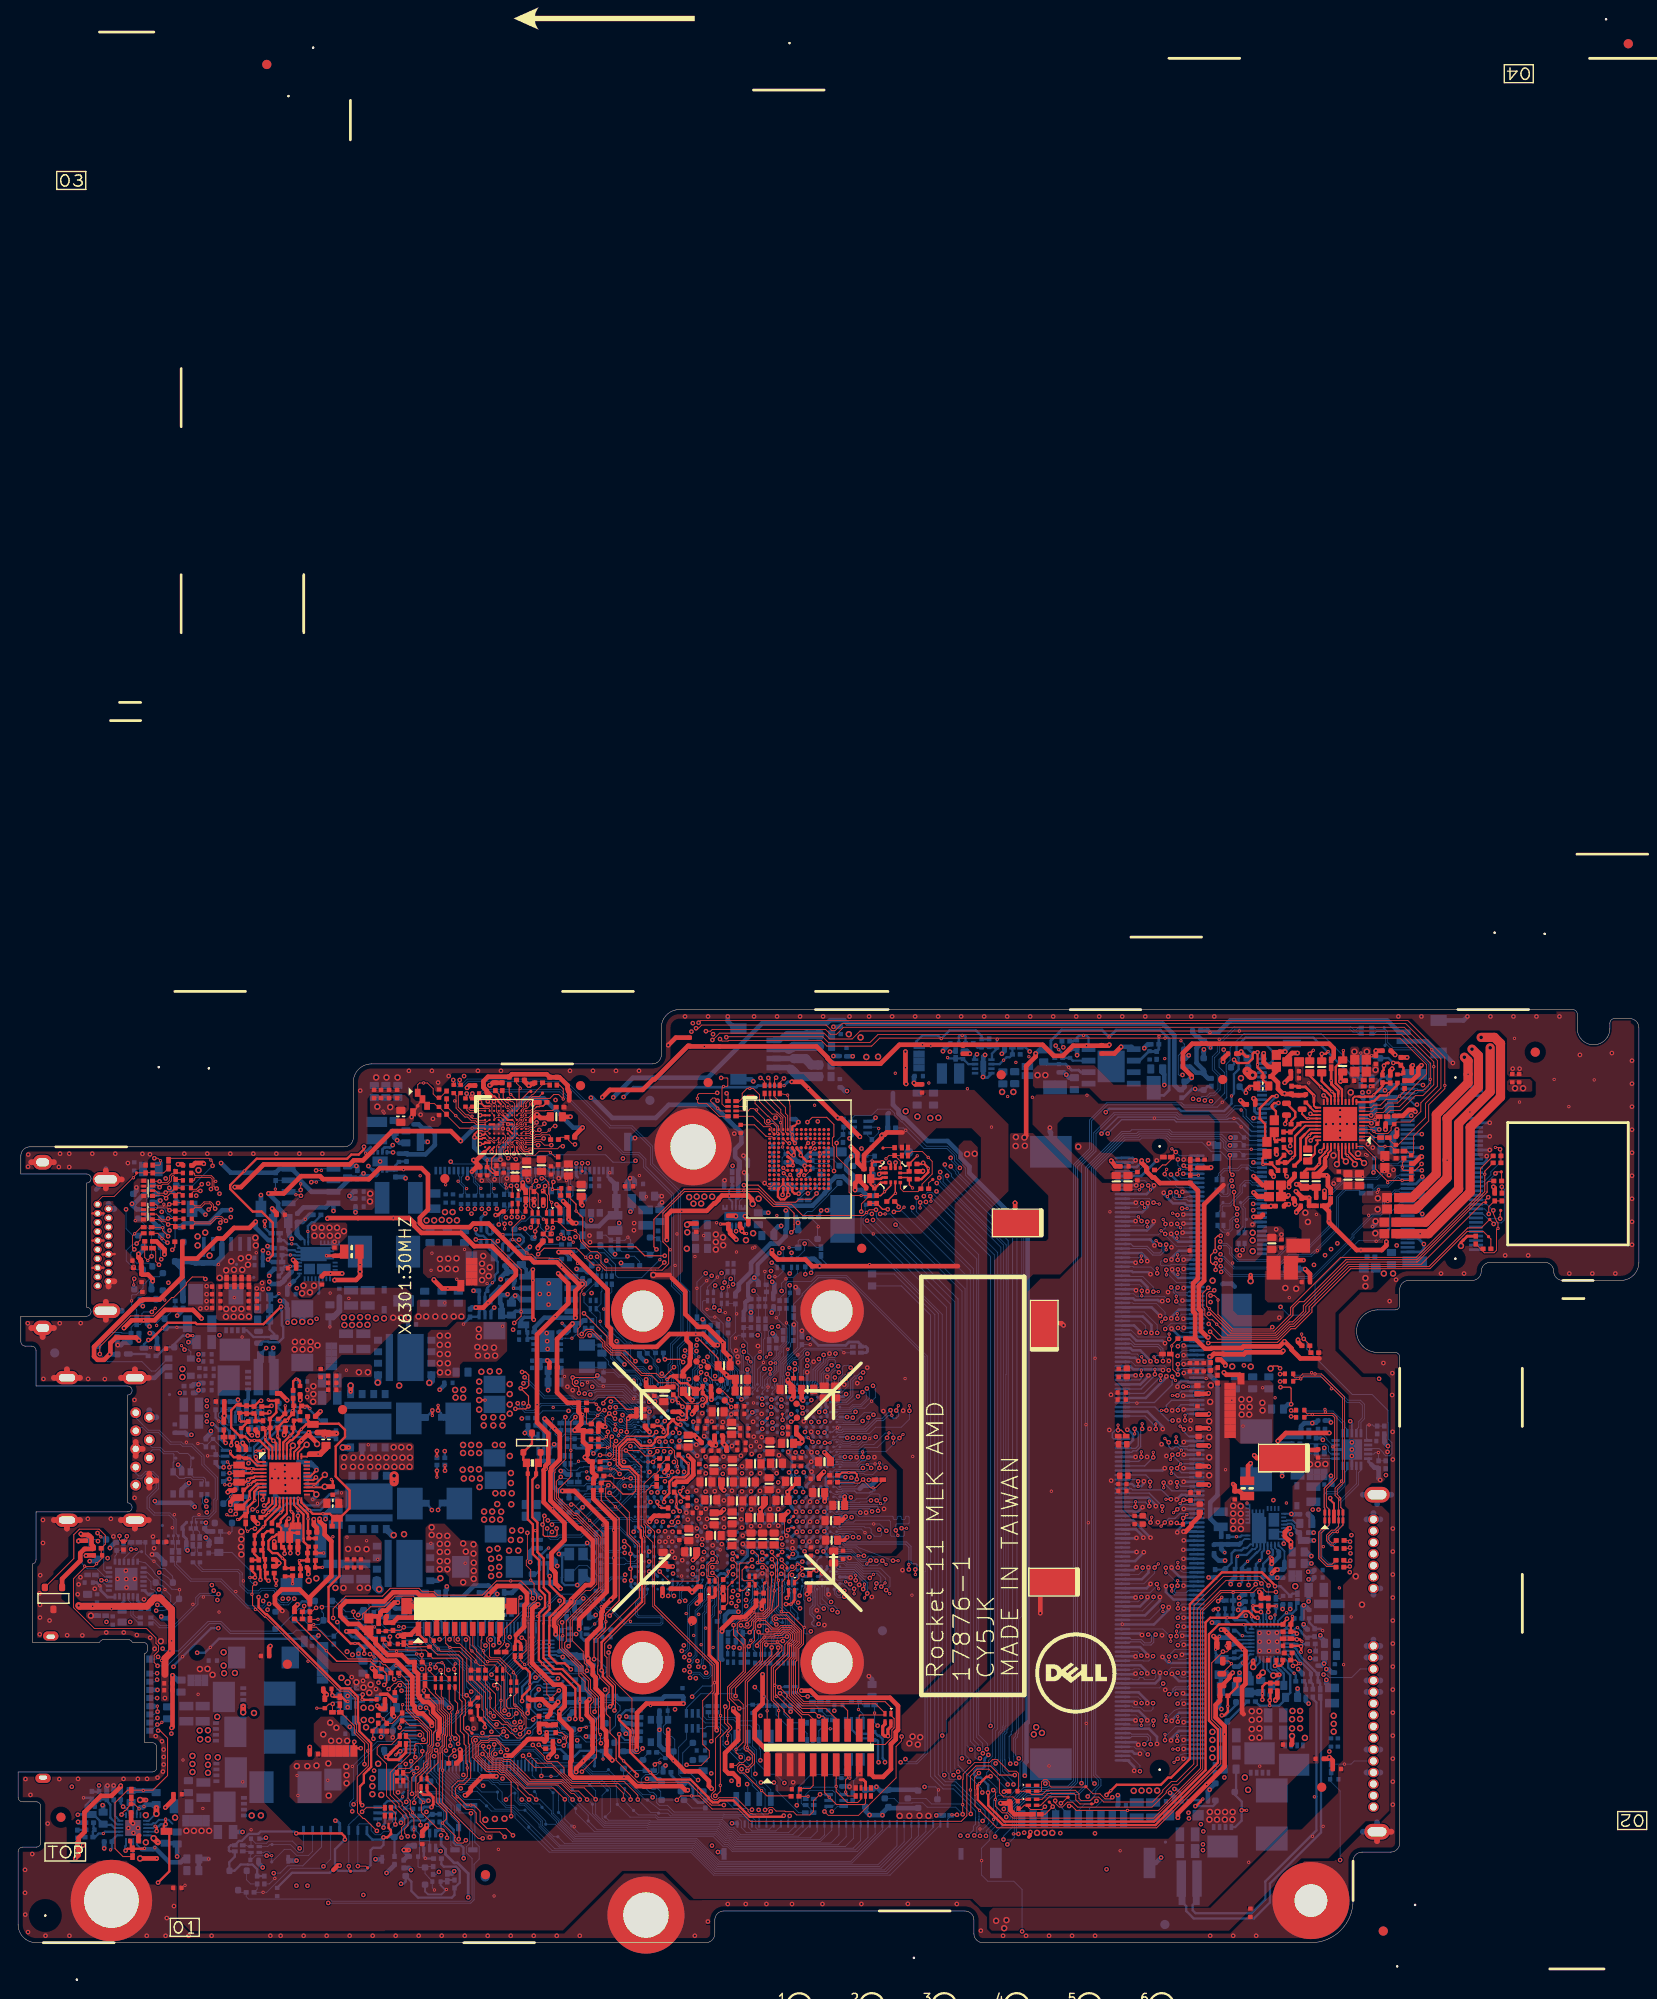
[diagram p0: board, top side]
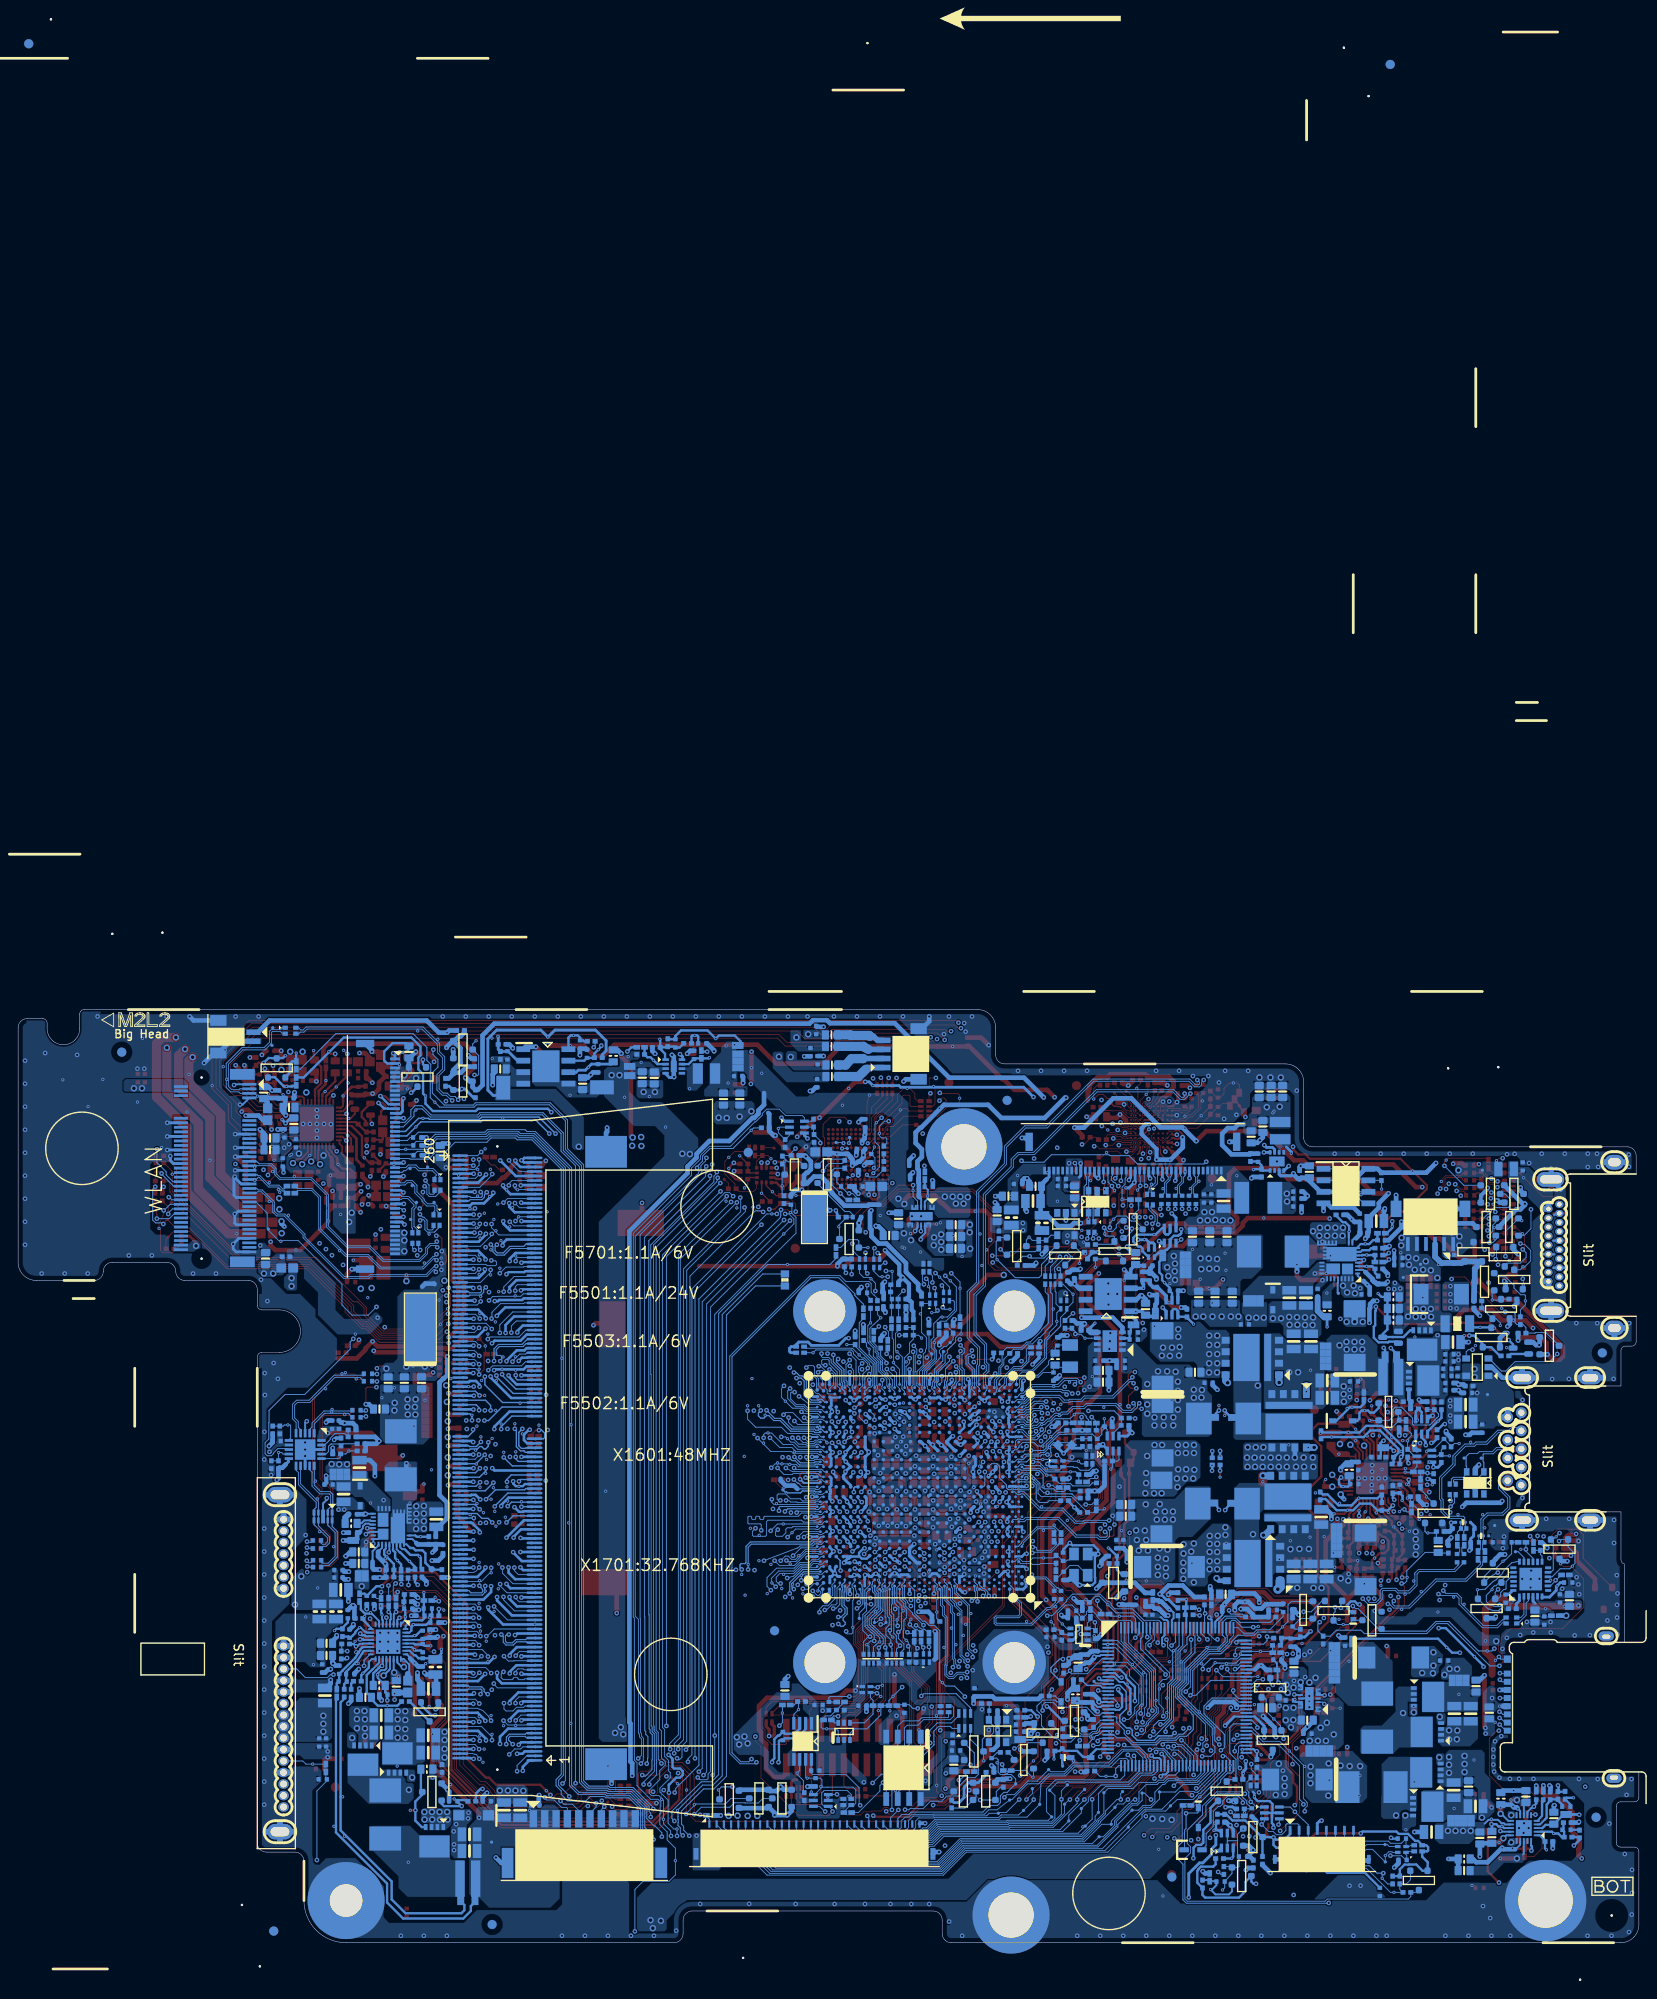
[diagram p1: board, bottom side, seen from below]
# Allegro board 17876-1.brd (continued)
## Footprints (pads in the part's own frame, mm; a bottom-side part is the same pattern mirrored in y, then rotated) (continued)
C402-TO0D2H28
  custom 0.152x0.152 smd: 1(0,0.457) 2(0,-0.457)
C402H22
  custom 0.114x0.114 smd: 1(0,0.457) 2(0,-0.457)
C603H35
  custom 0.197x0.197 smd: 1(0,0.66) 2(0,-0.66)
C603H36
  custom 0.197x0.197 smd: 1(0,0.66) 2(0,-0.66)
C603H38
  custom 0.197x0.197 smd: 1(0,0.66) 2(0,-0.66)
C603H40
  custom 0.197x0.197 smd: 1(0,0.66) 2(0,-0.66)
C805H50
  rect 1.549x0.94 smd: 1(0,0.838) 2(0,-0.838)
C805H54
  rect 1.549x0.94 smd: 1(0,0.838) 2(0,-0.838)
C805H56
  rect 1.549x0.94 smd: 1(0,0.838) 2(0,-0.838)
C805H58
  rect 1.549x0.94 smd: 1(0,0.838) 2(0,-0.838)
CON2O-U
  custom 0.159x0.159 smd: 1(0,0.254) 2(0,-0.254)
CSP97G60-1H41
  round 0.241 smd: A1(-2.25,2.25) A2(-1.75,2.25) A3(-1.25,2.25) A4(-0.75,2.25) A5(-0.25,2.25) A6(0.25,2.25) A7(0.75,2.25) A8(1.25,2.25) A9(1.75,2.25) A10(2.25,2.25) B1(-2.25,1.75) B2(-1.75,1.75) B3(-1.25,1.75) B4(-0.75,1.75) B5(-0.25,1.75) B6(0.25,1.75) B7(0.75,1.75) B8(1.25,1.75) B9(1.75,1.75) B10(2.25,1.75) C1(-2.25,1.25) C2(-1.75,1.25) C3(-1.25,1.25) C4(-0.75,1.25) C5(-0.25,1.25) C6(0.25,1.25) C7(0.75,1.25) C8(1.25,1.25) C9(1.75,1.25) C10(2.25,1.25) D1(-2.25,0.75) D2(-1.75,0.75) D3(-1.25,0.75) D4(-0.75,0.75) D5(-0.25,0.75) D6(0.25,0.75) D7(0.75,0.75) D8(1.25,0.75) D9(1.75,0.75) D10(2.25,0.75) E1(-2.25,0.25) E2(-1.75,0.25) E3(-1.25,0.25) E4(-0.75,0.25) E5(-0.25,0.25) E7(0.75,0.25) E8(1.25,0.25) E9(1.75,0.25) E10(2.25,0.25) F1(-2.25,-0.25) F2(-1.75,-0.25) F3(-1.25,-0.25) F4(-0.75,-0.25) F7(0.75,-0.25) F8(1.25,-0.25) F9(1.75,-0.25) F10(2.25,-0.25) G1(-2.25,-0.75) G2(-1.75,-0.75) G3(-1.25,-0.75) G4(-0.75,-0.75) G5(-0.25,-0.75) G6(0.25,-0.75) G7(0.75,-0.75) G8(1.25,-0.75) G9(1.75,-0.75) G10(2.25,-0.75) H1(-2.25,-1.25) H2(-1.75,-1.25) H3(-1.25,-1.25) H4(-0.75,-1.25) H5(-0.25,-1.25) H6(0.25,-1.25) H7(0.75,-1.25) H8(1.25,-1.25) H9(1.75,-1.25) H10(2.25,-1.25) J1(-2.25,-1.75) J2(-1.75,-1.75) J3(-1.25,-1.75) J4(-0.75,-1.75) J5(-0.25,-1.75) J6(0.25,-1.75) J7(0.75,-1.75) J8(1.25,-1.75) J9(1.75,-1.75) J10(2.25,-1.75) K1(-2.25,-2.25) K2(-1.75,-2.25) K3(-1.25,-2.25) K4(-0.75,-2.25) K5(-0.25,-2.25) K6(0.25,-2.25) K7(0.75,-2.25) K8(1.25,-2.25) K9(1.75,-2.25) K10(2.25,-2.25)
CT7343H83
  rect 2.413x1.905 smd: 1(0,2.959) 2(0,-2.959)
D0201H13
  custom 0.076x0.076 smd: 1(0,0.279) 2(0,-0.279)
DFN8-G125065H32
  rect 0.305x0.711 smd: 1(0.75,0.965) 2(0.25,0.965) 3(-0.25,0.965) 4(-0.75,0.965) 5(-0.75,-0.965) 6(-0.25,-0.965) 7(0.25,-0.965) 8(0.75,-0.965)
  rect 1.245x0.66 smd: 9(0,0)
DFN8F3-G2416-1H32
  rect 0.406x0.737 smd: 1(0.975,1.386) 2(0.325,1.386) 3(-0.325,1.386) 4(-0.975,1.386) 5(-0.975,-1.386) 6(-0.325,-1.386) 7(0.325,-1.386) 8(0.975,-1.386)
  rect 2.388x1.6 smd: 9(0,0)
DFN8G2-G1711H26
  rect 0.305x0.508 smd: 1(0.75,1) 2(0.25,1) 3(-0.25,1) 4(-0.75,1) 5(-0.75,-1) 6(-0.25,-1) 7(0.25,-1) 8(0.75,-1)
  rect 1.702x1.092 smd: 9(0,0)
DFN10G2510H22
  rect 0.305x0.66 smd: 1(1,0.43) 5(-1,0.43) 6(-1,-0.43) 10(1,-0.43)
  rect 0.254x0.66 smd: 2(0.521,0.43) 4(-0.521,0.43) 7(-0.521,-0.43) 9(0.521,-0.43)
  rect 0.025x0.025 smd: 3(0,0.43)
  rect 0.406x1.499 smd: 8(0,-0.43)
DFN14J32-G255D95H32
  custom 0.14x0.14 smd: 1(1.2,0.975) 6(-0.8,0.975) 8(-1.2,-0.975) 13(0.8,-0.975)
  rect 0.025x0.025 smd: 2(0.8,0.975) 7(-1.2,0.975) 9(-0.8,-0.975) 14(1.2,-0.975)
  rect 0.203x0.559 smd: 3(0.4,0.975) 4(0,0.975) 5(-0.4,0.975) 10(-0.4,-0.975) 11(0,-0.975) 12(0.4,-0.975)
  rect 2.54x0.94 smd: 15(0,0)
DM-ASP-137098-05-01
  rect 0.737x2.54 smd: 1(-5.715,-1.908) 2(-5.715,1.908) 3(-4.445,-1.908) 4(-4.445,1.908) 5(-3.175,-1.908) 6(-3.175,1.908) 7(-1.905,-1.908) 8(-1.905,1.908) 9(-0.635,-1.908) 10(-0.635,1.908) 11(0.635,-1.908) 12(0.635,1.908) 13(1.905,-1.908) 14(1.905,1.908) 15(3.175,-1.908) 16(3.175,1.908) 17(4.445,-1.908) 18(4.445,1.908) 19(5.715,-1.908) 20(5.715,1.908)
DO214AAAKH97
  rect 2.261x1.651 smd: A(0,2.223) K(0,-2.223)
GAP-CLOSE-PWR
  rect 0.66x0.762 smd: 1(-0.305,0) 2(0.305,0)
GAP-CLOSE-PWR-3
  rect 0.66x0.762 smd: 1(-0.305,0) 2(0.305,0)
HOLE276R178
  round 7.01 hole 4.521: 1(0,0)
HOLE335R142
  round 8.509 hole 3.607: 1(0,0)
HOLE335R197
  round 8.509 hole 5.004: 1(0,0)
HOLE354R237
  round 8.992 hole 6.02: 1(0,0)
L1608-UH38
  custom 0.197x0.197 smd: 1(0,0.66) 2(0,-0.66)
L2520-D620H48
  rect 2.261x1.118 smd: 1(0,0.955) 2(0,-0.955)
L7066-1830-UH119
  rect 3.505x2.667 smd: 1(0,2.653) 2(0,-2.653)
L7366-1930H119
  rect 3.505x2.819 smd: 1(0,2.729) 2(0,-2.729)
L125100-4PH24
  rect 0.457x0.584 smd: 1(-0.328,-0.587) 2(0.328,-0.587) 3(0.328,0.587) 4(-0.328,0.587)
LGA12G2H40
  rect 0.381x0.381 smd: 1(0.809,0.809) 4(-0.809,0.809) 7(-0.809,-0.809) 10(0.809,-0.809)
  rect 0.305x0.432 smd: 2(0.25,0.784) 3(-0.25,0.784) 8(-0.25,-0.784) 9(0.25,-0.784)
  rect 0.432x0.305 smd: 5(-0.784,0.25) 6(-0.784,-0.25) 11(0.784,-0.25) 12(0.784,0.25)
LQFP128H63
  rect 0.203x1.27 smd: 1(6.2,7.62) 2(5.8,7.62) 3(5.4,7.62) 4(5,7.62) 5(4.6,7.62) 6(4.2,7.62) 7(3.8,7.62) 8(3.4,7.62) 9(3,7.62) 10(2.6,7.62) 11(2.2,7.62) 12(1.8,7.62) 13(1.4,7.62) 14(1,7.62) 15(0.6,7.62) 16(0.2,7.62) 17(-0.2,7.62) 18(-0.6,7.62) 19(-1,7.62) 20(-1.4,7.62) 21(-1.8,7.62) 22(-2.2,7.62) 23(-2.6,7.62) 24(-3,7.62) 25(-3.4,7.62) 26(-3.8,7.62) 27(-4.2,7.62) 28(-4.6,7.62) 29(-5,7.62) 30(-5.4,7.62) 31(-5.8,7.62) 32(-6.2,7.62) 65(-6.2,-7.62) 66(-5.8,-7.62) 67(-5.4,-7.62) 68(-5,-7.62) 69(-4.6,-7.62) 70(-4.2,-7.62) 71(-3.8,-7.62) 72(-3.4,-7.62) 73(-3,-7.62) 74(-2.6,-7.62) 75(-2.2,-7.62) 76(-1.8,-7.62) 77(-1.4,-7.62) 78(-1,-7.62) 79(-0.6,-7.62) 80(-0.2,-7.62) 81(0.2,-7.62) 82(0.6,-7.62) 83(1,-7.62) 84(1.4,-7.62) 85(1.8,-7.62) 86(2.2,-7.62) 87(2.6,-7.62) 88(3,-7.62) 89(3.4,-7.62) 90(3.8,-7.62) 91(4.2,-7.62) 92(4.6,-7.62) 93(5,-7.62) 94(5.4,-7.62) 95(5.8,-7.62) 96(6.2,-7.62)
  rect 1.27x0.203 smd: 33(-7.62,6.2) 34(-7.62,5.8) 35(-7.62,5.4) 36(-7.62,5) 37(-7.62,4.6) 38(-7.62,4.2) 39(-7.62,3.8) 40(-7.62,3.4) 41(-7.62,3) 42(-7.62,2.6) 43(-7.62,2.2) 44(-7.62,1.8) 45(-7.62,1.4) 46(-7.62,1) 47(-7.62,0.6) 48(-7.62,0.2) 49(-7.62,-0.2) 50(-7.62,-0.6) 51(-7.62,-1) 52(-7.62,-1.4) 53(-7.62,-1.8) 54(-7.62,-2.2) 55(-7.62,-2.6) 56(-7.62,-3) 57(-7.62,-3.4) 58(-7.62,-3.8) 59(-7.62,-4.2) 60(-7.62,-4.6) 61(-7.62,-5) 62(-7.62,-5.4) 63(-7.62,-5.8) 64(-7.62,-6.2) 97(7.62,-6.2) 98(7.62,-5.8) 99(7.62,-5.4) 100(7.62,-5) 101(7.62,-4.6) 102(7.62,-4.2) 103(7.62,-3.8) 104(7.62,-3.4) 105(7.62,-3) 106(7.62,-2.6) 107(7.62,-2.2) 108(7.62,-1.8) 109(7.62,-1.4) 110(7.62,-1) 111(7.62,-0.6) 112(7.62,-0.2) 113(7.62,0.2) 114(7.62,0.6) 115(7.62,1) 116(7.62,1.4) 117(7.62,1.8) 118(7.62,2.2) 119(7.62,2.6) 120(7.62,3) 121(7.62,3.4) 122(7.62,3.8) 123(7.62,4.2) 124(7.62,4.6) 125(7.62,5) 126(7.62,5.4) 127(7.62,5.8) 128(7.62,6.2)
MSOP8-1H44
  rect 0.356x1.397 smd: 1(-0.975,-1.991) 2(-0.325,-1.991) 3(0.325,-1.991) 4(0.975,-1.991) 5(0.975,1.991) 6(0.325,1.991) 7(-0.325,1.991) 8(-0.975,1.991)
NFSA0-S6705-TPH4
  round 0.254 hole 1.651 unplated: (-10,0)
  round 0.254 hole 1.168 unplated: (10,0)
  rect 0.305x1.549 smd: 1(9.25,-5.275) 2(9,2.275) 3(8.75,-5.275) 4(8.5,2.275) 5(8.25,-5.275) 6(8,2.275) 7(7.75,-5.275) 16(5.5,2.275) 17(5.25,-5.275) 18(5,2.275) 19(4.75,-5.275) 20(4.5,2.275) 21(4.25,-5.275) 22(4,2.275) 23(3.75,-5.275) 24(3.5,2.275) 25(3.25,-5.275) 26(3,2.275) 27(2.75,-5.275) 28(2.5,2.275) 29(2.25,-5.275) 30(2,2.275) 31(1.75,-5.275) 32(1.5,2.275) 33(1.25,-5.275) 34(1,2.275) 35(0.75,-5.275) 36(0.5,2.275) 37(0.25,-5.275) 38(0,2.275) 39(-0.25,-5.275) 40(-0.5,2.275) 41(-0.75,-5.275) 42(-1,2.275) 43(-1.25,-5.275) 44(-1.5,2.275) 45(-1.75,-5.275) 46(-2,2.275) 47(-2.25,-5.275) 48(-2.5,2.275) 49(-2.75,-5.275) 50(-3,2.275) 51(-3.25,-5.275) 52(-3.5,2.275) 53(-3.75,-5.275) 54(-4,2.275) 55(-4.25,-5.275) 56(-4.5,2.275) 57(-4.75,-5.275) 58(-5,2.275) 59(-5.25,-5.275) 60(-5.5,2.275) 61(-5.75,-5.275) 62(-6,2.275) 63(-6.25,-5.275) 64(-6.5,2.275) 65(-6.75,-5.275) 66(-7,2.275) 67(-7.25,-5.275) 68(-7.5,2.275) 69(-7.75,-5.275) 70(-8,2.275) 71(-8.25,-5.275) 72(-8.5,2.275) 73(-8.75,-5.275) 74(-9,2.275) 75(-9.25,-5.275)
  rect 1.194x2.743 smd: 76(10.35,-4.5) 77(-10.35,-4.5)
NTC-402H22-U
  custom 0.127x0.127 smd: 1(0,0.432) 2(0,-0.432)
NTC-402H24-U
  custom 0.127x0.127 smd: 1(0,0.432) 2(0,-0.432)
NTC-603H38
  rect 0.914x0.787 smd: 1(0,0.66) 2(0,-0.66)
OSC-3225-4P-4H36
  rect 1.397x1.067 smd: 1(-1.171,-0.756) 2(1.171,-0.756) 3(1.171,0.756) 4(-1.171,0.756)
PAD-87212-1002N
  rect 0.61x1.549 smd: 1(-4.5,-2.525) 2(-3.5,-2.525) 3(-2.5,-2.525) 4(-1.5,-2.525) 5(-0.5,-2.525) 6(0.5,-2.525) 7(1.5,-2.525) 8(2.5,-2.525) 9(3.5,-2.525) 10(4.5,-2.525)
  rect 1.194x1.803 smd: 11(-5.797,0) 12(5.797,0)
POLYSW-2114H30
  rect 1.6x0.889 smd: 1(0,0.865) 2(0,-0.865)
POLYSW-4633-UH43
  rect 3.505x1.626 smd: 1(0,1.834) 2(0,-1.834)
PPAK-8P-3232H36
  rect 0.406x0.66 smd: 1(-0.975,-2.142) 2(-0.325,-2.142) 3(0.325,-2.142) 4(0.975,-2.142)
  rect 3.353x2.438 smd: 5(0,0)
  rect 0.025x0.025 smd: 6(0.65,0.838) 7(0,0.838) 8(-0.65,0.838)
PPAK-8P-G5324H44-COLAY
  rect 0.762x0.889 smd: 1(-1.905,-2.946) 2(-0.635,-2.946) 3(0.635,-2.946) 4(1.905,-2.946) 5(1.905,2.946) 6(0.635,2.946) 7(-0.635,2.946) 8(-1.905,2.946)
  rect 5.207x2.896 smd: 9(0,0.65)
  rect 5.207x0.787 smd: 10(0,-1.7)
PTFBT4-09GLBS1NN4H2
  rect 0.813x0.762 smd: 1(5.3,11.775)
  rect 0.66x0.762 smd: 2(3.7,11.775) 3(2.8,11.775) 4(1.9,11.775) 5(1,11.775) 6(0.1,11.775) 7(-0.8,11.775) 8(-1.7,11.775) 9(-2.6,11.775)
  oval 1.016x1.702 hole 0.457x0.914: 10(-7.775,0) 11(7.775,0.85)
QFN20-G1D75H32
  rect 0.203x0.66 smd: 1(0.8,1.487) 2(0.4,1.487) 3(0,1.487) 4(-0.4,1.487) 5(-0.8,1.487) 11(-0.8,-1.487) 12(-0.4,-1.487) 13(0,-1.487) 14(0.4,-1.487) 15(0.8,-1.487)
  rect 0.66x0.203 smd: 6(-1.487,0.8) 7(-1.487,0.4) 8(-1.487,0) 9(-1.487,-0.4) 10(-1.487,-0.8) 16(1.487,-0.8) 17(1.487,-0.4) 18(1.487,0) 19(1.487,0.4) 20(1.487,0.8)
  rect 1.753x1.753 smd: 21(0,0)
QFN20-G2D25H32
  rect 0.305x0.914 smd: 1(1,1.86) 2(0.5,1.86) 3(0,1.86) 4(-0.5,1.86) 5(-1,1.86) 11(-1,-1.86) 12(-0.5,-1.86) 13(0,-1.86) 14(0.5,-1.86) 15(1,-1.86)
  rect 0.914x0.305 smd: 6(-1.86,1) 7(-1.86,0.5) 8(-1.86,0) 9(-1.86,-0.5) 10(-1.86,-1) 16(1.86,-1) 17(1.86,-0.5) 18(1.86,0) 19(1.86,0.5) 20(1.86,1)
  rect 2.261x2.261 smd: 21(0,0)
QFN24-G2D5H40-U
  rect 0.305x0.66 smd: 1(1.25,1.987) 6(-1.25,1.987) 13(-1.25,-1.987) 18(1.25,-1.987)
  rect 0.305x0.711 smd: 2(0.75,1.962) 3(0.25,1.962) 4(-0.25,1.962) 5(-0.75,1.962) 14(-0.75,-1.962) 15(-0.25,-1.962) 16(0.25,-1.962) 17(0.75,-1.962)
  rect 0.66x0.305 smd: 7(-1.987,1.25) 12(-1.987,-1.25) 19(1.987,-1.25) 24(1.987,1.25)
  rect 0.711x0.305 smd: 8(-1.962,0.75) 9(-1.962,0.25) 10(-1.962,-0.25) 11(-1.962,-0.75) 20(1.962,-0.75) 21(1.962,-0.25) 22(1.962,0.25) 23(1.962,0.75)
  rect 2.489x2.489 smd: 25(0,0)
QFN32J4-G2D7H42
  custom 0.051x0.051 smd: 1(1.4,1.911) 8(-1.4,1.911) 9(-1.911,1.4) 16(-1.911,-1.4) 17(-1.4,-1.911) 24(1.4,-1.911) 25(1.911,-1.4) 32(1.911,1.4)
  rect 0.203x0.686 smd: 2(1,1.911) 3(0.6,1.911) 4(0.2,1.911) 5(-0.2,1.911) 6(-0.6,1.911) 7(-1,1.911) 18(-1,-1.911) 19(-0.6,-1.911) 20(-0.2,-1.911) 21(0.2,-1.911) 22(0.6,-1.911) 23(1,-1.911)
  rect 0.686x0.203 smd: 10(-1.911,1) 11(-1.911,0.6) 12(-1.911,0.2) 13(-1.911,-0.2) 14(-1.911,-0.6) 15(-1.911,-1) 26(1.911,-1) 27(1.911,-0.6) 28(1.911,-0.2) 29(1.911,0.2) 30(1.911,0.6) 31(1.911,1)
  rect 2.692x2.692 smd: 33(0,0)
QFN32J4-G3PH32
  rect 0.203x0.559 smd: 1(1.4,1.975) 2(1,1.975) 3(0.6,1.975) 4(0.2,1.975) 5(-0.2,1.975) 6(-0.6,1.975) 7(-1,1.975) 8(-1.4,1.975) 21(0.2,-1.975) 22(0.6,-1.975) 23(1,-1.975) 24(1.4,-1.975)
  rect 0.559x0.203 smd: 9(-1.975,1.4) 10(-1.975,1) 25(1.975,-1.4) 26(1.975,-1) 27(1.975,-0.6) 28(1.975,-0.2) 29(1.975,0.2) 30(1.975,0.6) 31(1.975,1) 32(1.975,1.4)
  rect 0.025x0.025 smd: 11(-1.975,0.6) 12(-1.975,0.2) 13(-1.975,-0.2) 14(-1.975,-0.6) 15(-1.975,-1) 17(-1.4,-1.975) 18(-1,-1.975) 19(-0.6,-1.975) 20(-0.2,-1.975)
  custom 0.14x0.14 smd: 16(-1.975,-1.4)
  rect 1.168x1.219 smd: 33(0.895,0.86)
  rect 1.168x1.524 smd: 34(0.895,-0.72)
  custom 0.401x0.401 smd: 35(-0.762,0)
QFN40-G3D5H32
  rect 0.203x0.66 smd: 1(1.8,2.4) 10(-1.8,2.4) 21(-1.8,-2.4) 30(1.8,-2.4)
  rect 0.203x0.711 smd: 2(1.4,2.4) 3(1,2.4) 4(0.6,2.4) 5(0.2,2.4) 6(-0.2,2.4) 7(-0.6,2.4) 8(-1,2.4) 9(-1.4,2.4) 22(-1.4,-2.4) 23(-1,-2.4) 24(-0.6,-2.4) 25(-0.2,-2.4) 26(0.2,-2.4) 27(0.6,-2.4) 28(1,-2.4) 29(1.4,-2.4)
  rect 0.66x0.203 smd: 11(-2.4,1.8) 20(-2.4,-1.8) 31(2.4,-1.8) 40(2.4,1.8)
  rect 0.711x0.203 smd: 12(-2.4,1.4) 13(-2.4,1) 14(-2.4,0.6) 15(-2.4,0.2) 16(-2.4,-0.2) 17(-2.4,-0.6) 18(-2.4,-1) 19(-2.4,-1.4) 32(2.4,-1.4) 33(2.4,-1) 34(2.4,-0.6) 35(2.4,-0.2) 36(2.4,0.2) 37(2.4,0.6) 38(2.4,1) 39(2.4,1.4)
  rect 3.505x3.505 smd: 41(0,0)
QFN40J5-G3D75H36
  rect 0.203x0.66 smd: 1(1.8,2.489) 2(1.4,2.489) 3(1,2.489) 4(0.6,2.489) 5(0.2,2.489) 6(-0.2,2.489) 7(-0.6,2.489) 8(-1,2.489) 9(-1.4,2.489) 10(-1.8,2.489) 21(-1.8,-2.489) 22(-1.4,-2.489) 23(-1,-2.489) 24(-0.6,-2.489) 25(-0.2,-2.489) 26(0.2,-2.489) 27(0.6,-2.489) 28(1,-2.489) 29(1.4,-2.489) 30(1.8,-2.489)
  rect 0.66x0.203 smd: 11(-2.489,1.8) 12(-2.489,1.4) 13(-2.489,1) 14(-2.489,0.6) 15(-2.489,0.2) 16(-2.489,-0.2) 17(-2.489,-0.6) 18(-2.489,-1) 19(-2.489,-1.4) 20(-2.489,-1.8) 31(2.489,-1.8) 32(2.489,-1.4) 33(2.489,-1) 34(2.489,-0.6) 35(2.489,-0.2) 36(2.489,0.2) 37(2.489,0.6) 38(2.489,1) 39(2.489,1.4) 40(2.489,1.8)
  rect 3.759x3.759 smd: 41(0,0)
R402H14
  custom 0.127x0.127 smd: 1(0,0.432) 2(0,-0.432)
R402H16
  custom 0.127x0.127 smd: 1(0,0.432) 2(0,-0.432)
R603H22
  custom 0.197x0.197 smd: 1(0,0.66) 2(0,-0.66)
R805H24
  rect 1.549x0.94 smd: 1(0,0.838) 2(0,-0.838)
R1206H28
  rect 1.854x1.016 smd: 1(0,1.346) 2(0,-1.346)
R3720H40
  rect 4.013x1.041 smd: 1(0,0.867) 2(0,-0.867)
S-OSC3-2016H28
  rect 0.889x0.635 smd: 1(-0.718,-0.517) 3(0.718,0.517)
  custom 0.417x0.417 smd: 2(0.718,-0.517)
SC70-2D2-312H44
  custom 0.152x0.152 smd: 1(-0.65,-0.864) 2(0.65,-0.864) 3(0,0.864)
SC70-6H44
  rect 0.406x0.66 smd: 1(-0.65,-0.95) 2(0,-0.95) 3(0.65,-0.95) 4(0.65,0.95) 5(0,0.95) 6(-0.65,0.95)
SKT-HDMI23-188125-5
  oval 0.762x0.914 hole 0.508: 1(-4.5,6.08) 2(-4,7.28) 3(-3.5,6.08) 4(-3,7.28) 5(-2.5,6.08) 6(-2,7.28) 7(-1.5,6.08) 8(-1,7.28) 9(-0.5,6.08) 10(0,7.28) 11(0.5,6.08) 12(1,7.28) 13(1.5,6.08) 14(2,7.28) 15(2.5,6.08) 16(3,7.28) 17(3.5,6.08) 18(4,7.28) 19(4.5,6.08)
  oval 1.626x3.023 hole 0.914x2.464: 20(7.25,6.98) 22(-7.25,6.98)
  oval 1.626x2.134 hole 0.914x1.422: 21(9.15,0) 23(-9.15,0)
SKT-USB13-160161
  round 1.194 hole 0.711: 1(3.5,9.09) 2(1,9.09) 3(-1,9.09) 4(-3.5,9.09) 5(-4,7.59) 6(-2,7.59) 7(0,7.59) 8(2,7.59) 9(4,7.59)
  oval 1.473x2.515 hole 0.813x1.803: 10(-7.85,0) 11(7.85,0)
  oval 1.473x2.718 hole 0.813x2.007: 12(-7.85,7.5) 13(7.85,7.5)
SMD49-12H34
  rect 1.753x1.27 smd: 1(0,1.231) 2(0,-1.231)
SMD-ARES4
  rect 0.356x0.61 smd: 1(-0.325,-0.457) 2(0.325,-0.457) 3(0.325,0.457) 4(-0.325,0.457)
SMD-ARES4H18
  rect 0.356x0.61 smd: 1(-0.325,-0.457) 2(0.325,-0.457) 3(0.325,0.457) 4(-0.325,0.457)
SMD-ARES4H20
  rect 0.356x0.61 smd: 1(-0.325,-0.457) 2(0.325,-0.457) 3(0.325,0.457) 4(-0.325,0.457)
SOD123AK-2H43
  rect 1.143x1.245 smd: A(0,1.631) K(0,-1.631)
SOD323-2513AKH36
  rect 0.559x1.041 smd: A(0,0.987) K(0,-0.987)
SOD323AKH38
  rect 0.559x0.813 smd: A(0,1.1) K(0,-1.1)
SOD323AKH40
  rect 0.559x0.813 smd: A(0,1.1) K(0,-1.1)
SOD323AKH44
  rect 0.559x0.813 smd: A(0,1.1) K(0,-1.1)
SOD882-10D6-1H20
  rect 0.61x0.457 smd: 1(0,0.457) 2(0,-0.457)
SOD-523-4H28
  rect 0.559x0.711 smd: 1(0,0.702) 2(0,-0.702)
SOIC8-1H86
  rect 0.635x1.524 smd: 1(-1.905,-3.442) 2(-0.635,-3.442) 3(0.635,-3.442) 4(1.905,-3.442) 5(1.905,3.442) 6(0.635,3.442) 7(-0.635,3.442) 8(-1.905,3.442)
SOIC8-G3530H63
  rect 0.635x1.524 smd: 1(-1.905,-2.492) 2(-0.635,-2.492) 3(0.635,-2.492) 4(1.905,-2.492) 5(1.905,2.492) 6(0.635,2.492) 7(-0.635,2.492) 8(-1.905,2.492)
  rect 3.505x2.997 smd: 9(0,0)
SOIC8H69
  rect 0.635x1.524 smd: 1(-1.905,-2.477) 2(-0.635,-2.477) 3(0.635,-2.477) 4(1.905,-2.477) 5(1.905,2.477) 6(0.635,2.477) 7(-0.635,2.477) 8(-1.905,2.477)
SOT23-2D4-312H44
  custom 0.171x0.171 smd: 1(-0.95,-1.069) 2(0.95,-1.069) 3(0,1.069)
SOT23-2D4-312H46
  custom 0.171x0.171 smd: 1(-0.95,-1.069) 2(0.95,-1.069) 3(0,1.069)
SOT23-2D4-312H48
  custom 0.171x0.171 smd: 1(-0.95,-1.069) 2(0.95,-1.069) 3(0,1.069)
SOT23-2D8-123H52
  custom 0.171x0.171 smd: 1(0,1.21) 2(-0.95,-1.21) 3(0.95,-1.21)
SOT23-2D8-312H58
  custom 0.171x0.171 smd: 1(-0.95,-1.21) 2(0.95,-1.21) 3(0,1.21)
SOT23CBE2D4H44
  custom 0.165x0.165 smd: B(-0.95,-1.073) C(0,1.073) E(0.95,-1.073)
SOT23DGS2D4H44
  custom 0.171x0.171 smd: D(0,1.069) G(-0.95,-1.069) S(0.95,-1.069)
SOT23DGS2D4H48
  custom 0.171x0.171 smd: D(0,1.069) G(-0.95,-1.069) S(0.95,-1.069)
SOT-6H58
  rect 0.61x0.813 smd: 1(-0.95,-1.219) 2(0,-1.219) 3(0.95,-1.219) 4(0.95,1.219) 5(0,1.219) 6(-0.95,1.219)
SOT-23-5H40
  rect 0.686x0.864 smd: 1(-0.953,-1.232) 2(0,-1.232) 3(0.953,-1.232) 4(0.953,1.232) 5(-0.953,1.232)
SOT-23-5H58
  rect 0.686x0.864 smd: 1(-0.953,-1.232) 2(0,-1.232) 3(0.953,-1.232) 4(0.953,1.232) 5(-0.953,1.232)
SOT-23-9H44
  custom 0.165x0.165 smd: 1(-0.953,-1.056) 2(0.953,-1.056) 3(0,1.056)
SOT-363H44
  rect 0.356x0.965 smd: 1(-0.65,-0.826) 2(0,-0.826) 3(0.65,-0.826) 4(0.65,0.826) 5(0,0.826) 6(-0.65,0.826)
SPR5432H83
  rect 5.105x2.896 smd: 1(-1.499,0)
SPR5630H142
  rect 5.283x2.692 smd: 1(-2.413,0)
SPR7837H229
  rect 7.493x3.353 smd: 1(-2.095,0)
TPAD14-OP
  round 0.356 smd: 1(0,0)
TPAD28
  round 0.711 smd: 1(0,0)
unnamed
  round 1.016 smd: (0,0)

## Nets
1V_CPU_CORE: C1001.1 C1002.1 C1003.1 C1004.1 C1005.1 C1006.1 C1007.1 C1008.1 C1009.1 C1067.1 C1068.1 C1069.1 C1070.1 C1075.1 CPU1.AA25 CPU1.AA27 CPU1.AA29 CPU1.AA31 CPU1.K21 CPU1.K23 CPU1.K25 CPU1.K27 CPU1.K29 CPU1.K31 CPU1.N21 CPU1.N23 CPU1.N25 CPU1.N27 CPU1.N29 CPU1.N31 CPU1.U23 CPU1.U25 CPU1.U27 CPU1.U29 CPU1.U31 PC4709.1 PC4710.1 PG4707.2 PL4701.2 PR4634.1 PT4701.1 PT4702.1
1V_S0: C6306.1 C6307.1 C6311.1 C6312.1 C6313.1 C6337.1 C6340.1 PC6301.1 PC6303.1 PC6304.1 PL6301.2 PR6302.1 PR6303.2 U6304.C3 U6304.D3 U6304.D5 U6304.D8 U6304.G1 U6304.G7 U6304.H2 U6304.H4 U6304.J4
3V5V_CT1: C4002.1 U4001.12
3V5V_CT2: C4001.1 U4001.10
3V_5V_EN: D4001.1 PR4502.2 PR4514.2 R4002.1 R4003.1
3V_5V_PWRGD: PG4903.1 PR4513.2 PR5409.1 PU4501.7 Q1702.2 RN1706.2
3V_5V_PWRGD_R: Q1702.5 Q1702.6 RN1706.1
3V_S0_EN: C4028.1 R4001.2 U4001.3
5V_AUX_S5: PG4525.2 PR5410.1
5V_DDC_HDMI1: D5701.1 RN5701.3(B)
5V_DDC_HDMI2: D5701.2 RN5701.4
5V_HDMI: EC5701.1 F5701.1 HDMI1.18
5V_S0: C4003.1 C6005.1 C6006.2 D5701.3 EC6001.1 F5503.1 FC8921.1 FC8922.1 FC8923.1 FC8924.1 FC8925.1 HDD1.P7 HDD1.P8 HDD1.P9 Q6501.E R2427.1 R2701.1 R2703.2 R2707.1 R5534.1 U4001.13 U4001.14
5V_S0_EN: C4029.1 R4012.2 U4001.5
5V_S5: AFTP5402.1 C3606.1 C4017.1 C4018.1 EC8901.1 F5701.2 IOBD1.39 IOBD1.40 IOBD1.41 IOBD1.42 IOBD1.43 IOBD1.44 PC4610.1 PC4901.1 PC4902.1 PC5201.1 PC5301.1 PG4502.2 PG4504.2 PG4509.2 PG4511.2 PG4516.2 PG4518.2 PG4519.2 PG4521.2 PR4303.1 PR4616.1 PR5201.2 PR5301.2 PR5310.1 PU4601.12 PU4601.26 PU4901.6 U3601.5 U4001.1 U4001.2 U4001.4 U4002.4 U4003.4
5V_USB30: AFTP3401.1 C3601.1 C3602.1 C3608.1 C3609.1 ED3505.5 R3605.1 U3601.1 USB1.1
12V_BT+: AFTP4304.1 BATT1.1 BATT1.2 BATT1.3 EC4303.1 PC4401.1 PC4410.1 PC4411.1 PC4452.1 PC4453.1 PC4464.1 PD4302.K PG4426.2 PQ4416.2 PR4443.2 PR4454.2 PR4481.1
19V_DCBATOUT_LCD: C5502.1 C5503.1 C5504.1 F5501.2 LCD1.1 LCD1.2 LCD1.3 LCD1.4
+3V_1D8V_AVDD: C2710.1 HDA27.33 R2752.2
+3V_1D8V_DVDD: C2720.1 C2721.1 C2740.1 C2741.1 HDA27.1 R2710.1 R2715.2 R2717.1
+5V_AVDD: C2706.1 C2707.1 HDA27.20 R2703.1
+5V_PVDD: C2701.1 C2712.1 R2701.2 R2707.2 R2751.1
+5V_PVDD1: C2713.1 C2714.1 C2717.1 C2718.1 HDA27.34 HDA27.39 R2751.2
DVSS: HDA27.10 R2716.2
GND: AFTP3404.1 AFTP4305.1 AFTP6526.1 BATT1.8 BATT1.9 BATT1.10 BATT1.11 BATT1.12 C801.2 C802.2 C803.1 C804.2 C1001.2 C1002.2 C1003.2 C1004.2 C1005.2 C1006.2 C1007.2 C1008.2 C1009.2 C1010.2 C1011.2 C1012.2 C1013.2 C1014.2 C1015.2 C1016.2 C1017.2 C1018.2 C1019.2 C1020.2 C1021.2 C1022.2 C1023.2 C1024.2 C1025.2 C1026.2 C1027.2 C1028.2 C1029.2 C1030.2 C1031.2 C1032.2 C1033.2 C1034.2 C1035.2 C1036.2 C1037.2 C1038.2 C1039.2 C1040.2 C1041.2 C1042.2 C1043.2 C1044.2 C1045.2 C1046.2 C1047.2 C1048.2 C1049.2 C1050.2 C1051.2 C1052.2 C1053.2 C1054.2 C1055.2 C1056.2 C1057.2 C1058.2 C1059.2 C1060.2 C1061.2 C1062.2 C1063.2 C1064.2 C1065.2 C1066.2 C1067.2 C1068.2 C1069.2 C1070.2 C1071.2 C1072.2 C1073.2 C1074.2 C1075.2 C1076.2 C1077.2 C1078.2 C1079.2 C1080.2 C1081.2 C1201.2 C1202.2 C1203.2 C1204.2 C1205.2 C1206.2 C1207.2 C1208.2 C1209.2 C1210.2 C1211.2 C1212.2 C1213.2 C1214.2 C1215.2 C1216.2 C1217.2 C1218.2 C1219.2 C1220.2 C1221.2 C1222.2 C1223.2 C1224.2 C1225.2 C1226.2 C1227.2 C1228.2 C1601.1 C1602.1 C1603.2 C1701.2 C1702.1 C1703.2 C1704.2 C2401.2 C2402.2 C2403.2 C2414.2 C2428.1 C2429.2 C2430.2 C2431.2 C2432.2 C2433.2 C2439.2 C2440.2 C2441.2 C2443.2 C2444.1 C2445.2 C2446.2 C2447.1 C2448.2 C2501.2 C2502.2 C2507.2 C2508.2 C2601.2 C2602.2 C2606.2 C2701.2 C2704.2 C2705.2 C2709.2 C2712.2 C2713.2 C2714.2 C2717.2 C2718.2 C2720.2 C2721.2 C2722.2 C2723.2 C2724.2 C2725.2 C2739.2 C2740.2 C2741.2 C2742.2 C2743.2 C3301.2 C3302.2 C3303.2 C3304.2 C3305.2 C3306.2 C3307.2 C3308.1 C3309.1 C3508.2 C3509.2 C3510.2 C3511.2 C3601.2 C3602.2 C3606.2 C3608.2 C3609.2 C4001.2 C4002.2 C4003.2 C4004.2 C4005.2 C4006.2 C4007.1 C4008.2 C4009.2 C4010.1 C4011.2 C4012.2 C4013.2 C4014.2 C4015.2 C4016.2 C4017.2 C4018.2 C4027.2 C4028.2 C4029.2 C4030.2 C5502.2 C5503.2 C5504.2 C5508.2 C5509.1 C5511.2 C5512.2 C5514.2 C5518.2 C5519.2 C5520.2 C5521.2 C6005.2 C6006.1 C6011.2 C6012.2 C6013.2 C6014.2 C6015.2 C6016.2 C6017.2 C6018.2 C6102.2 C6103.2 C6104.2 C6301.2 C6302.2 C6303.2 C6304.2 C6305.2 C6306.2 C6307.2 C6308.2 C6309.2 C6310.2 C6311.2 C6312.2 C6313.2 C6314.2 C6315.2 C6318.2 C6320.2 C6327.2 C6330.2 C6335.2 C6337.2 C6340.2 C6341.2 C6343.2 C6344.2 C6349.2 C6701.2 C6702.2 C6801.2 C6901.2 C6902.2 CPU1.A2 CPU1.A8 CPU1.A13 CPU1.A18 CPU1.A23 CPU1.A32 CPU1.A35 CPU1.A39 CPU1.AA1 CPU1.AA2 CPU1.AA3 CPU1.AA5 CPU1.AA10 CPU1.AA39 CPU1.AC3 CPU1.AC7 CPU1.AC10 CPU1.AC11 CPU1.AC13 CPU1.AC15 CPU1.AC17 CPU1.AC19 CPU1.AC21 CPU1.AC23 CPU1.AC25 CPU1.AC27 CPU1.AC29 CPU1.AC31 CPU1.AC38 CPU1.AC39 CPU1.AC41 CPU1.AE3 CPU1.AE5 CPU1.AE10 CPU1.AE39 CPU1.AG3 CPU1.AG7 CPU1.AG10 CPU1.AG11 CPU1.AG13 CPU1.AG15 CPU1.AG17 CPU1.AG19 CPU1.AG21 CPU1.AG23 CPU1.AG25 CPU1.AG27 CPU1.AG29 CPU1.AG31 CPU1.AG39 CPU1.AG41 CPU1.AJ3 CPU1.AJ5 CPU1.AJ10 CPU1.AJ29 CPU1.AJ31 CPU1.AJ39 CPU1.AL1 CPU1.AL2 CPU1.AL3 CPU1.AL7 CPU1.AL10 CPU1.AL31 CPU1.AL39 CPU1.AL41 CPU1.AM25 CPU1.AM27 CPU1.AM29 CPU1.AM31 CPU1.AN3 CPU1.AN5 CPU1.AN39 CPU1.AR3 CPU1.AR11 CPU1.AR19 CPU1.AR23 CPU1.AR27 CPU1.AR31 CPU1.AR39 CPU1.AR41 CPU1.AU3 CPU1.AU9 CPU1.AU21 CPU1.AU25 CPU1.AU29 CPU1.AU39 CPU1.AW3 CPU1.AW5 CPU1.AW7 CPU1.AW9 CPU1.AW11 CPU1.AW13 CPU1.AW15 CPU1.AW17 CPU1.AW19 CPU1.AW21 CPU1.AW23 CPU1.AW25 CPU1.AW27 CPU1.AW29 CPU1.AW31 CPU1.AW33 CPU1.AW35 CPU1.AW37 CPU1.AW39 CPU1.AW41 CPU1.AY1 CPU1.AY11 CPU1.B8 CPU1.B13 CPU1.B32 CPU1.B39 CPU1.BA7 CPU1.BA11 CPU1.BA15 CPU1.BA19 CPU1.BA23 CPU1.BA31 CPU1.BA35 CPU1.BA39 CPU1.C3 CPU1.C5 CPU1.C7 CPU1.C9 CPU1.C11 CPU1.C13 CPU1.C15 CPU1.C17 CPU1.C19 CPU1.C21 CPU1.C23 CPU1.C25 CPU1.C27 CPU1.C29 CPU1.C31 CPU1.C33 CPU1.C35 CPU1.C37 CPU1.C39 CPU1.C41 CPU1.E1 CPU1.E2 CPU1.E3 CPU1.E21 CPU1.E25 CPU1.E29 CPU1.E35 CPU1.E38 CPU1.E39 CPU1.G1 CPU1.G2 CPU1.G3 CPU1.G11 CPU1.G13 CPU1.G23 CPU1.G27 CPU1.G31 CPU1.G35 CPU1.G37 CPU1.G39 CPU1.G41 CPU1.H23 CPU1.J3 CPU1.J8 CPU1.J39 CPU1.L3 CPU1.L8 CPU1.L13 CPU1.L19 CPU1.L21 CPU1.L23 CPU1.L25 CPU1.L27 CPU1.L29 CPU1.L31 CPU1.L39 CPU1.L41 CPU1.N1 CPU1.N2 CPU1.N3 CPU1.N39 CPU1.R3 CPU1.R11 CPU1.R13 CPU1.R15 CPU1.R17 CPU1.R19 CPU1.R21 CPU1.R23 CPU1.R25 CPU1.R27 CPU1.R29 CPU1.R31 CPU1.R39 CPU1.R41 CPU1.U1 CPU1.U2 CPU1.U3 CPU1.U10 CPU1.U39 CPU1.W3 CPU1.W10 CPU1.W11 CPU1.W13 CPU1.W15 CPU1.W17 CPU1.W19 CPU1.W21 CPU1.W23 CPU1.W25 CPU1.W27 CPU1.W29 CPU1.W31 CPU1.W39 CPU1.W41 D4301.1 D4302.1 D4303.1 DB1.1 DB1.3 DB1.11 DB1.12 DCIN1.1 DCIN1.2 DCIN1.7 DCIN1.8 DIMM1.1 DIMM1.2 DIMM1.5 DIMM1.6 DIMM1.9 DIMM1.10 DIMM1.14 DIMM1.15 DIMM1.18 DIMM1.19 DIMM1.22 DIMM1.23 DIMM1.26 DIMM1.27 DIMM1.30 DIMM1.31 DIMM1.35 DIMM1.36 DIMM1.39 DIMM1.40 DIMM1.43 DIMM1.44 DIMM1.47 DIMM1.48 DIMM1.51 DIMM1.52 DIMM1.56 DIMM1.57 DIMM1.60 DIMM1.61 DIMM1.64 DIMM1.65 DIMM1.68 DIMM1.69 DIMM1.72 DIMM1.73 DIMM1.77 DIMM1.78 DIMM1.81 DIMM1.82 DIMM1.85 DIMM1.86 DIMM1.89 DIMM1.90 DIMM1.93 DIMM1.94 DIMM1.98 DIMM1.99 DIMM1.102 DIMM1.103 DIMM1.106 DIMM1.107 DIMM1.167 DIMM1.168 DIMM1.171 DIMM1.172 DIMM1.175 DIMM1.176 DIMM1.180 DIMM1.181 DIMM1.184 DIMM1.185 DIMM1.188 DIMM1.189 DIMM1.192 DIMM1.193 DIMM1.196 DIMM1.197 DIMM1.201 DIMM1.202 DIMM1.205 DIMM1.206 DIMM1.209 DIMM1.210 DIMM1.213 DIMM1.214 DIMM1.217 DIMM1.218 DIMM1.222 DIMM1.223 DIMM1.226 DIMM1.227 DIMM1.230 DIMM1.231 DIMM1.234 DIMM1.235 DIMM1.238 DIMM1.239 DIMM1.243 DIMM1.244 DIMM1.247 DIMM1.248 DIMM1.251 DIMM1.252 DIMM1.261 DIMM1.262 EC1601.2 EC1701.1 EC2401.2 EC2403.2 EC2601.2 EC2602.2 EC2701.2 EC2702.2 EC2703.2 EC2704.2 EC2705.2 EC2709.2 EC2710.2 EC2711.2 EC2901.2 EC2902.2 EC2903.2 EC2904.2 EC3301.2 EC3307.2 EC4301.2 EC4302.2 EC4303.2 EC4304.2 EC4305.1 EC4306.2 EC4307.2 EC4308.2 EC4309.2 EC4310.2 EC4311.2 EC4312.2 EC4313.2 EC4314.2 EC4315.2 EC4401.1 EC5501.2 EC5502.2 EC5503.2 EC5505.2 EC5506.2 EC5507.2 EC5510.2 EC5701.2 EC6001.2 EC6002.2 EC6501.2 EC6502.2 EC6503.2 EC6506.2 EC6601.2 EC6602.2 EC6603.2 EC8901.2 EC8902.2 EC8903.2 EC8904.2 EC8905.2 ED501.2 ED3301.3 ED3302.3 ED3303.3 ED3501.2 ED3502.2 ED3503.2 ED3504.2 ED3505.2 ED5501.2 ED6001.3 ED6001.8 ED6002.3 ED6002.8 FC1001.2 FC1002.2 FC1003.2 FC1201.2 FC1202.2 FC1601.2 FC2401.2 FC6002.2 FC8901.2 FC8902.2 FC8903.2 FC8904.2 FC8905.2 FC8906.2 FC8907.2 FC8908.2 FC8909.2 FC8910.2 FC8911.2 FC8912.2 FC8913.2 FC8914.2 FC8915.2 FC8916.2 FC8917.2 FC8918.2 FC8919.2 FC8920.2 FC8921.2 FC8922.2 FC8923.2 FC8924.2 FC8925.2 FC8926.2 FC8927.2 G1701.1 G1702.1 H1.1 H4.1 H9.1 H10.1 H11.1 H12.1 H13.1 H14.1 HDA27.41 HDD1.23 HDD1.24 HDD1.P4 HDD1.P5 HDD1.P6 HDD1.P10 HDD1.P12 HDD1.S1 HDD1.S4 HDD1.S7 HDMI1.2 HDMI1.5 HDMI1.8 HDMI1.11 HDMI1.17 HDMI1.20 HDMI1.21 HDMI1.22 HDMI1.23 HDT1.3 HDT1.5 HDT1.7 HDT1.17 IOBD1.14 IOBD1.24 IOBD1.27 IOBD1.30 IOBD1.33 IOBD1.45 IOBD1.46 KB1.30 KB1.31 KB1.32 LCD1.8 LCD1.11 LCD1.14 LCD1.17 LCD1.21 LCD1.28 LCD1.29 LCD1.32 LCD1.34 LCD1.35 LCD1.41 LCD1.42 LIDSW1.1 PC4302.2 PC4303.2 PC4304.2 PC4305.2 PC4306.2 PC4401.2 PC4402.2 PC4403.2 PC4405.2 PC4406.2 PC4410.2 PC4411.2 PC4418.2 PC4419.2 PC4427.2 PC4435.2 PC4436.2 PC4438.2 PC4445.2 PC4446.2 PC4452.2 PC4453.2 PC4456.2 PC4459.2 PC4461.1 PC4462.1 PC4464.2 PC4467.1 PC4468.1 PC4471.2 PC4501.2 PC4502.2 PC4503.2 PC4504.2 PC4505.2 PC4506.2 PC4507.2 PC4508.2 PC4509.2 PC4510.2 PC4513.2 PC4514.2 PC4517.2 PC4518.2 PC4601.1 PC4605.2 PC4608.2 PC4609.2 PC4610.2 PC4611.2 PC4612.1 PC4613.2 PC4617.2 PC4620.1 PC4621.1 PC4622.2 PC4623.2 PC4701.2 PC4702.2 PC4703.2 PC4704.2 PC4705.2 PC4706.2 PC4707.2 PC4709.2 PC4710.2 PC4711.2 PC4712.2 PC4713.2 PC4714.2 PC4715.2 PC4716.2 PC4718.2 PC4719.2 PC4720.2 PC4901.2 PC4902.2 PC4903.2 PC4904.2 PC4905.2 PC4906.2 PC4907.2 PC5201.2 PC5202.2 PC5203.2 PC5204.2 PC5205.2 PC5207.2 PC5208.2 PC5209.2 PC5210.2 PC5211.2 PC5212.2 PC5213.2 PC5214.2 PC5301.2 PC5302.2 PC5303.2 PC5304.2 PC5305.2 PC5307.2 PC5308.2 PC5309.2 PC5310.2 PC5311.2 PC5312.2 PC5313.2 PC5314.2 PC5315.2 PC5316.2 PC5317.2 PC5318.2 PC5320.2 PC5321.2 PC5405.2 PC5406.2 PC5407.2 PC5408.2 PC5410.2 PC5411.2 PC5412.2 PC5418.2 PC5419.2 PC5420.2 PC6301.2 PC6302.2 PC6304.2 PC6305.2 PD4301.A PD4302.A PD4303.1 PD4304.3 PD5201.A PD5301.A PQ4302.E PQ4304.2 PQ4309.S PQ4402.S PQ4405.1 PQ4405.4 PQ4412.S PQ4414.1 PQ4414.4 PQ4415.2 PQ4901.1 PQ4901.4 PR4302.2 PR4310.2 PR4403.2 PR4404.2 PR4405.2 PR4406.1 PR4412.2 PR4413.1 PR4416.2 PR4418.2 PR4433.2 PR4434.1 PR4436.2 PR4445.2 PR4478.2 PR4506.2 PR4507.2 PR4508.2 PR4512.2 PR4608.2 PR4612.1 PR4615.2 PR4618.2 PR4622.1 PR4629.2 PR4630.1 PR4631.2 PR4903.2 PR5208.2 PR5309.2 PR5316.2 PR5405.2 PR6301.2 PT4501.2 PT4502.2 PT4701.2 PT4702.2 PT4705.2 PT4706.2 PT4707.2 PT4708.2 PU4401.33 PU4412.1 PU4412.2 PU4412.3 PU4501.21 PU4504.1 PU4504.2 PU4504.3 PU4505.1 PU4505.2 PU4505.3 PU4601.41 PU4701.5 PU4701.6 PU4701.7 PU4702.5 PU4702.6 PU4702.7 PU4705.5 PU4705.6 PU4705.7 PU4706.5 PU4706.6 PU4706.7 PU4901.2 PU4901.9 PU5201.4 PU5201.5 PU5201.11 PU5201.12 PU5201.13 PU5201.14 PU5201.15 PU5201.16 PU5201.29 PU5201.30 PU5201.31 PU5201.32 PU5201.33 PU5301.4 PU5301.11 PU5301.12 PU5301.13 PU5301.14 PU5301.15 PU5301.16 PU5301.30 PU5301.32 PU5301.33 PU5302.1 PU5401.4 PU5401.8 PU5401.9 PU5402.2 PU6301.4 PU6301.8 PU6301.9 Q1701.1 Q1701.4 Q1702.1 Q1702.4 Q2401.C Q2402.S Q2403.S Q2405.S Q2502.S Q2505.S Q2507.S Q4001.S Q5401.S Q5701.S Q5707.S Q6507.1 Q6507.4 Q7001.1 Q7001.4 R302.2 R802.2 R803.2 R809.2 R811.2 R1201.1 R1202.1 R1204.2 R1208.1 R1210.1 R1601.1 R1603.2 R1609.2 R1613.1 R1614.1 R1620.1 R1621.1 R1636.1 R1717.1 R1718.1 R1719.1 R1721.1 R1723.1 R1724.1 R1756.1 R1757.1 R1761.1 R2007.2 R2008.2 R2009.2 R2010.2 R2011.2 R2012.2 R2415.2 R2419.2 R2428.1 R2442.2 R2443.2 R2468.2 R2497.1 R2505.2 R2507.2 R2516.2 R2613.2 R2704.2 R2705.2 R2706.2 R2735.2 R3304.1 R3311.1 R3605.2 R4002.2 R4014.2 R4301.1 R5502.2 R5505.1 R5506.1 R5507.1 R5508.1 R5709.1 R5711.2 R5719.2 R6005.2 R6007.2 R6008.2 R6009.2 R6010.2 R6012.2 R6346.2 R6355.2 R6357.2 R6359.2 R6360.2 R6504.2 R6515.1 R6903.1 RN808.3(B) RN808.4 RN809.3(B) RN809.4 RN1708.1 RN1708.2 RN1709.1 RN1709.2 RN1710.1 RN1710.2 RN6802.6 RN6802.7 RN6802.8 RTC1.2 RTC1.3 RTC1.4 SD1.4 SD1.10 SD1.11 SPK1.5 SPK1.6 SPR1.1 SPR2.1 SPR3.1 SPR4.1 SPR5.1 SPR6.1 TPAD1.4 TPAD1.9 TPAD1.10 U801.2 U2401.5 U2401.12 U2401.18 U2401.45 U2401.78 U2401.89 U2401.116 U2404.2 U2501.4 U2502.1 U2601.5 U3301.25 U3601.2 U4001.11 U4001.15 U4002.11 U4002.15 U4003.9 U5501.2 U6001.3 U6001.13 U6001.18 U6001.21 U6301.A6 U6301.C4 U6301.E7 U6301.G5 U6301.H10 U6301.J5 U6301.K8 U6301.N2 U6301.N5 U6301.P4 U6301.P6 U6304.A1 U6304.A2 U6304.B10 U6304.C1 U6304.C2 U6304.C5 U6304.D6 U6304.D7 U6304.E2 U6304.E3 U6304.E4 U6304.E5 U6304.F3 U6304.F4 U6304.F7 U6304.G3 U6304.G4 U6304.G5 U6304.J1 U6304.J2 U6304.J5 U6304.J7 U6304.K3 U6304.K9 U6305.4 U6901.5 U6901.6 U6901.7 U6901.8 USB1.4 USB1.7 USB1.10 USB1.11 USB1.12 USB1.13 WLAN1.1 WLAN1.7 WLAN1.18 WLAN1.23 WLAN1.24 WLAN1.29 WLAN1.30 WLAN1.33 WLAN1.36 WLAN1.39 WLAN1.45 WLAN1.51 WLAN1.57 WLAN1.63 WLAN1.69 WLAN1.75 X1601.2 X1601.4 X6301.2
V3D3_STB: HDA27.16 R2708.2
VCCCORE_SENSE: CPU1.D31 PG4610.2 PR4634.2
VDD: PC4446.1 PR4401.1 PR4402.1 PR4438.1 PR4451.1 PU4401.19
VDDCR_FCH: C1043.1 C1044.1 C1045.1 C1078.1 C1079.1 C1080.1 C4015.1 C4016.1 CPU1.AR4 CPU1.AR5 CPU1.AR7 CPU1.AU7 U4003.7 U4003.8
VDDCR_FCH_EN: R4010.1 U4003.5
VDDIO_AUDIO: C1064.1 C1065.1 C1081.1 CPU1.AM13 R704.2
VDDNB_SENSE: CPU1.E33 PG4601.2
VDDQ_PWRGD: PR5303.2 PU5301.8 TP5301.1
VSSCORE_SENSE: PG4609.2 PR4631.1 RN810.4
VSSNB_SENSE: PG4611.2 RN810.3(B)
0D6V_VREF_S0: C1222.1 C1223.1 C1228.1 DIMM1.258 PG5314.1 PG5315.1
0D95V_S0: C1034.1 C1035.1 C1036.1 C1037.1 C1038.1 C1039.1 C1040.1 C1041.1 C1042.1 C1046.1 C1047.1 C1051.1 C4007.2 CPU1.AJ21 CPU1.AJ23 CPU1.AJ25 CPU1.AJ27 CPU1.AL23 CPU1.AL25 CPU1.AL27 CPU1.AL29 FC8926.1 FC8927.1 PR6303.1 R301.1 R1602.1 U4002.13 U4002.14
0D95V_S0_EN: C4011.1 R4007.2 U4002.3
0D95V_S5: C1048.1 C1049.1 C1050.1 CPU1.AJ11 CPU1.AL11 CPU1.AL13 PG5204.2 PG5205.2 PG5206.2 PG5207.2 PG5208.2 PG5209.2 PG5210.2 PG5211.2 R1610.2 U4002.1 U4002.2
0D95V_S5_EN: PR5206.1 RN2407.1 U2401.9
0D95V_S5_PWRGD: PR5204.1 U2401.20
0D775V_S5: C4013.1 C4014.1 PG4901.2 U4003.3
1D2V_CPU_VDDNB: C1010.1 C1011.1 C1012.1 C1013.1 C1014.1 C1015.1 C1016.1 C1017.1 C1018.1 C1019.1 C1020.1 C1021.1 C1071.1 C1072.1 C1073.1 C1074.1 C1076.1 C4008.1 C4009.1 CPU1.AA11 CPU1.AA13 CPU1.AA15 CPU1.AA17 CPU1.AA19 CPU1.AA21 CPU1.AA23 CPU1.AE11 CPU1.AE13 CPU1.AE15 CPU1.AE17 CPU1.AE19 CPU1.AE21 CPU1.AE23 CPU1.AE25 CPU1.AE27 CPU1.AE29 CPU1.AE31 CPU1.E9 CPU1.E11 CPU1.E13 CPU1.E15 CPU1.E17 CPU1.E19 CPU1.G7 CPU1.J7 CPU1.K11 CPU1.K13 CPU1.K15 CPU1.K17 CPU1.K19 CPU1.L7 CPU1.L10 CPU1.L15 CPU1.L17 CPU1.N7 CPU1.N11 CPU1.N13 CPU1.N15 CPU1.N17 CPU1.N19 CPU1.R7 CPU1.U7 CPU1.U11 CPU1.U13 CPU1.U15 CPU1.U17 CPU1.U19 CPU1.U21 CPU1.W7 PC4718.1 PC4719.1 PG4713.2 PL4702.2 PR4601.1 PT4705.1 PT4706.1 U4003.1 U4003.2
1D2V_S3: C1022.1 C1023.1 C1024.1 C1025.1 C1026.1 C1027.1 C1028.1 C1029.1 C1030.1 C1031.1 C1032.1 C1033.1 C1077.1 C1203.1 C1204.1 C1205.1 C1206.1 C1207.1 C1208.1 C1209.1 C1210.1 C1212.1 C1213.1 C1214.1 C1215.1 C1216.1 C1217.1 C1218.1 C1219.1 CPU1.AA35 CPU1.AC32 CPU1.AC37 CPU1.AE32 CPU1.AE35 CPU1.AG32 CPU1.AG37 CPU1.AJ32 CPU1.AJ35 CPU1.AL32 CPU1.AL37 CPU1.AR35 CPU1.J35 CPU1.L32 CPU1.L37 CPU1.N35 CPU1.R37 CPU1.U32 CPU1.U35 CPU1.W32 CPU1.W37 DIMM1.111 DIMM1.112 DIMM1.117 DIMM1.118 DIMM1.123 DIMM1.124 DIMM1.129 DIMM1.130 DIMM1.135 DIMM1.136 DIMM1.141 DIMM1.142 DIMM1.147 DIMM1.148 DIMM1.153 DIMM1.154 DIMM1.159 DIMM1.160 DIMM1.163 FC1201.1 FC1202.1 PG5302.2 PG5304.2 PG5306.2 PG5307.2 PG5308.2 PG5309.2 PG5310.2 PG5311.2 R503.1 R504.1 R1203.2 R1206.1
1D8V_AUX_EN: PC5418.1 PR5414.1 PU5402.3 Q5401.D
1D8V_AUX_PWR: PC5419.1 PG5411.1 PU5402.5
1D8V_AUX_S5: C2439.1 FC2401.1 PG5411.2 R2465.1 R2486.1
1D8V_DVDD-IO: C2723.1 C2724.1 C2742.1 C2743.1 HDA27.8 R2742.2
1D8V_PWR: PC5407.1 PC5408.1 PC5410.1 PG5401.1 PG5404.2 PG5405.2 PG5406.2 PL5401.2
1D8V_PWR_VIN: PC5420.1 PR5410.2 PR5413.2 PU5402.1
1D8V_S0: C803.2 C1055.1 C1056.1 C1057.1 C4010.2 CPU1.AJ15 CPU1.AL17 HDT1.1 HDT1.19 PG4606.1 PR4619.1 Q801.2 Q801.5 Q6301.G R704.1 R801.1 R808.1 R812.1 R822.1 R1615.2 R2515.2 R2709.1 R2742.1 R2752.1 R5521.1 R5526.1 R6309.1 R6313.2 R6325.2 R6514.1 RN803.5(B) RN803.6 RN803.7 RN803.8 RN804.1 RN804.2 RN804.3 RN804.4 RN806.1 RN806.2 RN807.1 RN807.2 RN1705.1 RN1705.2 U801.5 U4002.8 U4002.9
1D8V_S0_EN: C4027.1 D4004.3 Q2507.G R2516.1 R4016.1
1D8V_S0_EN_D: Q2506.G Q2507.D R2518.1
1D8V_S0_EN_R: R4015.2 R4016.2 U4002.5
1D8V_S5: C1052.1 C1053.1 C1054.1 C2446.1 CPU1.AJ13 CPU1.AL15 PG4902.2 PG5404.1 PG5405.1 PG5406.1 PR4902.1 R1616.2 R1746.2 R2421.1 R2436.1 R2517.2 R5522.1 U2404.1 U4002.6 U4002.7
1D8V_S5_PWRGD: PR5209.1 PR5412.1
1D8V_SPI_EN#: R4008.1 R4014.1 U2401.100
1D8V_SPI_S5: C2501.1 C2502.1 Q2506.D R2515.1 R2540.1 RN1601.3(B) RN1601.4 U2501.8
3D3V_AUX_KBC: D4301.2 D4302.2 D4303.2 PR5414.2 Q2404.D R2407.1 R2408.2 R2409.2 R2410.1 R2463.1 R2490.1 R2608.1 R2615.1 RN2404.1 RN2404.2 RN2407.3(B) RN2407.4
3D3V_AUX_S5: C2403.1 C2442.2 PG4524.1 PR4409.1 PR4435.1 PR4449.1 PR4450.1 PR5413.1 Q2404.S Q2501.2 R2472.1 R2473.1 R2489.2 R2491.2 R2513.2 R2514.1 R2614.1 R4013.1 RN1706.3(B) RN1706.4 U2401.75
3D3V_CAMERA_S0: C5514.1 EC5510.1 F5502.2 LCD1.40 R5533.2
3D3V_CARD: C3301.1 C3302.1 C3303.1 C3304.1 C3305.1 SD1.6 U3301.5
3D3V_CARD_S0: C3306.1 C3307.1 R3302.2 U3301.4
3D3V_GSEN2: C6901.1 C6902.1 R6901.2 R6902.1 R6905.1 U6901.9 U6901.10
3D3V_LCDVDD_S0: C5508.1 C5509.2 C5511.1 C5521.1 LCD1.37 LCD1.38 U5501.1
3D3V_MSATA_S0: C6014.1 C6015.1 C6018.1 HDD1.P1 HDD1.P2 R6014.2 R6015.2
3D3V_S0: AFTP6601.1 C1061.1 C1062.1 C1063.1 C1201.1 C2432.1 C2433.1 C2601.1 C2602.1 C4004.1 C5512.1 C6011.1 C6012.1 C6013.1 C6016.1 C6017.1 C6308.1 C6309.1 C6310.1 C6318.1 C6320.1 C6330.1 C6335.1 C6341.1 CPU1.AJ19 CPU1.AL21 DB1.10 DIMM1.255 EC8902.1 EC8903.1 EC8904.1 EC8905.1 F5502.1 FC1003.1 FC6002.1 FC8916.1 FC8917.1 FC8918.1 FC8919.1 FC8920.1 IOBD1.36 PC6302.1 PC6305.1 PR4611.1 PR4620.1 PU6301.3 PU6301.7 Q2604.2 Q2604.5 Q5701.G Q5703.G Q5705.G Q5708.C R1205.1 R1207.1 R1209.1 R1708.1 R1713.1 R1715.1 R1758.1 R2004.1 R2005.1 R2006.1 R2400.1 R2420.1 R2422.1 R2423.1 R2475.1 R2478.1 R2499.1 R2605.1 R2606.1 R2607.2 R2715.1 R2716.1 R3302.1 R3307.1 R4006.1 R5516.1 R5527.1 R5533.1 R5719.1 R6002.1 R6003.1 R6004.1 R6006.1 R6011.1 R6013.1 R6014.1 R6015.1 R6105.1 R6324.2 R6345.1 R6347.1 R6348.1 R6354.1 R6356.1 R6361.1 R6364.1 R6513.2 R6901.1 R7002.1 R7005.1 RN811.1 RN811.2 RN1703.1 RN1703.2 RN2403.1 RN2403.2 RN2601.1 RN2601.2 RN6901.1 RN6901.2 U2401.4 U2601.1 U4001.8 U4001.9 U5501.5 U6001.7 U6001.10 U6001.20 U6304.C6 U6304.D4 U6304.E7 U6304.F2 U6304.G2 U6304.H1 U6304.J3 U6304.K5 U6304.K8 U6305.3 U6305.8
3D3V_S5: C1058.1 C1059.1 C1060.1 C2445.1 C6702.1 CPU1.AJ17 CPU1.AL19 FC1001.1 FC1002.1 IOBD1.37 LIDSW1.2 PD4303.2 PG4501.1 PG4507.1 PG4512.1 PG4515.1 PG4517.1 PG4520.1 PG5402.1 PG5403.1 PR4306.1 PR4448.2 PR4472.1 PR4513.1 PR4901.1 PR5203.1 PR5303.1 PR5311.2 PR5407.1 R1702.1 R1703.1 R1707.1 R1709.1 R1710.1 R1711.1 R1733.1 R1735.1 R1738.1 R1747.1 R1759.1 R1760.1 R2001.1 R2002.1 R2003.1 R2434.1 R2444.1 R2471.1 R2474.1 R4010.2 R4011.2 R5701.1 R6106.1 R6501.1 R6701.2 RN1701.1 RN1701.2 RN2401.1 RN2401.2 U2404.6 U4001.6 U4001.7
3D3V_WLAN_S0: AFTP6101.1 C6102.1 C6103.1 C6104.1 R6105.2 R6106.2 R6111.1 R6112.1 WLAN1.2 WLAN1.4 WLAN1.72 WLAN1.74
25M_48M_OSC: CPU1.AL8 TP1608.1
48M_X1: C1601.2 CPU1.F2 R1624.1 X1601.3
48M_X2: CPU1.F1 R1624.2 R1625.2
+DC_IN: EC4308.1 EC4309.1 EC4310.1 EC4311.1 EC4312.1 EC4313.1 EL4301.2 EL4302.2 EL4303.2 EL4304.2 PC4301.1 PC4302.1 PD4301.K PQ4305.2 PR4309.1 PR4316.1 PU4301.1 PU4301.2 PU4301.3
+DC_IN_C: AFTP4307.1 AFTP4309.1 DCIN1.5 DCIN1.6 EC4304.1 EC4306.1 EL4301.1 EL4302.1 EL4303.1 EL4304.1
+RTC_PWR: R2501.2 RTC1.1
+SDC_IN: PG4429.2 PQ4408.1 PQ4408.2 PQ4408.3 PR4426.1 PR4441.1
+VCHGR: PG4428.2 PL4401.2 PQ4401.5 PQ4401.6 PQ4401.7 PQ4401.8 PR4443.1
AC_DIS_R: PC4471.1 PQ4412.G PR4444.2
AC_PRES_KBC: R1734.1 U2401.113
AC_PRES_R: CPU1.AH2 R1717.2 R1734.2
ACLIM: PR4401.2 PR4403.1 PU4401.16
ACOK_IN: PQ4405.2 PR4417.2 PR4418.1 PR4474.1 Q2405.G
AD+: EC4314.1 EC4315.1 EC4401.2 PC4303.1 PC4304.1 PC4305.1 PC4306.1 PD4410.1 PQ4408.5 PQ4408.6 PQ4408.7 PQ4408.8 PR4420.1 PR4431.1 PR4440.1 PR4445.1 PR4452.1 PU4301.5 PU4301.6 PU4301.7 PU4301.8
AD+_G_1: PQ4405.5 PQ4405.6 PR4422.1
AD+_G_2: PQ4408.4 PR4422.2 PR4441.2
AD+_R: PQ4401.4 PQ4412.D PR4440.2
AD_IA: C2428.2 C2438.2 PC4402.1 PR4475.1 U2401.97
AD_OFF_L: PQ4304.3 PQ4305.1
AD_OFF_R: PC4301.2 PQ4305.3 PR4309.2 PR4310.1 PU4301.4
AGPIO3: CPU1.AJ7 R2003.2 R2009.1
AGPIO11: CPU1.AJ8 R1710.2
AGPIO92: CPU1.AY32 R1761.2
AGPIO130: CPU1.AY30 R1636.2
ALERT#: R2605.2 U2601.6
APU_ALERT#: CPU1.A30 RN804.6
APU_DBRDY: CPU1.A26 HDT1.14
APU_DBREQ#: CPU1.A25 HDT1.16 R812.2
APU_DEVSLP1: CPU1.AU31 R1613.2 TP1605.1
APU_FANIN: CPU1.AV33 TP1706.1
APU_FANOUT: CPU1.AU33 TP1707.1
APU_KBRST#: CPU1.BA30 R1633.1
APU_LDRQ0#: CPU1.AY18 TP1602.1
APU_LPC_AD0: CPU1.BA26 RN1605.4
APU_LPC_AD1: CPU1.AY28 RN1605.3(B)
APU_LPC_AD2: CPU1.AY25 RN1606.3(B)
APU_LPC_AD3: CPU1.AY23 RN1606.4
APU_LPC_CLKRUN#: CPU1.AY26 R1630.2
APU_LPC_FRAME#: CPU1.AY24 R1618.2
APU_LPC_PD#: CPU1.AC1 R1614.2 R1632.2
APU_LPC_PME#: CPU1.AA8 R1634.2
APU_LPC_RST#: CPU1.AY27 R1629.2
APU_LPC_SERIRQ: CPU1.AV27 R1631.2
APU_LPC_SMI#: CPU1.BA27 R1635.2
APU_LPCCLK0: CPU1.BA25 R1611.2
APU_LPCCLK1: CPU1.BA24 R1612.2 R2005.2 R2011.1
APU_PWRBTN#_R: CPU1.AD2 R1702.2 R1730.2
APU_PWROK: PR4621.2 PU4601.9
APU_PWROK_HDT: HDT1.10 R823.2 RN806.3(B) U801.4
APU_RSMRST#: Q1701.5 Q1702.3 R1719.2 R1748.1
APU_RSMRST#_R: C1702.2 CPU1.AG1 Q1701.6 R1746.1
APU_RST#: R808.2 R816.1 R821.1 U801.1
APU_RST#_R: C801.1 CPU1.D29 R816.2
APU_RST_L_BUF: HDT1.12 R821.2 RN806.4 U801.6
APU_S0A3_IND: CPU1.AB1 R1757.2
APU_SIC: CPU1.B30 Q801.4 RN804.7
APU_SID: CPU1.B29 Q801.1 RN804.5(B)
APU_SLP_S3#: CPU1.AC2 D4002.K D4003.K D4004.1 PR5307.1 R1733.2 R4001.1 R4007.1 R4009.2 R4012.1 R4015.1 U2401.64
APU_SLP_S5#: CPU1.AG4 PQ4415.1 PR5314.1 PR5319.1 R1738.2 U2401.21
APU_SPI_CLK: CPU1.AY17 RN1603.1
APU_SPI_CS1#: CPU1.AY21 R1616.1 RN1604.1
APU_SPI_CS2#: CPU1.AY19 R1615.1 R1621.2 TP1609.1
APU_SPI_HOLD#: CPU1.BA18 R1617.1
APU_SPI_SI_R: CPU1.AY20 RN1603.2
APU_SPI_SO_R: CPU1.BA17 RN1604.2
APU_SPI_TPM_CS#: CPU1.BA21 R1620.2 TP1601.1
APU_SPI_WP#: CPU1.BA20 R1619.1
APU_SVC: CPU1.E27 R813.2
APU_SVD: CPU1.D27 R820.2
APU_SVT: CPU1.H27 R810.2
APU_TCK: CPU1.B27 HDT1.2 RN803.3
APU_TDI: CPU1.B25 HDT1.6 RN803.1
APU_TDO: CPU1.A27 HDT1.8
APU_TEST0: CPU1.AF2 RN1701.3(B) RN1708.4
APU_TEST1: CPU1.AE1 R1711.2 R1721.2
APU_TEST2: CPU1.AC8 RN1701.4 RN1708.3(B)
APU_TEST6: CPU1.H25 TP803.1
APU_TEST9: CPU1.R32 TP804.1
APU_TEST10: CPU1.N32 TP805.1
APU_TEST14_BP1: CPU1.G21 R811.1 TP806.1
APU_TEST15_BP3: CPU1.H21 TP807.1
APU_TEST16_BP5: CPU1.D23 RN808.2 TP808.1
APU_TEST17_BP7: CPU1.E23 RN808.1 TP809.1
APU_TEST18_HDT20: CPU1.A28 HDT1.20 RN809.1 TP810.1
APU_TEST19_HDT18: CPU1.B28 HDT1.18 RN809.2 TP811.1
APU_TEST28_H: CPU1.N8 TP812.1
APU_TEST28_L: CPU1.N10 TP813.1
APU_TEST31: CPU1.H31 TP814.1
APU_TEST36: CPU1.D25 R809.1 R822.2 TP815.1
APU_TEST41: CPU1.B31 TP816.1
APU_THERMDA: CPU1.H29 TP801.1
APU_THERMDC: CPU1.G29 TP802.1
APU_TMS: CPU1.B26 HDT1.4 RN803.2
APU_TRST#: CPU1.A29 R6804.1 RN803.4
APU_TRST#_R: C6801.1 HDT1.9 R6804.2
APU_VSS_SENSE_A: CPU1.D33 RN810.1 RN810.2
AUD_AGND: AFTP2908.1 C2702.1 C2703.2 C2706.2 C2707.2 C2710.2 C2711.2 C2715.2 C2902.1 EC2701.1 EC2702.1 EC2703.1 EC2704.1 EC2705.1 EC2905.2 EC2906.2 EC2907.2 EC2908.2 HDA27.19 HDA27.31 IOBD1.1 IOBD1.13 Q2901.S R2702.2 R2704.1 R2705.1 R2706.1 R2905.2
AUD_HP1_JACK_L: HDA27.25 R2908.1 R2922.2 R2928.2
AUD_HP1_JACK_L1: EC2907.1 R2907.1 R2908.2
AUD_HP1_JACK_R: HDA27.26 R2910.1 R2912.2 R2921.2
AUD_HP1_JACK_R1: EC2908.1 R2909.1 R2910.2
AUD_PC_BEEP: C2735.2 HDA27.11
AUD_PC_BEEP_C: C2735.1 C2739.1 D2703.3 R2735.1
AUD_PORTA_L_R_B: AFTP2906.1 IOBD1.12 R2907.2
AUD_PORTA_R_R_B: AFTP2907.1 IOBD1.11 R2909.2
AUD_SENSE: AFTP2909.1 Q2901.D R2711.1 R2914.2
AUD_SENSE_A: HDA27.12 R2710.2 R2711.2
AUD_SPK_11_L+: EC2902.1 R2743.1 R2902.1
AUD_SPK_11_L-: EC2901.1 R2745.1 R2901.1
AUD_SPK_11_R+: EC2904.1 R2749.1 R2904.1
AUD_SPK_11_R-: EC2903.1 R2747.1 R2903.1
AUD_SPK_L+_C11: AFTP2902.1 R2902.2 SPK1.3
AUD_SPK_L+_R: HDA27.35 R2743.2
AUD_SPK_L-_C11: AFTP2901.1 R2901.2 SPK1.4
AUD_SPK_L-_R: HDA27.36 R2745.2
AUD_SPK_R+_C11: AFTP2904.1 R2904.2 SPK1.1
AUD_SPK_R+_R: HDA27.38 R2749.2
AUD_SPK_R-_C11: AFTP2903.1 R2903.2 SPK1.2
AUD_SPK_R-_R: HDA27.37 R2747.2
AUD_VREF: C2702.2 HDA27.22
BAT_IN#: D4302.3 EC4305.2 PC4433.1 PR4409.2 PR4439.2 PR4472.2 R2463.2 RN4301.2 U2401.80
BAT_SCL: D4301.3 EC4301.1 PR4471.1 RN2404.3(B) RN4302.2 U2401.70
BAT_SDA: D4303.3 EC4302.1 PR4470.1 RN2404.4 RN4301.1 U2401.69
BKLT_CTRL: D5502.3 R5505.2 R5524.1 RN5503.3(B)
BLON_OUT: RN5504.4 U2401.27
BLON_OUT_C: LCD1.25 R5506.2 RN5504.1
BLUETOOTH_EN: AFTP6110.1 R2478.2 R6110.1 U2401.83
BLUETOOTH_EN_R: R6110.2 R6111.2 WLAN1.54
BP_D: PQ4402.D PR4415.2
BP_G: PC4433.2 PQ4402.G PR4478.1
BT_USB20_CON_N5: AFTP6111.1 EL6101.1 WLAN1.5
BT_USB20_CON_P5: AFTP6113.1 EL6101.2 WLAN1.3
BT_USB20_N5: CPU1.AP2 EL6101.4
BT_USB20_P5: CPU1.AP1 EL6101.3
CAP_LED: AFTP6533.1 EC6506.1 KB1.27 R6503.2
CAP_LED#: R6502.1 U2401.109
CAP_LED_Q: Q6501.C R6503.1
CAP_LED_R#: Q6501.B R6502.2
CARD1_USB20_CON_N2: EL3301.2 U3301.2
CARD1_USB20_CON_P2: EL3301.1 U3301.3
CARD1_USB20_N2: CPU1.AU2 EL3301.3
CARD1_USB20_P2: CPU1.AU1 EL3301.4
CARD_AV18: C3308.2 U3301.24
CARD_RREF: R3304.2 U3301.1
CBN: C2708.1 HDA27.28
CBP: C2708.2 HDA27.30
CCD_USB20_CON_N0: EL5501.2 LCD1.16
CCD_USB20_CON_P0: EL5501.1 LCD1.15
CCD_USB20_N0: CPU1.AW2 EL5501.3
CCD_USB20_P0: CPU1.AW1 EL5501.4
CCLIM: PR4402.2 PR4404.1 PU4401.11
CLK_REQG: CPU1.AV35 R7005.2
CPVDD: C2704.1 C2705.1 HDA27.29 R2709.2
CPVEE: C2709.1 HDA27.27
CR_GPIO0: TP3301.1 U3301.17
DBC_EN: CPU1.AY14 R5501.2
DBC_EN_R: LCD1.22 R5501.1
DBRDY1: HDT1.15 RN6802.1
DBRDY2: HDT1.13 RN6802.2
DBRDY3: HDT1.11 RN6802.3
DC_IN_D: PQ4405.3 PR4420.2
DCBATOUT: EC5501.1 EC5502.1 EC5503.1 F5501.1 FC8901.1 FC8902.1 FC8903.1 FC8904.1 FC8905.1 FC8906.1 FC8907.1 FC8908.1 FC8909.1 FC8910.1 FC8911.1 FC8912.1 FC8913.1 FC8914.1 FC8915.1 PC4418.1 PC4427.1 PC4438.1 PC4456.1 PC4459.1 PC4506.1 PC4507.1 PG4407.2 PG4503.1 PG4505.1 PG4506.1 PG4508.1 PG4510.1 PG4513.1 PG4514.1 PG4701.1 PG4702.1 PG4703.1 PG4704.1 PG4705.1 PG4708.1 PG4709.1 PG4710.1 PG4711.1 PG5201.1 PG5202.1 PG5203.1 PG5301.1 PG5303.1 PG5305.1 PQ4401.1 PQ4401.2 PQ4401.3 PR4426.2 PR4432.1 PR4477.1 PT4707.1 PT4708.1 PU4411.5 PU4411.6 PU4411.7 PU4411.8 PU4501.12
DDR4_A_DRAMRST#: C1211.1 CPU1.G38 DIMM1.108 ED501.1
DDR_VREF_S3: CPU1.AA40 TP502.1
DM1_SA0: DIMM1.256 R1209.2 R1210.2
DM1_SA1: DIMM1.260 R1207.2 R1208.2
DM1_SA2: DIMM1.166 R1201.2 R1205.2
DMIC_CLK: C2725.1 EC5506.1 R2720.1 RN5502.3(B)
DMIC_CLK_C: LCD1.18 RN5502.2
DMIC_CLK_R: HDA27.3 R2720.2
DMIC_DATA: EC2711.1 EC5505.1 R2718.1 RN5502.4
DMIC_DATA_C: LCD1.19 RN5502.1
DMIC_DATA_R: HDA27.2 R2718.2
DP_2K_ZVSS: CPU1.B18 R803.1
DP_150_ZVSS: CPU1.D21 R802.1
DP_HPD0_C: LCD1.24 RN5503.1
E51_RX1: R6109.2 TP6102.1 WLAN1.46
E51_RX2: TP6101.1 WLAN1.58
E51_TX1: R6107.2 R6108.2 WLAN1.44
E51_TXD: R6107.1 U2401.111
EC_AGND: C2416.2 C2417.2 C2436.2 C2438.1 R2415.1 R2438.2 U2401.103
EC_AVCC: C2416.1 C2436.1 R2409.1 R2437.1 U2401.102
EC_BRIGHTNESS: D5502.2 U2401.106
EC_MUTE#: R2497.2 R2712.1 R2717.2 U2401.30
EC_VCC1V8: R2486.2 U2401.88
ECRST#: C2444.2 Q2401.E R2465.2 U2401.85
ECSCI#_KBC: R1634.1 R2423.2 U2401.29
ECSMI#_KBC: R1632.1 R1635.1 R2422.2 U2401.6
EDP_AUX_CON_N: C5505.1 LCD1.13
EDP_AUX_CON_P: C5501.1 LCD1.12
EDP_AUX_CPU_N: C5505.2 CPU1.H15
EDP_AUX_CPU_P: C5501.2 CPU1.G15
EDP_BLON: CPU1.B23 U2401.91
EDP_HPD_CPU: CPU1.D15 R5507.2 RN5503.4
EDP_TX_CON_N0: C5507.1 LCD1.9
EDP_TX_CON_N1: C5513.1 LCD1.6
EDP_TX_CON_P0: C5506.1 LCD1.10
EDP_TX_CON_P1: C5510.1 LCD1.7
EDP_TX_CPU_N0: C5507.2 CPU1.B9
EDP_TX_CPU_N1: C5513.2 CPU1.B10
EDP_TX_CPU_P0: C5506.2 CPU1.A9
EDP_TX_CPU_P1: C5510.2 CPU1.A10
EGPIO95: CPU1.BA14 TP1708.1
EGPIO96: CPU1.AY15 TP1709.1
EGPIO99: CPU1.BA16 TP1710.1
EGPIO100: CPU1.AY16 TP1711.1
EMMC_CLK: R6312.1 R6343.1
EMMC_CLK_R: R6343.2 U6304.G10
EMMC_CMD: R6313.1 R6344.1 U6301.M5
EMMC_CMD_R: R6344.2 U6304.H10
EMMC_D0: RN6302.3 U6301.A3
EMMC_D0_R: RN6302.6 U6304.F10
EMMC_D1: RN6301.1 U6301.A4
EMMC_D1_R: RN6301.8 U6304.F9
EMMC_D2: RN6301.3 U6301.A5
EMMC_D2_R: RN6301.6 U6304.G9
EMMC_D3: RN6302.1 U6301.B2
EMMC_D3_R: RN6302.8 U6304.H9
EMMC_D4: RN6302.2 U6301.B3
EMMC_D4_R: RN6302.7 U6304.J10
EMMC_D5: RN6302.4 U6301.B4
EMMC_D5_R: RN6302.5(B) U6304.J9
EMMC_D6: RN6301.2 U6301.B5
EMMC_D6_R: RN6301.7 U6304.G8
EMMC_D7: RN6301.4 U6301.B6
EMMC_D7_R: RN6301.5(B) U6304.H8
EMMC_E9: TP6301.1 U6301.E9
EMMC_E10: TP6302.1 U6301.E10
EMMC_F10: TP6303.1 U6301.F10
EMMC_K10: TP6304.1 U6301.K10
EMMC_R_CLK: R6312.2 U6301.M6
EMMC_RESET#: C6349.1 Q6301.S R6309.2 R6327.1 U6301.K5
EMMC_SATA_RX_N1: C6348.1 CPU1.BA8
EMMC_SATA_RX_N1_C: C6348.2 U6304.B2
EMMC_SATA_RX_P1: C6347.1 CPU1.AY8
EMMC_SATA_RX_P1_C: C6347.2 U6304.B1
EMMC_SATA_TX_N1: C6346.1 CPU1.BA9
EMMC_SATA_TX_N1_C: C6346.2 U6304.D2
EMMC_SATA_TX_P1: C6345.1 CPU1.AY9
EMMC_SATA_TX_P1_C: C6345.2 U6304.D1
EMMC_VCC: C6302.1 C6305.1 R6324.1 U6301.E6 U6301.F5 U6301.J10 U6301.K9
EMMC_VCC1N: R6347.2 U6304.H7
EMMC_VCC2N: R6348.2 U6304.J8
EMMC_VCCQ: C6303.1 C6304.1 R6325.1 U6301.C6 U6301.M4 U6301.N4 U6301.P3 U6301.P5
EMMC_VDDI: C6301.1 U6301.C2
FALL_INT2: Q7001.2 Q7001.3 R7002.2
FAN_PWM1_C: TP2408.1 U2401.22
FAN_TACH1: D2403.A R2498.1 R2499.2 U2401.31
FAN_TACH1_C: D2403.K R2498.2 TP2409.1
FFS_INT2: CPU1.AV29 Q7001.5 R1758.2 R6937.1 R7001.1
FFS_INT2_Q: EC6002.1 Q7001.6 R6001.1 R7001.2
FFS_INT2_Q_R: HDD1.P11 R6001.2
GPIO0: R6359.1 R6364.2 U6304.B9
GPIO1: R6356.2 U6304.C8
GPIO2: R6360.1 U6304.B8
GPIO3: R6361.2 U6304.A8
GPIO4: R6355.1 U6304.C7
GPIO5: R6357.1 U6304.B7
GPIO67: RN2407.2 U2401.123
GROUPB_PWRGD: PR4617.1 R4005.2
GROUPB_PWRGD_R: C4012.1 D4003.A R4005.1 R4006.2
GSEN2_INT1: IOBD1.18 R6933.2
GSEN2_INT1_R: R6933.1 U6901.12
GSEN2_INT2: IOBD1.17 R6934.2 R6937.2
GSEN2_INT2_R: R6934.1 U6901.11
GSENSOR_CS: R6905.2 U6901.2
GSENSOR_SDO: R6902.2 R6903.2 U6901.3
H_A20GATE: CPU1.AU35 R1713.2 U2401.121
H_PROCHOT#: CPU1.A31 PG4604.1 PR4415.1 PR4447.2 PR4450.2 PU4401.5 Q2402.D RN804.8
HALL_KB_DIS#: IOBD1.21 R2434.2 U2401.105
HDA_BITCLK_CODEC: R2753.1 RN1707.3
HDA_BITCLK_CODEC_R: EC2710.1 HDA27.5 R2753.2
HDA_CODEC_BITCLK_R: CPU1.AY6 R1723.2 RN1707.6
HDA_CODEC_SDIN0_R: CPU1.BA6 R1724.2 RN1707.5(B)
HDA_CODEC_SDIN1_R: CPU1.AY5 RN1710.4
HDA_CODEC_SDIN2_R: CPU1.BA5 RN1710.3(B)
HDA_CODEC_SDOUT_R: CPU1.BA4 RN1707.7 RN1709.3(B)
HDA_CODEC_SYNC_R: CPU1.BA3 RN1707.8 RN1709.4
HDA_SDIN0_CPU: HDA27.7 RN1707.4
HDA_SDOUT_CODEC: EC2709.1 HDA27.4 RN1707.2
HDA_SPKR_R: D2703.1 R2741.2
HDA_SYNC_CODEC: HDA27.9 RN1707.1
HDD_DEVSLP: CPU1.AV31 HDD1.P3
HDD_DEW1: R6010.1 R6011.2 U6001.16
HDD_DEW2: R6012.1 R6013.2 U6001.6
HDD_SATA_RX_CON_N0: C6003.2 HDD1.S5 R6018.1
HDD_SATA_RX_CON_P0: C6004.2 HDD1.S6 R6019.1
HDD_SATA_RX_N0: C6008.2 C6022.1 CPU1.AY12
HDD_SATA_RX_P0: C6007.2 C6021.1 CPU1.BA12
HDD_SATA_RX_RE_N0: C6003.1 ED6001.4 ED6001.7 U6001.12
HDD_SATA_RX_RE_N1: C6022.2 ED6002.4 ED6002.7 R6018.2
HDD_SATA_RX_RE_P0: C6004.1 ED6001.5 ED6001.6 U6001.11
HDD_SATA_RX_RE_P1: C6021.2 ED6002.5 ED6002.6 R6019.2
HDD_SATA_TX_CON_N0: C6002.2 HDD1.S3 R6017.1
HDD_SATA_TX_CON_P0: C6001.2 HDD1.S2 R6016.1
HDD_SATA_TX_N0: C6010.1 C6019.1 CPU1.AY10
HDD_SATA_TX_P0: C6009.1 C6020.1 CPU1.BA10
HDD_SATA_TX_RE_N0: C6002.1 ED6001.2 ED6001.9 U6001.14
HDD_SATA_TX_RE_N1: C6019.2 ED6002.2 ED6002.9 R6017.2
HDD_SATA_TX_RE_P0: C6001.1 ED6001.1 ED6001.10 U6001.15
HDD_SATA_TX_RE_P1: C6020.2 ED6002.1 ED6002.10 R6016.2
HDMI_CLK_CON: HDMI1.15 Q5703.D RN5701.2
HDMI_DATA_CON: HDMI1.16 Q5705.D RN5701.1
HDMI_DDI_TX_CON_N0: C5703.2 ER5714.1 HDMI1.9 RN5703.2
HDMI_DDI_TX_CON_N1: C5705.2 ER5715.1 HDMI1.6 RN5702.4
HDMI_DDI_TX_CON_N2: C5707.2 ER5716.1 HDMI1.3 RN5702.2
HDMI_DDI_TX_CON_N3: C5701.2 ER5717.1 HDMI1.12 RN5703.4
HDMI_DDI_TX_CON_P0: C5704.2 ER5714.2 HDMI1.7 RN5703.1
HDMI_DDI_TX_CON_P1: C5706.2 ER5715.2 HDMI1.4 RN5702.3
HDMI_DDI_TX_CON_P2: C5708.2 ER5716.2 HDMI1.1 RN5702.1
HDMI_DDI_TX_CON_P3: C5702.2 ER5717.2 HDMI1.10 RN5703.3
HDMI_DDI_TX_N0: C5703.1 CPU1.B16
HDMI_DDI_TX_N1: C5705.1 CPU1.B15
HDMI_DDI_TX_N2: C5707.1 CPU1.B14
HDMI_DDI_TX_N3: C5701.1 CPU1.B17
HDMI_DDI_TX_P0: C5704.1 CPU1.A16
HDMI_DDI_TX_P1: C5706.1 CPU1.A15
HDMI_DDI_TX_P2: C5708.1 CPU1.A14
HDMI_DDI_TX_P3: C5702.1 CPU1.A17
HDMI_DET_CPU: CPU1.D17 R5712.1
HDMI_HPD_B: Q5708.B R5710.2
HDMI_HPD_E: Q5708.E R5709.2 R5712.2
HDMI_HPD_G: Q5707.G R5702.2
HDMI_IN#: Q5707.D R5701.2 U2401.17
HDMI_PLL_GND: Q5701.D RN5702.5(B) RN5702.6 RN5702.7 RN5702.8 RN5703.5(B) RN5703.6 RN5703.7 RN5703.8
HDMI_SCL_CPU: CPU1.G17 Q5703.S RN811.4
HDMI_SDA_CPU: CPU1.H17 Q5705.S RN811.3(B)
HPD_HDMI_CON: HDMI1.19 R5702.1 R5710.1 R5711.1 TP5701.1
HUB_USB20_CON_N7: AFTP6606.1 EL6602.1 IOBD1.31
HUB_USB20_CON_P7: AFTP6607.1 EL6602.2 IOBD1.32
HUB_USB20_N7: CPU1.AM2 EL6602.4
HUB_USB20_P7: CPU1.AM1 EL6602.3
HVBEN_L: CPU1.AP27 R1756.2
I2C1_1V8_CLK: CPU1.AU19 RN1705.3(B) TP1703.1
I2C1_1V8_DATA: CPU1.AV19 RN1705.4 TP1704.1
I_BATT: C2447.2 PC4403.1 PR4476.1 U2401.96
INT_SERIRQ: C2401.1 R2420.2 R2435.1 U2401.125 U2404.4
INT_SERIRQ_OE: R2419.1 R2421.2 U2404.5
INT_TP#: Q6502.D R1709.2 R1737.2 R6510.2
INT_TP#_CONN: Q6502.S R6510.1 R6512.2 TPAD1.5 U2401.63
INT_TP#_R: CPU1.AJ2 R1737.1
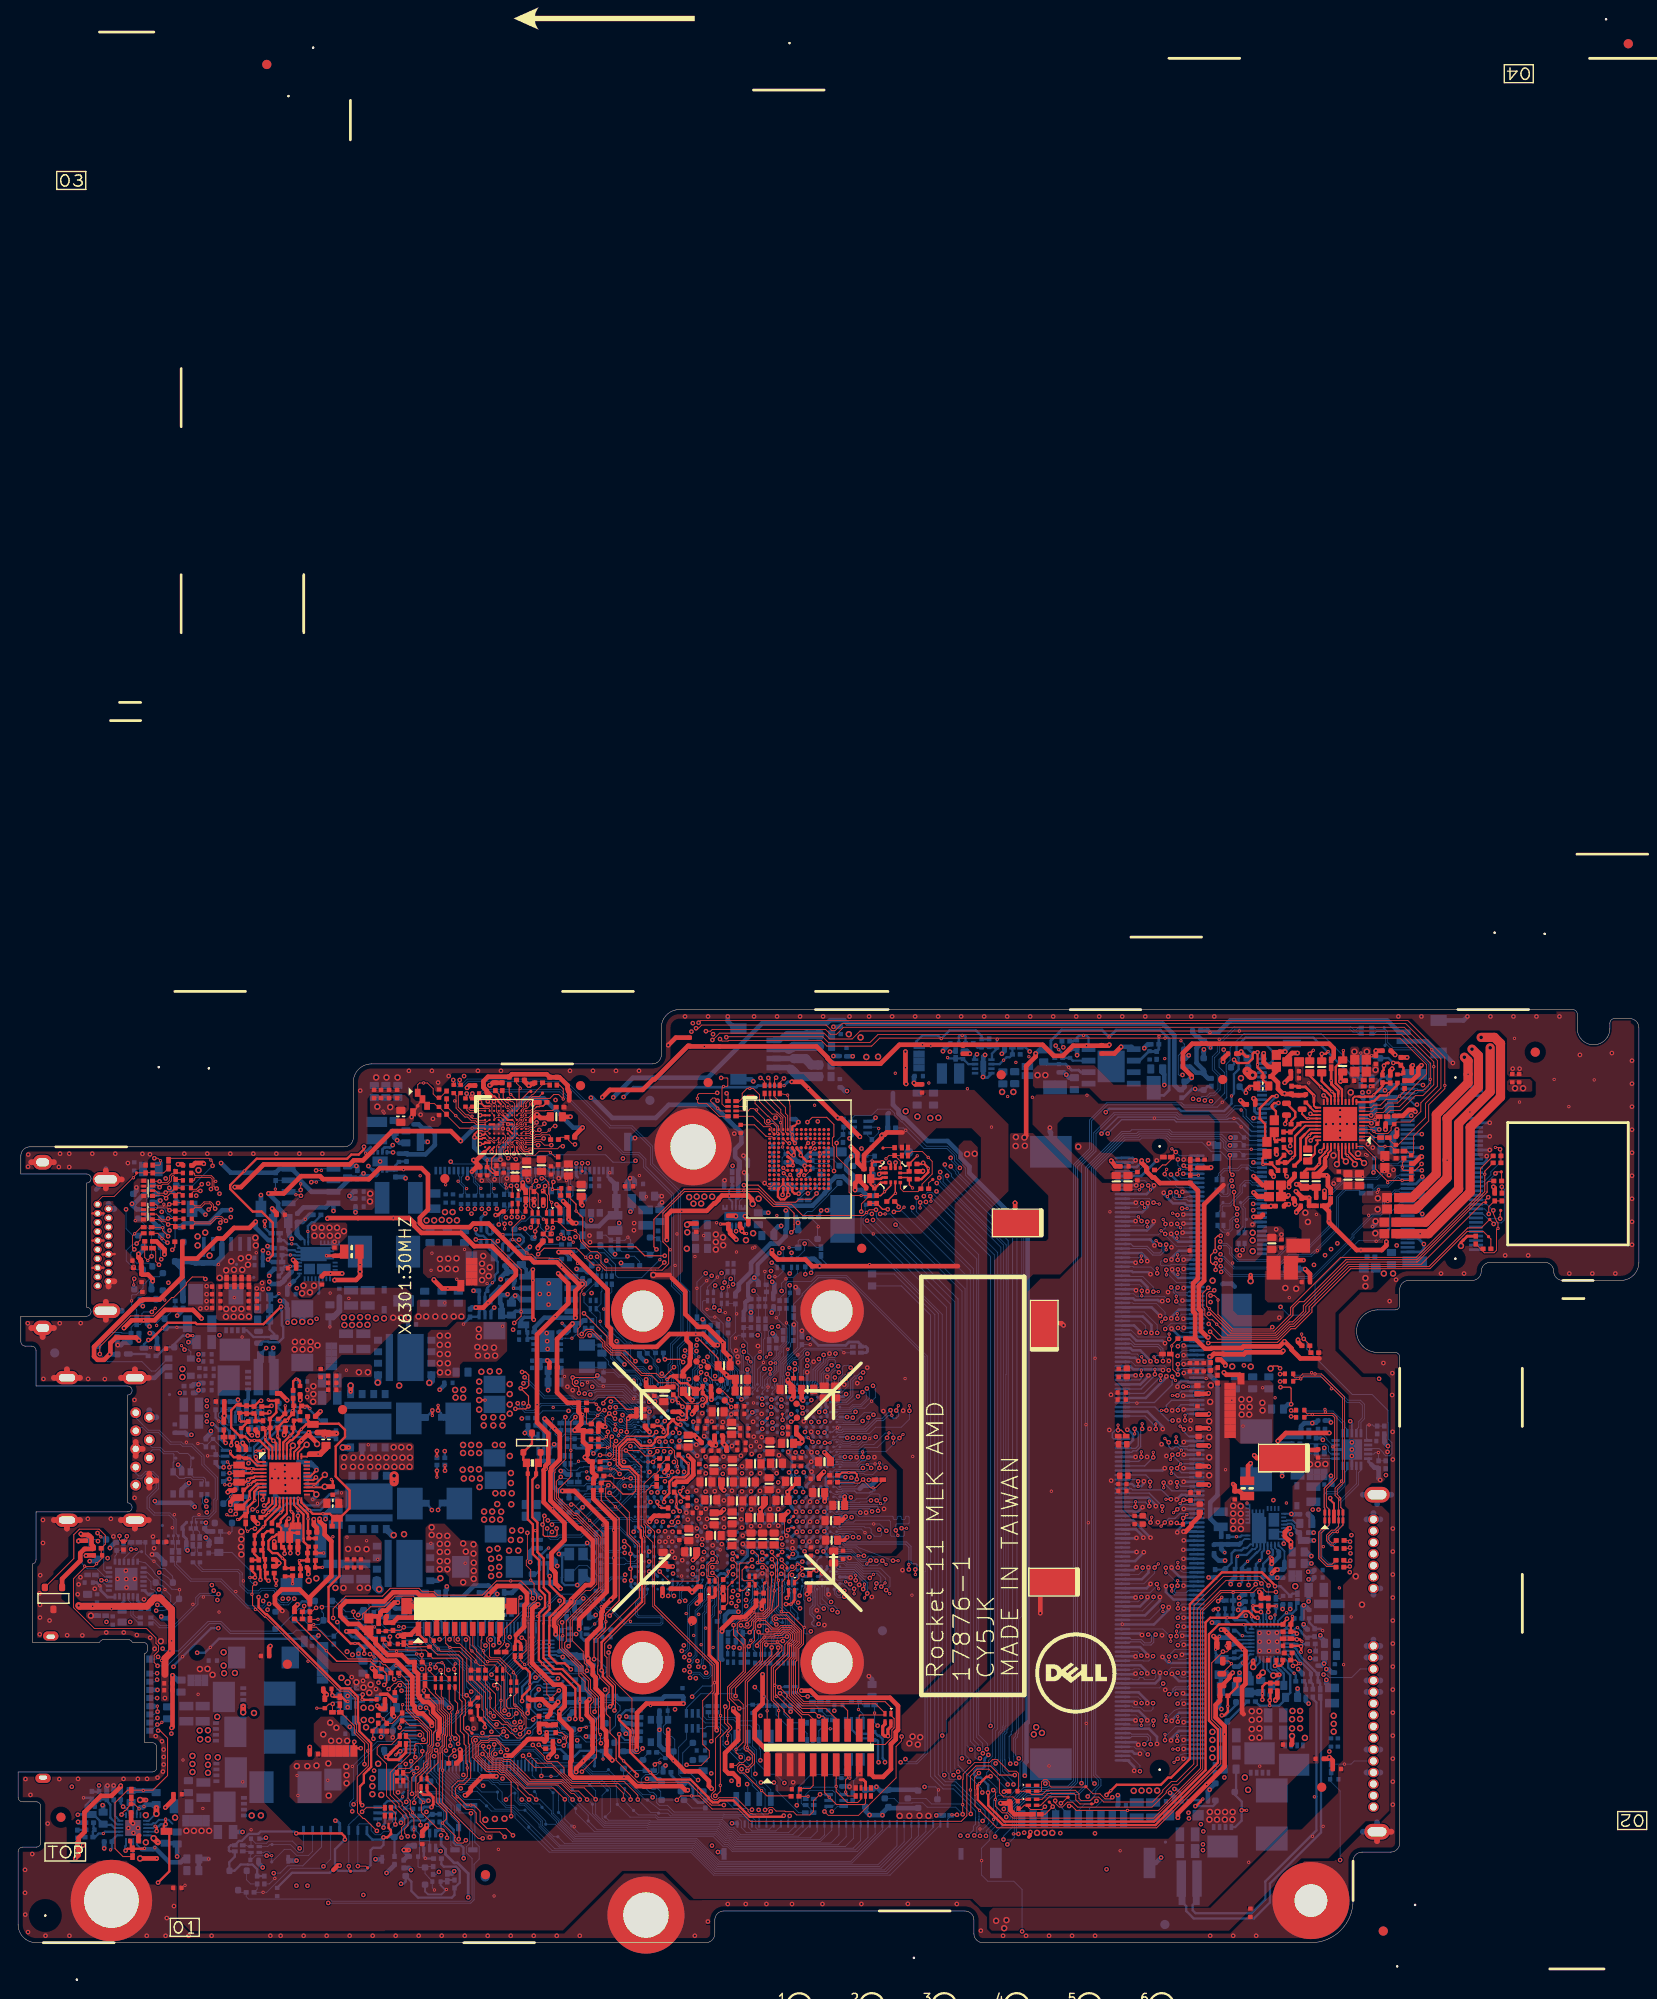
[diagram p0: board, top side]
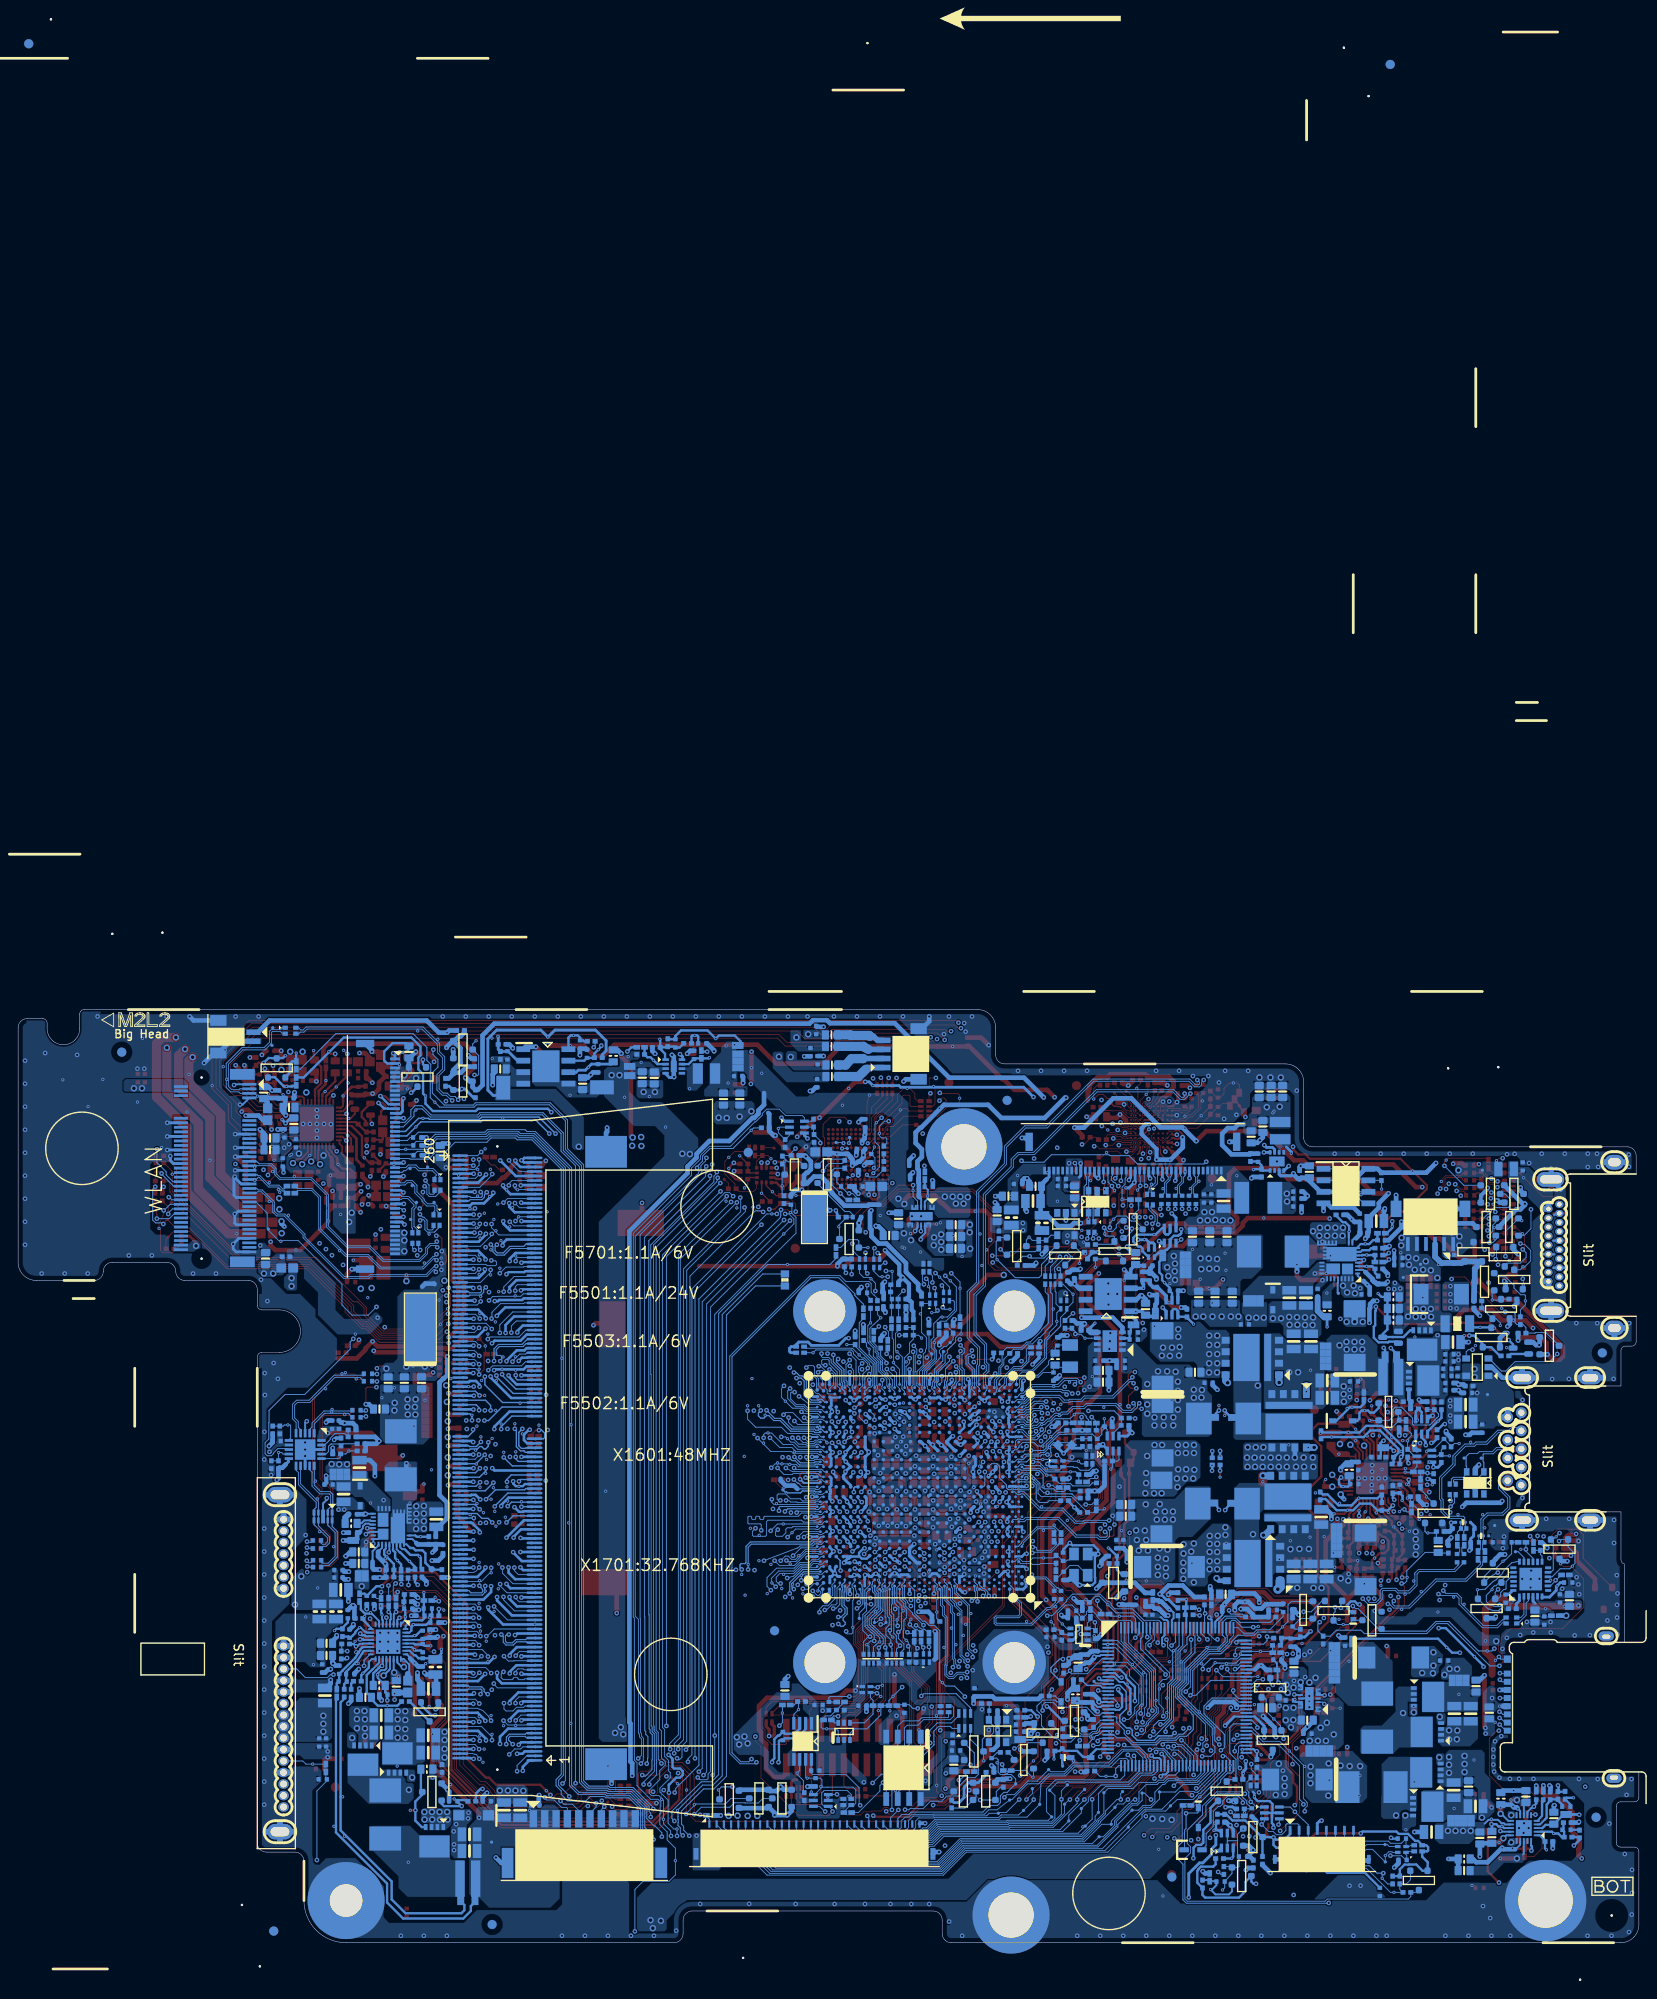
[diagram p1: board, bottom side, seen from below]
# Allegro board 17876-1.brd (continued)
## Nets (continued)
JACK_PLUG: C2902.2 IOBD1.2 Q2901.G R2905.1 R2914.1
KB_LOOP: KB1.1 R6515.2
KBC_BEEP: R2734.1 U2401.32
KBC_BEEP_R: D2703.2 R2734.2
KBC_ON#_GATE: C2442.1 Q2403.G Q2404.G R2492.2
KBC_ON#_GATE_L: R2491.1 R2492.1 R2493.2
KBC_PECI: TP2407.1 U2401.13
KBC_PWRBTN#: EC6601.1 IOBD1.22 R2488.1
KBC_VCC: C2414.1 C2429.1 C2430.1 C2431.1 C2440.1 C2441.1 R2408.1 U2401.19 U2401.46 U2401.76 U2401.115
KBC_VCORF: C2443.1 U2401.44
KBRST#: R1633.2 R2400.2 U2401.122
KCOL0: AFTP6517.1 KB1.18 U2401.53
KCOL1: AFTP6515.1 KB1.16 U2401.52
KCOL2: AFTP6516.1 KB1.17 U2401.51
KCOL3: AFTP6514.1 KB1.15 U2401.50
KCOL4: AFTP6510.1 KB1.11 U2401.49
KCOL5: AFTP6509.1 KB1.10 U2401.48
KCOL6: AFTP6512.1 KB1.13 U2401.47
KCOL7: AFTP6511.1 KB1.12 U2401.43
KCOL8: AFTP6513.1 KB1.14 U2401.42
KCOL9: AFTP6523.1 KB1.24 U2401.41
KCOL10: AFTP6525.1 KB1.26 U2401.40
KCOL11: AFTP6524.1 KB1.25 U2401.39
KCOL12: AFTP6518.1 KB1.19 U2401.38
KCOL13: AFTP6521.1 KB1.22 U2401.37
KCOL14: AFTP6522.1 KB1.23 U2401.36
KCOL15: AFTP6520.1 KB1.21 U2401.35
KCOL16: AFTP6527.1 KB1.20 U2401.34
KROW0: AFTP6508.1 KB1.9 U2401.54
KROW1: AFTP6506.1 KB1.7 U2401.55
KROW2: AFTP6504.1 KB1.5 U2401.56
KROW3: AFTP6507.1 KB1.8 U2401.57
KROW4: AFTP6503.1 KB1.4 U2401.58
KROW5: AFTP6505.1 KB1.6 U2401.59
KROW6: AFTP6502.1 KB1.3 U2401.60
KROW7: AFTP6501.1 KB1.2 U2401.61
L_BKLT_CTRL: D5502.1 Q5503.C R5524.2 R5527.2
L_BKLT_CTRL_B: Q5503.B R5526.2
L_BKLT_CTRL_CPU: CPU1.A24 Q5503.E
LCD_BRIGHTNESS: EC5507.1 LCD1.26 RN5503.2
LCD_TST: R2413.1 RN5504.3(B)
LCD_TST_C: LCD1.23 RN5504.2
LCD_TST_EN: D5501.2 R5503.1 U2401.28
LCD_TST_KBC: R2413.2 U2401.124
LDO1_CAP: C2703.1 HDA27.21 R2702.1
LDO2_CAP: C2711.1 HDA27.32
LDO3_CAP: C2722.1 HDA27.6
LID_CLOSE#: C6701.1 LIDSW1.3 R2474.2 R6701.1 U2401.107
LINE1-L_C: C2907.2 R2922.1
LINE1-L_R: C2908.2 R2921.1
LINE1_L: C2907.1 HDA27.18
LINE1_R: C2908.1 HDA27.17
LINE1_VREFO: D2901.3 HDA27.24
LINE1_VREFO_D1: D2901.2 R2912.1
LINE1_VREFO_D2: D2901.1 R2928.1
LPC_AD_CPU_P0: RN1605.1 RN6801.2 U2401.126
LPC_AD_CPU_P1: RN1605.2 RN6801.1 U2401.127
LPC_AD_CPU_P2: RN1606.2 RN6803.2 U2401.128
LPC_AD_CPU_P3: RN1606.1 RN6803.1 U2401.1
LPC_CLK_CPU_P0: C1603.1 EC1601.1 R1611.1 R2004.2 R2010.1 U2401.2
LPC_CLK_CPU_P1: DB1.2 FC1601.1 R1612.1
LPC_CLKRUN#_CPU: R1630.1 R2475.2 U2401.8
LPC_FRAME#_CPU: R1618.1 R2006.2 R2012.1 R6801.1 U2401.3
LPC_FRAME#_DEBUG: DB1.5 R6801.2
LPC_LAD0_R: DB1.9 RN6801.3(B)
LPC_LAD1_R: DB1.8 RN6801.4
LPC_LAD2_R: DB1.7 RN6803.3(B)
LPC_LAD3_R: DB1.6 RN6803.4
LPC_RST#: C804.1 R1629.1 R6802.1 U2401.7
LPC_SERIRQ_CPU: R1631.1 R2435.2 R2436.2 U2404.3
LVDS_VDD_EN: D5501.1 Q5501.C R5516.2
LVDS_VDD_EN_B: Q5501.B R5521.2
LVDS_VDD_EN_CPU: CPU1.B24 Q5501.E R2440.2 R5522.2
LVDS_VDD_EN_KBC: R2440.1 U2401.26
LVDS_VDD_EN_R: D5501.3 R5503.2 R5508.2 U5501.4
M_A_A0: CPU1.AG38 DIMM1.144
M_A_A1: CPU1.W35 DIMM1.133
M_A_A2: CPU1.W38 DIMM1.132
M_A_A3: CPU1.W34 DIMM1.131
M_A_A4: CPU1.U38 DIMM1.128
M_A_A5: CPU1.U37 DIMM1.126
M_A_A6: CPU1.U34 DIMM1.127
M_A_A7: CPU1.R35 DIMM1.122
M_A_A8: CPU1.R38 DIMM1.125
M_A_A9: CPU1.N38 DIMM1.121
M_A_A10: CPU1.AG34 DIMM1.146
M_A_A11: CPU1.R34 DIMM1.120
M_A_A12: CPU1.N37 DIMM1.119
M_A_A13: CPU1.AN35 DIMM1.158
M_A_ACT#: CPU1.L35 DIMM1.114
M_A_ALERT_N: DIMM1.116 R1206.2
M_A_BA0: CPU1.AJ38 DIMM1.150
M_A_BA1: CPU1.AG35 DIMM1.145
M_A_BG0: CPU1.N34 DIMM1.115
M_A_BG1: CPU1.L38 DIMM1.113
M_A_CAS#: CPU1.AN38 DIMM1.156
M_A_CKE0: CPU1.J38 DIMM1.109
M_A_CKE1: CPU1.J34 DIMM1.110
M_A_CLK0: CPU1.AC35 DIMM1.137
M_A_CLK1: CPU1.AA34 DIMM1.138
M_A_CLK#0: CPU1.AC34 DIMM1.139
M_A_CLK#1: CPU1.AA32 DIMM1.140
M_A_CS#0: CPU1.AL35 DIMM1.149
M_A_CS#1: CPU1.AR37 DIMM1.157
M_A_DM0: CPU1.B35 DIMM1.12
M_A_DM1: CPU1.D40 DIMM1.33
M_A_DM2: CPU1.K40 DIMM1.54
M_A_DM3: CPU1.T41 DIMM1.75
M_A_DM4: CPU1.AE41 DIMM1.178
M_A_DM5: CPU1.AL40 DIMM1.199
M_A_DM6: CPU1.AU40 DIMM1.220
M_A_DM7: CPU1.BA37 DIMM1.241
M_A_DQ0: CPU1.A34 DIMM1.8
M_A_DQ1: CPU1.B34 DIMM1.7
M_A_DQ2: CPU1.A38 DIMM1.20
M_A_DQ3: CPU1.B38 DIMM1.21
M_A_DQ4: CPU1.A33 DIMM1.4
M_A_DQ5: CPU1.B33 DIMM1.3
M_A_DQ6: CPU1.A37 DIMM1.16
M_A_DQ7: CPU1.B37 DIMM1.17
M_A_DQ8: CPU1.B41 DIMM1.28
M_A_DQ9: CPU1.C40 DIMM1.29
M_A_DQ10: CPU1.F41 DIMM1.41
M_A_DQ11: CPU1.G40 DIMM1.42
M_A_DQ12: CPU1.A40 DIMM1.24
M_A_DQ13: CPU1.B40 DIMM1.25
M_A_DQ14: CPU1.E41 DIMM1.38
M_A_DQ15: CPU1.F40 DIMM1.37
M_A_DQ16: CPU1.J40 DIMM1.50
M_A_DQ17: CPU1.J41 DIMM1.49
M_A_DQ18: CPU1.N40 DIMM1.62
M_A_DQ19: CPU1.N41 DIMM1.63
M_A_DQ20: CPU1.H40 DIMM1.46
M_A_DQ21: CPU1.H41 DIMM1.45
M_A_DQ22: CPU1.M40 DIMM1.58
M_A_DQ23: CPU1.M41 DIMM1.59
M_A_DQ24: CPU1.R40 DIMM1.70
M_A_DQ25: CPU1.T40 DIMM1.71
M_A_DQ26: CPU1.W40 DIMM1.83
M_A_DQ27: CPU1.Y40 DIMM1.84
M_A_DQ28: CPU1.P40 DIMM1.66
M_A_DQ29: CPU1.P41 DIMM1.67
M_A_DQ30: CPU1.V40 DIMM1.79
M_A_DQ31: CPU1.V41 DIMM1.80
M_A_DQ32: CPU1.AD41 DIMM1.174
M_A_DQ33: CPU1.AD40 DIMM1.173
M_A_DQ34: CPU1.AH41 DIMM1.187
M_A_DQ35: CPU1.AH40 DIMM1.186
M_A_DQ36: CPU1.AB40 DIMM1.170
M_A_DQ37: CPU1.AC40 DIMM1.169
M_A_DQ38: CPU1.AF40 DIMM1.183
M_A_DQ39: CPU1.AG40 DIMM1.182
M_A_DQ40: CPU1.AK41 DIMM1.195
M_A_DQ41: CPU1.AK40 DIMM1.194
M_A_DQ42: CPU1.AP41 DIMM1.207
M_A_DQ43: CPU1.AP40 DIMM1.208
M_A_DQ44: CPU1.AJ41 DIMM1.191
M_A_DQ45: CPU1.AJ40 DIMM1.190
M_A_DQ46: CPU1.AN41 DIMM1.203
M_A_DQ47: CPU1.AN40 DIMM1.204
M_A_DQ48: CPU1.AT40 DIMM1.216
M_A_DQ49: CPU1.AU41 DIMM1.215
M_A_DQ50: CPU1.AY40 DIMM1.228
M_A_DQ51: CPU1.BA40 DIMM1.229
M_A_DQ52: CPU1.AR40 DIMM1.211
M_A_DQ53: CPU1.AT41 DIMM1.212
M_A_DQ54: CPU1.AW40 DIMM1.224
M_A_DQ55: CPU1.AY41 DIMM1.225
M_A_DQ56: CPU1.BA38 DIMM1.237
M_A_DQ57: CPU1.AY37 DIMM1.236
M_A_DQ58: CPU1.BA34 DIMM1.249
M_A_DQ59: CPU1.BA33 DIMM1.250
M_A_DQ60: CPU1.AY39 DIMM1.232
M_A_DQ61: CPU1.AY38 DIMM1.233
M_A_DQ62: CPU1.AY35 DIMM1.245
M_A_DQ63: CPU1.AY34 DIMM1.246
M_A_DQS_DN0: CPU1.A36 DIMM1.11
M_A_DQS_DN1: CPU1.D41 DIMM1.32
M_A_DQS_DN2: CPU1.K41 DIMM1.53
M_A_DQS_DN3: CPU1.U40 DIMM1.74
M_A_DQS_DN4: CPU1.AE40 DIMM1.177
M_A_DQS_DN5: CPU1.AM41 DIMM1.198
M_A_DQS_DN6: CPU1.AV41 DIMM1.219
M_A_DQS_DN7: CPU1.AY36 DIMM1.240
M_A_DQS_DP0: CPU1.B36 DIMM1.13
M_A_DQS_DP1: CPU1.E40 DIMM1.34
M_A_DQS_DP2: CPU1.L40 DIMM1.55
M_A_DQS_DP3: CPU1.U41 DIMM1.76
M_A_DQS_DP4: CPU1.AF41 DIMM1.179
M_A_DQS_DP5: CPU1.AM40 DIMM1.200
M_A_DQS_DP6: CPU1.AV40 DIMM1.221
M_A_DQS_DP7: CPU1.BA36 DIMM1.242
M_A_EVENT#: DIMM1.134 R501.1
M_A_EVENT#_APU: CPU1.AA41 R501.2 R504.2
M_A_ODT0: CPU1.AN37 DIMM1.155
M_A_ODT1: CPU1.AU38 DIMM1.161
M_A_PARITY: DIMM1.143 R1202.2
M_A_RAS#: CPU1.AJ37 DIMM1.152
M_A_WE#: CPU1.AL38 DIMM1.151
M_VREF_CA_DIMMA: C1202.1 C1220.1 C1224.1 DIMM1.164 R1203.1 R1204.1 R1211.1
M_VREFDQ: CPU1.Y41 TP501.1
M_ZVDDIO: CPU1.AB41 R503.2
MIC2_VREFO: HDA27.23 RN2901.1 RN2901.2
MIC_CAP: C2715.1 HDA27.15
MIC_GND: LCD1.20 R5502.1
MODEL_ID: IOBD1.15 R2414.1
MODEL_ID_AD: R2410.2 R2414.2 U2401.94
NC#7: R6354.2 U6305.7
NCT_CLK: EC2601.1 Q2604.1 R2476.1 RN2601.4 U2601.8
NCT_CLK_R: R2476.2 U2401.119
NCT_DATA: EC2602.1 Q2604.4 R2477.1 RN2601.3(B) U2601.7
NCT_DATA_R: R2477.2 U2401.120
P2800_DXN: C2604.2 C2605.2 Q2601.E R2604.2 U2601.3
P2800_DXP: C2604.1 C2605.1 Q2601.B Q2601.C R2604.1 U2601.2
P_ZVDDP: CPU1.U8 R301.2
P_ZVSS: CPU1.W8 R302.1
PBAT_PRES1#: AFTP4301.1 BATT1.6 RN4301.3(B)
PBAT_SMBCLK1: AFTP4303.1 BATT1.4 RN4302.3(B)
PBAT_SMBDAT1: AFTP4302.1 BATT1.5 RN4301.4
PCB_VER_AD: C2417.1 R2437.2 R2438.1 U2401.98
PCIE_RST#_C: CPU1.AE4 R1729.2
PD4403_A: PD4404.A PQ4413.B
PD4403_K: PD4404.K PR4432.2
PD4410_2: PD4410.2 PQ4416.3 PR4481.2
PDB_R: HDA27.40 R2712.2
PG_1: PG4429.1 PR4467.1
PG_2: PG4407.1 PR4468.1
PLT_RST#: AFTP6105.1 C1701.1 EC1701.2 R1729.1 R6328.2 R6803.1 WLAN1.52
PLT_RST#_DEBUG: DB1.4 R6802.2 R6803.2
PLTRST#_CPU_D: Q6301.D R6327.2 R6328.1
PM_PWRBTN#: R1730.1 U2401.117
PQ3802_1: PQ4302.B PR4302.1 PR4311.2
PQ4209_D: PQ4309.D PR4316.2
PQ4405_2: PQ4414.2 PR4442.1 PR4446.2
PQ4405_3: PQ4414.3 PR4447.1
PQ4405_5: PC4404.1 PQ4414.5 PR4413.2
PQ4405_6: PC4404.2 PQ4414.6 PR4448.1
PQ4408_C: PQ4413.C PR4433.1 PR4442.2
PQ4408_E: PQ4413.E PR4431.2 PR4436.1
PQ4415_C: PQ4415.3 PQ4416.1
PR_2: PC4405.1 PR4407.2
PROCHOT#_EC: Q2402.G R2442.1 U2401.24
PROJECT_ID1: LCD1.33 TP5501.1
PS_ID: PQ4301.S PR4307.1
PS_ID_R: AFTP4308.1 DCIN1.3 EC4307.1 PD4304.1 PD4304.2 PQ4301.D PR4311.1
PSID_DISABLE#_R_C: PQ4301.G PQ4302.C PR4303.2
PSID_EC: PD4303.3 PR4306.2 PR4307.2 U2401.99
PSL_IN1#: Q2405.D R2473.2 U2401.73
PSL_IN2#: R2488.2 R2489.1 U2401.93
PSL_OUT#: PR5411.1 R2493.1 U2401.74
PURE_HW_SHUTDOWN#: C2606.1 D4001.3 EC2403.1 Q2401.B Q2603.D R2472.2 R2603.1
PWR_0D95V: PC5207.1 PC5208.1 PC5209.1 PC5210.1 PC5211.1 PC5212.1 PG5204.1 PG5205.1 PG5206.1 PG5207.1 PG5208.1 PG5209.1 PG5210.1 PG5211.1 PG5212.2 PL5201.2
PWR_0D95V_BOOT: PR5210.1 PU5201.27
PWR_0D95V_BOOT_A: PC5206.1 PR5210.2
PWR_0D95V_CS: PR5202.2 PU5201.10
PWR_0D95V_EN: PR5206.2 PR5209.2 PU5201.6
PWR_0D95V_FB: PR5207.2 PR5208.1 PU5201.3
PWR_0D95V_PG: PR5203.2 PR5204.2 PU5201.8
PWR_0D95V_PH: PC5206.2 PL5201.1 PR5211.1 PU5201.17 PU5201.18 PU5201.19 PU5201.20 PU5201.25 PU5201.35
PWR_0D95V_SNUB: PC5214.1 PR5211.2
PWR_0D95V_TON: PR5205.2 PU5201.7
PWR_0D95V_VCC: PC5202.1 PR5201.1 PR5202.1 PU5201.9
PWR_0D95V_VDDQ: PG5212.1 PR5207.1 PU5201.2
PWR_0D95V_VLDOIN: PU5201.28 TP5201.1
PWR_0D95V_VTTREF: PC5213.1 PU5201.1
PWR_0D775V: PC4903.1 PC4904.1 PG4901.1 PU4901.4
PWR_0D775V_EN: PC4907.1 PG4903.2 PQ4901.5
PWR_0D775V_EN_R: PQ4901.2 PQ4901.3 PR4901.2
PWR_0D775V_VIN: PC4905.1 PG4902.1 PU4901.1
PWR_0D775V_VREF: PC4906.1 PQ4901.6 PR4902.2 PR4903.1 PU4901.3
PWR_1D0V_FB: PC6303.2 PR6301.1 PR6302.2 PU6301.1
PWR_1D0V_LX: PL6301.1 PU6301.6
PWR_1D8V_EN: PC5411.1 PR5409.2 PU5401.7
PWR_1D8V_FB: PC5401.2 PR5403.2 PR5405.1 PR5406.1 PU5401.1
PWR_1D8V_FB_R1: PC5401.1 PG5401.2 PR5403.1
PWR_1D8V_FB_R2: PC5412.1 PR5406.2
PWR_1D8V_PG: PR5407.2 PR5412.2 PU5401.2
PWR_1D8V_PH: PL5401.1 PU5401.6
PWR_1D8V_PVIN: PC5405.1 PC5406.1 PG5402.2 PG5403.2 PU5401.3
PWR_2D5V_PWRGD: PC5317.1 PR5306.1 PR5312.2 PU5302.7
PWR_3D3V: PC4514.1 PG4501.2 PG4507.2 PG4512.2 PG4515.2 PG4517.2 PG4520.2 PG4522.1 PL4501.1 PT4501.1
PWR_3D3V_BOOT: PR4503.2 PU4501.9
PWR_3D3V_BOOT_A: PC4511.2 PR4503.1
PWR_3D3V_CS: PR4506.1 PU4501.5
PWR_3D3V_EN: PC4502.1 PR4502.1 PU4501.6
PWR_3D3V_FB: PC4515.2 PR4505.2 PR4508.1 PU4501.4
PWR_3D3V_FB_A: PC4515.1 PR4509.2
PWR_3D3V_FB_B: PG4522.2 PR4505.1 PR4509.1
PWR_3D3V_HG: PU4501.10 PU4502.4
PWR_3D3V_LG: PU4501.11 PU4504.4
PWR_3D3V_PH: PC4511.1 PL4501.2 PU4501.8 PU4502.1 PU4502.2 PU4502.3 PU4504.5 PU4504.6 PU4504.7 PU4504.8
PWR_3D3V_VREG: PC4517.1 PG4524.2 PU4501.3
PWR_5V: PC4513.1 PG4502.1 PG4504.1 PG4509.1 PG4511.1 PG4516.1 PG4518.1 PG4519.1 PG4521.1 PG4523.1 PL4502.2 PT4502.1
PWR_5V_BOOT: PR4504.1 PU4501.17
PWR_5V_BOOT_A: PC4512.1 PR4504.2
PWR_5V_CS: PR4507.1 PU4501.1
PWR_5V_EN: PC4501.1 PR4514.1 PU4501.20
PWR_5V_FB: PC4516.2 PR4511.2 PR4512.1 PU4501.2
PWR_5V_FB_A: PC4516.1 PR4510.2
PWR_5V_HG: PU4501.16 PU4503.4
PWR_5V_LG: PU4501.15 PU4505.4
PWR_5V_PH: PC4512.2 PL4502.1 PU4501.18 PU4503.1 PU4503.2 PU4503.3 PU4505.5 PU4505.6 PU4505.7 PU4505.8
PWR_5V_VO: PG4523.2 PR4510.1 PR4511.1 PU4501.14
PWR_5V_VREG: PC4518.1 PG4525.1 PU4501.13
PWR_CHG_ACDET: PC4419.1 PR4416.1 PR4452.2 PU4401.1
PWR_CHG_ACN: PC4466.2 PC4468.2 PR4468.2 PU4401.31
PWR_CHG_ACOK: PR4434.2 PR4446.1 PR4451.2 PR4474.2 PU4401.2
PWR_CHG_ACP: PC4466.1 PC4467.2 PR4467.2 PU4401.32
PWR_CHG_AD_OFF: PQ4309.G PR4312.1 PR4444.1 R2443.1 U2401.11
PWR_CHG_AD_OFF_R: PQ4304.1 PR4312.2
PWR_CHG_AMON: PR4475.2 PU4401.6
PWR_CHG_ASGATE: PC4409.2 PU4401.30
PWR_CHG_BATDRV: PC4408.2 PU4401.25
PWR_CHG_BATGONE: PC4436.1 PR4439.1 PU4401.13
PWR_CHG_BMON: PR4476.2 PU4401.7
PWR_CHG_BTST: PR4428.1 PU4401.24
PWR_CHG_BTST1: PC4431.1 PR4428.2
PWR_CHG_CMSRC: PC4409.1 PR4477.2 PU4401.29
PWR_CHG_COMP: PC4406.1 PR4407.1 PU4401.10
PWR_CHG_DCIN: PC4435.1 PR4437.1 PU4401.18
PWR_CHG_DCIN_R: PD4410.3 PR4437.2
PWR_CHG_FSET: PR4406.2 PU4401.12
PWR_CHG_HIDRV: PU4401.23 PU4411.4
PWR_CHG_LODRV: PU4401.21 PU4412.4
PWR_CHG_NTC: PR4410.1 PU4401.17
PWR_CHG_NTC_1: PR4410.2 PR4412.1
PWR_CHG_PHASE: PC4431.2 PL4401.1 PU4401.22 PU4411.1 PU4411.2 PU4411.3 PU4412.5 PU4412.6 PU4412.7 PU4412.8
PWR_CHG_PROG: PR4405.1 PU4401.9
PWR_CHG_REGN: PC4445.1 PR4417.1 PR4438.2 PU4401.20
PWR_CHG_SCL: PR4449.2 PR4471.2 PU4401.4
PWR_CHG_SDA: PR4435.2 PR4470.2 PU4401.3
PWR_CHG_SRN: PC4462.2 PC4463.2 PR4457.2 PU4401.14
PWR_CHG_SRN_R: PG4426.1 PR4457.1
PWR_CHG_SRP: PC4461.2 PC4463.1 PR4456.2 PU4401.15
PWR_CHG_SRP_R: PG4428.1 PR4456.1
PWR_CORE_BOOT1: PR4701.1 PU4601.21
PWR_CORE_BOOT_1: PC4708.1 PR4701.2
PWR_CORE_COMP: PC4615.1 PC4616.1 PR4629.1 PU4601.19
PWR_CORE_COMP_A: PC4616.2 PR4627.1
PWR_CORE_COMP_B: PC4617.1 PR4628.2
PWR_CORE_EN: PR4617.2 PU4601.8
PWR_CORE_FB_A: PC4614.1 PR4624.2
PWR_CORE_FB_R: PC4615.2 PR4624.1 PR4625.1 PR4627.2 PR4628.1 PU4601.18
PWR_CORE_HG1: PU4601.22 PU4701.1 PU4702.1
PWR_CORE_IMON: PC4613.1 PR4618.1 PU4601.10
PWR_CORE_ISEN1_N: PG4707.1 PR4703.2
PWR_CORE_ISEN1_P: PG4706.1 PR4702.2
PWR_CORE_ISEN_N: PC4618.2 PC4619.2 PC4622.1 PC4623.1 PR4633.2 PR4635.2 PR4636.2 PR4703.1
PWR_CORE_ISEN_P: PC4618.1 PC4619.1 PR4632.1 PR4633.1 PR4702.1 PU4601.14
PWR_CORE_ISUMN: PR4636.1 PU4601.15
PWR_CORE_ISUMP: PR4632.2 PR4635.1
PWR_CORE_LG1: PU4601.24 PU4701.8 PU4702.8
PWR_CORE_NTC: PR4623.2 PR4626.2 PU4601.11
PWR_CORE_NTC_A_R: PR4622.2 PR4623.1 PR4626.1
PWR_CORE_PGOOD: PG4608.1 PR4620.2 PU4601.20
PWR_CORE_PH1: PC4708.2 PG4706.2 PL4701.1 PU4601.23 PU4701.9 PU4702.9
PWR_CORE_SVC: PG4603.2 PU4601.3
PWR_CORE_SVD: PG4605.2 PU4601.5
PWR_CORE_SVT: PG4607.2 PU4601.7
PWR_CORE_VDD: PC4611.1 PR4616.2 PU4601.25
PWR_CORE_VDDIO: PC4612.2 PG4606.2 PU4601.6
PWR_CORE_VR_HOT#: PG4604.2 PU4601.4
PWR_CORE_VSEN1_N: PC4620.2 PG4609.1 PG4611.1 PU4601.17
PWR_CORE_VSEN1_P: PC4614.2 PC4621.2 PG4610.1 PR4625.2 PU4601.16
PWR_CPU_ISEN1: PR4630.2 PU4601.13
PWR_DCBATOUT_0D95V: PC5203.1 PC5204.1 PC5205.1 PD5201.K PG5201.2 PG5202.2 PG5203.2 PR5205.1 PU5201.21 PU5201.22 PU5201.23 PU5201.24 PU5201.34
PWR_DCBATOUT_3D3V: PC4503.1 PC4504.1 PC4505.1 PG4505.2 PG4508.2 PG4513.2 PU4502.5 PU4502.6 PU4502.7 PU4502.8
PWR_DCBATOUT_5V: PC4508.1 PC4509.1 PC4510.1 PG4503.2 PG4506.2 PG4510.2 PG4514.2 PU4503.5 PU4503.6 PU4503.7 PU4503.8
PWR_DCBATOUT_VCCCORE: PC4701.1 PC4702.1 PC4703.1 PC4704.1 PC4705.1 PC4706.1 PC4707.1 PG4701.2 PG4702.2 PG4703.2 PG4704.2 PG4705.2 PU4701.2 PU4701.3 PU4701.4 PU4701.10 PU4702.2 PU4702.3 PU4702.4 PU4702.10
PWR_DCBATOUT_VDDNB: PC4711.1 PC4712.1 PC4713.1 PC4714.1 PC4715.1 PC4716.1 PC4720.1 PG4708.2 PG4709.2 PG4710.2 PG4711.2 PU4705.2 PU4705.3 PU4705.4 PU4705.10 PU4706.2 PU4706.3 PU4706.4 PU4706.10
PWR_DCBATOUT_VDDQ: PC5303.1 PC5304.1 PC5305.1 PD5301.K PG5301.2 PG5303.2 PG5305.2 PR5304.1 PU5301.21 PU5301.22 PU5301.23 PU5301.24 PU5301.34
PWR_OPCN: PC4407.2 PU4401.28
PWR_OPCP: PC4407.1 PU4401.27
PWR_VBAT: PC4408.1 PR4454.1 PU4401.26
PWR_VDDNB_BOOT: PR4704.1 PU4601.31
PWR_VDDNB_BOOT_A: PC4717.1 PR4704.2
PWR_VDDNB_COMP: PC4603.1 PC4604.1 PR4608.1 PU4601.36
PWR_VDDNB_FB: PC4603.2 PR4602.1 PR4604.2 PR4605.1 PR4607.2 PU4601.37
PWR_VDDNB_FB_A: PC4604.2 PR4604.1
PWR_VDDNB_FB_B: PC4608.1 PR4607.1
PWR_VDDNB_FB_C: PC4602.1 PR4602.2
PWR_VDDNB_HG: PU4601.32 PU4705.1 PU4706.1
PWR_VDDNB_ISEN1_N: PG4713.1 PR4706.2
PWR_VDDNB_ISEN1_N_A: PC4605.1 PC4606.1 PC4607.1 PR4603.1 PR4606.1 PR4609.1 PR4706.1
PWR_VDDNB_ISEN1_P: PG4712.1 PR4705.2
PWR_VDDNB_ISEN1_P_A: PC4606.2 PC4607.2 PR4609.2 PR4610.2 PR4705.1 PU4601.40
PWR_VDDNB_ISUMN: PR4603.2 PU4601.39
PWR_VDDNB_ISUMN_A: PR4606.2 PR4610.1
PWR_VDDNB_LG: PU4601.34 PU4705.8 PU4706.8
PWR_VDDNB_NTC: PR4613.2 PR4614.2 PU4601.1
PWR_VDDNB_NTC_A: PR4612.2 PR4613.1 PR4614.1
PWR_VDDNB_PG: PG4602.1 PR4611.2 PU4601.35
PWR_VDDNB_PH: PC4717.2 PG4712.2 PL4702.1 PU4601.33 PU4705.9 PU4706.9
PWR_VDDNB_VSEN: PC4601.2 PC4602.2 PG4601.1 PR4601.2 PR4605.2 PU4601.38
PWR_VDDNBE_IMON: PC4609.1 PR4615.1 PU4601.2
PWR_VDDQ: PC5308.1 PC5309.1 PC5310.1 PC5311.1 PG5302.1 PG5304.1 PG5306.1 PG5307.1 PG5308.1 PG5309.1 PG5310.1 PG5311.1 PG5312.1 PG5313.2 PL5301.2
PWR_VDDQ_BOOT: PR5317.1 PU5301.27
PWR_VDDQ_BOOT_A: PC5306.1 PR5317.2
PWR_VDDQ_CS: PR5302.2 PU5301.10
PWR_VDDQ_EN: PR5306.2 PR5319.2 PU5301.6
PWR_VDDQ_FB: PR5308.2 PR5309.1 PU5301.3
PWR_VDDQ_LVOIN: PC5307.1 PG5312.2 PU5301.28
PWR_VDDQ_PH: PC5306.2 PL5301.1 PR5318.1 PU5301.17 PU5301.18 PU5301.19 PU5301.20 PU5301.25 PU5301.35
PWR_VDDQ_SNUB: PC5321.1 PR5318.2
PWR_VDDQ_TON: PR5304.2 PU5301.7
PWR_VDDQ_VCC: PC5302.1 PR5301.1 PR5302.1 PU5301.9
PWR_VDDQ_VDDQ: PG5313.1 PR5308.1 PU5301.2
PWR_VDDQ_VTT: PC5312.1 PC5313.1 PG5314.2 PG5315.2 PU5301.29 PU5301.31
PWR_VDDQ_VTTREF: PC5314.1 PU5301.1 R1211.2
PWR_VPP_EN1: PC5320.1 PR5314.2 PU5302.8
PWR_VPP_FB: PC5319.2 PR5315.2 PR5316.1 PU5302.2
PWR_VPP_VCNTL: PC5316.1 PR5310.2 PU5302.6
PWR_VTT_EN: PR5307.2 PU5301.5
Q1702_2: Q1701.2 Q1701.3 R1747.2
Q2406_D: C4030.1 D4004.2 Q4001.D R4013.2
Q2406_G: Q4001.G R4008.2
Q2506_S: Q2506.S R2517.1 R2518.2
Q5102_G: PR5411.2 Q5401.G
Q6203_S: C6504.2 Q6503.S R6501.2
Q6204_S: C6505.2 Q6504.S R6514.2 R6518.2
Q6205_D: Q6507.6 R6505.2
Q6206_D: Q6507.3 R6506.2
R1930.R: C1602.2 R1625.1 X1601.1
RING2: EC2905.1 HDA27.13 R2906.1 RN2901.3(B)
RING2_R: IOBD1.3 IOBD1.4 IOBD1.5 IOBD1.6 R2906.2
RSMRST#_KBC: EC2401.1 R1748.2 U2401.15
RSTN: C6327.1 R6345.2 U6304.H5
RTC_1D5V_PWR: C2508.1 R2506.1 U2502.2
RTC_1D5V_S5: C1066.1 CPU1.AM11 Q2505.D R2506.2
RTC_AUX_S5: C2507.1 Q2501.3 R2425.2 R2513.1 R2708.1 U2502.3
RTC_CLK: CPU1.AN4 R2001.2 R2007.1
RTC_DET#: CPU1.AE8 Q2502.D R1703.2
RTC_DET#_G: Q2501.1 Q2502.G R2501.1 R2505.1 R2514.2
RTCRST_ON: Q2505.G R2507.1 U2401.23
RUNPWROK_D: D4002.A R4004.1
S5_ENABLE: C2448.1 Q2403.D R2490.2 R4003.2 U2401.14
S5_MUX_APU: CPU1.AA7 R4009.1 R4011.1 U4003.6
SATA3_DE1_HDD: R6002.2 R6005.1 U6001.9
SATA3_DE2_HDD: R6006.2 R6009.1 U6001.8
SATA3_EQ1_HDD: R6003.2 R6007.1 U6001.17
SATA3_EQ2_HDD: R6004.2 R6008.1 U6001.19
SATA3_PRX_DTX_N0_L: C6008.1 U6001.4
SATA3_PRX_DTX_P0_L: C6007.1 U6001.5
SATA3_PTX_DRX_N0_R: C6010.2 U6001.2
SATA3_PTX_DRX_P0_R: C6009.2 U6001.1
SATA_ZVDD_095: CPU1.AP11 R1602.2
SATA_ZVSS: CPU1.AU11 R1601.2
SD1_POWER: C6314.1 C6315.1 U6304.F8 U6304.K2
SD1_REXT: R6346.1 U6304.E8
SD_CD#: EC3301.1 R3309.2 SD1.1
SD_CD#_CARD: R3307.2 R3309.1 U3301.13
SD_MMC_CLK/MS_DATA2: EC3307.1 ED3302.1 R3303.2 SD1.5
SD_MMC_CMM/MS_DATA3: ED3301.2 SD1.7 U3301.18
SD_MMC_DAT1: ED3303.1 SD1.2 U3301.10
SD_MMC_DATA0/MS_DATA5: ED3303.2 SD1.3 U3301.11
SD_MMC_DATA2/MS_BS: ED3301.1 SD1.9 U3301.21
SD_MMC_DATA3/MS_CLK: ED3302.2 SD1.8 U3301.20
SD_WP#/MS_DATA1_C: R3311.2 U3301.8
SDREG: C3309.2 U3301.6
SENSOR_I2C_SCL: R6935.1 TP6901.1
SENSOR_I2C_SCL_R: R6935.2 RN6901.4 U6901.1
SENSOR_I2C_SDA: R6936.1 TP6902.1
SENSOR_I2C_SDA_R: R6936.2 RN6901.3(B) U6901.4
SENSOR_KB_DIS: IOBD1.16 R2428.2 U2401.101
SER_RXD: CPU1.AG5 R6109.1
SER_TXD: CPU1.AJ4 R6108.1
SLEEVE: EC2906.1 HDA27.14 R2911.1 RN2901.4
SLEEVE_R: IOBD1.7 IOBD1.8 IOBD1.9 IOBD1.10 R2911.2
SMB0_CLK: CPU1.AY33 DIMM1.253 RN1703.3(B)
SMB0_DATA: CPU1.BA32 DIMM1.254 RN1703.4
SML1_CLK: Q801.3 Q2604.6 RN2401.3(B) U2401.67
SML1_DATA: Q801.6 Q2604.3 RN2401.4 U2401.68
SP5: R3303.1 U3301.15
SPI_CLK_KBC: RN2405.1 U2401.92
SPI_CLK_ROM: RN1603.4 RN2405.4 U2501.6
SPI_CS_KBC_N0: RN2405.2 U2401.90
SPI_CS_ROM_N0: R2540.2 RN1604.4 RN2405.3(B) U2501.1
SPI_CSN: U6304.J6 U6305.1
SPI_HOLD_CPU: R1617.2 RN1601.2 U2501.7
SPI_MISO: U6304.G6 U6305.2
SPI_MOSI: U6304.H6 U6305.5
SPI_SCK: U6304.K6 U6305.6
SPI_SI_KBC: RN2406.2 U2401.87
SPI_SI_ROM: RN1603.3(B) RN2406.3(B) U2501.5
SPI_SO_CPU: RN1604.3(B) RN2406.4 U2501.2
SPI_SO_KBC: RN2406.1 U2401.86
SPI_WP_CPU: R1619.2 RN1601.1 U2501.3
SPKR: CPU1.AP29 R2741.1
SVID_ALERT#_CPU: PG4607.1 R801.2 R810.1
SVID_CLK_CPU: PG4603.1 R813.1 RN807.3(B)
SVID_DATA_CPU: PG4605.1 R820.1 RN807.4
SVID_PWRGD: PR4619.2 PR4621.1 R818.1 R823.1 U801.3
SVID_PWRGD_R: C802.1 CPU1.G25 R818.2
SYS_PRES1#: AFTP4306.1 BATT1.7 R4301.2
SYS_PWRGD: R1731.1 R2609.2 R4004.2 U2401.84
SYS_PWRGD_G: Q2603.G R2607.1 R2609.1
SYS_PWRGD_R: CPU1.AE2 R1718.2 R1731.2
SYS_RESET#: CPU1.AF1 G1701.2 G1702.2 R2002.2 R2008.1
T_CRIT#: R2601.1 R2606.2 U2601.4
THERM_SYS_SHDN#: Q2603.S R2601.2 R2602.1
TOUCH_PANEL_EN: D2402.K R2427.2 U2401.25
TOUCH_PANEL_INTR#: CPU1.AL4 D2402.A R1708.2 R1735.2 R5504.2
TP_CLK: AFTP6532.1 Q6508.6 RN6504.4 TPAD1.3
TP_CLK_C: AFTP6529.1 RN6502.3(B) TPAD1.8
TP_DAT: AFTP6531.1 Q6508.3 RN6504.3(B) TPAD1.2
TP_DATA_C: AFTP6530.1 RN6502.4 TPAD1.7
TP_DISABLE#: R2494.1 R6520.2 TPAD1.6
TP_DISABLE#_R: R2494.2 U2401.62
TP_I2C_CLK: CPU1.AY22 Q6508.1 RN1704.4
TP_I2C_DATA: CPU1.BA22 Q6508.4 RN1704.3(B)
TP_ON#: R2407.2 R6516.1 U2401.33
TP_ON#_GATE: C6504.1 C6505.1 Q6503.G Q6504.G Q6507.2 Q6507.5 R6516.2
TP_VDD: AFTP6528.1 EC6502.1 Q6502.G Q6503.D R6504.1 R6505.1 R6512.1 R6513.1 R6520.1 RN6503.1 RN6503.2 RN6504.1 RN6504.2 TPAD1.1
TP_VDD_1D8V: Q6504.D Q6508.2 Q6508.5 R6506.1 R6518.1 RN1704.1 RN1704.2
TPAN_VDD: C5519.1 C5520.1 ED5501.5 F5503.2 LCD1.39 R5534.2
TPCLK: EC6501.1 RN6502.2 RN6503.3(B) U2401.72
TPDATA: EC6503.1 RN6502.1 RN6503.4 U2401.71
TPNL_INT: C5518.1 LCD1.27 R5504.1
TS_USB20_CON_N1: ED5501.6 EL5502.1 LCD1.30
TS_USB20_CON_P1: ED5501.1 EL5502.2 LCD1.31
TS_USB20_N1: CPU1.AV2 EL5502.4
TS_USB20_P1: CPU1.AV1 EL5502.3
UART_RX: TP6306.1 U6304.A9
UART_TX: TP6305.1 U6304.A10
USB1_USB20_CON_N6: AFTP3402.1 ED3505.3 EL3503.4 USB1.2
USB1_USB20_CON_P6: AFTP3403.1 ED3505.1 EL3503.3 USB1.3
USB1_USB20_N6: CPU1.AN2 EL3503.1
USB1_USB20_P6: CPU1.AN1 EL3503.2
USB1_USB30_RX_CON_N2: C3511.1 ED3504.1 R3506.2 USB1.5
USB1_USB30_RX_CON_P2: C3510.1 ED3503.1 R3505.2 USB1.6
USB1_USB30_RX_N2: CPU1.Y1 R3506.1
USB1_USB30_RX_P2: CPU1.Y2 R3505.1
USB1_USB30_TX_CMC_N2: C3505.2 R3504.1
USB1_USB30_TX_CMC_P2: C3506.2 R3503.1
USB1_USB30_TX_CON_N2: C3509.1 ED3502.1 R3504.2 USB1.8
USB1_USB30_TX_CON_P2: C3508.1 ED3501.1 R3503.2 USB1.9
USB1_USB30_TX_N2: C3505.1 CPU1.P2
USB1_USB30_TX_P2: C3506.1 CPU1.P1
USB2_PWR_EN#: IOBD1.23 R2444.2 U2401.112
USB2_USB20_CON_N3: AFTP6602.1 EL6603.1 IOBD1.28
USB2_USB20_CON_P3: AFTP6603.1 EL6603.2 IOBD1.29
USB2_USB20_N3: CPU1.AT2 EL6603.4
USB2_USB20_P3: CPU1.AT1 EL6603.3
USB3_PWR_EN#: R2471.2 U2401.108 U3601.4
USB3_USB20_CON_N4: AFTP6605.1 EL6604.1 IOBD1.25
USB3_USB20_CON_P4: AFTP6604.1 EL6604.2 IOBD1.26
USB3_USB20_N4: CPU1.AR2 EL6604.4
USB3_USB20_P4: CPU1.AR1 EL6604.3
USB_OC#0: CPU1.AB2 IOBD1.34 R1760.2
USB_OC#1: CPU1.AH1 R1707.2 U3601.3
USB_SS_ZVDD_095: CPU1.W5 R1610.1
USB_SS_ZVSS: CPU1.W4 R1609.1
USB_ZVSS: CPU1.AN7 R1603.1
VBKUP: C2402.1 R2425.1 U2401.114
VCORE_PWRGD: PG4602.2 PG4608.2 U2401.10
VD1_EN#: R2468.1 U2401.66
VD_IN1: C2612.1 C2613.1 R2608.2 R2612.1 R2614.2 U2401.95 U2401.104
VD_IN1_C: C2612.2 C2613.2 R2612.2 R2613.1
VD_OUT1#: R2602.2 R2603.2 R2615.2 U2401.110
VOL_DOWN#: EC6603.1 IOBD1.19 RN2403.3(B) U2401.79
VOL_UP#: EC6602.1 IOBD1.20 RN2403.4 U2401.77
VPP_2D5V: C1221.1 C1225.1 C1226.1 C1227.1 DIMM1.257 DIMM1.259 PR5312.1 PR5313.2
VPP_IN: PC5315.1 PR5311.1 PU5302.5 PU5302.9
VPP_PWR: PC5318.1 PC5319.1 PR5313.1 PR5315.1 PU5302.3 PU5302.4
VTT_CT_0.95V: C4006.1 U4002.12
VTT_CT_1.8V: C4005.1 U4002.10
WAKE_L: CPU1.AE7 R1759.2
WIFI_RF_EN: AFTP6104.1 R6113.1 U2401.82
WIFI_RF_EN_R: R6112.2 R6113.2 WLAN1.56
WLAN_CLK_CPU_N3: R1608.1 WLAN1.49
WLAN_CLK_CPU_N3_R: CPU1.J1 R1608.2
WLAN_CLK_CPU_P3: R1607.1 WLAN1.47
WLAN_CLK_CPU_P3_R: CPU1.J2 R1607.2
WLAN_CLKREQ_CPU_N3: AFTP6102.1 CPU1.AP31 R1715.2 WLAN1.53
WLAN_PCIE_RX_N3: CPU1.N5 R6104.2
WLAN_PCIE_RX_P3: CPU1.N4 R6101.2
WLAN_PCIE_TX_CON_N3: C304.2 WLAN1.37
WLAN_PCIE_TX_CON_P3: C303.2 WLAN1.35
WLAN_PCIE_TX_N3: C304.1 CPU1.B3
WLAN_PCIE_TX_P3: C303.1 CPU1.A3
WLANTX_N3: R6104.1 WLAN1.43
WLANTX_P3: R6101.1 WLAN1.41
X25M_48M_OSC: CPU1.AU27 TP1604.1
XI: C6344.1 R6353.1 U6304.F1 X6301.3
XO: R6353.2 R6365.1 U6304.E1
XO_R: C6343.1 R6365.2 X6301.1
XTL_32K_X1_CPU: C1703.1 CPU1.BA2 R1745.1 X1701.2
XTL_32K_X2_CPU: C1704.1 CPU1.AY2 R1745.2 X1701.1

Pads without a net: CPU1 A4 A5 A6 A7 A11 A12 A19 A20 A21 A22 AA4 AA37 AA38 AC4 AC5 AD1 AE34 AE37 AE38 AG2 AG8 AJ1 AJ34 AK1 AK2 AL5 AL34 AM15 AM17 AM19 AM21 AM23 AN8 AN34 AP13 AP15 AP17 AP19 AP21 AP23 AP25 AR13 AR15 AR17 AR21 AR25 AR29 AR38 AU4 AU13 AU15 AU17 AU23 AV7 AV9 AV11 AV13 AV15 AV17 AV21 AV23 AV25 AY3 AY4 AY7 AY13 AY29 AY31 B1 B2 B4 B5 B6 B7 B11 B12 B19 B20 B21 B22 BA13 BA28 BA29 C1 C2 D1 D2 D7 D9 D11 D13 D19 D35 E4 E7 E31 G4 G5 G19 H1 H2 H11 H13 H19 J4 J5 J37 K1 K2 L1 L2 L4 L5 L11 L34 M1 M2 R1 R2 R4 R5 R8 R10 T1 T2 U4 U5 V1 V2 W1 W2; D4001 2; DCIN1 4; DIMM1 87 88 91 92 95 96 97 100 101 104 105 162 165; ED3505 4 6; ED5501 3 4; HDD1 P13 P14 P15; HDMI1 13 14; IOBD1 35 38; KB1 28 29; LCD1 5 36; PU4401 8; PU4501 19; PU4601 27 28 29 30; PU4901 5 7 8; PU5201 26; PU5301 26; PU5401 5; PU5402 4; PU6301 2 5; RN4302 1 4; RN6802 4 5; U2401 16 65 81 118; U3301 7 9 12 14 16 19 22 23; U5501 3; U6301 A1 A2 A7 A8 A9 A10 A11 A12 A13 A14 B1 B7 B8 B9 B10 B11 B12 B13 B14 C1 C3 C5 C7 C8 C9 C10 C11 C12 C13 C14 D1 D2 D3 D4 D12 D13 D14 E1 E2 E3 E5 E8 E12 E13 E14 F1 F2 F3 F12 F13 F14 G1 G2 G3 G10 G12 G13 G14 H1 H2 H3 H5 H12 H13 H14 J1 J2 J3 J12 J13 J14 K1 K2 K3 K6 K7 K12 K13 K14 L1 L2 L3 L12 L13 L14 M1 M2 M3 M7 M8 M9 M10 M11 M12 M13 M14 N1 N3 N6 N7 N8 N9 N10 N11 N12 N13 N14 P1 P2 P7 P8 P9 P10 P11 P12 P13 P14; U6304 A3 A4 A5 A6 A7 B3 B4 B5 B6 C4 C9 C10 D9 D10 E9 E10 H3 K1 K4 K7 K10; WLAN1 6 16 17 19 20 21 22 25 26 27 28 31 32 34 38 40 42 48 50 55 59 60 61 62 64 65 66 67 68 70 71 73 76 77

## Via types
v1: diameter 0.508, hole 0.254, TOP to BOTTOM, 2382 vias
v2: diameter 0.356, hole 0.178, TOP to BOTTOM, 862 vias
v3: diameter 0.711, hole 0.406, TOP to BOTTOM, 480 vias
v4: diameter 0.457, hole 0.203, TOP to BOTTOM, 14 vias
v5: diameter 0.559, hole 0.305, TOP to BOTTOM, 2 vias

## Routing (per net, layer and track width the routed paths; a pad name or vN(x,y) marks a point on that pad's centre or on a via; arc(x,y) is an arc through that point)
1V_CPU_CORE: length 32.1
  TOP w0.508: PR4634.1 28.27,43.69 v1(28.27,44.27) ; v1(74.93,37.44) 75.34,37.85 C1009.1 ; v1(71.12,38.28) 71.13,38.29 C1075.1
  L3 w0.508: v1(28.27,44.27) 28.27,42.52 28.17,42.42 28.17,41.63 28.55,41.25 29.67,41.25 32.88,38.04 37.45,38.04 37.8,37.7 40.56,37.7 41.07,38.2 49.95,38.2 v3(52.21,40.46)
  vias: v1(78.74,37.49) v1(78.79,38.13) v1(78.92,38.81) v1(79.27,37.14) v1(79.45,38.36) v1(79.53,37.72) v1(79.98,44.93) v1(79.95,43.12) v1(80.35,37.83) v1(80.91,47.83) v1(80.91,45.98) v1(81.89,49.87) v1(81.89,46) v1(82.91,46.03) v1(82.98,47.86) v1(83.9,49.87) v1(83.9,47.86) v1(83.9,46.03) v1(84.25,44.65) v1(84.35,43.94) v2(57.1,45.49) v3(51.44,47.59) v3(51.44,46.7) v3(52.03,43.38) v3(52.21,42.37) v3(52.21,41.35) v3(52.32,47.59) v3(52.32,46.7) v3(52.88,48.41) v3(52.92,43.51) v3(53.1,42.5) v3(53.1,41.48) v3(53.1,40.59) v3(53.21,46.7) v3(53.31,47.58) v3(54.19,43.28) v3(54.43,48.39) v3(54.39,44.45) v3(54.53,45.49) v3(55.21,43.28) v3(55.41,44.45) v3(55.5,45.52)
1V_S0: length 18.5
  TOP w0.076: U6304.D8 54.8,91.07 54.8,92.63 54.56,92.86 54.38,92.86 v1(54.13,93.12) ; U6304.D3 52.8,91.07 53.3,91.07 U6304.D5 ; U6304.H4 52.8,88.57 52.44,88.57 52.19,88.82 U6304.H2 ; U6304.C3 52.3,91.57 52.3,92.51 52.22,92.58 52.12,92.58 v1(51.84,92.86)
  TOP w0.089: U6304.D3 U6304.C3 ; U6304.H2 U6304.G1 ; U6304.J4 U6304.H4
  TOP w0.203: v4(54.08,89.79) U6304.G7 ; U6304.G1 51.41,89.18 v1(51,89.18)
  BOTTOM w0.508: PC6303.1 PR6302.1 42.96,87.02 44.96,87.02 46,88.05 46,89.31 45.39,89.92 44.63,89.92 44.22,90.32 43.64,90.32
  vias: v2(40.27,91.79) v2(40.4,91.59) v3(39.65,92.28) v3(41.07,92.23)
3V5V_CT1: length 0.8
  BOTTOM w0.203: U4001.12 37.88,26.55 C4002.1
3V5V_CT2: length 2.9
  TOP w0.254: v1(38.04,27.4) 37.97,27.33 v2(37.97,26.82) 37.98,26.81 39.52,26.81 C4001.1
  BOTTOM w0.203: U4001.10 37.99,27.35 v1(38.04,27.4)
3V_5V_EN: length 49.9
  TOP w0.102: R4003.1 R4002.1 31.57,36.73 v1(31.57,37.16) ; v1(15.45,23.41) 15.46,23.4 15.68,23.4 16.5,22.57 16.5,18.46 14.88,16.84 PR4502.2 12.09,16.84 10.69,15.44 10.69,10.39 11.58,9.5 PR4514.2
  L3 w0.102: v1(15.95,32.46) 15.95,29.28 16.64,28.59 16.64,26.11 15.86,25.34 15.86,23.82 v1(15.45,23.41)
  BOTTOM w0.102: v1(31.57,37.16) 31.29,36.88 31,36.88 28.75,34.64 28.41,34.64 D4001.1 28.16,34.39 23.47,34.39 22.41,35.45 20.94,35.45 17.7,32.2 v2(16.75,32.2) 16.21,32.2 v1(15.95,32.46)
3V_5V_PWRGD: length 178.7
  L3 w0.254: v1(17.14,30.46) 17.91,29.69 17.91,29.06 17.86,29.01 17.86,25.96 17.48,25.58 17.48,22.91 17.08,22.52 17.08,18.48 15.58,16.98 13.2,16.98 12.26,16.03 12.07,16.03 11.67,15.63 11.67,15.1 v1(11.59,15.02) ; v1(102.84,98.35) 102.16,97.66 96.77,97.66 94.15,95.05 88.33,95.05 82.09,88.8 78.2,88.8 76.65,89.9 76,90.55 74.59,90.88 73.21,90.88 71.67,90.05 70.47,89.43 67.94,88.14 67.84,88.04 67.84,86.72 67.64,86.52 67.64,86.22 66.71,85.28 60.26,85.28 59.92,84.94 53.82,84.94 53.39,84.52 53.39,80.52 53.21,80.34 53.21,80.11 52.86,79.76 51.54,79.76 v1(50.52,78.74) 45.2,78.74 43.83,80.11 38.35,80.11 37.74,80.72 37.74,80.95 37.47,81.23 37.24,81.23 37.19,81.28 32.49,81.28 32.23,81.03 29.11,81.03 28.32,80.24 26.01,80.24 21.84,76.08 21.84,75.59 21.49,75.24 21.01,75.24 19,73.23 19,68.23 20.93,66.3 20.93,60.66 20.32,60.05 20.32,59.34 19.66,58.68 19.66,55.53 19.15,55.02 19.15,51.92 18.69,51.46 18.69,51.44 17.96,50.7 17.96,45.26 19.2,44.01 19.2,42.12 18.36,41.28 18.36,38.46 v1(22.1,34.72)
  BOTTOM w0.203: 11.83,14.86 11.87,14.86 12.3,14.43 PU4501.7
  BOTTOM w0.254: v1(50.52,78.74) 50.52,78.28 50.67,78.13 50.75,78.13 50.85,78.03 51.33,78.03 51.74,77.62 Q1702.2 51.74,76.84 52.1,76.48 52.22,76.48 PG4903.1 52.99,76.15 53.01,76.13 53.06,76.13 53.47,75.71 RN1706.2 ; v1(102.84,98.35) 103.35,98.35 PR5409.1 ; 11.67,15.02 11.33,15.36 PR4513.2 ; 11.67,15.02 v1(11.59,15.02) ; 11.67,15.02 11.83,14.86 ; v1(22.1,34.72) 21.31,34.72 v2(18.15,31.57) 17.14,30.56 v1(17.14,30.46)
3V_5V_PWRGD_R: length 8.7
  BOTTOM w0.254: Q1702.5 51.74,78.39 51.95,78.17 52.21,78.17 52.39,78.35 Q1702.6 52.62,78.88 53.33,78.17 v2(53.51,78.17) 53.53,78.16 55.46,78.16 55.8,77.81 55.8,77.39 55.25,76.84 55.01,76.84 54.79,76.62 54.79,76.33 RN1706.1
3V_S0_EN: length 3.6
  TOP w0.102: v1(34.72,26.36) 34.7,26.33 ; 34.7,26.33 R4001.2 ; 34.7,26.33 34.3,26.33 C4028.1 v2(32.97,25.88)
  BOTTOM w0.102: U4001.3 34.92,26.55 v1(34.72,26.36)
5V_AUX_S5: length 109
  TOP w0.254: PG4525.2 16.69,7.88 v1(15.44,6.63) ; v1(66.38,24.95) 66.37,24.94 66.37,24.56 67.23,23.69 67.3,23.69 67.55,23.44 67.55,23.31 67.59,23.28 67.59,22.85 67.55,22.82 67.55,21.01 v2(69.76,18.8) 70.55,18.01 74.21,18.01 76.22,16 76.22,15.9 76.48,15.64 76.51,15.64 76.66,15.49 77.26,15.49 77.47,15.7 78.96,15.7 80.75,13.91 84.39,13.91 v1(84.51,14.02)
  L4 w0.254: v1(15.44,6.63) 15.85,6.22 22.33,6.22 24.92,8.82 27.91,8.82 28.65,8.08 31.29,8.08 34.6,4.76 48.49,4.76 49.58,5.85 59.95,5.85 63.42,9.32 74.3,9.32 74.69,8.93 79.82,8.93 84.45,13.57 84.45,13.9 84.51,13.95 v1(84.51,14.02)
  BOTTOM w0.254: v1(66.38,24.95) 67.08,25.66 PR5410.1
5V_DDC_HDMI1: length 3.5
  TOP w0.102: RN5701.3 15.42,78.31 15.88,77.85 v2(15.88,77.71) 16.04,77.71 v1(16.48,77.27)
  BOTTOM w0.102: v1(16.48,77.27) 16.13,77.27 15.8,77.6 D5701.1
5V_DDC_HDMI2: length 4.7
  TOP w0.102: RN5701.4 15.11,78.98 15.16,78.93 v2(15.96,78.93) 15.95,78.93 15.95,78.59 v1(16.56,77.98)
  BOTTOM w0.102: D5701.2 15.8,79.53 16.13,79.19 16.13,78.56 16.56,78.13 v1(16.56,77.98)
5V_HDMI: length 1.2
  BOTTOM w0.635: 9.98,81.56 HDMI1.18 10.62,81
  vias: v2(12.72,84.43)
5V_S0: length 264.1
  TOP w0.508: v1(68.28,21.31) 68.28,22.52 68.31,22.55 68.31,25.36 69.35,26.39 v1(73.43,26.39) ; v1(120.45,99.11) 120.35,99.01 119.66,99.01 FC8925.1 119.56,99.01 v2(117.93,99.01) 116.44,99.01 115.33,97.89 114.3,97.89 113.08,99.11 104.37,99.11 FC8924.1 104.22,99.11 v2(99.83,99.11) 97.28,99.11 95.2,97.03 89.93,97.03 89.36,97.6 89.36,97.69 88.13,98.92 77.43,98.92 77.43,98.93 v2(75.74,98.93) 74.17,98.93 FC8923.1 73.94,98.99 70.26,95.3 70.1,95.3 68.94,94.13 65.3,94.13 v1(64.49,93.32) ; R2703.2 140.08,97.67 140.61,98.2 v1(141.22,98.2)
  L3 w0.508: v1(66.76,86.56) 65.57,87.75 v1(64.2,87.75) 64.16,87.79 63.18,87.79 62.27,86.88 61.53,86.88 60.86,86.21 60.29,86.21 59.65,85.57 53.55,85.57 53.18,85.21 50.13,85.21 48.49,86.84 46.63,86.84 45.39,85.6 39.83,85.6 37.54,83.31 32.05,83.31 31.63,83.73 30.52,83.73 28.7,81.92 27.66,81.92 26.89,81.14 23.74,81.14 v1(23.5,80.9) ; v1(141.22,98.2) 140.44,98.99 134.72,98.99 134.37,98.63 134.37,98.53 133.81,97.97 133.43,97.97 133.4,97.94 132.79,97.94 132.44,98.3 132.44,98.76 131.93,99.26 125.84,99.26 125.72,99.24 124.57,98.1 121.46,98.1 v1(120.45,99.11)
  L4 w0.508: v3(141.07,72.19) 141.07,78.54 140.28,79.33 140.02,79.33 139.27,80.08 139.27,86.46 139.55,86.74 139.55,87.3 138.81,88.04 138.81,91.19 140.49,92.86 140.49,95.76 141.22,96.5 v1(141.22,98.2) ; v1(120.14,8.1) 120.14,13.13 117.31,15.96 117.31,16.76 116.74,17.34 116.74,17.58 113.4,20.92 111.89,20.92 111.52,21.29 107.83,21.29 107.56,21.55 107.56,21.63 107.19,22 107.1,22 106.69,22.4 102.7,22.4 102.51,22.22 100.71,22.22 99.62,21.13 98.98,21.13 98.86,21.26 98.04,21.26 97.13,22.18 95.26,22.18 93.56,23.88 88.27,23.88 85.42,26.72 83.67,26.72 81.57,28.82 77,28.82 74.5,26.32 73.51,26.32 v1(73.43,26.39) ; v1(64.49,93.32) 64.49,90.2 64.14,89.84 64.14,87.82 v1(64.2,87.75) ; v1(66.76,86.56) 66.76,82.31 66.1,81.65 66.1,79.69 v1(66.34,79.44)
  BOTTOM w0.508: v1(23.5,80.9) 23.44,80.85 22.52,80.85 21.07,79.4 18.34,79.4 D5701.3 ; R2427.1 66.28,26.9 71.07,26.9 71.35,27.18 FC8922.1 73.43,27.08 v1(73.43,26.39) ; v1(68.28,21.31) 68.08,21.12 Q6501.E ; F5503.1 66.34,79.04 v1(66.34,79.44)
  vias: v2(140.31,71.2) v3(38.13,25.94) v3(38.15,24.59) v3(38.4,23.78) v3(38.96,25.91) v3(38.99,24.56) v3(139.88,72.26) v3(145.21,25.05) v3(145.21,24.16) v3(145.21,23.29)
5V_S0_EN: length 3.5
  TOP w0.254: C4029.1 34.62,27.99 34.62,27.38 v1(34.7,27.31) 34.87,27.13 R4012.2 35.72,27.13 36.21,26.64 v2(36.4,26.64)
  BOTTOM w0.203: v1(34.7,27.31) 34.74,27.35 U4001.5
5V_S5: length 249.8
  TOP w0.203: PU4601.12 28.06,48.48 27.31,47.73 27.2,47.73 27.08,47.6 v1(27.05,47.6) ; PU4601.26 32.24,51.46 32.69,51.9 32.69,51.92
  TOP w0.254: 32.69,51.92 v1(32.93,52.16)
  TOP w0.508: v1(131.52,64.7) 131.67,64.7 131.98,65 133.02,65 133.07,64.95 135.31,64.95 135.53,65.18 139.5,65.18 v1(139.65,65.33) ; v1(112.32,98.15) 112.32,97.82 111.27,96.77 111.27,89.07 v3(111.07,88.88) ; v1(61.52,68.99) 61.51,69 61.51,71.94 v1(62.28,72.71) 61.86,72.71 59.46,75.11 56.96,75.11 56.5,75.57 55.73,75.57 51.93,79.38 50.24,79.38 49.85,78.98 44.78,78.98 44.35,79.41 44.35,80.02 45.24,80.91 45.24,84.79 44.53,85.5 39.93,85.5 38.71,84.28 33.66,84.28 33.33,84.61 31.23,84.61 29.32,82.7 v1(27.64,82.7)
  L3 w0.508: v3(136.27,76.33) 137.36,75.24 137.36,67.79 139.55,65.61 139.55,65.43 v1(139.65,65.33) ; v1(27.05,47.6) 27.08,47.6 27.1,47.63 30.05,47.63 31.65,49.23 31.65,51.04 32.6,52 32.63,52 32.79,52.16 v1(32.93,52.16) 32.58,52.51 31.19,52.51 29.42,54.27 29.42,55.19 30,55.77 30,56.74 28.73,58.02 28.73,64.3 29.74,65.31 v1(29.74,68.43)
  L3 w0.762: v1(27.64,82.7) 27.58,82.75 27.58,82.83 27.13,83.29 25.43,83.29 23.72,84.99 20.19,84.99 v3(19.91,85.27) 18.31,83.67 18.31,76.7 17.22,75.61 17.22,75.03 15.7,73.51 15.7,72.79 15.17,72.26 15.01,72.26 13.77,71.02 v1(13.77,70.26) 13.92,70.41 15.29,70.41 17.6,68.09 17.6,65.14 18.14,64.61 v3(18.14,63.32)
  L4 w0.508: v1(62.28,72.71) 62.28,74.24 62.42,74.37 62.42,80.01 63.12,80.72 63.12,82.4 64.16,83.44 64.16,86.62 63.41,87.37 63.41,89.91 63.22,90.1 v1(63.22,93.27) ; v1(30.2,77.7) 30.2,77.67 29.72,77.19 29.72,75.1 29.87,74.95 29.87,71.73 28.98,70.84 v1(28.91,70.84)
  BOTTOM w0.203: U4002.4 79.22,82.09 79.4,82.27
  BOTTOM w0.508: PR5310.1 112.75,98.55 112.34,98.15 v1(112.32,98.15) ; v1(32.93,52.16) 32.93,52.35 32.42,52.86 PR4616.1 31.78,53.06 PC4610.1 ; v1(62.28,72.71) 62.73,72.71 PC4902.1 ; v1(62.28,72.71) 61.81,72.24 PU4901.6 ; v1(62.28,72.71) 62.28,73.31 PC4901.1 ; v1(61.52,68.99) 58.09,68.99 57.01,67.91 U4003.4 ; v1(28.91,70.84) 29.31,70.84 29.67,70.49 29.67,70.05 29.74,69.98 v1(29.74,68.43) ; v1(13.77,70.26) 13.44,70.59 PR4303.1 ; v1(30.2,77.7) 30.2,77.75 29.92,78.03 PR5201.2 29.82,78.49 PC5201.1 29.82,80.13 29.71,80.13 28.7,81.13 28.7,81.64 v1(27.64,82.7) ; PR5301.2 132.8,45.84 PC5301.1 132.51,45.9 131.58,46.82 131.58,48.6 132.38,49.4 132.38,61.85 131.98,62.26 131.93,62.26 131.52,62.66 v1(131.52,64.7) ; 79.4,82.27 79.48,82.35 79.48,83.88 79.53,83.93 C4018.1 79.49,84.32 79.49,85.28 79.63,85.42 C4017.1 79.63,86.25 79.15,86.73 79.15,87.58 79.83,88.27 79.83,89.44 79.32,89.94 79.25,89.94 76.71,92.49 71.82,92.49 70.37,91.04 65.58,91.04 63.35,93.27 v1(63.22,93.27)
  vias: v3(18.14,62.43) v3(33.68,22.99) v3(34.44,24.28) v3(34.54,22.28) v3(35.13,23.73) v3(35.43,22.28) v3(36.32,22.28) v3(97.31,14) v3(98.37,14) v3(99.49,14.02) v3(100.48,14) v3(110.13,88.93) v3(110.11,87.94) v3(111.12,87.96) v3(136.27,78.36) v3(136.27,77.52)
5V_USB30: length 13.6
  L4 w0.305: v1(17.86,60.68) 18.59,59.95 18.59,54.96 18.95,54.6 18.95,50.83 v1(18.86,50.74)
  BOTTOM w0.508: ED3505.5 18.06,50.04 18.57,50.55 18.67,50.55 v1(18.86,50.74)
  BOTTOM w0.635: 14.48,58.78 USB1.1 15.25,58
12V_BT+: length 22.2
  TOP w0.457: v1(134.06,29.8) 133.72,29.45 133.72,29.23 PQ4416.2
  TOP w0.508: v1(128.02,13.79) 128.02,14.29 v2(131.19,17.46) 133.17,19.44 v2(133.17,23.02) 133.17,23.87 132.18,24.86 132.18,26.24 132.66,26.72 PR4481.1 132.66,28.18 PQ4416.2
  BOTTOM w0.508: v1(134.06,29.8) 133.86,29.59 PR4454.2 132.77,29.52 PC4453.1
19V_DCBATOUT_LCD:
  vias: v2(44.38,84.66) v2(47.19,83.66)
+3V_1D8V_AVDD: length 7
  TOP w0.203: HDA27.33 144.92,87.46 144.6,87.14 144.6,86.94 144.41,86.75
  TOP w0.381: 144.26,86.31 144.26,86.6 144.41,86.75
  TOP w0.508: R2752.2 144.88,83.23 144.58,83.53 144.58,84.56 v2(144.42,84.71) C2710.1 144.26,85.69 144.26,86.31
+3V_1D8V_DVDD: length 12.3
  TOP w0.508: v1(151.66,96.47) 151.66,96.45 151.46,96.24 R2710.1
  L3 w0.508: v1(149.53,87.76) 151.09,87.76 152.83,89.5 152.83,95.3 v1(151.66,96.47)
  vias: v1(149,88.14) v2(150.65,86.36)
+5V_AVDD:
  vias: v2(142.46,94.91)
+5V_PVDD: length 1.4
  TOP w0.508: R2701.2 v2(141.9,75.34)
+5V_PVDD1:
  vias: v2(143.31,80.39) v2(143.42,76.39) v2(148.74,87) v2(148.9,86.91) v3(142.09,80.57) v3(142.37,79.55) v3(145.19,86.9) v3(147.9,87.1)
DVSS: length 5.7
  TOP w0.102: 152.49,93.47 153.03,94.02 R2716.2 ; 152.49,93.47 152.1,93.09 151,93.09 150.37,92.46 149.63,92.46 149.35,92.18 HDA27.10 ; 152.49,93.47 v2(152.49,93.44)
GND: length 1234.5
  TOP w0.076: U6304.D7 54.8,90.57 54.8,90.22 54.55,89.97 U6304.F7 ; v1(82.4,83.85) 82.75,83.49 83.19,83.49 83.44,83.75 U6301.N2 ; U6304.G5 53.79,89.07 53.79,88.7 53.55,88.45 U6304.J5 ; U6304.J7 54.79,88.57 55.15,88.57 55.3,88.42 55.3,88.18 55.55,87.93 U6304.K9 ; U6304.C5 53.4,91.32 53.15,91.57 52.95,91.57 52.8,91.72 52.8,92.44 52.53,92.71 v1(52.53,92.84)
  TOP w0.089: U6304.B10 56.53,91.82 56.82,92.11 v1(56.82,92.53)
  TOP w0.102: v1(84.83,44.92) 84.58,45.17 84.58,46.65 C1067.2 ; 84.13,43.54 84.52,43.53
  TOP w0.127: v1(67.18,56.36) 67.18,57.71 v1(67.34,57.86) ; v1(67.67,39.98) 67.67,41.18 v1(67.58,41.27) 67.59,41.27 v1(67.59,42.93) 67.59,43.64 v1(66.9,44.32) ; v1(133.76,86.92) 133.76,85.04 v1(134.04,84.76) ; v1(54.89,58.93) 56.06,58.93 v1(56.34,59.21) 56.34,60.33 v1(55.47,61.19) 56.05,61.19 56.36,61.5 56.36,62.65 56.02,62.99 v1(55.63,62.99) ; v1(64.59,59.54) 64.59,59.68 65.12,60.21 65.79,60.21 67.12,58.88 C1080.2 ; v1(134.57,81.03) 134.21,81.38 v1(134.21,82.86) ; U6301.N5 U6301.P6 ; v1(64.8,56.95) 64.8,57.96 v1(65.25,58.42) 65.84,57.84 v1(65.89,57.84) ; v3(138.25,63.37) 138.53,63.65 139.04,63.65 v1(139.29,63.4) ; v1(132.18,74.27) v1(132.18,74.98) 132.09,74.89 131.85,74.89 131.63,75.12 131.63,75.87 132.09,76.33 v1(132.13,76.33) 132.13,77.74 132.42,78.03 v1(132.74,78.03) ; v1(59.44,45.72) 59.49,45.67 59.49,45.01 59.33,44.85 58.11,44.85 57.95,45.01 57.95,46.09 v1(57.89,46.15) 58,46.27 58,47.03 v1(58.09,47.12) ; U6301.C4 84.96,88.24 v4(85.12,88.24) ; v1(73.41,64.09) 73.1,64.39 v1(71.4,64.39) ; v1(61.9,60.66) 61.9,61.28 61.77,61.41 61.47,61.41 61.45,61.43 61.44,61.43 61.18,61.69 61.18,62.35 v1(61.21,62.38) 63.7,62.38 v1(63.93,62.61) ; v1(140.51,59.44) 140.51,61.19 140.39,61.32 v1(139.34,61.32) ; C1058.2 77.27,64.51 75.2,66.58 v1(74.96,66.58)
  TOP w0.152: U6304.K9 55.55,87.66 55.89,87.32 v1(56.57,87.32)
  TOP w0.203: v1(50.98,92.79) 51.45,92.32 U6304.A1 U6304.A2 ; v1(144.83,49.07) 144.83,48.9 145.24,48.49 ED6002.8 ; U6301.A6 85.45,90.05 85.57,90.17 85.72,90.17 v1(86.13,90.58) ; U6304.K3 52.3,87.58 52.3,87.41 v1(52.27,87.33) ; v1(51,91.34) 51.02,91.32 U6304.C1 U6304.C2 ; U6304.C5 U6304.D6 U6304.D7 ; U6304.J1 51.39,88.17 v1(50.98,88.17)
  TOP w0.241: U6304.J1 51.56,88.31 52.04,88.31 U6304.J2 ; U6304.E2 U6304.E3
  TOP w0.254: v1(84.38,82.55) 84.45,82.62 U6301.P4 ; v1(86.16,82.68) 85.7,82.68 85.45,82.93 U6301.P6 ; 8.19,80.5 HDMI1.17 9.44,80.51 ; DB1.1 44.19,34.1 FC1601.2 ; C2444.1 50.75,24.97 FC2401.2 51.51,24.21 v1(51.51,23.78) ; v4(86.17,84.71) 86.17,84.78 86.3,84.91 86.3,84.91 86.45,85.06 U6301.K8 ; U6301.G5 85.01,86.75 85.09,86.67 85.12,86.67 85.52,86.26 v4(85.52,85.8) 85.47,85.75 U6301.J5 ; 9.41,77.5 HDMI1.11 8.19,77.5 ; U6301.E7 85.95,87.66 86.04,87.57 86.04,87.55 86.39,87.2 v1(86.39,86.92) 86.78,86.53 86.78,86.5 87.03,86.25 U6301.H10 ; 9.4,74.5 HDMI1.5 8.19,74.48 ; 10.66,76.01 HDMI1.8 9.32,75.96
  TOP w0.305: R5506.1 56.92,81.69 56.95,81.66 v1(56.95,81.38) ; U6901.8 95.17,84.96 v1(95.05,84.84) ; v1(52.7,80.32) 52.98,80.32 53.39,80.72 EC5506.2 ; PC4621.1 29.62,46.55 v1(29.87,46.81) ; U6901.5 96.82,86.08 v1(96.85,86.11) ; RN6802.6 93.54,17.73 93.29,17.98 92.94,17.98 ; U6901.6 96.32,85.95 v1(96.16,86.11) ; R5502.2 v1(56.03,81.36) 56.01,81.33 EC5505.2 ; U6901.7 95.23,85.52 95.22,85.52 v1(95.17,85.52)
  TOP w0.356: AFTP4305.1 111.71,11.81 111.71,12.19 v1(111.73,12.22) ; RN809.3 95.69,24.12 95.43,23.86 95.43,23 95.63,22.81 v1(96.01,22.81) 96.01,23.54 96.34,23.87 RN809.4
  TOP w0.381: EC4301.2 108.86,16.71 v1(108.81,16.66) ; v1(50.98,92.79) 50.88,92.89 C6320.2 ; C1006.2 85.44,50.32 85.44,50.27 v1(84.92,49.75)
  TOP w0.406: v1(91.52,44.76) 91.19,44.43 C1023.2
  TOP w0.457: DB1.3 46.19,35.58 46.58,35.97 46.58,36.2 v1(46.61,36.22) ; PR4615.2 24.37,54.65 24.18,54.84 24.18,55.07 24.16,55.1 v1(24.16,55.15) ; v1(24.79,55.16) 24.82,55.13 24.82,55.06 25.14,54.74 PC4609.2
  TOP w0.508: v1(152.2,89.77) 152.2,89.1 C2725.2 ; v1(142.06,74.35) 142.6,73.82 FC8921.2 ; v1(141.27,66.55) 141.27,66.32 R6009.2 ; R1603.2 69.22,56.87 v1(69.7,56.39) ; v1(16.15,75.97) 16.15,76.53 15.26,77.42 R5709.1 ; v1(56.82,92.53) 57.05,92.76 R6346.2 ; R2443.2 56.54,26.8 57.22,26.8 57.29,26.87 57.82,26.87 58.19,26.5 58.19,26.5 58.46,26.23 EC2401.2 ; C4006.2 79.17,80.24 v1(79.22,80.19) ; v1(59.44,81.48) 59.82,81.1 R5507.1 ; C1030.2 v1(91.24,49.22) ; SPR6.1 115.16,68.38 v1(115.39,68.15) ; FC8913.2 30.68,75.03 v1(30.35,75.36) ; v1(88.94,51.97) 88.39,51.42 C1031.2 ; v1(99.87,85.17) 99.85,85.17 99.82,85.14 R6903.1 ; v1(82.09,36.83) 82.09,37.53 R809.2 ; v1(77.9,47.82) 77.53,47.45 C1012.2 ; C4001.2 40.49,25.88 C2440.2 40,25.81 v1(39.66,26.15) ; FC8904.2 143.41,54.38 140.32,54.38 SPR3.1 136.73,53.5 v1(136.44,53.79) ; v1(134.92,92.97) 135.36,92.53 EC2702.2 ; EC2703.2 v1(138.28,81.31) 138.23,81.26 C1201.2 ; v1(120.65,86.31) 120.67,86.28 120.71,86.27 121.11,85.7 C1227.2 ; C1066.2 73.04,58.6 v1(73.31,58.33) ; v1(16.25,14.92) 17.14,15.82 FC8908.2 ; C1210.2 130.43,47.12 C1211.2 129.49,46 128.87,45.38 v1(128.64,45.38) ; v1(29.36,56.03) 29.36,56.24 29.49,56.36 PR4608.2 ; v1(64.8,56.95) 64.62,56.95 64.47,57.1 64.29,57.1 R2007.2 64.03,57.15 R2009.2 ; R4301.1 109.98,14.17 109.52,14.63 EC4305.1 109.52,15.52 EC4302.2 109.19,15.39 109.05,15.39 109.04,15.39 108.46,15.39 v1(108.45,15.41) ; PC4612.1 23.9,49.99 23.83,49.91 23.32,49.91 v1(23.14,49.73) ; C2704.2 140.89,81.99 140.89,81.59 140.94,81.54 v1(140.94,81.48) ; v1(12.67,13.18) 12.47,13.39 PC4502.2 ; 92.84,84.28 92.84,84.15 93.6,83.39 C6902.2 ; 92.84,84.28 92.38,83.82 v1(92.38,83.09) ; 92.84,84.28 C6901.2 ; R4002.2 30.51,37 v1(30.84,37.33) ; EC8905.2 58.7,25.21 58.72,25.23 EC2401.2 ; v1(26.44,55.98) 26.44,56.29 26.21,56.52 PC4605.2 ; FC8927.2 73.96,79.38 v3(73.84,79.25) ; v1(98.88,94.9) 99.03,94.74 FC8917.2 ; C1024.2 v1(89.03,48.72) ; v1(58.42,64.26) 58.64,64.05 FC1001.2 ; R2704.2 137.36,83.62 v1(136.37,84.61) ; DB1.12 53.11,37.16 52.07,36.12 v1(51.97,36.12) ; C1037.2 79.17,60.91 C1034.2 78.94,62.41 78.46,62.41 78.21,62.66 v1(78.18,62.66) 77.27,63.58 C1058.2 ; FC8909.2 27.71,32.62 v1(27.84,32.74) ; C1081.2 C1065.2 76.53,60.61 v1(76.53,59.94) ; v1(121.74,98.88) 121.01,98.15 FC8925.2 ; v1(131.44,58.37) 131.37,58.29 C1214.2 ; v1(59.59,26.57) 59.59,26.52 59.09,26 EC2401.2 ; v1(84.92,49.75) 84.98,49.69 C1068.2 ; PR4418.2 138.99,27 138.79,26.8 v1(138.79,26.75) ; R1609.2 70.74,47.12 70.74,47.12 70.21,47.12 69.85,46.76 69.85,46.71 69.71,46.57 v1(69.71,46.47) ; R2735.2 v1(153.31,97.72) ; C2448.2 40.02,29.41 EC8904.2 39.45,29.92 v1(39.07,30.3) ; R802.2 77.8,39.19 v1(77.8,38.53) 77.8,38.47 77.85,38.42 R811.2 ; EC2701.2 132.99,97.56 v1(132.99,97.23) ; 57.02,94.92 56.9,94.79 56.64,94.79 56.46,94.62 v1(56.36,94.62) 55.88,95.1 R6360.2 ; C1048.2 74.63,56.03 v1(74.94,55.71) 75.05,55.6 75.08,55.6 75.44,55.25 C1057.2 ; EC2711.2 154.06,86.01 154.81,86.75 v1(154.94,86.75) ; EC2705.2 151.54,98.45 v1(151.99,97.99) ; PC4620.1 PR4631.2 v1(30.89,43) ; FC8915.2 28.52,80.55 v1(28.04,81.03) ; PC4608.2 31.14,60.5 v1(31.14,59.89) ; R2706.2 137.29,82.35 137.28,82.36 136.82,82.36 v1(136.37,82.81) ; C1038.2 C1046.2 86.02,56.14 86.54,55.62 v1(86.54,55.3) 86.36,55.12 C1035.2 ; R5505.1 57.94,77.34 57.38,76.79 v1(57.38,76.66) ; v1(131.44,52.53) 131.37,52.61 C1205.2 ; C1022.2 89.66,53.46 v1(89,54.12) ; C1025.2 86.49,60 v1(86.64,59.85) ; v1(74.49,42.24) 74.89,42.64 C1016.2 ; C6330.2 49.81,94.62 v1(49.56,94.36) ; v1(16.94,23.71) 17.04,23.81 C3303.2 C3302.2 v1(17.04,29.52) ; C2443.2 59.03,21.47 R2497.1 59.11,21.39 59.11,21.08 58.55,20.52 v1(58.55,20.45) ; v1(84.96,62.13) 84.96,61.94 85.42,61.48 C1051.2 85.6,60.89 85.6,60.23 v1(85.37,60) ; C6701.2 7.54,42.75 7.52,42.72 v1(7.49,42.72) ; C4029.2 33.68,27.76 v1(34.06,27.38) 33.86,27.18 C4028.2 ; EC2710.2 150.95,89.94 150.93,89.92 v1(150.93,89.77) ; PC4456.2 140.61,21.95 v3(140.61,22.81) ; R6357.2 R6355.2 52.41,94.92 52.13,94.64 v1(52.04,94.64) ; v1(43.94,36.83) 43.61,37.16 DB1.11 ; C1028.2 90.9,46.59 v1(91.34,47.02) ; v1(112.83,36.37) 112.83,38.57 SPR4.1 ; SPR5.1 110.05,81.64 v1(110.03,81.66) ; EC5507.2 v1(57.96,81.36) ; C1064.2 73.43,60.76 74.3,59.89 v1(74.42,59.89) ; v1(140.28,83.42) 140.28,83.92 140.89,84.53 C2709.2 ; v1(131.44,56.72) 131.37,56.8 C1206.2 ; v1(85,47.57) 84.34,46.91 C1067.2 ; C1004.2 82.38,48.3 v1(81.9,47.82) 81.96,47.76 C1070.2 ; C2739.2 153.82,96.75 v1(153.92,96.85) ; FC8906.2 44.6,12.27 45.1,12.77 v1(45.1,12.96) ; C6314.2 v1(60.96,91.16) ; C1216.2 131.37,54.89 v1(131.44,54.81) ; AFTP6526.1 35.28,8.51 v1(35.48,8.51) ; C1080.2 C1045.2 67.59,58.12 v1(67.34,57.86) ; C6702.2 6.71,44.38 v1(6.65,44.32) ; v1(131.95,33.83) 132.32,33.47 PQ4415.2 ; 13.36,11.84 13.28,11.76 PC4501.2 ; v1(131.44,50.5) 131.37,50.57 C1219.2 ; C1207.2 131.33,60.58 v1(131.41,60.66) ; C1017.2 77.64,50.17 77.88,49.94 v1(77.93,49.94) ; v1(69.32,62.18) 69.32,61.39 C1079.2 C1044.2 70.46,61.04 C1043.2 71.58,61.34 R1601.1 ; v1(144.2,82.98) EC2704.2 ; PC4513.2 v1(32.2,21.59) ; ED501.2 87.38,38.78 v1(87.08,38.49) ; v1(41.91,33.83) 41.96,33.89 42.21,33.89 R2613.2 42.7,34.01 C2447.1 43.96,34.64 DB1.1 ; EC1701.1 71.7,52.35 71.58,52.22 71.58,52.19 v1(71.33,51.94) ; EC2709.2 152.85,91.26 153.51,91.92 154.03,91.92 v1(154.22,91.74) ; PC4622.2 28.47,41.56 v1(28.8,41.89) 28.38,42.32 PC4623.2 ; FC8911.2 v1(22.76,58.17) 22.71,58.12 PR4434.1 ; PR4630.1 25.96,46.92 25.96,46.74 26.39,46.31 26.42,46.31 v1(26.47,46.26) ; C1075.2 74.02,39.07 v1(74.4,38.69) 75,39.29 C1009.2 ; 31.88,41.43 32.03,41.28 v1(32.03,40.69) ; C4005.2 80.59,79.83 v1(80.24,80.19) ; C2705.2 141.58,81.17 141.1,80.69 v1(141.1,80.62) ; FC8924.2 v1(105.05,98.12) ; EC8903.2 18.08,85.93 v1(17.65,85.93) ; v1(32.64,46.74) 32.64,46.11 32.97,45.78 PR4629.2 ; FC8919.2 145.11,20.09 v1(144.73,20.47) 144.55,20.3 FC8905.2 ; v1(72.25,41.52) 71.65,41.52 71.41,41.76 C1020.2 ; FC8923.2 72.59,99.9 v1(71.76,99.07) ; v1(139.85,98.35) 139.24,98.35 138.89,97.99
  TOP w0.635: HDMI1.20 9.68,85.24 ; HDMI1.20 9.68,83.26 ; HDMI1.20 11.45,84.25 ; USB1.10 6.83,46.65 ; USB1.10 3.95,46.65 ; USB1.10 5.39,45.71 ; USB1.4 14.48,51.78 ; USB1.4 15.25,51 ; USB1.4 14.48,50.22 ; 2.7,66.86 HDMI1.23 ; HDMI1.23 3.95,67.85 ; HDMI1.23 1.45,67.85 ; 1.45,86.15 HDMI1.21 3.95,86.15 ; USB1.7 12.98,55.28 ; USB1.7 12.98,53.72 ; USB1.7 13.76,54.5 ; 9.68,70.74 HDMI1.22 9.68,68.76 ; 9.98,72.44 HDMI1.2 10.62,73 ; USB1.11 6.83,62.35 ; USB1.11 3.95,62.35 ; USB1.11 5.39,63.29 ; 11.35,46.65 USB1.12 ; USB1.12 12.89,45.71 ; USB1.12 14.43,46.65 ; USB1.13 14.43,62.35 ; USB1.13 12.89,63.29 ; USB1.13 11.35,62.35 ; 151.58,12.25 HDD1.24 150,11.21
  L3 w0.127: v1(21.39,39.47) 21.93,39.47 22.67,38.73 22.67,38.33 22.17,37.82 v1(22,37.82) ; v1(134.57,79.1) 134.31,79.1 134.05,79.37 134.05,80.57 134.5,81.03 v1(134.57,81.03)
  L3 w0.508: HDD1.P5 150.58,27.68 ; HDD1.P6 150.58,26.41 ; HDD1.P10 150.58,21.33 ; HDD1.P12 150.58,18.79 ; HDD1.P4 150.58,28.95
  L3 w0.635: 5.39,45.71 USB1.10 ; USB1.10 3.95,46.65 ; USB1.10 6.83,46.65 ; 150,11.21 HDD1.24 ; HDD1.24 151.58,12.25 ; HDD1.24 148.42,12.25 ; HDD1.24 150,13.29 ; USB1.11 6.83,62.35 ; USB1.11 3.95,62.35 ; USB1.11 5.39,63.29 ; 2.7,66.86 HDMI1.23 ; HDMI1.23 3.95,67.85 ; HDMI1.23 1.45,67.85 ; 12.98,53.79 USB1.7 ; USB1.7 12.98,55.21 ; USB1.7 13.69,54.5 ; HDD1.23 151.58,49.45 ; HDD1.23 148.42,49.45 ; HDD1.23 150,48.41 ; 11.35,62.35 USB1.13 12.89,63.29 ; 3.95,86.15 HDMI1.21 1.45,86.15 ; 14.48,51.71 USB1.4 14.48,50.29 ; 12.89,45.71 USB1.12 11.35,46.65 ; HDD1.S1 150.36,46.73 ; HDD1.S1 148.84,46.73 ; HDD1.S1 149.6,47.42 ; HDMI1.22 9.68,70.74 ; HDMI1.22 9.68,68.76 ; HDMI1.22 11.45,69.75 ; HDMI1.20 11.45,84.25 ; HDMI1.20 9.68,85.24 ; HDMI1.20 9.68,83.26
  L4 w0.127: v1(61.52,77.9) 61.65,77.78 v1(61.65,74.37) ; v1(63.37,61.37) 63.93,61.93 v1(63.93,62.61)
  L4 w0.635: 148.84,28.95 HDD1.P4 150.36,28.95 ; HDD1.S1 149.6,47.42 ; HDD1.S1 150.36,46.73 ; HDD1.S1 148.84,46.73 ; USB1.10 6.83,46.65 ; USB1.10 5.39,45.71 ; USB1.10 3.95,46.65 ; 148.42,49.45 HDD1.23 ; HDD1.23 150,48.41 ; HDD1.23 151.58,49.45 ; HDMI1.23 3.95,67.85 ; HDMI1.23 1.45,67.85 ; HDMI1.23 2.7,66.86 ; 150,11.21 HDD1.24 ; HDD1.24 148.42,12.25 ; HDD1.24 150,13.29 ; HDD1.24 151.58,12.25 ; 14.48,50.29 USB1.4 14.48,51.71 ; HDMI1.20 9.68,85.24 ; HDMI1.20 9.68,83.26 ; HDMI1.20 11.45,84.25 ; 150.36,21.33 HDD1.P10 148.84,21.33 ; 12.89,63.29 USB1.13 11.35,62.35 ; 148.84,27.68 HDD1.P5 150.36,27.68 ; HDMI1.22 9.68,70.74 ; HDMI1.22 11.45,69.75 ; HDMI1.22 9.68,68.76 ; USB1.7 13.69,54.5 ; USB1.7 12.98,55.21 ; USB1.7 12.98,53.79 ; 148.84,18.79 HDD1.P12 150.36,18.79 ; 148.84,26.41 HDD1.P6 150.36,26.41 ; USB1.11 5.39,63.29 ; USB1.11 3.95,62.35 ; USB1.11 6.83,62.35 ; 1.45,86.15 HDMI1.21 3.95,86.15
  BOTTOM w0.102: v1(77.8,38.53) 77.8,39.32 CPU1.A18
  BOTTOM w0.152: U2401.89 43.97,30.55 44.32,30.2 v1(44.58,30.2)
  BOTTOM w0.203: U6001.3 147.22,57.38 v1(147.04,57.56) ; U4001.11 36.97,26.95 36.41,27.15 v1(36.37,27.23) ; WLAN1.7 154.12,92.51 v1(154.41,92.51) ; v1(140.51,45.09) 140.51,45.11 140.36,45.26 140.16,45.26 140.07,45.35 PU5301.30 138.87,45.35 PU5301.33 139.15,44.55 PU5301.32 139.69,44.05 v1(139.7,44.05) ; v1(60.11,31.55) 60.05,31.61 59.96,31.61 59.92,31.65 59.51,31.65 59.41,31.75 U2401.5 ; U2401.78 44.15,26.15 44.37,25.94 v1(44.4,25.94) ; v1(59.59,29.16) 59.38,28.95 U2401.12 ; IOBD1.30 136.68,83.05 136.66,83.03 136.6,83.03 v1(136.37,82.81) ; WLAN1.1 154.98,94.75 v1(155.07,94.67) ; v1(59.59,26.57) 59.58,26.56 58.58,26.56 U2401.18 ; v1(91.52,55.73) 91.43,55.82 CPU1.AL41 ; U4002.11 79.22,78.67 79.25,78.64 v1(79.25,78.54) ; CPU1.U1 CPU1.U2 ; PU5301.4 137.92,43.16 v1(137.99,43.09) ; v1(52.47,32.84) 52.63,33 52.63,33.65 52.35,33.92 U2401.116 ; CPU1.AW37 88.25,60.17 89.25,60.17 ; v1(52.68,20.83) 52.35,20.5 U2401.45 ; PU5201.5 30.45,75.46 v1(30.35,75.36) 30.65,75.06 PU5201.4 ; ED6002.8 145.24,48.49 144.83,48.9 v1(144.83,49.07)
  BOTTOM w0.216: v1(88.94,51.97) 88.94,51.83 88.6,51.49 CPU1.AC38
  BOTTOM w0.25: CPU1.E38 88.73,41.38 88.73,40.86 88.76,40.84 v1(88.76,40.77)
  BOTTOM w0.254: 9.42,74.49 HDMI1.5 8.19,74.5 ; v1(67.94,45.36) 68.1,45.52 CPU1.N1 CPU1.N2 ; DIMM1.209 121.91,74.12 122.94,74.12 123.04,74.02 124.76,74.02 v1(124.99,73.79) ; v1(30.84,37.33) 31.03,37.33 31.06,37.37 31.06,37.39 31.34,37.67 31.8,37.67 32.16,37.31 32.16,36.86 31.85,36.55 EC2403.2 ; HDMI1.17 9.36,80.35 ; v1(128.64,41.41) 128.68,41.38 DIMM1.86 ; v1(128.65,24.33) 128.66,24.35 128.66,24.38 DIMM1.18 ; CPU1.A32 CPU1.B32 ; v1(62.31,48.06) 62.97,48.72 R1757.1 ; CPU1.A8 CPU1.B8 ; CPU1.AW11 CPU1.AY11 73.92,60.94 73.92,61.6 CPU1.BA11 ; CPU1.AL1 68.11,55.83 68.2,55.83 68.22,55.86 68.68,55.86 68.7,55.83 68.79,55.83 CPU1.AL2 CPU1.AL3 69.72,56.04 69.72,56.37 v1(69.7,56.39) ; CPU1.G3 69.5,43.01 v1(69.66,43.17) 69.5,43.33 CPU1.J3 ; v1(67.58,41.27) 67.84,41.52 CPU1.E1 CPU1.E2 ; CPU1.G2 68.78,42.64 68.12,42.64 CPU1.G1 67.79,42.93 v1(67.59,42.93) ; 10.65,76.02 HDMI1.8 9.38,75.99 ; C1601.1 63.55,43.38 v1(62.81,44.12) 62.64,43.95 62.61,43.95 62.53,43.87 60.2,43.87 59.69,43.36 v1(59.69,42.91) 60.05,42.55 60.05,40.34 60.02,40.31 60.02,39.79 60.34,39.47 v1(61.72,39.47) ; DIMM1.201 123.15,72.13 123.27,72.01 v1(123.39,72.01) ; 86.08,42.7 86.16,42.62 CPU1.G35 ; 86.08,42.7 86.08,43.03 85.57,43.54 v1(85.47,43.54) ; 86.08,42.7 85.78,42.39 85.23,42.39 CPU1.G31 ; DIMM1.78 128.67,39.38 v1(128.64,39.4) ; CPU1.AC3 69.5,51.76 v1(69.69,51.95) ; DIMM1.213 123.25,75.13 123.32,75.06 v1(123.34,75.06) ; v1(27.36,11.58) 27.25,11.48 EC6501.2 ; CPU1.AW3 69.5,59.86 v1(69.65,59.7) ; DIMM1.26 v1(128.66,26.38) ; CPU1.L41 91.45,44.82 v1(91.52,44.76) ; CPU1.AA2 68.77,50.35 68.13,50.35 CPU1.AA1 ; HDMI1.11 9.45,77.49
  BOTTOM w0.279: v1(128.54,78.38) 128.54,78.38 DIMM1.226 ; v1(124.66,38.15) 124.66,37.95 123.84,37.12 DIMM1.69 ; v1(124.05,33.96) 123.98,33.96 123.81,34.12 DIMM1.57 ; DIMM1.184 128.7,67.87 128.69,67.87 v1(128.66,67.87) ; v1(124.64,31.68) 124.64,31.84 123.85,32.63 DIMM1.51 ; v1(126.7,39.35) 126.7,38.71 127.53,37.87 DIMM1.72 ; DIMM1.239 123.3,81.62 v1(123.37,81.69) ; DIMM1.196 v1(128.52,70.88) ; DIMM1.217 124,76.13 124.64,75.49 v1(124.64,75.24) ; v1(127.94,45.29) 127.94,45.48 128.79,46.33 128.9,46.33 128.95,46.38 DIMM1.106 ; v1(128.65,72.26) 128.76,72.38 DIMM1.202 ; DIMM1.30 128.74,27.38 v1(128.59,27.52) ; DIMM1.244 v1(128.51,82.88) ; v1(125.68,86.34) 123.97,84.62 DIMM1.251 ; DIMM1.193 125.13,70.13 v1(126.06,69.19) ; v1(126.29,70.82) 125.93,70.82 125.81,70.94 123.27,70.94 123.09,71.13 DIMM1.197 ; DIMM1.103 123.39,45.63 124.21,44.81 v1(124.21,44.71) ; v1(128.5,33.87) DIMM1.56 ; DIMM1.44 126.98,30.87 126.31,31.54 v1(126.31,31.54) ; DIMM1.90 v1(128.64,42.38) ; v1(124.64,26.44) 124.64,26.67 123.68,27.63 DIMM1.31 ; DIMM1.14 128.12,23.38 127.25,22.51 v1(127.25,22.33) ; v1(127.32,41.41) 127.32,41.26 128.21,40.38 DIMM1.82 ; v1(126.03,38.15) 126.03,37.77 124.39,36.12 DIMM1.65 ; v1(124.76,41.43) 124.76,40.84 124.04,40.13 DIMM1.81 ; v1(125.09,67.31) 125.09,68.18 124.15,69.13 DIMM1.189 ; DIMM1.248 128.13,83.88 127.25,84.76 v1(127.25,84.79) ; v1(128.66,44.41) 128.7,44.38 DIMM1.98 ; DIMM1.205 123.9,73.13 124.66,72.37 v1(124.66,71.91) ; v1(127.38,74.32) 127.38,74.07 128.07,73.38 DIMM1.206 ; v1(128.65,74.37) 128.7,74.37 128.7,74.38 DIMM1.210 ; v1(123.34,31.6) 123.27,31.6 123.24,31.63 DIMM1.47 ; DIMM1.238 128.99,81.37 128.75,81.61 127.48,81.61 126.45,82.63 v1(126.45,82.78) ; v1(124.99,44.71) 123.07,46.63 DIMM1.107 ; v1(128.65,35.87) 128.69,35.87 128.7,35.87 DIMM1.64 ; v1(124.64,24.54) 124.64,24.65 123.71,25.58 122.94,25.58 122.89,25.63 DIMM1.23 ; v1(128.65,22.38) 130.1,22.38 DIMM1.10 ; DIMM1.234 v1(128.61,80.37) ; DIMM1.93 v1(123.46,43.13) ; v1(127.28,68.91) 127.28,69.04 128.12,69.88 DIMM1.192 ; v1(128.65,75.39) 128.8,75.39 128.82,75.38 DIMM1.214 ; v1(123.65,64.21) 123.29,64.57 122.71,64.57 122.65,64.62 DIMM1.171 ; v1(127.33,24.49) 127.33,24.54 128.17,25.38 DIMM1.22 ; v1(124.99,64.19) 124.99,64.25 123.86,65.38 123.01,65.38 122.77,65.62 DIMM1.175 ; v1(125.35,79.63) 125.35,79.38 124.6,78.62 DIMM1.227 ; DIMM1.222 128.06,77.38 127.27,78.17 v1(127.27,78.25) ; v1(127.3,75.41) 127.3,75.57 128.11,76.38 DIMM1.218 ; v1(123.42,83.59) 123.39,83.62 DIMM1.247 ; v1(128.65,21.39) 128.68,21.39 128.69,21.38 DIMM1.6 ; v1(124.69,81.64) 124.69,81.23 124.09,80.62 DIMM1.235 ; v1(124.64,29.72) 124.64,29.88 123.9,30.63 DIMM1.43 ; DIMM1.230 v1(128.63,79.38) ; DIMM1.48 128.55,31.87 v1(128.46,31.79) ; DIMM1.52 v1(128.66,32.87) ; DIMM1.243 124.56,82.62 125.37,83.44 v1(125.37,83.59) ; DIMM1.5 122.97,21.12 123.24,20.86 v1(123.83,20.86) ; DIMM1.176 128.77,65.87 128.73,65.91 v1(128.65,65.91) ; DIMM1.68 v1(128.66,36.87) ; v1(128.63,20.3) 128.98,20.38 DIMM1.2 ; DIMM1.172 129.07,64.87 129.05,64.85 v1(128.65,64.85) ; DIMM1.27 123.19,26.63 v1(123.37,26.44) ; DIMM1.167 122.76,63.62 123.1,63.29 126.28,63.29 v1(126.36,63.2) ; v1(125.71,21.94) 125.71,22.73 124.81,23.63 DIMM1.15 ; DIMM1.73 123.32,38.13 v1(123.34,38.1) ; v1(124.99,39.6) 124.99,39.55 124.57,39.13 DIMM1.77 ; DIMM1.85 123.16,41.13 v1(123.46,41.43) ; DIMM1.61 125.37,35.12 127.01,36.77 v1(127.01,37.02) ; v1(123.34,79.66) 123.31,79.62 DIMM1.231 ; v1(73.51,51.97) 73.48,51.99 73.48,52.44 ; v1(126.59,66.17) 126.31,66.45 123.44,66.45 122.77,67.13 DIMM1.181 ; v1(123.44,44.68) 123.37,44.68 123.31,44.63 DIMM1.99 ; DIMM1.89 123.3,42.13 124.26,43.08 v1(124.26,43.11) ; DIMM1.19 123.26,24.63 v1(123.34,24.54) ; v1(126.03,29.8) 126.03,29.15 125.51,28.63 DIMM1.35 ; v1(123.19,18.98) 123.19,19.41 122.47,20.12 DIMM1.1 ; DIMM1.185 123.19,68.13 123.8,67.52 v1(123.8,67.36) ; DIMM1.252 v1(128.61,84.88) ; v1(123.65,21.85) 123.65,21.86 123.38,22.12 DIMM1.9 ; v1(128.65,29.75) 128.78,29.87 DIMM1.40 ; v1(127.31,67.78) 128.22,66.87 DIMM1.180 ; DIMM1.39 123.22,29.63 123.29,29.69 v1(123.34,29.69) ; DIMM1.60 v1(128.66,34.87) ; v1(125.43,76.96) 125.43,77.17 124.97,77.62 DIMM1.223 ; v1(127.36,29.67) 127.36,29.66 128.14,28.87 DIMM1.36 ; DIMM1.168 128.8,63.87 128.79,63.86 v1(128.65,63.86) ; DIMM1.94 v1(128.62,43.38) ; DIMM1.102 v1(128.64,45.38) ; v1(128.63,68.87) DIMM1.188
  BOTTOM w0.3: CPU1.G41 91.62,42.62 v1(91.77,42.47) ; CPU1.A39 89.35,38.56 v1(89.46,38.45) ; v1(91.26,53.62) CPU1.AG41 ; CPU1.C41 91.32,40.37 91.36,40.33 91.9,40.33 v1(91.9,40.31) ; CPU1.AC41 91.25,51.42 91.31,51.36 v1(91.31,51.39) ; v1(91.39,60.56) 91.1,60.27 CPU1.AW41 ; v1(87.08,38.49) 87.1,38.51 CPU1.A35 ; v1(89.31,62.46) 89.28,62.46 89.35,62.39 CPU1.BA39 ; CPU1.R41 v1(91.34,47.02) ; CPU1.BA31 84.9,62.07 v1(84.96,62.13) ; v1(91.24,49.22) CPU1.W41 ; v1(87.1,62.97) 87.1,62.97 CPU1.BA35 ; CPU1.AR41 v1(91.5,58.02)
  BOTTOM w0.305: v1(71.4,64.39) 71.22,64.57 R1724.1 ; CPU1.AA1 67.69,50.32 v1(67.59,50.42) ; CPU1.C19 77.98,40.74 77.52,40.74 CPU1.C17 ; CPU1.G27 82.29,42.31 v1(82.14,42.31) ; CPU1.C27 82.38,40.74 82.18,40.74 v1(82.15,40.77) 81.95,40.77 CPU1.C25 81.4,40.62 80.7,40.62 CPU1.C23 ; C3508.2 20.73,45.9 v1(20.73,46.36) ED3501.2 ; CPU1.E39 89.3,41.28 88.79,40.77 v1(88.76,40.77) ; CPU1.BA11 73.9,62.07 v1(74.04,62.21) ; CPU1.E35 87.71,41.92 v1(87.73,41.94) 87.6,42.06 87.6,42.11 87.3,42.42 87.2,42.42 CPU1.G35 CPU1.G37 ; CPU1.C35 86.81,40.42 86.66,40.58 v1(86.6,40.58) 86.16,40.58 CPU1.C33 ; CPU1.AW13 74.75,60.22 v1(74.42,59.89) ; WLAN1.36 161.75,86 162.1,86.36 v1(162.1,86.82) ; v1(88.76,40.77) 89.11,40.42 CPU1.C39 CPU1.B39 ; v1(88.76,40.77) 88.76,40.75 88.43,40.42 CPU1.C37 ; 73.48,52.44 CPU1.AE10 73.23,52.69 73.23,53.45 CPU1.AG10 ; CPU1.AW33 86.14,60.22 86.51,59.85 v1(86.64,59.85) 86.64,59.86 87,60.22 CPU1.AW35 ; v1(89.03,48.72) 89.3,48.99 CPU1.W39 89.3,49.54 89.23,49.61 89.23,49.94 89.24,49.95 89.24,49.95 89.3,50.01 CPU1.AA39 89.15,50.47 89.15,51.27 CPU1.AC39 ; 61.77,84.49 61.6,84.66 LCD1.32 61.6,86 v1(61.62,86.02) ; CPU1.BA7 71.7,61.63 71.68,61.65 71.68,62.18 v1(71.04,62.82) ; LCD1.14 52.6,84.26 v1(52.59,84.25) ; WLAN1.45 154.28,83.75 154.99,84.46 v1(154.99,84.56) 155.08,84.46 155.08,82.52 154.82,82.25 WLAN1.51 ; v1(136.36,91.02) 136.39,91.05 IOBD1.14 ; CPU1.R3 69.71,46.81 v1(69.71,46.47) ; WLAN1.63 154.81,79.25 154.99,79.43 v1(154.99,80.44) 154.92,80.44 154.61,80.75 WLAN1.57 ; v1(74.47,40.67) 74.72,40.42 CPU1.C13 CPU1.B13 ; IOBD1.33 v1(136.32,81.55) ; PR4413.1 21.81,52.84 22.17,52.48 v1(22.68,52.48) 22.68,52.88 PQ4414.4 ; v1(78.18,62.66) 78.21,62.64 78.21,62.18 78.3,62.09 CPU1.BA19 ; RN1708.2 64.98,52.53 v1(65.29,52.85) 64.95,53.18 RN1708.1 ; v1(53.95,84.35) 54.02,84.42 54.02,84.43 54.05,84.46 54.05,84.61 54.1,84.66 LCD1.17 ; CPU1.AW15 76.25,60.22 v1(76.53,59.94) 76.59,60 76.98,60 CPU1.AW17 77.4,60.22 77.5,60.12 78.2,60.12 CPU1.AW19 ; CPU1.AJ3 69.5,54.39 v1(69.76,54.13) 69.73,54.13 69.5,53.9 CPU1.AG3 69.5,53.31 69.57,53.24 69.57,52.91 69.5,52.84 CPU1.AE3 69.5,52.17 69.54,52.13 69.54,52.1 v1(69.69,51.95) ; v1(83.11,59.13) 83.39,59.13 CPU1.AU29 ; CPU1.A13 74.67,38.69 v1(74.4,38.69) ; CPU1.C3 69.66,40.58 v1(69.66,40.97) 70.05,40.97 CPU1.C5 ; IOBD1.24 136.43,86.05 v1(136.35,86.13) ; v1(79.84,59.97) 79.85,59.98 80.05,59.98 80.29,60.22 CPU1.AW23 ; v1(80.49,63.27) 80.5,63.27 CPU1.BA23 ; v1(71.38,57.58) 71,57.2 CPU1.AN5 ; CPU1.AG7 71.8,53.74 72.01,53.95 v1(72.01,54.15) ; v1(69.66,42.07) 69.66,41.68 CPU1.E3 ; CPU1.AC10 73.4,51.72 73.43,51.75 73.43,51.89 v1(73.51,51.97) ; CPU1.AR23 80.5,57.97 81.02,58.48 81.02,58.51 v1(81.04,58.54) ; 89.01,47.57 89.3,47.86 CPU1.U39 ; 89.01,47.57 v1(88.98,47.57) ; 89.01,47.57 89.3,47.28 CPU1.R39 ; PU6301.8 v1(41.39,87.23) ; CPU1.AA3 69.44,50.38 68.86,50.38 CPU1.AA2 ; v1(67.67,39.98) 67.64,39.96 67.64,39.32 67.94,39.02 CPU1.A2 ; v1(56.29,84.18) 56.29,84.28 56.1,84.47 LCD1.21 ; CPU1.L39 89.3,45.09 v1(88.98,45.41) 89.3,45.73 CPU1.N39 ; v1(106.5,95.56) 106.57,95.49 107,95.49 PU5401.4 ; Q7001.4 92.11,89.12 v1(91.77,88.77) ; CPU1.C29 84.12,40.74 84.2,40.74 v1(84.23,40.72) 84.4,40.72 84.7,40.42 CPU1.C31 85.07,40.59 v1(85.42,40.59) 85.45,40.56 CPU1.B32 ; WLAN1.18 v1(162.44,90.5) ; Q1701.4 56.48,55.92 56.13,56.26 v1(55.93,56.26) ; CPU1.AW39 89.14,60.06 89.14,59.28 CPU1.AU39 89.3,59.05 89.08,58.83 v1(89.08,58.62) 89.08,58.5 89.3,58.28 CPU1.AR39 ; TPAD1.4 35.5,13.16 35.2,13.47 v1(35.02,13.47) ; LCD1.29 60.1,84.69 59.8,84.38 v1(59.66,84.38) 59.6,84.45 LCD1.28 ; LCD1.11 51.1,84.19 v1(51.18,84.11) ; Q7001.1 94.28,90.67 94.64,91.03 v1(94.64,91.06) ; v1(38.66,85.73) 39.15,85.23 PU6301.4 ; CPU1.A23 80.5,38.52 v1(80.49,38.51) ; PQ4901.1 52.19,69.71 52.53,70.05 52.53,70.08 v1(52.55,70.11) ; PU5401.8 105.56,97.79 v1(105.84,98.07) ; v1(45.1,12.96) 45.1,12.85 44.78,12.53 Q6507.4 ; CPU1.BA15 75.84,61.88 v1(75.84,62.13) ; WLAN1.69 154.53,77.75 v1(155.17,77.12) 155.17,76.58 154.84,76.25 WLAN1.75 ; U6001.13 v1(147.22,53.72) ; CPU1.AJ39 89.3,54.43 89,54.14 v1(89,54.12) 89.3,53.82 CPU1.AG39 89.15,53.47 89.15,52.67 CPU1.AE39 ; CPU1.J39 89.3,43.61 v1(88.89,43.2) 89.3,42.78 CPU1.G39 ; CPU1.AL10 73,55.42 v1(73,55.41) 73,55.12 CPU1.AJ10 ; CPU1.AM25 81.75,56.32 v1(82.14,56.71) ; CPU1.AW27 82.51,60.22 82.32,60.03 v1(82.12,60.03) 81.99,60.03 81.8,60.22 CPU1.AW25 ; ED3502.2 18.14,45.95 C3509.2 18.24,45.62 ED3503.2 18.57,44.58 C3510.2 ; WLAN1.39 v1(154.94,85.25) ; WLAN1.33 v1(154.94,86.75) ; CPU1.AW29 83.58,60 83.21,60 v1(83.16,59.95) ; CPU1.AW5 70.23,59.85 70.23,59.82 v1(70.31,59.74) ; CPU1.W3 69.5,48.98 69.8,48.67 v1(69.8,48.63) 69.5,48.33 CPU1.U3 CPU1.U2 ; CPU1.AN39 89.3,56.63 89,56.34 v1(89,56.31) 89,56.31 89.3,56.01 CPU1.AL39 ; WLAN1.30 v1(162.44,87.5) ; CPU1.AJ5 71,55.09 v1(70.78,55.31) ; CPU1.AU3 69.67,58.95 69.67,58.65 v1(69.7,58.62) 69.67,58.6 69.67,58.39 69.5,58.22 CPU1.AR3 69.5,57.96 69.57,57.89 69.57,57.3 69.5,57.23 CPU1.AN3 ; LCD1.8 v1(49.6,84.39) ; WLAN1.24 v1(162.44,89) ; v1(67.92,62.03) 68.05,61.9 68.05,61.24 68.08,61.21 68.08,61.04 CPU1.AY1 ; CPU1.AW7 71.84,60.22 72.21,59.84 v1(72.21,59.79) 72.24,59.79 72.43,59.98 72.56,59.98 CPU1.AW9 ; G1702.1 64.14,54.64 v1(63.5,54) 62.81,54.69 G1701.1 62.51,54.59 61.59,54.59 R2008.2 ; v1(24.79,55.16) 24.79,55.3 24.63,55.46 PQ4405.1 ; v1(51.56,80.49) 51.09,80.02 Q1702.4 ; v1(59.16,55.02) 59.11,54.97 59.11,54.89 58.69,54.47 Q1701.1 ; U6001.18 v1(147.22,54.43) ; ED5501.2 59.79,80.9 59.44,81.26 v1(59.44,81.48) ; WLAN1.29 v1(154.94,87.75) ; CPU1.N3 69.69,45.73 v1(69.69,45.37) 69.69,45.01 CPU1.L3 ; WLAN1.23 v1(154.94,89.25) ; IOBD1.27 136.56,84.55 136.5,84.61 v1(136.37,84.61) ; v1(83.2,41.52) 83.4,41.52 CPU1.E29
  BOTTOM w0.356: v1(46.64,10.11) 46.63,10.12 46.41,10.12 Q6507.1 ; CPU1.AR31 85.25,58.27 85.27,58.27 v1(85.34,58.35) ; CPU1.AW21 79.58,60.22 79.83,59.97 v1(79.84,59.97) ; RN1710.1 66.21,64.55 v1(66.93,63.83) ; CPU1.AA5 71,50.23 70.57,49.8 v1(70.57,49.71) ; CPU1.W19 78.2,49.45 ; CPU1.AR19 78.32,57.92 v1(78.72,58.32) 78.92,58.52 78.92,58.52 79.02,58.62 79.3,58.62 CPU1.AU21 ; v1(22.76,58.17) 22.96,58.17 PQ4405.4 ; CPU1.AR11 73.49,58.33 v1(73.31,58.33) 73.19,58.33 CPU1.AU9 ; PQ4901.4 50.89,71.95 PC4907.2 ; v1(85.37,60) 85.35,60 85.13,60.22 CPU1.AW31 ; v1(80,44.01) CPU1.H23 CPU1.G23 79.7,41.92 CPU1.E21 ; Q1702.1 52.72,77.23 52.93,77.45 v1(52.96,77.45) ; CPU1.AU25 81.43,58.72 81.24,58.54 v1(81.04,58.54) ; v1(71.33,51.94) 71.8,51.47 CPU1.AC7 ; v1(72.27,56.29) 72.18,56.29 71.8,55.91 CPU1.AL7 ; v1(82.14,57.38) 82.25,57.38 82.7,57.83 CPU1.AR27 ; RN1710.2 66.21,66.25 v1(66.07,66.4)
  BOTTOM w0.381: v1(144.02,55.5) 143.81,55.7 R6007.2 ; v1(62.31,48.06) 62.28,48.06 R1614.1 ; v1(73.76,47.47) 73.74,47.49 73.74,47.78 CPU1.U10 ; v1(149.61,85.02) 149.61,85.6 C2741.2 ; CPU1.L13 75.4,45.36 75.09,45.68 74.98,45.68 v1(74.93,45.73) ; CPU1.AE5 71,52.27 v1(71.33,51.94) ; v1(61.59,34.06) 61.57,34.04 U2404.2 ; v1(63.75,36.17) 63.75,36.12 63.61,35.97 63.17,35.97 63.17,35.84 C2445.2
  BOTTOM w0.406: v1(27.03,76.4) 27,76.38 EC4304.2 27,74.8 EC4306.2 ; v1(16.69,83.31) 16.76,83.24 16.76,83.15 17.45,82.47 Q5707.S ; KB1.30 79.32,13.18 v1(78.79,13.18) ; CPU1.E25 v1(82.14,42.31)
  BOTTOM w0.457: PC5303.2 144.88,50.78 144.88,51.51 v1(144.91,51.54)
  BOTTOM w0.508: C4016.2 C1078.2 v1(58.5,60.99) ; C6012.2 144.7,57.63 v1(144.91,57.43) ; EC1601.2 83.39,69.88 83.19,69.67 v1(83.19,69.55) ; v1(102.08,98.4) 102.08,98.49 102.86,99.26 PC5412.2 ; PC4304.2 v1(19.91,60.99) 19.61,60.68 C3609.2 ; v1(80.14,85.02) 80.44,84.71 C4018.2 ; v1(14.78,42.85) 15.32,42.85 15.82,42.34 15.82,42.32 16.13,42.02 ED3302.3 ; v1(93.9,29.41) 94.26,29.06 C2602.2 ; SD1.4 v1(15.38,27.9) ; DCIN1.7 20.04,81 v1(20.68,80.37) ; v1(142.39,40.95) 142.9,40.95 C6016.2 ; v1(64.8,56.95) 64.54,56.95 R1717.1 ; C1008.2 57.67,43.55 PC4709.2 56.52,43.16 v1(56.52,42.01) ; v1(121.74,98.88) 122.89,98.88 PU5302.1 ; ED3505.2 18.06,52.35 v1(17.65,52.76) ; C2403.2 37.95,32.67 37.57,32.29 v1(37.57,31.9) 37.57,31.57 C4004.2 ; PR4512.2 6.7,13.25 v1(6.62,13.34) ; v1(17.55,9.51) PC4507.2 17.48,10.97 PC4518.2 ; EC6601.2 v1(133.76,86.92) ; PQ4304.2 11.67,66.29 11.35,65.97 v1(11,65.97) 10.95,66.01 PD4303.1 ; PR5405.2 108.89,98.43 v1(108.58,98.12) ; 8.62,83.13 HDMI1.20 9.68,85.45 ; v1(27,8.31) 26.54,8.77 EC6503.2 ; PC4468.1 v1(131.78,35.33) ; v1(89.99,101.09) 90.7,101.09 EC2901.2 ; v1(152.2,89.77) 151.75,89.32 C2720.2 151.71,88.77 151.71,87.56 C2740.2 ; R1756.1 83.69,66.75 83.49,66.96 83.49,67.06 v1(83.29,67.26) ; v1(126.16,9.4) 125.56,8.8 BATT1.11 ; 134.29,72.42 133.96,72.75 132.99,72.75 132.94,72.7 ; v1(85.27,25.5) 85.27,26.14 C803.1 ; PC5304.2 140.07,53.27 139.52,52.72 v1(139.52,51.51) ; v1(127.15,16.54) 127.61,16.08 PC4464.2 ; C5519.2 67.72,80.9 67.59,80.77 v1(67.59,80.7) ; v1(113.89,89.96) 113.89,89.52 114,89.4 DIMM1.261 ; R6504.2 45.55,13.3 45.21,12.96 v1(45.1,12.96) ; PQ4309.S 15.33,66.76 14.81,67.29 v1(14.53,67.29) ; v1(91.77,17.22) 91.72,17.22 91.69,17.25 EC2602.2 ; PC4419.2 135.25,36.73 v1(134.67,36.73) ; C6018.2 145.01,29.82 144.65,30.18 144.42,30.18 v1(144.4,30.2) ; SPK1.5 80.92,95.3 v1(81.15,95.07) ; v1(62.68,22.78) 62.72,22.74 R2442.2 ; PR5208.2 27.71,73.81 v1(27.71,73.61) ; v1(63.09,67.03) 63.78,67.03 63.99,66.83 C1703.2 ; R5508.1 65.43,76.43 65.86,76 v1(65.89,76) ; v1(78.33,102.24) 78.33,101.7 79.14,100.9 SPK1.6 ; v1(59.89,52.07) 59.92,52.05 60.17,52.05 60.55,51.67 R1718.1 ; v1(9.86,17.35) 9.74,17.2 PR4508.2 ; v1(142.44,37.67) C6017.2 ; C2401.2 C2445.2 ; DIMM1.262 113.39,19.09 v1(113.39,17.57) ; PC5318.2 126.34,96.01 126.52,95.84 v1(126.52,94.67) ; PC4904.2 55.85,76.18 v1(56.49,76.81) ; C6014.2 144.2,30.91 144.15,30.86 v1(144.15,30.81) 144.09,30.81 143.87,30.58 PC4462.1 ; PC4306.2 v1(18.8,66.3) ; C1701.2 93.6,82.58 93.09,83.09 v1(92.38,83.09) ; C2742.2 151.28,94.49 v1(150.88,94.08) C2743.2 ; v1(57.65,38.05) 57.45,38.25 57.45,38.28 57.08,38.65 56.91,38.65 U2502.1 ; 42.72,13.92 42.26,13.46 v1(42.26,13.25) ; EC8901.2 37.03,23.4 v1(36.6,23.83) 36.53,23.9 36.49,23.9 35.94,24.45 C4003.2 ; PC6301.2 41.5,88.9 v1(41.83,88.57) 42.11,88.29 PC6304.2 ; v1(133.22,42.18) 132.51,42.18 132.01,42.69 PC5302.2 ; PR5309.2 138.36,40.29 v1(138.99,40.29) 139.01,40.29 PC5314.2 ; PC5418.2 PU5402.2 v1(70.79,23.5) 70.76,23.47 70.76,21.79 71.27,21.29 EC6506.2 ; C6005.2 144.91,28.12 144.4,28.63 v1(144.4,29.01) ; ED3303.3 8.51,42.11 v1(7.9,42.11) ; C4011.2 77.93,84.1 v1(77.98,84.15) ; PC4445.2 139.04,27.05 138.79,26.8 v1(138.79,26.75) ; DCIN1.8 v1(26.8,82.52) ; PU4901.2 55.47,70.97 55.02,71.43 v1(54.86,71.43) 54.46,71.02 PC4905.2 ; PQ4414.1 24.79,54.64 v1(24.79,55.16) ; v1(106.73,97.99) 106.53,97.79 PU5401.9 106.53,95.58 v1(106.5,95.56) ; PC4706.2 34.47,47.83 33.94,47.29 v1(33.94,46.76) ; C2606.2 38.23,36.63 Q2401.C 38.1,36.73 v1(37.54,36.17) ; v1(131.42,88.22) 132.08,88.22 C1222.2 ; v1(85.62,68.23) 85.57,68.18 R1636.1 ; v1(33.15,33.91) 32.92,33.68 PC4514.2 ; PC5315.2 116.03,95.48 v1(115.7,95.81) 115.44,96.06 PC5316.2 ; EC2903.2 v1(89.99,97.87) ; EC4303.2 121.42,15.24 121.42,16.25 v1(121.39,16.28) ; C2439.2 39.45,31.07 39.07,30.68 v1(39.07,30.3) ; v1(143.74,33.94) 143.74,33.76 144.2,33.3 C6015.2 ; EC5503.2 37.05,82.91 v1(36.58,82.43) 36.86,82.15 EC5502.2 ; PC4403.2 v1(140.41,36.83) ; v1(141.3,30.2) 141.78,29.72 PC4461.1 ; v1(50.27,71.96) PC4907.2 ; v1(105.05,98.12) 104.72,98.45 PC5411.2 ; C4030.2 86.11,79.48 v1(86.08,79.45) 86.08,79.38 86.1,79.35 Q4001.S ; v1(148.39,93.85) 148.41,93.83 148.41,93.3 C2724.2 ; EC5510.2 68.07,83.92 68.05,83.94 68.05,84.15 67.82,84.38 v1(67.54,84.38) 67.54,84.3 67.26,84.02 C5520.2 ; C3510.2 18.57,43.44 v1(18.69,43.31) ; PC5420.2 67.71,24.21 Q2402.S 66.76,23.51 67.08,23.19 v1(67.08,23.06) 67.36,23.06 67.59,23.29 PC5419.2 ; Q2507.S 70.81,18.03 R2516.2 69.83,18.1 v1(69.41,18.1) ; EC2902.2 v1(92.13,97.84) ; R2505.2 128.83,97.56 v1(129.21,97.94) ; C4010.1 v1(82.8,80.57) ; PR4416.2 135.25,37.64 135.05,37.44 135.03,37.44 134.95,37.37 v1(134.8,37.37) ; PC4506.2 v1(24.78,12.22) ; C4009.2 C4008.2 58.39,64.24 v1(58.42,64.26) 58.45,64.24 C4015.2 ; v1(89.27,80.84) 89.41,80.84 89.44,80.87 90.16,80.87 91,80.03 SPR2.1 ; PQ4412.S 131.52,16.96 v1(131.52,16.89) 131.32,16.69 PC4471.2 ; v1(159.97,102.24) 159.53,101.8 RTC1.3 ; C4027.2 C6303.2 86.59,83.11 v1(86.16,82.68) ; C1055.2 83.41,78.56 83.92,79.07 84.18,79.07 v1(84.23,79.12) ; PR4903.2 54,74.24 53.92,74.32 53.92,74.45 53.7,74.68 PC4903.2 ; PR4903.2 54.13,74.04 PC4906.2 ; PR4903.2 53.77,73.91 53.26,73.4 v1(53.26,73.23) ; IOBD1.45 139.85,98.5 v1(139.85,98.35) ; v1(17.56,69.22) 18.19,69.85 PR4302.2 ; FC6002.2 142.88,40.11 v1(142.44,40.11) ; v1(45.29,15.67) 45.23,15.67 45.21,15.65 Q2405.S ; v1(71.07,81.71) 71.07,81.69 70.84,81.46 C5512.2 ; v1(158.37,97.11) 157.27,98.2 RTC1.4 155.5,99.5 RTC1.2 ; TPAD1.10 29.95,9.07 v1(30.73,9.07) ; v1(85.83,72.37) 85.83,72.32 86.11,72.04 C804.2 ; PR4506.2 v1(10.54,17.35) ; C2508.2 58.78,42.67 59.33,42.11 59.33,41.76 v1(59.51,41.58) ; PC4405.2 142.2,37.03 142.18,37.03 141.98,37.24 v1(141.91,37.24) 141.78,37.11 141.78,35.86 PR4405.2 ; Q2502.S 130.86,98.3 130.89,98.33 v1(130.89,98.6) ; ED3301.3 15.93,35.81 15.8,35.94 v1(15.8,36.01) ; PC5410.2 98.88,95.58 v1(98.88,94.9) ; v1(62.87,51.31) 62.99,51.18 R1721.1 ; v1(61.65,74.37) 61.75,74.27 PC4901.2 62.59,74.27 62.84,74.02 63.07,74.02 PC4902.2 ; LCD1.42 67.73,88.83 v1(68.1,88.83) ; R3605.2 19.35,61.62 v1(19.91,61.62) 20.07,61.77 PC4305.2 ; v1(24.27,59.93) 24.05,59.72 PR4436.2 ; v1(60.11,31.55) 60.14,31.51 60.14,31.42 60.68,30.89 C2432.2 61.14,30.89 61.24,30.79 61.49,30.79 61.9,30.38 C2433.2 ; C2507.2 54.43,37.14 C2441.2 C2429.2 53.47,36.88 53.04,36.88 C2402.2 52.55,36.4 52.53,36.4 52.25,36.12 v1(51.97,36.12) ; C4017.2 80.54,86.39 v1(80.06,86.87) ; PC5317.2 116.15,98.58 116.26,98.68 PC5320.2 116.89,98.66 v1(116.89,97.97) ; v1(39.45,9.22) 39.47,9.2 TPAD1.9 ; R2415.2 47.19,38.86 47.32,38.99 v1(47.32,39.32) ; C1602.1 62.97,40.03 62.44,40.56 X1601.4 62.35,39.98 61.84,39.47 v1(61.72,39.47) ; C2721.2 150.22,89.79 v1(150.24,89.77) ; v1(140.51,59.44) 140.18,59.44 139.67,58.93 PC5308.2 ; PC4435.2 v1(141.22,28.04) ; IOBD1.46 v1(142.06,74.35) ; v1(141.9,35.15) 141.9,34.99 PC4406.2 ; v1(34.81,80.77) U6305.4 34.41,81.61 33.95,81.15 31.5,81.15 PC5202.2 ; v1(42.77,84.38) 42.63,84.52 PR6301.2 ; v1(14.5,68.02) 14.24,68.29 PQ4302.E ; v1(134.82,29.8) 134.82,29.48 134.81,29.47 134.81,29.06 134.44,28.69 PC4453.2 ; R6008.2 141.6,57 141.96,57.35 v1(142.85,57.35) 143,57.35 143.05,57.41 143.26,57.41 C6013.2 ; EC5501.2 v1(37.24,80.62) ; C2428.1 40.87,36.02 R4014.2 42.52,35.94 R2428.1 42.65,36.07 42.65,36.25 43.23,36.83 43.94,36.83 v1(43.94,36.83) ; v1(28.04,81.03) 28.07,81 28.07,80.85 28.14,80.77 PC5201.2 ; C6305.2 86.36,87.33 v1(86.39,86.92) ; C3608.2 18.44,56.29 18.67,56.06 v1(19.13,56.06) ; USB1.13 15.05,62.35 16.21,63.5 16.57,63.5 U3601.2 ; PC4402.2 139.57,37.31 v1(139.57,36.83) ; R2011.2 v1(80.89,69.57) 80.9,69.57 R2012.2 ; v1(47.57,25.94) 46.94,26.57 44.77,26.57 44.4,26.2 v1(44.4,25.94) ; C6304.2 85.81,90.9 v1(86.13,90.58) ; v1(101.35,14.05) R6515.1 ; v1(46.53,61.04) 47.04,61.55 PC4718.2 ; v1(45.21,88.39) 45.11,88.39 45.11,88.4 LCD1.41 ; PR4507.2 v1(9.5,10.41) ; PR4412.2 142.14,26.7 v1(142.44,26.39) ; PC6305.2 37.44,85.63 v1(37.34,85.73) 37.31,85.75 PC6302.2 ; KB1.32 77.91,9.8 77.7,10.01 v1(77.24,10.01) ; v1(86.51,67.54) R1761.1 ; C1704.2 64.36,62.28 64.21,62.28 64.01,62.49 64.01,62.54 v1(63.93,62.61) ; EC6603.2 v1(133.83,88.88) ; C1702.1 59.56,54.92 59.26,54.92 v1(59.16,55.02) ; v1(83.24,72.95) 83.46,72.72 R2010.2 83.36,71.73 C1603.2 ; R1719.1 56.29,56.62 v1(55.93,56.26) ; PC4517.2 9.39,15.11 9.33,15.17 v1(9.33,15.18) ; v1(75.56,68.81) 75.56,68.76 75.69,68.63 R1621.1 ; PC5313.2 142.24,43.13 142.7,42.67 v1(142.75,42.67) ; v4(85.52,85.8) 85.22,86.11 84.76,86.11 C6349.2 ; C2430.2 C2431.2 60.2,27.43 59.61,26.85 59.61,26.6 v1(59.59,26.57) ; U5501.2 v1(63.25,79.73) ; v1(26.44,55.98) 26.44,56.11 26.47,56.14 PR4433.2 ; C5514.2 v1(71.04,82.4) ; PC4505.2 17.58,28.98 v1(17.04,29.52) ; D4302.1 99.31,14.85 96.19,14.85 D4303.1 95.4,14.32 v1(95.4,14.07) 94.01,14.07 v1(93.98,14.1) 93.52,14.56 D4301.1 ; v1(142.75,41.86) PC5312.2 ; EC2904.2 90.86,94.41 91.26,94.01 v1(91.49,94.01) ; v1(78.41,68.84) 78.36,68.78 R1620.1 ; PC4467.1 v1(135.51,36.1) ; X1601.2 v1(59.69,42.91) ; PR4478.2 20.88,45.39 C3508.2 ; v1(69.34,64.19) 69.16,64.19 68.58,64.77 R1723.1 ; C6302.2 86.16,84.72 v4(86.17,84.71) ; PU4705.7 v3(37.97,53.54) ; v1(79.5,36.53) 78.44,36.53 78.03,36.12 R803.2 ; Q5701.S 15.36,81.7 15.57,81.92 v1(15.7,81.92) ; R2507.2 60.78,24.64 v1(60.86,24.72) 60.86,25.06 Q2505.S ; R6012.2 150.8,55.4 C6011.2 150.83,55.2 v1(151.21,54.81) ; PR5316.2 124.69,99.16 124.31,98.78 v1(124.31,98.73) ; v1(144.17,54.61) R6010.2 ; PC5307.2 v1(143,45.26) ; EC6602.2 v1(133.76,88.01)
  BOTTOM w0.635: HDD1.23 151.58,49.45 ; HDD1.23 150,48.41 ; HDD1.23 148.42,49.45 ; USB1.11 5.39,63.29 ; USB1.11 6.83,62.35 ; USB1.11 3.95,62.35 ; HDMI1.22 9.68,70.74 ; HDMI1.22 11.45,69.75 ; HDMI1.22 9.68,68.76 ; 150,11.21 HDD1.24 ; HDD1.24 151.58,12.25 ; HDD1.24 148.42,12.25 ; HDD1.24 150,13.29 ; 148.84,27.68 HDD1.P5 150.36,27.68 ; 150.36,21.33 HDD1.P10 148.84,21.33 ; 150.36,18.79 HDD1.P12 148.84,18.79 ; 150.36,39.11 HDD1.S7 149.6,38.41 ; 150.36,28.95 HDD1.P4 148.84,28.95 ; HDMI1.23 3.95,67.85 ; HDMI1.23 2.7,66.86 ; HDMI1.23 1.45,67.85 ; 5.39,45.71 USB1.10 ; USB1.10 3.95,46.65 ; USB1.10 6.83,46.65 ; 3.95,86.15 HDMI1.21 1.45,86.15 ; 12.89,63.29 USB1.13 11.35,62.35 ; HDD1.S1 149.6,47.42 ; HDD1.S1 148.84,46.73 ; HDD1.S1 150.36,46.73 ; 12.89,45.71 USB1.12 11.35,46.65 ; 10.62,73 HDMI1.2 9.98,72.44
  BOTTOM w0.711: PT4707.2 v3(31.37,68.53)
  vias: v1(0.81,18.06) v1(0.76,8.04) v1(0.76,5.5) v1(0.79,3.1) v1(1.12,87) v1(1.09,85.65) v1(1.07,68.38) v1(1.09,1.17) v1(1.36,16.31) v1(1.56,9.79) v1(2.44,40.57) v1(2.36,38.56) v1(2.41,37.29) v1(2.41,35.89) v1(2.39,34.04) v1(2.74,46.66) v1(2.74,44.12) v1(2.79,62.23) v1(3.02,0.76) v1(3.26,13.15) v1(3.47,35.56) v1(4.5,85.63) v1(4.55,18.06) v1(4.63,87.09) v1(4.6,68.38) v1(5.41,33.94) v1(5.64,87.09) v1(5.64,85.61) v1(5.66,0.76) v1(6.58,38.46) v1(6.61,18.08) v1(6.68,39.55) v1(6.91,68.39) v1(6.88,40.34) v1(7.09,33.92) v1(7.72,62.23) v1(7.7,46.79) v1(8.18,87.09) v1(8.46,39.07) v1(9.57,62.21) v1(9.73,34.24) v1(9.75,35.41) v1(9.88,42.45) v1(10.24,46.79) v1(10.51,44.84) v1(10.72,87.09) v1(10.97,40.16) v1(11.64,18.08) v1(11.66,34.24) v1(11.89,41.07) v1(11.94,40.13) v1(11.96,39.19) v1(12.12,86.06) v1(12.17,12.65) v1(12.37,35.41) v1(12.73,12.12) v1(12.84,59.91) v1(12.85,49.1) v1(12.88,40.16) v1(13.11,33.96) v1(13.22,18.08) v1(13.23,12.65) v1(13.72,87.07) v1(13.89,37.9) v1(14.23,18.08) v1(14.2,0.76) v1(14.55,87.02) v1(14.58,33.66) v1(14.88,44.83) v1(15.01,43.54) v1(15.06,32.44) v1(15.19,22.8) v1(15.39,18.22) v1(15.85,80.67) v1(15.88,22.23) v1(15.98,18.89) v1(16.06,21.32) v1(16.07,20.5) v1(16.07,19.67) v1(16.28,84.36) v1(16.28,0.76) v1(16.41,2.72) v1(16.71,78.61) v1(16.91,23.08) v1(17.2,4.04) v1(18.34,87.09) v1(18.82,0.76) v1(19.66,82.45) v1(19.91,64.95) v1(19.91,64.31) v1(20.12,70) v1(20.8,72.47) v1(20.8,71.58) v1(20.8,70.82) v1(20.8,70.05) v1(20.83,59.84) v1(20.83,59.21) v1(20.83,58.19) v1(20.83,57.53) v1(20.83,47.5) v1(20.88,87.09) v1(20.98,83.77) v1(21.36,0.76) v1(22.07,81.64) v1(22.23,82.68) v1(22.2,78.84) v1(23.42,87.09) v1(23.47,80.09) v1(25.96,87.09) v1(26.34,72.21) v1(26.92,72.82) v1(27,72.14) v1(27.41,38.28) v1(27.53,36.76) v1(27.84,0.76) v1(28.02,51.26) v1(28.5,87.09) v1(28.73,51.26) v1(28.98,0.76) v1(29.21,37.97) v1(29.44,52.71) v1(29.44,52) v1(29.46,51.26) v1(29.49,50.52) v1(29.51,49.84) v1(30.25,51.26) v1(30.72,6.29) v1(30.76,72.24) v1(30.94,51.26) v1(31.04,87.09) v1(31.52,0.76) v1(31.93,61.01) v1(31.9,60.23) v1(31.94,6.29) v1(33.58,87.09) v1(34.06,0.76) v1(34.92,77.37) v1(36.37,25.99) v1(36.6,0.76) v1(37.76,94.05) v1(39.14,0.76) v1(39.29,18.99) v1(39.95,86.23) v1(41.68,0.76) v1(43.13,96.24) v1(44.22,0.76) v1(44.42,91.39) v1(45.67,96.24) v1(45.79,90.93) v1(46.35,94.95) v1(46.76,0.76) v1(47.52,95.66) v1(49.23,95.66) v1(49.3,0.76) v1(50.04,80.47) v1(50.75,96.24) v1(51.84,0.76) v1(53.29,96.24) v1(53.85,80.06) v1(54.33,79.4) v1(54.38,0.76) v1(54.64,67.67) v1(56.92,0.76) v1(57.33,50.34) v1(57.58,71.6) v1(58.34,67.29) v1(58.39,66.4) v1(58.45,65.53) v1(58.55,70.44) v1(58.57,72.77) v1(58.57,71.6) v1(59.32,93.02) v1(59.46,0.76) v1(59.61,77.73) v1(60.91,96.24) v1(62,0.76) v1(62.89,86.04) v1(63.3,71.71) v1(63.45,96.24) v1(65.28,32.67) v1(65.99,96.24) v1(68.53,96.24) v1(72.29,40.74) v1(73.48,32.82) v1(73.53,30.08) v1(73.61,102.24) v1(73.89,49.76) v1(73.92,46.71) v1(74.14,31.8) v1(74.32,100.56) v1(74.47,101.5) v1(74.47,41.4) v1(74.7,0.76) v1(74.8,29.19) v1(74.85,49.91) v1(74.98,31.09) v1(75.51,58.45) v1(75.56,40.7) v1(75.88,53.63) v1(75.91,51.8) v1(75.95,29.8) v1(76.14,2.34) v1(76.15,102.24) v1(76.5,18.69) v1(76.71,100.28) v1(77.79,57.47) v1(77.79,51.75) v1(77.87,53.65) v1(78.33,4.27) v1(78.92,40.67) v1(79.04,89.31) v1(79.79,53.75) v1(79.83,46.74) v1(79.9,51.82) v1(79.9,49.82) v1(79.9,47.82) v1(79.9,45.82) v1(80.31,4.27) v1(80.9,49.82) v1(81.23,102.24) v1(81.85,53.72) v1(81.9,51.82) v1(81.94,25.05) v1(82.6,4.27) v1(83.77,102.24) v1(83.9,50.82) v1(83.98,53.81) v1(84.35,56.2) v1(85.42,4.27) v1(85.47,44.25) v1(85.55,17.71) v1(86.31,102.24) v1(87.81,64.14) v1(88.16,36.68) v1(88.78,4.27) v1(88.85,102.24) v1(89,35.05) v1(89.56,65.03) v1(90.09,25.6) v1(91.19,61.6) v1(91.77,102.24) v1(92.63,61.76) v1(92.85,39.5) v1(93.08,4.27) v1(93.73,63.48) v1(93.93,102.24) v1(94.23,38.16) v1(95.5,58.68) v1(96.47,102.24) v1(97.61,41.12) v1(97.69,58.73) v1(98.21,4.29) v1(99.01,102.24) v1(99.67,41.16) v1(101.55,102.24) v1(103.61,4.27) v1(104.01,11.81) v1(104.09,102.24) v1(106.26,1.32) v1(106.63,102.24) v1(108.72,0.76) v1(109.17,102.24) v1(111.05,12.14) v1(111.26,0.76) v1(111.71,102.24) v1(113.8,0.76) v1(114.25,102.24) v1(116.34,0.76) v1(116.79,102.24) v1(118.88,0.76) v1(119.33,102.24) v1(120.45,56.59) v1(120.62,60.48) v1(120.65,51) v1(121.87,102.24) v1(124.41,102.24) v1(126.26,33.94) v1(126.62,27.92) v1(126.92,71.81) v1(126.95,102.24) v1(127.03,64.21) v1(127.28,79.33) v1(127.3,76.76) v1(128.65,86.44) v1(129.18,14.35) v1(129.24,13.72) v1(129.49,102.24) v1(129.69,93.14) v1(130.56,13.08) v1(130.82,12.29) v1(130.78,10.85) v1(130.78,10.21) v1(131.58,0.76) v1(131.67,92.89) v1(132.03,102.24) v1(134.12,0.76) v1(134.85,75.87) v1(135.31,63.73) v1(136.66,0.76) v1(137.03,34.19) v1(137.03,33.22) v1(137.03,32.21) v1(138.02,34.22) v1(138.05,33.22) v1(138.07,32.21) v1(138.86,78.74) v1(138.94,34.22) v1(138.96,33.22) v1(139.01,32.21) v1(139.45,78.16) v1(142.9,47.8) v1(143.03,74.82) v1(143.54,47.8) v1(144.26,75.89) v1(144.37,90.35) v1(144.73,21.11) v1(144.92,76.55) v1(145.14,90.37) v1(145.21,83.8) v1(145.62,77.2) v1(145.92,91.9) v1(145.92,91.16) v1(145.92,90.37) v1(145.92,89.64) v1(145.92,88.85) v1(146.69,90.37) v1(146.99,40.9) v1(147.07,42.98) v1(147.22,55.22) v1(147.17,44.99) v1(147.45,90.37) v1(150.23,62.25) v1(150.7,63.98) v1(150.98,51.61) v1(151.38,70.82) v1(151.69,62.87) v1(151.66,60.45) v1(151.71,56.39) v1(151.74,53.34) v1(151.74,45.72) v1(151.74,43.18) v1(151.74,40.64) v1(151.74,38.1) v1(151.74,35.56) v1(151.74,33.02) v1(151.74,30.48) v1(151.74,27.94) v1(151.74,25.4) v1(151.74,22.86) v1(151.74,20.32) v1(151.74,17.78) v1(151.74,15.24) v1(152.1,73.18) v1(152.17,76.96) v1(152.35,102.24) v1(154.89,102.24) v1(157.06,73.86) v1(159.6,73.86) v1(162.51,102.24) v1(164.14,75.86) v1(164.97,96.47) v1(165.05,102.24) v1(165.74,96.47) v1(166.68,75.86) v1(167.59,102.24) v1(170.13,102.24) v1(171.22,73.86) v1(172.39,97.99) v1(173.76,73.86) v1(175.92,98.2) v1(176.3,73.86) v1(178.14,97.36) v1(178.14,94.82) v1(178.14,92.28) v1(178.14,89.74) v1(178.14,87.2) v1(178.14,84.66) v1(178.14,82.12) v1(178.14,79.58) v1(178.14,77.04) v2(14.61,65.68) v2(18.2,20.16) v2(18.42,6.33) v2(28.35,52.26) v2(38.65,54.96) v2(45.56,44.08) v2(47.1,70.62) v2(49.34,41.89) v2(52.54,5.16) v2(53.47,68.05) v2(69.36,82.33) v2(97.9,62.27) v2(98.75,53.68) v2(98.66,38.36) v2(109.22,93.41) v2(113.79,19.51) v2(114.05,49.84) v2(117.87,57.17) v2(117.9,24.21) v2(118.13,46.35) v2(118.87,64.51) v2(120.51,80.68) v2(121.87,35.16) v2(125.41,91.02) v2(165.17,99.82) v2(165.72,92.79) v2(169.55,95.29) v2(171.17,92.29) v2(173.97,95.24) v3(17.33,13.81) v3(19.25,20.62) v3(19.25,19.73) v3(19.25,18.84) v3(19.81,77.95) v3(19.81,76.96) v3(20.04,23.42) v3(20.09,22.46) v3(20.65,78.39) v3(20.95,23.45) v3(20.95,22.43) v3(20.95,20.5) v3(20.95,19.64) v3(20.95,18.75) v3(21.13,75.85) v3(22.68,32.06) v3(22.68,30.58) v3(22.73,29.75) v3(23.93,29.77) v3(30.48,68.53) v3(31.34,71.68) v3(31.5,72.52) v3(32.08,39.96) v3(32.21,71.78) v3(32.26,68.53) v3(32.59,61.42) v3(32.59,60.56) v3(32.56,59.72) v3(32.66,78.92) v3(32.72,78.03) v3(32.66,72.52) v3(32.92,40.21) v3(33.5,78.92) v3(33.55,78.03) v3(34.37,78.92) v3(34.42,78.03) v3(35.03,39.16) v3(35.2,78.92) v3(35.28,78.03) v3(35.94,52.53) v3(35.92,39.16) v3(35.97,78.54) v3(35.97,69.01) v3(36.02,68.18) v3(35.99,53.54) v3(36.86,69.01) v3(36.86,68.18) v3(37.01,53.54) v3(36.96,52.53) v3(37.74,69.04) v3(37.69,68.2) v3(37.72,39.17) v3(37.85,52.53) v3(38.61,69.06) v3(38.56,68.2) v3(38.61,39.17) v3(38.86,53.54) v3(38.86,52.53) v3(39.1,18.14) v3(39.1,17.28) v3(39.1,16.39) v3(39.52,95.51) v3(39.5,68.91) v3(39.74,19.75) v3(39.75,53.54) v3(39.75,52.53) v3(40.08,16.31) v3(40.39,68.91) v3(40.64,53.54) v3(40.64,52.53) v3(40.67,95.51) v3(41.45,54.69) v3(41.53,53.54) v3(41.53,52.53) v3(41.88,95.51) v3(42.29,54.69) v3(42.42,53.54) v3(42.37,52.53) v3(43.18,54.69) v3(43.21,52.53) v3(43.26,53.54) v3(44.2,69.12) v3(45.03,69.12) v3(45.09,79.72) v3(45.64,45.85) v3(45.64,45.01) v3(45.92,79.73) v3(46.05,69.12) v3(46.55,67.01) v3(46.55,65.99) v3(46.55,64.97) v3(46.55,63.96) v3(46.48,44.91) v3(46.55,44.02) v3(46.55,43.13) v3(46.55,42.11) v3(46.55,41.23) v3(46.56,62.94) v3(46.76,79.78) v3(47.12,80.65) v3(47.07,69.12) v3(47.43,67.01) v3(47.43,65.99) v3(47.43,64.97) v3(47.43,63.96) v3(47.45,62.94) v3(47.37,44.91) v3(47.38,44.02) v3(47.38,43.13) v3(47.38,42.11) v3(47.38,41.23) v3(47.6,79.73) v3(47.96,80.65) v3(48.08,69.12) v3(48.44,79.73) v3(48.92,69.12) v3(49.11,54.94) v3(49.11,54.05) v3(49.07,52.2) v3(49.12,44.07) v3(49.12,39.78) v3(49.2,51.23) v3(49.42,43.17) v3(50,54.94) v3(50,54.05) v3(49.97,52.25) v3(50.09,51.23) v3(50.27,43.97) v3(50.27,42.95) v3(50.29,41.94) v3(50.29,41.05) v3(50.29,40.16) v3(50.69,65.75) v3(50.76,64.81) v3(50.85,67.72) v3(50.85,66.88) v3(50.89,54.94) v3(50.89,54.05) v3(50.86,52.25) v3(50.93,50.29) v3(50.99,51.23) v3(51.54,65.69) v3(51.77,64.77) v3(52.53,65.69) v3(52.63,54.94) v3(52.65,64.8) v3(52.68,49.61) v3(53.47,54.94) v3(53.52,49.61) v3(54.28,53.72) v3(54.39,51.84) v3(54.39,50.74) v3(54.48,49.61) v3(73.81,76.61) v3(73.86,78.41) v3(97.97,91.77) v3(99.26,91.19) v3(100.69,91.04) v3(101.57,91.06) v3(108.61,93.91) v3(109.86,93.91) v3(112.47,12.12) v3(113.31,12.12) v3(114.15,12.12) v3(123.14,16.77) v3(124,16.79) v3(124.84,16.79) v3(125.73,16.79) v3(131.83,23.27) v3(131.83,22.38) v3(131.83,21.39) v3(131.83,20.45) v3(134.01,63.6) v3(134.11,48.21) v3(134.11,47.37) v3(134.11,46.53) v3(134.11,45.7) v3(134.95,48.19) v3(134.95,47.35) v3(134.98,46.51) v3(134.98,45.67) v3(136.06,63.59) v3(140.62,24.67) v3(140.62,23.65) v3(140.67,25.58) v3(141.5,25.58) v3(141.5,24.69) v3(141.5,23.67) v4(53.52,89.87)
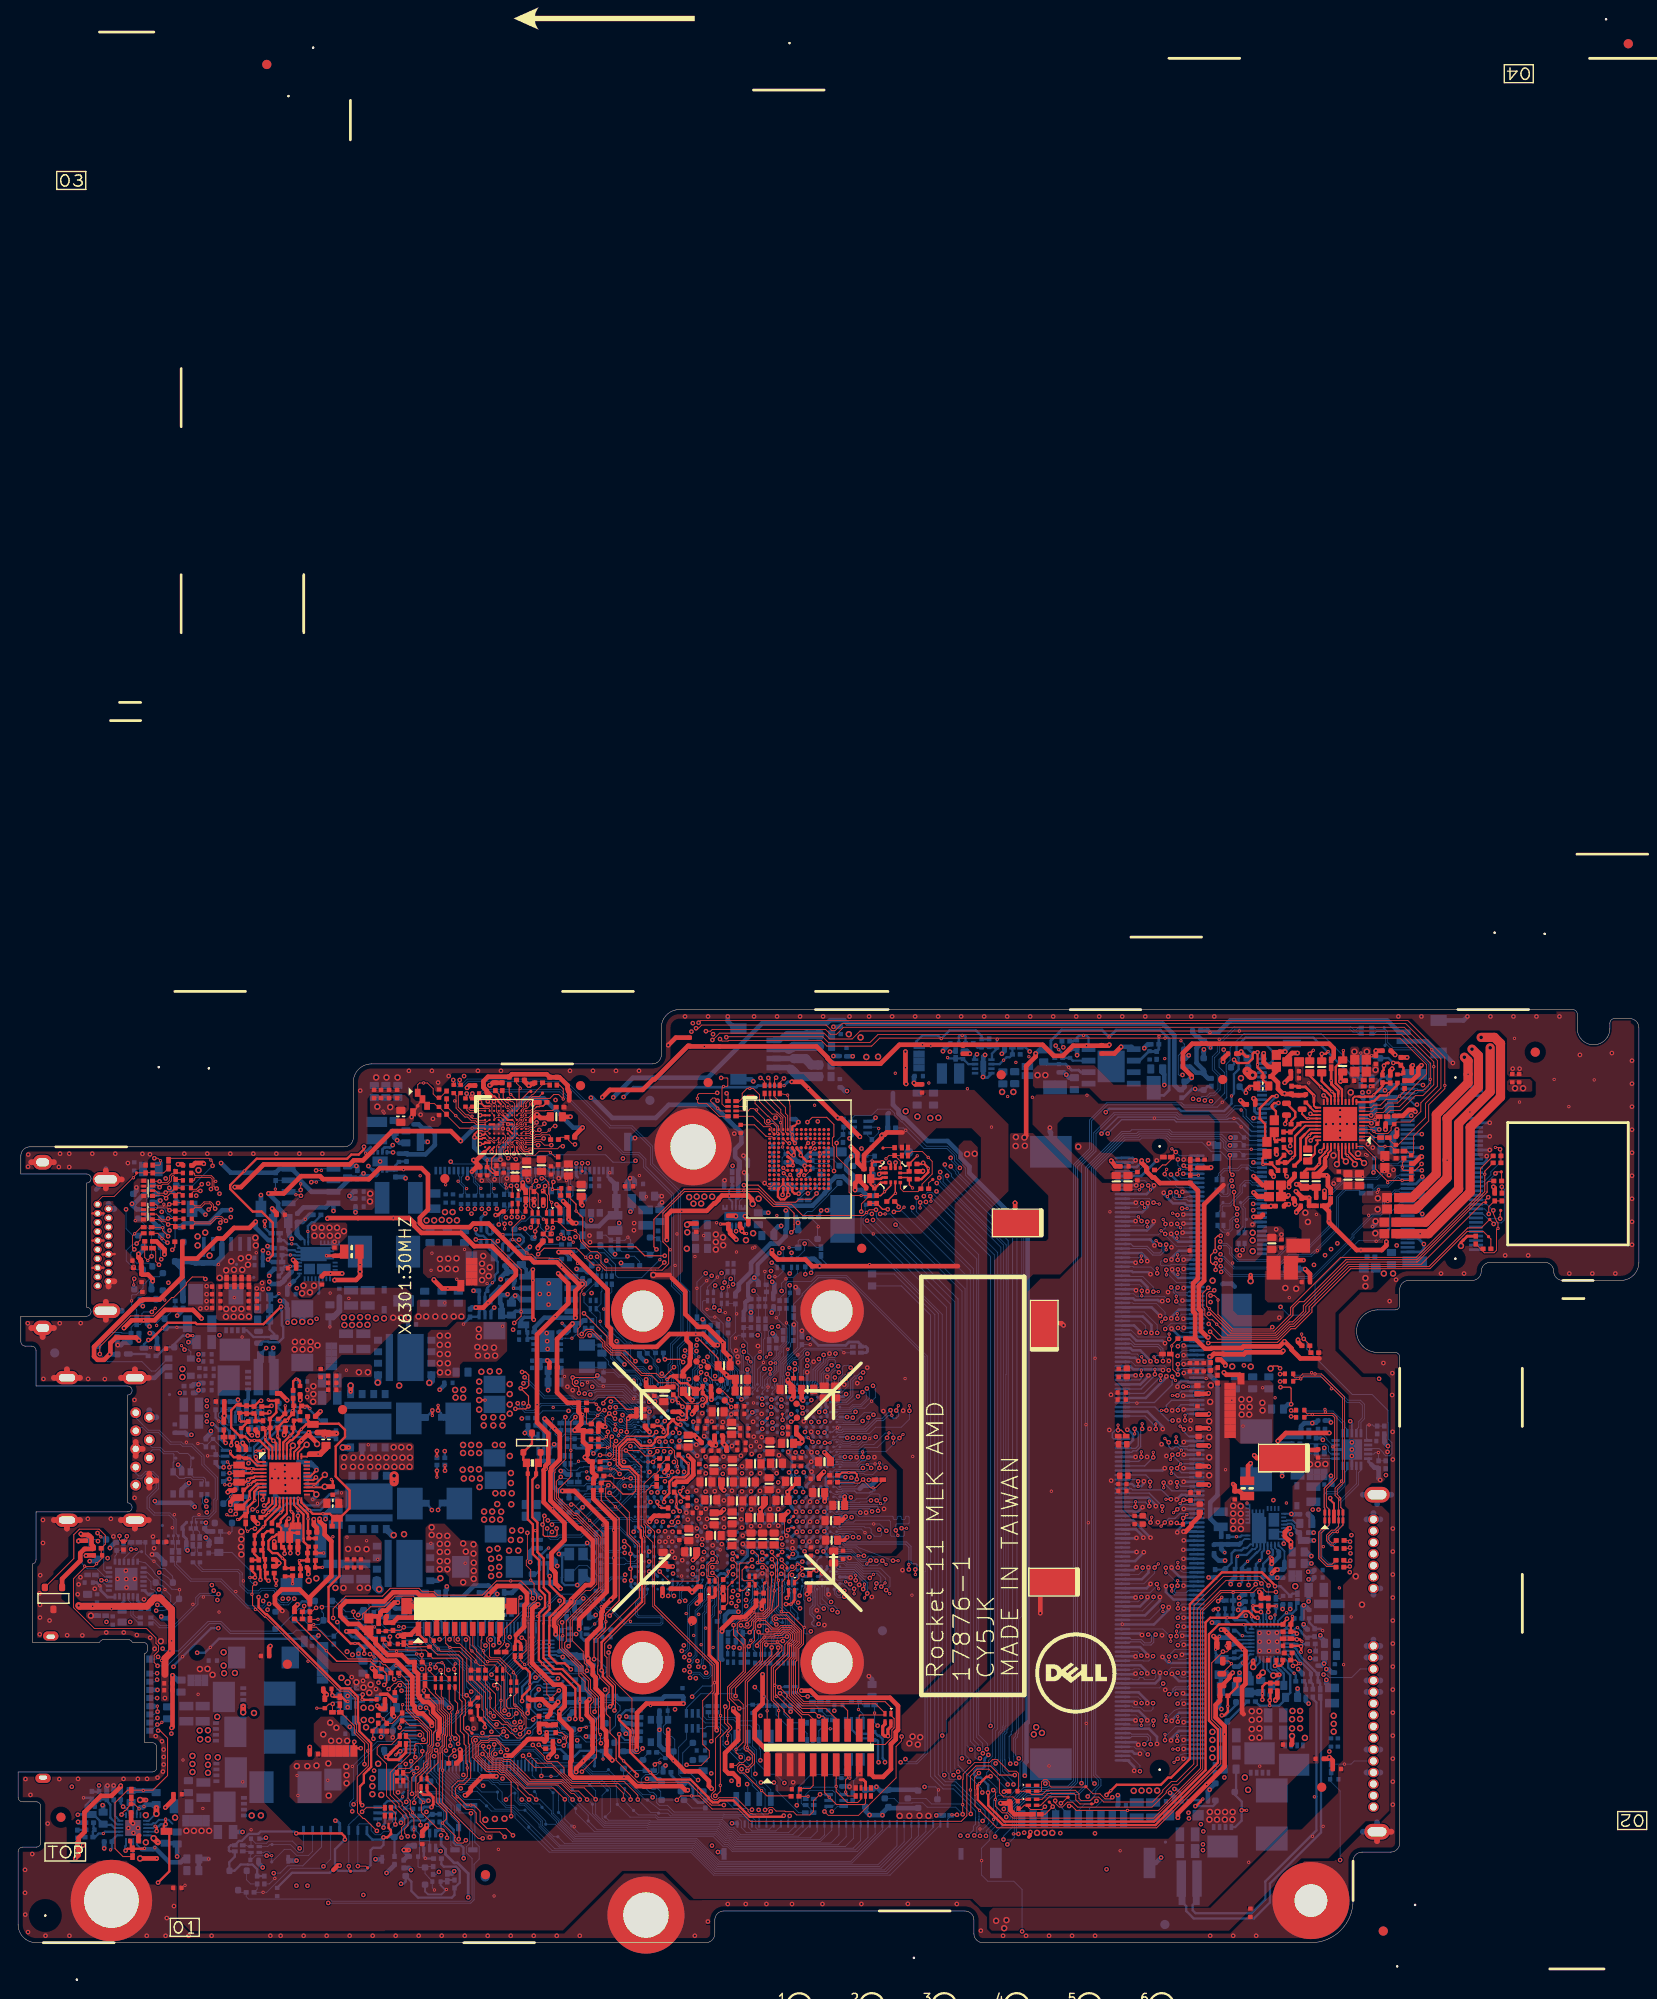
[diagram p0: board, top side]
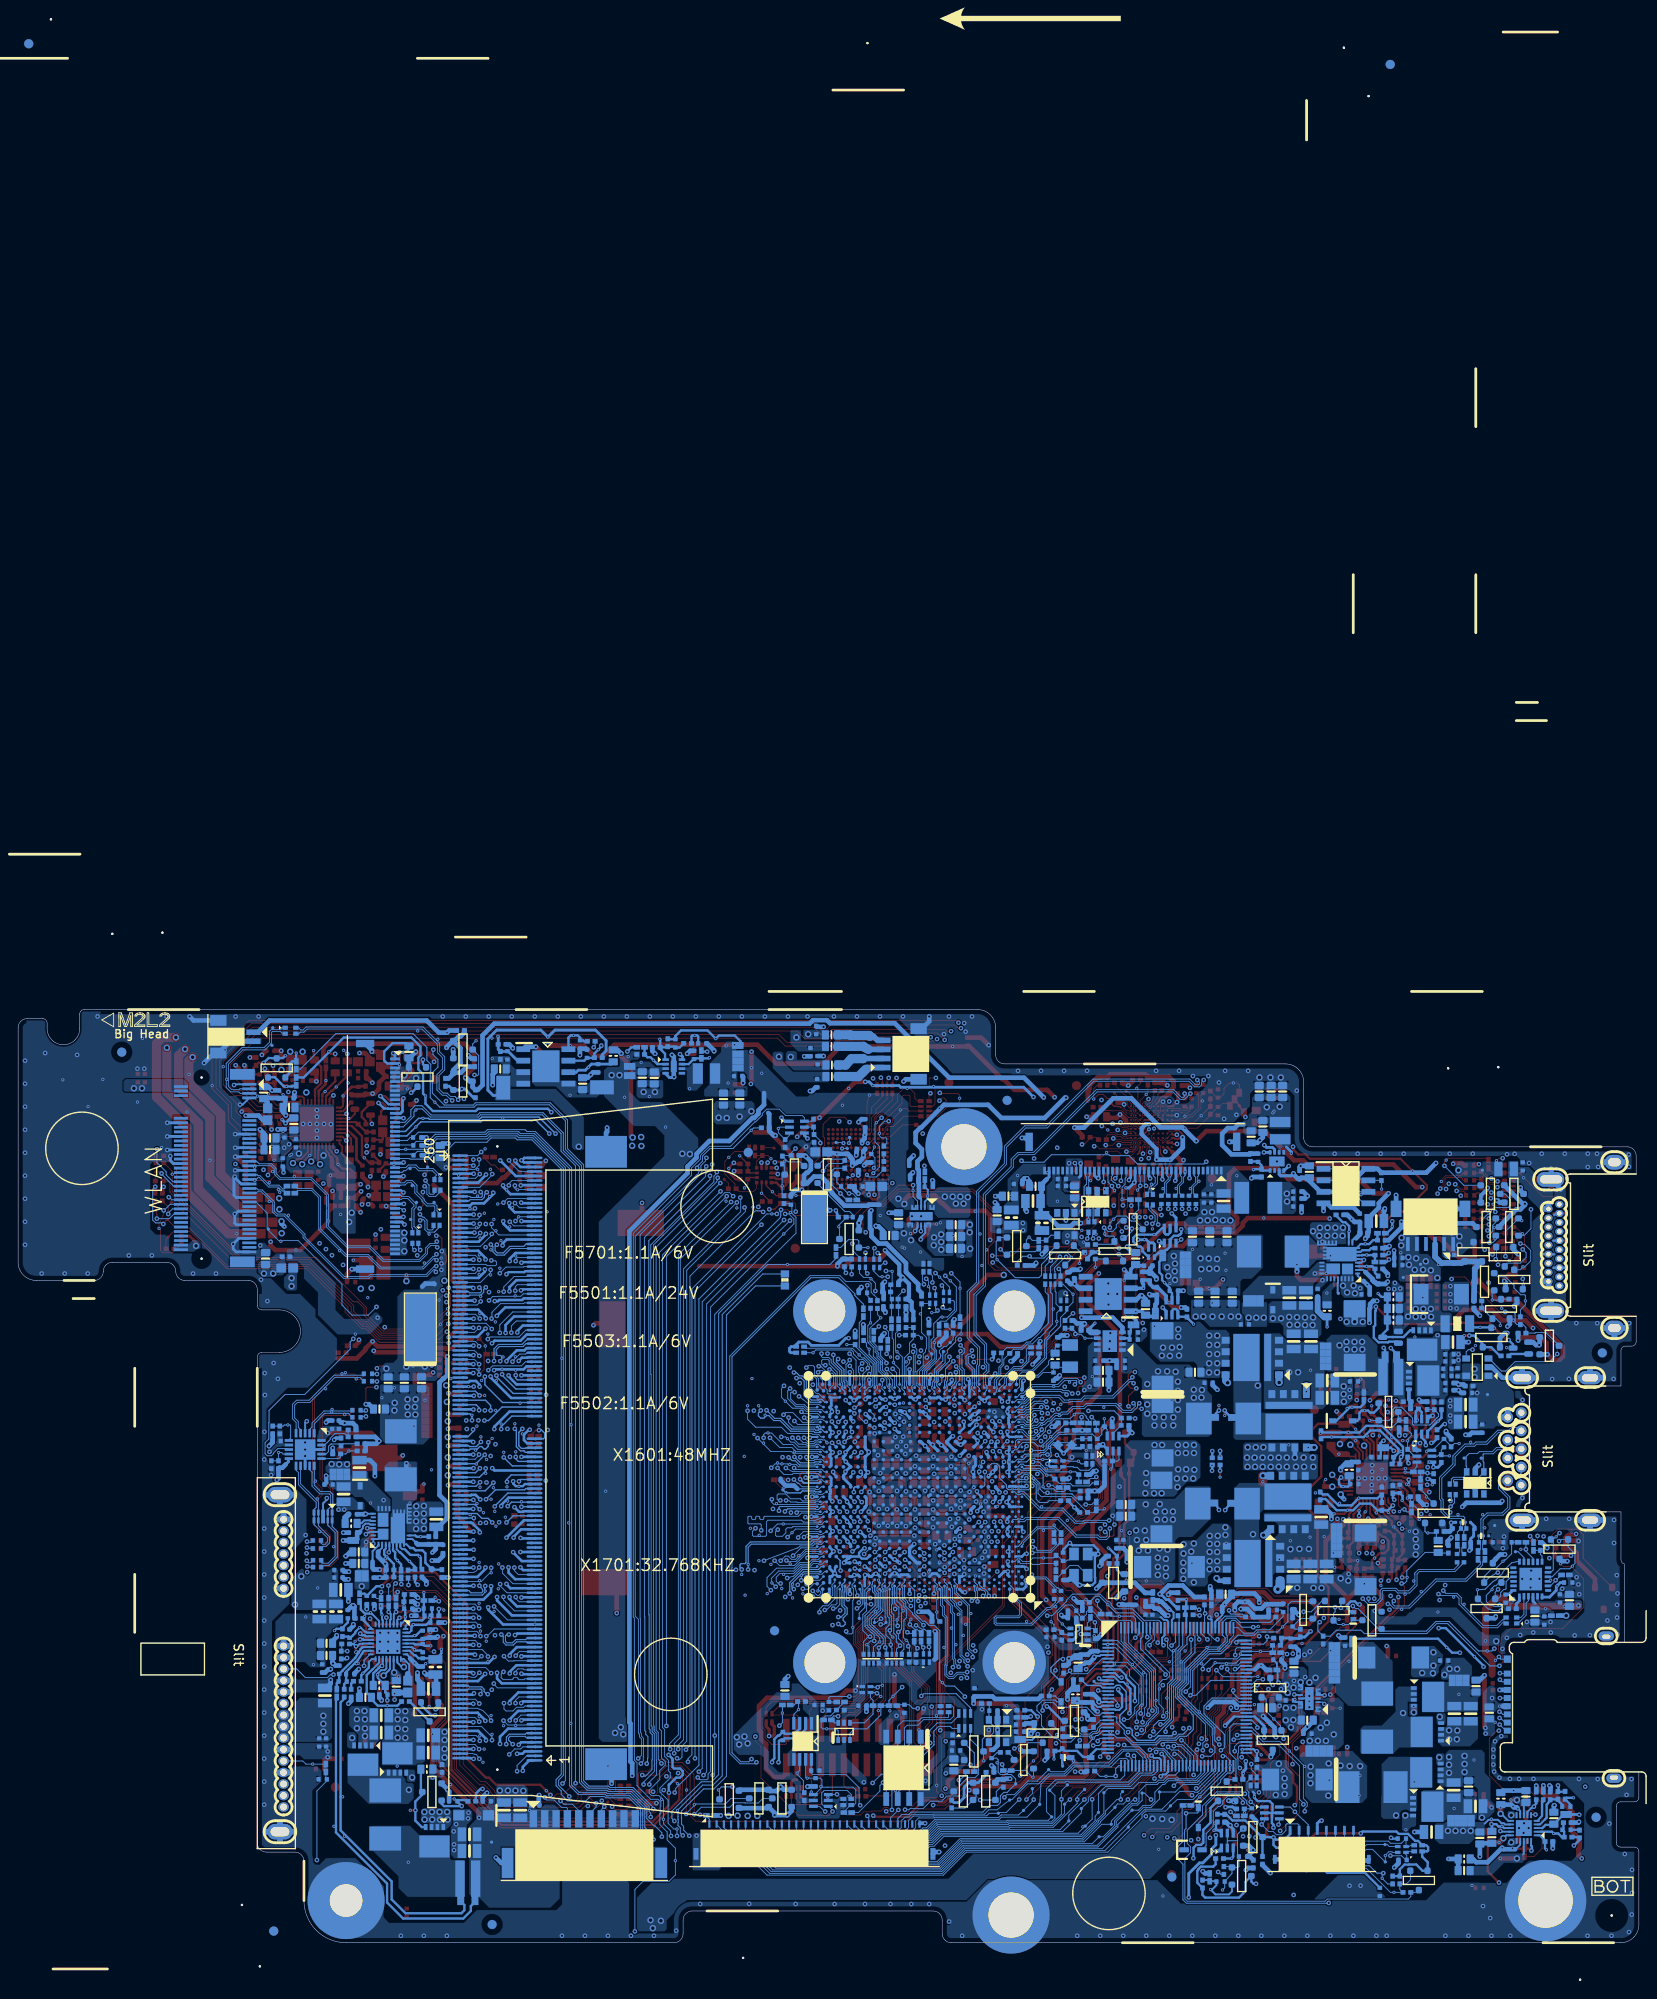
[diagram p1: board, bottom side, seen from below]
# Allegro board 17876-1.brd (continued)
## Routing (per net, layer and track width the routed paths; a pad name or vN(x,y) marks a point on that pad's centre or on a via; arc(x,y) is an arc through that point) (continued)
V3D3_STB: length 4
  TOP w0.203: HDA27.16 145.72,93.45 145.72,93.45 145.72,93.68
  TOP w0.305: 145.72,93.68 145.72,94.01 144.97,94.76 144.97,95.05 144.93,95.09 144.93,95.16 v2(144.93,95.16) 144.93,95.17 R2708.2
VCCCORE_SENSE: length 78.9
  TOP w0.254: v1(29.41,42.95) 29.41,43.41 PR4634.2 29.03,43.79 PG4610.2
  L4 w0.254: v1(85.45,41.51) 85.62,41.34 85.62,41.28 85.9,41 85.9,40.25 84.92,39.27 84.92,38.84 84.91,38.81 84.33,38.23 84.33,37.72 82.63,36.02 79.27,36.02 78.99,36.3 78.99,36.32 72.16,36.32 71.81,36.68 66.27,36.68 65.72,37.24 58.25,37.24 57.61,36.61 57.61,36.61 57.48,36.48 54.61,36.48 53.39,35.26 51.52,35.26 49.94,33.67 49.94,33.24 49.33,32.64 43.8,32.64 43.45,33 40.72,33 39.91,33.81 36.07,33.81 34.28,35.6 30.66,35.6 30.3,35.97 27.59,35.97 26.34,37.22 26.34,37.62 25.6,38.36 25.6,40.5 25.93,40.82 25.94,40.82 28.33,43.21 29.16,43.21 v1(29.41,42.95)
  BOTTOM w0.254: CPU1.D31 84.93,41.12 85.29,41.48 85.42,41.48 v1(85.45,41.51)
VDD: length 188.5
  TOP w0.254: v1(140.06,35.76) 140.06,35.69 139.62,35.26 PR4402.1 132.53,35.13 131.44,34.05 131.44,24.51 132.44,23.52 132.44,19.88 125.54,12.98 108.7,12.98 105.93,15.76 105.93,16.36 105.92,16.37 105.92,16.99 105.89,17.02 105.89,17.32 v2(106.11,17.55) 106.88,18.32 107.29,18.32 v1(107.34,18.37) ; PR4401.1 139.6,30.81 139.34,30.56 v1(138.73,30.56) 138.73,30.58 138.89,30.74 PC4446.1
  L3 w0.254: v1(107.34,18.37) 106.5,18.37 106.35,18.21 105.16,18.21 103.99,19.38 100.03,19.38 99.36,18.72 93.85,18.72 91.87,20.7 85.07,20.7 81.69,24.08 81.54,24.08 80.98,24.65 80.98,24.79 80.42,25.35 75.55,25.35 74.94,24.74 70.59,24.74 69.95,24.11 64.49,24.11 63.92,24.68 62.9,24.68 62.35,25.22 60.65,25.22 60.22,24.79 58.22,24.79 56.13,26.87 56.13,26.89 55.11,27.92 52.08,27.92 50.76,29.24 45.62,29.24 45.5,29.36 44.37,29.36 43.13,30.61 40.23,30.61 39.52,31.32 38.61,31.32 38.53,31.24 35.84,31.24 34.92,32.16 32.08,32.16 30.78,33.46 26.26,33.46 24.39,35.33 23.05,35.33 20.37,38.01 20.37,44.28 18.98,45.67 18.98,49.36 20.07,50.45 20.07,51.11 20.18,51.22 20.18,54.57 20.68,55.07 20.68,56.59 21.34,57.25 v1(21.42,57.25)
  L4 w0.254: v1(138.73,30.56) 140.06,31.88 v1(140.06,35.76)
  BOTTOM w0.203: PU4401.19 138.65,30.64
  BOTTOM w0.254: PR4438.1 139.7,29.72 139.37,30.05 139.37,30.05 139.12,30.3 138.86,30.56 v1(138.73,30.56) 138.65,30.64 ; v1(21.42,57.25) 21.57,57.25 22.2,56.62 PR4451.1
VDDCR_FCH:
  vias: v1(60.63,61.37) v1(61.21,60.99) v1(71.15,58.6) v2(60.31,62.5) v2(64.58,61.42) v2(67.95,60.05)
VDDCR_FCH_EN: length 2.1
  BOTTOM w0.305: R4010.1 60.71,67.72 v2(60.05,68.38)
  BOTTOM w0.635: R4010.1 60.49,67.37 U4003.5
VDDIO_AUDIO: length 11.3
  TOP w0.254: v2(71.63,62.16) 72,62.53 R704.2 72.53,62.34 73.11,61.76 73.85,61.76 C1064.1 75.01,60.86 C1081.1 C1065.1 76.03,60.19 76.03,59.78 v1(75.54,59.29)
  L4 w0.254: v1(74.52,57.51) 74.52,57.58 74.88,57.94 74.88,58.62 v1(75.54,59.29)
  BOTTOM w0.254: CPU1.AM13 74.47,56.85 74.47,57.46 v1(74.52,57.51)
VDDNB_SENSE: length 97.1
  TOP w0.254: v2(26.24,54.22) 26.32,54.29 v1(27.05,54.29)
  L4 w0.254: v1(86.56,42.06) 87.08,41.55 87.08,40.29 85.62,38.83 85.62,37.3 85.65,37.27 85.65,35.69 83.34,33.38 77.32,33.38 75.51,35.18 71.67,35.18 71.32,35.54 66.25,35.54 65.87,35.16 63.5,35.16 62.56,36.1 58.72,36.1 58.09,35.46 58.09,35.46 57.93,35.31 55.07,35.31 53.88,34.11 52,34.11 51.08,33.19 51.08,32.77 49.63,31.32 45.75,31.32 45.27,30.84 43.99,30.84 42.97,31.85 40.23,31.85 39.42,32.67 35.56,32.67 33.77,34.46 30.19,34.46 29.82,34.83 27.12,34.83 25.2,36.75 25.2,37.14 24.33,38 24.33,41.1 26.59,43.36 26.59,44.28 27.28,44.97 27.28,46.61 26.47,47.42 26.47,53.13 27.05,53.72 v1(27.05,54.29)
  BOTTOM w0.254: PG4601.2 27.38,54.64 27.05,54.3 v1(27.05,54.29) ; v1(86.56,42.06) 86.42,41.92 CPU1.E33
VDDQ_PWRGD: length 6
  BOTTOM w0.203: PU5301.8 136.02,43.98 135.66,43.61
  BOTTOM w0.254: 135.66,43.61 135.61,43.56 135.29,43.56 135.04,43.31 134.27,43.31 133.95,42.98 133.95,41.93 TP5301.1 133.19,41.18 PR5303.2
VSSCORE_SENSE: length 78
  TOP w0.254: RN810.4 85.69,37.82 85.62,37.74 85.62,37.66 85.32,37.37 v2(85.31,37.37) v1(84.76,37.37) ; v1(30.05,43) 30.05,43.61 PR4631.1 29.97,43.69 PG4609.2
  L4 w0.254: v1(30.05,43) 30.05,43.04 29.5,43.59 28.17,43.59 25.78,41.2 25.77,41.2 25.22,40.65 25.22,38.2 25.96,37.47 25.96,37.06 27.44,35.59 30.14,35.59 30.51,35.22 34.12,35.22 35.92,33.43 39.75,33.43 40.56,32.62 43.29,32.62 43.64,32.26 49.49,32.26 50.32,33.09 50.32,33.51 51.68,34.88 53.55,34.88 54.77,36.1 57.64,36.1 57.77,36.22 57.77,36.22 58.4,36.86 65.56,36.86 66.12,36.3 71.65,36.3 72,35.94 78.81,35.94 79.12,35.64 82.78,35.64 84.51,37.37 84.75,37.37 v1(84.76,37.37)
VSSNB_SENSE: length 86.2
  TOP w0.254: v1(84.84,38.05) 85.04,38.26 RN810.3 ; v1(30.89,47.12) 30.89,47.09 30.91,47.07 PG4611.2
  L4 w0.254: v1(84.84,38.05) 85.24,37.65 85.24,37.14 85.27,37.11 85.27,35.85 83.18,33.76 77.48,33.76 75.67,35.56 71.83,35.56 71.48,35.92 66.09,35.92 65.71,35.54 63.66,35.54 62.72,36.48 58.56,36.48 57.93,35.84 57.93,35.84 57.77,35.69 54.92,35.69 53.72,34.49 51.84,34.49 50.7,33.35 50.7,32.93 49.47,31.7 45.59,31.7 45.11,31.22 44.15,31.22 43.13,32.23 40.39,32.23 39.57,33.05 35.72,33.05 33.93,34.84 30.35,34.84 29.98,35.21 27.28,35.21 25.58,36.91 25.58,37.29 24.71,38.16 24.71,40.94 26.97,43.2 26.97,44.12 27.66,44.81 27.66,46 27.91,46.26 30.15,46.26 30.86,46.97 30.86,47.09 v1(30.89,47.12)
  BOTTOM w0.254: v1(30.89,47.12) v2(30.89,47.68)
0D6V_VREF_S0: length 57.6
  TOP w0.508: C1223.1 C1228.1 131.62,85.52 v1(131.67,85.57) ; v3(136.04,73.03) v2(136.04,73.69)
  L3 w0.762: v3(136.04,73.03) 136.04,71.81 135.1,70.87 135.1,68.48 138.56,65.02 138.56,64.97 139.22,64.31 139.26,64.31 139.39,64.19 139.58,64.19 140.31,63.46 140.31,62.03 141.91,60.43 141.91,53.37 141.73,53.19 141.73,52.43 141.99,52.17 141.99,46.76 141.78,46.56 141.78,43.54 140.97,42.72 v3(140.97,39.35) ; v3(131.85,73.08) 131.67,73.08 131.65,73.1 131.62,73.1 131.09,73.64 131.09,76.68 131.14,76.74 131.14,76.79 131.52,77.17 131.52,85.42 v1(131.67,85.57)
  L4 w0.762: v3(136.04,73.03) 135.89,73.18 133.93,73.18 133.38,72.62 132.51,72.62 132.05,73.08 v3(131.85,73.08)
0D95V_S0: length 16.3
  TOP w0.508: R1602.1 74.85,58.93 74.52,58.6 74.52,58.47 v1(74.4,58.35) ; R301.1 72.69,50.88 73.78,50.88 73.8,50.9 73.81,50.9 74.53,51.62 74.53,53.19 v1(73.96,53.75)
  L3 w0.508: 78.82,54.21 78.21,54.21 78.13,54.28 75.29,54.28 75.21,54.36 74.7,54.36 74.09,53.75 v1(73.96,53.75) 73.91,53.8 73.91,57.76 74.4,58.24 v1(74.4,58.35)
  BOTTOM w0.102: 81.76,57.59 81.97,57.77
  BOTTOM w0.127: 81.32,58.18 81.54,58.31
  vias: v1(43.43,91.14) v1(79.25,65.36) v1(79.4,64.7) v1(79.48,64.06) v1(80.89,54.81) v1(80.98,53.95) v1(81.13,57.51) v1(81.2,55.86) v1(81.66,65.86) v1(81.89,54.76) v1(82.07,58.37) v1(82.07,55.81) v2(74.71,75.74) v2(75.68,78.05) v2(77.1,79.47) v2(81.06,76.67) v2(81.17,59.58) v2(81.5,55.29) v2(82.77,61.32) v3(77.01,78.18) v3(77.01,77.34) v3(77.01,76.51) v3(77.8,77.85) v3(77.83,76.99)
0D95V_S0_EN: length 3.4
  BOTTOM w0.203: U4002.3 78.82,81.79 78.49,82.12 78.49,82.41 v2(78.51,82.42) 78.49,82.45 78.49,83.09 C4011.1
  BOTTOM w0.254: C4011.1 78.82,83.47 R4007.2
0D95V_S5: length 2.1
  BOTTOM w0.356: CPU1.AL11 74.73,54.99 74.8,54.99 74.83,54.97 v1(74.85,54.97) 74.88,54.99 75.06,54.99 75.39,55.32 CPU1.AL13 ; v1(74.96,53.75) 74.4,54.3 CPU1.AJ11
  vias: v2(51.77,72.75) v3(51.21,74.96) v3(51.23,74.12) v3(51.21,73.15) v3(51.33,75.8) v3(51.94,73.59) v3(52.07,74.55) v3(74.07,82.3) v3(74.54,81.58) v3(74.9,82.35) v3(75.39,81.58) v3(75.74,82.35) v3(76.61,82.35)
0D95V_S5_EN: length 97.4
  TOP w0.254: v1(55.63,26.68) 55.63,27.18 56.49,28.05 v2(56.49,28.53) 56.49,29.84 56.04,30.28 55.72,30.28 54.82,31.18 RN2407.1
  L3 w0.254: v1(27.61,76.13) 27.58,76.13 24.54,73.08 24.54,70.92 26.09,69.37 26.09,68.86 21.44,64.21 21.44,59.1 21.04,58.7 20.62,58.7 20.17,58.25 20.17,55.3 19.66,54.79 19.66,51.44 19.56,51.34 19.56,50.67 18.47,49.59 18.47,45.46 19.71,44.22 19.71,41.91 19.53,41.73 19.53,38.06 22.77,34.82 24.18,34.82 26.95,32.06 31.45,32.06 31.85,31.65 34.7,31.65 35.61,30.74 38.76,30.74 38.84,30.81 39.29,30.81 40.01,30.1 42.9,30.1 44.15,28.86 45.29,28.86 45.54,28.6 49.15,28.6 49.28,28.73 50.55,28.73 51.24,28.04 51.24,28.04 51.87,27.41 54.89,27.41 v1(55.63,26.68)
  BOTTOM w0.203: 56.4,29.01 56.63,29.23 56.63,29.51 57.27,30.15 U2401.9
  BOTTOM w0.254: PR5206.1 27.94,75.9 27.86,75.97 27.81,75.97 27.66,76.13 v1(27.61,76.13) ; v1(55.63,26.68) 55.63,28.23 56.4,29.01
0D95V_S5_PWRGD: length 96.1
  TOP w0.254: v1(27.23,79.63) v2(27.23,79.07)
  L3 w0.254: v1(27.23,79.63) 28.88,77.98 28.88,74.91 28.09,74.12 27.5,74.12 25.83,72.45 25.83,71.42 27.36,69.89 27.36,68.2 25.02,65.86 25.02,65.81 23.27,64.05 23.27,56.88 22.05,55.66 22.05,54.79 21.36,54.1 21.36,50.75 21.21,50.6 21.21,49.94 20.22,48.95 20.22,46.13 21.31,45.04 21.31,41.28 20.88,40.84 20.88,38.22 23.26,35.84 24.6,35.84 26.47,33.97 31.01,33.97 32.31,32.67 37.69,32.67 37.9,32.87 40.08,32.87 40.46,32.49 44.57,32.49 45.36,31.7 46.23,31.7 46.71,31.22 49.89,31.22 50.3,30.8 51.29,30.8 51.48,30.61 56.49,30.61 57.62,29.48 57.62,28.1 v1(57.47,27.95)
  BOTTOM w0.203: 57.05,26.03 57.07,26 57.07,25.97 57.36,25.69 57.76,25.69 57.82,25.75 U2401.20
  BOTTOM w0.254: 57.05,26.03 57.05,26.03 57.05,26.45 57.05,26.45 57.05,27.36 57.43,27.74 57.43,27.92 v1(57.47,27.95) ; PR5204.1 27.82,78.31 27.23,78.9 v1(27.23,79.63)
0D775V_S5: length 2.5
  BOTTOM w0.254: U4003.3 56.36,66.72 C4014.1 C4013.1 56.08,67.49 PG4901.2
1D2V_CPU_VDDNB: length 33.3
  TOP w0.254: v3(50.89,59.89) v2(51.55,59.89)
  TOP w0.508: PR4601.1 28.93,60.63 v1(29.69,59.87)
  L3 w0.508: v3(49.12,61.04) 49.1,61.06 49.1,67.24 48.18,68.15 39.75,68.15 36.25,64.64 31.72,64.64 29.52,62.44 29.52,61.23 29.49,61.21 29.49,60.07 v1(29.69,59.87)
  vias: v1(69.9,49.71) v1(70.69,45.42) v1(70.79,44.27) v1(71.4,50.93) v1(71.42,45.42) v1(71.45,44.25) v1(72.11,48.72) v1(72.23,45.37) v1(72.2,44.27) v1(72.2,43.17) v1(72.33,47.56) v1(72.49,42.49) v1(73.15,48.69) v1(73.3,42.22) v1(74.88,48.8) v1(74.9,48.01) v1(74.96,44.88) v1(75.13,46.81) v1(75.51,44.55) v1(75.55,42.32) v1(75.84,45.9) v1(75.91,52.59) v1(75.88,49.8) v1(75.9,47.88) v1(76.04,46.77) v1(76.63,41.45) v1(76.67,43.86) v1(76.89,49.83) v1(77.67,43.99) v1(77.91,52.59) v1(77.9,48.82) v1(77.9,46.82) v1(77.91,45.84) v1(78.79,49.89) v1(79.91,52.59) v1(80.93,51.8) v1(83.73,51.82) v2(71.77,44.75) v2(73.24,40.47) v2(77.5,43.36) v3(48.23,61.01) v3(48.29,60.17) v3(49.12,60.15) v3(50.89,61.93) v3(50.89,60.91) v3(50.89,58.84) v3(51.13,63.02) v3(51.4,57.99) v3(51.4,57.1) v3(52.07,63.07) v3(52.45,57.99) v3(52.45,57.1) v3(53.09,63.07) v3(53.47,57.99) v3(53.47,57.1) v3(54.27,61.66) v3(54.27,60.56) v3(54.27,59.41) v3(54.27,58.4)
1D2V_S3: length 68.8
  BOTTOM w0.254: v1(124.26,50.93) 124.26,50.67 123.98,50.4 123.19,50.4 122.96,50.62 DIMM1.123
  BOTTOM w0.279: DIMM1.147 124.66,58.62 126.34,56.95 v1(126.34,56.69) ; DIMM1.112 v1(128.66,47.87) ; DIMM1.124 v1(128.65,50.87) ; v1(126.57,52.38) 126.32,52.13 DIMM1.129 ; v1(122.43,56.62) 122.53,56.62 123.06,56.08 123.06,55.48 122.71,55.13 DIMM1.141 ; v1(127.89,48.92) 128.37,49.4 128.4,49.4 128.42,49.43 128.88,49.43 128.93,49.38 DIMM1.118 ; v1(128.65,58.85) 128.7,58.85 128.7,58.87 DIMM1.148 ; DIMM1.111 123.09,47.62 123.15,47.56 123.61,47.56 v1(124.12,48.07) ; v1(123.34,62.62) DIMM1.163 ; DIMM1.154 v1(128.6,60.38) ; v1(124.76,62.61) 124.76,62.51 123.88,61.62 121.9,61.62 DIMM1.159 ; DIMM1.160 129.16,61.87 129.03,62 128.37,62 127.97,61.6 v1(127.97,61.37) ; v1(128.64,52.38) 128.64,52.38 DIMM1.130 ; v1(128.66,55.26) 128.78,55.38 DIMM1.142 ; DIMM1.135 122.72,53.62 122.72,53.62 123.32,53.62 v1(123.34,53.62) ; v1(125.58,48.19) 125.58,48.31 124.77,49.13 DIMM1.117 ; v1(126.75,62.51) 126.75,62.39 124.48,60.13 DIMM1.153 ; DIMM1.136 v1(128.66,53.87)
  BOTTOM w0.305: CPU1.W32 85.27,49.09 85.27,48.25 CPU1.U32 85.4,48.02 v1(85.86,47.56) ; v1(87.54,56.4) 87.54,56.39 CPU1.AL37 ; CPU1.L32 85.92,45.34 v1(85.95,45.34) ; CPU1.R37 87.4,46.62 v1(87.4,46.47) 87.37,46.47 87,46.1 CPU1.N35 ; CPU1.L37 87.4,44.42 87.4,44.32 v1(87.35,44.27) 87,43.92 CPU1.J35 ; CPU1.AC32 85.4,51.61 v1(85.09,51.92) 85.4,52.23 CPU1.AE32 CPU1.AG32 85,54.02 v1(85,54.17) 85.4,54.57 CPU1.AJ32 CPU1.AL32 ; CPU1.AJ35 87,54.71 v1(87.57,54.14) 87.59,54.11 87.59,53.83 CPU1.AG37 87.8,53.42 87.54,53.16 v1(87.54,53.09) 87,52.54 CPU1.AE35 87.05,52.52 v1(87.58,52) 87.58,51.79 87.8,51.57 CPU1.AC37 87.8,51.27 87,50.47 CPU1.AA35 ; CPU1.W37 87.4,48.82 v1(87.4,48.67) 87.4,48.64 87,48.24 CPU1.U35
  BOTTOM w0.356: v1(86.72,57.54) 87,57.81 CPU1.AR35
  vias: v1(92.57,53.59) v1(93.6,47.47) v1(94.52,53.59) v1(95.58,47.88) v1(124.61,53.62) v1(124.89,56.72) v1(125.81,46.41) v1(126.21,55.02) v1(126.75,53.72) v1(127.2,50.8) v1(127.25,46.36) v1(127.38,58.75) v1(128.09,57.66) v1(129.44,57.65) v1(129.38,56.7) v2(90.43,56.84) v2(123.49,59.56) v2(133.27,52.2) v3(131.47,57.56) v3(131.47,55.81) v3(131.47,53.57) v3(131.47,51.59) v3(131.65,61.52) v3(131.57,59.69)
1D8V_AUX_EN: length 7.4
  BOTTOM w0.102: v2(72.31,20.07) 72.34,20.09 Q5401.D 72.47,21.24 72.47,22.44 72.15,22.76 71.65,22.76 71.22,23.19 71.22,23.9 71.74,24.42 PU5402.3 71.74,25.57 PC5418.1 PR5414.1
1D8V_AUX_S5: length 46.8
  TOP w0.203: v1(66.34,23.01) 66.34,20.55 v2(66.83,20.06) 68.07,18.83 68.09,18.83 68.29,18.63 v1(68.29,18.46)
  L3 w0.203: v1(68.29,18.46) 68.29,18.58 68.09,18.78 67.27,18.78 66.12,17.63 52.86,17.63 52.6,17.88 52.58,17.88 51.64,18.82 51.64,18.84 50.19,20.3 50.17,20.3 49.7,20.76 49.7,22.91 50.28,23.49 v1(50.28,23.65) 50.28,23.91 49.11,25.08 42.99,25.08 40.21,27.86 40.21,27.97 39.78,28.4 v1(39.78,28.7)
  BOTTOM w0.203: v1(39.78,28.7) 39.88,28.81 39.88,30.02 R2486.1 39.95,30.84 C2439.1 ; v1(66.34,23.01) 66.98,22.38 67.94,22.38 PG5411.2
1D8V_DVDD-IO: length 6.8
  TOP w0.203: HDA27.8 149.28,91.37 149.34,91.31 v1(149.35,91.31)
  BOTTOM w0.508: v1(149.35,91.31) 149.35,91.38 149.66,91.69 C2723.1 149.4,92.46 C2724.1 150.06,93.22 C2743.1 150.18,93.23 151.73,93.23 151.79,93.17 151.35,92.73 R2742.2
1D8V_PWR:
  vias: v2(100.52,94.89) v2(100.74,98.99)
1D8V_PWR_VIN:
  vias: v2(69.81,26.17)
1D8V_S0: length 487.7
  TOP w0.508: v1(151.03,77.37) 151.03,76.96 150.52,76.46 v2(148.23,76.46) 147.75,76.46 144.69,79.52 v2(144.69,79.67) 144.69,80.71 R2709.1 144.53,81.33 144.88,81.68 R2752.1 ; PG4606.1 23.93,49.13 23.42,48.62 v1(23.42,48.34) ; C1056.1 76.88,55.61 76.89,55.6 76.89,55.17 77,55.05 v1(77,54.92) 76.6,54.92 C1057.1 ; v1(59.66,76.23) 60.92,76.23 v2(61.1,76.04) 65.06,72.08 65.06,68.11 65.43,67.74 65.43,66.13 65.8,65.76 70.49,65.76 71.91,67.18 73.79,67.18 ; v1(77.22,65.97) 76.81,65.97 75.59,67.18 73.79,67.18 ; 73.79,67.18 73.79,66.5 74.23,66.05 74.23,64.56 74.14,64.47 74.14,63.8 73.39,63.05 R704.1 ; HDT1.19 94.11,18.66 94.47,18.3 95.47,18.3 96.34,19.17 96.34,21.92 96.88,22.45 96.88,23.25 97.12,23.5 97.12,26.14 96.23,27.03 88.24,27.03 87.46,27.81 v1(86.46,27.81) ; v1(98.02,94.79) 97.94,94.87 v2(97.94,96.58) v1(97.94,98.35) ; v1(23.91,83.4) 24.6,83.4 27.1,85.9 36.6,85.9 37.06,86.36 38.07,86.36 41.3,89.59 47.75,89.59 v1(48.84,88.5) ; R822.1 81.45,37.18 80.21,35.94 79.78,35.94 79.76,35.92 78.97,35.92 77.7,34.65 v1(77.7,34.37) ; v1(62.31,89.97) 61.44,89.1 R6313.2 ; HDT1.1 82.68,21.2 81.31,22.57 81.31,25.52 82.17,26.39 v1(82.17,29.61)
  L3 w0.508: v1(153.77,91.29) 153.77,88.77 150.34,85.35 150.34,84.02 151.48,82.89 151.48,77.82 v1(151.03,77.37) ; v1(91.95,86.79) 91.95,86.94 91.67,87.23 91.66,87.23 91.14,87.75 91.14,89.04 94.15,92.05 95.28,92.05 v1(98.02,94.79) ; v1(16.59,72.85) 17.98,74.25 17.98,75.29 19.08,76.38 19.08,78.26 19.94,79.12 20.75,79.12 23.91,82.29 v1(23.91,83.4) ; v1(48.13,7.89) 46.11,5.87 39.86,5.87 38.76,6.96 19.68,6.96 19.38,7.27 14.35,7.27 12.57,9.04 9.59,9.04 8.72,9.92 8.72,14.42 v1(5.93,17.22) ; v1(27.64,72.18) 27.64,72.16 28.08,71.71 28.08,69.11 28.07,69.09 28.07,68 25.65,65.58 25.65,65.54 25.17,65.06 25.17,55.75 25.65,55.26 25.65,54.3 24.44,53.08 24.44,51.54 24.41,51.51 24.41,49.33 v1(23.42,48.34)
  L4 w0.508: v1(62.31,89.97) 62.77,89.5 62.77,87.11 63.53,86.35 63.53,84.07 61.44,81.99 61.44,80.43 59.29,78.28 59.27,78.28 58.98,77.99 58.98,76.91 v1(59.66,76.23) ; v1(5.93,17.22) 6.5,16.64 11.73,16.64 12.47,17.38 15.44,17.38 16.7,18.64 16.7,22.31 16.28,22.74 16.28,23.95 20.05,27.73 20.05,29.17 19.33,29.9 19.33,30.51 20.4,31.57 20.4,32.39 19.76,33.02 19.76,34.65 18.01,36.4 18.01,37.1 16.29,38.82 16.29,39.02 16.28,39.03 16.28,41.4 15.75,41.94 15.75,51.56 15.47,51.84 15.47,58.68 14.68,59.46 14.68,63.04 12.7,65.03 12.7,70.09 14.19,71.58 15.32,71.58 v1(16.59,72.85) ; v1(27.64,72.18) 27.65,72.16 28.19,72.16 28.55,72.52 28.55,74.12 28.02,74.65 27.18,74.65 26.19,75.64 26.19,75.97 25.93,76.23 25.93,76.23 25.2,76.96 25.2,82.12 v1(23.91,83.4) ; v1(153.77,91.29) 153.59,91.48 153.59,94.08 155.52,96.02 155.52,97.12 153.37,99.26 126.47,99.26 125.3,98.1 120.27,98.1 119.61,98.76 116.77,98.76 116.2,98.2 113.81,98.2 112.97,99.04 98.63,99.04 v1(97.94,98.35) ; v1(48.13,7.89) 48.93,8.69 58.92,8.69 63.35,13.11 74.75,13.11 78.74,17.1 v1(78.74,17.87)
  BOTTOM w0.305: v1(59.66,76.23) R5521.1 60.35,76.13 60.86,75.62 R5526.1
  BOTTOM w0.356: v1(77,54.92) 77,54.92 ; 77,54.92 76.92,54.92 76.4,54.4 CPU1.AJ15 ; 77,54.92 CPU1.AL17
  BOTTOM w0.508: R6309.1 92.06,86.9 v1(91.95,86.79) 91.4,86.23 91.4,85.36 91.76,84.99 91.87,84.99 92.15,84.71 Q6301.G 91.79,83.84 91.06,84.57 90.26,84.57 89.55,83.86 89.55,83.29 89.04,82.79 89.04,82.72 87.67,81.35 85.11,81.35 85,81.46 83.81,81.46 ; v1(23.42,48.34) 23.77,48.34 24.33,48.9 24.33,49.2 PR4619.1 ; R2742.1 151.85,90.79 152.35,91.29 v1(153.77,91.29) ; v1(77.7,34.37) 77.6,34.27 77.6,31.4 77.75,31.24 ; v1(48.13,7.89) 47.9,7.65 R6514.1 ; v1(77.22,65.97) 77.22,66.17 76.45,66.93 R1615.2 ; v1(48.84,88.5) 48.9,88.5 50.39,89.99 52.81,89.99 56.03,93.21 58.02,93.21 61.26,89.97 v1(62.31,89.97)
  vias: v2(79.29,76.24) v2(81.32,76.77) v2(83.75,80.27) v3(80.34,77.55) v3(81.13,78.31)
1D8V_S0_EN: length 141.6
  TOP w0.102: v1(110.01,18.5) 108.34,18.5 107.33,19.51 105.72,19.51 104.72,18.51 104.72,14.02 104.1,13.4 80.83,13.4 79.47,14.76 76.6,14.76 75.16,16.2 v2(74.33,16.2) 73.16,16.2 v1(72.71,15.75)
  L4 w0.102: v1(102.54,84.65) 102.54,84.91 102.36,85.09 102.36,85.11 101.97,85.5 101.55,85.5 100.76,84.7 98.56,84.7 98.33,84.93 98.33,85.85 97.17,87.01 97.15,87.01 96.87,87.29 94.39,87.29 93.35,86.26 93.33,86.26 91.14,84.08 91.14,83.9 90.94,83.69 88.19,83.69 87.2,82.7 v1(87.17,82.7)
  BOTTOM w0.102: v1(72.71,15.75) Q2507.G 70.93,15.92 70.93,16.69 70.43,17.17 R2516.1 ; v1(110.01,18.5) 109.9,18.39 109.64,18.39 108.94,19.1 108.94,20.16 108.9,20.2 108.9,22.96 109.14,23.2 109.14,23.5 109.25,23.61 109.25,36.17 109.29,36.21 109.29,77.49 102.54,84.24 v1(102.54,84.65) ; R4016.1 86.33,82.24 86.79,82.7 v1(87.17,82.7) 87.3,82.7 C4027.1 88.53,83.93 D4004.3
1D8V_S0_EN_D: length 3.8
  BOTTOM w0.102: Q2507.D 73.16,16.09 Q2506.G 74.39,14.86 75.86,14.86 R2518.1
1D8V_S0_EN_R: length 17.6
  TOP w0.102: v1(80.11,83.62) 81.69,83.62 83.57,81.74 85.84,81.74 86.16,82.06 87.58,82.06 88.1,82.58 88.1,82.63 88.13,82.66 v1(88.13,82.7)
  BOTTOM w0.102: U4002.5 79.62,81.85 80.11,82.34 v2(80.11,83.01) v1(80.11,83.62) ; R4015.2 88.78,85.49 89.07,85.2 89.07,83.64 v1(88.13,82.7) 87.41,81.98 R4016.2
1D8V_S5: length 248.4
  TOP w0.508: v3(81.08,81.54) 81.08,81.71 81,81.79 81,82.04 80.57,82.48 77.7,82.48 77.34,82.12 77.34,82.02 76.94,81.61 76.83,81.61 76,80.78 72.11,80.78 71.6,80.27 v1(71.6,77.57) ; v1(59.33,34.04) 59.33,34.8 59.16,34.97 59.16,35.69 59.81,36.34 59.81,36.35 61.04,37.58 v2(61.04,37.86) 62.65,39.47 63.17,39.47 63.45,39.75 63.45,44.38 62.09,45.75 61.82,45.75 58.76,48.81 58.76,52.01 58.84,52.08 58.84,52.38 59.79,53.33 59.79,56.16 v2(59.23,56.72) v1(58.12,57.84)
  L3 w0.508: v1(118.86,12.07) 118.07,12.85 110.37,12.85 110.06,12.55 108.53,12.55 107.44,13.64 107.44,13.93 107.25,14.12 107.25,14.16 106.71,14.7 105.62,14.7 105.28,15.04 102.5,15.04 102.38,14.92 91.11,14.92 90.29,15.74 88.25,15.74 87.7,16.29 79.29,16.29 78.29,17.3 78.14,17.44 78.14,17.66 77.14,18.66 77.14,18.95 76.77,19.33 76.24,19.33 75.98,19.07 75.8,19.07 75.78,19.05 74.6,19.05 74.6,19.04 74.11,19.04 74.07,19 72.02,19 v1(71.46,19.56) ; v1(54.03,71.58) 54.03,71.37 55.9,69.5 59.96,69.5 64.11,73.64 65.15,73.64 v1(66.55,75.03) 66.55,75.96 68.16,77.57 v1(71.6,77.57)
  L4 w0.305: v1(54.03,71.58) 54.03,70.69 54.76,69.95 54.76,69.16 55.58,68.35 55.58,65.13 57.33,63.37 57.33,61.82 57.2,61.69 57.2,60.45 58.29,59.36 58.29,58.02 v1(58.12,57.84)
  L4 w0.508: v1(118.86,12.07) 118.86,13.51 113.94,18.43 v1(111.12,18.43)
  BOTTOM w0.356: v1(75.72,55.91) 75.81,55.91 CPU1.AL15 76.4,55.22 75.5,54.32 CPU1.AJ13
  BOTTOM w0.508: R2517.2 71.19,19.29 v1(71.46,19.56) ; PG4902.2 53.37,70.44 53.21,70.59 PR4902.1 53.92,71.48 v1(54.03,71.58) ; R5522.1 66.75,74.75 66.55,74.96 v1(66.55,75.03) ; v1(58.12,57.84) 58.14,57.81 R1746.2 ; R1616.2 79.17,71.71 79.55,72.09 79.55,72.7 80.9,74.04 80.9,75.02 83.05,77.17 83.91,77.17 84.71,77.97 84.71,78.69 84.86,78.84 84.86,80.7 v1(84.73,80.82) ; v1(111.12,18.43) 111.12,19.8 111.31,19.99 111.31,24.18 111.43,24.3 111.43,78.53 105.01,84.95 105.01,85.67 104.01,86.67 104.01,87.08 102.6,88.49 100.39,88.49 97.85,91.04 97.66,91.04 97.18,91.52 97.18,91.87 96.57,92.48 96.57,93.78 ; R2436.1 59.74,33.58 59.33,33.99 v1(59.33,34.04)
  vias: v1(76.56,57.53) v2(81.52,91.93) v2(87.91,92.44) v2(96.82,95.98) v3(81.74,82.12)
1D8V_S5_PWRGD: length 110.4
  TOP w0.254: v1(38.18,87.86) 38.18,87.58 37.59,87 36.78,87 36.32,86.54 26.33,86.54 v2(24.97,85.18) 23.41,83.61 23.41,83.19 25.9,80.7 26.88,80.7 28.12,79.46 28.12,75.92 27.62,75.41 v1(27.58,75.41)
  L3 w0.254: v1(38.18,87.86) 38.18,91.67 41.1,94.59 42.01,94.59 42.88,95.45 46.69,95.45 47.42,94.72 49.12,94.72 49.47,95.07 51.39,95.07 51.95,95.63 66.93,95.63 70.37,95.68 75.99,96.83 95.21,96.83 97.29,98.91 111.12,98.91 v1(111.66,98.38)
  BOTTOM w0.254: v1(111.66,98.38) 111.2,98.83 PR5412.1 ; PR5209.1 27.86,75.13 v1(27.58,75.41)
1D8V_SPI_EN#: length 165.6
  L3 w0.102: v1(106.47,13.43) 106.35,13.55 104.81,13.55 104.79,13.57 102.62,13.57 102.29,13.24 91.86,13.24 90.01,15.08 87.98,15.08 87.44,15.62 79.03,15.62 77.48,17.17 77.48,17.39 76.93,17.94 75.68,17.94 75.23,18.39 74.87,18.39 74.83,18.34 69.78,18.34 69.59,18.53 69.24,18.53 68.98,18.28 68.98,18.22 68.44,17.67 67.03,17.67 66.48,17.12 52.6,17.12 51.94,17.78 49.27,17.78 48.21,18.85 v1(48.21,20.58)
  BOTTOM w0.102: R4014.1 40.67,35.36 44.02,35.36 44.48,35.82 45.5,35.82 45.95,35.36 U2401.100 45.95,33.94 45.92,33.91 45.67,33.66 45.67,33.3 46.33,32.64 47.61,32.64 49.96,30.28 49.96,28.7 50.67,27.99 50.67,27.28 47.04,23.65 47.04,21.87 46.8,21.63 46.8,21.02 47.24,20.58 v1(48.21,20.58) ; R4008.1 88.62,75.52 89.29,74.86 v2(93.98,74.86) 96.18,74.86 101.57,69.46 101.57,18.54 102.35,17.76 103.49,17.76 106.73,14.52 106.73,13.7 v1(106.47,13.43)
1D8V_SPI_S5: length 10.2
  TOP w0.508: v1(78.94,25.86) 78.94,25.6 79.48,25.07 v2(79.48,23.5) 79.48,22.38 78.04,20.94 78.04,19.04 78.4,18.68 R2540.1 78.91,18.68 79.53,18.06 v1(79.53,17.43)
3D3V_AUX_KBC: length 170.2
  TOP w0.305: 54.94,33.93 54.94,33.28 ; 54.94,33.28 54.88,33.22 RN2407.4 ; 54.94,33.28 55.21,33.28 55.49,33 RN2407.3 ; v1(40.61,20.5) 40.92,20.19 41.99,20.19 42.36,20.57 42.38,20.57 42.8,21 RN2404.2
  TOP w0.356: v1(40.61,20.5) 40.69,20.5 41.12,20.93 41.12,20.96 41.78,21.62 41.81,21.62 RN2404.1
  TOP w0.508: v1(76.54,17) 76.25,17.29 76.25,17.84 75.17,18.92 73.6,18.92 71.75,20.77 v1(71.75,23.5) ; 54.94,33.93 55.86,34.85 55.86,36.1 55.9,36.14 55.9,37.21 56.16,37.48 56.16,38.55 55.34,39.37 52.88,39.37 51.94,38.43 v1(51.94,38.41) 51.41,37.87 46.16,37.87 45.73,38.3 44.37,38.3 43.99,38.69 41.4,38.69 40.39,37.67 36.2,37.67 35.56,37.03 35.56,36.07 36.45,35.18 37.54,35.18 38.25,34.47 R2409.2 38.71,33.99 39.22,33.48 R2608.1 39.45,33.07 40.77,31.75 42.32,31.75 43.11,30.96 R2410.1 43.74,30.08 44.15,29.67 44.15,27.36 R2463.1 44.3,27.03 44.75,26.57 45.3,26.57 45.82,26.05 45.82,25.44 46.53,24.72 46.53,23.27 46.45,23.18 46.45,23.16 46.38,23.09 v1(46.38,22.51) ; v1(63.07,26.85) 62.77,26.55 62.77,25.12 63.42,24.47 63.42,22.49 63.41,22.48 63.41,21.77 63.42,21.76 63.42,21.08 v2(62.4,20.06) 61.59,19.25 v1(61.59,18.85)
  L3 w0.508: v1(40.61,20.5) 40.91,20.2 40.91,19.8 42.72,18 45.59,18 48.12,15.47 50.23,15.47 50.56,15.14 71.6,15.14 71.66,15.09 74.63,15.09 v1(76.54,17) ; v1(71.75,23.5) 71.86,23.6 75.42,23.6 75.89,24.08 79.93,24.08 81.07,22.94 81.22,22.94 84.59,19.56 91.39,19.56 93.75,17.2 v1(94.74,17.2) ; v1(72.51,25.76) 71.91,26.36 66.81,26.36 66.02,27.15 63.8,27.15 63.5,26.85 v1(63.07,26.85)
  L4 w0.508: v1(40.61,20.5) 41.89,21.77 44.99,21.77 45.72,22.51 v1(46.38,22.51)
  BOTTOM w0.508: R2407.1 61.04,18.85 v1(61.59,18.85) ; R2615.1 51.72,38.64 v1(51.94,38.41) ; D4302.2 99.24,16.88 D4303.2 95.92,16.74 95.2,16.74 v1(94.74,17.2) 94.69,17.2 94.37,16.88 D4301.2 ; v1(63.07,26.85) 63.07,27.56 62.56,28.07 R2408.2 62.41,28.3 R2490.1 ; Q2404.D 40.41,20.9 40.61,20.7 v1(40.61,20.5)
3D3V_AUX_S5: length 473.3
  TOP w0.508: v1(137.01,38.71) 137.19,38.53 PR4435.1 137.25,38.05 137.27,38.03 PR4449.1 ; v1(36.25,34.37) 37.24,34.37 40.49,31.12 41.71,31.12 43.51,29.31 43.51,26.35 43.76,26.09 43.76,25.67 44.14,25.3 44.66,25.3 45.57,24.39 45.57,24.35 45.67,24.25 v1(45.67,23.95) ; v1(85.39,95.02) 86.49,95.02 v2(87.21,94.3) v1(90.45,91.06) 90.5,91.01 90.86,91.01 v1(92.91,88.95)
  L3 w0.508: v1(88.64,80.83) 88.64,81.1 89.01,81.48 89.24,81.48 91.7,83.94 91.7,84.84 93.61,86.76 93.61,86.97 93.81,87.16 93.81,87.88 92.91,88.77 v1(92.91,88.95) ; v1(90.45,91.06) 93.57,94.18 94.89,94.18 96.82,96.12 99.26,96.12 100.91,94.46 104.8,94.46 105.87,95.53 105.87,95.82 106.77,96.72 116.71,96.72 117.07,96.37 125.29,96.37 125.34,96.42 129.5,96.42 130.18,95.74 130.18,95.22 129.92,94.96 v1(129.92,94.24) 129.89,94.24 129.06,93.41 129.06,92.43 133.12,88.37 133.12,78.55 133.6,78.07 133.6,77.19 133.38,76.96 133.38,74.75 133.58,74.55 133.58,70.61 133.48,70.51 133.48,68.06 136.86,64.68 136.86,63.27 136.32,62.74 135.43,62.74 133.17,60.48 133.17,59.03 133.15,59 133.15,45.01 132.59,44.45 132.59,39.87 133.75,38.71 v1(137.01,38.71) ; v1(36.25,34.37) 35.85,33.97 34.4,33.97 33.55,34.83 32.05,34.83 31.56,35.32 27.92,35.32 22.61,40.63 22.61,47.04 22.4,47.25 22.4,48.9 22.5,49 22.5,50.01 22.66,50.17 22.66,50.73 23.1,51.18 v1(23.32,51.18) ; v1(43.39,20.03) 42.82,20.6 42.82,21.4 41.56,22.66 v1(41.35,22.66) ; v1(142.6,31.42) 142.6,30.19 143.48,29.3 143.48,13.69 135.05,5.26 125.73,5.26 122.63,8.36 122.51,8.36 121.91,8.95 117.72,8.95 117,8.23 109.32,8.23 109.3,8.26 74.6,8.26 73.41,9.45 58.94,9.45 54.5,5.01 v1(49.68,5.01) 39.27,5.01 38.37,5.9 32.46,5.9 32.2,5.65 15.07,5.65 12.31,8.41 8.48,8.41 7.97,8.92 7.97,13.61 7.46,14.12 v1(6.59,14.12)
  L4 w0.457: v1(43.39,20.03) 43.4,20.02 43.4,19.06 46.89,15.57 46.89,12.05 v1(46.69,11.85)
  L4 w0.508: v1(67.13,24.97) 67.13,24.81 66.64,24.32 66.04,24.32 64.14,26.21 60.92,26.21 59.93,27.21 57.32,27.21 57.21,27.31 55.16,27.31 54.1,26.25 52.85,26.25 50.93,24.33 49.36,24.33 48.79,23.76 46.69,23.76 ; v1(55.3,77.6) 55.3,79.06 55.69,79.45 56.03,79.45 57.25,80.67 58.18,80.67 58.8,81.3 58.8,82.62 60.3,84.12 60.3,87.15 60.78,87.64 60.78,87.65 60.8,87.67 60.8,88.39 60.4,88.79 60.4,90.63 60.28,90.75 60.28,91.47 61.04,92.23 61.04,93.04 62.59,94.59 66.02,94.59 66.83,93.79 v1(66.83,93.35) ; v1(142.6,31.42) 142.9,31.42 143.41,31.93 143.41,33.37 143.1,33.67 143.1,35.13 140.16,38.08 137.64,38.08 v1(137.01,38.71)
  BOTTOM w0.203: 44.67,24.95 U2401.75 42.4,24.95 ; 45.45,24.17 45.45,24.17
  BOTTOM w0.305: v1(46.69,11.85) 46.69,10.81 47.17,10.33 47.17,9.76 48.13,8.81 48.51,8.81 49.68,7.63 v1(49.68,5.01) ; R2473.1 43.73,18.84 43.51,19.06 43.51,19.07 43.39,19.19 v1(43.39,20.03) ; R2514.1 131.31,94.54 130.89,94.12 Q2501.2 130.04,94.12 v1(129.92,94.24) 129.6,94.24 128.63,93.27 R2513.2 ; RN1706.3 53.47,77.1 53.62,77.24 54.03,77.24 54.12,77.15 ; v1(41.35,22.66) 41.35,23.41 Q2404.S 41.36,23.91 42.4,24.95 ; 54.12,77.15 54.12,77.34 54.38,77.6 v2(54.59,77.6) v1(55.3,77.6) ; 54.12,77.15 RN1706.4 ; v1(67.13,24.97) 67.26,24.97 67.36,24.87 PR5413.1 ; v1(6.59,14.12) 6.62,14.15 PG4524.1 ; v1(36.25,34.37) 36.87,33.74 R2472.1 37.53,33.58 C2403.1 38.48,33.58 38.53,33.63 R2614.1 39.45,32.95 R2489.2 ; R4013.1 88.62,80.8 88.64,80.82 v1(88.64,80.83) ; 44.67,24.95 45.45,24.17 ; PR4409.1 142.72,31.32 142.62,31.42 v1(142.6,31.42) ; v1(23.32,51.18) 23.08,51.18 22.8,50.9 PR4450.1 ; v1(66.83,93.35) 67.91,94.43 81.49,94.43 81.67,94.61 v2(84.55,94.61) 84.96,95.02 v1(85.39,95.02) ; 45.45,24.17 v1(45.67,23.95)
3D3V_CAMERA_S0:
  vias: v2(68.58,84.68)
3D3V_CARD: length 19.1
  TOP w0.762: v1(6.68,37.21) 6.76,37.14 v2(8.23,37.14) 14.21,37.14 14.66,37.58 14.66,37.66 15.05,38.05 15.68,38.05 16.94,36.79 v2(16.94,33.32) 16.94,32.11 16.21,31.38 16.21,29.62
  BOTTOM w0.66: SD1.6 14.92,26.1
  vias: v1(16.21,27)
3D3V_CARD_S0: length 0.8
  BOTTOM w0.305: 11.46,37.47 11.69,37.7 U3301.4
  vias: v2(10.31,36.86)
3D3V_GSEN2: length 16.3
  TOP w0.254: C6901.1 94.13,84.31 94.77,84.31 94.78,84.3 95.2,84.3 95.23,84.33 95.26,84.33 95.39,84.46 U6901.9 ; C6901.1 94.11,85.27 R6901.2 94.23,85.99 94.26,86.02 v2(94.26,86.29) 94.35,86.19 95.32,86.19 v1(95.38,86.14) ; C6901.1 94.11,83.69 C6902.1 94.59,83.29 95.2,83.9 U6901.10 ; R6902.1 99.75,85.96 99.87,86.08 v1(99.9,86.08) 100.46,85.52 v2(100.46,85.46) 100.46,85.03 99.7,84.28 R6905.1
  L3 w0.254: v1(95.38,86.14) 95.43,86.19 95.53,86.19 95.95,86.62 95.96,86.62 96.09,86.74 99.24,86.74 v1(99.9,86.08)
3D3V_LCDVDD_S0: length 1
  TOP w0.508: v1(62.27,81.39) 62.15,81.52 C5521.1
  vias: v2(64.19,81.84)
3D3V_MSATA_S0: length 3.7
  BOTTOM w0.635: HDD1.P1 150.36,32.76 ; HDD1.P1 149.6,33.45 ; HDD1.P1 148.84,32.76 ; 148.84,31.49 HDD1.P2 150.36,31.49
  vias: v2(146.3,30.69) v2(147.15,35.95)
3D3V_S0: length 448.7
  TOP w0.076: 51.8,89.57 51.8,89.57 U6304.G2 ; 51.8,89.57 51.65,89.57 51.65,89.57 51.26,89.57 51.19,89.64 ; 51.8,89.57 U6304.F2 ; 53.3,92.55 53.3,91.72 53.45,91.57 53.8,91.57 U6304.C6 ; U6304.J3 52.44,88.32 52.19,88.57 51.94,88.57 51.94,88.58 51.79,88.58 U6304.H1 ; U6304.D4 53.3,90.57 53.86,90.57 v4(54.08,90.35)
  TOP w0.152: U6304.K8 55.05,87.48 55.07,87.46 55.07,87.4 55.17,87.3 55.17,87.18 55.34,87.01 ; 50.61,89.47 50.78,89.64 51.19,89.64
  TOP w0.203: v4(54.08,90.35) 54.11,90.32 U6304.E7 ; U6304.H1 51.29,88.82 51.19,88.72 50.81,88.72 50.72,88.82 50.52,88.82 50.48,88.79 v1(50.37,88.9) 50.37,89.23 50.61,89.47 ; 53.3,92.55 52.98,92.86 52.98,93.03 52.59,93.42 52.24,93.42
  TOP w0.305: DB1.10 53.19,33.84 53.02,33.67 53.02,33.24 53.11,33.15 v1(53.11,33.12) ; 45.49,16.38 45.13,16.75 RN2403.2 ; 45.49,16.38 45.44,16.33 44.73,16.33 44.48,16.58 RN2403.1 ; 45.49,16.38 45.82,16.05 45.82,15.26 45.72,15.16 45.72,15.05 v1(45.62,14.95)
  TOP w0.356: 76.28,38.13 76.76,38.13 76.93,38.3 RN811.2 ; 76.28,38.13 76.28,31.75 77.19,30.84 77.19,27.54 77.05,27.39 77.05,23.67 77.11,23.61 v1(77.11,23.44) ; 76.28,38.13 RN811.1
  TOP w0.381: R2478.1 41.46,26.74 40.77,27.43 39.97,27.43
  TOP w0.508: 32.21,37.85 32.21,38.13 34.49,40.41 34.52,40.41 34.57,40.46 34.57,44.31 33.84,45.05 33.84,45.96 PR4620.1 33.81,45.98 33.27,46.51 v1(33.27,46.78) ; 32.21,37.85 R2607.2 ; 32.21,37.85 31.07,38.98 29.08,38.98 28.35,38.25 28.35,37.44 v1(29.16,36.63) ; R2423.1 58.96,24.06 58.92,24.01 EC8905.1 58.29,24.13 R2475.1 57.51,23.29 57.56,23.24 v1(57.56,23.22) ; R2716.1 153.87,95.15 154.56,95.83 154.56,96.52 v1(154.89,96.85) ; v1(144.73,56.26) 139.94,56.26 v1(139.05,55.38) ; 129.92,66.68 129.92,69.45 129.69,69.67 129.69,72.77 130.23,73.31 FC8918.1 130.23,83.01 R1209.1 126.03,83.85 125.41,84.46 125.22,84.46 124.57,85.12 R1207.1 124.57,85.53 124.02,86.09 v1(124.02,86.32) ; 129.92,66.68 131.04,65.56 131.62,65.56 131.7,65.64 135.09,65.64 135.27,65.81 139.22,65.81 v1(139.78,66.37) 140.56,65.58 140.56,65.46 141.53,64.49 143.64,64.49 ; 129.92,66.68 R1205.1 ; EC8903.1 19.3,85.8 19.56,86.06 20.42,86.06 v1(20.49,85.98) ; 52.24,93.42 51.93,93.73 C6320.1 51.74,93.78 51.74,94.03 51.36,94.41 C6330.1 51.36,95.07 51.87,95.58 54.18,95.58 R6361.1 54.51,95.86 58.34,95.86 R6364.1 R6356.1 59.74,95.53 60.66,94.62 60.66,94.24 60.71,94.18 60.71,94.03 60.81,93.93 60.81,93.85 60.83,93.83 60.83,92.97 ; v1(91.92,87.86) 92.63,87.15 92.63,86.13 R6901.1 93.37,86.92 95.31,88.86 v1(95.31,89.1) 95.39,89.18 95.63,89.18 95.89,89.44 97.61,89.44 ; v1(65.57,20.14) 65.57,20.15 64.9,20.83 64.9,21.67 64.97,21.75 64.97,22.27 64.9,22.35 64.9,23.34 64.5,23.74 64.5,25.06 64.49,25.07 64.49,25.85 64.48,25.85 64.48,27.31 64.42,27.37 64.42,27.4 63.75,28.07 63.75,29.27 63.42,29.6 63.42,30.54 62.92,31.05 v1(62.92,31.37) 62.92,31.42 62.8,31.53 62.8,33.36 64.31,34.87 64.31,35.71 64.39,35.79 64.39,36.45 64.52,36.58 64.52,36.93 v1(65.43,37.85) 65.88,38.3 65.88,46.64 63.5,49.01 R1708.1 ; 103.73,74.68 v1(88.47,74.68) 87.63,74.68 86.89,75.41 83.84,75.41 83.21,76.04 v1(83.21,76.43) ; v1(13.28,76.02) 13.28,75.63 13.52,75.4 FC1003.1 13.59,75.21 R5719.1 13.62,74.47 EC8902.1 13.71,73.74 14.34,73.74 14.86,73.22 v1(14.86,73.03) ; C1201.1 137.16,80.11 v1(136.37,80.11) ; PR4611.1 32.82,58.1 v1(33.36,58.65)
  L3 w0.508: v1(87.22,66.73) 87.22,67.74 86.54,68.43 86.54,70.82 88.89,73.17 88.89,74.26 v1(88.47,74.68) ; v1(151.81,85.31) 151.81,85.45 153.7,87.33 153.7,87.4 154.74,88.44 155.03,88.44 155.57,88.99 155.57,92.79 154.43,93.93 154.43,96.39 v1(154.89,96.85) ; v1(81.25,73.41) 81.81,72.85 81.81,69.59 81,68.78 81,65.33 81.1,65.23 81.1,60.86 81.17,60.79 81.17,59.53 80.39,58.75 80.39,56.43 v1(78.79,54.83) ; v3(8.03,36.1) 7.82,36.3 7.82,39.35 8.53,40.06 8.53,42.6 9.5,43.57 v1(10.14,43.57) ; v1(50.37,88.9) 49.2,87.73 42.29,87.73 42.09,87.94 41.45,87.94 v1(41.35,88.04) 40.07,88.04 38.02,85.99 38.02,85.02 v1(38.13,84.91) ; v3(51.57,13.56) 51.56,13.56 51.39,13.4 51.13,13.4 51.05,13.48 48.84,13.48 48.31,14.01 46.8,14.01 45.86,14.95 v1(45.62,14.95) ; v1(22.4,86.06) 22.02,86.44 20.95,86.44 v1(20.49,85.98) 20.42,86.06 19.05,86.06 18.16,85.17 15.42,85.17 14.73,84.48 14.73,83.72 v1(12.57,81.56) 14.22,79.91 14.22,76.96 v1(13.28,76.02)
  L4 w0.381: v1(40.67,7.7) 41.66,8.69 41.66,11.83 44.84,15.01 45.57,15.01 v1(45.62,14.95)
  L4 w0.508: v1(65.57,20.14) 64.92,20.14 64.77,20.3 60.8,20.3 59.11,21.99 59.11,22.03 59.06,22.08 59.06,22.19 58.05,23.2 57.89,23.2 57.88,23.22 v1(57.56,23.22) ; v1(33.36,58.65) 31.08,58.65 28.73,56.29 28.73,55.75 28.82,55.67 28.82,53.99 26.97,52.15 26.97,49.81 27.25,49.53 27.26,49.53 27.64,49.16 27.64,49.15 28.07,48.72 31.56,48.72 33.27,47 v1(33.27,46.78) ; v1(136.37,80.11) 136.88,79.61 136.88,78.79 138.38,77.29 138.38,71.82 139.39,70.82 139.61,70.82 139.98,70.45 139.98,66.63 139.78,66.42 v1(139.78,66.37) 139.78,66.12 141.73,64.16 141.73,60.76 143.71,58.78 143.71,57.28 v1(144.73,56.26) ; v1(65.43,37.85) 65.28,38 v1(62.38,38)
  BOTTOM w0.203: 59.71,32.15 U2401.4
  BOTTOM w0.279: DIMM1.255 123.47,85.62 124.02,86.17 v1(124.02,86.32)
  BOTTOM w0.305: v1(78.79,54.83) 78.4,54.44 CPU1.AJ19 ; 149.36,52.8 149.08,53.08 U6001.10 ; v1(41.35,88.04) 41.1,87.78 40.44,87.78 40.2,87.55 PU6301.7 ; v1(45.62,14.95) 45.59,14.99 44.84,14.99 44.64,14.78 R4006.1 ; RN1703.2 93.61,65.12 93.75,65.27 93.75,65.61 93.57,65.79 RN1703.1 93.02,66 92.72,66.3 91.71,66.3 91.34,65.94 88.32,65.94 87.53,66.73 v1(87.22,66.73) ; v1(136.37,80.11) 136.44,80.05 IOBD1.36 ; PU6301.3 39.7,84.83
  BOTTOM w0.356: v1(38.13,84.91) 38.38,84.66 39.53,84.66 39.7,84.83 ; v1(78.79,54.83) 79.28,55.32 CPU1.AL21
  BOTTOM w0.457: v1(83.21,76.43) 81.64,74.86 81.64,73.79 v1(81.25,73.41) 80.57,72.72 80.57,71.35 80.87,71.05 80.69,71.05 80.52,70.87 80.44,70.87 80.26,70.69 80.26,69.85 80.08,69.67 R2005.1 ; v4(54.08,90.35) 54.43,90.35 54.89,89.89 54.89,89.25 53.24,87.6 v1(53.24,86.44)
  BOTTOM w0.508: R6004.1 139.5,55.83 v1(139.05,55.38) 139.36,55.07 R6003.1 140.54,54.99 140.54,54.36 R6011.1 ; R1715.1 R1713.1 87.91,75.47 88.47,74.91 v1(88.47,74.68) ; Q5703.G 14.72,72.88 v1(14.86,73.03) ; R2422.1 63.12,30.61 62.92,30.81 v1(62.92,31.37) 62.59,31.37 62.38,31.57 C2433.1 61.67,31.8 C2432.1 60.48,32.15 60.33,32.15 60.3,32.18 59.74,32.18 59.71,32.15 ; v1(22.4,86.06) 23.47,84.99 R6354.1 28.85,85.42 U6305.8 30.21,85.42 31,84.63 31,84.28 32.4,82.88 U6305.3 35.16,82.88 36.37,84.1 PC6302.1 37.29,84.43 PC6305.1 37.52,84.36 37.67,84.36 38.13,84.81 v1(38.13,84.91) ; v1(40.67,7.7) 41.55,8.58 R6513.2 ; v1(10.14,43.57) 10.14,43.62 10.69,44.17 R3307.1 ; v1(53.24,86.44) 51.69,86.44 50.34,87.78 50.34,88.88 v1(50.37,88.9) ; R2420.1 61.44,37.49 R2400.1 61.95,37.57 v1(62.38,38) ; v1(150.34,51.08) 150.16,51.26 R6002.1 150.06,52.43 149.73,52.43 149.36,52.8 ; R2004.1 81.71,72.95 v1(81.25,73.41) ; 80.87,71.05 R2006.1 ; v1(13.28,76.02) 13.36,76.02 13.86,76.52 Q5705.G ; Q5708.C 15.42,79.05 13.53,80.94 13.08,80.94 12.57,81.45 v1(12.57,81.56) 12.82,81.56 Q5701.G ; v1(95.31,89.1) 95.49,89.1 95.99,89.61 R7005.1 95.99,91.48 AFTP6601.1 ; v3(8.03,36.1) R3302.1 ; v1(65.57,20.14) 65.57,20.15 65.33,20.4 R2499.1
  vias: v1(36.83,29.31) v1(38.07,28.91) v1(39.5,27.99) v1(63.07,78.06) v1(63.12,77.32) v1(68,79.43) v1(67.97,78.64) v1(151.16,54.18) v1(151.32,84.74) v2(22.18,36.5) v2(53.01,10.31) v2(65.31,84.98) v2(107.44,90.03) v2(142.87,11.75) v2(145.84,39.16) v3(15.75,33.28) v3(37.34,28.75) v3(38.13,28.17) v3(38.76,27.59) v3(38.91,28.48) v3(52.62,13.66) v3(53.69,13.69) v3(98.37,22) v3(98.73,22.76) v3(99.31,21.87) v3(99.57,22.68) v3(107.95,2.41) v3(108.84,1.6) v3(109.09,2.49) v3(147.65,40.44) v3(148.34,37.31) v3(148.72,73.36) v3(148.72,72.47)
3D3V_S5: length 422
  TOP w0.508: v1(50.52,70.11) 51.34,70.11 v2(51.87,70.63) 54.94,73.7 54.94,74.23 52.29,76.88 50.35,76.88 48.88,78.35 44.51,78.35 43.71,79.15 43.71,79.44 43.16,79.99 v2(41.41,79.99) 37.52,79.99 37.52,79.99 34.19,79.99 v1(34.14,79.94) ; C1058.1 v1(78.59,64.59) 77.88,65.31 77.88,66.17 76.07,67.97 75.06,67.97 73.63,69.4 73.63,71.88 72.17,73.35 ; v1(61.93,34.62) 61.93,35.69 64.97,38.74 64.97,46.29 61.4,49.86 v1(60.07,49.86) ; v1(61.19,68.33) 59.49,66.63 59.49,63.56 FC1001.1 59.49,63.43 59.49,60.73 60.63,59.59 R1707.1 R2001.1 61.87,58.56 62.15,58.28 62.15,57.28 v1(61.44,56.57) 61.47,56.54 62.48,56.54 ; v1(11.33,17.32) 11.33,17.24 10.3,16.21 9.14,16.21 7.33,14.4 7.33,12.22 6.68,11.57 6.68,11.14 6.53,10.99 6.53,10.47 6.68,10.32 6.68,9.67 v1(6.31,9.3) ; R1735.1 63.5,51.23 R1760.1 63.37,51.93 R1759.1 R1703.1 63.07,53.09 v1(62.57,53.58) 62.87,53.88 62.87,54.43 R1710.1 62.89,54.76 62.36,55.3 62.36,56.42 62.48,56.54 ; v1(48.77,21.31) 48.84,21.24 48.84,20.24 R2471.1 ; 133.05,83.62 130.91,81.48 130.91,73.08 130.33,72.49 130.33,69.95 130.56,69.72 130.56,67.56 131.28,66.83 v1(131.37,66.83) ; LIDSW1.2 4.85,40.16 6.86,42.17 6.86,43 7.32,43.46 C6702.1 8.23,43.46 R6701.2 8.31,43.74 8.1,43.95 8.1,44.69 7.88,44.91 7.83,44.91 7.73,45.01 7.04,45.01 v1(6.92,45.12) ; 62.48,56.54 62.59,56.44 R2003.1 ; C1060.1 78.18,54.35 78.18,54.74 v1(77.95,54.97) 77.8,55.12 77.8,55.9 C1059.1 ; 18.12,75.52 18.12,77.33 R5701.1 ; 18.12,75.52 19.76,75.52 21.97,77.73 22.66,77.73 23.83,78.89 25.53,78.89 v1(26.21,79.58) ; 18.12,75.52 18.12,73.49 15.63,71 13.8,71 FC1002.1 13.52,70.91 8.38,65.77 8.38,64.71 8.75,64.34 9.49,64.34 v1(10.09,64.94) 10.19,65.03 10.19,66.19 10.79,66.8 13,66.8 v1(13.34,66.47) ; v3(70.11,73.7) 71.91,73.7
  L3 w0.508: v1(48.77,21.31) 48.83,21.31 49.2,21.68 49.2,22.51 47.12,24.59 42.8,24.59 40.44,26.95 39.37,26.95 39.18,26.76 37.77,26.76 36.37,28.16 v3(36.37,28.73) ; v1(78.59,64.59) 78.79,64.39 78.79,63.88 80.07,62.6 80.07,61.02 80.56,60.53 80.56,59.81 79.78,59.03 79.78,56.8 v1(77.95,54.97) ; v3(70.11,73.7) 66.62,73.7 63.1,70.18 61.72,70.18 60.88,69.34 60.88,68.63 v1(61.19,68.33) 60.99,68.12 56.37,68.12 55.13,69.37 51.26,69.37 v1(50.52,70.11) ; v1(6.31,9.3) 6.31,3.56 8.81,1.06 11.79,1.06 15.41,4.68 33.62,4.68 33.97,5.02 37.86,5.02 v1(38.11,5.27) ; v1(26.21,79.58) 26.21,79.11 28.24,77.07 28.24,75.18 27.82,74.75 27.16,74.75 25.17,72.76 25.17,71.18 26.72,69.63 26.72,68.48 24.38,66.14 24.38,66.09 22.61,64.31 22.61,64.29 22.1,63.78 22.1,57.09 22.06,57.06 22.06,56.99 21.69,56.62 21.62,56.62 21.48,56.48 v1(21.29,56.48) 21.41,56.35 21.41,55.07 20.73,54.38 20.73,51.03 20.57,50.88 20.57,50.22 19.56,49.2 19.56,49.17 19.49,49.1 v1(19.49,48.11) 19.49,47.09 19.58,46.99 19.58,45.85 v1(20.71,44.72)
  L4 w0.254: v1(52.06,11.63) 52.06,11.58 51.28,10.8 47.03,10.8 46.18,11.64 46.18,12.07 46.22,12.11 46.22,15.46 44.74,16.94 42.29,16.94 v1(41.94,16.59)
  L4 w0.406: 40.94,9.81 40.94,13.98 41.94,14.98 v1(41.94,16.59)
  L4 w0.508: v1(6.92,45.12) 7.88,46.08 11.23,46.08 11.8,45.51 13.98,45.51 15.09,46.62 v1(15.09,48.74) ; v1(26.21,79.58) 26.37,79.58 26.95,79 27.51,79 28.09,79.58 29.22,79.58 30.44,80.8 33.63,80.8 34.14,80.29 v1(34.14,79.94) ; v1(38.11,5.27) 42.54,5.27 43.05,5.78 43.05,7.7 v1(43.37,8.02) 42.64,8.02 41.53,6.91 40.36,6.91 39.7,7.57 39.7,8.56 40.94,9.81 ; v1(131.37,66.83) 131.11,66.83 130.73,66.46 130.73,42.62 131.41,41.95 v1(131.41,40.31)
  BOTTOM w0.305: IOBD1.37 136.52,79.55 v1(136.25,79.28) ; R2444.1 51.01,36.96 51.93,37.87 52.17,37.87 52.78,38.48 52.86,38.48 ; v1(61.93,34.62) 61.93,34.51 62.14,34.29 62.14,33.72 62.47,33.39 U2404.6
  BOTTOM w0.356: CPU1.AL19 78.07,54.99 77.98,54.99 v1(77.95,54.97) 77.95,54.87 CPU1.AJ17
  BOTTOM w0.508: R6501.1 43.13,8.25 v1(43.37,8.02) ; PR4901.1 50.06,70.11 v1(50.52,70.11) ; R2434.1 49.07,38.15 50.34,39.42 51.92,39.42 52.86,38.48 v1(52.89,38.48) ; PR4448.2 20.73,55.73 21.29,56.29 v1(21.29,56.48) ; R4010.2 61.57,67.95 v1(61.19,68.33) 61.21,68.35 62.04,68.35 62.37,68.68 R4011.2 ; R1738.1 v1(61.44,56.57) R1709.1 ; PR4513.1 v1(11.33,17.32) ; v1(15.09,48.74) 15.28,48.56 19.04,48.56 v1(19.49,48.11) ; v1(61.93,34.62) 61.93,35.05 62.1,35.23 C2445.1 ; PR5303.1 v1(131.41,40.31) ; v1(26.21,79.58) 26.21,78.94 27.61,77.55 PR5203.1 ; PR4472.1 21.11,43.94 21.11,44.32 v1(20.71,44.72) ; 58.98,52.69 58.98,50.78 R1711.1 59,50.42 59.56,49.86 v1(60.07,49.86) R1702.1 R1733.1 ; PR4306.1 v1(13.34,66.47) ; PD4303.2 v1(10.09,64.94)
  vias: v1(139.22,68.99) v2(111.57,97.79) v2(111.96,93.32) v3(35.69,29.24) v3(104.75,87.05) v3(105.59,87.09) v3(112.11,22.99) v3(112.37,23.79) v3(112.52,95.76) v3(113.01,23.15) v3(113.39,95.76) v5(36.31,32.13) v5(36.91,31.78)
3D3V_WLAN_S0: length 3.1
  TOP w0.305: R6111.1 159.95,77.99 AFTP6101.1 159.26,77.29 v3(159.26,76.91)
  TOP w0.508: R6112.1 162.99,83.29 v1(162.84,83.43)
  vias: v3(150.75,73.86) v3(151.76,73.86) v3(165.23,94.31) v3(166.12,94.31)
25M_48M_OSC: length 1.3
  TOP w0.089: TP1608.1 72.64,56.6 v1(72.99,56.26)
  BOTTOM w0.089: CPU1.AL8 72.6,55.87 v1(72.99,56.26)
48M_X1: length 8
  BOTTOM w0.089: CPU1.F2 68.88,42.07 68.58,42.37 68.32,42.37 68.03,42.07 67.3,42.07 66.89,42.47 v2(65.73,42.47) 64.62,42.47 R1624.1 64.21,42.75 63.6,42.14 C1601.2 63.17,42.14 63.07,42.24 62.89,42.24 62.35,42.78 X1601.3
48M_X2: length 5.1
  BOTTOM w0.089: CPU1.F1 68.22,41.84 67.04,41.84 66.95,41.76 66.14,41.76 66.06,41.84 64.38,41.84 R1624.2 64.34,41.08 R1625.2
+DC_IN:
  vias: v2(23.85,71.21) v3(22.94,69.09) v3(22.96,69.95) v3(23.8,69.95) v3(23.8,69.09) v3(24.64,69.95) v3(24.64,69.09) v3(25.48,69.12)
+DC_IN_C:
  vias: v2(22.12,74.86) v2(26.28,76.15) v3(22.25,73.38) v3(22.96,74.22) v3(23.52,75.21) v3(23.83,74.27) v3(24.59,75.54) v3(24.74,74.27) v3(25.37,74.83) v3(25.45,75.67) v3(26.19,77.8) v3(26.24,76.96)
+RTC_PWR: length 23.6
  BOTTOM w0.508: R2501.2 131.32,100.69 v2(131.56,100.45) 132.45,100.45 133.79,101.79 151.14,101.79 152.43,100.5 RTC1.1
+VCHGR:
  vias: v2(135.83,8.88)
AC_DIS_R: length 5.9
  TOP w0.254: v1(129.94,15.08) 130.04,15.08 130.51,15.55 130.51,15.6 130.76,15.84 130.76,15.85 v2(130.77,15.87)
  BOTTOM w0.254: PR4444.2 129.38,15.74 130.35,15.74 PC4471.1 130.42,15.58 129.94,15.1 v1(129.94,15.08) 131.9,15.08 132.15,15.33 PQ4412.G
AC_PRES_KBC: length 41.9
  TOP w0.102: v1(60.76,32.73) 60.76,32.73 60.94,32.9 60.94,35.62 64.33,39.01 64.33,44.75 61.68,47.4 61.41,47.4 59.64,49.17 59.64,50.07 61.01,51.44 v2(61.01,54.35) 61.01,57.51 v1(61.52,58.02)
  L3 w0.102: v1(51.59,32.8) 51.75,32.8 52.15,32.4 54.76,32.4 55.08,32.73 v1(60.76,32.73)
  BOTTOM w0.102: R1734.1 61.57,57.89 61.52,57.94 v1(61.52,58.02) ; U2401.113 51.15,33.2 51.52,32.83 51.56,32.83 v1(51.59,32.8)
AC_PRES_R: length 8.5
  BOTTOM w0.102: CPU1.AH2 68.91,54.41 68.68,54.41 68.43,54.66 68.43,54.82 68.03,55.22 66.77,55.22 66.36,54.82 65.79,54.82 v2(65.79,54.82) 65.79,54.95 64.2,56.54 64.08,56.54 R1717.2 R1734.2
ACLIM: length 4.3
  TOP w0.127: v1(140.72,30.56) 140.8,30.64 141.17,30.64 v2(141.37,30.83) 141.01,31.19 PR4401.2 140.61,31.35 PR4403.1
  BOTTOM w0.127: v1(140.72,30.56) 140.72,31.17 140.06,31.82 PU4401.16
ACOK_IN: length 178
  TOP w0.254: v1(23.52,54.92) 23.55,54.94 23.55,55.25 23.6,55.3 PR4474.1 ; PR4418.1 PR4417.2 137.72,28.65 137.35,28.28 137.35,27.5 v2(137.34,27.5) 137.35,27.49 v1(137.35,26.82) ; v1(37.98,15.18) 37.77,15.39 37.77,15.57 37.73,15.61 37.73,17.25 38.16,17.68 38.16,18.59 38.7,19.13 38.7,19.13 38.97,19.4 38.97,22.04 38.71,22.3 38.71,22.3 37.67,23.34 37.67,24.21 37.52,24.36 37.52,27.13 36.58,28.07 35.64,28.07 27.46,36.25 27.32,36.25 26.54,37.03 v1(26.54,38.15)
  L3 w0.254: v1(26.54,38.15) 26.52,38.18 25.78,38.18 24.33,39.63 24.33,39.7 23.14,40.9 23.14,43.66 23.11,43.69 23.11,44.81 23.14,44.83 23.14,47.25 22.91,47.47 22.91,48.67 23.88,49.63 23.88,54.66 23.62,54.92 v1(23.52,54.92) ; v1(137.35,26.82) 133.13,26.82 132.31,25.99 132.31,24.67 132.44,24.54 132.44,18.86 127.9,14.33 127.46,14.33 123.22,10.09 117.24,10.09 116.65,9.5 75.11,9.5 74.02,10.59 58.36,10.59 57.3,9.53 49.39,9.53 v1(49.18,9.32) 48.97,9.53 45.47,9.53 44.21,10.79 39.79,10.79 38.63,11.95 38.63,13.96 38.73,14.06 38.73,14.42 v1(37.98,15.18)
  BOTTOM w0.254: PQ4405.2 23.98,55.75 23.6,55.37 23.6,55.3 23.55,55.25 23.55,54.94 v1(23.52,54.92) ; v1(49.18,9.32) 49.16,9.34 49.16,10.48 48.85,10.79 48.33,10.79 48.07,11.04 48.07,12.46 47.29,13.25 47.29,14.87 46.51,15.65 Q2405.G
AD+: length 215
  TOP w0.508: v1(11.68,67.85) 12.55,68.71 v2(13.85,68.71) 15.06,68.71 16.21,69.85 19.3,69.85 v1(20.24,68.91)
  L3 w0.508: v1(11.68,67.85) 11.93,67.6 11.93,65.75 15.39,62.28 15.39,50.02 14.45,49.07 14.45,47.53 14.92,47.06 14.92,45.88 15.61,45.19 15.61,44.27 16.26,43.62 16.26,42.61 14.86,41.21 14.86,38.65 15.59,37.92 15.63,37.92 16,37.55 16,37.36 22.05,31.32 24.18,31.32 25.83,29.67 30.23,29.67 30.66,29.24 32.56,29.24 32.94,28.86 32.94,22.13 33.78,21.29 35.7,21.29 37.17,19.82 37.17,17.67 37.14,17.65 37.14,16.38 36.2,15.44 36.2,13.58 36.71,13.08 36.79,13.08 39.69,10.17 41.7,10.17 42.78,9.09 45.19,9.09 45.72,8.56 57.04,8.56 57.57,9.09 57.58,9.09 58.57,10.09 73.69,10.09 74.88,8.89 109.58,8.89 109.59,8.87 116.74,8.87 117.45,9.59 123.8,9.59 127.3,13.08 129.5,13.08 129.87,13.45 129.87,13.79 133.15,17.07 v1(133.15,18.24)
  L4 w0.508: v1(20.24,68.91) 21.65,67.51 21.78,67.51 v1(22.23,67.06) ; v1(134.77,38.08) 134.82,38.03 135.04,38.03 136.14,36.92 136.14,33.53 132.82,30.2 v1(132.82,25.78) 132.66,25.78 132.23,25.36 132.23,23.9 132.59,23.55 132.59,18.8 v1(133.15,18.24)
  BOTTOM w0.508: v1(134.77,38.08) 134.98,38.28 135.03,38.28 135.18,38.43 PR4452.1 ; v1(132.82,25.78) 132.52,26.08 PD4410.1
AD+_G_1: length 2.5
  BOTTOM w0.254: PQ4405.5 23.98,58.57 PR4422.1 24.63,58.64 PQ4405.6
AD+_G_2: length 2.3
  BOTTOM w0.406: PQ4408.4 25.38,59.95 PR4441.2
  BOTTOM w0.508: PR4441.2 25.2,59.67 PR4422.2
AD+_R: length 8.1
  TOP w0.254: v1(135.05,14.62) v2(135.61,14.62)
  BOTTOM w0.254: PR4440.2 134.44,16.79 PQ4412.D 134.29,16.34 135.06,15.57 135.06,14.63 v1(135.05,14.62) 135.05,13.47 134.34,12.76 PQ4401.4
AD_IA: length 137.1
  TOP w0.089: v1(138.84,38.71) 137.77,38.71 137.34,39.14 136.8,39.14 136.3,38.64 132.8,38.64 130.75,36.59 130.75,19.16 125.34,13.75 109.8,13.75 109.22,14.33 108.63,14.33 107.87,15.08 v2(107.87,15.82) 107.87,16.63 107.66,16.84 v1(107.63,16.84)
  L3 w0.14: v1(50.01,27.71) 50.2,27.71 51.47,26.44 53.71,26.44 54.39,25.76 55.18,25.76 55.45,25.5 55.45,25.38 57.16,23.67 60.87,23.67 61.46,23.09 62.34,23.09 62.49,23.23 63.93,23.23 64.6,22.56 67.72,22.56 68.31,23.15 70.5,23.15 70.6,23.05 70.98,23.05 71.19,23.26 71.35,23.26 71.57,23.05 71.94,23.05 72.05,23.15 75.6,23.15 75.72,23.26 76.51,23.26 77.1,22.67 80.7,22.67 80.88,22.49 81.03,22.49 84.41,19.11 84.44,19.11 84.45,19.1 91.2,19.1 93.55,16.75 101.63,16.75 101.82,16.94 106.15,16.94 106.24,17.03 107.45,17.03 v1(107.63,16.84)
  BOTTOM w0.089: v1(50.01,27.71) 49.51,28.21 49.51,30.1 47.45,32.16 46.15,32.16 45.21,33.1 45.21,33.42 44.75,33.88 U2401.97 44.25,34.77 43.64,34.16 42.55,34.16 42.17,34.54 40.74,34.54 39.27,36.01 C2438.2 39.5,36.73 C2428.2 ; v1(138.84,38.71) PR4475.1 139.34,38 PC4402.1
AD_OFF_L: length 23.9
  TOP w0.254: v1(14.38,66.52) 14.61,66.52 v2(15.93,67.84) 16.52,68.43 19.57,68.43 19.73,68.28 27.08,68.28 29.01,70.21 v1(29.03,70.21)
  BOTTOM w0.254: v1(29.03,70.21) 29.03,69.78 29.11,69.7 29.11,68.15 29.26,68 29.26,66.78 28.75,66.27 27.67,66.27 27.59,66.35 26.71,66.35 PQ4305.1 ; PQ4304.3 13.89,66.04 v1(14.38,66.52)
AD_OFF_R: length 9.5
  BOTTOM w0.254: PU4301.4 25.24,67.6 25.98,66.85 27.16,66.85 28.01,66.85 28.03,66.83 PQ4305.3 28.27,67.18 27.76,67.69 PR4309.2 PC4301.2 PR4310.1 28.42,71.29 v2(28.79,71.66)
AGPIO3: length 11.3
  TOP w0.102: R2003.2 R2009.1 64.64,55.58 64.92,55.86 v2(64.93,55.86) 64.94,55.86 64.94,55.88 65.1,56.04 v1(65.1,56.39)
  L3 w0.102: v1(65.1,56.39) 65.2,56.49 65.2,56.82 65.43,57.05 66.14,57.05 66.27,56.92 67.55,56.92 69.19,55.29 69.54,54.94 69.87,54.94 70.38,55.44 70.38,55.48 70.61,55.71 71.05,55.71 v1(71.47,55.3)
  BOTTOM w0.102: v1(71.47,55.3) 71.8,54.97 CPU1.AJ7
AGPIO11: length 10.9
  TOP w0.102: R1710.2 64.18,54.64 v2(65.05,54.64) 65.26,54.64 65.37,54.74 65.37,55.69 v1(65.53,55.86)
  L3 w0.102: v1(65.53,55.86) 65.56,55.88 65.68,55.88 65.81,56.01 66.01,56.01 66.39,55.63 68.12,55.63 69.01,54.74 71.48,54.74 72.1,55.36 v1(72.15,55.36)
  BOTTOM w0.102: v1(72.15,55.36) 72.6,54.91 CPU1.AJ8
AGPIO92: length 7.7
  BOTTOM w0.102: v2(87.43,66.02) R1761.2 86.51,65.86 84.52,63.87 84.52,62.6 84.56,62.56 84.56,61.54 84.77,61.32 84.97,61.32 85.32,60.97 85.38,60.97 85.45,60.9 CPU1.AY32
AGPIO130: length 6.7
  BOTTOM w0.102: R1636.2 85.27,66.17 85.27,65.81 v2(84.96,65.51) 84.96,64.92 84.11,64.07 84.11,61.48 84.05,61.42 84.05,61.14 84.35,60.84 CPU1.AY30
ALERT#: length 4.1
  BOTTOM w0.102: R2605.2 92.22,16.66 92.22,17.89 92.91,18.58 v2(92.91,18.72) 92.63,19.01 U2601.6
APU_ALERT#: length 9.1
  BOTTOM w0.102: RN804.6 84.48,32.64 84.26,32.87 84.23,32.87 83.89,33.2 v2(83.79,33.2) 83.79,33.65 84.59,34.44 84.63,34.44 85.19,35 85.19,35.95 84.09,37.04 84.09,38.55 84.35,38.81 CPU1.A30
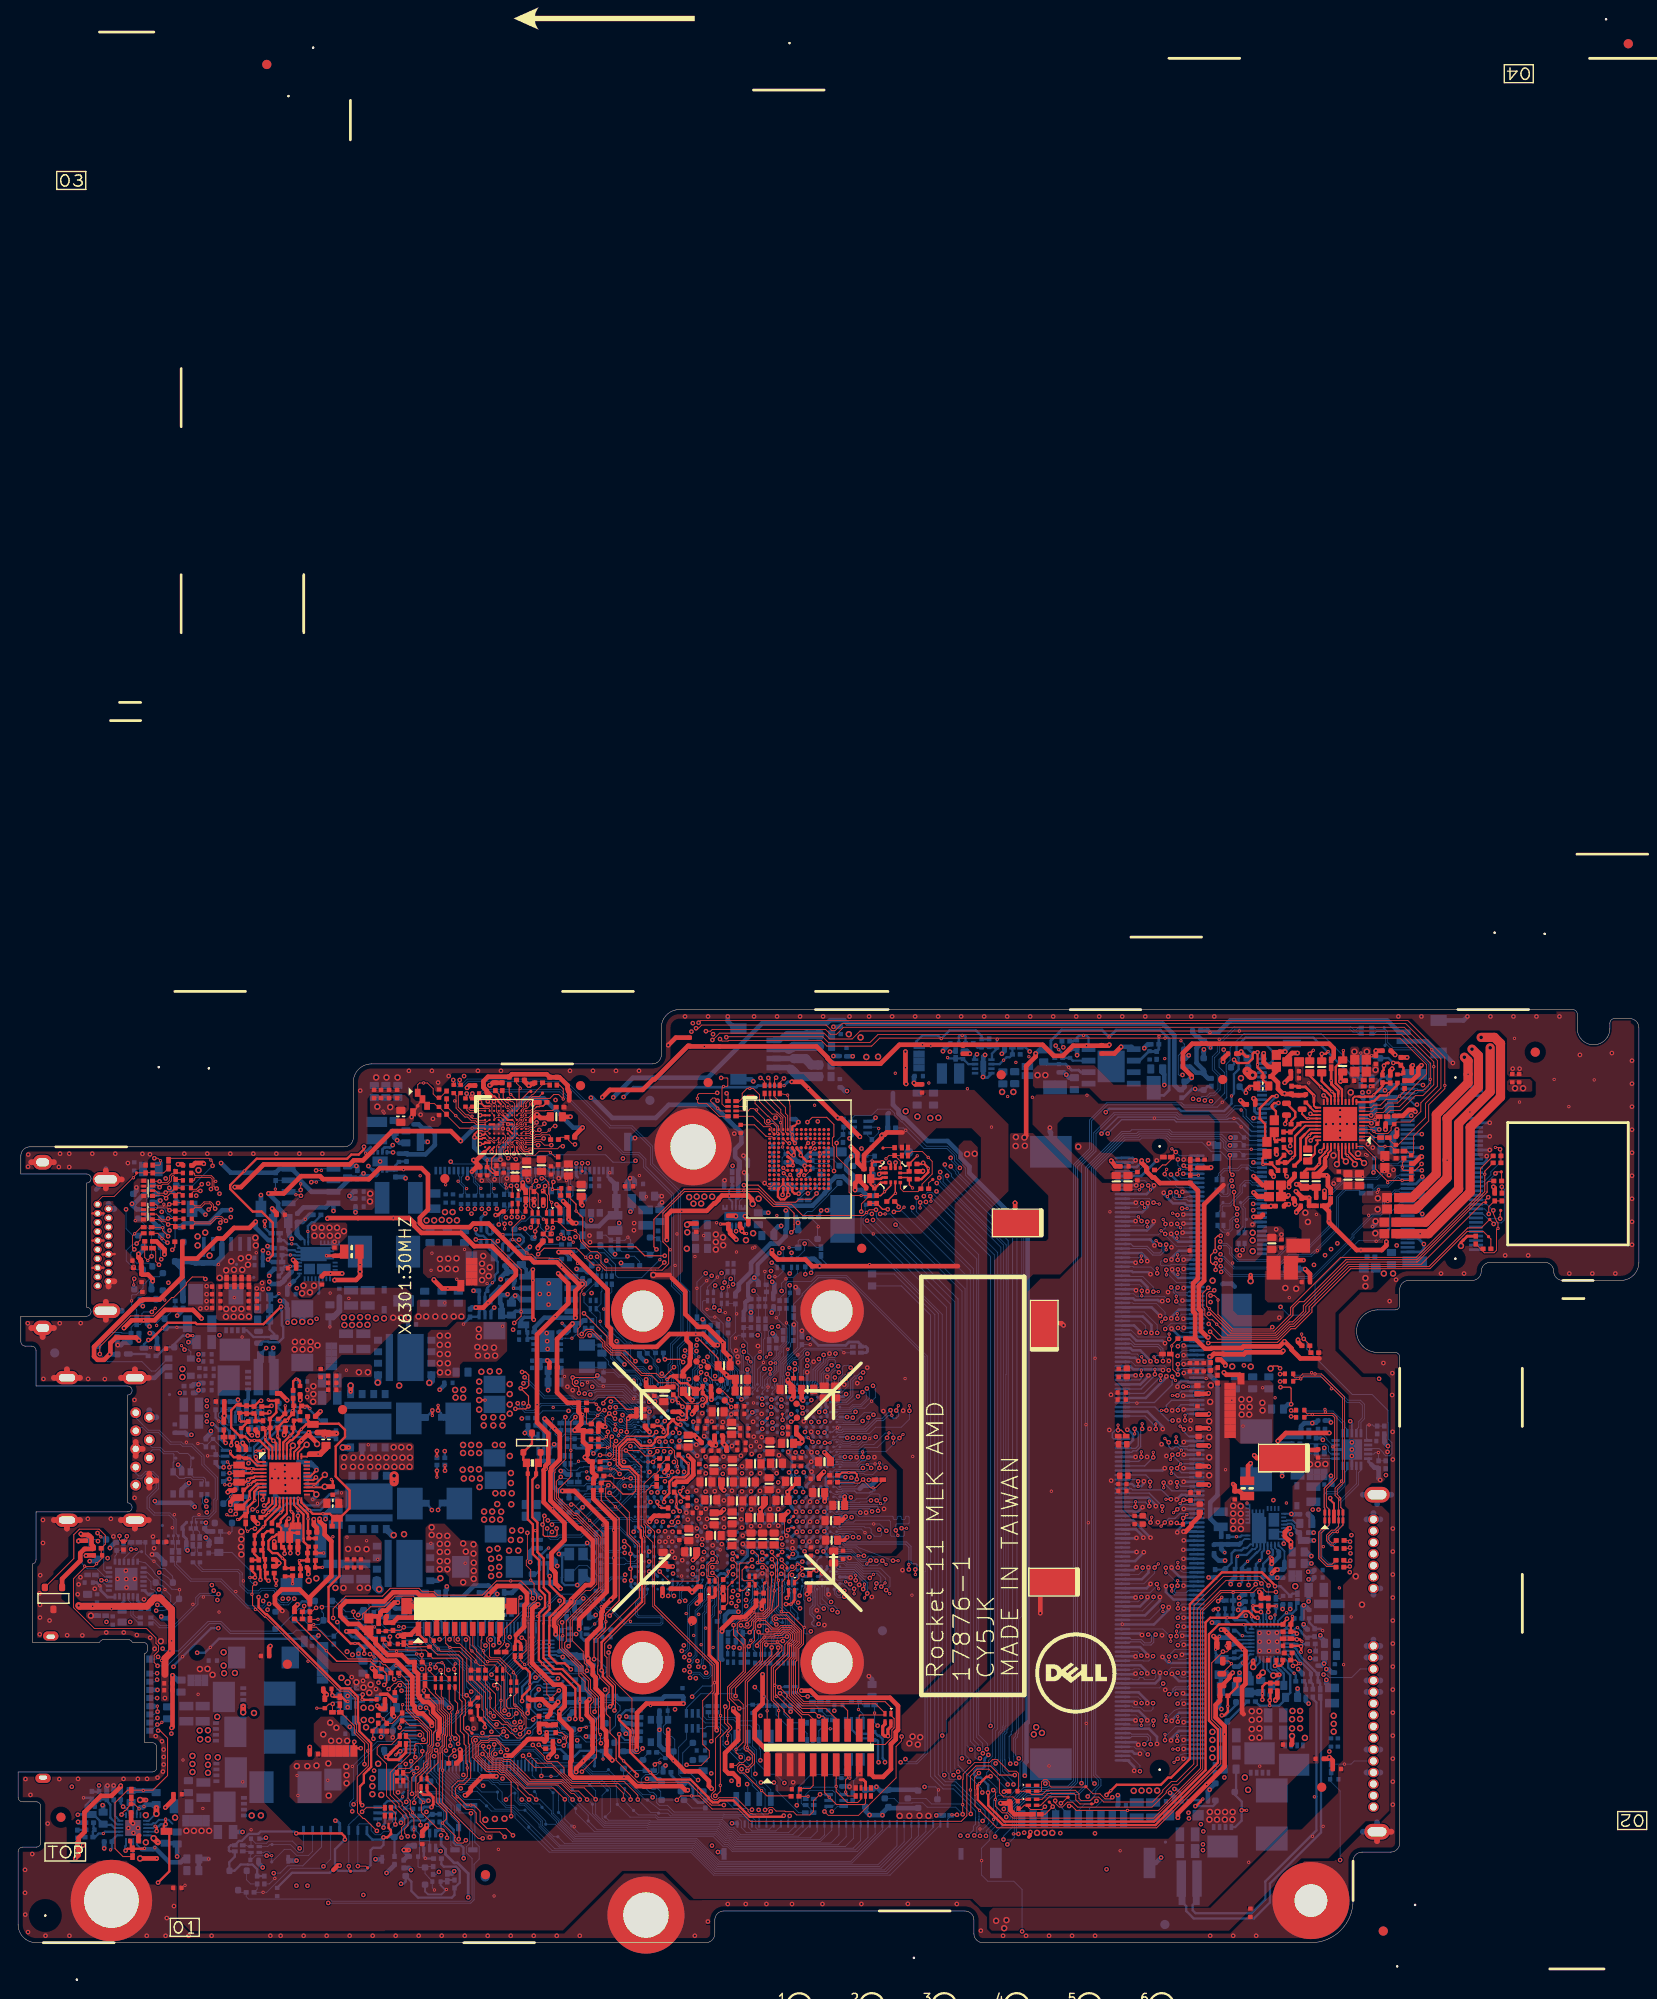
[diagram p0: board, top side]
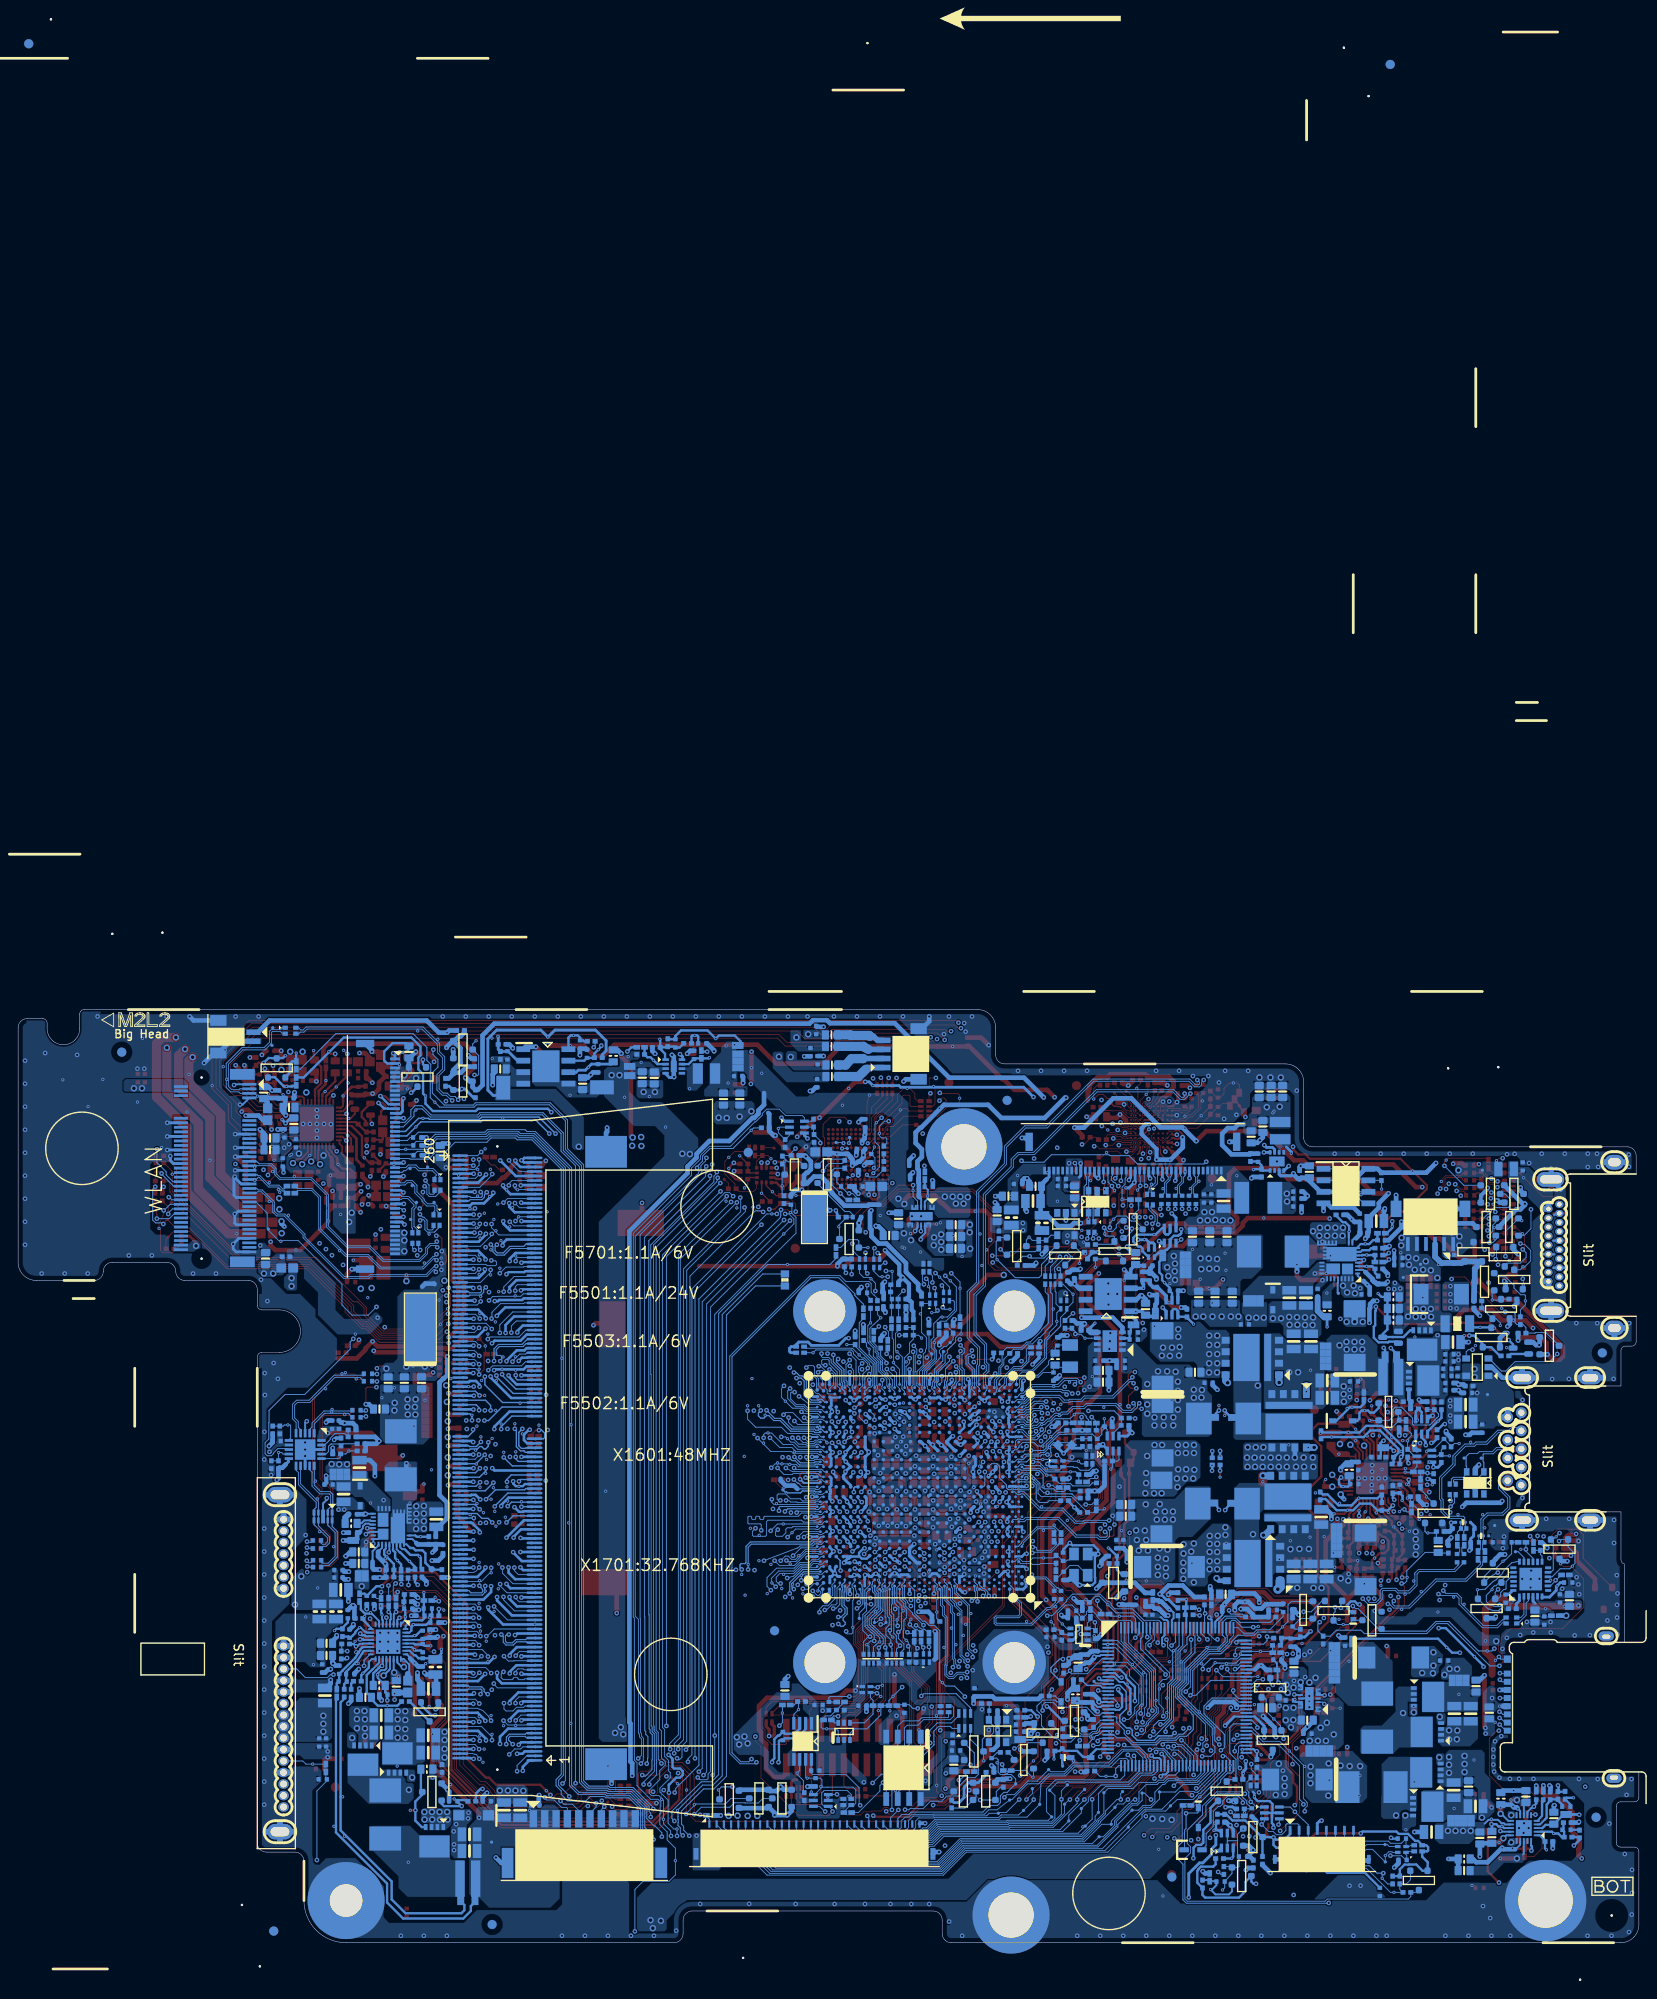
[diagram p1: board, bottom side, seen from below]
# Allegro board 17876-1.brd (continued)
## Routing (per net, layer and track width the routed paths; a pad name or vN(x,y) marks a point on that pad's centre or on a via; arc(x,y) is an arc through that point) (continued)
APU_DBRDY: length 24.3
  TOP w0.102: v1(81.81,34.97) 81.81,35.02 81.95,35.16 82.57,35.16 83.2,34.52 83.97,34.52 84.25,34.8 85.28,34.8 85.88,34.21 85.88,33.31 85.35,32.78 85.35,31.51 85.12,31.28 85.12,27.26 86.51,25.86 89.15,25.86 90.3,24.72 HDT1.14
  BOTTOM w0.102: CPU1.A26 82.15,37.47 81.69,37.01 81.69,35.95 81.88,35.75 v2(81.88,35.62) 81.88,35.22 81.81,35.16 v1(81.81,34.97)
APU_DBREQ#: length 32.7
  TOP w0.102: HDT1.16 91.57,25.6 91.03,26.14 86.55,26.14 85.34,27.35 85.34,31.22 85.56,31.43 85.56,32.7 86.08,33.22 86.08,34.29 85.37,35 84.15,35 83.87,34.72 83.31,34.72 82.47,35.56 81.64,35.56 81.41,35.32 81.41,34.57 81.28,34.44 81.28,33.35 v1(80.64,32.72)
  BOTTOM w0.102: CPU1.A25 81.6,37.93 81.13,37.46 81.13,37.06 80.85,36.78 80.85,35.88 81.13,35.6 81.13,34.52 81.18,34.47 81.18,33.68 v2(80.87,33.38) 80.85,33.38 80.64,33.17 v1(80.64,32.72) 80.52,32.59 80.52,31.85 R812.2
APU_DEVSLP1: length 9.3
  TOP w0.102: TP1605.1 84.35,57.79 84.38,57.76 v1(84.38,57.71) ; v1(85.75,63.3) 85.72,63.27 85.72,63.15 85.6,63.02 R1613.2
  L3 w0.102: v1(84.38,57.71) 84.38,58.02 86.02,59.65 86.02,60.68 85.75,60.94 v1(85.75,63.3)
  BOTTOM w0.102: v1(84.38,57.71) 84.4,57.74 84.4,58.22 CPU1.AU31
APU_FANIN: length 1.6
  TOP w0.102: TP1706.1 86.16,59.48 v1(86.59,59.06)
  BOTTOM w0.102: CPU1.AV33 86.46,59.06 v1(86.59,59.06)
APU_FANOUT: length 2.5
  TOP w0.102: v1(85.32,57.51) 85.52,57.51 TP1707.1
  BOTTOM w0.102: v1(85.32,57.51) 85.34,57.53 85.57,57.53 86.06,58.02 86.06,58.66 CPU1.AU33
APU_KBRST#: length 8.8
  BOTTOM w0.102: CPU1.BA30 84.35,62.46 84.32,62.5 84.32,63.97 86.06,65.71 86.06,68.43 85.6,68.89 R1633.1
APU_LDRQ0#: length 5.3
  BOTTOM w0.102: CPU1.AY18 77.75,60.84 78.05,61.14 78.05,61.4 77.99,61.46 77.99,61.85 77.75,62.09 77.75,63.3 76.83,64.21 76.83,65.18 TP1602.1
APU_LPC_AD0: length 15.7
  TOP w0.089: v1(83.01,63.32) v2(83.01,62.77)
  L4 w0.14: v1(85.17,73.86) 84.18,72.87 84.18,72.54 83.52,71.88 83.52,71.2 82.7,70.39 82.7,68.84 82.32,68.45 82.32,66.58 82.61,66.29 82.61,63.72 v1(83.01,63.32)
  BOTTOM w0.089: v1(83.01,63.32) 82.15,62.47 CPU1.BA26 ; v1(85.17,73.86) 85.37,74.07 RN1605.4
APU_LPC_AD1: length 16.5
  L4 w0.14: v1(84.28,71.93) 84.28,69.78 82.75,68.25 82.75,66.83 83.82,65.76 83.82,62.41 v1(83.52,62.1)
  BOTTOM w0.089: v1(83.52,62.1) 83.49,62.08 83.49,61.49 83.56,61.42 83.56,61.14 83.25,60.83 CPU1.AY28 ; RN1605.3 86.02,73.89 85.57,73.43 84.91,73.43 v2(84.76,73.28) 84.28,72.8 v1(84.28,71.93)
APU_LPC_AD2: length 16.5
  L4 w0.14: v1(82.37,63.35) 82.32,63.4 82.32,65.84 81.77,66.39 81.41,66.39 81.18,66.62 81.18,66.87 81.18,66.88 81.18,68.63 81.76,69.22 81.76,70.72 82.6,71.55 82.6,73.2 v1(82.91,73.51)
  BOTTOM w0.089: CPU1.AY25 81.6,61.16 81.94,61.5 81.94,62.92 v1(82.37,63.35) ; v1(82.91,73.51) v2(83.54,73.51) 83.85,73.51 84.45,74.11 RN1606.3
APU_LPC_AD3: length 17
  TOP w0.089: v1(80.49,64.52) 80.49,64.49 80.79,64.2 80.79,64.19 v2(80.87,64.11)
  L4 w0.14: v1(80.49,64.52) 80.82,64.84 80.82,68.85 81.34,69.38 81.34,70.98 82.15,71.79 82.15,74.02 v1(83.19,75.06)
  BOTTOM w0.089: RN1606.4 83.8,74.6 83.34,75.06 v1(83.19,75.06) ; v1(80.49,64.52) 80.49,63.98 80.89,63.58 80.89,61.97 80.85,61.93 80.85,61.51 80.74,61.4 80.74,61.16 CPU1.AY23
APU_LPC_CLKRUN#: length 7
  BOTTOM w0.089: CPU1.AY26 82.15,60.84 82.45,61.14 82.45,61.45 82.4,61.49 82.4,62.14 83.49,63.22 83.49,64.29 83.9,64.7 83.9,65.08 84.1,65.28 84.1,65.81 84.45,66.17 R1630.2
APU_LPC_FRAME#: length 7.9
  BOTTOM w0.089: CPU1.AY24 81.05,60.83 81.35,61.13 81.35,61.45 81.3,61.5 81.3,64.64 v2(81.89,65.23) 82.06,65.4 82.06,67.24 81.71,67.59 R1618.2
APU_LPC_PD#: length 11.7
  BOTTOM w0.089: v2(59,47.89) 59.12,47.78 R1632.2 60.17,47.5 R1614.2 62.62,49.26 65.98,49.26 66.32,49.59 66.32,50.64 66.75,51.07 66.86,51.07 67.45,51.66 67.86,51.66 CPU1.AC1
APU_LPC_PME#: length 3.9
  TOP w0.089: v1(72.19,51.97) v2(71.79,51.57) 71.55,51.34 R1634.2
  BOTTOM w0.089: CPU1.AA8 72.36,50.32 72.19,50.5 v1(72.19,51.97)
APU_LPC_RST#: length 10.2
  BOTTOM w0.089: R1629.2 v2(84.81,68.42) 85.12,68.11 85.12,66.32 85.06,66.27 85.06,66.22 84.51,65.66 84.51,64.75 83.9,64.14 83.9,63.07 83.01,62.19 83.01,61.48 82.7,61.17 CPU1.AY27
APU_LPC_SERIRQ: length 8.6
  TOP w0.089: v2(82.59,64.64) 82.67,64.64 83.03,65 v1(83.03,65)
  L3 w0.14: v1(83.03,65) 82.88,65 81.53,63.65 81.53,62.77 81.64,62.66 81.64,59.61 81.87,59.37 v1(82.14,59.37)
  BOTTOM w0.089: CPU1.AV27 82.5,59.52 82.35,59.37 v1(82.14,59.37) ; R1631.2 82.91,65.13 v1(83.03,65)
APU_LPC_SMI#: length 10
  BOTTOM w0.089: CPU1.BA27 82.7,62.15 83.69,63.15 83.69,64.21 84.1,64.62 84.1,65 84.3,65.2 84.3,65.74 84.86,66.3 84.86,66.37 84.88,66.39 84.88,66.85 84.89,66.85 84.89,67.82 84.45,68.25 84.43,68.25 84.07,68.61 84.05,68.61 v2(83.68,68.98) 84.05,69.34 R1635.2
APU_LPCCLK0: length 6.6
  BOTTOM w0.089: CPU1.BA25 81.6,63.29 82.27,63.96 v2(82.27,64.04) 82.27,66.58 82.42,66.73 82.42,67.82 R1611.2
APU_LPCCLK1: length 8.9
  BOTTOM w0.089: R1612.2 80.09,66.61 80.52,66.18 80.52,65.1 81.08,64.54 81.08,61.88 81.05,61.85 CPU1.BA24 ; R1612.2 80.09,67.89 R2005.2 R2011.1 ; R1612.2 79.5,67.06 v2(79.18,66.74)
APU_PWRBTN#_R: length 9.9
  BOTTOM w0.102: R1702.2 62.74,49.86 R1730.2 63.12,50.15 63.48,49.79 64.29,49.79 64.59,50.09 65.61,50.09 65.76,50.24 v2(65.76,50.32) 65.76,51.68 66.23,52.15 68.17,52.15 68.3,52.27 68.58,52.27 68.89,51.97 CPU1.AD2
APU_PWROK: length 4.5
  TOP w0.102: PU4601.9 26.64,49.86 26.53,49.75 26.53,48.25 26.11,47.83 v1(25.88,47.83)
  BOTTOM w0.102: PR4621.2 25.6,47.55 v1(25.88,47.83) 26.18,47.83 v2(26.43,47.58)
APU_PWROK_HDT: length 12.8
  TOP w0.102: HDT1.10 87.76,24.68 87.26,25.17 86.55,25.17 85.56,26.16 85.47,26.16 v1(84.1,27.54)
  BOTTOM w0.102: v2(83.68,27.17) 84.05,27.54 v1(84.1,27.54) 84.18,27.62 RN806.3 84.81,27.03 84.53,26.75 R823.2 84.53,25.24 85.5,24.27 U801.4
APU_RSMRST#: length 32.5
  TOP w0.102: v1(54.76,68.4) 55.53,69.17 v2(55.53,69.65) 55.53,74.27 52.17,77.62 v1(50.52,77.62)
  L3 w0.102: v1(54.76,68.4) 55.26,67.9 55.26,67.76 55.07,67.57 55.07,67.39 56.87,65.58 57.71,65.58 59.54,63.76 59.54,60.68 60.76,59.46 v1(60.76,58.7)
  BOTTOM w0.102: Q1701.5 58.04,56.21 R1719.2 57.12,57.13 R1748.1 57.91,58.7 v1(60.76,58.7) ; Q1702.3 50.91,77.23 v1(50.52,77.62)
APU_RSMRST#_R: length 13.5
  BOTTOM w0.102: R1746.1 v2(59,57.84) ; R1746.1 58.69,56.63 Q1701.6 ; R1746.1 59.28,56.67 59.28,56.11 C1702.2 60.33,56.14 63.25,56.14 63.27,56.11 63.98,56.11 65.2,54.89 65.2,54.53 65.63,54.1 66.07,54.1 66.25,53.93 67.79,53.93 CPU1.AG1
APU_RST#: length 7.2
  BOTTOM w0.102: R816.1 R808.2 89.22,25.03 89.78,25.03 89.99,24.82 R821.1 90.25,24.33 90.25,23.78 90.08,23.61 v2(89.65,23.61) 88.6,23.61 88.38,23.39 U801.1
APU_RST#_R: length 21.5
  TOP w0.102: v1(84.31,41.5) 84.31,41.38 84.63,41.06 84.63,40.13 84.33,39.83 84.33,36.62 v2(84.24,36.53) 84.24,36.53 84.33,36.44 85.08,36.44 86.69,34.83 86.69,32.97 86.17,32.45 86.17,28.13 86.03,27.99 86.03,27.64 86.49,27.18 v1(87.15,27.18)
  BOTTOM w0.102: R816.2 C801.1 89.41,27.03 89.26,27.18 v1(87.15,27.18) ; v1(84.31,41.5) 84.25,41.44 84.12,41.44 CPU1.D29
APU_RST_L_BUF: length 11.3
  TOP w0.102: HDT1.12 89.03,24.82 88.85,25 v1(88.39,25) 87.99,25.4 86.65,25.4 84.89,27.16 84.89,27.36 84.05,28.2 v1(84.02,28.2)
  BOTTOM w0.102: v2(83.51,28.41) 83.81,28.41 v1(84.02,28.2) 84.43,28.2 84.5,28.27 RN806.4 ; v1(88.39,25) 88.44,25.05 88.87,25.05 89.13,24.79 R821.2 88.81,24.27 U801.6
APU_S0A3_IND: length 6.6
  BOTTOM w0.102: R1757.2 65.07,48.8 65.28,48.59 66.17,48.59 66.52,48.95 66.52,50.56 66.81,50.85 67.79,50.85 67.81,50.87 CPU1.AB1
APU_SIC: length 26.3
  TOP w0.102: v1(79.2,27.23) 79.2,28.12 82.17,31.09 82.17,33.06 82.41,33.3 v1(84.4,33.3)
  BOTTOM w0.102: v1(79.2,27.23) 78.94,27.48 75.35,27.48 73.77,25.9 Q801.4 ; RN804.7 84.98,32.66 v2(85.22,32.89) 84.81,33.3 v1(84.4,33.3) 84.4,33.94 84.68,34.22 84.72,34.22 85.42,34.91 85.42,36.11 84.3,37.23 84.3,38.45 84.58,38.74 84.58,39.17 84.65,39.24 84.65,39.53 84.59,39.59 84.59,39.83 CPU1.B30
APU_SID: length 33.7
  TOP w0.102: v1(80.49,18.98) 81.28,19.76 81.28,20.74 v2(80.49,21.52) 80.49,28.75 83.9,32.16 v1(83.9,32.56)
  BOTTOM w0.102: RN804.5 v1(83.9,32.56) 83.41,33.05 83.41,33.59 84.57,34.75 84.61,34.75 84.96,35.1 84.96,35.77 83.89,36.84 83.89,38.65 84.1,38.87 84.1,39.16 83.8,39.46 CPU1.B29 ; v1(80.49,18.98) 80.49,19.21 80,19.7 79.94,19.7 77.82,21.82 77.82,21.85 77.8,21.87 77.8,22.23 77.82,22.24 77.82,23.35 77.29,23.87 76.28,23.87 76.02,23.88 75.79,23.65 Q801.1
APU_SLP_S3#: length 289.5
  TOP w0.102: v1(65.28,49.66) 67.46,47.47 67.46,45.11 68.57,44.01 68.57,38.11 64,33.55 64,30.55 63.97,30.52 63.97,29.68 64.19,29.47 64.19,29.29 65.23,28.25 65.23,27.64 64.92,27.33 64.92,26.03 64.92,26.02 64.92,25.25 65.33,24.84 65.33,23.14 66,22.47 66,20.33 66.01,20.32 66.01,20.14 68.44,17.71 69.2,17.71 69.24,17.67 69.59,17.67 69.63,17.71 73.98,17.71 76.36,15.33 76.38,15.33 76.53,15.18 77.38,15.18 77.39,15.19 v1(77.9,15.19) ; v1(87.12,90.58) 87.13,90.58 87.66,91.11 89.25,91.11 90.05,90.31 90.05,88.99 89.88,88.82 89.88,88 90.06,87.83 v1(90.06,85.18) ; v1(68.15,64.19) 67.01,65.33 65.62,65.33 65,65.96 65,66.93 v1(62.46,69.47) ; v1(116.01,15.09) 116.31,15.09 116.8,14.6 v2(122.45,14.6) 125.88,14.6 130.51,19.23 130.51,36.66 132.71,38.86 135.94,38.86 136.61,39.53 v1(136.61,39.57) ; R4012.1 35.56,26.21 R4001.1 35.85,25.14 35.9,25.14 37.11,23.93 37.11,23.14 38.25,21.99 38.25,21.29 38.23,21.26 v1(38.23,19.7)
  L3 w0.102: v1(38.23,19.7) 38.23,16.51 38.97,15.78 40.34,15.78 41.61,17.05 42.11,17.05 42.21,16.94 45.08,16.94 47.22,14.81 49.46,14.81 v1(49.98,14.28) 50.03,14.28 50.22,14.48 71.33,14.48 71.38,14.43 72.3,14.43 72.53,14.2 73.88,14.2 73.91,14.24 76.95,14.24 v1(77.9,15.19) ; v1(68.15,64.19) 71.82,67.86 71.82,72.25 70.87,73.21 70.87,75.93 71.22,76.28 71.61,76.28 71.84,76.51 71.86,76.51 72.54,77.19 72.54,77.95 72.52,77.98 72.52,79.38 73.51,80.37 76.08,80.37 78.87,83.16 v1(78.87,85.75) 80.51,85.75 83.62,88.86 83.62,88.88 85.75,91.01 86.69,91.01 v1(87.12,90.58)
  L4 w0.102: v1(68.15,64.19) 68.15,62.83 67.51,62.2 67.51,58.26 67.74,58.03 67.74,57.69 67.59,57.54 67.59,56.2 66.08,54.69 65.52,54.69 64.64,53.81 64.64,53.65 64.49,53.49 64.49,50.45 v1(65.28,49.66) ; v1(77.9,15.19) 78.31,15.6 86.43,15.6 87.22,14.8 87.22,13.8 88.86,12.16 101.91,12.16 103.2,13.44 103.2,14.3 103.81,14.91 107.97,14.91 108.55,14.33 111.1,14.33 112.97,16.2 115.01,16.2 116.01,15.2 v1(116.01,15.09)
  BOTTOM w0.102: D4002.K 50.16,10.26 50.16,12.43 49.98,12.6 v1(49.98,14.28) 49.95,14.32 48.73,14.32 48.63,14.42 D4003.K 48.63,15.27 46.17,17.73 46.17,17.97 45.41,18.72 44.98,18.72 44.75,18.95 U2401.64 ; R4009.2 62.89,69.14 62.84,69.14 62.51,69.47 v1(62.46,69.47) ; R4007.1 78.87,85.14 v1(78.87,85.75) ; D4004.1 89.93,86.49 87.8,86.49 R4015.1 87.66,86.25 87.91,86.01 89.42,86.01 89.75,85.68 89.75,85.49 v1(90.06,85.18) ; PR5307.1 136.63,39.59 v1(136.61,39.57) ; CPU1.AC2 68.55,51.67 68.3,51.67 68.11,51.86 67.26,51.86 66.12,50.71 66.12,50.09 65.68,49.66 v1(65.28,49.66) 65.16,49.54 62.59,49.54 62.55,49.51 62.12,49.07 R1733.2
APU_SLP_S5#: length 250.4
  TOP w0.102: PQ4415.1 133.62,32.3 133.43,32.11 133.17,32.11 133.15,32.13 v1(132.99,32.13) 131.75,30.89 131.75,24.64 132.74,23.65 132.74,19.76 125.66,12.68 108.05,12.68 v2(106.12,14.61) 105.62,15.11 105.62,16.23 105.61,16.24 105.61,16.86 105.58,16.9 105.58,18.25 v1(106.05,18.72) ; v1(65.82,25.63) 65.94,25.75 65.94,28.39 65,29.34 65,31.47 64.74,31.73 64.74,33.02 69.18,37.45 69.18,44.72 69.03,44.86 69.03,45.78 68.77,46.04 68.77,52.64 v1(67.08,54.33) 68.6,54.33 69.21,53.73 70.04,53.73 v1(70.57,54.25)
  L3 w0.102: v1(132.99,32.13) 133.93,33.07 133.93,35.13 137.06,38.25 140.67,38.25 141.73,39.32 141.73,42.67 142.34,43.28 142.34,45.99 144.09,47.74 144.09,51.66 145.34,52.9 145.34,57.96 140.89,62.41 140.89,63.67 139.69,64.87 139.5,64.87 136.42,67.95 136.42,71.25 136.6,71.43 136.6,75.13 135.59,76.15 135.59,76.63 135.51,76.71 135.51,89.77 132.74,92.54 132.74,93.38 131.78,94.35 131.78,95.68 129.64,97.82 129.64,98.12 129.39,98.38 125.78,98.38 124.84,97.44 118.61,97.44 118.49,97.55 117.21,98.83 v1(115.37,98.83) ; v1(65.82,25.63) 71.88,25.63 72.21,25.3 73.45,25.3 74.65,26.49 74.7,26.49 75.01,26.8 78.66,26.8 78.89,26.57 79.75,26.57 81.28,25.04 81.28,24.77 81.67,24.39 81.93,24.39 85.3,21.02 91.99,21.02 93.98,19.03 99.21,19.03 99.87,19.69 104.31,19.69 104.69,19.31 104.7,19.31 105.16,18.85 105.83,18.85 105.96,18.72 v1(106.05,18.72)
  L4 w0.102: v1(135.81,39.48) 135.4,39.06 135.15,39.06 134.24,38.15 134.24,33.38 v1(132.99,32.13)
  BOTTOM w0.102: v1(70.57,54.25) 70.57,54.25 70.2,53.88 CPU1.AG4 ; v1(135.81,39.48) 135.81,40.22 PR5319.1 ; R1738.2 63.37,56.34 64.04,56.34 65.43,54.94 65.43,54.58 65.68,54.33 v1(67.08,54.33) ; v1(65.82,25.63) 65.82,26.22 65.53,26.51 64.64,26.51 64.13,26 60.95,26 60.05,25.1 59.51,25.1 59.25,25.35 U2401.21 ; PR5314.1 115.21,98.99 v1(115.37,98.83)
APU_SPI_CLK: length 12.2
  L4 w0.127: v1(76.83,70.13) 76.96,70 76.96,69.47 77.22,69.22 77.22,67.03 77.24,67.01 77.24,66.63 76.76,66.14 76.76,65.33 v1(76.1,64.67)
  BOTTOM w0.102: v2(76.04,69.92) 76.62,69.92 v1(76.83,70.13) 76.75,70.21 RN1603.1 ; CPU1.AY17 77.2,61.17 77.5,61.48 77.5,61.77 77.34,61.93 77.34,62.97 76.1,64.21 v1(76.1,64.67)
APU_SPI_CS1#: length 11.4
  BOTTOM w0.089: CPU1.AY21 79.4,61.19 79.71,61.5 79.71,61.75 79.68,61.77 79.68,63.06 78.99,63.74 78.99,64.97 78.74,65.23 78.74,65.48 78.65,65.58 78.65,66.82 79.17,67.35 79.17,69.27 v2(79.31,69.41) 79.17,69.54 R1616.1 79.12,70.56 RN1604.1
APU_SPI_CS2#: length 9.2
  BOTTOM w0.089: R1615.1 75.69,67.39 R1621.2 75.69,66.58 TP1609.1 76.47,65.8 76.71,65.8 76.9,65.61 76.96,65.61 77.22,65.36 77.22,65.1 77.09,64.97 77.09,64.57 78.6,63.06 78.6,61.46 78.54,61.39 78.54,61.16 CPU1.AY19
APU_SPI_HOLD#: length 8.2
  BOTTOM w0.089: CPU1.BA18 77.75,61.8 77.55,62 77.55,63.04 76.58,64.01 76.58,64.85 76.33,65.1 76.33,65.41 75.44,66.3 75.44,66.75 75.01,67.18 v2(74.8,67.18) 74.8,68 R1617.1
APU_SPI_SI_R: length 13.2
  BOTTOM w0.089: RN1603.2 75.67,70.87 75.56,70.76 75.56,69.83 76.34,69.05 v2(76.91,69.05) 77.1,69.05 77.83,68.33 77.83,66.83 78.12,66.53 78.12,65.71 77.7,65.29 77.7,64.49 79.07,63.13 79.07,61.52 79.15,61.44 79.15,61.13 78.85,60.84 CPU1.AY20
APU_SPI_SO_R: length 10.4
  L4 w0.14: v1(77.42,69.78) 77.77,69.42 77.77,65.86 76.94,65.03 v1(76.94,62.54)
  BOTTOM w0.089: RN1604.2 77.63,69.98 v1(77.42,69.78) 77.65,69.54 v2(78.05,69.54) ; v1(76.94,62.54) 76.94,61.88 CPU1.BA17
APU_SPI_TPM_CS#: length 6.4
  BOTTOM w0.089: CPU1.BA21 79.4,63.07 78.05,64.41 TP1601.1 78.36,65.28 R1620.2
APU_SPI_WP#: length 6.9
  BOTTOM w0.089: R1619.1 77.24,67.03 77.77,66.5 v2(77.77,66.24) 77.77,65.64 77.51,65.38 77.51,64.41 78.85,63.08 CPU1.BA20
APU_SVC: length 12.6
  TOP w0.102: v1(79.78,35.03) 80.37,34.72 80.64,34.72 80.95,35.04 80.95,35.44 81.48,35.97 82.38,35.97 83.18,36.77 83.49,38.81 v2(83.47,38.84) 83.47,38.84 83.45,38.86 83.45,39.02 83.61,40.51 83.61,41.62 83.47,41.9 v1(83.2,42.33)
  BOTTOM w0.102: R813.2 78.84,34.6 79.12,34.6 v1(79.78,35.03) ; CPU1.E27 v1(83.2,42.33)
APU_SVD: length 10.1
  TOP w0.102: v1(80.47,35.13) 80.47,35.25 81.39,36.17 82.29,36.17 82.97,36.85 v1(83.2,40.73)
  BOTTOM w0.102: R820.2 79.68,34.6 79.96,34.6 80.47,35.1 v1(80.47,35.13) 80.47,35.59 v2(80.35,35.71) ; v1(83.2,40.73) 82.82,41.12 CPU1.D27
APU_SVT: length 12.5
  TOP w0.102: v1(80.75,34.27) 81.2,34.72 81.2,35.41 81.56,35.76 82.46,35.76 83.93,37.23 v2(83.93,40.01) 83.82,40.12 83.82,42.3 83.2,42.92 v1(83.2,43.12)
  BOTTOM w0.102: R810.2 80.62,34.14 v1(80.75,34.27) ; CPU1.H27 v1(83.2,43.12)
APU_TCK: length 20.4
  TOP w0.102: v1(82.58,32.89) 82.68,33 84.04,33 84.3,32.73 84.3,32.24 82.68,30.62 v2(82.68,25.59) HDT1.2
  BOTTOM w0.102: CPU1.B27 82.7,39.45 83,39.15 83,38.89 82.97,38.86 82.97,36.05 82.75,35.84 82.75,35.08 83.11,34.72 83.11,33.96 82.58,33.43 v1(82.58,32.89) 82.58,32.62 82.44,32.48 RN803.3
APU_TDI: length 25.2
  TOP w0.102: v1(81.74,34.29) 81.97,34.06 83.41,34.06 83.46,34.11 84.18,34.11 84.45,34.39 85.11,34.39 85.47,34.04 85.47,33.48 84.95,32.95 84.95,31.9 83.36,30.31 83.36,26.87 84.56,25.68 84.56,25.5 85.22,24.84 HDT1.6
  BOTTOM w0.102: CPU1.B25 81.6,39.48 81.9,39.18 81.9,37.73 81.36,37.19 81.36,36.78 v2(81.21,36.63) 81.38,36.46 81.38,34.65 v1(81.74,34.29) 81.74,33.58 81.38,33.22 81.38,33.22 81.13,32.97 81.13,32.39 81.36,32.16 RN803.1
APU_TDO: length 21.9
  TOP w0.102: HDT1.8 86.49,24.9 85.45,25.94 85.09,25.94 83.59,27.43 83.59,30.04 85.15,31.6 85.15,32.87 85.67,33.39 85.67,34.12 85.2,34.6 84.35,34.6 84.07,34.32 82.83,34.32 v1(82.68,34.47)
  BOTTOM w0.102: CPU1.A27 82.7,37.37 82.73,37.35 82.73,36.25 82.52,36.04 82.52,34.62 v1(82.68,34.47) 82.68,34.06 v2(82.35,33.73)
APU_TEST0: length 9
  TOP w0.102: v1(64.24,53.82) 65.23,53.82 v1(65.28,53.88)
  BOTTOM w0.102: v1(65.28,53.88) 65.89,53.88 66.04,53.72 67.56,53.72 67.67,53.62 67.97,53.32 68.25,53.32 68.31,53.37 68.6,53.37 68.9,53.07 CPU1.AF2 ; v1(64.24,53.82) 64.16,53.82 63.58,53.24 RN1708.4 62.94,53.18 62.9,53.14 v2(61.86,53.14) 61.56,52.85 RN1701.3
APU_TEST1: length 9.2
  BOTTOM w0.102: CPU1.AE1 67.93,52.35 66.12,52.35 65.38,51.61 v2(65.35,51.61) 64.9,51.61 R1721.2 63.98,50.7 62.76,50.7 62.48,50.42 60.64,50.42 60.31,50.75 R1711.2
APU_TEST2: length 19.1
  TOP w0.102: v1(72.82,52) 72.82,52.54 v2(72.77,52.59) 72.77,52.87 72.8,52.89 72.8,53.23 72.44,53.59 72.44,54.3 72.08,54.66 70.31,54.66 70.28,54.63 70.21,54.56 68.7,54.56 68.7,54.56 68.63,54.56 67.94,55.25 67.38,55.25 66.65,54.51 66.65,53.3 v1(66.88,53.07)
  BOTTOM w0.102: RN1701.4 60.32,52.53 60.71,52.15 61.67,52.15 62,52.47 62.35,52.47 62.41,52.53 RN1708.3 63.94,52.17 65.33,52.17 66.22,53.07 v1(66.88,53.07) ; v1(72.82,52) 72.92,51.9 72.92,51.74 CPU1.AC8
APU_TEST6: length 1.3
  TOP w0.102: v1(82.14,43.07) 82.44,42.76 TP803.1
  BOTTOM w0.102: v1(82.14,43.07) 81.69,43.52 CPU1.H25
APU_TEST9: length 1.4
  TOP w0.102: TP804.1 85.11,46.58 v1(85.11,46.51)
  BOTTOM w0.102: v1(85.11,46.51) 85.11,46.73 CPU1.R32
APU_TEST10: length 1.3
  TOP w0.102: v1(84.99,45.55) 85.01,45.57 85.01,45.6 85.22,45.8 TP805.1
  BOTTOM w0.102: CPU1.N32 85.33,45.92 85.01,45.6 85.01,45.57 v1(84.99,45.55)
APU_TEST14_BP1: length 6.9
  TOP w0.102: R811.1 78.33,37.47 78.33,39.3 TP806.1 79.33,40.3 79.33,41.83 v1(78.84,42.32)
  BOTTOM w0.102: v1(78.84,42.32) 79.24,42.72 CPU1.G21
APU_TEST15_BP3: length 1.4
  TOP w0.102: v1(78.89,42.97) 79,42.97 TP807.1
  BOTTOM w0.102: v1(78.89,42.97) 78.89,43.01 CPU1.H21
APU_TEST16_BP5: length 4.8
  TOP w0.102: RN808.2 81.35,39.71 81.1,39.96 80.11,39.96 79.92,40.15 79.92,41.13 80.24,41.45 TP808.1 80.97,41.45 v1(81.04,41.52)
  BOTTOM w0.102: v1(81.04,41.52) 80.9,41.52 CPU1.D23
APU_TEST17_BP7: length 6.5
  TOP w0.102: v1(81,42.27) 80.64,41.91 79.71,41.91 79.6,41.81 79.6,38.97 TP809.1 80.09,38.89 RN808.1
  BOTTOM w0.102: v1(81,42.27) 80.85,42.27 CPU1.E23
APU_TEST18_HDT20: length 35.9
  TOP w0.102: HDT1.20 94.11,21.98 94.21,21.88 95.69,21.88 96.44,22.63 96.44,23.47 96.69,23.72 96.69,24.74 96.34,25.09 RN809.1 96.34,25.97 95.7,26.6 86.74,26.6 85.8,27.54 85.8,31 85.96,31.17 85.96,32.53 86.49,33.05 86.49,34.46 84.77,36.17 83.47,36.17 83.24,35.93 83.24,35.59 v1(83.69,35.13)
  BOTTOM w0.102: CPU1.A28 83.21,39.33 83.21,38.81 83.2,38.81 83.2,35.97 83.11,35.87 TP810.1 83.29,35.16 83.67,35.16 v1(83.69,35.13)
APU_TEST19_HDT18: length 32.2
  TOP w0.102: v1(83.64,35.76) 84.89,35.76 86.28,34.37 86.28,33.14 85.76,32.61 85.76,31.35 85.57,31.16 85.57,27.45 86.65,26.37 94.65,26.37 95.69,25.33 RN809.2 95.55,25.14 92.94,25.14 92.84,25.04 HDT1.18
  BOTTOM w0.102: v1(83.64,35.76) 83.79,35.61 83.87,35.61 84.14,35.34 TP811.1 84.38,35.69 83.44,36.62 83.44,39.1 83.55,39.21 83.55,39.5 83.25,39.8 CPU1.B28
APU_TEST28_H: length 1.7
  TOP w0.102: v1(72.15,46.43) 72.75,47.03 TP812.1
  BOTTOM w0.102: CPU1.N8 72.6,45.98 v1(72.15,46.43)
APU_TEST28_L: length 2
  TOP w0.102: TP813.1 72.39,45.97 v1(72.85,46.43)
  BOTTOM w0.102: CPU1.N10 73.4,45.95 72.92,46.43 v1(72.85,46.43)
APU_TEST31: length 1.5
  TOP w0.102: v1(85.52,42.9) 85.52,42.9 85.42,42.9 TP814.1
  BOTTOM w0.102: CPU1.H31 85.44,42.98 85.45,42.98 v1(85.52,42.9)
APU_TEST36: length 4.7
  TOP w0.102: v1(82.14,41.43) 82.31,41.43 82.57,41.17 82.57,39.87 TP815.1 82.29,39.59 R809.1 R822.2
  BOTTOM w0.102: v1(82.14,41.43) 82.06,41.43 81.75,41.12 CPU1.D25
APU_TEST41: length 4.4
  BOTTOM w0.102: TP816.1 86.06,36.37 85.45,36.98 85.45,38.91 84.9,39.46 CPU1.B31
APU_THERMDA: length 1.3
  TOP w0.102: TP801.1 84.23,43.13 v1(84.34,43.13)
  BOTTOM w0.102: CPU1.H29 84.19,43.13 v1(84.34,43.13)
APU_THERMDC: length 1.9
  TOP w0.102: v1(84.28,42.26) 84.28,42.13 84.87,41.55 TP802.1
  BOTTOM w0.102: CPU1.G29 83.95,42.72 84.28,42.39 v1(84.28,42.26)
APU_TMS: length 25.2
  TOP w0.102: v1(81.56,32.79) 81.56,33.01 82.38,33.83 83.49,33.83 83.57,33.91 84.28,33.91 84.56,34.19 85.03,34.19 85.27,33.95 85.27,33.56 84.63,32.92 84.63,31.9 83.13,30.41 83.13,26.77 83.95,25.96 v2(83.95,25.62) HDT1.4
  BOTTOM w0.102: RN803.2 81.94,32.41 v1(81.56,32.79) 81.97,33.2 81.97,33.89 82.25,34.16 82.25,36.2 82.5,36.45 82.5,37.29 82.4,37.39 82.4,39.19 82.45,39.24 82.45,39.5 82.15,39.8 CPU1.B26
APU_TRST#: length 32.4
  TOP w0.102: R6804.1 85.27,16.21 82.65,16.21 v2(82.06,16.8) 80.13,18.73 79.67,18.73 79.42,18.98 79.42,19.39 79.67,19.65 79.69,19.65 79.72,19.68 80.08,19.68 80.35,19.41 80.6,19.41 81.05,19.85 81.05,20.65 80.53,21.16 80.34,21.16 80.14,21.36 80.14,21.69 80.26,21.82 80.26,28.86 83.19,31.78 v1(83.19,32.59)
  BOTTOM w0.102: CPU1.A29 83.69,38.91 83.69,36.71 84.73,35.67 84.73,35.19 84.52,34.98 84.47,34.98 83.52,34.02 83.5,34.02 83.19,33.71 v1(83.19,32.59) 83.03,32.44 RN803.4
APU_TRST#_R: length 5.8
  TOP w0.102: HDT1.9 87.76,17.35 87.43,17.02 86.39,17.02 C6801.1 86.18,16.82 R6804.2 v2(87.19,16.16)
APU_VSS_SENSE_A: length 5.9
  TOP w0.102: RN810.2 85.04,40.39 85.01,40.42 85.01,40.76 85.33,41.07 85.59,41.07 85.87,41.36 85.87,41.62 v2(86.02,41.77) 86.23,41.77 86.55,41.45 v1(86.55,41.3) 86.55,41.1 86.19,40.75 86.19,40.25 RN810.1
  BOTTOM w0.102: v1(86.55,41.3) 86.33,41.3 86.15,41.12 CPU1.D33
AUD_AGND: length 30.3
  TOP w0.203: HDA27.19 144.52,93.16 144.15,93.52 v1(144.09,93.52) ; HDA27.31 144.12,87.74 v1(143.74,87.35)
  TOP w0.305: AFTP2908.1 135.53,97.82 v1(135,98.35)
  TOP w0.508: v1(138.91,87.02) 138.86,87.07 EC2907.2 ; v1(145.97,95.07) 145.99,95.09 ; 145.99,95.09 146.05,95.15 EC2906.2 ; 145.99,95.09 145.99,95.9 C2715.2 ; v1(138.58,84.56) 138.58,84.66 138.3,84.94 EC2908.2 ; EC2701.1 134.49,98.15 134.8,98.15 v1(135,98.35) ; C2707.2 140.49,96.17 140.49,95.45 C2706.2 140.31,95.43 v1(139.8,94.92) ; v1(136.37,93.2) 136.41,93.17 136.41,93.15 136.55,93.01 EC2702.1 ; C2702.1 142.04,93.55 C2703.2 140.69,93.55 R2702.2 139.83,93.68 v1(139.78,93.73) 139.57,93.73 139.06,94.24 139.06,94.93 138.39,95.61 R2905.2 138.89,96.22 R2705.1 138,96.67 137.49,97.18 v1(137.49,98.17) ; v1(140.21,82.5) 140.06,82.35 R2706.1 R2704.1 ; v1(140.26,81.51) 139.93,81.51 EC2703.1 ; EC2905.2 149.87,97.9 v1(149.87,98.45) EC2705.1 ; v1(141.1,83.72) 141.35,83.72 141.68,83.39 C2711.2 C2710.2 EC2704.1
  BOTTOM w0.305: IOBD1.1 137.3,97.98 v1(137.49,98.17) ; IOBD1.13 136.69,91.55 136.47,91.77 136.47,93.09 136.41,93.15 136.41,93.17 v1(136.37,93.2)
  BOTTOM w0.508: v1(135,98.35) 135.69,97.66 C2902.1 135.77,97.65 Q2901.S
AUD_HP1_JACK_L: length 4.2
  TOP w0.203: HDA27.25 141.88,90.57
  TOP w0.254: R2908.1 R2922.2 140.51,89.49 R2928.2 141.6,90.57 141.88,90.57
AUD_HP1_JACK_L1: length 2
  TOP w0.254: R2907.1 138.66,88.67 EC2907.1 139.01,88.62 R2908.2
AUD_HP1_JACK_R: length 8.4
  TOP w0.203: 142,90.08 142.09,90.18 HDA27.26
  TOP w0.254: R2912.2 139.06,86.26 R2910.1 R2921.2 140.15,86.11 140.68,86.64 v2(140.69,86.64) 140.69,86.65 140.94,86.91 140.94,89.03 142,90.08
AUD_HP1_JACK_R1: length 3.4
  TOP w0.254: 137.85,87.07 137.36,86.59 137.36,85.96 v2(137.41,85.9) 137.44,85.93 138.2,85.93 EC2908.1 138.3,86.01 R2910.2
AUD_PC_BEEP: length 5.6
  TOP w0.254: 151.25,93.69 152.25,94.69 C2735.2 ; 151.25,93.69 151.23,93.69 151.06,93.52 150.31,93.52 149.68,92.89 149.43,92.89 149.33,92.79 147.8,92.79 HDA27.11 ; 151.25,93.69 v2(151.28,93.69)
AUD_PC_BEEP_C: length 5.4
  TOP w0.254: v1(151.79,97.11) 151.82,97.13 152.35,97.13 R2735.1 152.91,96.57 C2739.1 152.73,95.84 C2735.1
  BOTTOM w0.254: v1(151.79,97.11) 151.24,97.65 D2703.3 149.66,97.65 v2(149.4,97.91)
AUD_PORTA_L_R_B: length 4.8
  TOP w0.254: R2907.2 138.84,90.96 138.84,91.77 138.4,92.2 AFTP2906.1 138.4,92.43 138.66,92.69 v1(139.12,92.69)
  BOTTOM w0.254: IOBD1.12 138.07,92.05 138.09,92.08 138.51,92.08 v1(139.12,92.69)
AUD_PORTA_R_R_B: length 8.4
  TOP w0.254: v1(138.91,93.45) 138.4,93.45 137.06,92.1 AFTP2907.1 137.64,90.38 137.64,88.6 R2909.2
  BOTTOM w0.254: IOBD1.11 138.01,92.55 v1(138.91,93.45)
AUD_SENSE: length 21.4
  TOP w0.254: v1(135.52,93.82) 135.51,93.83 135.51,94.19 135.89,94.57 R2914.2 ; AFTP2909.1 151.03,97.11 150.78,96.85 150.78,96.82 v1(150.76,96.8) 150.76,96.8 150.72,96.76 150.72,96.32 150.6,96.19 R2711.1
  L3 w0.254: v1(135.52,93.82) 135.52,94.05 136.04,94.57 138.64,94.57 138.82,94.39 146.76,94.39 146.84,94.46 148.82,94.46 150.67,96.32 150.67,96.71 150.76,96.8 v1(150.76,96.8)
  BOTTOM w0.254: v1(135.52,93.82) 135.47,93.82 134.82,94.46 Q2901.D
AUD_SENSE_A: length 5.5
  TOP w0.203: HDA27.12 147.32,93.2 147.52,93.4 147.93,93.4
  TOP w0.254: 147.93,93.4 148.11,93.4 148.16,93.35 148.62,93.35 148.67,93.4 149.45,93.4 v2(149.64,93.59) 150.6,94.54 R2711.2 150.62,94.9 R2710.2
AUD_SPK_11_L+: length 99
  TOP w1.016: R2743.1 v2(154.75,78.26) 155.68,78.26 160.27,82.85 160.27,89.99 163.63,93.35 163.63,99.26 162.96,99.93 v3(161.49,99.93)
  L4 w1.016: v3(92.99,99.93) 93.98,99.93 94.24,100.18 161.23,100.18 v3(161.49,99.93)
AUD_SPK_11_L-: length 98.9
  TOP w1.016: v3(162.48,98.78) 162.48,93.93 v2(160.25,91.7) 159,90.45 159,83.2 155.33,79.53 R2745.1
  L4 w1.016: v3(91.69,100.28) 92.74,101.33 93.76,101.33 93.78,101.35 161.7,101.35 162.64,100.41 162.64,99.44 162.63,99.44 162.63,98.93 v3(162.48,98.78)
AUD_SPK_11_R+: length 86.4
  TOP w1.016: v3(159.64,97.74) 160.05,97.33 v2(160.05,95.85) 160.05,94.92 156.54,91.41 156.54,84.85 155.21,83.52 155.17,83.52 153.9,82.25 R2749.1
  L3 w1.016: v3(159.64,97.74) 157.17,100.21 97.33,100.21 v3(94.92,97.79)
AUD_SPK_11_R-: length 92.3
  TOP w1.016: v3(160.48,98.63) 161.19,97.92 161.19,94.44 157.74,90.99 157.73,90.98 v2(157.73,86.37) 157.73,84.43 154.64,81.33 154.61,81.33 154.25,80.98 R2747.1
  L3 w1.016: v3(160.48,98.63) 157.76,101.35 96.86,101.35 93.62,98.11 v3(93.62,97.77)
AUD_SPK_L+_C11: length 5.2
  BOTTOM w0.61: SPK1.3 85.06,98.6
  BOTTOM w1.016: 85.06,98.6 AFTP2902.1 85.6,98.93 R2902.2
AUD_SPK_L+_R: length 11.6
  TOP w0.203: HDA27.35 145.72,87.5 145.77,87.45 145.77,86.13 v3(145.57,85.93)
  L4 w0.889: v3(145.57,85.93) 145.57,84.71 146.1,84.18 146.1,84.13
  L4 w1.016: v3(149.81,78.31) 149.54,78.31 147.83,80.02 147.83,82.4 146.1,84.13
  vias: v2(149.9,77.43)
AUD_SPK_L-_C11: length 5.3
  BOTTOM w0.61: SPK1.4 84.04,99.6 84.49,100.05 84.86,100.05
  BOTTOM w1.016: R2901.2 87.04,100.2 AFTP2901.1 84.95,100.14 84.86,100.05
AUD_SPK_L-_R: length 10.5
  TOP w0.203: v3(146.56,86.23) 146.12,86.67 HDA27.36
  L4 w0.889: 147.09,84.96 146.61,85.45 146.61,86.18 v3(146.56,86.23)
  L4 w1.016: v3(149.83,79.63) 148.97,80.49 148.97,83.09 147.09,84.96
  BOTTOM w0.508: v3(149.83,79.63) 149.83,79.38 v2(149.5,79.05)
AUD_SPK_R+_C11: length 5.5
  BOTTOM w0.61: SPK1.1 85.14,96.6
  BOTTOM w0.635: 85.14,96.6 85.33,96.41
  BOTTOM w1.016: 85.33,96.41 AFTP2904.1 86.13,95.61 R2904.2
AUD_SPK_R+_R: length 7.6
  TOP w0.203: HDA27.38 146.92,87.25 147.66,86.51 148.11,86.51 v3(148.56,86.06)
  L3 w0.889: 148.5,85.33 148.56,85.4 v3(148.56,86.06)
  L3 w1.016: 148.5,85.33 148.5,83.25 149.58,82.17 v3(150.09,82.17)
  vias: v2(150.03,82.83)
AUD_SPK_R-_C11: length 5.4
  BOTTOM w0.61: 85.64,97.6 SPK1.2
  BOTTOM w1.016: 85.64,97.6 85.65,97.59 AFTP2903.1 87.55,96.88 R2903.2
AUD_SPK_R-_R: length 9.1
  TOP w0.203: HDA27.37 146.52,87.08 v2(146.71,86.89) 146.73,86.89 147.55,86.07 v3(147.55,85.93)
  L3 w0.889: v3(147.55,85.93) 147.5,85.88 147.5,85.85 147.29,85.65 147.29,84.94
  L3 w1.016: 147.29,84.94 147.29,82.84 149.18,80.95 v3(150.06,80.95)
AUD_VREF: length 1.7
  TOP w0.203: 142.65,92.18 143.05,91.78 HDA27.22
  TOP w0.254: 142.65,92.18 142.65,92.23 C2702.2
BAT_IN#: length 220.8
  TOP w0.102: v1(113.33,15.01) 113.03,14.71 111.74,14.71 111.51,14.94 RN4301.2 111.06,15.17 110.7,14.81 EC4305.2 ; v1(39.6,12.34) 38.22,13.72 38.08,13.72 37.46,14.34 37.46,15.45 37.43,15.48 37.43,18.29 38.66,19.52 38.66,21.91 37.36,23.21 37.36,24.08 37.21,24.23 37.21,27 36.45,27.76 35.51,27.76 27.33,35.94 27.2,35.94 25.88,37.26 25.88,39.35 v1(26.19,39.65) ; v1(48.63,11.43) 48.67,11.46 48.67,13.31 46.49,15.49 46.49,19.18 46.58,19.27 46.58,20.91 46.57,20.93 46.57,21.5 46.81,21.74 46.81,22.89 46.91,22.98 46.91,23.03 46.97,23.09 46.97,24.9 46.25,25.61 46.25,26.23 45.45,27.03 45.34,27.03 R2463.2 44.78,27.59 v1(44.78,27.84)
  L3 w0.102: v1(100.05,17.2) 100.15,17.3 104.74,17.3 104.82,17.22 105.42,17.22 105.45,17.18 105.81,17.18 106.05,17.18 106.14,17.27 106.74,17.27 106.77,17.3 108.5,17.3 108.5,17.3 108.64,17.3 108.85,17.1 108.99,17.1 109.25,16.84 109.25,16.7 110.93,15.01 v1(113.33,15.01) ; v1(39.6,12.34) 39.77,12.17 42.01,12.17 42.12,12.29 47.54,12.29 48.45,11.39 48.59,11.39 v1(48.63,11.43) 48.96,11.75 50.33,11.75 51.29,10.8 56.74,10.8 57.8,11.85 77.41,11.85 78.51,10.75 107.93,10.75 108.33,11.14 108.33,11.57 108.64,11.88 109.93,11.88 110.24,11.57 114.52,11.57 v1(115.04,12.09)
  L4 w0.102: v1(142.57,32.18) 142.16,31.78 142.16,30.33 143.14,29.35 143.14,12.47 138.08,7.41 117.25,7.41 116.52,8.14 116.52,10.61 v1(115.04,12.09) 115.04,13.31 v1(113.33,15.01)
  BOTTOM w0.102: PR4472.2 22.07,43 PC4433.1 23.6,43.08 25.62,41.06 25.62,39.91 25.88,39.65 v1(26.19,39.65) ; D4302.3 101.48,16.74 v2(101.6,16.86) 101.26,17.2 v1(100.05,17.2) ; v1(142.57,32.18) PR4409.2 143.18,32.23 PR4439.2 ; v1(44.78,27.84) 44.78,27.54 44.2,26.95 U2401.80
BAT_SCL: length 162
  TOP w0.089: v1(43,11.74) 42.67,12.07 42.67,12.54 43.04,12.92 43.04,13.83 42.83,14.04 42.83,14.22 42.04,15.01 42.04,15.32 41.07,16.29 41.07,18.79 42.02,19.73 42.19,19.73 43.27,20.81 43.27,22.36 RN2404.3 44.25,22.82 v1(44.35,22.92) ; v1(104.27,14.17) v2(104.27,15.24) 104.27,18.02 104.31,18.06 104.31,18.61 105.6,19.9 107.23,19.9 107.55,20.21 108.07,20.21 109.36,18.93 110.18,18.93 110.43,18.68 110.43,16.89 110.31,16.76 EC4301.1 111.02,16.71 111.03,16.72 RN4302.2 111.51,16.7 111.84,16.36 113.06,16.36 113.52,16.82 116.7,16.82 117.1,16.43 117.1,15.92 117.35,15.67 118.37,15.67 118.76,16.07 119.27,16.07 119.82,15.53 125.21,15.53 126.34,16.66 126.34,16.83 127.29,17.78 127.83,17.78 129.77,19.73 129.77,36.77 129.79,36.79 129.79,37.19 133.05,40.44 137.06,40.44 138.02,39.47 v1(138.02,39.42)
  L4 w0.14: v1(43,11.74) 44.44,10.3 44.44,7.92 45.99,6.37 48.76,6.37 49.21,6.82 59.54,6.82 63,10.27 76.37,10.27 76.38,10.26 76.78,10.26 77.01,10.49 79.71,10.49 84.13,14.92 85.51,14.92 86.51,13.92 86.51,13.91 88.69,11.73 102.27,11.73 104.27,13.72 v1(104.27,14.17)
  BOTTOM w0.089: v1(44.35,22.92) 44.32,22.95 U2401.70 ; v1(104.27,14.17) 103.49,14.96 100.34,14.96 99.85,15.44 98.68,15.44 98.65,15.41 97.21,15.41 96.7,15.93 D4301.3 ; v1(138.02,39.42) 138,39.4 PR4471.1
BAT_SDA: length 170.9
  TOP w0.089: v1(42.31,11.61) 42.31,12.69 42.69,13.06 42.69,13.68 42.47,13.9 42.47,14.07 41.68,14.86 41.68,15.18 40.65,16.2 40.65,19.75 39.63,20.77 39.63,21.52 39.98,21.87 41.21,21.87 42.13,22.79 RN2404.4 42.13,23.1 42.48,23.45 44.42,23.45 44.78,23.1 44.78,22.46 v1(44.72,22.41) ; v1(137.24,39.65) 136.89,40 133.34,40 130.15,36.81 130.15,19.6 127.98,17.43 127.44,17.43 126.73,16.71 126.73,16.54 125.15,14.96 116.95,14.96 116.4,15.51 115.82,15.51 115.28,14.97 114.92,14.97 114.48,15.42 v1(114.48,15.67) ; RN4301.1 110.54,15.82 EC4302.1 110.29,15.62 109.82,16.09 108.78,16.09 108.31,16.56 108.31,18 107.16,19.15 105.87,19.15 105.11,18.38 v2(105.11,16.86) 105.11,16.85 105.16,16.81 v1(105.16,14.21)
  L4 w0.14: v1(114.48,15.67) 114.46,15.67 114.35,15.57 112.94,15.57 110.8,13.42 108.85,13.42 107.8,14.48 105.42,14.48 v1(105.16,14.21) 105.17,14.21 105.17,13.92 102.53,11.29 88.5,11.29 86.06,13.74 86.06,13.75 85.33,14.47 84.32,14.47 79.4,9.56 74.78,9.56 74.51,9.83 63.2,9.83 59.73,6.35 49.37,6.35 48.95,5.92 45.49,5.92 44,7.42 44,9.73 42.31,11.41 v1(42.31,11.61)
  BOTTOM w0.089: v1(105.16,14.21) 105.16,14.25 104.09,15.31 100.83,15.31 100.22,15.93 D4303.3 ; v1(137.24,39.65) 137.49,39.4 137.49,38.36 PR4470.1 ; U2401.69 44,22.55 44.08,22.47 44.66,22.47 v1(44.72,22.41)
BKLT_CTRL: length 7.9
  TOP w0.102: R5505.2 58.04,78.23 R5524.1 58.27,78.54 58.27,78.82 v1(58.39,78.94) 58.32,79.02 RN5503.3
  BOTTOM w0.102: D5502.3 54.77,78.85 55.58,79.66 56.03,79.66 56.58,80.2 57.64,80.2 v2(57.98,79.87) 58.39,79.45 v1(58.39,78.94)
BLON_OUT: length 113.7
  TOP w0.102: RN5504.4 57.4,79.04 57.1,78.74 57.1,78.56 57.07,78.54 v1(57.07,78.51) 57.07,77.91 v2(57.04,77.87)
  L3 w0.102: v1(57.07,78.51) 55.5,76.94 51.72,76.94 50.57,75.79 50.57,74.4 50.55,74.37 50.55,74.35 46.45,70.26 34.37,70.26 33.43,69.32 32.61,69.32 32.41,69.12 29.82,69.12 29.31,68.61 29.31,65.87 27.51,64.07 27.51,59.58 27.3,59.37 27.3,58.18 28.61,56.88 28.61,53.97 27.14,52.49 27.14,51.1 25.65,49.61 25.65,48.48 25.44,48.27 25.44,46.27 25.32,46.15 25.32,45.8 26.49,44.63 26.49,42.37 28.45,40.41 29.46,40.41 30.09,39.78 30.1,39.78 31.85,38.03 31.88,38.03 32.23,37.67 32.23,36.68 32.62,36.3 36.45,36.3 37.06,35.69 40.74,35.69 41.29,36.23 43.24,36.23 43.69,35.79 45.67,35.79 45.71,35.75 45.86,35.75 46.74,34.88 47.99,34.88 48.56,34.3 v1(49.43,33.45)
  BOTTOM w0.102: v1(49.43,33.45) 49.43,31.95 50.42,30.96 50.42,28.89 51.13,28.18 51.13,27.07 49.19,25.13 49.19,23.52 49.93,22.79 50.67,22.79 51.11,22.35 52.77,22.35 53.27,21.85 55.91,21.85 56.68,22.61 57.61,22.61 57.95,22.95 U2401.27
BLON_OUT_C: length 5.7
  TOP w0.102: v1(57.45,83.52) 57.45,83.47 56.92,82.93 R5506.2 57.12,82.91 57.4,82.63 RN5504.1
  BOTTOM w0.102: LCD1.25 58.1,84.7 58.23,84.57 58.23,84.19 57.96,83.92 57.86,83.92 v1(57.45,83.52)
BLUETOOTH_EN: length 192.8
  TOP w0.102: v1(131.37,66.19) 131.44,66.27 139.01,66.27 140.51,67.77 140.97,67.77 142.81,69.61 142.81,70.12 147.09,74.4 155.83,74.4 159.95,78.52 161.72,78.52 AFTP6110.1 162.56,77.67 R6110.1 ; R2478.2 41.58,28.01 41.99,28.42 v1(42.14,28.42)
  L3 w0.102: v1(131.37,66.19) 131.09,65.91 131.09,60.95 130.94,60.8 130.94,19.01 125.21,13.29 110.19,13.29 109.89,12.98 108.7,12.98 107.9,13.79 107.9,14.08 107.68,14.3 107.68,14.34 106.89,15.13 105.86,15.13 105.52,15.47 102.32,15.47 102.21,15.36 91.76,15.36 90.3,16.81 85.25,16.81 85.2,16.75 79.59,16.75 79.09,17.25 79.09,17.61 79.17,17.69 79.17,18.05 78.92,18.3 78.4,18.3 76.95,19.76 74.28,19.76 73.97,20.07 71.36,20.07 70.35,19.06 66.95,19.06 66.43,18.54 63.23,18.54 62.46,19.31 61.44,19.31 60.63,18.5 58.65,18.5 58.04,19.1 52.38,19.1 50.83,20.65 50.83,21.97 51.68,22.82 51.68,23.34 51.94,23.61 51.94,23.96 49.97,25.94 48.72,25.94 48,26.65 42.87,26.65 41.83,27.69 41.83,28.12 v1(42.14,28.42)
  BOTTOM w0.102: v1(42.14,28.42) 42.24,28.32 42.52,28.32 42.69,28.15 U2401.83
BLUETOOTH_EN_R: length 9.8
  TOP w0.102: v1(162.83,80.83) 162.83,80.49 163.19,79.63 163.35,79.47 v2(163.35,78.84) 163.18,78.68 163.18,76.43 162.91,76.16 161.85,76.16 161.7,76.3 R6110.2 161.43,76.59 R6111.2
  BOTTOM w0.102: WLAN1.54 162.13,81.5 162.79,80.83 v1(162.83,80.83)
BP_D: length 2.5
  BOTTOM w0.114: PQ4402.D 23.4,49.21 v2(23.44,49.21) 23.44,49.38 24.1,50.04 PR4415.2
BP_G: length 3.4
  BOTTOM w0.114: PQ4402.G 23.61,45.4 23.44,45.22 v2(23.29,45.22) 22.52,45.22 PR4478.1 22.35,44.6 PC4433.2
BT_USB20_CON_N5: length 14.5
  BOTTOM w0.089: 150.8,100.81 150.93,100.81 151.16,100.58 151.16,99.39 151.75,98.8 154.2,98.8 155.93,97.06 155.93,94.41 155.44,93.92 154.55,93.92 154.38,93.75 WLAN1.5 ; 150.8,100.81 AFTP6111.1 ; 150.8,100.81 149.9,100.81 149.72,100.99 EL6101.1
BT_USB20_CON_P5: length 13.7
  BOTTOM w0.089: WLAN1.3 154.42,94.25 154.51,94.16 155.34,94.16 155.69,94.51 155.69,96.96 154.1,98.55 151.65,98.55 151.02,99.19 ; 151.02,99.19 150.92,99.29 150.92,100.48 150.83,100.57 149.94,100.57 149.7,100.34 EL6101.2 ; 151.02,99.19 AFTP6113.1
BT_USB20_N5: length 126.8
  L4 w0.114: v1(66.71,58.24) 66.72,58.24 66.72,58.53 66.99,58.8 66.99,61.97 67.65,62.63 67.65,67.2 65.79,69.06 65.79,70.41 69.72,74.34 69.72,76.48 70.39,77.15 70.39,82.63 70.82,83.06 70.82,83.99 71.41,84.59 71.41,88.86 73.34,90.79 74.38,90.79 75.54,91.95 78.76,91.95 81.07,94.26 91.11,94.26 91.31,94.46 91.67,94.46 91.72,94.41 97.47,94.41 97.82,94.07 99.45,94.07 101.13,92.39 105.91,92.39 105.93,92.42 105.95,92.42 108.15,94.62 110.21,94.62 110.92,93.91 129.14,93.91 129.47,93.58 130.41,93.58 130.42,93.57 130.6,93.39 130.6,93.31 v1(130.33,93.04)
  BOTTOM w0.089: v2(132.57,99.72) 132.7,99.58 ; 132.7,99.58 132.37,99.25 132.37,98.35 131.81,97.79 131.81,96.33 132.44,95.71 132.44,94.24 131.98,93.78 131.55,93.78 131.16,93.39 130.66,93.39 130.33,93.05 v1(130.33,93.04) ; 132.7,99.58 134.2,101.09 147.11,101.09 147.45,100.75 147.7,100.75 147.94,100.99 EL6101.4 ; CPU1.AP2 68.9,57.47 68.58,57.79 68.3,57.79 68.23,57.71 67.82,57.71 67.57,57.46 67.52,57.46 67.51,57.46 67.16,57.46 66.93,57.69 66.93,57.86 66.7,58.09 66.7,58.22 66.71,58.23 v1(66.71,58.24)
BT_USB20_P5: length 126.5
  L4 w0.114: v1(66.52,57.63) 66.3,57.86 66.3,58.42 66.77,58.89 66.77,62.06 67.44,62.72 67.44,67.11 65.58,68.97 65.58,70.5 69.51,74.43 69.51,76.57 70.17,77.24 70.17,82.72 70.6,83.15 70.6,84.08 71.2,84.68 71.2,88.95 73.25,91.01 74.3,91.01 75.46,92.17 78.67,92.17 80.98,94.48 91.02,94.48 91.22,94.68 91.76,94.68 91.81,94.63 97.56,94.63 97.91,94.29 99.54,94.29 101.22,92.61 105.82,92.61 105.84,92.64 105.86,92.64 108.06,94.84 110.3,94.84 111.01,94.13 129.23,94.13 129.56,93.8 130.5,93.8 130.82,93.48 130.82,93.14 v1(130.99,92.97)
  BOTTOM w0.089: v2(134.8,100.64) 134.79,100.84 ; 134.79,100.84 134.31,100.84 132.61,99.15 132.61,98.25 132.05,97.69 132.05,96.43 132.68,95.81 132.68,94.14 132.08,93.54 131.65,93.54 131.26,93.15 131.17,93.15 v1(130.99,92.97) ; 134.79,100.84 147.01,100.84 147.35,100.51 147.76,100.51 147.93,100.34 EL6101.3 ; CPU1.AP1 67.92,57.47 67.67,57.22 67.62,57.22 67.61,57.22 67.06,57.22 66.64,57.63 v1(66.52,57.63)
CAP_LED: length 21.8
  BOTTOM w0.102: KB1.27 81.8,13.71 81.36,14.15 80.59,14.15 80.32,14.41 72.42,14.41 71.67,15.16 70.78,15.16 70.48,15.45 70.48,16.21 70.1,16.6 69.72,16.6 AFTP6533.1 68.79,18.08 69.28,18.57 70.48,18.57 70.72,18.82 70.72,20.2 70.9,20.37 EC6506.1 70.82,21.01 R6503.2
CAP_LED#: length 37.1
  TOP w0.102: v2(70.84,19.86) 70.38,19.86 70.28,19.76 v1(70.28,19.67)
  L3 w0.102: v1(70.28,19.67) 69.96,19.34 66.91,19.34 66.34,18.77 63.32,18.77 62.56,19.53 61.35,19.53 60.54,18.72 58.74,18.72 58.14,19.33 53.57,19.33 52.25,20.65 52.25,21.01 52.5,21.26 52.54,21.26 52.98,21.71 52.98,22.13 52.24,22.87 v1(52.24,23.29)
  BOTTOM w0.102: R6502.1 70.15,19.54 v1(70.28,19.67) ; U2401.109 49.55,33.99 49.89,33.66 49.89,32.94 50.65,32.17 50.65,28.98 51.36,28.27 51.36,24.55 52.24,23.66 v1(52.24,23.29)
CAP_LED_Q: length 1.1
  BOTTOM w0.102: Q6501.C 68.97,20.35 R6503.1
CAP_LED_R#: length 3.7
  BOTTOM w0.102: 66.88,18.27 v2(66.88,18.25) ; 66.88,18.27 66.97,18.27 67.69,19 R6502.2 ; 66.88,18.27 66.82,18.33 Q6501.B
CARD1_USB20_CON_N2: length 2.9
  BOTTOM w0.089: U3301.2 12.69,36.24 13.04,35.89 EL3301.2
CARD1_USB20_CON_P2: length 3.6
  BOTTOM w0.089: U3301.3 12.19,37.75 12.45,37.49 12.45,36.14 13.35,35.23 EL3301.1
CARD1_USB20_N2: length 96
  L4 w0.114: v1(21.59,38.86) 21.89,39.17 21.89,39.85 21.01,40.74 21.01,42.8 20.73,43.07 20.73,43.82 20.48,44.08 20.31,44.08 20.03,44.36 20.03,49.07 20.35,49.38 20.35,57.08 20.17,57.25 20.17,60.25 20.78,60.86 20.78,63.02 25.67,67.92 32.73,67.92 33.44,68.62 33.44,70.3 34.9,71.76 49.83,71.76 50.09,71.5 51,71.5 51.83,70.68 51.83,68.9 53.23,67.5 53.23,67.07 53.31,66.99 54.08,66.22 54.08,64.25 54.84,63.49 54.84,63.17 55.19,62.82 55.19,62.79 55.47,62.51 55.5,62.51 55.6,62.41 v1(55.91,62.41)
  BOTTOM w0.089: v1(21.59,38.86) 21.29,38.56 20.07,38.56 19.61,38.1 19.61,37.45 19.4,37.24 ; EL3301.3 14.91,35.64 15.05,35.64 15.69,35 17.16,35 19.4,37.24 ; 19.4,37.24 v2(19.29,37.35) ; CPU1.AU2 68.54,59.12 68.17,59.49 67.77,59.49 66.83,60.43 63.93,60.43 63.4,59.89 62.92,59.89 62.83,59.98 61.59,59.98 61.23,60.35 58.12,60.35 56.3,62.17 56.15,62.17 v1(55.91,62.41)
CARD1_USB20_P2: length 95.8
  L4 w0.114: v1(22.12,38.48) 22.11,38.5 22.11,39.94 21.22,40.83 21.22,42.89 20.95,43.16 20.95,43.91 20.57,44.29 20.4,44.29 20.25,44.45 20.25,48.98 20.56,49.29 20.56,57.17 20.38,57.34 20.38,60.16 20.99,60.77 20.99,62.93 25.76,67.7 32.82,67.7 33.66,68.53 33.66,70.21 34.99,71.54 49.75,71.54 50,71.29 50.91,71.29 51.61,70.59 51.61,68.81 52.45,67.97 53.01,67.41 53.01,66.98 53.09,66.9 53.09,66.9 53.86,66.13 53.86,64.16 54.62,63.4 54.62,63.08 54.98,62.73 54.98,62.7 55.38,62.3 55.41,62.3 55.51,62.19 55.51,62.17 55.65,62.03 55.65,61.88 v1(55.78,61.75)
  BOTTOM w0.089: EL3301.4 14.83,35.4 14.95,35.4 15.59,34.76 17.26,34.76 19.85,37.35 19.85,38 20.17,38.32 20.45,38.32 ; 20.45,38.32 v2(20.45,38.15) ; 20.45,38.32 21.93,38.32 22.1,38.48 v1(22.12,38.48) ; CPU1.AU1 67.97,59.25 67.67,59.25 66.73,60.19 64.03,60.19 63.5,59.65 62.82,59.65 62.73,59.74 61.49,59.74 61.13,60.11 58.02,60.11 56.2,61.93 55.96,61.93 v1(55.78,61.75)
CARD_AV18: length 1
  BOTTOM w0.305: C3308.2 14.38,38.43 U3301.24
CARD_RREF: length 1.4
  BOTTOM w0.305: U3301.1 13.19,37.74 13.54,37.39 R3304.2
CBN: length 2.8
  TOP w0.203: HDA27.28 142.78,89.37
  TOP w0.254: C2708.1 142.16,87.78 142.16,88.76 v2(142.52,89.11) 142.78,89.37
CBP: length 2.7
  TOP w0.203: HDA27.30 143.43,88.19 143.13,87.89 143.13,87.07 143,86.95
  TOP w0.254: 143,86.95 C2708.2
CCD_USB20_CON_N0: length 3.3
  BOTTOM w0.089: 53.64,83.62 53.39,83.87 53.39,84.45 53.6,84.66 LCD1.16 ; 53.64,83.62 54.08,83.19 54.08,82.83 EL5501.2 ; 53.64,83.62 v2(53.81,83.73)
CCD_USB20_CON_P0: length 3
  BOTTOM w0.089: EL5501.1 53.84,82.79 53.84,83.09 53.15,83.77 53.15,84.61 53.1,84.66 LCD1.15
CCD_USB20_N0: length 33.5
  TOP w0.089: v1(53.7,79.35) v2(53.7,78.79)
  L4 w0.114: v1(53.7,79.35) 53.7,78.86 54.48,78.08 54.48,77.4 55.1,76.78 55.77,76.78 60.45,72.1 60.45,71.32 60.15,71.03 60.15,69.15 59.88,68.87 59.88,67.78 60.7,66.96 60.7,62.28 61.32,61.66 61.4,61.66 v1(61.62,61.88)
  BOTTOM w0.089: EL5501.3 54.1,81.23 54.1,80.94 53.4,80.24 53.4,79.64 v1(53.7,79.35) ; v1(61.62,61.88) 61.62,61.91 62,62.3 63.47,62.3 64.16,61.61 67.02,61.61 67.74,60.89 67.74,60.86 67.94,60.66 68.19,60.66 68.22,60.63 68.25,60.63 68.45,60.43 68.45,60.4 68.63,60.22 CPU1.AW2
CCD_USB20_P0: length 33.3
  L4 w0.114: v1(53.06,79.28) 53.06,79.19 54.26,77.99 54.26,77.31 55.01,76.56 55.68,76.56 60.23,72.01 60.23,71.41 59.94,71.12 59.94,69.24 59.66,68.96 59.66,67.69 60.48,66.87 60.48,62.19 61.23,61.44 61.42,61.44 61.44,61.42 61.8,61.42 61.84,61.46 62.09,61.46 v1(62.26,61.62)
  BOTTOM w0.089: 62.85,62.05 63.37,62.05 64.06,61.37 66.92,61.37 67.5,60.79 67.5,60.76 67.84,60.42 67.95,60.42 CPU1.AW1 ; 62.85,62.05 v2(62.85,61.87) ; 62.85,62.05 62.1,62.05 62.05,62 62.05,61.83 v1(62.26,61.62) ; EL5501.4 53.86,81.22 53.86,81.04 53.16,80.34 53.16,79.38 v1(53.06,79.28)
CCLIM: length 3.8
  TOP w0.254: v2(140.65,36.02) 140.65,35.57 140.49,35.4 PR4402.2 PR4404.1 140.94,34.32 v1(141.15,34.11)
  BOTTOM w0.203: PU4401.11 140.54,33.82
  BOTTOM w0.254: 140.54,33.82 140.65,33.94 140.92,33.94 141.1,34.11 v1(141.15,34.11)
CLK_REQG: length 46.2
  L3 w0.102: v1(103.96,85.52) 103.95,85.52 103.84,85.41 103.84,83.95 94.03,74.14 90.53,74.14 87.2,70.82 87.2,68.58 87.66,68.12 87.66,66.19 87.53,66.07 86.79,66.07 86.49,65.76 86.49,60.96 v1(87.55,59.89)
  BOTTOM w0.102: R7005.2 97.73,89.92 v2(97.98,89.68) 100,87.66 102.52,87.66 103.36,86.81 103.36,86.26 103.75,85.87 103.75,85.87 103.95,85.67 103.95,85.53 v1(103.96,85.52) ; v1(87.55,59.89) 87.55,59.82 87.25,59.52 CPU1.AV35
CPVDD: length 11.4
  TOP w0.203: HDA27.29 143.1,88.97 v1(142.67,88.55)
  TOP w0.508: R2709.2 C2705.1 v2(142.49,82.22) 141.78,82.22 C2704.1 141.68,82.3 v1(141.05,82.93)
  L3 w0.508: v1(142.67,88.55) 142.67,83.52 142.09,82.93 v1(141.05,82.93)
CPVEE: length 5.6
  TOP w0.203: 142.03,89.23 142.57,89.78 HDA27.27
  TOP w0.305: 142.03,89.23 141.55,88.76 141.55,86.44 C2709.1
CR_GPIO0: length 1.6
  BOTTOM w0.102: U3301.17 12.69,42.51 13.33,43.16 TP3301.1
DBC_EN: length 40.7
  TOP w0.089: v1(55.75,80.09) 54.59,78.93 54.59,77.7 v2(56.16,76.13) 56.29,76 56.7,76 57.13,75.57 58.64,75.57 58.67,75.54 59.64,75.54 62.03,73.15 62.46,73.15 62.71,72.9 62.71,72.52 62.46,72.26 62.23,72.04 62.23,71.86 62.03,71.66 62.03,68 61.78,67.75 61.78,67.01 62.03,66.76 62.38,66.76 62.64,67.01 62.64,67.18 62.92,67.46 63.27,67.46 64.54,66.19 64.54,65.77 65.44,64.87 66.52,64.87 68.78,62.61 69.9,62.61 70.71,61.8 72.56,61.8 72.87,61.49 72.87,60.37 73.75,59.49 75.06,59.49 v1(75.55,59.98)
  BOTTOM w0.089: R5501.2 55.22,81.98 55.22,80.93 55.63,80.52 55.63,80.32 55.75,80.19 v1(55.75,80.09) ; CPU1.AY14 v1(75.55,59.98)
DBC_EN_R: length 4.3
  BOTTOM w0.089: LCD1.22 56.6,84.49 56.66,84.43 56.66,84.41 56.71,84.35 56.71,83.73 57.05,83.39 v2(57.05,82.02) R5501.1
DBRDY1: length 4.5
  TOP w0.102: RN6802.1 91.58,16.19 91.34,16.44 91.34,16.62 v2(91.34,16.63) 91.34,16.63 91.34,17.96 91.57,18.19 HDT1.15
DBRDY2: length 6.7
  TOP w0.102: HDT1.13 v2(90.3,17.25) 90.3,16.7 91.52,15.47 92.67,15.47 93.04,15.84 93.04,16.19 RN6802.2
DBRDY3: length 9
  TOP w0.102: RN6802.3 93.54,15.39 93.4,15.24 90.34,15.24 v2(89.53,16.06) 89.03,16.56 HDT1.11
DC_IN_D: length 3.3
  BOTTOM w0.254: PQ4405.3 23.33,56.43 22.18,57.57 v2(22.16,57.57) 21.79,57.94 PR4420.2
DCBATOUT: length 14.8
  TOP w0.508: v1(132.79,34.55) 133.11,34.55 v2(133.41,34.25) 135.47,32.19 135.47,28.57 135.1,28.2 135.1,25.4 135.28,25.22
  BOTTOM w0.203: PU4501.12 14.78,13.05 14.91,13.18 15.16,13.18 15.54,13.57 16.6,13.57 17.04,13.13
  BOTTOM w0.508: PR4477.1 v1(132.79,34.55)
  vias: v2(24.72,66.85) v2(24.8,17.75) v2(36.51,71.12) v2(61.38,12.79) v2(121.64,10.15) v2(137.05,19.49) v3(18.57,12.35) v3(19.41,12.35) v3(20.07,30.2) v3(20.24,12.35) v3(20.9,30.23) v3(21.08,12.35) v3(21.46,29.57) v3(24.64,45.37) v3(24.64,44.53) v3(24.59,43.69) v3(24.64,42.85) v3(30.53,65.48) v3(30.56,66.32) v3(31.39,66.32) v3(31.39,65.48) v3(32.28,66.32) v3(32.26,65.48) v3(33.05,65.94) v3(38.84,81.82) v3(38.86,82.68) v3(41.4,68.99) v3(42.24,68.99) v3(43.08,68.99) v3(131.55,14.43) v3(131.5,13.59) v3(132.33,13.59) v3(132.38,14.43) v3(133.22,14.43) v3(133.2,13.59) v3(134.04,13.59) v3(134.06,14.43) v3(136.17,25.55) v3(136.17,24.59) v3(136.17,23.57) v3(136.17,22.61) v3(137.01,25.55) v3(137.01,24.67) v3(137.01,23.65) v3(137.01,22.63) v3(142.6,52.81) v3(143.46,52.81) v3(144.3,52.83)
DDR4_A_DRAMRST#: length 55.2
  TOP w0.14: v1(88.11,41.07) 87.77,41.07 ED501.1 ; v2(129.01,47.25) 129.01,47.25 128.63,46.87 v1(128.6,46.87) 128.57,46.85 C1211.1 128.04,46.18 v1(127.89,46.33)
  L3 w0.216: v1(88.11,41.07) 87.93,40.9 87.93,38.64 89.39,37.18 89.39,36.06 89.81,35.64 116.43,35.64 123.11,42.32 124.21,42.32 127.89,46 v1(127.89,46.33)
  BOTTOM w0.14: CPU1.G38 88.16,42.18 88.16,41.12 v1(88.11,41.07) ; v1(128.6,46.87) DIMM1.108
DDR_VREF_S3: length 5.5
  BOTTOM w0.102: 92.89,50.09 90.91,50.09 90.83,50.02 90.55,50.02 90.25,50.32 CPU1.AA40
  BOTTOM w0.508: TP502.1 94.72,51 94.17,50.45 93.25,50.45 92.89,50.09
DM1_SA0: length 4
  TOP w0.102: v1(128.65,85.78) 128.91,85.52 R1210.2 R1209.2 v2(130.28,84.71)
  BOTTOM w0.102: DIMM1.256 128.75,85.88 v1(128.65,85.78)
DM1_SA1: length 6.4
  TOP w0.102: R1207.2 125.76,85.3 126.31,85.85 126.69,85.85 127.28,86.44 R1208.2 127.28,86.77 v1(127.79,87.28) 127.7,87.28 v2(127.35,87.62)
  BOTTOM w0.102: DIMM1.260 128.19,86.88 v1(127.79,87.28)
DM1_SA2: length 7.2
  TOP w0.102: v1(128.02,62.71) 127.46,63.27 127.46,64.7 R1201.2 127.31,65.1 127.31,65.73 127.34,65.76 v2(127.34,65.86) 127.34,65.97 128.02,66.65 R1205.2
  BOTTOM w0.102: DIMM1.166 128.4,63.38 128.02,62.99 v1(128.02,62.71)
DMIC_CLK: length 135.2
  TOP w0.089: R2720.1 151.25,88.75 151.79,88.22 151.92,88.22 C2725.1 152.32,88.06 155.35,91.09 155.35,92.64 157.05,94.34 157.05,97.56 v2(156.05,98.55) 153.15,101.45 90.95,101.45 90.17,100.67 89.82,100.67 89.19,101.29 75.46,101.29 75.11,100.94 v1(74.83,100.94) ; RN5502.3 54.51,81.56 EC5506.1 54.51,80.6 54.48,80.57 v1(54.48,80.09)
  L4 w0.14: v1(54.48,80.09) 53.04,81.53 53.04,84.71 54.32,85.99 56.03,85.99 58.57,88.53 58.57,91.63 59.94,93 59.94,93.47 62.2,95.72 70.29,95.72 74.83,100.26 v1(74.83,100.94)
DMIC_CLK_C: length 3.4
  TOP w0.089: v2(53.89,83.32) v1(54.41,83.54) 54.54,83.41 RN5502.2
  BOTTOM w0.089: LCD1.18 54.6,83.74 v1(54.41,83.54)
DMIC_CLK_R: length 2.2
  TOP w0.089: R2720.2 149.68,88.86 149.17,89.37 HDA27.3
DMIC_DATA: length 137.7
  TOP w0.089: v1(75.11,101.55) 75.34,101.78 90.75,101.78 90.78,101.8 153.39,101.8 157.48,97.71 v2(157.48,94.62) 157.48,94.26 155.7,92.48 155.7,90.71 154.03,89.03 154.03,87.17 EC2711.1 153.31,87.38 R2718.1 ; v1(55.12,80.09) 55.07,80.14 55.07,80.7 EC5505.1 55.19,80.82 RN5502.4
  L4 w0.14: v1(55.12,80.09) 55.12,80.09 53.5,81.71 53.5,84.54 54.5,85.54 58.61,85.54 59.49,86.42 59.49,89.66 59.76,89.94 59.76,90.36 59.57,90.55 59.57,91.99 60.4,92.83 60.4,93.3 62.32,95.22 70.45,95.22 71.25,96.01 71.25,96.04 75.31,100.1 75.31,101.35 v1(75.11,101.55)
DMIC_DATA_C: length 3.4
  TOP w0.089: v1(55.04,83.54) 55.04,83.54 55.04,83.17 55.19,83.02 RN5502.1
  BOTTOM w0.089: LCD1.19 55.1,84.63 55.04,84.57 v1(55.04,83.54) 55.04,83.39 55.32,83.11 55.32,83.1 v2(55.35,83.07)
DMIC_DATA_R: length 4.3
  TOP w0.089: HDA27.2 149.17,88.97 150.25,87.9 v2(150.88,87.9) 151.58,87.9 R2718.2
DP_2K_ZVSS: length 5
  BOTTOM w0.102: R803.1 77.5,35.8 v2(77.5,36.49) 77.5,37.87 77.39,37.97 77.39,38.76 77.5,38.87 77.5,39.16 77.45,39.22 77.45,39.53 77.75,39.83 CPU1.B18
DP_150_ZVSS: length 2.6
  TOP w0.102: R802.1 78.38,40.64 v2(78.38,40.92) 78.88,41.41 v1(78.88,41.55)
  BOTTOM w0.102: CPU1.D21 79.01,41.51 78.92,41.51 v1(78.88,41.55)
DP_HPD0_C: length 5.4
  TOP w0.102: RN5503.1 58.97,81.1 58.9,81.18 v2(58.9,81.72) 58.67,81.95 58.67,82.55 58.57,82.65 58.57,83.31 58.6,83.34 58.6,83.7 58.57,83.73 58.57,83.88 58.51,83.93 58.51,83.96 58.1,84.37 v1(57.8,84.37)
  BOTTOM w0.102: v1(57.8,84.37) 57.66,84.51 57.66,84.53 57.6,84.59 LCD1.24
E51_RX1: length 4.5
  TOP w0.102: R6109.2 163.75,85.05 TP6102.1 163.24,85.08 v1(163.07,84.91)
  BOTTOM w0.102: v1(163.07,84.91) 163.07,84.85 161.72,83.5 WLAN1.46
E51_RX2: length 3.8
  TOP w0.102: v1(163.59,79.93) 163.59,80.35 163.58,80.36 TP6101.1
  BOTTOM w0.102: WLAN1.58 161.63,80.5 162.22,79.92 163.58,79.92 v1(163.59,79.93)
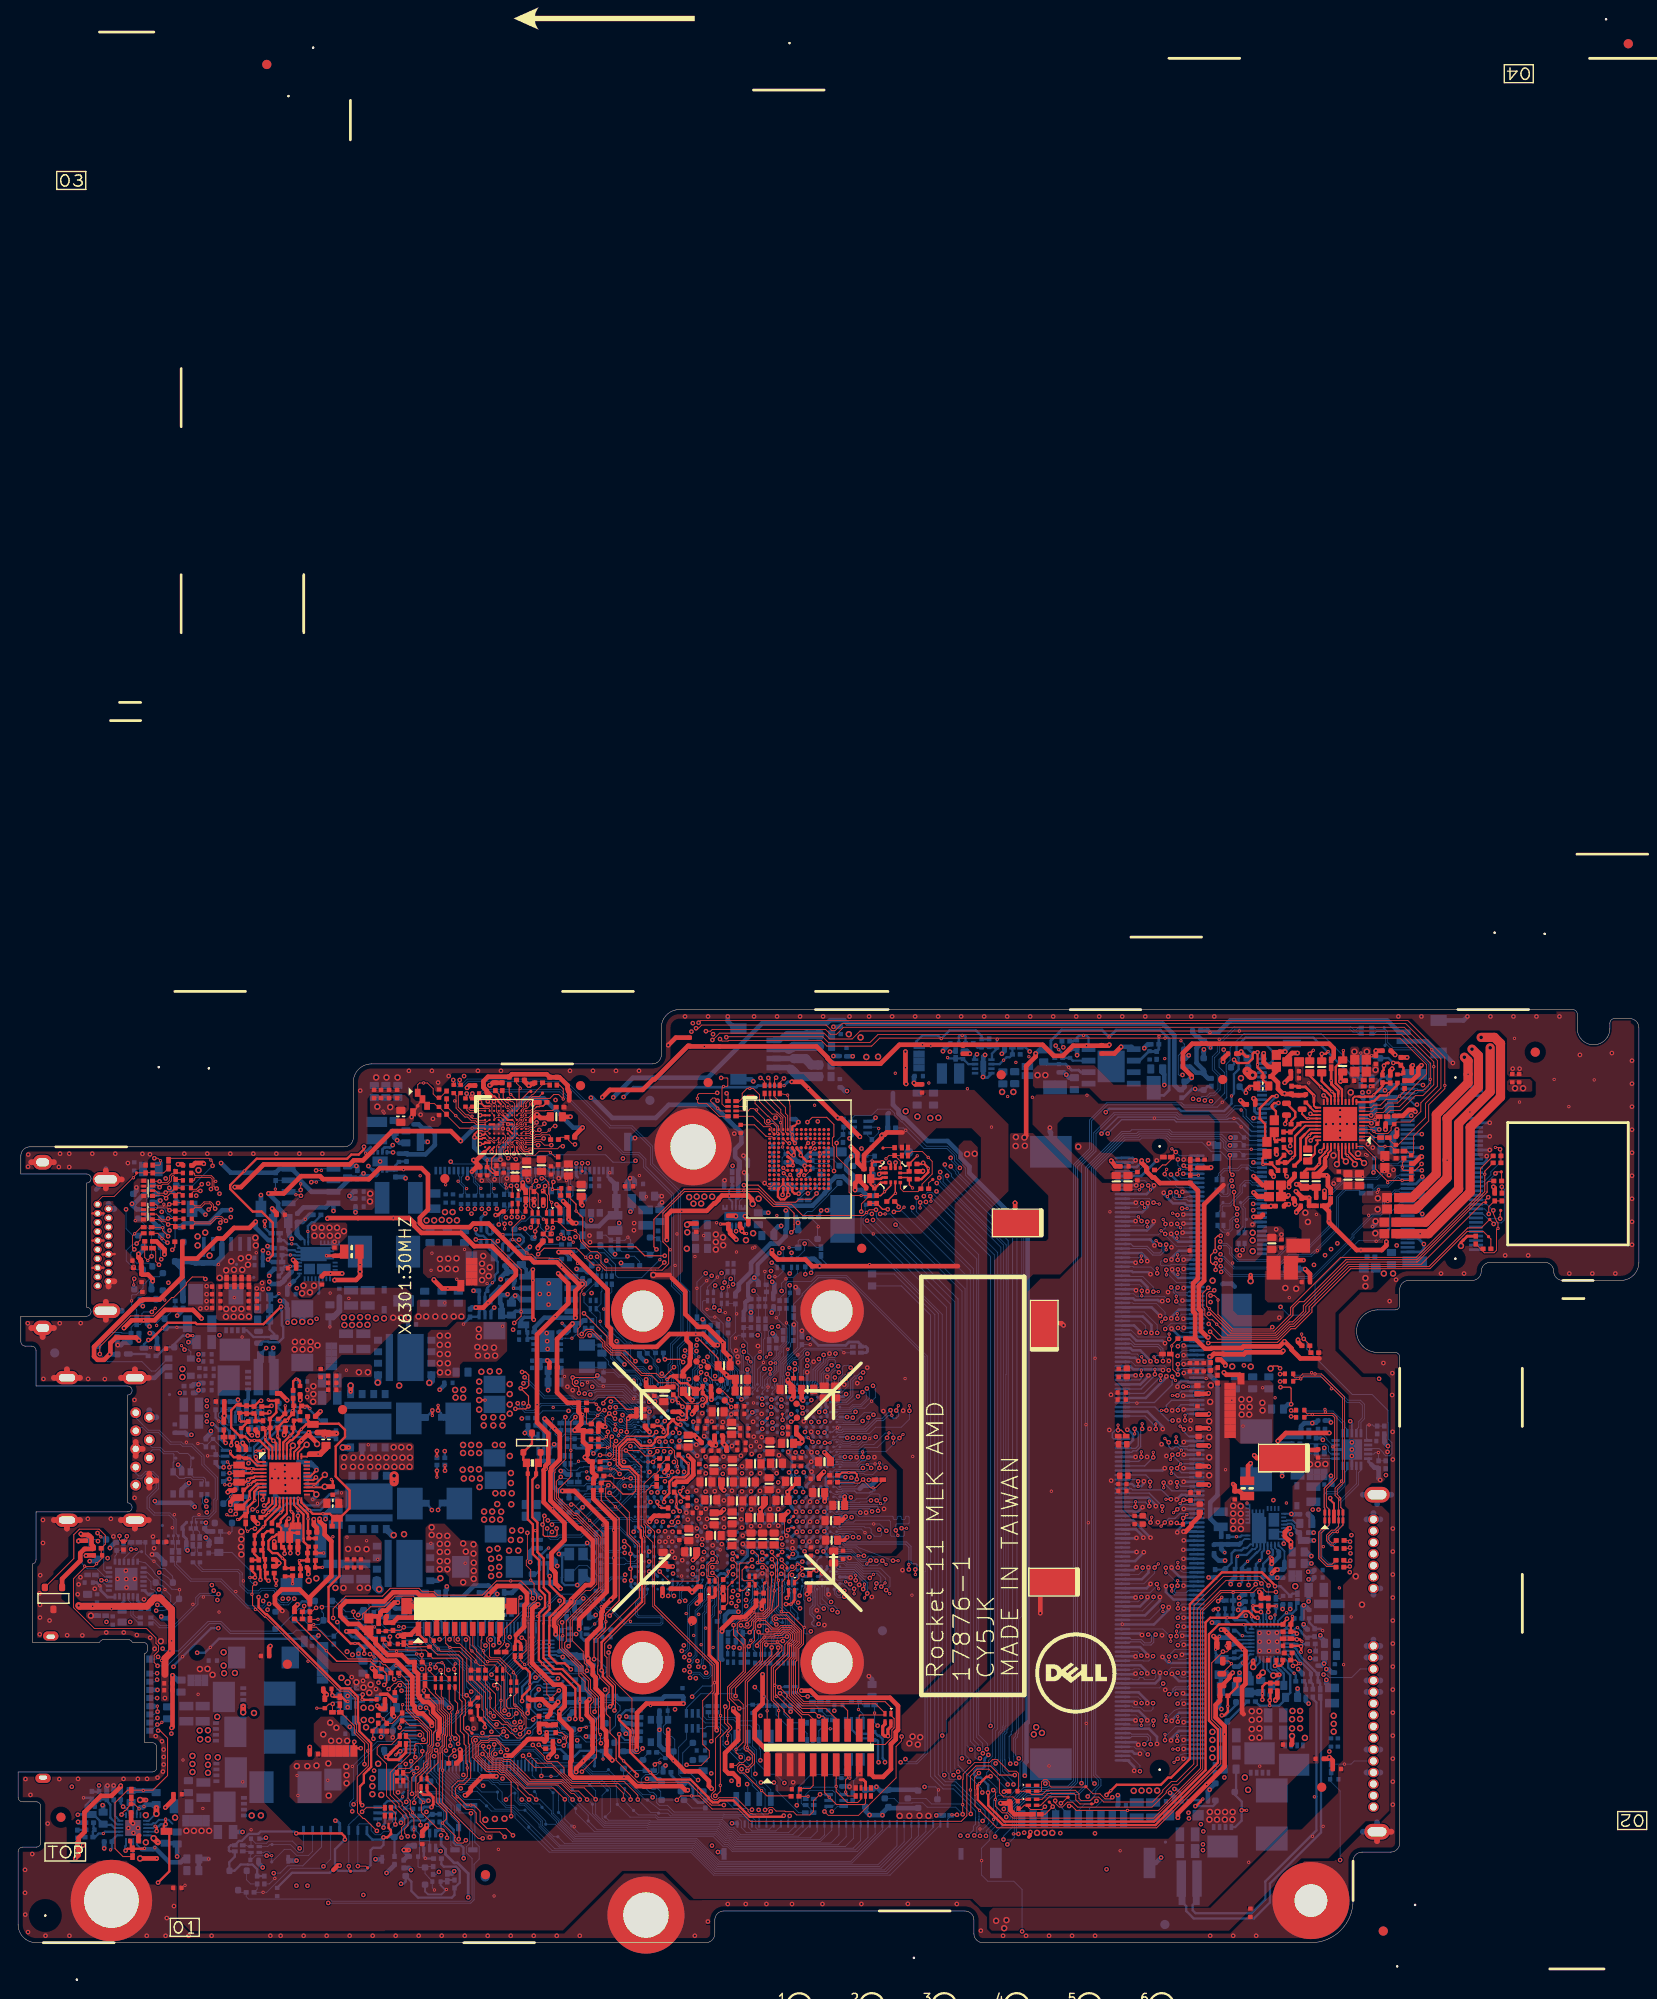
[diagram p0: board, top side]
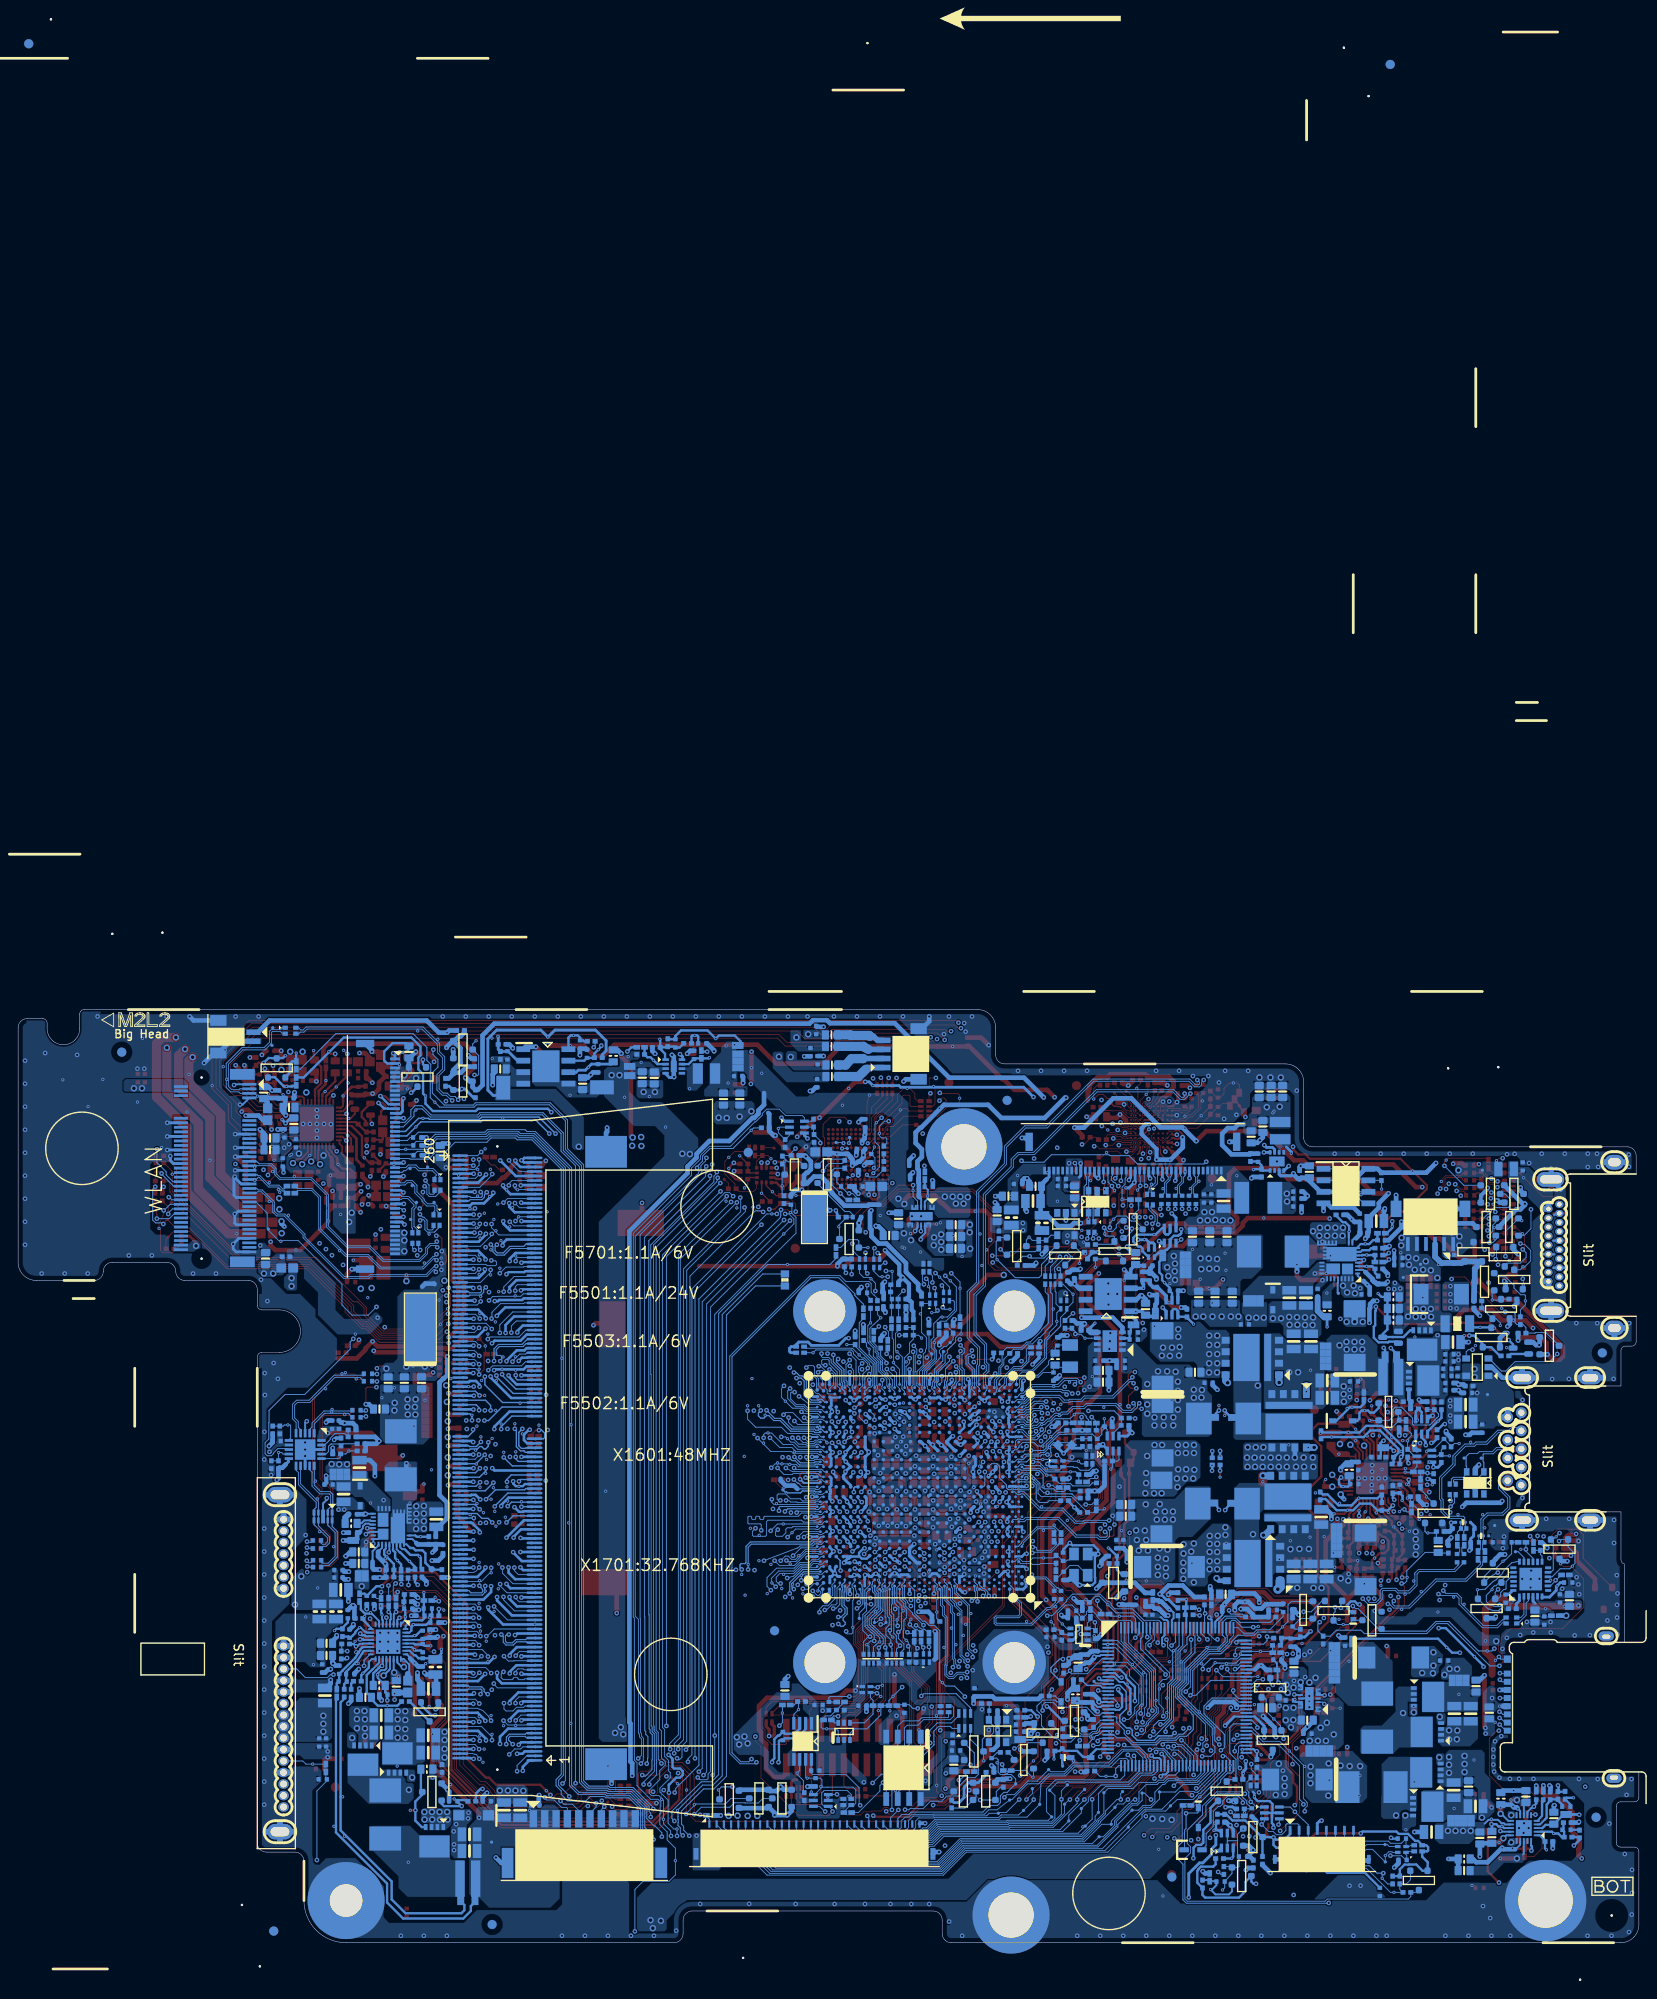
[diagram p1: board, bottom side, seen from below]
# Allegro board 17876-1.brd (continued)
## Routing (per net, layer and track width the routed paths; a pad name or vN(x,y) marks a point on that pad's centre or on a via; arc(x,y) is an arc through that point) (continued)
E51_TX1: length 7.3
  TOP w0.102: R6107.2 R6108.2 163.68,87.48 v1(163.58,87.58) 163.38,87.78 v2(163.05,87.78)
  BOTTOM w0.102: WLAN1.44 161.81,84 162.56,84.75 162.56,85.09 163.58,86.11 v1(163.58,87.58)
E51_TXD: length 191.2
  TOP w0.102: v1(131.44,69.42) 131.69,69.42 133.82,67.29 138.75,67.29 140.72,69.25 140.72,70.05 141.41,70.75 141.92,70.75 146.56,75.39 154.38,75.39 161.89,82.9 v2(161.89,84.83) 161.89,85.16 R6107.1
  L3 w0.102: v1(131.44,69.42) 131.79,69.08 131.85,69.01 131.85,68.12 131.6,67.87 131.39,67.87 130.56,67.03 130.56,61.07 130.47,60.98 130.47,19.2 125.02,13.74 110,13.74 109.7,13.44 108.89,13.44 108.51,13.83 108.36,13.98 108.36,14.27 108.14,14.49 108.14,14.53 107.08,15.59 106.14,15.59 105.8,15.93 102.13,15.93 102.02,15.81 91.96,15.81 90.5,17.27 85.37,17.27 85.01,17.63 85.01,17.81 84.66,18.16 82.92,18.16 81.85,19.24 81.43,19.24 81.24,19.43 80.25,19.43 80.08,19.6 78.64,19.6 77.39,20.84 75.7,20.84 75.39,21.15 69.94,21.15 69.22,20.42 67.91,20.42 67.75,20.58 65.16,20.58 65,20.41 63.67,20.41 63.47,20.61 60.9,20.61 60.38,20.09 59.28,20.09 58.98,20.4 58.98,20.63 58.22,21.39 55.69,21.39 54.51,22.57 54.17,22.57 v1(53.95,22.79)
  BOTTOM w0.102: v1(53.95,22.79) 53.46,22.79 51.59,24.66 51.59,28.37 50.88,29.08 50.88,32.27 50.35,32.8 U2401.111
EC_AGND: length 17.2
  TOP w0.508: v1(47.42,35.89) 47.24,36.07 47.24,36.49 46.87,36.86 45.96,36.86 45.5,37.31 44.97,37.31 44.6,36.94 v1(44.6,36.7) 44.6,36.59 43.89,35.88 41.92,35.88 R2438.2 40.61,35.33 C2417.2 40.59,35.92 C2436.2
  BOTTOM w0.203: U2401.103 47.15,35.62 v1(47.42,35.89)
  BOTTOM w0.508: v1(44.6,36.7) 44.6,37.26 44.25,37.62 v2(43.49,37.62) 43.1,37.62 42.37,36.89 41.65,36.89 41.17,37.37 39.32,37.37 C2438.1
EC_AVCC: length 13.1
  TOP w0.508: C2436.1 38.94,36.02 R2409.1 ; C2436.1 40.01,36.25 40.01,36.45 40.21,36.65 40.64,36.65 41.53,37.54 v1(41.91,37.54) ; C2436.1 39.8,35.99 R2437.1
  BOTTOM w0.203: 45.97,36.5 45.97,36.17 46.51,35.64 46.55,35.64 46.75,35.43 U2401.102
  BOTTOM w0.508: 45.97,36.5 46,36.53 46,37.09 45.75,37.33 v2(45.73,37.33) 45.73,37.42 44.96,38.19 C2416.1 44.87,38.55 42.44,38.55 41.91,38.02 v1(41.91,37.54)
EC_BRIGHTNESS: length 94.5
  TOP w0.102: v1(55.96,78.82) v2(55.4,78.82)
  L3 w0.127: v1(47.62,33.48) 46.71,34.39 46.53,34.39 45.64,35.28 43.51,35.28 43.03,35.76 41.49,35.76 40.94,35.21 36.85,35.21 36.58,35.49 35.97,35.49 35.39,34.91 34.86,34.91 33.95,35.83 32.42,35.83 31.99,36.26 30.29,36.26 28.77,37.78 28.77,38.6 28.12,39.24 26.41,39.24 26.37,39.21 26,39.21 24.04,41.17 24.04,46.22 24.94,47.12 24.94,48.46 25.15,48.67 25.15,49.77 26.64,51.27 26.64,52.69 27.5,53.54 27.5,54.97 27.28,55.18 27.28,57.55 26.38,58.45 26.38,65.26 28.8,67.69 28.8,68.8 29.61,69.6 32.21,69.6 32.41,69.8 33.22,69.8 34.16,70.74 46.23,70.74 50.09,74.6 50.09,75.98 52.59,78.49 55.63,78.49 v1(55.96,78.82)
  BOTTOM w0.102: D5502.2 56.71,77.79 55.96,78.54 v1(55.96,78.82) ; v1(47.62,33.48) 47.65,33.48 48.35,34.18 U2401.106
EC_MUTE#: length 201.4
  TOP w0.102: R2497.2 58.22,21.41 57.94,21.41 57.51,21.84 v1(57.47,21.84) ; v1(154.91,85.96) 154.2,85.24 R2712.1 152.89,85.24 152.79,85.35 152.79,85.59 v2(152.79,85.6) 152.79,86.1 152.96,86.26 R2717.2
  L3 w0.102: v1(108.8,14.76) 108.88,14.84 108.88,15.59 108.33,16.13 107.24,16.13 107.24,16.13 106.88,16.13 106.88,16.13 106.26,16.13 106.01,16.38 101.94,16.38 101.83,16.27 93.34,16.27 91,18.62 83.11,18.62 82.04,19.69 81.75,19.69 81.55,19.89 80.44,19.89 80.27,20.05 78.82,20.05 77.57,21.31 75.88,21.31 75.58,21.6 69.75,21.6 69.03,20.88 68.1,20.88 67.94,21.03 64.97,21.03 64.81,20.87 63.86,20.87 63.63,21.1 58.86,21.1 58.12,21.84 v1(57.47,21.84) ; v1(133.07,98.58) 133.91,99.42 152.93,99.42 156.11,96.24 156.11,87.15 v1(154.91,85.96)
  BOTTOM w0.102: v1(57.47,21.84) 57.63,21.84 57.72,21.75 U2401.30 ; v1(133.07,98.58) 133.12,98.53 133.12,98.04 132.56,97.49 132.56,96.65 133.18,96.03 133.18,93.78 131.85,92.46 128.68,92.46 128.42,92.71 120.16,92.71 118.26,90.82 118.26,87.65 116.48,85.87 116.48,17.88 115.88,17.28 113.72,17.28 113.57,17.13 111,17.13 108.8,14.93 v1(108.8,14.76)
EC_VCC1V8: length 2.9
  BOTTOM w0.203: U2401.88 42.39,30.15
  BOTTOM w0.508: R2486.2 41.12,30.1 41.61,30.58 v2(41.71,30.58) 41.96,30.58 42.39,30.15
ECRST#: length 29.6
  TOP w0.102: v1(49.5,27.31) 49.58,27.31 49.94,26.95 R2465.2 50.65,27.05 C2444.2
  BOTTOM w0.102: Q2401.E 38.34,37.68 38.73,37.29 38.73,35.46 v2(39.34,34.86) 39.9,34.3 42.08,34.3 42.44,33.94 44.25,33.94 44.98,33.2 44.98,33 46.05,31.93 46.08,31.93 46.1,31.9 47.39,31.9 49.25,30.05 49.25,27.56 v1(49.5,27.31) 48.9,27.31 47.25,28.95 U2401.85
ECSCI#_KBC: length 53.7
  TOP w0.102: R1634.1 69.95,50.47 69.31,49.83 69.31,46.3 69.54,46.06 69.57,46.06 70.25,45.38 70.25,37.27 76.83,30.69 76.83,27.68 76.68,27.53 76.68,22.41 v1(76.51,22.24) ; v1(60.23,21.76) 60.51,22.04 v2(60.51,22.7) 60.02,23.19 R2423.2
  L3 w0.102: v1(76.51,22.24) 76.21,22.54 68.54,22.54 67.75,21.75 65.04,21.75 64.62,21.33 64.05,21.33 63.62,21.76 v1(60.23,21.76)
  BOTTOM w0.102: v1(60.23,21.76) 59.57,21.76 59.18,22.15 U2401.29
ECSMI#_KBC: length 138.4
  TOP w0.089: v1(61.06,48.36) 61.34,48.36 v2(63.08,46.62) 64.55,45.15 64.55,38.92 61.17,35.54 61.17,33.34 62.38,32.13 62.38,31.36 62.49,31.25 62.49,30.87 62.79,30.57 v1(62.79,30.02)
  L3 w0.14: v1(97.41,19.92) 96.96,20.37 93.66,20.37 92.29,21.73 85.9,21.73 82.62,25.01 82.62,25.33 82.22,25.73 81.91,25.73 79.66,27.97 74.16,27.97 74.07,27.88 70.75,27.88 70.37,27.5 67.53,27.5 65.53,29.5 65.53,29.57 64.48,30.63 63.39,30.63 63.04,30.28 v1(62.79,30.02)
  BOTTOM w0.089: R2422.2 63.07,29.75 v1(62.79,30.02) 62.77,30.01 62.77,29.84 62.62,29.69 60.89,29.69 60.58,30 60.58,30.02 59.25,31.35 U2401.6 ; v1(97.41,19.92) 97.58,19.74 99.2,19.74 100.35,20.89 100.35,64.74 91.47,73.63 88.18,73.63 87.55,73 84.99,73 84.74,72.75 84.74,71.81 84.71,71.78 84.71,71.76 84.45,71.5 84.43,71.5 84.05,71.12 R1635.1 ; R1632.1 60.1,48.64 60.38,48.36 v1(61.06,48.36)
EDP_AUX_CON_N: length 3.3
  BOTTOM w0.089: 52.37,83.24 52.37,83.85 51.95,84.28 51.95,84.51 52.1,84.66 LCD1.13 ; 52.37,83.24 v2(52.53,83.24) ; 52.37,83.24 52.37,82.78 C5505.1
EDP_AUX_CON_P: length 3.1
  BOTTOM w0.089: C5501.1 52.17,82.68 52.17,83.77 51.75,84.19 51.75,84.51 51.6,84.66 LCD1.12
EDP_AUX_CPU_N: length 61.5
  L4 w0.127: v1(75.49,43.91) 74.91,43.33 74.63,43.33 73.74,42.44 73.74,40.95 73.01,40.22 69.32,40.22 68.66,39.56 66.73,39.56 66.07,40.23 66.07,48.01 64.14,49.94 64.14,51.38 62.13,53.39 62.13,53.77 62.23,53.88 62.23,59.09 60.1,61.22 60.1,61.55 59.86,61.79 59.86,66.58 59.04,67.4 59.04,69.25 59.31,69.52 59.31,71.89 58.91,72.29 57.8,72.29 55.93,74.16 55.93,74.89 54.88,75.94 54.75,75.94 53.63,77.05 53.63,77.73 52.26,79.1 52.26,80.5 52.76,81 v1(52.83,81)
  BOTTOM w0.089: v1(52.83,81) 52.7,81.13 C5505.2 ; CPU1.H15 75.88,43.52 v1(75.49,43.91)
EDP_AUX_CPU_P: length 61.6
  L4 w0.127: v1(51.94,81) 52.06,80.89 52.06,80.66 52.03,80.63 52.03,79 53.4,77.63 53.4,76.96 54.65,75.71 54.79,75.71 55.7,74.79 55.7,74.07 57.71,72.06 58.82,72.06 59.08,71.8 59.08,69.62 58.81,69.34 58.81,67.31 59.63,66.49 59.63,61.7 59.87,61.46 59.87,61.13 62,58.99 62,53.97 61.9,53.87 61.9,53.29 63.91,51.28 63.91,49.85 65.84,47.92 65.84,40.13 66.64,39.33 68.75,39.33 69.41,40 73.11,40 73.96,40.85 73.96,42.34 74.73,43.11 75.03,43.11 75.21,43.28 75.55,43.28 v1(75.71,43.12)
  BOTTOM w0.089: v1(75.71,43.12) 75.86,43.12 76.1,42.88 CPU1.G15 ; v1(51.94,81) C5501.2
EDP_BLON: length 50.3
  L3 w0.102: v1(74.4,27.15) 74.29,27.26 70.8,27.26 70.57,27.02 67.14,27.02 65.56,28.6 61.61,28.6 60.3,27.29 57.2,27.29 57.08,27.41 55.4,29.08 51.67,29.08 50.99,29.77 47.83,29.77 v1(47.5,30.1)
  BOTTOM w0.102: CPU1.B23 80.5,39.46 79.94,38.9 79.94,36.35 79.07,35.49 78.79,35.49 78.54,35.23 78.54,35.21 78.35,35.03 77.75,35.03 77.17,34.45 77.17,30.94 77.21,30.9 77.21,29.04 v2(76.87,28.7) 76.5,28.33 75.55,28.33 74.4,27.18 v1(74.4,27.15) ; U2401.91 43.99,31.35 44.27,31.09 44.5,30.86 46.74,30.86 v1(47.5,30.1)
EDP_HPD_CPU: length 59.8
  TOP w0.089: v1(71.32,75.08) 70.71,74.47 64.89,74.47 64.33,75.03 64.33,75.9 63.95,76.27 63.2,76.27 62.09,77.39 62.09,77.54 61.94,77.68 61.94,78.08 61.59,78.44 61.59,78.52 v2(61.48,78.62) 60.59,78.62 59.82,79.39 R5507.2 59.74,79.63 RN5503.4 ; v1(75.55,41.52) 75.16,41.13 75.16,40.03 75.03,39.91 71.86,39.91 71.02,40.74 71.02,40.77 v1(70.82,40.97)
  L3 w0.14: v1(70.69,64.24) 70.97,64.52 70.97,64.57 71.15,64.74 71.15,65.28 72.07,66.2 72.07,72.36 71.32,73.1 v1(71.32,75.08)
  L4 w0.14: v1(70.69,64.24) 70.69,63.12 70.55,62.99 70.55,61.87 69.18,60.5 69.18,55.89 68.77,55.48 68.77,47.23 69.23,46.77 69.23,42.99 69.73,42.5 69.83,42.5 70.82,41.51 v1(70.82,40.97)
  BOTTOM w0.089: v1(75.55,41.52) 75.95,41.12 CPU1.D15
EDP_TX_CON_N0: length 3.2
  BOTTOM w0.089: C5507.1 50.72,82.75 50.72,83.48 50.25,83.96 50.25,84.51 50.1,84.66 LCD1.9
EDP_TX_CON_N1: length 3.3
  BOTTOM w0.089: v2(48.56,84.05) 48.75,84.05 ; 48.75,84.05 48.75,83.81 49.15,83.41 49.15,82.7 C5513.1 ; 48.75,84.05 48.75,84.51 48.6,84.66 LCD1.6
EDP_TX_CON_P0: length 3.3
  BOTTOM w0.089: 50.93,83.26 v2(51.08,83.26) ; 50.93,83.26 50.93,82.7 C5506.1 ; 50.93,83.26 50.93,83.57 50.45,84.04 50.45,84.51 50.6,84.66 LCD1.10
EDP_TX_CON_P1: length 3.3
  BOTTOM w0.089: 49.35,83.24 v2(49.5,83.24) ; 49.35,83.24 49.35,83.49 48.95,83.89 48.95,84.51 49.1,84.66 LCD1.7 ; 49.35,83.24 49.35,82.75 C5510.1
EDP_TX_CPU_N0: length 57.2
  L4 w0.127: v1(50.42,81) 50.48,80.94 50.48,80.12 51.23,79.37 51.23,78.05 54.91,74.37 54.91,73.23 56.54,71.6 56.54,70.19 57.59,69.13 57.59,65.22 57.99,64.82 58.49,64.82 58.86,64.45 58.86,61.37 59.11,61.13 59.11,60.79 59.69,60.21 59.69,57.36 61.06,55.99 61.06,53.01 61.77,52.3 61.77,51.36 63.02,50.12 63.02,48.22 65.28,45.96 65.28,40.04 66.56,38.76 71.4,38.76 71.75,38.41 v1(71.75,38.28)
  BOTTOM w0.089: CPU1.B9 72.8,39.5 72.57,39.27 72.57,39.24 72.39,39.07 72.2,39.07 71.86,38.72 71.86,38.38 v1(71.75,38.28) ; v1(50.42,81) C5507.2
EDP_TX_CPU_N1: length 60.8
  L4 w0.127: v1(73,37.67) 72.99,37.67 72.94,37.62 66.99,37.62 64.82,39.79 64.82,44.49 61.62,47.69 61.62,50.43 61.01,51.04 61.01,51.97 60.3,52.68 60.3,55.65 58.93,57.02 58.93,59.6 57.82,60.71 57.82,61.44 57.95,61.56 57.95,63.72 56.2,65.47 56.2,68.6 55.78,69.02 55.78,71.28 53.72,73.34 53.72,73.4 53.44,73.69 53.37,73.69 52.91,74.15 52.91,75.3 51.27,76.94 50.25,76.94 49.12,78.07 49.12,80.77 v1(48.9,81)
  BOTTOM w0.089: CPU1.B10 73.35,39.82 73.03,39.51 73.03,39.21 73.1,39.14 73.1,38.89 73,38.79 v1(73,37.67) ; v1(48.9,81) C5513.2
EDP_TX_CPU_P0: length 57.1
  L4 w0.127: v1(72.39,38.28) 71.68,38.99 66.66,38.99 65.51,40.14 65.51,46.06 63.25,48.32 63.25,50.21 62,51.46 62,52.4 61.29,53.11 61.29,56.08 59.92,57.46 59.92,60.3 59.33,60.89 59.33,61.23 59.09,61.47 59.09,64.54 58.58,65.05 58.08,65.05 57.82,65.31 57.82,69.23 56.77,70.28 56.77,71.7 55.14,73.32 55.14,74.46 51.46,78.15 51.46,79.47 50.71,80.22 50.71,80.66 51.05,81 v1(51.18,81)
  BOTTOM w0.089: CPU1.A9 72.65,39.02 72.49,38.86 72.29,38.86 72.11,38.69 72.11,38.48 72.31,38.28 v1(72.39,38.28) ; v1(51.18,81) C5506.2
EDP_TX_CPU_P1: length 60.6
  L4 w0.127: v1(49.66,81) 49.35,80.7 49.35,78.16 50.35,77.17 51.36,77.17 53.14,75.39 53.14,74.25 53.47,73.92 53.53,73.92 53.95,73.5 53.95,73.43 56.01,71.38 56.01,69.12 56.43,68.7 56.43,65.56 58.18,63.81 58.18,61.47 58.05,61.34 58.05,60.8 59.16,59.7 59.16,57.12 60.53,55.75 60.53,52.78 61.24,52.06 61.24,51.13 61.85,50.52 61.85,47.79 65.05,44.59 65.05,39.89 67.09,37.85 72.57,37.85 72.82,38.1 73.18,38.1 73.53,37.75 v1(73.63,37.75)
  BOTTOM w0.089: v1(73.63,37.75) 73.51,37.75 73.2,38.05 73.2,38.69 73.35,38.83 CPU1.A10 ; v1(49.66,81) 49.66,81 49.66,81.54 C5510.2
EGPIO95: length 3.5
  TOP w0.102: v1(75.36,63.6) 74.88,64.09 TP1708.1
  BOTTOM w0.102: CPU1.BA14 75.31,61.51 75.31,61.74 74.98,62.07 74.98,63.14 75.36,63.52 v1(75.36,63.6)
EGPIO96: length 3.2
  TOP w0.102: v1(75.39,62.97) 75.39,62.79 TP1709.1
  BOTTOM w0.102: CPU1.AY15 75.85,61.17 75.85,61.4 75.51,61.73 75.51,61.85 75.39,61.98 v1(75.39,62.97)
EGPIO99: length 4.1
  TOP w0.102: TP1710.1 76.12,63.73 v1(75.67,64.19)
  BOTTOM w0.102: v1(75.67,64.19) 76.53,63.32 76.53,62.09 76.65,61.97 CPU1.BA16
EGPIO100: length 4.4
  TOP w0.102: TP1711.1 76.66,62.1 v1(76,62.77)
  BOTTOM w0.102: CPU1.AY16 76.65,60.8 76.35,61.1 76.35,61.41 76.4,61.47 76.4,61.93 76.3,62.03 76.3,62.46 v1(76,62.77)
EMMC_CLK: length 0.8
  BOTTOM w0.089: R6312.1 83.34,87.07
EMMC_CLK_R: length 35.4
  TOP w0.089: v1(56.72,89.38) 56.65,89.32 U6304.G10
  L3 w0.14: v1(82.8,90.68) 82.77,90.65 77.54,90.65 76.36,91 75.87,91.49 75.87,91.49 75.76,91.61 75.25,91.8 74.85,91.8 74.05,91.65 73.9,91.65 71.51,91.03 67.59,90.01 67.34,89.97 64.37,89.97 61.98,87.58 61.24,87.58 60.57,86.91 59.21,86.91 58.83,86.53 58.08,86.53 56.21,88.39 56.21,88.88 v1(56.72,89.38)
  BOTTOM w0.089: v1(82.8,90.68) 83.26,90.68 83.82,90.12 v2(83.82,89.34) 83.82,89.07 83.59,88.84 83.11,88.84 83.02,88.75 83.02,88.25 R6343.2
EMMC_CMD: length 33.9
  TOP w0.089: v1(61.47,88.11) 61.39,88.2 61.15,88.2 60.74,88.61 60.74,88.74 R6313.1 59.89,88.9 R6344.1 ; v4(84.51,84.94) 84.95,84.5 U6301.M5
  L3 w0.14: v1(83.59,91.06) 83.48,91.17 77.94,91.17 76.69,91.5 76.68,91.5 76.32,91.86 75.63,92.32 74.95,92.41 74.56,92.33 73.09,92 73.09,92 71.6,91.66 71.21,91.49 67.5,90.52 67.31,90.5 64.15,90.5 61.77,88.11 v1(61.47,88.11)
  BOTTOM w0.089: v4(84.51,84.94) 83.83,85.61 83.83,87.91 84.32,88.4 84.32,90.36 v2(84.16,90.52) 84.14,90.52 v1(83.59,91.06)
EMMC_CMD_R: length 3.3
  TOP w0.089: U6304.H10 56.44,88.82 56.47,88.79 56.97,88.79 57.18,89 57.66,89 57.83,89.18 58.62,89.18 58.78,89.02 R6344.2
EMMC_D0: length 8
  TOP w0.089: RN6302.3 80.36,92.31 80.45,92.4 80.45,93.45 80.54,93.54 81.18,93.54 81.34,93.38 81.34,92.64 82.74,91.24 82.81,91.24 83.92,90.13 83.92,89.78 U6301.A3
EMMC_D0_R: length 30
  TOP w0.076: v1(58.09,90.4) 57.84,90.15 57.18,90.15 57,89.97 56.46,89.97 56.32,89.82 U6304.F10
  TOP w0.089: RN6302.6 77.96,92.31 77.69,92.58 77.69,94.34 v2(77.86,94.51) 78.25,94.51 78.33,94.6 78.33,95.38 78.26,95.45 v1(77.6,95.45)
  L3 w0.14: v1(77.6,95.45) 76.18,95.71 75.63,95.71 72.7,95.19 71.89,95.02 71.89,95.02 69.12,94.46 67.79,94.34 66.91,94.34 62.59,94.29 60.78,94.29 60.48,93.98 58.92,93.98 58.34,93.4 58.34,90.65 v1(58.09,90.4)
EMMC_D1: length 4.9
  TOP w0.089: RN6301.1 82.4,93.03 83.76,91.67 83.82,91.67 84.41,91.08 84.41,89.79 U6301.A4
EMMC_D1_R: length 33.3
  TOP w0.076: v1(57.23,90.54) 56.83,90.15 56.36,90.15 56.29,90.07 55.95,90.07 55.7,89.82 U6304.F9
  TOP w0.089: v1(81.94,95.45) 82.02,95.45 82.4,95.07 RN6301.8
  L3 w0.14: v1(81.94,95.45) 76.71,96.22 75.25,96.16 71.79,95.46 70.41,95.18 69.07,94.9 67.63,94.82 66.79,94.83 66.78,94.85 66.75,94.85 61.25,94.73 60.6,94.73 60.58,94.72 59.14,94.69 58.21,94.69 57.87,94.35 57.87,93.91 57.73,93.77 56.97,93.77 56.83,93.63 56.83,93.35 56.97,93.21 57.73,93.21 57.87,93.07 57.87,91.19 v1(57.23,90.54)
EMMC_D2: length 4.6
  TOP w0.089: U6301.A5 84.95,91.29 84.7,91.54 84.7,92.19 83.49,93.4 RN6301.3
EMMC_D2_R: length 33.8
  TOP w0.076: U6304.G9 55.79,89.57 56.34,89.57 56.57,89.79 56.87,89.79 57.09,89.57 57.31,89.57 57.45,89.71 v1(57.53,89.71)
  TOP w0.089: v1(83.67,95.48) 83.49,95.3 RN6301.6
  L3 w0.14: v1(83.67,95.48) 82.58,94.48 81.71,94.08 80.04,93.93 78.15,94.26 77.44,94.26 75.65,94.79 71.91,94.12 70.6,93.85 70.6,93.85 67.37,92.91 67,92.87 66.41,92.87 65.94,92.86 65.74,92.83 65.69,92.83 64.69,92.84 63.47,92.84 63.42,92.79 63.02,92.79 62.74,93.07 60.04,93.07 59.79,92.82 59.27,92.3 59.27,90.84 59.76,90.36 59.76,89.94 59.49,89.67 57.58,89.67 v1(57.53,89.71)
EMMC_D3: length 5.3
  TOP w0.089: U6301.B2 83.2,89.5 83.2,89.92 83.04,90.07 82.28,90.07 81.67,90.68 81.65,90.68 81.11,91.22 RN6302.1
EMMC_D3_R: length 33
  TOP w0.076: U6304.H9 55.68,88.82 55.93,88.57 57.02,88.57 57.07,88.62 57.78,88.62 57.94,88.77 v1(58.01,88.77)
  TOP w0.089: v1(77.17,93.8) 77.06,93.8 76.98,93.73 75.16,93.73 74.98,93.55 v2(74.98,93.21) 74.98,92.79 75.13,92.64 75.98,92.64 77.4,91.22 RN6302.8
  L3 w0.14: v1(58.01,88.77) 59.23,88.77 60.21,89.75 60.21,90.59 59.72,91.09 59.72,92.11 60.23,92.62 62.54,92.62 62.85,92.31 66.73,92.41 66.75,92.42 67.03,92.43 67.46,92.48 69.44,93.05 72.49,93.77 74.99,94.22 76.44,94.09 76.81,93.98 v1(77.17,93.8)
EMMC_D4: length 6.6
  TOP w0.076: 83.69,90.08 83.69,89.51 U6301.B3
  TOP w0.089: 83.69,90.08 83.36,90.41 83.11,90.41 82.97,90.27 82.64,90.27 82.4,90.51 82.4,90.87 81.2,92.06 80.82,92.06 80.57,91.81 80.56,91.81 80.55,91.81 RN6302.2
EMMC_D4_R: length 30.1
  TOP w0.089: RN6302.7 77.52,91.81 v2(77.22,92.11) 76.44,92.89 76.44,93.01 76.67,93.23 76.91,93.23 v1(77.2,92.94) ; v1(58.85,88.04) 58.08,88.04 57.68,88.44 57.17,88.44 57.05,88.32 U6304.J10
  L3 w0.14: v1(58.85,88.04) 59.1,88.29 59.56,88.29 61.3,90.03 61.3,90.54 61.16,90.68 60.76,90.68 60.16,91.28 60.16,91.91 60.4,92.15 62.29,92.15 62.62,91.83 63.24,91.83 67.06,91.98 67.55,92.04 68.6,92.34 73.43,93.49 73.43,93.49 75.01,93.77 76.64,93.51 76.78,93.49 77.13,93.16 v1(77.2,92.94)
EMMC_D5: length 9.5
  TOP w0.089: RN6302.4 79.63,92.9 79.92,93.19 79.92,93.75 80.45,94.29 v2(80.77,94.29) 81.15,94.29 81.84,93.6 81.84,92.85 83.22,91.47 83.75,91.47 84.2,91.02 84.2,89.5 U6301.B4
EMMC_D5_R: length 27.8
  TOP w0.076: 55.8,87.94 55.8,87.72 55.94,87.57 56.25,87.57 56.31,87.63
  TOP w0.089: v1(60.12,87.91) 59.83,87.91 59.55,87.64 56.99,87.64 56.92,87.72 56.4,87.72 56.31,87.63 ; RN6302.5 78.36,93.6 v1(78.2,93.76) ; 55.8,87.94 55.55,88.19 U6304.J9
  L3 w0.14: v1(78.2,93.76) 78.28,93.68 78.28,92.84 77.84,92.4 77.04,92.4 76.57,92.87 76.26,93.12 75.02,93.32 75.01,93.32 73.52,93.05 72.95,92.92 67.79,91.65 67.64,91.6 66.73,91.38 63.05,91.38 61.82,90.16 61.82,89.89 60.12,88.19 v1(60.12,87.91)
EMMC_D6: length 5.3
  TOP w0.089: RN6301.2 82.99,93.17 84.19,91.96 84.19,91.59 84.7,91.08 84.7,89.5 U6301.B5
EMMC_D6_R: length 33.7
  TOP w0.076: v2(58.63,89.71) 58.33,89.41 57.78,89.41 57.58,89.21 57.1,89.21 56.88,88.99 56.55,88.99 56.47,89.07 55.29,89.07 U6304.G8
  TOP w0.089: v1(82.8,95.45) 82.99,95.27 RN6301.7 ; v2(58.63,89.71) 59.06,90.15 v1(59.28,90.15)
  L3 w0.14: v1(82.8,95.45) 81.7,94.68 80.92,94.5 77.25,94.95 77.25,94.96 76.65,94.96 75.68,95.24 71.83,94.56 69.19,94.02 68.57,93.97 67.82,93.83 61.9,93.83 61.21,93.81 60.94,93.81 60.65,93.52 59.1,93.52 58.83,93.25 58.83,92.5 58.83,92.5 58.83,90.66 58.83,90.65 58.83,90.6 v1(59.28,90.15)
EMMC_D7: length 5.3
  TOP w0.089: RN6301.4 v2(84.94,93.56) 85.14,92.8 85.2,92.34 85.2,89.5 U6301.B6
EMMC_D7_R: length 33.9
  TOP w0.076: v1(57.4,88.04) 57.37,88.07 55.95,88.07 55.8,88.22 55.8,88.42 55.65,88.57 55.44,88.57 55.19,88.82 U6304.H8
  TOP w0.089: RN6301.5 84.07,94.95 v1(84.53,95.4)
  L3 w0.14: v1(57.4,88.04) 58.54,87.56 58.63,87.56 59.58,87.43 60.32,87.43 60.6,87.72 60.83,88.15 61.48,88.8 62.5,89.49 63.95,90.94 66.93,90.94 71.19,92.03 74.47,92.77 75.02,92.87 75.92,92.73 76.02,92.71 76.34,92.47 76.87,91.94 77.92,91.94 78.52,92.13 81.82,93.51 83.1,94.22 v1(84.53,95.4)
EMMC_E9: length 1.3
  TOP w0.089: U6301.E9 86.95,88.04 87.17,88.27 v4(87.2,88.27)
  BOTTOM w0.089: TP6301.1 87.12,88.34 v4(87.2,88.27)
EMMC_E10: length 1.5
  TOP w0.089: U6301.E10 87.8,88.1 v4(87.8,88.27)
  BOTTOM w0.089: v4(87.8,88.27) 87.86,88.32 TP6302.1
EMMC_F10: length 1.2
  TOP w0.089: U6301.F10 87.86,87.66 87.95,87.66 v4(87.95,87.66)
  BOTTOM w0.089: v4(87.95,87.66) 87.95,87.66 TP6303.1
EMMC_K10: length 1.6
  TOP w0.089: U6301.K10 86.93,84.73 86.77,84.73 v4(86.76,84.72)
  BOTTOM w0.089: TP6304.1 87,84.48 v4(86.76,84.72)
EMMC_R_CLK: length 3
  TOP w0.089: U6301.M6 85.45,84.53 v4(85.22,84.76)
  BOTTOM w0.089: R6312.2 83.34,85.35 84.16,84.52 84.98,84.52 v4(85.22,84.76)
EMMC_RESET#: length 17.9
  TOP w0.089: v4(84.45,85.52) 84.73,85.25 U6301.K5
  L3 w0.14: v4(84.45,85.52) 85.26,86.33 91.73,86.33 91.74,86.31 92.28,86.31 92.95,86.98 92.95,87.52 v1(93.09,87.66)
  BOTTOM w0.089: v2(84.38,87.83) C6349.1 84.33,86.64 84.33,85.65 v4(84.45,85.52) ; v1(93.09,87.66) 93.55,87.2 93.55,86.92 R6309.2 94.46,86.9 R6327.1 93.91,86.19 92.6,86.19 Q6301.S
EMMC_SATA_RX_N1: length 51.8
  TOP w0.089: C6348.1 49.9,93.19 49.81,93.28 49.81,93.42 50.11,93.73 v1(50.14,93.73)
  BOTTOM w0.089: v1(50.14,93.73) 50.14,93.43 50.27,93.31 50.5,93.31 51.35,94.16 59.89,94.16 66.82,87.23 68.55,87.23 69.29,86.49 69.29,85.68 72.36,82.6 72.36,74.75 ; CPU1.BA8 72.36,61.38 72.36,62.79 71.98,63.17 71.98,63.7 72.24,63.96 72.24,65.98 73.39,67.14 73.39,71.55 72.36,72.58 72.36,74.75 ; 72.36,74.75 v2(72.52,74.75)
EMMC_SATA_RX_N1_C: length 3.2
  TOP w0.076: U6304.B2 52.05,91.97 51.95,92.07 51.38,92.07
  TOP w0.089: 51.38,92.07 50.68,92.07 50.45,91.84 49.94,91.84 49.77,92.01 49.77,92.14 49.91,92.28 C6348.2
EMMC_SATA_RX_P1: length 52.4
  TOP w0.089: v1(49.5,93.73) 49.5,93.32 C6347.1
  BOTTOM w0.089: CPU1.AY8 71.95,61.12 71.95,61.44 72.12,61.61 72.12,62.69 71.74,63.07 71.74,63.81 72,64.06 72,66.08 73.15,67.24 73.15,71.45 72.12,72.48 72.12,76.48 ; v2(71.98,76.48) 72.12,76.48 ; 72.12,76.48 72.12,82.5 72.11,82.51 72.11,82.52 69.05,85.58 69.05,86.39 68.45,86.98 66.72,86.98 59.79,93.92 51.45,93.92 50.6,93.07 50.16,93.07 v1(49.5,93.73)
EMMC_SATA_RX_P1_C: length 2.7
  TOP w0.089: C6347.2 49.53,92.13 49.53,91.91 49.84,91.6 50.55,91.6 50.78,91.83 51.54,91.83 U6304.B1
EMMC_SATA_TX_N1: length 54.7
  TOP w0.089: v1(48.03,95.23) 48.08,95.18 C6346.1
  BOTTOM w0.089: v1(48.03,95.23) 48.27,94.99 48.27,94.69 48.49,94.46 49.05,94.46 49.67,95.09 60.16,95.09 65.32,89.93 67.68,89.93 69.8,87.81 69.8,85.9 72.87,82.84 72.87,78.23 ; 72.87,78.23 72.87,72.8 73.9,71.77 73.9,66.86 72.76,65.71 72.76,63.76 72.86,63.66 72.86,61.68 CPU1.BA9 ; 72.87,78.23 v2(72.72,78.23)
EMMC_SATA_TX_N1_C: length 6.3
  TOP w0.076: 50.6,90.62 50.64,90.57 51.6,90.57 51.65,90.59 U6304.D2
  TOP w0.089: 48.34,92.91 v2(48.18,92.91) ; 48.34,92.91 48.34,93.52 C6346.2 ; 48.34,92.91 48.34,92.12 49.33,91.14 49.63,91.14 50.05,90.72 50.5,90.72 50.6,90.62
EMMC_SATA_TX_P1: length 55.5
  TOP w0.089: v1(48.74,95.23) 48.74,94.79 C6345.1
  BOTTOM w0.089: 73.11,80.75 73.11,72.9 74.14,71.87 74.14,66.76 73,65.61 73,63.86 73.1,63.76 73.1,61.5 72.8,61.19 CPU1.AY9 ; 73.11,80.75 73.11,82.94 70.04,86 70.04,87.91 67.78,90.17 65.42,90.17 60.26,95.33 49.57,95.33 48.95,94.71 48.59,94.71 48.51,94.79 48.51,94.99 v1(48.74,95.23) ; 73.11,80.75 v2(73.25,80.75)
EMMC_SATA_TX_P1_C: length 5.4
  TOP w0.076: 50.77,90.79 51.51,90.79 U6304.D1
  TOP w0.089: 49.99,91.12 49.73,91.38 49.43,91.38 48.58,92.22 48.58,93.52 C6345.2 ; 49.99,91.12 50.15,90.96 50.6,90.96 50.77,90.79 ; 49.99,91.12 v2(50.1,91.23)
EMMC_VCC: length 9.3
  TOP w0.165: 85.57,86.95 85.32,86.95 85.01,87.25 U6301.F5 ; U6301.K9 86.82,85.38 v1(86.82,85.77) 87.43,85.77 U6301.J10
  TOP w0.203: 85.57,86.95 v1(85.6,86.92)
  TOP w0.229: U6301.E6 85.45,87.64 85.67,87.42 85.67,87 v1(85.6,86.92)
  BOTTOM w0.508: R6324.1 v2(88.53,87.07) 87.33,87.07 87.02,86.77 87.02,86.66 86.82,86.45 86.82,85.9 ; 86.82,85.9 v1(86.82,85.77) ; 86.82,85.9 86.7,85.9 86.56,86.05 86.41,86.05 C6302.1 86.01,86.21 85.97,86.25 85.58,86.74 v1(85.6,86.92) 85.6,87.39 C6305.1
EMMC_VCC1N: length 7
  TOP w0.076: U6304.H7 54.8,89.07 54.8,89.92 54.95,90.07 55.15,90.07 55.3,90.22 55.3,90.42 55.45,90.57 55.65,90.57 55.8,90.72 55.8,90.92 55.95,91.07 56.29,91.07
  TOP w0.089: R6347.2 59.02,91.87 58.22,91.87 58.17,91.82 57.07,91.82 56.33,91.07 56.29,91.07
EMMC_VCC2N: length 5.9
  TOP w0.076: 57.51,87.37 57.06,86.92 55.98,86.92 55.3,87.61 55.3,87.93 55.05,88.18 U6304.J8
  TOP w0.089: 57.51,87.37 58.62,87.37 v2(58.76,87.23) 59.24,86.74 R6348.2
EMMC_VCCQ: length 16
  TOP w0.127: U6301.P3 U6301.N4 U6301.P5
  TOP w0.254: U6301.P3 83.87,83.17 83.87,82.34 84.17,82.04 84.59,82.04 85.01,82.47 v1(85.01,82.55) 84.95,82.62 U6301.P5 ; U6301.M4 U6301.N4 ; v4(85.74,88.25) 85.74,88.33 85.45,88.62 U6301.C6
  L3 w0.508: v1(85.01,82.55) 85.01,83.61 83.87,84.75 83.87,86.4 84.51,87.03 84.51,88.49 84.86,88.85 85.37,88.85 85.74,88.48 v4(85.74,88.25)
  BOTTOM w0.508: C6304.1 85.41,89.19 v2(85.45,89.15) 85.45,88.77 85.72,88.49 85.72,88.48 85.74,88.46 v4(85.74,88.25)
EMMC_VDDI: length 4.3
  TOP w0.076: U6301.C2 83.19,89.01 82.64,89.01 82.62,89.03
  TOP w0.089: C6301.1 81.28,90.27 82.52,89.03 82.62,89.03
FALL_INT2: length 3.7
  BOTTOM w0.089: Q7001.3 93.76,89.12 R7002.2 94.99,89.4 v2(94.99,89.88) 94.85,90.02 Q7001.2
FAN_PWM1_C: length 12.1
  TOP w0.102: v1(49.62,23.7) 49.62,23.6 TP2408.1
  BOTTOM w0.102: U2401.22 57.76,24.95 57.63,24.83 57.63,24.29 56.81,23.47 56.81,23.07 55.82,22.07 53.37,22.07 52.86,22.58 51.21,22.58 50.77,23.01 50.31,23.01 v1(49.62,23.7)
FAN_TACH1: length 7.8
  BOTTOM w0.203: 59.89,21.35 U2401.31
  BOTTOM w0.254: v2(64.56,20.27) 64.56,21.06 R2499.2 63.94,21.16 R2498.1 63.47,21.26 63.38,21.17 62.01,21.17 61.37,20.52 D2403.A 60.49,20.74 59.89,21.35
FAN_TACH1_C: length 2
  BOTTOM w0.254: D2403.K 63.51,20.43 R2498.2 63.66,19.82 TP2409.1
FFS_INT2: length 40.2
  TOP w0.089: v1(93.07,80.7) 93.1,80.74 93.1,81.57 93.99,82.45 R6937.1 93.05,82.47 v2(93.05,82.48) 92.08,82.48 91.72,82.83 91.72,85.4 90.35,86.77 v1(90.35,88.27)
  L3 w0.14: v1(84.25,59.18) 84.25,59.21 84.68,59.64 84.68,61.04 84.17,61.55 84.17,67.33 84.82,67.98 84.82,70.7 86.33,72.21 86.33,74.55 92.48,80.7 v1(93.07,80.7)
  BOTTOM w0.089: v1(84.25,59.18) 83.92,59.52 CPU1.AV29 ; v1(90.35,88.27) 90.35,88.51 R1758.2 91.1,89.26 R7001.1 91.12,90.02 Q7001.5
FFS_INT2_Q: length 162.1
  L4 w0.14: v1(110.82,1.25) 110.85,1.21 143.5,1.21 145.92,3.63 v1(145.92,9.12)
  BOTTOM w0.089: v1(145.92,9.12) 145.92,16.75 144.82,17.85 EC6002.1 144.93,18.15 R6001.1 ; R7001.2 91.33,90.67 Q7001.6 92.11,91.07 92.35,91.31 94.18,91.31 94.88,92.01 96.27,92.01 96.75,91.53 96.75,91.34 97.49,90.61 97.57,90.61 100.27,87.91 102.58,87.91 103.59,86.91 103.59,86.49 104.58,85.5 104.58,84.71 111,78.29 111,35.95 110.88,35.83 110.88,20.16 110.58,19.87 110.58,17.33 109.09,15.83 108.27,15.83 108.02,15.58 108.02,14.32 108.07,14.27 108.07,13.03 107.26,12.22 107.26,11.34 106.35,10.44 v2(106.35,9.06) 106.35,7.47 107.04,6.78 109.91,6.78 110.82,5.87 v1(110.82,1.25)
FFS_INT2_Q_R: length 4.8
  BOTTOM w0.089: R6001.2 v2(146.39,19.71) 147.14,19.71 147.48,20.06 HDD1.P11
GPIO0: length 5
  TOP w0.076: U6304.B9 55.55,91.93 55.8,92.17 55.8,92.63 55.85,92.69 55.85,92.74 56.72,93.6 56.82,93.6 57.07,93.85 57.07,93.91 57.89,94.72 R6359.1
  TOP w0.102: R6359.1 58.01,94.79 58.55,94.79 R6364.2
GPIO1: length 8.7
  TOP w0.076: 56.77,93.07 56.43,92.72 56.43,92.35 56.15,92.07 55.95,92.07 55.8,91.92 55.8,91.72 55.65,91.57 55.3,91.57 U6304.C8
  TOP w0.102: 56.77,93.07 56.9,93.19 58.7,93.19 59.13,93.63 59.66,93.63 v2(60.17,93.12) 60.17,94.26 59.77,94.67 R6356.2
GPIO2: length 3.7
  TOP w0.076: 55.3,93.32 55.3,92.07 U6304.B8
  TOP w0.102: 55.3,93.32 55.3,94.19 v2(55.42,94.31) 55.42,94.46 55.02,94.87 R6360.1
GPIO3: length 2.7
  TOP w0.102: R6361.2 54.2,93.8 v2(54.38,93.63) 55.05,92.96 U6304.A8
GPIO4: length 3.6
  TOP w0.076: 53.8,92.48 53.8,92.22 53.95,92.07 54.15,92.07 54.3,91.92 54.3,91.57 U6304.C7
  TOP w0.102: 53.8,92.48 53.37,92.92 53.37,93.03 53.09,93.31 53.09,93.65 R6355.1
GPIO5: length 2.8
  TOP w0.076: U6304.B7 54.55,91.97 54.3,92.22 54.3,92.48 54.1,92.68
  TOP w0.102: 54.1,92.68 54.07,92.71 53.96,92.71 53.72,92.95 53.72,93.06 53.54,93.24 53.54,93.96 R6357.1
GPIO67: length 4.9
  TOP w0.102: v1(55.59,33.66) 55.6,33.65 55.74,33.65 56.07,33.32 56.07,32.22 RN2407.2 55.49,31.12 55.9,30.71 v2(55.9,30.71)
  BOTTOM w0.102: v1(55.59,33.66) 55.22,34.02 55.22,34.03 55.15,34.1 U2401.123
GROUPB_PWRGD: length 74
  TOP w0.102: PR4617.1 25.12,45.62 v2(25.32,45.42) 25.42,45.42 25.7,45.7 v1(26.13,45.7) ; v1(54.42,13.96) 54.42,17.77 53.65,18.54 53.24,18.54 52.91,18.87 51.76,18.87 50.2,20.44 50.2,22.03 50.06,22.16 50.06,22.53 50.32,22.79 50.67,22.79 50.75,22.71 51.92,22.71 52.05,22.84 53.11,22.84 v1(53.59,23.32)
  L3 w0.102: v1(54.42,13.96) 54.42,13.44 54.15,13.17 54.07,13.17 53.9,13 53.16,13 53.12,12.96 51.53,12.96 51.5,12.93 50.99,12.93 50.87,13.05 48.66,13.05 48.13,13.58 46.62,13.58 45.87,14.33 45.46,14.33 45.18,14.33 v1(45.07,14.44) ; v1(26.13,45.7) 26.14,45.69 26.19,45.69 26.72,45.16 26.72,42.47 28.55,40.64 29.34,40.64 29.36,40.67 29.54,40.67 31.95,38.25 31.97,38.25 32.46,37.76 32.46,36.78 32.71,36.53 35.36,36.53 35.79,36.96 37.44,36.96 37.93,36.46 43.35,36.46 43.79,36.02 45.92,36.02 46.84,35.1 50.57,35.1 52.12,33.55 52.12,33.47 v1(52.14,33.45)
  BOTTOM w0.102: R4005.2 44.6,14 45.04,14.44 v1(45.07,14.44) ; v1(52.14,33.45) 52.02,33.32 52.02,32.62 51.46,32.06 51.46,29.14 52.04,28.56 52.04,24.85 52.36,24.53 52.99,24.53 53.59,23.92 v1(53.59,23.32)
GROUPB_PWRGD_R: length 10.8
  BOTTOM w0.102: R4005.1 R4006.2 42.77,14.78 C4012.1 43,15.11 43.02,15.11 43.28,15.37 43.28,15.63 43.62,15.97 43.63,15.97 44.09,16.43 46.52,16.43 47.79,15.15 47.79,13.99 48.63,13.16 D4003.A
GSEN2_INT1: length 48.3
  TOP w0.152: v1(97.19,81.21) 97.19,81.37 R6933.2
  L3 w0.152: v1(97.19,81.21) 97.19,82.23 99.67,84.71 100.06,84.71 100.33,84.98 100.33,85.39 101.67,86.73 101.99,86.73 104.36,89.1 105.4,89.1 107.35,91.04 115.53,91.04 117.72,88.85 119.81,88.85 v1(120.27,89.31)
  BOTTOM w0.152: v1(120.27,89.31) 121.81,90.85 127.59,90.85 127.84,90.6 134.44,90.6 v2(134.99,90.05) 135.99,89.05 IOBD1.18
GSEN2_INT1_R: length 2.5
  TOP w0.152: R6933.1 96.78,82.7 96.82,82.7 v2(96.85,82.72) 96.82,82.75 U6901.12
GSEN2_INT2: length 50.9
  TOP w0.152: v1(95.99,80.95) 95.42,80.95 R6934.2 94.76,81.61 R6937.2
  L3 w0.152: v1(95.99,80.95) 95.99,81.1 96.7,81.82 96.7,82.13 99.36,84.8 99.36,85.35 99.64,85.63 100.1,85.63 101.49,87.01 101.87,87.01 104.24,89.38 105.28,89.38 107.22,91.32 115.77,91.32 117.85,89.24 119.51,89.24 v1(119.58,89.31)
  BOTTOM w0.152: v1(119.58,89.31) 121.41,91.13 127.72,91.13 127.86,90.99 127.89,90.99 127.99,90.88 133.5,90.88 133.61,90.99 v2(134.21,90.99) 134.71,90.99 136.15,89.55 IOBD1.17
GSEN2_INT2_R: length 2.4
  TOP w0.152: R6934.1 94.76,82.46 95.21,82.46 v2(95.64,82.89) 96.32,83.57 U6901.11
GSENSOR_CS: length 2.2
  TOP w0.152: U6901.2 98.19,84.46 R6905.2 98.37,83.66 v2(98.73,83.31)
GSENSOR_SDO: length 3.2
  TOP w0.152: U6901.3 98.17,84.96 R6903.2 R6902.2 v2(99.25,86.86)
H_A20GATE: length 157.4
  TOP w0.102: v1(100.69,82.4) 100.76,82.32 v2(100.76,81.85)
  L3 w0.102: v1(86.59,58.42) 86.18,58.83 86.18,59.5 86.22,59.53 86.22,64.73 86.08,64.87 86.08,71.2 87.15,72.26 87.15,72.62 87.33,72.8 87.33,73.74 v1(87.53,73.94) 87.53,74.35 91.77,78.59 98.15,78.59 100.69,81.13 v1(100.69,82.4)
  L4 w0.102: v1(54.27,33.73) 54.27,33.73 54.27,33.88 55.39,35 58.06,35 58.21,35.16 58.21,35.16 58.85,35.79 62.43,35.79 63.37,34.85 66.22,34.85 66.52,35.16 71.25,35.16 71.53,34.88 75.39,34.88 77.19,33.07 79.68,33.07 80.21,32.54 80.21,32.54 80.47,32.29 82.63,32.29 88.54,26.37 94.44,26.37 96.62,24.18 107.09,24.18 v1(107.34,23.93)
  BOTTOM w0.102: v1(54.27,33.73) 54.27,33.97 54.35,34.05 U2401.121 ; R1713.2 87.68,74.09 v1(87.53,73.94) ; v1(100.69,82.4) 107.34,75.74 v1(107.34,23.93) ; v1(86.59,58.42) 86.89,58.72 CPU1.AU35
H_PROCHOT#: length 227.6
  TOP w0.089: v1(84.86,33.78) 84.78,33.7 84.22,33.7 84.15,33.63 82.46,33.63 81.97,33.14 81.97,31.22 78.77,28.02 78.77,27.05 79.03,26.8 79.53,26.8 80.04,26.29 80.04,22.14 v2(79.24,21.34) 79.24,20.99 79.33,20.9 79.34,20.9 v1(79.76,20.48) ; v1(65.18,32.03) 65.23,31.98 65.23,29.44 67.75,26.91 67.75,23.66 67.85,23.56 67.85,23.44 67.89,23.4 67.89,22.73 67.85,22.69 67.85,21.14 68.1,20.89 68.48,20.89 68.93,21.33 v1(68.93,21.44) ; PG4604.1 23.42,51.77 v1(23.34,51.84)
  L3 w0.14: v1(68.93,21.44) 69.47,21.98 75.58,21.98 75.71,21.85 75.71,21.82 75.97,21.56 76.23,21.56 76.23,21.56 76.79,21.56 76.8,21.56 77.76,21.56 77.95,21.37 79.14,21.37 79.76,20.75 v1(79.76,20.48) ; v1(65.18,32.03) 64.62,32.58 62.32,32.58 61.73,32 59.92,32 59.83,31.91 51.96,31.91 51.85,32.03 50.98,32.03 50.55,32.46 47.24,32.46 46.79,32.92 45.97,32.92 44.91,33.98 43.3,33.98 42.65,33.33 40.84,33.33 40.47,33.7 37.51,33.7 37.33,33.52 34.19,33.52 33.35,34.37 31.85,34.37 31.39,34.83 27.78,34.83 22.15,40.45 22.15,46.84 21.95,47.04 21.95,49.11 22.05,49.2 22.05,50.22 22.2,50.37 22.2,50.92 23.13,51.84 v1(23.34,51.84)
  L4 w0.14: v1(138.25,35.89) 138.58,36.22 140.24,36.22 141.48,34.97 141.48,34.92 142.06,34.35 142.06,32.53 141.92,32.39 141.92,30.22 142.89,29.24 142.89,12.57 137.97,7.65 117.42,7.65 116.86,8.21 116.86,14.88 114.62,17.12 111.79,17.12 110.67,18.24 110.67,18.8 110.91,19.05 110.91,20.53 110.64,20.79 107.88,20.79 106.62,19.53 106.62,18.66 106.13,18.16 105.45,18.16 105.04,17.76 103.3,17.76 100.94,15.39 91.19,15.39 88.96,17.62 87.8,17.62 87.12,18.3 86.4,18.3 83.93,20.77 80.05,20.77 v1(79.76,20.48)
  BOTTOM w0.089: RN804.8 85.57,33.25 85.06,33.76 84.89,33.76 v1(84.86,33.78) 84.99,33.78 85.67,34.46 85.67,36.2 85.24,36.63 85.24,38.68 CPU1.A31 ; v1(68.93,21.44) 68.92,21.44 68.91,21.43 68.78,21.43 68.34,21.87 67.59,21.87 67.49,21.97 67.49,21.98 67.4,22.07 Q2402.D ; PU4401.5 v1(138.25,35.89) ; PR4450.2 23.27,51.77 v1(23.34,51.84) 23.67,51.84 23.8,51.97 PR4447.2 24.1,51.89 PR4415.1
HALL_KB_DIS#: length 173.1
  L3 w0.102: v1(118.81,17.56) 118.41,17.17 117.19,17.17 112.83,21.54 107.9,21.54 107.26,22.18 100.37,22.18 99.53,21.34 99.09,21.34 98.96,21.46 94.01,21.46 92.71,22.76 87.08,22.76 81.75,28.09 81.75,28.39 79.68,30.46 77.01,30.46 73.65,33.82 64.98,33.82 64.34,33.17 60.4,33.17 60.22,33 55.14,33 54.81,33.32 54.81,33.8 54.44,34.17 51.84,34.17 50.32,35.69 48.31,35.69 47.88,36.12 v1(47.88,36.35)
  BOTTOM w0.102: IOBD1.21 136.14,87.55 v2(136.11,87.58) 133.58,87.58 133.32,87.83 133.32,88.39 132.74,88.98 127.2,88.98 126.9,89.28 123.75,89.28 123.55,89.08 122,89.08 118.49,85.57 118.49,17.88 v1(118.81,17.56) ; R2434.2 47.95,36.76 47.95,36.42 v1(47.88,36.35) 47.95,36.28 U2401.105
HDA_BITCLK_CODEC: length 123.4
  TOP w0.089: v1(76.63,99.65) 76.67,99.65 77.42,100.4 88.96,100.4 89.6,99.75 92.06,99.75 92.94,100.64 152.85,100.64 156.26,97.23 v2(156.26,96.7) 156.26,94.7 155.06,93.5 154.23,93.5 152.6,91.87 151.5,91.87 151.1,91.48 R2753.1
  L4 w0.14: v1(63.91,75.72) 64.14,76.15 64.16,76.18 64.16,80.24 64.19,80.27 64.19,81.89 65.23,82.94 65.23,85.31 65.24,85.32 65.24,87.19 65.25,87.2 65.25,87.42 65.28,87.44 65.28,88.77 65.8,89.29 71.61,95.1 72.24,95.1 76.63,99.49 v1(76.63,99.65)
  BOTTOM w0.089: v1(63.91,75.72) 63.91,75.66 64.94,74.62 RN1707.3
HDA_BITCLK_CODEC_R: length 2.7
  TOP w0.089: HDA27.5 149.05,90.18 149.2,90.03 149.66,90.03 EC2710.1 150.24,90.6 R2753.2
HDA_CODEC_BITCLK_R: length 15.9
  BOTTOM w0.089: CPU1.AY6 70.92,60.8 70.92,61.06 70.85,61.13 70.85,61.43 70.9,61.47 70.9,62.1 70.43,62.56 70.43,63.46 70.1,63.8 70.1,64.4 R1723.2 69.44,65.1 69.04,65.51 68.07,65.51 67.49,66.09 66.94,66.09 66.22,66.8 66.11,66.8 65.51,67.41 65.51,67.49 64.74,68.25 64.74,69.81 64.64,69.92 v2(64.64,69.94) 64.64,69.97 64.74,70.08 64.74,71.61 64.94,71.81 RN1707.6
HDA_CODEC_SDIN0_R: length 15.3
  BOTTOM w0.089: CPU1.BA6 71.15,62.14 70.64,62.65 70.64,63.52 70.29,63.88 70.29,65.03 R1724.2 69.75,65.71 68.15,65.71 67.56,66.3 67.17,66.3 65.91,67.56 65.91,67.64 65.56,68 65.28,68.28 65.18,68.39 65.18,71.48 65.53,71.84 RN1707.5
HDA_CODEC_SDIN1_R: length 6
  BOTTOM w0.089: CPU1.AY5 70.6,61.14 70,61.74 70,62.34 68.93,63.4 68.1,63.4 67.34,64.16 67.34,64.57 RN1710.4
HDA_CODEC_SDIN2_R: length 6.2
  BOTTOM w0.089: CPU1.BA5 70.6,62 69,63.6 68.17,63.6 67.61,64.16 67.61,65.47 67.44,65.64 67.16,65.64 RN1710.3
HDA_CODEC_SDOUT_R: length 15.4
  BOTTOM w0.089: CPU1.BA4 69.81,61.51 69.81,62.26 68.87,63.2 67,63.2 65.61,64.59 65.61,66.55 65.1,67.06 65.1,67.34 64.25,68.19 v2(64.25,68.58) 64.25,69.53 RN1709.3 64.34,70.51 64.34,71.81 64.44,71.91 RN1707.7
HDA_CODEC_SYNC_R: length 15.5
  BOTTOM w0.089: RN1707.8 63.56,72.68 v2(62.46,71.58) 62.46,70.69 63.17,69.98 RN1709.4 63.15,69.69 63.29,69.56 63.29,69.54 63.31,69.52 63.33,69.52 63.86,68.99 63.86,68.01 65.41,66.46 65.41,64.52 66.93,62.99 68.09,62.99 68.91,62.17 68.91,62.02 69.31,61.62 CPU1.BA3
HDA_SDIN0_CPU: length 123.7
  TOP w0.089: HDA27.7 149.08,90.97 149.17,90.89 149.53,90.89 149.78,91.14 149.78,91.48 149.95,91.64 150.7,91.64 151.33,92.28 152.45,92.28 154.23,94.06 155.06,94.06 155.87,94.87 v2(155.87,95.3) 155.87,97.07 152.69,100.24 94.91,100.24 94.02,99.36 89.44,99.36 88.8,100 78.22,100 v1(78.17,99.95)
  L4 w0.14: v1(64.92,75.29) 65.18,75.55 65.18,81.63 66.12,82.57 66.12,82.58 66.12,84.95 66.13,84.95 66.13,86.82 66.17,86.86 66.17,88.4 71.95,94.18 72.59,94.18 78.17,99.77 v1(78.17,99.95)
  BOTTOM w0.089: v1(64.92,75.29) 65.53,74.68 RN1707.4
HDA_SDOUT_CODEC: length 130.5
  TOP w0.089: v1(75.92,100.61) 76.43,100.61 76.61,100.79 89.14,100.79 89.65,100.27 90.34,100.27 91.11,101.04 153,101.04 156.65,97.39 156.65,94.53 154.83,92.71 154.83,91.75 153.67,90.58 152.13,90.58 EC2709.1 151.56,90.01 151.56,89.69 151.18,89.31 149.89,89.31 v2(149.65,89.55) 149.43,89.78 HDA27.4
  L4 w0.14: v1(63.22,75.69) 63.22,75.95 63.7,76.43 63.7,80.41 63.75,80.46 63.75,82.09 64.79,83.13 64.79,85.5 64.8,85.5 64.8,87.37 64.81,87.38 64.81,87.6 64.83,87.63 64.83,88.96 65.61,89.74 71.43,95.56 71.9,95.56 76.2,99.85 76.2,100.33 v1(75.92,100.61)
  BOTTOM w0.089: RN1707.2 64.44,74.1 64.52,74.17 64.52,74.49 63.31,75.69 v1(63.22,75.69)
HDA_SPKR_R: length 3.6
  BOTTOM w0.254: R2741.2 148.28,94.57 148.63,94.57 148.7,94.51 v2(149.3,94.51) 149.55,94.51 150.57,95.53 151.31,95.53 D2703.1
HDA_SYNC_CODEC: length 121.9
  TOP w0.089: HDA27.9 149.48,91.78 149.76,92.05 150.55,92.05 151.18,92.69 152.26,92.69 155.47,95.9 155.47,96.9 152.53,99.85 v2(126.6,99.85) 95.1,99.85 94.21,98.97 89.27,98.97 88.67,99.58 78.42,99.58 78.37,99.53 77.69,99.53 v1(77.47,99.75)
  L4 w0.14: v1(64.03,74.37) 64.03,75.04 64.64,75.64 64.64,81.71 65.68,82.75 65.68,85.13 65.68,85.14 65.68,87 65.72,87.04 65.72,88.59 65.98,88.85 71.78,94.64 72.41,94.64 77.47,99.7 v1(77.47,99.75)
  BOTTOM w0.089: RN1707.1 63.86,74.2 v1(64.03,74.37)
HDD_DEVSLP: length 148.3
  TOP w0.102: v1(131.62,71.43) 132.05,71.43 132.45,71.04 v2(132.45,70.94) 132.45,69.35 134.06,67.74 138.23,67.74 v1(138.43,67.95)
  L3 w0.102: v1(138.43,67.95) 138.86,67.95 140.21,66.6 140.21,64.72 141.12,63.81 141.12,62.52 145.69,57.94 145.69,52.94 144.32,51.57 144.32,47.63 142.57,45.87 142.57,43.18 141.96,42.57 141.96,37.92 141.48,37.44 141.48,37.03 141.71,36.81 141.93,36.81 144.83,33.91 144.83,29.9 144.53,29.59 v1(144.09,29.59) ; v1(131.62,71.43) 130.28,72.77 130.28,77.07 130.5,77.29 130.5,85.65 126.64,89.51 121.07,89.51 119.01,91.58 106.66,91.58 104.98,89.9 97.72,89.9 95.05,87.22 95.05,86.68 93.88,85.52 93.88,82.45 86.09,74.65 86.09,74.17 84.71,72.8 84.71,71.2 84.33,70.82 84.33,67.84 83.92,67.44 83.92,60.28 v1(84.25,59.95)
  BOTTOM w0.102: HDD1.P3 148.15,30.22 147.19,29.26 144.76,29.26 144.43,29.59 v1(144.09,29.59) ; CPU1.AV31 84.65,59.52 84.29,59.88 84.29,59.91 v1(84.25,59.95)
HDD_DEW1: length 4.4
  BOTTOM w0.102: R6011.2 v2(142.39,54.28) 142.72,53.95 R6010.1 143.31,53.63 143.5,53.43 U6001.16
HDD_DEW2: length 3.8
  BOTTOM w0.102: U6001.6 148.82,55.69 148.82,57.08 148.9,57.15 v2(149.12,57.15) 149.51,57.15 149.64,57.02 R6013.2 R6012.1
HDD_SATA_RX_CON_N0: length 14.3
  TOP w0.089: R6018.1 146.91,43.51 v1(147.02,43.61)
  L4 w0.114: HDD1.S5 150.12,41.12 150.55,41.12 150.79,40.88 150.79,38.52 150.36,38.09 149.19,38.09 148.6,38.67 148.6,43.41 148.4,43.61 v1(147.02,43.61)
  BOTTOM w0.089: v1(147.02,43.61) 146.91,43.51 C6003.2
HDD_SATA_RX_CON_P0: length 14
  TOP w0.089: R6019.1 146.89,44.4 v1(147.02,44.27)
  L4 w0.114: v1(147.02,44.27) 147.46,43.83 148.49,43.83 148.82,43.5 148.82,38.76 149.28,38.3 150.27,38.3 150.57,38.61 150.57,40.79 150.46,40.91 149.77,40.91 149.6,40.74 HDD1.S6
  BOTTOM w0.089: C6004.2 146.6,44.18 146.92,44.18 v1(147.02,44.27)
HDD_SATA_RX_N0: length 114.6
  TOP w0.089: v1(139.29,61.95) 139.32,61.98 C6022.1
  L4 w0.114: v1(139.29,61.95) 139.01,62.23 137.74,62.23 137.06,62.92 137.06,64.67 132.97,68.76 130.61,68.76 129.49,69.88 129.49,83.63 129.3,83.82 129.3,87 127.27,89.03 125.44,89.03 124.99,88.58 118.68,88.58 118.24,89.03 113.45,89.03 112.83,89.65 109.59,89.65 109.31,89.37 109.31,88.59 108.74,88.01 105.89,88.01 105.5,87.62 99.28,87.62 97.64,89.25 96.91,89.25 96.63,89.54 90.86,89.54 87.59,86.27 84.5,86.27 83.5,85.27 83.5,84.01 82.67,83.17 81.97,83.17 80.87,82.07 80.37,82.07 78.09,79.8 76.75,79.8 76.43,79.48 76.43,76.11 75.26,74.94 75.26,73.63 76.3,72.59 76.3,66.96 75.34,65.99 75.34,65.76 v1(74.88,65.31)
  BOTTOM w0.089: CPU1.AY12 74.45,60.82 74.75,61.12 74.75,61.4 74.7,61.44 74.7,63.15 74.96,63.41 74.96,64.66 ; v1(74.88,65.31) 74.96,65.22 74.96,64.66 ; v1(139.29,61.95) 139.32,61.98 C6022.1 ; v2(75.15,64.67) 74.96,64.66
HDD_SATA_RX_P0: length 114.3
  TOP w0.089: v1(139.29,62.77) 139.32,62.79 C6021.1
  L4 w0.114: v1(74.88,65.94) 74.98,65.94 76.09,67.05 76.09,72.5 75.04,73.54 75.04,75.03 76.21,76.2 76.21,79.57 76.66,80.01 78,80.01 80.28,82.29 80.78,82.29 81.88,83.39 82.58,83.39 83.29,84.1 83.29,85.36 84.41,86.48 87.5,86.48 90.77,89.75 96.72,89.75 97,89.47 97.73,89.47 99.36,87.83 105.41,87.83 105.8,88.23 108.65,88.23 109.09,88.67 109.09,89.46 109.5,89.87 112.92,89.87 113.54,89.24 118.33,89.24 118.77,88.8 124.9,88.8 125.35,89.24 127.36,89.24 129.51,87.09 129.51,83.91 129.71,83.72 129.71,69.97 130.7,68.98 133.06,68.98 137.27,64.76 137.27,63.01 137.83,62.45 138.98,62.45 v1(139.29,62.77)
  BOTTOM w0.089: v1(74.88,65.94) 74.47,65.53 74.47,65.13 74.7,64.9 74.72,64.9 74.72,63.51 74.46,63.25 74.46,61.74 74.28,61.56 74.28,61.44 CPU1.BA12 ; v1(139.29,62.77) 139.32,62.79 C6021.1
HDD_SATA_RX_RE_N0: length 11.1
  BOTTOM w0.089: U6001.12 147.72,50.66 145.95,48.89 ; C6003.1 145.25,43.73 144.92,43.73 144.53,44.12 144.53,44.81 145.76,46.04 ED6001.7 ED6001.4 145.76,48.7 145.95,48.89 ; 145.95,48.89 v2(145.86,48.99)
HDD_SATA_RX_RE_N1: length 25.3
  TOP w0.089: 145.06,61.24 146.18,60.12 146.18,50.98 145.36,50.17 145.36,49.37 145.76,48.97 ED6002.7 ED6002.4 145.76,45.95 145.35,45.54 144.98,45.54 144.42,44.99 144.42,44.36 144.91,43.88 145.12,43.88 R6018.2 ; 145.06,61.24 v2(144.96,61.14) ; 145.06,61.24 143.76,62.54 141.88,62.54 141.53,62.18 140.94,62.18 C6022.2
HDD_SATA_RX_RE_P0: length 11.3
  BOTTOM w0.089: C6004.1 145.47,44.12 145.31,43.97 145.02,43.97 144.77,44.22 144.77,44.71 145.52,45.46 ; v2(145.62,45.37) 145.52,45.46 ; 145.52,45.46 146.24,46.18 ED6001.6 ED6001.5 146.24,47.82 146,48.06 146,48.6 147.96,50.56 147.96,51.9 148.22,52.16 U6001.11
HDD_SATA_RX_RE_P1: length 25.6
  TOP w0.089: v2(142.77,62.92) 142.77,62.78 ; 142.77,62.78 141.78,62.78 141.43,62.42 140.88,62.42 140.74,62.56 C6021.2 ; 142.77,62.78 143.86,62.78 146.42,60.22 146.42,50.88 145.61,50.07 145.61,49.47 146,49.07 146,48.03 146.24,47.79 ED6002.6 ED6002.5 146.24,46.09 145.45,45.3 145.08,45.3 144.67,44.89 144.67,44.46 145.01,44.12 145.21,44.12 R6019.2
HDD_SATA_TX_CON_N0: length 17.5
  TOP w0.089: v1(147.04,42.17) 146.87,42 146.55,42 R6017.1
  L3 w0.114: HDD1.S3 149.6,44.57 149.78,44.75 150.69,44.75 150.96,44.48 150.96,38.18 150.68,37.9 149.15,37.9 148.42,38.62 148.42,41.39 147.89,41.92 147.28,41.92 v1(147.04,42.17)
  BOTTOM w0.089: C6002.2 146.35,42.17 146.59,41.94 146.81,41.94 v1(147.04,42.17)
HDD_SATA_TX_CON_P0: length 17.5
  TOP w0.089: R6016.1 146.91,41.45 v1(146.99,41.53)
  L3 w0.114: v1(146.99,41.53) 147.17,41.71 147.8,41.71 148.21,41.3 148.21,38.53 149.06,37.68 150.77,37.68 151.18,38.09 151.18,44.57 150.78,44.97 150.09,44.97 HDD1.S2
  BOTTOM w0.089: C6001.2 146.91,41.45 v1(146.99,41.53)
HDD_SATA_TX_N0: length 121.8
  TOP w0.089: v1(140.51,58.75) 140.67,58.6 140.92,58.6 C6019.1
  L4 w0.114: v1(73.62,65.37) 73.62,65.65 74.52,66.54 74.52,66.76 75.01,67.25 75.01,72.69 74.42,73.28 74.42,75.29 75.59,76.46 75.59,79.83 76.44,80.68 77.79,80.68 80.04,82.93 80.54,82.93 82.19,84.58 82.19,86.14 84.73,88.69 88.79,88.69 90.48,90.37 97,90.37 97.28,90.09 97.99,90.09 99.63,88.46 105.14,88.46 105.56,88.88 107.47,88.88 109.09,90.49 117.68,90.49 118.01,90.15 121.27,90.15 121.6,90.48 127.01,90.48 130.14,87.35 130.14,84.27 130.34,84.06 130.34,70.78 131.25,69.86 133.79,69.86 140.68,62.98 140.68,60.21 141.31,59.58 141.31,58.56 141.13,58.38 140.89,58.38 v1(140.51,58.75)
  BOTTOM w0.089: C6010.1 140.92,58.6 140.67,58.6 v1(140.51,58.75) ; v1(73.62,65.37) 73.62,65.19 73.85,64.96 74.04,64.96 74.27,64.73 74.27,63.9 73.58,63.22 73.58,61.47 73.65,61.41 73.65,61.1 73.35,60.8 CPU1.AY10
HDD_SATA_TX_P0: length 122
  TOP w0.089: C6020.1 141,58.09 v1(140.51,58.09)
  L4 w0.114: v1(140.51,58.09) 140.54,58.09 140.61,58.16 141.22,58.16 141.53,58.47 141.53,59.67 140.89,60.3 140.89,63.07 133.88,70.08 131.34,70.08 130.56,70.87 130.56,84.15 130.35,84.36 130.35,87.44 127.1,90.7 121.51,90.7 121.18,90.37 118.1,90.37 117.77,90.71 109,90.71 107.39,89.09 105.47,89.09 105.05,88.67 99.72,88.67 98.08,90.31 97.37,90.31 97.09,90.59 90.39,90.59 88.7,88.9 84.64,88.9 81.97,86.23 81.97,84.67 80.45,83.15 79.95,83.15 77.7,80.89 76.35,80.89 75.37,79.91 75.37,76.54 74.21,75.38 74.21,73.19 74.8,72.6 74.8,67.34 74.3,66.85 74.3,66.63 73.21,65.54 73.21,65.02 v1(73.51,64.72)
  BOTTOM w0.089: CPU1.BA10 73.35,61.39 73.34,61.4 73.34,63.32 74.03,64 74.03,64.63 73.94,64.72 v1(73.51,64.72) ; v1(140.51,58.09) 141,58.09 C6009.1
HDD_SATA_TX_RE_N0: length 14.2
  BOTTOM w0.089: U6001.14 146.72,52.21 146.46,51.95 146.46,50.4 145.61,49.54 144.57,49.54 144.4,49.38 144.4,48.11 144.72,47.79 ED6001.2 ED6001.9 144.72,46.08 143.92,45.28 143.92,43.72 ; C6002.1 145.44,41.98 145.35,41.89 144.69,41.89 143.92,42.66 143.92,43.72 ; 143.92,43.72 v2(144.07,43.72)
HDD_SATA_TX_RE_N1: length 22.8
  TOP w0.089: R6017.2 145.02,41.77 144.52,41.77 143.81,42.48 143.81,45.23 144.72,46.14 ED6002.2 ED6002.9 144.72,47.84 144.4,48.16 144.4,50.05 145.57,51.23 145.57,58.03 145.18,58.43 144.3,58.43 ; 144.3,58.43 v2(144.3,58.57) ; 144.3,58.43 142.23,58.43 142.01,58.65 C6019.2
HDD_SATA_TX_RE_P0: length 14.1
  BOTTOM w0.089: U6001.15 146.22,50.95 ; 146.22,50.95 v2(146.08,50.95) ; 146.22,50.95 146.22,50.5 145.51,49.79 144.47,49.79 144.16,49.48 144.16,48.01 144.24,47.93 ED6001.1 ED6001.10 144.24,45.94 143.68,45.38 143.68,42.56 144.59,41.65 145.25,41.65 C6001.1
HDD_SATA_TX_RE_P1: length 22.4
  TOP w0.089: R6016.2 145.39,41.53 144.42,41.53 143.57,42.38 143.57,45.33 144.24,46 ED6002.1 ED6002.10 144.24,47.98 144.16,48.06 144.16,50.15 145.33,51.33 145.33,54.74 ; 145.33,54.74 v2(145.13,54.73) ; 145.33,54.74 145.33,57.93 145.08,58.19 142.21,58.19 C6020.2
HDMI_CLK_CON: length 15.3
  TOP w0.089: v1(13.08,77.17) 13.46,77.55 13.46,78.06 13.71,78.31 RN5701.2
  L3 w0.102: HDMI1.15 8.86,79.5 9.25,79.9 9.25,80.09 9.4,80.24 9.42,80.31 9.42,80.66 9.34,80.8 9.34,81.19 9.35,81.21 9.43,81.32 9.8,81.69
  L3 w0.14: v1(13.08,77.17) 12.88,77.17 12.29,77.75 12.29,79.58 10.21,81.67 9.8,81.69
  BOTTOM w0.089: Q5703.D 13.11,74.27 v2(12.79,74.6) 12.6,74.6 11.94,75.26 11.94,76.4 12.6,77.07 12.98,77.07 v1(13.08,77.17)
HDMI_DATA_CON: length 11.8
  TOP w0.089: v1(12.83,76.53) 12.63,76.73 12.63,76.85 12.64,76.86 12.64,78.03 v2(12.86,78.25) 13.58,78.98 RN5701.1
  L3 w0.14: v1(12.83,76.53) 11.85,77.51 11.85,78.21 10.06,80 HDMI1.16
  BOTTOM w0.089: v1(12.83,76.53) 12.45,76.15 12.45,75.64 13.08,75.01 14.58,75.01 14.81,74.78 Q5705.D
HDMI_DDI_TX_CON_N0: length 15.3
  TOP w0.089: RN5703.2 15.15,83.01 15.43,82.73 16.21,82.73 v1(16.29,82.81) 16.36,82.88 16.92,82.88 ER5714.1 17.37,83.31 C5703.2
  L4 w0.076: 9.47,76.5 10.54,76.5
  L4 w0.127: HDMI1.9 9.47,76.5 ; 10.54,76.5 10.68,76.36 10.94,76.36 11.38,76.8 11.38,77.57 12.04,78.23 12.04,79.76 15.09,82.81 15.88,82.81 v1(16.29,82.81)
HDMI_DDI_TX_CON_N1: length 15
  TOP w0.089: v2(16.09,81.52) 16.07,81.31 ; 16.07,81.31 15.39,81.31 15.19,81.51 RN5702.4 ; 16.07,81.31 16.48,81.31 v1(16.69,81.51) 16.74,81.51 16.76,81.54 17.26,81.54 ER5715.1 17.4,81.68 C5705.2
  L4 w0.127: v1(16.69,81.51) 16.59,81.41 15.02,81.41 12.85,79.24 12.85,77.9 12.14,77.19 12.14,76.12 10.65,74.63 10.35,74.63 HDMI1.6
HDMI_DDI_TX_CON_N2: length 17
  TOP w0.089: RN5702.2 15.26,80.42 15.9,79.78 16.41,79.78 v1(16.56,79.94) 17.32,79.94 ER5716.1 17.36,79.9 C5707.2
  L4 w0.127: HDMI1.3 9.32,72.83 9.43,72.67 9.72,72.28 10.24,72.21 10.33,72.21 13.93,75.81 13.93,78.62 15.07,79.76 16.38,79.76 v1(16.56,79.94)
HDMI_DDI_TX_CON_N3: length 13.9
  TOP w0.089: RN5703.4 14.88,84.05 15.6,84.05 v1(15.61,84.04) 15.72,83.92 16.46,83.92 16.71,84.18 16.71,84.63 16.94,84.86 17.27,84.86 17.38,84.97 ER5717.1 17.54,84.96 C5701.2
  L4 w0.127: HDMI1.12 10.32,78 10.76,78.44 10.76,80.83 12.43,82.5 12.83,82.91 13.23,82.91 14.12,83.8 15.37,83.8 15.37,83.8 v1(15.61,84.04)
HDMI_DDI_TX_CON_P0: length 16.1
  TOP w0.089: RN5703.1 15.21,82.42 15.29,82.5 15.98,82.5 16.1,82.37 16.13,82.37 v1(16.34,82.17) 16.34,82.25 16.76,82.68 17.13,82.68 ER5714.2 17.36,82.54 17.58,82.75 17.9,82.75 C5704.2
  L4 w0.076: 10.45,75.55 10.4,75.5 9.5,75.5
  L4 w0.127: HDMI1.7 9.5,75.5 ; 10.45,75.55 11.61,76.71 11.61,77.48 12.27,78.14 12.27,79.66 15.18,82.58 15.85,82.58 16.26,82.17 v1(16.34,82.17)
HDMI_DDI_TX_CON_P1: length 14.9
  TOP w0.089: C5706.2 18.23,80.77 ER5715.2 17.27,80.85 v1(16.71,80.85) 16.46,81.1 15.39,81.1 15.21,80.92 RN5702.3
  L4 w0.127: HDMI1.4 10.38,74.4 10.74,74.4 12.37,76.02 12.37,77.09 13.08,77.8 13.08,79.15 15.11,81.18 16.38,81.18 v1(16.71,80.85)
HDMI_DDI_TX_CON_P2: length 16.7
  TOP w0.089: RN5702.1 15.56,79.83 15.81,79.58 16.26,79.58 v1(16.56,79.28) 17.12,79.28 ER5716.2 17.39,79.01 C5708.2
  L4 w0.127: v1(16.56,79.28) 16.31,79.53 15.16,79.53 14.16,78.53 14.16,75.72 10.43,71.99 9.29,71.99 9.04,72.24 HDMI1.1
HDMI_DDI_TX_CON_P3: length 14.6
  TOP w0.089: RN5703.3 14.94,83.61 15.4,83.61 v1(15.62,83.39) 15.95,83.72 16.54,83.72 16.92,84.09 16.92,84.55 17.03,84.66 17.15,84.66 17.38,84.43 ER5717.2 18.08,84.26 C5702.2
  L4 w0.127: HDMI1.10 10.99,78.01 10.99,80.74 12.59,82.34 12.93,82.68 13.33,82.68 14.22,83.57 15.44,83.57 v1(15.62,83.39)
HDMI_DDI_TX_N0: length 135.6
  TOP w0.089: C5703.1 19.22,83.16 19.69,83.16 19.94,83.41 19.96,83.41 v1(20.27,83.72)
  L4 w0.127: v1(20.27,83.72) 20.75,83.24 20.75,82.58 18.47,80.29 18.47,75.02 17.54,74.09 17.54,72.45 15.88,70.79 15.88,59.63 16.42,59.08 16.42,52.28 16.7,52 16.7,42.48 17.25,41.93 17.25,39.21 18.97,37.49 18.97,36.88 20.73,35.13 20.73,34.37 21.93,33.16 21.93,32.01 22.45,31.5 23.6,31.5 25.78,29.31 32.51,29.31 32.82,29.01 32.82,25.04 34.67,23.18 37.15,23.18 37.88,22.46 38.56,22.46 39.08,21.93 40.28,21.93 40.63,22.29 40.63,23.38 41.97,24.72 48.39,24.72 48.96,25.29 50.54,25.29 52.45,27.21 53.7,27.21 54.79,28.3 56.2,28.3 56.53,28.63 63.22,28.63 65.09,26.75 65.86,26.75 66.8,25.81 71.5,25.81 73.04,27.34 73.59,27.34 75.25,29 75.25,30.29 v1(75.08,30.46)
  BOTTOM w0.089: CPU1.B16 76.65,39.82 76.35,39.52 76.35,39.2 76.4,39.16 76.4,37.84 75.79,37.24 75.79,36.56 75.54,36.31 75.54,32.89 ; v1(75.08,30.46) 75.41,30.79 75.41,31.27 75.54,31.4 75.54,32.89 ; 75.54,32.89 v2(75.39,32.89)
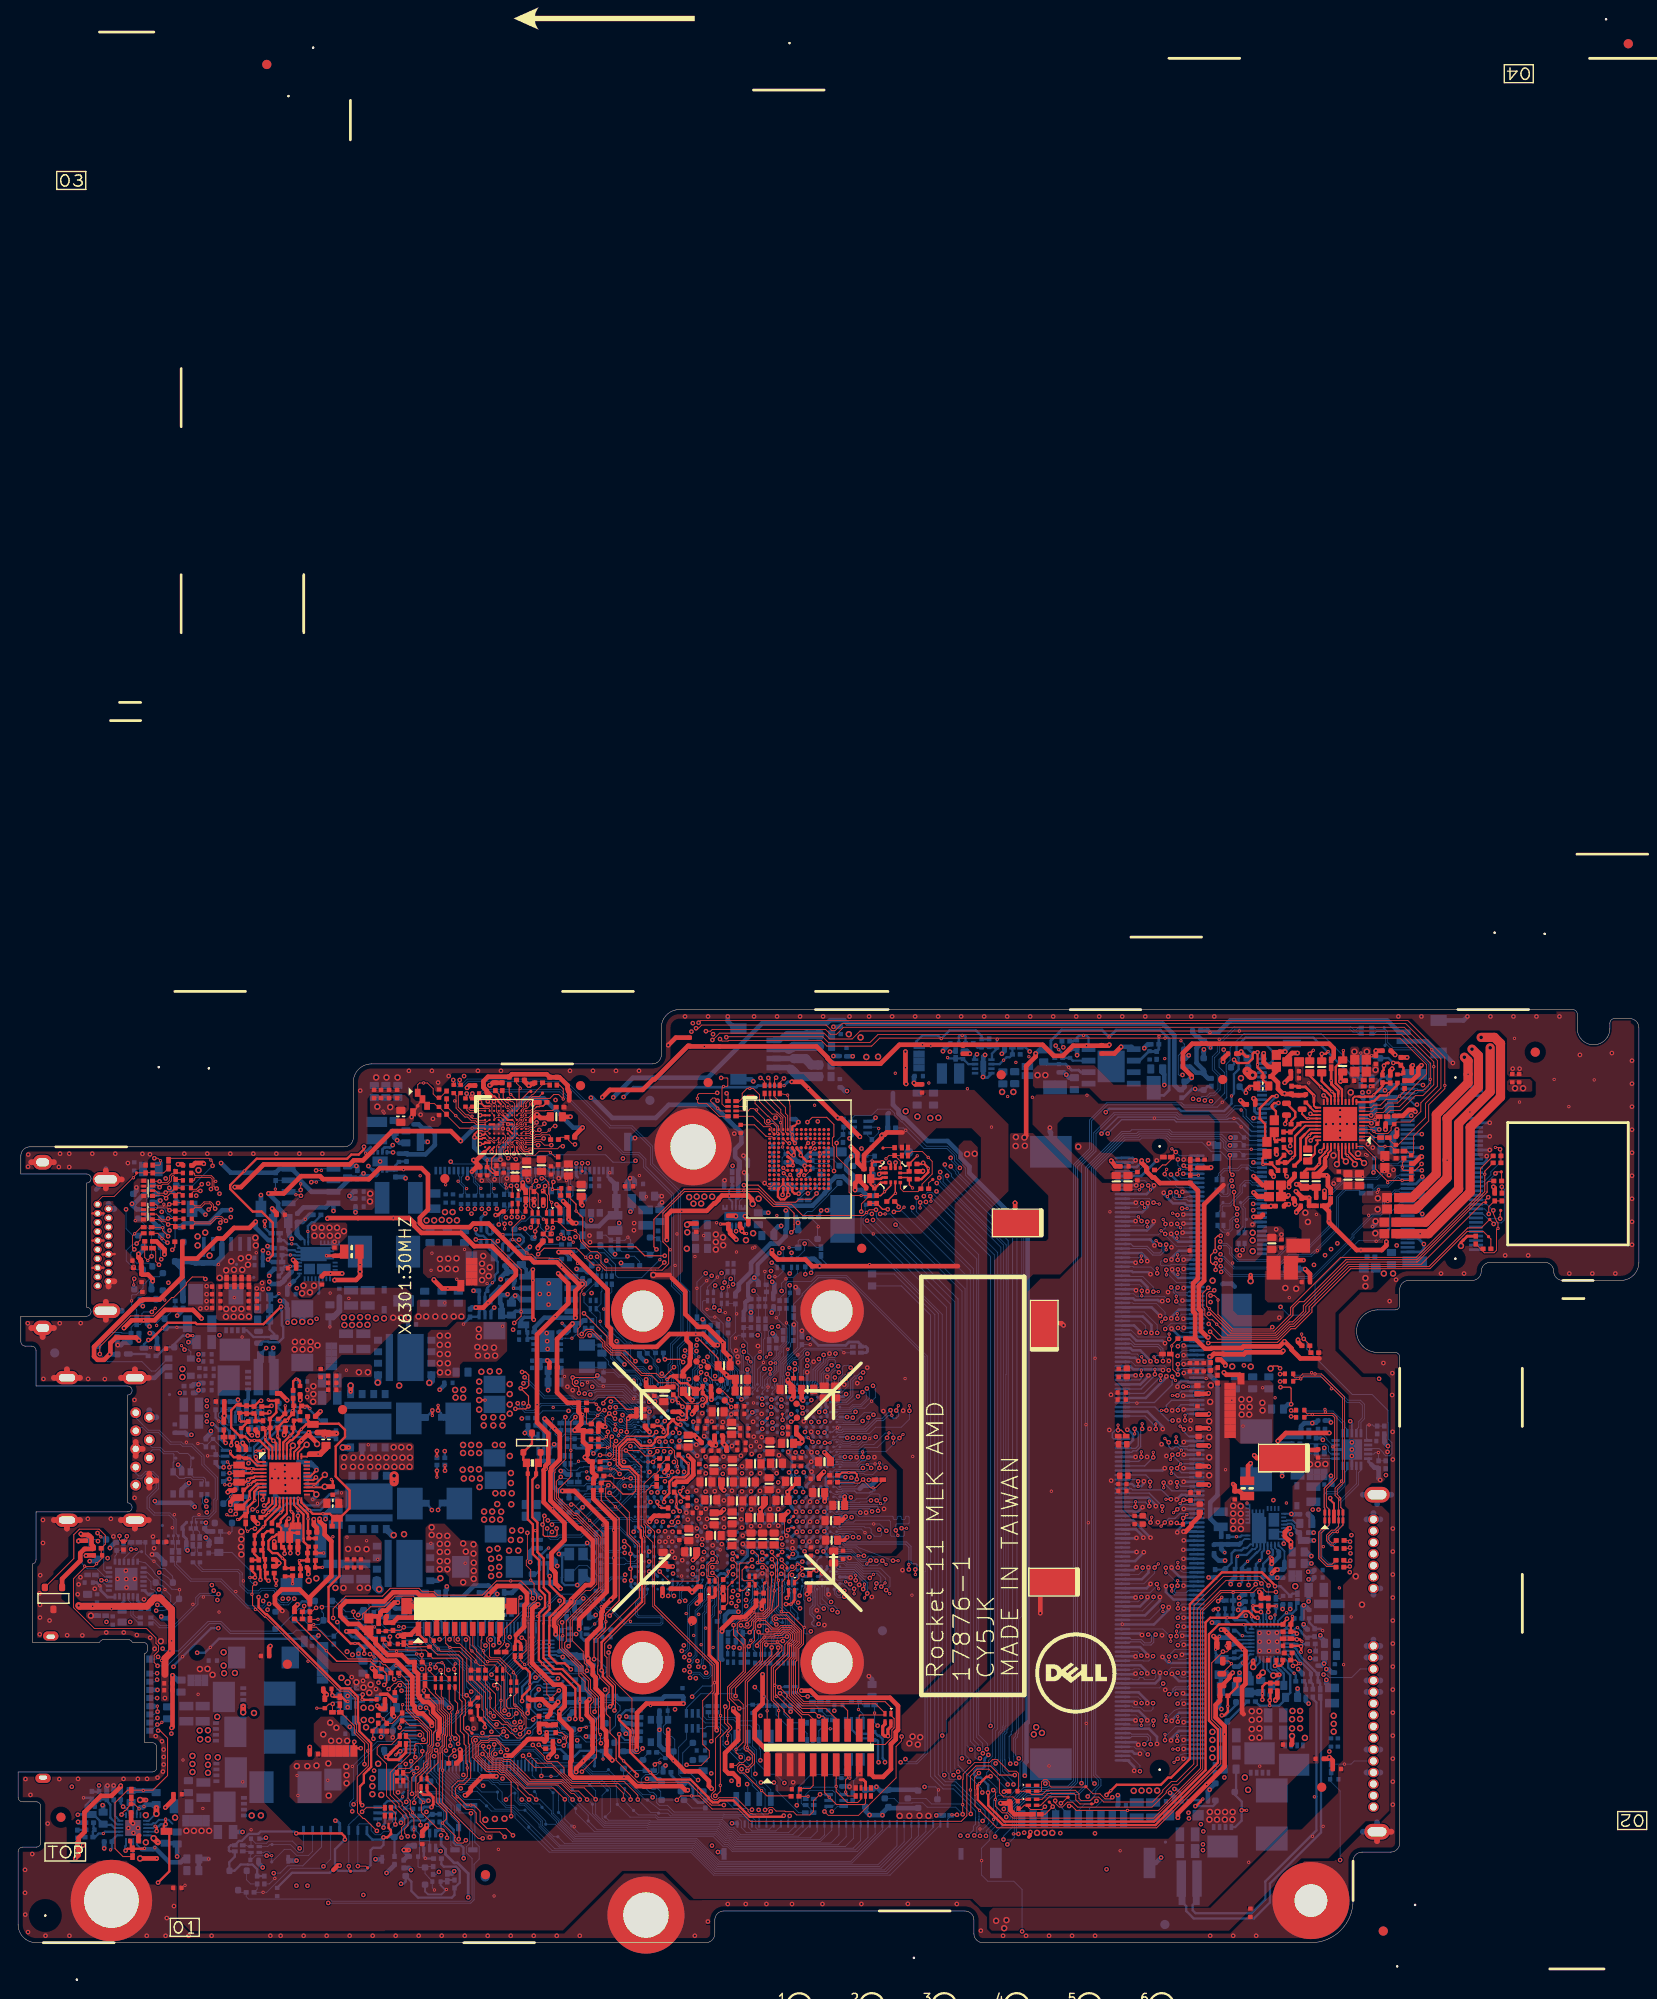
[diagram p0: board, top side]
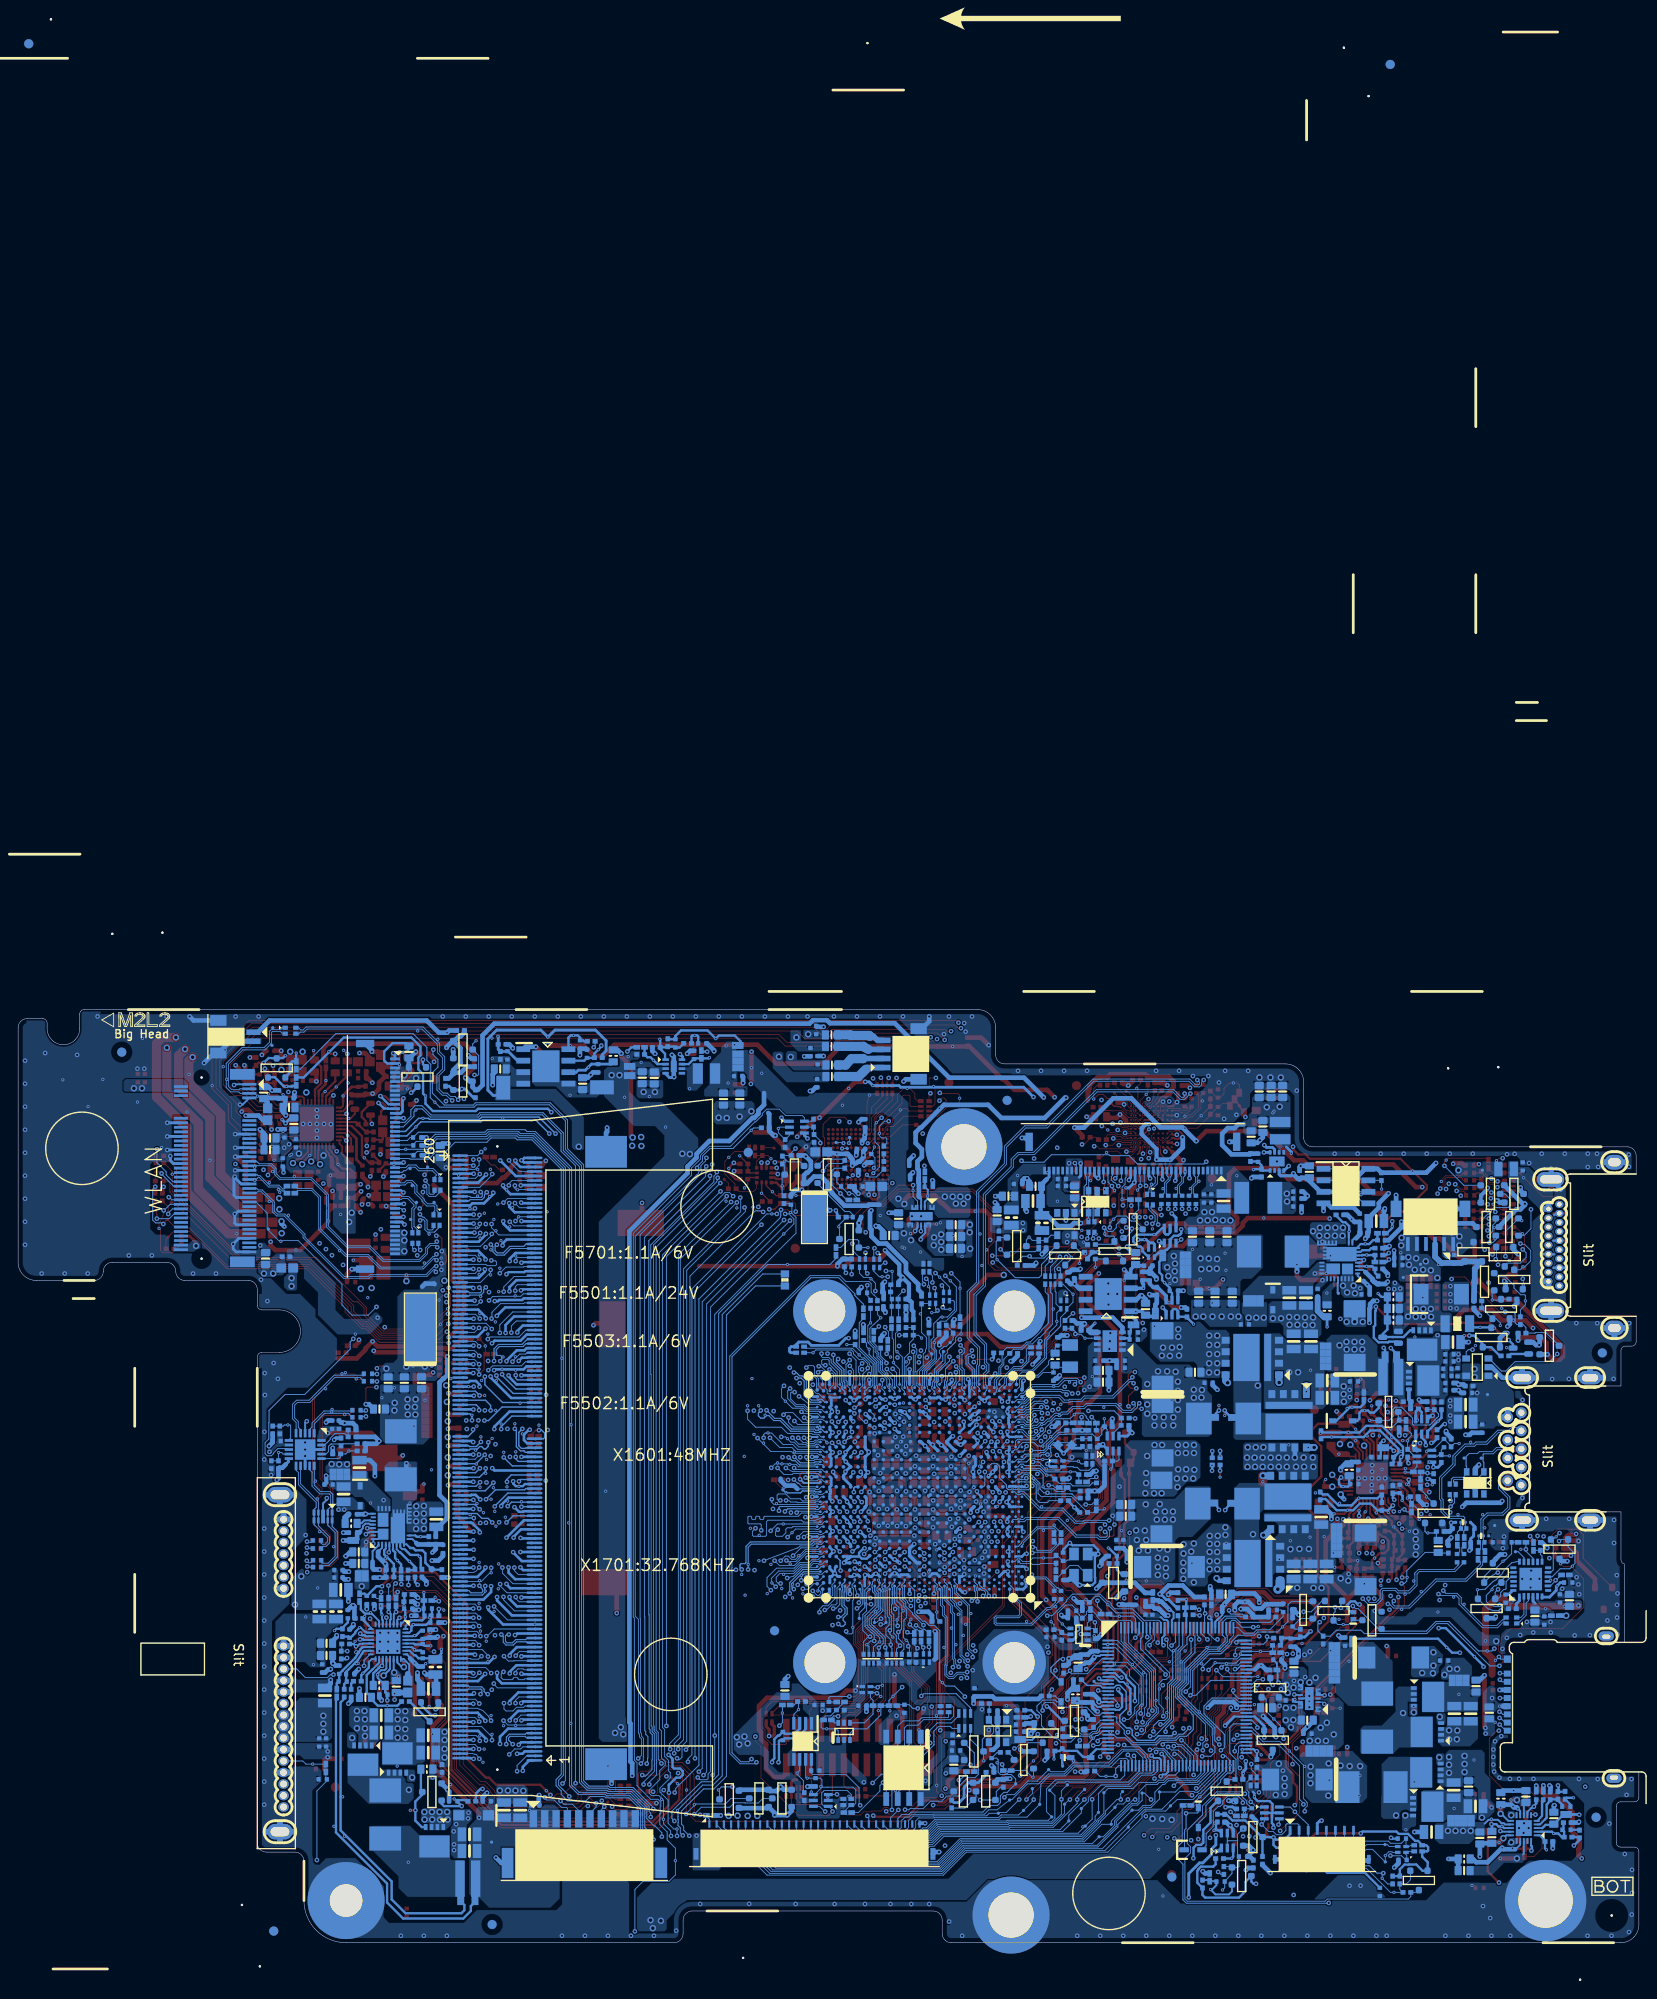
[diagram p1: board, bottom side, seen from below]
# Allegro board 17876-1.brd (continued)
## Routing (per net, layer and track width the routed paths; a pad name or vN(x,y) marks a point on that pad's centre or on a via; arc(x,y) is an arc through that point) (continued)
HDMI_DDI_TX_N1: length 126
  TOP w0.089: v1(21.75,81.02) 21.54,81.23 21.54,81.49 21.27,81.76 21.1,81.76 20.52,81.76 20.09,81.33 19.51,81.33 C5705.1
  L4 w0.127: v1(21.75,81.02) 21.75,80.98 21.53,80.76 21.53,77.43 20.09,76 20.09,74.49 19.06,73.46 19.06,71.82 18.24,71 18.24,68.94 17.72,68.42 17.4,68.1 17.4,60.26 17.95,59.71 17.95,54.63 18.33,54.25 18.33,52.24 18.28,52.19 18.28,44.39 18.41,44.25 18.41,43.66 18.25,43.49 18.25,43.12 18.77,42.6 18.77,39.91 20.52,38.15 20.52,37.51 22.25,35.78 22.25,35.54 26.95,30.84 33.17,30.84 34.34,29.66 34.34,28.63 36.31,26.66 36.65,26.66 37.05,26.26 37.05,26.24 37.92,25.36 39.75,25.36 40.98,26.6 44.11,26.6 44.12,26.61 45.26,26.61 45.48,26.82 49.92,26.82 52.23,29.14 53.25,29.14 53.97,29.86 55.6,29.86 56.53,30.79 60.01,30.79 60.68,31.46 61.79,31.46 62.4,30.85 64.6,30.85 65.15,30.3 65.15,29.66 67.48,27.33 70.8,27.33 72.54,29.08 72.54,30.32 73.16,30.94 73.58,30.94 73.79,31.14 v1(74.07,31.14)
  BOTTOM w0.089: 74.73,33.92 v2(74.57,33.91) ; 74.73,33.92 74.73,36.65 75.34,37.26 75.34,37.47 75.77,37.91 75.77,39.12 75.9,39.24 75.9,39.52 CPU1.B15 ; 74.73,33.92 74.73,31.73 74.13,31.14 v1(74.07,31.14)
HDMI_DDI_TX_N2: length 122.3
  TOP w0.089: v1(22.94,79.68) 22.48,80.14 21.76,80.14 21.18,79.55 19.51,79.55 C5707.1
  L4 w0.127: v1(73.25,32.21) 71.78,30.74 71.78,29.41 70.47,28.09 67.86,28.09 65.99,29.97 65.99,30.58 64.34,32.23 59.75,32.23 59.71,32.2 56.87,32.2 55.3,30.63 53.67,30.63 53.31,30.28 51.98,30.28 50.43,28.73 49.96,28.73 48.97,27.74 45.31,27.74 44.95,27.37 43.8,27.37 43.79,27.36 39.76,27.36 39.39,26.99 39.37,26.99 39.28,26.9 37.71,26.9 36.54,28.07 35.99,28.07 35.12,28.94 35.12,29.98 33.5,31.6 27.27,31.6 23.01,35.86 23.01,36.11 21.29,37.84 21.29,38.48 20.47,39.29 20.47,42.54 19.66,43.35 19.66,43.97 19.43,44.2 19.43,44.32 19.04,44.71 19.04,48.86 19.81,49.63 19.81,56.61 19.63,56.79 19.63,60.2 19.56,60.28 19.56,60.3 19.47,60.39 19.47,71.15 19.82,71.51 19.82,73.14 20.87,74.19 20.87,74.34 21.98,75.45 21.98,75.85 22.94,76.81 22.94,79.68 v1(22.94,79.68)
  BOTTOM w0.089: 73.91,36.33 73.91,32.49 73.63,32.21 v1(73.25,32.21) ; 73.91,36.33 v2(73.74,36.33) ; 73.91,36.33 73.91,37.28 75.31,38.68 75.31,39.14 75.23,39.22 75.23,39.51 75.55,39.82 CPU1.B14
HDMI_DDI_TX_N3: length 135.5
  TOP w0.089: 21.62,84.01 21.62,84.38 21.34,84.66 19.58,84.66 19.49,84.75 19.49,84.87 19.4,84.96 C5701.1 ; 21.62,84.01 21.62,83.47 21.84,83.24 v1(21.92,83.24) ; 21.62,84.01 v2(21.81,84.03)
  L4 w0.127: v1(74.14,29.87) 74.14,29.85 73.76,29.47 73.57,29.47 73.3,29.2 73.3,28.75 71.12,26.57 67.13,26.57 64.12,29.58 60.44,29.58 59.99,30.02 56.85,30.02 55.88,29.06 54.43,29.06 53.34,27.97 52.14,27.97 50.22,26.05 48.65,26.05 48.08,25.48 42.74,25.48 42.46,25.76 41.29,25.76 38.75,23.22 38.19,23.22 36.04,25.36 34.47,25.36 33.58,26.25 33.58,29.34 32.84,30.08 26.11,30.08 21.49,34.7 21.49,35.45 19.75,37.19 19.75,37.84 18.01,39.58 18.01,42.26 17.46,42.81 17.46,52.32 17.18,52.6 17.18,59.4 16.64,59.94 16.64,70.47 18.3,72.14 18.3,73.77 19.24,74.71 19.24,79.98 21.72,82.45 21.72,83.03 v1(21.92,83.24)
  BOTTOM w0.089: CPU1.B17 77.2,39.45 76.89,39.14 76.89,37.34 76.66,37.12 76.66,36.23 76.36,35.92 76.36,30.61 76.4,30.56 76.4,29.64 76.12,29.36 75.74,29.36 75.26,29.85 74.18,29.85 74.16,29.87 v1(74.14,29.87)
HDMI_DDI_TX_P0: length 134.8
  TOP w0.089: C5704.1 19.08,82.66 19.38,82.96 19.79,82.96 19.86,83.03 20.07,83.03 v1(20.12,82.98)
  L4 w0.127: v1(20.12,82.98) 20.4,82.98 20.52,82.86 20.52,82.67 18.24,80.39 18.24,75.11 17.31,74.18 17.31,72.55 15.65,70.89 15.65,59.53 16.19,58.99 16.19,52.19 16.47,51.91 16.47,42.38 17.02,41.84 17.02,39.12 18.75,37.39 18.75,36.79 20.5,35.04 20.5,34.27 21.7,33.07 21.7,31.92 22.35,31.27 23.5,31.27 25.69,29.08 32.42,29.08 32.59,28.91 32.59,24.94 34.58,22.95 37.06,22.95 37.78,22.23 38.47,22.23 38.99,21.7 40.37,21.7 40.86,22.19 40.86,23.28 42.06,24.49 48.49,24.49 49.06,25.06 50.63,25.06 52.55,26.98 53.8,26.98 54.89,28.07 56.3,28.07 56.63,28.4 63.12,28.4 65,26.52 65.77,26.52 66.71,25.58 71.59,25.58 73.13,27.12 73.68,27.12 75.48,28.91 75.48,30.16 v1(75.72,30.41)
  BOTTOM w0.089: 75.74,34.72 75.74,31.31 75.62,31.18 75.62,30.51 v1(75.72,30.41) ; 75.74,34.72 v2(75.9,34.72) ; 75.74,34.72 75.74,36.22 76,36.48 76,37.15 76.6,37.76 76.6,39.16 76.65,39.21 CPU1.A16
HDMI_DDI_TX_P1: length 126.1
  TOP w0.089: C5706.1 19.51,81.13 20.18,81.13 20.61,81.56 21.18,81.56 21.32,81.42 21.32,81.2 21.06,80.93 v1(21.03,80.93)
  L4 w0.127: v1(74.09,30.51) 74.07,30.51 73.86,30.71 73.25,30.71 72.77,30.23 72.77,28.98 70.89,27.1 67.39,27.1 64.92,29.57 64.92,30.21 64.51,30.62 62.3,30.62 61.69,31.23 60.78,31.23 60.1,30.56 56.62,30.56 55.7,29.63 54.07,29.63 53.34,28.91 52.32,28.91 50.01,26.6 45.57,26.6 45.36,26.38 44.22,26.38 44.2,26.37 41.07,26.37 39.84,25.14 37.83,25.14 36.82,26.15 36.82,26.17 36.56,26.43 36.21,26.43 34.11,28.53 34.11,29.57 33.07,30.61 26.85,30.61 22.02,35.44 22.02,35.69 20.29,37.42 20.29,38.06 19.92,38.43 18.54,39.81 18.54,42.51 18.02,43.03 18.02,43.59 18.19,43.75 18.19,44.15 18.05,44.29 18.05,52.28 18.1,52.33 18.1,54.16 17.72,54.53 17.72,59.62 17.17,60.16 17.17,68.2 17.56,68.58 18.02,69.04 18.02,71.1 18.83,71.92 18.83,73.55 19.86,74.58 19.86,76.09 21.3,77.53 21.3,80.66 v1(21.03,80.93)
  BOTTOM w0.089: 74.93,36.25 74.93,31.65 74.5,31.22 74.5,30.96 74.09,30.56 v1(74.09,30.51) ; 74.93,36.25 v2(75.12,36.25) ; 74.93,36.25 74.93,36.57 75.54,37.18 75.54,37.39 75.97,37.82 75.97,38.89 CPU1.A15
HDMI_DDI_TX_P2: length 122.5
  TOP w0.089: v1(22.33,79.48) 22.5,79.66 22.5,79.83 22.39,79.94 21.84,79.94 21.26,79.35 19.51,79.35 C5708.1
  L4 w0.127: v1(73.53,31.52) 73.33,31.73 73.09,31.73 72.01,30.64 72.01,29.31 70.56,27.87 67.77,27.87 65.76,29.87 65.76,30.49 64.24,32.01 59.84,32.01 59.81,31.97 56.96,31.97 55.39,30.41 53.76,30.41 53.41,30.05 52.07,30.05 50.52,28.5 50.06,28.5 49.07,27.51 45.41,27.51 45.04,27.14 43.9,27.14 43.89,27.13 39.85,27.13 39.48,26.76 39.47,26.76 39.38,26.67 37.62,26.67 36.45,27.84 35.9,27.84 34.9,28.84 34.9,29.88 33.41,31.37 27.18,31.37 22.78,35.76 22.78,36.02 21.06,37.75 21.06,38.38 20.24,39.19 20.24,42.45 19.43,43.26 19.43,43.87 19.2,44.1 19.2,44.22 18.81,44.62 18.81,48.95 19.58,49.73 19.58,56.52 19.41,56.69 19.41,60.11 19.33,60.18 19.33,60.21 19.24,60.3 19.24,71.25 19.6,71.6 19.6,73.24 20.62,74.26 20.62,74.41 21.76,75.54 21.76,75.94 22.71,76.9 22.71,79.27 22.5,79.48 v1(22.33,79.48)
  BOTTOM w0.089: CPU1.A14 75.55,39.2 75.51,39.17 75.51,38.59 74.12,37.19 74.12,35.15 ; 74.12,35.15 v2(74.3,35.15) ; 74.12,35.15 74.12,32.4 73.48,31.77 73.48,31.57 v1(73.53,31.52)
HDMI_DDI_TX_P3: length 134.9
  TOP w0.089: v1(21.29,83.19) 21.41,83.31 21.41,84.3 21.25,84.46 19.58,84.46 19.49,84.36 19.49,84.24 19.4,84.15 C5702.1
  L4 w0.127: v1(21.29,83.19) 21.49,82.99 21.49,82.55 19.01,80.07 19.01,74.81 18.07,73.87 18.07,72.23 16.41,70.57 16.41,59.85 16.96,59.3 16.96,52.5 17.23,52.22 17.23,42.71 17.78,42.17 17.78,39.48 19.52,37.74 19.52,37.1 21.26,35.36 21.26,34.6 26.02,29.85 32.75,29.85 33.35,29.24 33.35,26.16 34.37,25.14 35.95,25.14 38.1,22.99 38.84,22.99 41.38,25.53 42.37,25.53 42.49,25.4 42.49,25.38 42.62,25.25 48.17,25.25 48.74,25.82 50.32,25.82 52.23,27.74 53.43,27.74 54.53,28.83 55.97,28.83 56.94,29.8 59.9,29.8 60.34,29.35 64.02,29.35 67.03,26.34 71.22,26.34 73.53,28.66 73.53,29.11 73.66,29.24 v1(74.17,29.24)
  BOTTOM w0.089: v1(74.17,29.24) 74.57,29.64 75.18,29.64 75.66,29.16 76.21,29.16 76.61,29.56 76.61,30.65 76.56,30.69 76.56,32.59 ; v2(76.71,32.59) 76.56,32.59 ; 76.56,32.59 76.56,35.84 76.87,36.14 76.87,37.03 77.09,37.25 77.09,38.79 77.11,38.81 77.11,38.93 CPU1.A17
HDMI_DET_CPU: length 163.4
  TOP w0.089: v1(15.54,74.83) 15.19,75.19 15.19,76.3 R5712.1 ; v1(76.63,40.82) 76.73,40.82 77.28,40.27 77.28,31.24 77.54,30.98 v2(77.54,25.06) 77.54,23.12 76.97,22.54 76.97,16.82 76.78,16.64 76.53,16.39 76.53,16.39 76.52,16.37 76.52,16.02 76.61,15.93 76.63,15.93 76.78,15.79 77.13,15.79 77.34,16 79.25,16 80.58,14.68 80.58,14.51 80.82,14.26 80.99,14.26 81.05,14.2 82.78,14.2 v1(83.08,14.51)
  L3 w0.14: v1(15.54,74.83) 12.66,71.94 12.66,66.19 15.91,62.94 15.91,45.53 16.06,45.38 16.06,44.47 16.71,43.82 16.71,42.31 16.47,42.07 16.47,37.54 21.4,32.61 23.55,32.61 26.04,30.13 30.53,30.13 30.94,29.72 32.72,29.72 33.58,28.86 33.58,26.21 36.67,23.12 36.81,23.12 37.56,22.36 37.56,21.84 37.37,21.65 37.37,21.28 37.62,21.03 37.62,17.82 37.9,17.53 37.9,16.05 39.06,14.89 39.06,12.24 40.16,11.14 46.24,11.14 47.52,9.86 57.16,9.86 58.21,10.92 76.38,10.92 v1(76.59,10.71)
  L4 w0.14: v1(76.59,10.71) 76.82,10.95 79.53,10.95 v1(83.08,14.51)
  BOTTOM w0.089: CPU1.D17 76.98,41.12 76.68,40.82 v1(76.63,40.82)
HDMI_HPD_B: length 12.8
  TOP w0.089: R5710.2 15.63,85.83 15.72,85.92 v2(15.72,86.32) 15.44,86.59 v1(15.04,86.59)
  L3 w0.14: v1(15.04,86.59) 15.04,86.08 11.91,82.96 v1(11.91,80.95)
  BOTTOM w0.089: Q5708.B 12.68,78.05 11.91,78.82 v1(11.91,80.95)
HDMI_HPD_E: length 7.7
  TOP w0.089: R5709.2 13.98,76.66 R5712.2 13.97,75.65 v2(14.32,75.3) 14.32,75.35 v1(14.73,75.77)
  BOTTOM w0.089: Q5708.E 14.73,78.49 v1(14.73,75.77)
HDMI_HPD_G: length 10.5
  TOP w0.089: R5702.2 16.82,86.59 21.07,86.59 v2(21.27,86.39) 21.46,86.2 v1(21.46,85.75)
  BOTTOM w0.089: v1(21.46,85.75) 19.31,83.6 Q5707.G
HDMI_IN#: length 161
  TOP w0.102: v1(17.02,76.48) 17.3,76.76 R5701.2 ; v1(76.96,16.21) 77.02,16.21 77.51,16.7 v2(77.51,17.36) 77.51,22.67 78.46,23.63 78.46,23.77 77.98,24.26 77.98,25.91 78.05,25.99 v1(78.05,26.06)
  L3 w0.102: v1(76.96,16.21) 76.96,16.15 75.27,14.47 73.81,14.47 73.77,14.43 72.63,14.43 72.41,14.65 71.48,14.65 71.42,14.71 50.38,14.71 50.05,15.04 47.94,15.04 45.75,17.22 42.28,17.22 40.27,19.23 40.27,19.97 39.96,20.29 38.75,20.29 38.57,20.47 38.57,22.2 37.41,23.35 37.41,23.65 35.18,25.88 35.18,27.61 32.81,29.97 31.04,29.97 30.63,30.38 26.14,30.38 23.66,32.86 21.5,32.86 16.71,37.64 16.71,41.97 16.95,42.21 16.95,43.93 16.31,44.57 16.31,45.48 16.15,45.64 16.15,63.04 12.9,66.29 12.9,71.68 15.62,74.4 15.72,74.4 16.66,75.34 16.66,76.13 v1(17.02,76.48) ; v1(57.56,26.17) 57.65,26.08 57.72,26.08 58.7,25.1 59.92,25.1 60.86,26.04 63.91,26.04 65.53,24.41 69.81,24.41 70.45,25.05 74.81,25.05 75.41,25.66 77.72,25.66 78.05,25.99 v1(78.05,26.06)
  BOTTOM w0.102: v1(17.02,76.48) 17.32,76.79 17.32,79.78 16.69,80.42 16.53,80.42 16.28,80.67 16.28,80.85 15.98,81.16 14.44,81.16 14.21,81.38 14.21,82.09 14.77,82.65 Q5707.D ; v1(57.56,26.17) 57.56,26.53 57.98,26.95 U2401.17
HDMI_PLL_GND: length 0.8
  BOTTOM w0.508: Q5701.D 13.06,82.99 v1(13.06,83.36)
  vias: v2(12.93,79.7)
HDMI_SCL_CPU: length 124.3
  TOP w0.089: RN811.4 76.28,40.03 76.02,40.29 76.02,41.71 76.38,42.06 76.39,42.06 v1(76.65,42.32) ; v2(12.76,72.6) 12.76,73.23 v1(12.81,73.28)
  L4 w0.14: v1(76.65,42.32) 76,41.67 76,40.54 75.15,39.69 74.66,39.69 74.65,39.7 74.45,39.7 73.69,38.94 73.69,38.3 74.07,37.92 74.07,37.57 73.69,37.19 72.36,37.19 72.19,37.37 66.9,37.37 64.52,39.75 64.52,43.84 58.67,49.68 58.67,55.96 57.58,57.05 57.58,58.07 57.76,58.24 57.76,59.15 56.67,60.23 56.67,61.91 56.8,62.04 56.8,63.14 54.97,64.97 54.97,66.6 54.9,66.67 54.9,66.7 54.18,67.41 54.18,69.74 54.18,69.75 54.18,69.75 51.36,72.57 51,72.57 50.7,72.87 49.23,72.87 49,72.65 34.52,72.65 31.85,69.98 29.69,69.98 29.46,69.76 27.15,69.76 25.35,71.55 23.3,71.55 21.7,73.15 21.7,73.61 21.86,73.77 21.86,73.93 22.97,75.04 22.97,75.44 24.52,76.99 24.52,81.91 22.91,83.52 22.91,83.65 21.87,84.69 19.97,84.69 17.23,81.94 17.23,77.37 16.61,76.76 16.35,76.76 16.02,76.43 15.95,76.43 15.7,76.18 15.7,76.1 15.14,75.55 15.14,75.42 13.54,73.81 13.03,73.81 12.81,73.6 v1(12.81,73.28)
  BOTTOM w0.089: Q5703.S 12.75,72.2 12.75,73.22 v1(12.81,73.28) ; CPU1.G17 76.95,42.72 76.65,42.42 v1(76.65,42.32)
HDMI_SDA_CPU: length 130.7
  TOP w0.089: RN811.3 76.93,40.27 76.78,40.41 76.33,40.41 76.23,40.51 76.23,41.63 76.45,41.86 77.01,41.86 v2(77.17,42.01) 77.17,42.52 v1(76.65,43.04)
  L4 w0.14: v1(15.8,75.44) 15.8,75.32 15.86,75.26 16.41,75.26 17.2,76.05 17.22,76.05 17.68,76.5 17.68,81.77 20.14,84.23 21.7,84.23 22.46,83.46 22.46,83.34 24.07,81.73 24.07,77.17 22.52,75.62 22.52,75.22 21.41,74.11 21.41,73.97 21.25,73.81 21.25,72.97 23.2,71.02 25.25,71.02 26.96,69.31 29.53,69.31 29.54,69.32 29.9,69.32 30.07,69.5 32.03,69.5 33.02,70.49 33.02,70.51 34.7,72.19 49.17,72.19 49.4,72.41 50.53,72.41 50.83,72.11 51.18,72.11 53.72,69.58 53.72,67.24 54.43,66.52 54.43,66.5 54.51,66.42 54.51,64.8 56.36,62.95 56.36,62.22 56.23,62.1 56.23,60.03 57.3,58.96 57.3,58.42 57.12,58.24 57.12,56.87 58.19,55.81 58.19,54.51 58.05,54.37 56.85,54.37 56.71,54.23 56.71,53.95 56.85,53.81 58.05,53.81 58.19,53.67 58.19,53.39 58.05,53.25 56.85,53.25 56.71,53.11 56.71,52.83 56.85,52.69 58.05,52.69 58.19,52.55 58.19,51.94 58.05,51.8 57.32,51.8 57.18,51.66 57.18,51.38 57.32,51.24 58.05,51.24 58.19,51.1 58.19,49.2 61.16,46.23 61.34,46.23 64.15,43.43 64.15,39.77 66.8,37.11 72.09,37.11 72.26,36.93 73.79,36.93 74.32,37.47 74.32,38.03 73.94,38.41 73.94,38.83 74.56,39.45 75.39,39.45 76.25,40.31 76.91,40.31 77.19,40.59 77.19,42.5 v1(76.65,43.04)
  BOTTOM w0.089: v1(76.65,43.04) 77.12,43.52 CPU1.H17 ; v1(15.8,75.44) 15.72,75.52 15.72,76.75 Q5705.S
HPD_HDMI_CON: length 9.8
  TOP w0.089: HDMI1.19 8.78,81.83 9.32,82.37 10.6,82.37 13.07,84.84 TP5701.1 13.09,84.98 14.06,84.98 R5711.1 14.1,84.99 14.83,84.99 R5710.1 16.06,84.96 R5702.1
HUB_USB20_CON_N7: length 6.4
  BOTTOM w0.089: IOBD1.31 136.73,82.55 136.55,82.37 135.79,82.37 135.03,81.61 ; AFTP6606.1 135.03,81.61 ; 135.03,81.61 134.98,81.56 134.98,81.18 135.2,80.95 135.2,79.07 134.72,78.59 EL6602.1
HUB_USB20_CON_P7: length 5.8
  BOTTOM w0.089: 135.45,79.84 135.45,78.92 135.38,78.85 EL6602.2 ; 135.45,79.84 135.45,81.05 135.22,81.28 135.22,81.46 135.89,82.13 136.5,82.13 136.58,82.05 IOBD1.32 ; 135.45,79.84 AFTP6607.1
HUB_USB20_N7: length 134
  TOP w0.089: v1(66.55,56.47) 66.29,56.21 v2(66.29,55.97)
  L4 w0.114: v1(134.52,76.46) 134.52,76.51 134.94,76.93 134.94,78.72 135.19,78.98 135.19,81.85 135.65,82.31 135.65,83.07 136.87,84.29 136.87,86.54 136.42,86.98 136.42,89.65 133.83,92.24 133.83,93.77 130.67,96.93 129.2,96.93 129.07,97.06 117.44,97.06 117.35,97.16 109.51,97.16 109.34,97.32 104.86,97.32 104.51,97.67 100.79,97.67 100.45,97.32 96.53,97.32 96.19,96.98 87.5,96.98 86.53,97.96 77.65,97.96 73.01,93.32 72.29,93.32 68.86,89.89 68.86,85.7 68.22,85.07 68.22,84.1 67.84,83.72 67.84,81.89 67.13,81.18 67.13,76.27 62.55,71.68 62.55,70.5 63.25,69.8 63.25,68 64.77,66.47 64.77,60.35 63.67,59.25 63.67,58.73 64,58.41 64.45,58.41 65.79,57.08 66.09,57.08 66.34,56.82 66.34,56.67 v1(66.55,56.47)
  BOTTOM w0.089: EL6602.4 134.72,76.69 134.57,76.53 134.57,76.51 v1(134.52,76.46) ; CPU1.AM2 68.87,56.37 68.57,56.67 68.27,56.67 68.21,56.61 68,56.61 67.35,55.96 66.83,55.96 66.55,56.24 v1(66.55,56.47)
HUB_USB20_P7: length 133.9
  TOP w0.089: v2(65.91,57.2) 65.91,57.2 v1(65.91,56.64)
  L4 w0.114: v1(65.91,56.64) 64.36,58.19 63.91,58.19 63.46,58.64 63.46,59.34 64.55,60.44 64.55,66.38 63.03,67.91 63.03,69.71 62.33,70.41 62.33,71.77 66.92,76.36 66.92,81.27 67.63,81.98 67.63,83.81 68.01,84.19 68.01,85.16 68.64,85.79 68.64,89.98 72.2,93.54 72.92,93.54 77.56,98.17 86.62,98.17 87.59,97.19 96.1,97.19 96.44,97.54 100.36,97.54 100.7,97.89 104.6,97.89 104.95,97.54 109.43,97.54 109.6,97.37 117.44,97.37 117.53,97.28 129.16,97.28 129.29,97.14 130.76,97.14 134.05,93.86 134.05,92.33 136.64,89.74 136.64,87.07 137.08,86.63 137.08,84.2 135.86,82.98 135.86,82.22 135.41,81.76 135.41,78.89 135.15,78.63 v1(135.15,76.46)
  BOTTOM w0.089: v1(135.15,76.46) 135.38,76.68 EL6602.3 ; CPU1.AM1 68.1,56.37 67.45,55.72 66.73,55.72 65.94,56.51 65.94,56.62 v1(65.91,56.64)
HVBEN_L: length 10.5
  TOP w0.102: v2(83.62,63.98) 83.57,63.98 83.57,63.98 v1(83.06,63.98)
  L3 w0.102: v1(83.26,57.43) 83.26,57.89 83.57,58.19 83.57,61.33 83.01,61.89 83.01,62.22 83.52,62.73 83.52,63.53 v1(83.06,63.98)
  BOTTOM w0.102: v1(83.06,63.98) 83.06,64.14 83.69,64.77 R1756.2 ; CPU1.AP27 82.92,57.12 83.21,57.41 83.24,57.41 v1(83.26,57.43)
I2C1_1V8_CLK: length 18.3
  TOP w0.089: TP1703.1 78.72,59.18 v1(78.72,59.12)
  L4 w0.14: v1(78.92,72.67) 78.97,72.62 78.97,71.76 79.32,71.41 79.32,70.86 79.31,70.85 79.31,67.78 78.74,67.22 78.74,65.64 77.76,64.65 77.76,61.48 79.17,60.07 79.17,59.57 v1(78.72,59.12)
  BOTTOM w0.089: CPU1.AU19 78.32,58.72 v1(78.72,59.12) ; v1(78.92,72.67) 78.92,72.86 79.09,73.03 79.09,73.77 78.97,73.89 RN1705.3
I2C1_1V8_DATA: length 18.2
  TOP w0.089: v1(78.74,59.89) 78.74,59.94 77.77,60.91 TP1704.1
  L4 w0.14: v1(77.98,72.87) 78.4,72.45 78.4,70.18 78.86,69.72 78.86,67.97 78.28,67.39 78.28,65.76 77.42,64.9 77.42,61.22 v1(78.74,59.89)
  BOTTOM w0.089: v1(77.98,72.87) 77.98,73.61 78.3,73.94 RN1705.4 ; CPU1.AV19 78.37,59.52 78.7,59.86 78.7,59.86 v1(78.74,59.89)
I_BATT: length 129.1
  TOP w0.254: C2447.2 43.38,33.15 v1(44.42,33.15) ; v1(120.14,16.31) v2(120.6,16.77) 121.26,17.43 126.14,17.43 126.93,18.22 127.27,18.22 129.34,20.29 129.34,37.35 132.86,40.88 137.29,40.88 138.73,39.43 v1(138.73,39.35)
  L3 w0.254: v1(120.14,16.31) 119.58,16.87 117.07,16.87 114.68,19.25 106.73,19.25 106.41,19.58 106.07,19.58 104.79,20.86 100.05,20.86 99.85,20.65 98.78,20.65 98.65,20.78 93.71,20.78 92.43,22.06 86.34,22.06 82.36,26.05 82.05,26.05 79.81,28.3 70.71,28.3 70.23,27.82 67.67,27.82 65.85,29.64 65.85,29.73 63.71,31.88 62.69,31.88 61.49,30.68 60.79,30.68 60.77,30.66 57.38,30.66 56.92,31.12 51.69,31.12 51.5,31.31 50.53,31.31 50.09,31.75 46.91,31.75 46.46,32.21 45.59,32.21 44.65,33.15 v1(44.42,33.15)
  BOTTOM w0.203: U2401.96 44.22,33.35 v1(44.42,33.15)
  BOTTOM w0.254: PR4476.1 140.66,38.52 PC4403.1 139.34,39.35 v1(138.73,39.35)
INT_SERIRQ: length 13.7
  BOTTOM w0.089: U2401.125 55.95,35.38 56.15,35.58 59.41,35.58 59.81,35.98 59.81,36.13 60.44,36.77 60.45,36.77 R2435.1 60.72,36.77 60.97,36.51 60.97,36.25 61.41,35.82 R2420.2 61.73,36.11 61.73,36.18 62.1,36.55 C2401.1 62.1,36.81 62.57,37.27 63.26,37.27 64.18,36.35 64.18,35.72 v2(63.64,35.18) 63.15,34.69 U2404.4
INT_SERIRQ_OE: length 3
  BOTTOM w0.102: v2(64.88,35.43) 64.88,35.42 64.57,35.11 R2419.1 64.01,34.55 R2421.2 63.5,34.04 U2404.5
INT_TP#: length 137.3
  TOP w0.089: v1(43.48,16.44) 43.48,16.49 43.45,16.53 43.45,18.24 43.66,18.45 v2(43.66,18.68) 44,18.68 44.14,18.82 44.18,18.82 44.75,19.39 44.75,19.74 45.04,20.02 45.04,20.95 45.24,21.15 45.24,21.75 45.42,21.93 45.42,23.28 44.05,24.65 43.86,24.65 42.86,25.65 42.86,28.31 42.31,28.85 41.95,28.85 41.73,28.63 41.53,28.63 v1(40.89,27.99) ; v1(60.4,58.02) 60.4,53.34 59.26,52.2 59.26,51.91 59.19,51.83 59.19,48.98 61.36,46.81 61.62,46.81 63.87,44.56 63.87,39.57 63.18,38.88 62.66,38.88 61.5,37.72 61.5,37.44 60.24,36.18 60.24,36.16 59.59,35.51 59.59,35.16 59.77,34.98 59.77,32.48 60.32,31.92 60.34,31.92 61.9,30.36 61.9,29.47 62.59,28.78 62.59,27.94 63.49,27.03 63.49,26.59 63.2,26.29 63.2,25.3 63.85,24.65 63.85,22.31 63.84,22.3 63.84,21.95 63.85,21.94 63.85,20.49 v1(62.23,18.87)
  L3 w0.14: v1(62.23,18.87) 62.23,18.31 61.89,17.98 58.81,17.98 57.94,18.85 52.09,18.85 50.04,20.89 50.04,22.78 50.73,23.47 50.73,23.84 50.66,23.91 50.66,23.96 49.23,25.38 43.39,25.38 40.89,27.88 v1(40.89,27.99)
  BOTTOM w0.089: R1709.2 R1737.2 59.89,57.51 v1(60.4,58.02) ; v1(43.48,16.44) 43.7,16.65 46.61,16.65 48.17,15.08 48.17,14.09 49.85,12.41 49.85,10.95 49.5,10.61 49.5,9.9 50.11,9.3 50.11,4.83 49.86,4.58 34.64,4.58 34.41,4.81 25.45,4.81 25.18,5.09 R6510.2 24.5,5.56 Q6502.D
INT_TP#_CONN: length 38.3
  L4 w0.14: v1(33.7,8.43) 34.44,9.16 35.74,9.16 39.15,12.58 39.15,13.9 40.89,15.64 40.89,18.77 42.29,20.17 42.39,20.17 43.15,20.92 44.16,20.92 44.5,20.59 v1(45.92,20.59)
  BOTTOM w0.089: Q6502.S 25.2,6.95 25.67,6.49 R6512.2 26.39,5.9 R6510.1 v2(27.04,5.56) 27.43,5.56 30.09,8.21 33.49,8.21 v1(33.7,8.43) 34.5,9.22 TPAD1.5 ; U2401.63 45.15,20.14 45.64,20.63 45.88,20.63 v1(45.92,20.59)
INT_TP#_R: length 10.9
  BOTTOM w0.102: CPU1.AJ2 68.8,55.35 68.58,55.57 68.35,55.57 68.33,55.55 68.28,55.55 68.24,55.52 66.46,55.52 65.51,56.48 65.51,56.81 64.96,57.35 64.91,57.35 64.43,57.84 62.78,57.84 v2(62.32,58.3) 62.17,58.45 61.34,58.45 61,58.11 61,57.96 60.76,57.72 R1737.1
JACK_PLUG: length 15.8
  TOP w0.254: R2914.1 137.41,95.2 R2905.1 137.41,95.99 136.8,96.6 v2(136.8,96.92) v1(136.8,98.27) 136.41,98.27 136.27,98.13 136.27,97.6 135.78,97.1 134.57,97.1 v1(134.21,97.46)
  BOTTOM w0.254: IOBD1.2 138.17,97.05 138.49,97.37 138.49,98.36 137.57,99.29 136.07,99.29 C2902.2 135.76,98.63 136.07,98.33 136.37,98.33 136.42,98.27 v1(136.8,98.27) ; v1(134.21,97.46) 134.21,96.97 Q2901.G
KB_LOOP: length 2.4
  TOP w0.102: v1(103.63,14.12) v2(103.07,14.12)
  BOTTOM w0.102: KB1.1 102.6,13.63 102.92,13.95 R6515.2 103.56,14.05 v1(103.63,14.12)
KBC_BEEP: length 176.7
  L3 w0.102: v1(109.07,13.87) 108.58,14.36 108.58,14.37 108.37,14.58 108.37,14.62 107.15,15.84 106.22,15.84 105.91,16.16 102.04,16.16 101.92,16.04 92.06,16.04 89.71,18.39 83.01,18.39 81.94,19.46 81.65,19.46 81.46,19.66 80.34,19.66 80.18,19.82 78.73,19.82 77.49,21.07 75.8,21.07 75.49,21.38 69.85,21.38 69.13,20.65 68,20.65 67.85,20.8 65.07,20.8 64.9,20.64 63.77,20.64 63.57,20.84 59.78,20.84 v1(59.46,20.52)
  BOTTOM w0.102: v1(59.46,20.52) 59.46,20.63 59.13,20.95 U2401.32 ; v1(109.07,13.87) 109.07,14.3 109.23,14.46 109.23,15.04 111.1,16.91 113.66,16.91 113.81,17.05 115.98,17.05 116.71,17.79 116.71,85.78 118.49,87.56 118.49,90.72 120.25,92.48 128.32,92.48 128.57,92.23 132.36,92.23 v2(132.91,92.78) 133.41,93.28 133.41,96.13 133.35,96.19 133.35,96.96 133.78,97.39 133.78,98.82 135.31,100.34 143.83,100.34 147.75,96.42 R2734.1
KBC_BEEP_R: length 3.4
  BOTTOM w0.254: v2(148.21,98.2) R2734.2 148.66,97.28 148.92,97.03 148.92,96.04 D2703.2
KBC_ON#_GATE: length 7.8
  TOP w0.102: R2492.2 39.75,24 C2442.1 39.14,23.34 39.14,22.58 v1(39.22,22.51)
  BOTTOM w0.102: v1(39.22,22.51) 39.22,23.18 Q2404.G 39.56,23.52 39.56,23.96 v2(40.3,24.7) 41.15,25.55 41.15,26.89 41.34,27.08 Q2403.G
KBC_ON#_GATE_L: length 4.5
  TOP w0.102: v2(42.44,26.28) 42.39,26.23 R2493.2 42.37,25.35 41.91,24.89 41.91,24.82 41.3,24.21 R2491.1 40.69,24.33 39.92,25.1 39.75,25.1
KBC_PECI: length 1.7
  BOTTOM w0.102: TP2407.1 59.96,28.65 59.28,28.65 59.19,28.55 U2401.13
KBC_PWRBTN#: length 180.9
  TOP w0.102: v1(38.84,31.85) 38.95,31.85 39.28,31.52 v2(39.29,31.52)
  L3 w0.102: v1(118.06,16.14) 117.26,16.14 114.45,18.95 106.58,18.95 106.36,19.17 105.17,19.17 104.8,19.53 104.78,19.53 104.4,19.92 99.34,19.92 98.68,19.25 94.08,19.25 92.09,21.25 85.44,21.25 82.08,24.61 81.76,24.61 81.51,24.87 81.51,25.13 79.84,26.8 78.99,26.8 78.77,27.03 74.9,27.03 74.6,26.72 74.55,26.72 74.35,26.52 73.99,26.52 73.68,26.82 70.69,26.82 70.66,26.79 67.01,26.79 65.43,28.37 61.71,28.37 60.4,27.06 57.1,27.06 55.31,28.86 51.58,28.86 50.89,29.54 46.55,29.54 46.42,29.67 45.36,29.67 45.01,30.02 45.01,30.38 44.65,30.74 44.17,30.74 43.36,31.55 40.03,31.55 39.73,31.85 v1(38.84,31.85)
  BOTTOM w0.102: v1(38.84,31.85) 38.99,32.01 R2488.1 ; v1(118.06,16.14) 118.06,16.21 119.24,17.38 119.24,17.94 118.72,18.46 118.72,85.48 122.09,88.85 123.65,88.85 123.85,89.05 126.8,89.05 127.13,88.72 132.67,88.72 133.07,88.32 133.07,87.76 133.48,87.35 134.82,87.35 EC6601.1 135.28,86.95 135.48,86.95 135.59,87.05 IOBD1.22
KBC_VCC: length 92.1
  TOP w0.508: v1(57.4,37.34) 57.34,37.34 57.17,37.16 57.06,37.16 57.03,37.13 57.02,37.13 56.75,36.86 56.75,35.79 56.72,35.76 56.72,33.69 56.72,33.68 56.72,30.89 56.83,30.78 56.83,30.75 57.61,29.97 57.64,29.97 58.14,29.47 58.14,29.45 59.11,28.48 59.95,28.48 60.33,28.1 60.33,26.11 v1(59.74,25.53) 59.74,24.72 61.07,23.39 61.07,20.07 60.96,19.96 60.96,18.59 61.33,18.21 67.32,18.21 68.26,17.27 69.02,17.27 69.06,17.23 69.77,17.23 69.81,17.27 73.23,17.27 73.67,16.84 v1(73.91,16.84) ; v1(49.33,16.28) 49.47,16.28 49.96,16.78 49.96,17.07 v2(50.99,18.1) 51.25,18.37 v1(52.78,18.37) ; C2440.1 41.33,25.15 v1(41.48,25)
  L3 w0.508: v1(73.91,16.84) 73.8,16.95 67.29,16.95 66.8,16.46 49.51,16.46 v1(49.33,16.28) 48.21,16.28 45.85,18.63 42.98,18.63 41.55,20.06 41.55,21.22 v1(40.06,22.71)
  BOTTOM w0.203: U2401.19 59.27,26.15 59.41,26.01 59.74,26.01 60.25,26.52 C2431.1 ; U2401.46 51.95,18.86 52.25,18.57 52.58,18.57 v1(52.78,18.37) ; U2401.115 51.95,35.44 52.15,35.64 52.45,35.64 52.73,35.92 52.83,35.92
  BOTTOM w0.381: v1(59.74,25.53) 59.92,25.53 60.3,25.91 60.3,26.47 C2431.1
  BOTTOM w0.508: 55.5,37.29 56.95,37.29 57,37.34 v1(57.4,37.34) ; v1(41.48,25) 40.21,23.73 40.21,22.86 v1(40.06,22.71) ; R2408.1 61.95,26.52 C2430.1 C2431.1
KBC_VCORF: length 8.2
  TOP w0.508: v1(53.8,20.65) 54.5,20.65 55.87,22.02 55.87,22.04 56.24,22.41 56.25,22.41 56.32,22.48 57.87,22.48 C2443.1 58.34,22.45 v2(58.34,23.23)
  BOTTOM w0.203: U2401.44 52.75,20.19 52.96,20.4 53.54,20.4 v1(53.8,20.65)
KBRST#: length 132.8
  L3 w0.102: v1(52.25,29.59) 55.22,29.59 57.29,27.52 57.82,27.52 58.48,28.18 58.53,28.23 59.26,28.23 59.87,28.83 65.66,28.83 67.24,27.25 70.47,27.25 70.85,27.63 74.17,27.63 74.2,27.66 79.38,27.66 81.56,25.48 82.12,25.48 82.37,25.23 82.37,24.91 85.81,21.48 92.19,21.48 94.18,19.48 97.59,19.48 97.94,19.84 v1(97.94,20.27)
  BOTTOM w0.102: v1(52.25,29.59) 52.25,29.69 55,32.44 55,33.56 54.75,33.8 U2401.122 54.75,35.36 55.79,36.4 57.71,36.4 v2(58.61,37.3) 59.56,38.25 59.97,38.25 R2400.2 ; v1(97.94,20.27) 98.25,19.97 99.11,19.97 100.1,20.96 100.1,40.95 100.13,40.97 100.13,41.35 100.1,41.38 100.1,64.68 91.38,73.4 88.32,73.4 86.54,71.62 86.54,71.43 85.6,70.49 R1633.2
KCOL0: length 51.4
  TOP w0.089: v1(63.75,15.83) 62.48,17.1 60.97,17.1 60.09,17.98 56.61,17.98 54.36,20.22 53.57,20.22 53.42,20.37 52.54,20.37 52.25,20.65 52.25,21.01 52.55,21.31 v1(52.55,21.89)
  BOTTOM w0.089: KB1.18 89,11.89 88.49,11.38 79.4,11.38 78.71,12.07 78.41,12.07 77.47,13.01 77.42,13.01 77.39,13.04 69.64,13.04 69.55,13.13 64.8,13.13 63.75,14.18 v1(63.75,15.83) 63.75,16.76 AFTP6517.1 ; U2401.53 49.15,20.63 50.36,21.85 50.88,21.85 51.16,22.12 52.32,22.12 v1(52.55,21.89)
KCOL1: length 50.7
  TOP w0.089: v1(51.33,21.69) 51.33,21.36 51.84,20.85 51.84,20.53 52.45,19.92 53.31,19.92 53.64,19.59 54.28,19.59 56.28,17.59 59.93,17.59 61.06,16.46 61.34,16.46 v1(62,15.8)
  BOTTOM w0.089: KB1.16 90.6,11.89 89.71,11 79.24,11 78.58,11.66 78.26,11.66 77.3,12.62 77.27,12.62 77.23,12.66 69.48,12.66 69.39,12.75 64.62,12.75 62,15.37 v1(62,15.8) 62,16.12 61.25,16.87 AFTP6515.1 ; v1(51.33,21.69) 51.28,21.64 50.52,21.64 49.55,20.67 U2401.52
KCOL2: length 47.9
  TOP w0.089: v1(62.8,15.8) 61.86,16.74 61.05,16.74 60.01,17.79 56.44,17.79 54.21,20.02 53.49,20.02 53.34,20.17 52.47,20.17 52.04,20.59 52.04,21.54 v1(51.97,21.62)
  BOTTOM w0.089: KB1.17 89.81,13.09 89.81,12.43 88.57,11.19 79.32,11.19 78.65,11.86 78.33,11.86 77.39,12.81 77.35,12.81 77.31,12.85 69.56,12.85 69.47,12.94 64.72,12.94 63.39,14.27 AFTP6516.1 62.88,15.8 v1(62.8,15.8) ; v1(51.97,21.62) 51.61,21.26 50.85,21.26 49.95,20.36 U2401.51
KCOL3: length 48.3
  TOP w0.089: v1(51.26,20.83) 52.37,19.71 53.24,19.71 53.57,19.38 54.22,19.38 56.2,17.4 59.6,17.4 v1(61.2,15.8)
  BOTTOM w0.089: KB1.15 91.4,11.7 90.51,10.81 79.17,10.81 78.52,11.46 78.16,11.46 77.15,12.47 63.9,12.47 AFTP6514.1 62.92,14.08 v1(61.2,15.8) ; U2401.50 50.35,20.26 50.93,20.83 v1(51.26,20.83)
KCOL4: length 51.4
  BOTTOM w0.089: KB1.11 94.6,12.02 92.62,10.05 78.85,10.05 78.25,10.64 77.8,10.64 76.74,11.71 61.51,11.71 59.83,13.4 59.83,13.52 59.05,14.3 AFTP6510.1 58.58,17.02 55.83,17.02 55.18,17.68 53.29,17.68 53.04,17.93 52.49,17.93 51.93,18.49 51.19,18.49 50.75,18.93 U2401.49
KCOL5: length 62.4
  TOP w0.089: v1(57.19,15.8) 56.7,16.29 56.61,16.33 56.45,16.33 53.8,18.98 53.42,18.98 53.09,19.31 51.91,19.31 50.64,20.57 50.64,21.87 51.08,22.31 51.83,22.31 52.02,22.5 52.81,22.5 53.14,22.17 53.14,22.13 v1(53.98,21.29)
  BOTTOM w0.089: AFTP6509.1 57.19,16.48 v1(57.19,15.8) 57.61,15.8 58.86,14.55 58.86,14.22 59.63,13.44 59.63,13.32 61.44,11.52 74.89,11.52 77.43,8.98 91.94,8.98 95.4,12.45 KB1.10 ; v1(53.98,21.29) 53.94,21.32 53.63,21.32 53.47,21.48 53.11,21.48 53.07,21.45 52.42,21.45 51.84,20.86 51.84,20.81 51.15,20.12 U2401.48
KCOL6: length 57.6
  TOP w0.089: v1(60.35,15.82) 59.1,17.07 55.99,17.07 53.88,19.18 53.49,19.18 53.16,19.51 51.98,19.51 50.83,20.65 50.83,21.79 51.16,22.12 51.91,22.12 52.1,22.31 52.73,22.31 52.95,22.09 52.95,22.05 53.29,21.7 v1(53.29,21.06)
  BOTTOM w0.089: v1(53.29,21.06) 53.09,21.26 52.5,21.26 52.12,20.87 52.12,20.75 51.55,20.19 U2401.47 ; v1(60.35,15.82) 60.35,13.64 AFTP6512.1 61.9,12.09 76.99,12.09 78.03,11.05 78.38,11.05 79.01,10.43 92.17,10.43 93,11.25 KB1.13
KCOL7: length 48.4
  BOTTOM w0.089: U2401.43 53.15,18.93 53.54,18.54 53.62,18.54 53.67,18.49 54.86,18.49 56.12,17.23 58.87,17.23 59.65,16.45 59.65,15.64 AFTP6511.1 60.02,13.96 60.02,13.47 61.59,11.9 76.9,11.9 77.95,10.85 78.32,10.85 78.93,10.24 92.43,10.24 93.8,11.61 KB1.12
KCOL8: length 45.2
  BOTTOM w0.089: U2401.42 53.55,18.94 53.77,18.72 55.05,18.72 56.35,17.42 59.36,17.42 60.77,16 60.77,15.57 AFTP6513.1 61.54,14.33 63.59,12.28 77.07,12.28 78.1,11.25 78.45,11.25 79.09,10.62 91.31,10.62 92.2,11.51 KB1.14
KCOL9: length 37.3
  TOP w0.089: v1(56.81,21.82) 58.12,20.52 58.12,20.27 58.37,20.02 58.61,20.02 58.62,20.02 59.54,20.02 60.25,19.31 60.25,18.69 61.16,17.79 66.89,17.79 68.4,16.28 v1(68.4,15.8)
  BOTTOM w0.089: v1(56.81,21.82) 56.61,21.62 55.15,21.62 54.22,20.69 54.22,20.47 53.95,20.2 U2401.41 ; v1(68.4,15.8) 69.84,14.37 70.61,14.37 AFTP6523.1 71.7,14.29 71.99,14 77.82,14 77.85,13.98 80.09,13.98 80.63,13.44 80.63,12.71 81.01,12.33 83.63,12.33 84.2,12.9 KB1.24
KCOL10: length 34.9
  L3 w0.14: v1(81.74,14.66) 81.26,15.13 78.82,15.13 76.99,16.97 76.99,17.19 76.73,17.45 76.35,17.45 75.05,16.14 73.25,16.14 73.2,16.2 70.19,16.2 v1(70.03,16.05)
  BOTTOM w0.089: v1(70.03,16.05) 70.03,16.09 69.79,16.34 68.93,16.34 67.43,17.84 66.41,17.84 AFTP6525.1 64.93,18.87 63.41,18.87 62.43,19.85 58.55,19.85 57.05,21.35 55.19,21.35 54.53,20.69 54.53,20.45 54.35,20.27 U2401.40 ; KB1.26 82.6,13.79 v1(81.74,14.66)
KCOL11: length 34
  BOTTOM w0.089: KB1.25 83.4,13.01 82.92,12.52 81.61,12.52 81.43,12.71 81.43,13.44 81,13.87 80.55,13.87 80.26,14.17 77.93,14.17 77.9,14.19 72.22,14.19 71.75,14.67 70.85,14.67 AFTP6524.1 69.18,15.82 67.46,17.54 66.25,17.54 65.17,18.62 63.39,18.62 62.42,19.59 58.46,19.59 56.9,21.16 55.49,21.16 54.75,20.42 U2401.39
KCOL12: length 40.5
  BOTTOM w0.089: U2401.38 55.15,18.93 56.36,17.72 62.88,17.72 62.94,17.77 63.23,17.77 63.29,17.72 64.15,17.72 AFTP6518.1 64.46,16.26 64.46,13.74 64.88,13.32 69.63,13.32 69.72,13.23 77.47,13.23 77.5,13.2 77.56,13.2 78.49,12.27 78.79,12.27 79.49,11.57 87.49,11.57 88.2,12.28 KB1.19
KCOL13: length 36.1
  TOP w0.089: v1(55.73,20.63) 57,19.36 59,19.36 61.06,17.3 66,17.3 66.8,16.5 v1(66.8,15.8)
  BOTTOM w0.089: v1(55.73,20.63) 55.55,20.45 U2401.37 ; KB1.22 85.8,12.9 85.04,12.14 80.4,12.14 79.83,12.71 79.83,13.44 79.49,13.77 77.79,13.77 77.75,13.8 70.68,13.8 70.38,14.1 68.47,14.1 AFTP6521.1 66.8,15.76 v1(66.8,15.8)
KCOL14: length 37.4
  TOP w0.089: v1(56.41,20.73) 57.32,19.81 58.84,19.81 61.07,17.58 66.25,17.58 67.6,16.23 v1(67.6,15.8)
  L3 w0.14: v1(67.6,15.8) 68.24,16.44 69.79,16.44 69.85,16.5 70.54,16.5 70.59,16.44 73.3,16.44 73.35,16.39 74.95,16.39 76.25,17.69 76.83,17.69 77.23,17.29 77.23,17.07 78.92,15.38 83.79,15.38 85.17,14 v1(85.17,14)
  BOTTOM w0.089: v1(67.6,15.8) 66.95,16.45 AFTP6522.1 ; KB1.23 85,13.83 v1(85.17,14) ; U2401.36 55.95,20.24 56.41,20.7 v1(56.41,20.73)
KCOL15: length 36.1
  BOTTOM w0.089: U2401.35 56.35,20.13 56.55,20.33 56.57,20.33 56.58,20.34 57.33,20.34 58.27,19.4 62.31,19.4 63.29,18.42 65.07,18.42 66,17.49 AFTP6520.1 67.55,13.86 70.35,13.86 70.6,13.61 77.67,13.61 77.71,13.58 77.74,13.58 78.64,12.68 79.02,12.68 79.75,11.95 85.53,11.95 86.6,13.02 KB1.21
KCOL16: length 37.7
  BOTTOM w0.089: U2401.34 56.75,18.47 57.24,17.98 64.39,17.98 65.39,16.98 65.39,14.46 AFTP6527.1 65.18,13.51 69.71,13.51 69.8,13.42 77.59,13.42 77.63,13.39 77.65,13.39 78.56,12.47 78.92,12.47 79.63,11.76 86.14,11.76 87.4,13.02 KB1.20
KROW0: length 58.2
  TOP w0.089: v1(50.5,22.35) 50.45,22.31 50.45,20.5 51.84,19.1 53.01,19.1 53.34,18.77 53.73,18.77 55.17,17.34 55.17,17.03 v1(56.4,15.8)
  BOTTOM w0.089: KB1.9 96.2,12.95 92.04,8.79 77.35,8.79 74.81,11.33 61.36,11.33 59.44,13.24 59.44,13.33 AFTP6508.1 57.56,15.32 56.89,15.32 v1(56.4,15.8) ; U2401.54 48.75,20.69 50.42,22.35 v1(50.5,22.35)
KROW1: length 58.6
  BOTTOM w0.089: KB1.7 97.8,11.13 95.08,8.41 77.19,8.41 74.66,10.94 60.33,10.94 AFTP6506.1 59.12,11.69 57.89,12.93 57.89,13.44 55.95,15.38 55.42,15.38 55.17,15.62 55.17,15.98 55.18,15.99 55.18,16.66 54.36,17.48 53.16,17.48 52.96,17.68 52.44,17.68 52.02,18.09 48.97,18.09 48.35,18.71 U2401.55
KROW2: length 60.2
  BOTTOM w0.089: U2401.56 47.95,18.81 48.88,17.88 51.93,17.88 52.33,17.48 52.56,17.48 53.42,16.61 53.42,15.62 53.89,15.16 54.72,15.16 55.25,14.62 AFTP6504.1 57.51,13.06 57.51,12.77 59.71,10.56 74.5,10.56 77.03,8.03 95.61,8.03 99.4,11.82 KB1.5
KROW3: length 57.8
  L4 w0.14: v1(51.32,17.32) 52.34,16.31 55.09,16.31 v1(55.6,15.8)
  BOTTOM w0.089: v1(51.32,17.32) 50.99,17.66 48.79,17.66 47.55,18.9 U2401.57 ; KB1.8 97,10.69 94.91,8.6 77.27,8.6 74.74,11.14 61.22,11.14 59.28,13.07 AFTP6507.1 58.24,13.42 56.28,15.38 56.22,15.38 55.8,15.8 v1(55.6,15.8)
KROW4: length 61.4
  BOTTOM w0.089: U2401.58 47.15,18.94 48.62,17.47 50.32,17.47 51.16,16.63 AFTP6503.1 52.91,15.86 53.84,14.94 54.67,14.94 59.23,10.37 74.41,10.37 76.95,7.84 95.77,7.84 100.2,12.26 KB1.4
KROW5: length 62.1
  L4 w0.14: v1(53.85,15.8) 53.37,15.32 49.65,15.32 48.86,16.11 v1(48.86,17.04)
  BOTTOM w0.089: U2401.59 46.75,18.94 48.65,17.04 v1(48.86,17.04) ; v1(53.85,15.8) 54.56,16.51 AFTP6505.1 54.83,15.69 55.34,15.18 55.88,15.18 57.7,13.36 57.7,12.85 59.79,10.75 74.58,10.75 77.11,8.22 95.25,8.22 98.6,11.57 KB1.6
KROW6: length 62.6
  BOTTOM w0.089: KB1.3 101,12.7 95.94,7.65 76.87,7.65 74.33,10.18 58.93,10.18 AFTP6502.1 56.36,12.89 54.52,14.73 52.64,14.73 50.67,16.71 49.13,16.71 49.04,16.61 48.7,16.61 48.68,16.64 48.66,16.64 46.35,18.95 U2401.60
KROW7: length 63.8
  BOTTOM w0.089: KB1.2 101.8,13.02 96.24,7.46 76.77,7.46 74.24,9.99 58.62,9.99 54.84,13.77 54.84,14.14 54.45,14.53 52.23,14.53 AFTP6501.1 50.96,15.8 49.21,15.8 48.8,16.21 48.8,16.24 48.6,16.45 48.46,16.45 45.95,18.96 U2401.61
L_BKLT_CTRL: length 8.6
  TOP w0.102: R5524.2 58.83,78.72 v1(59.03,78.92)
  BOTTOM w0.102: D5502.1 57.24,79.7 57.68,79.25 57.68,78.92 58.09,78.51 58.6,78.51 58.83,78.74 58.83,78.79 58.95,78.92 v1(59.03,78.92) 58.95,78.84 v2(58.95,78.25) 58.95,78.09 58.85,77.99 57.99,77.99 57.89,77.89 Q5503.C 57.89,77.34 58.14,77.09 59.97,77.09 R5527.2
L_BKLT_CTRL_B: length 2.2
  BOTTOM w0.102: Q5503.B 59.05,75.47 R5526.2 v2(59.99,74.55)
L_BKLT_CTRL_CPU: length 96.5
  TOP w0.102: v1(85.34,78.41) 85.65,78.72 85.65,79.27 85.65,79.27 85.65,80.52 84.91,81.26 83.36,81.26 81.7,82.91 73.56,82.91 71.17,80.52 71.17,77.37 71.81,76.74 71.81,74.96 71.08,74.23 70.35,74.23 70.33,74.25 69.88,74.25 69.86,74.23 64.78,74.23 64.21,74.8 63.5,74.8 v2(62.65,75.65) 61.64,76.66 58.06,76.66 v1(57.4,76)
  L3 w0.127: v1(81.84,64.59) 82.25,65 82.25,68.34 82.4,68.49 82.4,71.48 83.41,72.49 83.41,72.49 83.8,72.88 83.8,73.92 85.81,75.94 85.81,77.64 85.34,78.11 v1(85.34,78.41)
  L4 w0.127: v1(81.84,64.59) 81.69,64.44 81.69,63.32 83.34,61.67 84.86,61.67 86,60.53 86,55.88 84.56,54.43 84.56,53.11 84.67,53 84.67,50.89 85.36,50.2 85.36,48.46 85.42,48.4 85.42,47.4 85.01,46.99 85,46.99 84.7,46.69 84.7,46.34 85.02,46.02 85.19,46.02 85.43,45.77 85.43,45.14 86,44.57 86,42.75 84.99,41.73 84.99,40.41 85.01,40.39 85.01,39.88 84.63,39.5 84.63,38.97 84.36,38.7 84.35,38.7 84.01,38.36 84.01,38.34 84,38.33 84,37.85 83.01,36.86 83.01,36.83 82.56,36.39 81.09,36.39 80.36,37.12 v1(80.36,37.16)
  BOTTOM w0.102: Q5503.E 56.94,75.53 v1(57.4,76) ; CPU1.A24 81.05,38 80.72,37.67 80.72,37.53 v1(80.36,37.16)
LCD_BRIGHTNESS: length 5.8
  TOP w0.102: RN5503.2 58.32,80.55 58.32,81.01 58.44,81.13 58.44,82.46 EC5507.1 57.96,83.31 v1(58.17,83.52)
  BOTTOM w0.102: v2(57.87,83.04) 58.17,83.33 v1(58.17,83.52) 58.6,83.95 LCD1.26
LCD_TST: length 106.7
  TOP w0.102: RN5504.3 56.75,79.07 56.65,78.97 56.62,78.97 v1(56.59,78.94) ; v1(56.8,38.01) 56.8,38.03 56.67,38.16 56.67,38.76 55.5,39.93 v2(54.37,39.93) 52.81,39.93 51.24,38.36 46.28,38.36 45.91,38.74 44.63,38.74 44.25,39.12 41.07,39.12 40.21,38.25 36.17,38.25 34.77,36.86 v1(34.77,35.84)
  L3 w0.102: v1(56.59,78.94) 56.59,78.84 55.98,78.23 52.7,78.23 51.66,77.19 51.64,77.19 50.34,75.9 50.34,74.5 50.29,74.45 50.29,74.42 46.35,70.49 34.26,70.49 33.32,69.55 32.51,69.55 32.31,69.34 29.72,69.34 29.46,69.09 29.44,69.09 29.08,68.73 29.08,68.71 29.06,68.68 29.06,65.94 27.25,64.14 27.25,59.64 27.08,59.46 27.08,58.09 27.52,57.65 27.52,55.28 28,54.8 28,53.69 26.9,52.58 26.9,51.18 25.4,49.68 25.4,48.57 25.2,48.36 25.2,46.35 25.1,46.25 25.1,45.65 26.26,44.48 26.26,41.65 27.2,40.71 27.2,39.75 27.43,39.52 30.02,39.52 31.75,37.8 31.78,37.8 32,37.57 32,36.59 32.52,36.07 34.54,36.07 v1(34.77,35.84)
  L4 w0.102: v1(56.8,38.01) 56.81,38.03 56.81,38.12 57.18,38.48 59.03,38.48 v1(59.77,37.75)
  BOTTOM w0.102: R2413.1 59.36,36.73 59.77,37.14 v1(59.77,37.75)
LCD_TST_C: length 5.1
  TOP w0.102: v1(57.18,84.1) 56.74,83.67 56.74,83.48 56.46,83.21 56.46,81.21 56.75,80.92 RN5504.2
  BOTTOM w0.102: LCD1.23 57.1,84.18 v1(57.18,84.1)
LCD_TST_EN: length 156.6
  TOP w0.102: v1(70.46,76.53) 70.18,76.81 70.18,79.85 73.51,83.19 81.75,83.19 81.77,83.16 81.79,83.16 83.44,81.51 85.34,81.51 86.59,80.27 93.32,80.27 v2(93.65,80.6) 93.95,80.9 v1(94.69,80.9)
  L3 w0.102: v1(106.43,16.58) 106.39,16.61 101.85,16.61 101.73,16.5 93.45,16.5 91.1,18.85 83.97,18.85 81.21,21.62 78.05,21.62 77.86,21.81 76.69,21.81 76.69,21.81 76.33,21.81 75.91,22.23 68.56,22.23 67.85,21.52 65.14,21.52 64.72,21.1 63.96,21.1 63.73,21.33 60.05,21.33 59.74,21.64 v1(59.74,22.25)
  BOTTOM w0.102: R5503.1 66.62,76.28 69.41,76.28 D5501.2 69.87,75.94 v1(70.46,76.53) ; v1(59.74,22.25) 59.72,22.28 59.72,22.35 59.51,22.55 U2401.28 ; v1(106.43,16.58) 106.43,16.6 106.32,16.7 106.32,17.02 103.75,19.59 103.75,71.05 94.77,80.04 94.77,80.19 94.72,80.24 94.72,80.65 94.77,80.7 94.77,80.82 v1(94.69,80.9)
LCD_TST_KBC: length 4.1
  BOTTOM w0.102: R2413.2 58.26,36.04 v2(57.34,36.04) 55.83,36.04 55.55,35.76 U2401.124
LDO1_CAP: length 4.5
  TOP w0.203: 143.03,92.76 143.03,92.38 143.23,92.18 HDA27.21
  TOP w0.305: R2702.1 141.22,94.54 141.3,94.46 C2703.1 142.1,94.46 143.03,93.54 v2(143.03,93.46) 143.03,92.76
LDO2_CAP: length 4.7
  TOP w0.203: HDA27.32 144.52,87.53 144.27,87.27 144.27,87.2 143.67,86.61
  TOP w0.305: 143.67,86.61 143.67,86 v2(143.58,85.91) 143.07,85.4 142.27,85.4 141.99,85.12 C2711.1
LDO3_CAP: length 2.7
  TOP w0.203: v1(149.38,90.45) 149.25,90.57 HDA27.6
  BOTTOM w0.305: C2722.1 148.82,91.04 149.38,90.48 v1(149.38,90.45) v2(149.77,90.85)
LID_CLOSE#: length 75.7
  TOP w0.102: LIDSW1.3 6.15,42.41 6.15,45.04 6.76,45.65 8.94,45.65 9.63,44.96 9.63,43.99 R6701.1 9.17,42.85 C6701.1 9.27,42.44 v2(8.66,41.83) 8.34,41.51 7.44,41.51 6.12,40.19 6.12,36.98 8.43,34.67 14.17,34.67 15.21,33.63 15.21,33.05 15.49,32.77 15.49,32.21 15.01,31.73 15.01,30.94 v1(15.39,30.56)
  L3 w0.102: v1(35.23,35.38) 35.69,35.84 36.58,35.84 36.96,35.46 40.84,35.46 41.38,36.01 43.14,36.01 43.62,35.52 45.76,35.52 46.63,34.65 46.81,34.65 46.82,34.63 47.38,34.63 v1(48.54,33.48)
  BOTTOM w0.102: v1(15.39,30.56) 16.45,30.56 21.11,35.22 22.32,35.22 23.42,34.12 30.3,34.12 30.68,34.49 33.4,34.49 34.06,33.83 R2474.2 35.43,34.42 35.43,35.18 v1(35.23,35.38) ; U2401.107 48.75,33.92 48.54,33.71 v1(48.54,33.48)
LINE1-L_C: length 13.1
  TOP w0.254: v1(140.41,87.94) 140.44,87.96 R2922.1 ; C2907.2 v1(142.57,98.11) v2(142.97,98.5)
  L4 w0.254: v1(142.57,98.11) 142.57,96.95 141.86,96.24 141.86,96.22 141.63,95.99 141.63,89.08 140.49,87.94 v1(140.41,87.94)
LINE1-L_R: length 17.4
  TOP w0.254: R2921.1 139.85,84.76 v1(140.03,84.58) ; C2908.2 143.89,97.92 143.9,97.93 v1(143.9,98.11) 144.34,98.11 v2(144.6,98.37)
  L4 w0.254: v1(143.9,98.11) 143.9,97.85 143.78,97.73 143.78,97.43 143.08,96.73 143.08,96.72 142.37,96.01 142.37,95.99 142.14,95.76 142.14,87.58 140.03,85.47 v1(140.03,84.58)
LINE1_L: length 4.2
  TOP w0.203: HDA27.18 144.92,93.43
  TOP w0.254: 144.92,93.43 144.32,94.03 144.22,94.03 v2(143.79,94.46) 142.57,95.68 C2907.1
LINE1_R: length 3.7
  TOP w0.203: HDA27.17 145.32,93.44
  TOP w0.254: C2908.1 143.89,95.08 145.02,93.95 v2(145.02,93.95) 145.31,93.65 145.31,93.45 145.32,93.44
LINE1_VREFO: length 2.4
  TOP w0.203: D2901.3 141.73,91.47 142.22,90.97 142.39,90.97 v2(142.4,90.98) 142.4,90.97 HDA27.24
LINE1_VREFO_D1: length 5.5
  TOP w0.254: D2901.2 140,90.73 139.85,90.58 v1(139.85,90.37) ; v1(140.44,87.23) 140.28,87.23 R2912.1
  L3 w0.254: v1(140.44,87.23) 140.39,87.23 139.78,87.83 139.78,90.3 v1(139.85,90.37)
LINE1_VREFO_D2: length 2.9
  TOP w0.254: R2928.1 140.51,90.68 140.97,91.14 140.97,91.69 D2901.1
LPC_AD_CPU_P0: length 153.5
  TOP w0.089: RN6801.2 55.04,27.54 54.68,27.18 54.68,26.38 v2(54.84,26.22) 54.98,26.09 55.13,26.09 55.81,25.4 55.81,25.15 56.06,24.9 56.06,23.76 55.9,23.6 55.9,23.57 55.65,23.33 55.63,23.33 55.4,23.1 v1(55.4,23.01)
  L4 w0.14: v1(55.4,23.01) 55.28,22.89 55.28,20.44 56.86,18.85 60.95,18.85 61.79,18.01 68.69,18.01 69.23,18.55 72.06,18.55 73.66,20.14 75.09,20.14 75.87,20.93 77.11,20.93 77.77,21.59 78.44,21.59 78.68,21.84 84.52,21.84 86.92,19.43 87.58,19.43 88.24,18.77 89.41,18.77 91.43,16.75 100.24,16.75 101.47,17.98 101.47,18.37 102.05,18.94 103.69,18.94 v1(103.76,18.87) ; v1(94.36,79.77) 94.36,79.73 93.32,78.69 87.7,78.69 85.37,76.36 v1(85.37,76.15)
  BOTTOM w0.089: v1(85.37,76.15) 85.37,76.15 RN1605.1 ; v1(103.76,18.87) 103.39,19.24 103.39,70.74 v1(94.36,79.77) ; U2401.126 56.35,33.14 53.36,30.15 53.36,26.23 53.06,25.92 53.06,25.33 54.15,24.24 54.15,24.07 54.46,23.75 54.46,23.3 54.74,23.01 v1(55.4,23.01)
LPC_AD_CPU_P1: length 153.6
  TOP w0.089: v1(95.15,80.44) v2(95.71,80.44) ; v1(55.47,23.75) 55.85,24.13 55.85,24.81 55.59,25.06 55.59,25.32 55.04,25.87 54.09,25.87 53.92,26.04 53.92,26.78 54.39,27.25 RN6801.1
  L4 w0.14: v1(95.15,80.44) 95.15,79.92 93.46,78.23 87.88,78.23 v1(86.82,77.17) ; v1(104.96,19.97) 104.85,19.85 101.59,19.85 100.48,18.75 99.44,18.75 98.64,17.95 96.43,17.95 95.78,18.59 91.11,18.59 89.87,19.84 88.62,19.84 88.02,20.44 87.18,20.44 84.8,22.81 78.87,22.81 78.73,22.94 77.8,22.94 77.55,22.69 76.31,22.69 75.18,21.57 73.78,21.57 72.4,20.18 68.4,20.18 67.92,19.69 63.84,19.69 63.76,19.77 59.58,19.77 59,20.35 59,21.46 58.61,21.85 58.61,21.97 57.83,22.75 57.39,22.75 57.02,23.11 57.02,23.24 56.57,23.69 56.55,23.69 56.49,23.75 v1(55.47,23.75)
  BOTTOM w0.089: U2401.127 56.75,33.18 53.57,30.01 53.57,26.14 53.27,25.83 53.27,25.42 54.36,24.33 54.36,24.16 54.61,23.91 55.31,23.91 v1(55.47,23.75) ; v1(86.82,77.17) 86.82,76.43 86.02,75.64 RN1605.2 ; v1(95.15,80.44) 96.26,80.44 104.52,72.18 104.52,20.74 104.96,20.3 v1(104.96,19.97)
LPC_AD_CPU_P2: length 157.7
  TOP w0.089: RN6803.2 53.64,29.03 53.64,25.76 53.7,25.71 53.7,25.62 v1(53.7,25.62)
  L4 w0.14: v1(103.89,18.24) 103.68,18.04 103.17,18.04 100.8,15.66 91.3,15.66 89.05,17.91 87.91,17.91 87.25,18.57 86.54,18.57 84.07,21.04 79.03,21.04 78.74,20.75 78.48,20.75 77.85,20.12 76.2,20.12 75.08,19.01 74.23,19.01 72.35,17.13 69.84,17.13 69.82,17.11 69.01,17.11 68.99,17.13 56.47,17.13 56.16,17.45 54.48,19.13 54.48,21.42 53.14,22.76 53.14,23.66 53.56,24.07 53.57,24.07 53.83,24.33 53.83,24.7 53.64,24.89 53.64,25.56 v1(53.7,25.62) ; v1(94.23,80.44) 93.65,80.44 92.7,79.49 89.2,79.49 89.2,79.49 89.19,79.49 88.08,79.49 88.08,79.49 87.69,79.49 85.7,77.5 85.22,77.5 v1(84.38,76.66)
  BOTTOM w0.089: U2401.128 57.15,33.28 53.79,29.92 53.79,25.79 53.7,25.7 v1(53.7,25.62) ; v1(94.23,80.44) 93.83,80.44 93.27,79.88 93.27,79.35 v2(94.39,78.23) 102.47,70.15 102.47,18.89 102.74,18.62 102.74,18.12 102.88,17.98 103.63,17.98 v1(103.89,18.24) ; v1(84.38,76.66) 84.45,76.59 RN1606.2
LPC_AD_CPU_P3: length 153.2
  TOP w0.089: v1(54.15,25.17) 53.55,25.17 53.27,25.44 53.27,26.72 v2(53.3,26.74) 53.3,28.29 52.84,28.75 RN6803.1
  L4 w0.14: v1(84.02,76.13) 84.5,76.13 85.59,77.22 85.83,77.22 87.78,79.17 93.17,79.17 v1(93.7,79.71) ; v1(103.25,18.49) 100.69,15.93 91.42,15.93 89.13,18.21 88.01,18.21 87.38,18.85 86.66,18.85 84.21,21.31 78.91,21.31 78.64,21.03 78.11,21.03 77.46,20.39 76.35,20.39 76.09,20.39 74.97,19.27 74.11,19.27 73.88,19.04 72.24,17.4 69.73,17.4 69.71,17.38 69.12,17.38 69.1,17.4 56.59,17.4 54.74,19.24 54.74,22.5 54.4,22.84 54.4,23.22 54.12,23.5 54.12,25.07 54.15,25.09 v1(54.15,25.17)
  BOTTOM w0.089: v1(103.25,18.49) 102.9,18.84 102.9,70.51 v1(93.7,79.71) ; RN1606.1 83.8,75.9 v1(84.02,76.13) ; U2401.1 57.56,33.35 54.22,30.01 54.21,30.01 54.01,29.8 54.01,25.94 54.22,25.73 54.22,25.27 54.17,25.22 54.17,25.19 v1(54.15,25.17)
LPC_CLK_CPU_P0: length 160
  L4 w0.14: v1(54.79,24.33) 54.83,24.33 54.97,24.48 54.97,24.57 55.24,24.84 55.33,24.84 55.34,24.84 56.42,24.84 56.85,25.27 59.36,25.27 59.55,25.08 59.93,25.08 60.12,25.27 62.54,25.27 63.83,23.99 63.89,23.92 64.76,23.92 66.15,22.53 67.2,22.53 67.71,23.05 71.94,23.05 72.75,23.85 74.14,23.85 76.81,26.52 78.61,26.52 78.82,26.32 80.9,26.32 81.74,25.47 84.36,25.47 84.99,24.84 85.25,24.84 87.76,22.33 93.47,22.33 94.79,21 95.59,21 96.26,20.33 96.26,19.8 96.58,19.48 96.85,19.2 97.1,18.96 98.25,18.96 99.05,19.76 100.1,19.76 101.4,21.06 103.63,21.06 103.81,21.24 104.56,21.24 104.89,20.91 104.94,20.91 104.99,20.86 105.41,20.86 105.8,21.25 105.93,21.25 v1(106.05,21.36) ; v1(99.19,82.25) 98.7,81.76 98.64,81.76 98.18,81.3 98.18,81.1 97.24,80.16 96.5,80.16 93.65,77.32 90.88,77.32 89.71,76.15 86.86,76.15 85.61,74.91 83.87,74.91 v1(83.11,74.14)
  BOTTOM w0.089: v1(106.05,21.36) 106.05,21.79 105.45,22.39 105.45,74.38 99.14,80.69 99.14,82.2 v1(99.19,82.25) ; v1(83.11,74.14) 82.47,74.14 v2(82.42,74.09) 82.42,72.77 R2004.2 82.6,72.59 R2010.1 82.6,71.2 C1603.1 82.47,71.02 EC1601.1 82.5,70.21 R1611.1 ; U2401.2 57.66,32.95 54.36,29.66 54.36,26.09 54.57,25.88 54.57,25.12 54.79,24.91 v1(54.79,24.33)
LPC_CLK_CPU_P1: length 167.3
  TOP w0.089: v1(56.38,23.24) 56.25,23.24 55.6,22.59 55.07,22.59 54.54,23.12 54.41,23.12 53.78,23.74 53.42,23.74 53.35,23.67 52.63,23.67 51.95,24.35 51.95,24.43 51.4,24.98 51.4,25.53 51.21,25.73 51.21,27.22 49.53,28.9 49.53,31.35 48.71,32.17 46.61,32.17 v2(46.37,32.42) 45.87,32.91 FC1601.1 45.19,34.02 DB1.2
  L4 w0.14: v1(56.38,23.24) 56.38,23.13 57.2,22.31 57.64,22.31 58.1,21.85 58.1,20.26 59.03,19.32 63.58,19.32 63.8,19.11 71.99,19.11 73.54,20.65 74.96,20.65 75.69,21.39 76.91,21.39 78.03,22.5 78.54,22.5 78.69,22.35 84.63,22.35 87.07,19.92 87.91,19.92 88.44,19.38 89.69,19.38 90.94,18.14 95.61,18.14 96.25,17.49 99.68,17.49 100.38,18.19 100.63,18.19 101.84,19.39 105.21,19.39 v1(106.17,20.35) ; v1(81.64,67.06) 81.64,68.45 82.22,69.04 82.22,70.54 83.06,71.38 83.06,72.06 83.72,72.72 83.72,73.05 85.11,74.45 85.93,74.45 87.19,75.71 89.9,75.71 91.06,76.86 93.82,76.86 96.67,79.71 97.42,79.71 98.63,80.92 98.63,81.02 98.72,81.11 v1(98.72,81.16)
  BOTTOM w0.089: R1612.1 v1(81.64,67.06) ; v1(98.72,81.16) 98.72,81.11 98.63,81.02 98.63,80.7 105.1,74.23 105.1,22.23 105.62,21.71 105.62,20.47 105.89,20.2 106.01,20.2 v1(106.17,20.35)
LPC_CLKRUN#_CPU: length 154
  TOP w0.089: R2475.2 57.02,25 56.84,24.82 v1(56.84,24.63) ; v1(99.57,81.71) v2(99.57,81.1)
  L4 w0.14: v1(106.49,20.9) 106.38,20.8 105.98,20.8 105.6,20.42 104.75,20.42 104.37,20.8 104,20.8 103.81,20.61 101.59,20.61 100.28,19.31 99.23,19.31 98.43,18.52 96.88,18.52 96.24,19.15 91.31,19.15 90.07,20.4 88.83,20.4 88.24,20.98 87.39,20.98 84.9,23.47 79.25,23.47 78.7,24.02 76.7,24.02 74.8,22.13 73.41,22.13 72.14,20.86 65.22,20.86 64.57,21.52 61.83,21.52 58.72,24.63 v1(56.84,24.63) ; v1(83.9,68.02) 83.9,68.78 85.5,70.39 85.5,71.03 89.27,74.8 90.27,74.8 91.41,75.95 94.28,75.95 99.57,81.23 v1(99.57,81.71)
  BOTTOM w0.089: v1(83.9,68.02) 84.43,67.49 R1630.1 ; v1(99.57,81.71) 105.81,75.47 105.81,22.65 106.47,21.99 106.47,20.93 106.49,20.92 v1(106.49,20.9) ; v1(56.84,24.63) 56.33,24.63 55.65,25.31 55.65,25.96 55.2,26.41 55.2,28.41 56.23,29.43 56.23,30.12 56.66,30.55 U2401.8
LPC_FRAME#_CPU: length 162.3
  TOP w0.089: v1(55,25.31) 54.43,24.74 53.67,24.74 52.69,25.71 52.69,27.45 51.59,28.55 R6801.1 ; v2(97.79,81.18) 97.32,80.72 96.84,80.72 96.8,80.67 v1(96.66,80.67)
  L4 w0.14: v1(96.66,80.67) 96.61,80.61 96.31,80.61 96.24,80.54 96.23,80.54 93.47,77.78 90.7,77.78 89.59,76.66 86.73,76.66 85.6,75.53 83.02,75.53 81.71,74.22 81.71,72.49 v1(81.18,71.96) ; v1(55,25.31) 55.58,25.31 56.05,25.78 56.42,25.78 56.48,25.72 59.27,25.72 59.53,25.98 59.98,25.98 60.24,25.72 62.73,25.72 64.01,24.43 64.07,24.37 64.95,24.37 65.81,23.52 67.26,23.52 68.05,24.31 73.51,24.31 76.17,26.98 78.79,26.98 78.99,26.78 81.06,26.78 81.86,25.98 84.19,25.98 85.09,25.08 85.36,25.08 87.66,22.79 93.64,22.79 94.98,21.45 95.77,21.45 96.96,20.26 96.96,19.73 97.22,19.46 98.13,19.46 98.88,20.22 99.92,20.22 101.21,21.5 103.45,21.5 103.63,21.69 104.81,21.69 v1(105.18,21.31)
  BOTTOM w0.089: R1618.1 81.71,70.18 R2012.1 R2006.2 81.76,71.38 v1(81.18,71.96) ; v1(96.66,80.67) 96.8,80.67 96.92,80.79 97.52,80.79 104.74,73.57 104.74,21.75 v1(105.18,21.31) ; U2401.3 57.76,32.55 54.72,29.51 54.72,26.23 54.93,26.02 54.93,25.38 v1(55,25.31)
LPC_FRAME#_DEBUG: length 6.5
  TOP w0.089: R6801.2 51.59,30.38 51.38,30.59 50.93,30.59 v2(50.51,31) 50.51,31.24 48.71,33.05 48.37,33.05 48.11,33.3 48.11,33.69 48.19,33.77 DB1.5
LPC_LAD0_R: length 8.1
  TOP w0.089: DB1.9 52.19,34.11 51.72,33.63 51.72,33.27 52.02,32.97 52.02,31.62 52.19,31.45 53.21,31.45 54.67,29.99 v2(54.67,29.8) 55.04,29.43 RN6801.3
LPC_LAD1_R: length 7.9
  TOP w0.089: DB1.8 51.19,33.49 51.1,33.4 51.1,32.49 v2(51.36,32.23) 51.36,31.98 52.1,31.23 53.08,31.23 53.84,30.48 53.84,29.99 54.39,29.44 RN6801.4
LPC_LAD2_R: length 6.6
  TOP w0.089: DB1.7 50.19,32.78 50.6,32.37 50.6,32.18 51.76,31.01 v2(51.83,31.01) 52.89,31.01 53.49,30.42 RN6803.3
LPC_LAD3_R: length 6.7
  TOP w0.089: RN6803.4 52.84,30.43 52.6,30.66 51.63,30.66 v2(50.09,32.2) 49.86,32.43 49.86,33.63 49.61,33.89 49.5,33.89 49.19,34.2 DB1.6
LPC_RST#: length 150.5
  TOP w0.089: R6802.1 50.8,28.91 52.11,27.6 v2(52.11,27.01) 52.11,26 53.77,24.33 54.03,24.33 54.45,23.91 54.96,23.91 55.42,24.37 v1(55.42,24.39)
  L4 w0.14: v1(96.85,79.25) 94.01,76.4 91.24,76.4 90.09,75.26 87.73,75.26 85.17,72.7 v1(85.17,72.57) ; v1(55.42,24.39) 56.24,24.39 56.67,23.95 59.02,23.95 61.74,21.24 64.47,21.24 65.11,20.59 72.43,20.59 73.69,21.85 75.06,21.85 76.17,22.96 77.44,22.96 77.83,23.34 78.99,23.34 79.15,23.19 84.8,23.19 87.29,20.7 88.14,20.7 88.72,20.12 89.96,20.12 91.21,18.87 95.96,18.87 96.62,18.21 98.53,18.21 99.34,19.03 100.38,19.03 101.7,20.35 v1(104.19,20.35)
  BOTTOM w0.089: R1629.1 84.81,71.05 85.19,71.43 C804.1 85.22,71.76 85.22,72.52 v1(85.17,72.57) ; v1(96.85,79.25) 104.19,71.91 v1(104.19,20.35) ; v1(55.42,24.39) 55.42,25.49 55.14,25.77 55.14,26.11 54.93,26.32 54.93,29.42 56.47,30.95 U2401.7
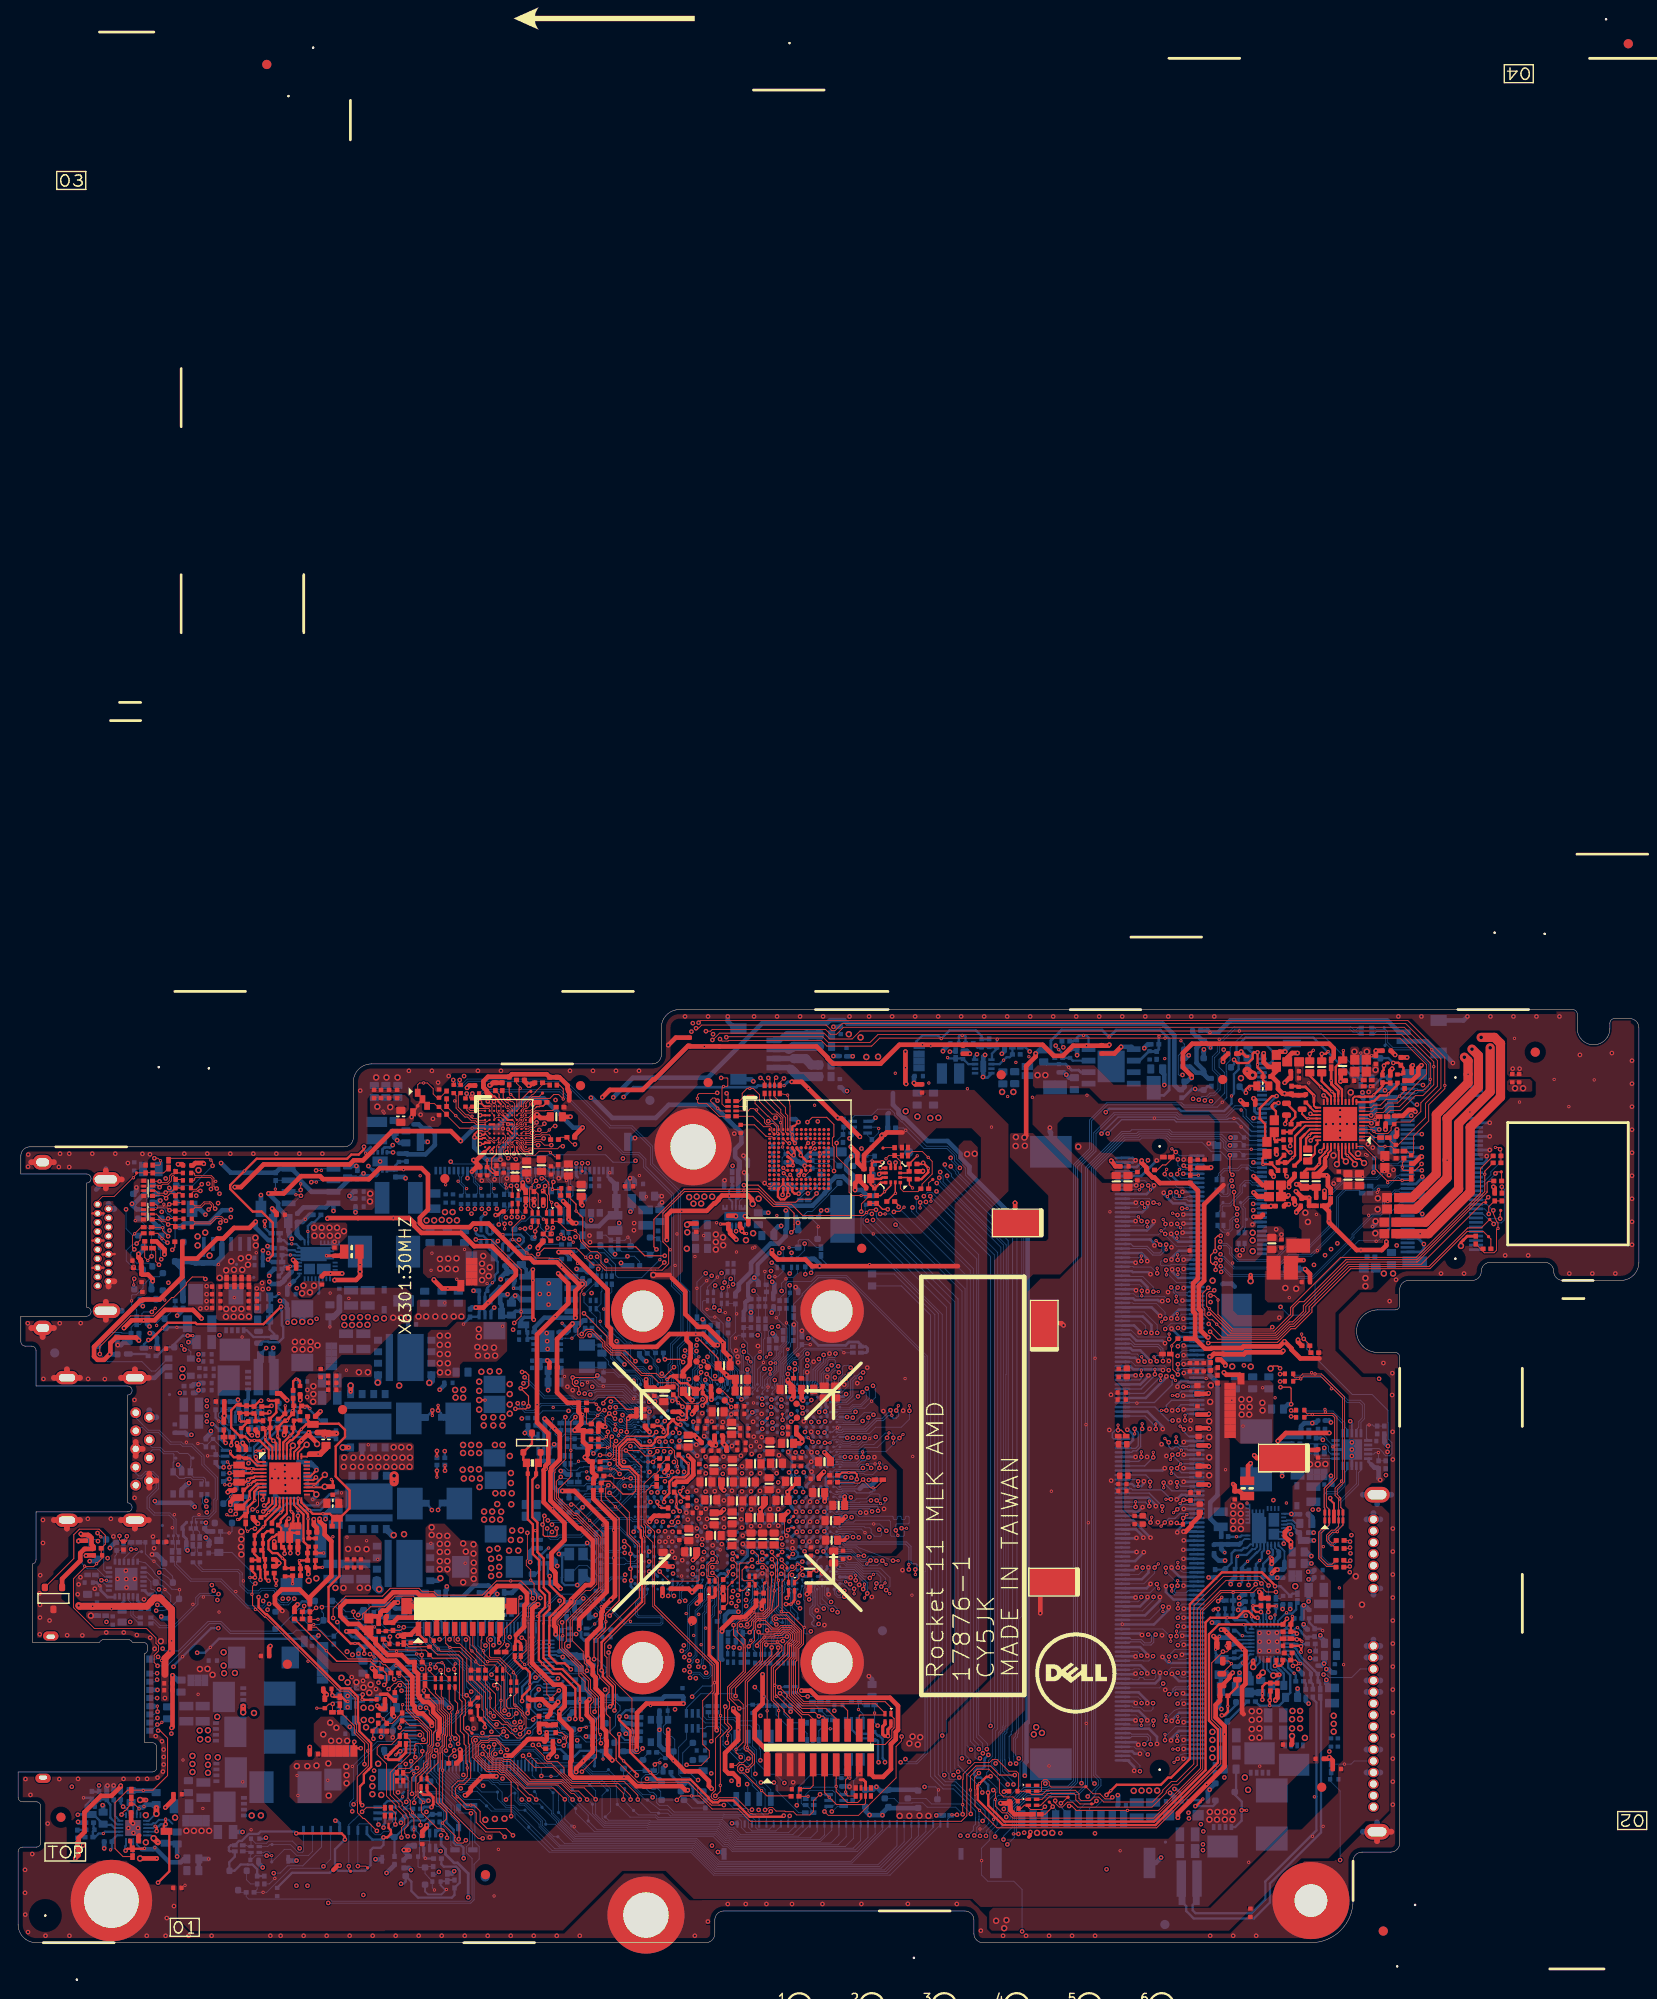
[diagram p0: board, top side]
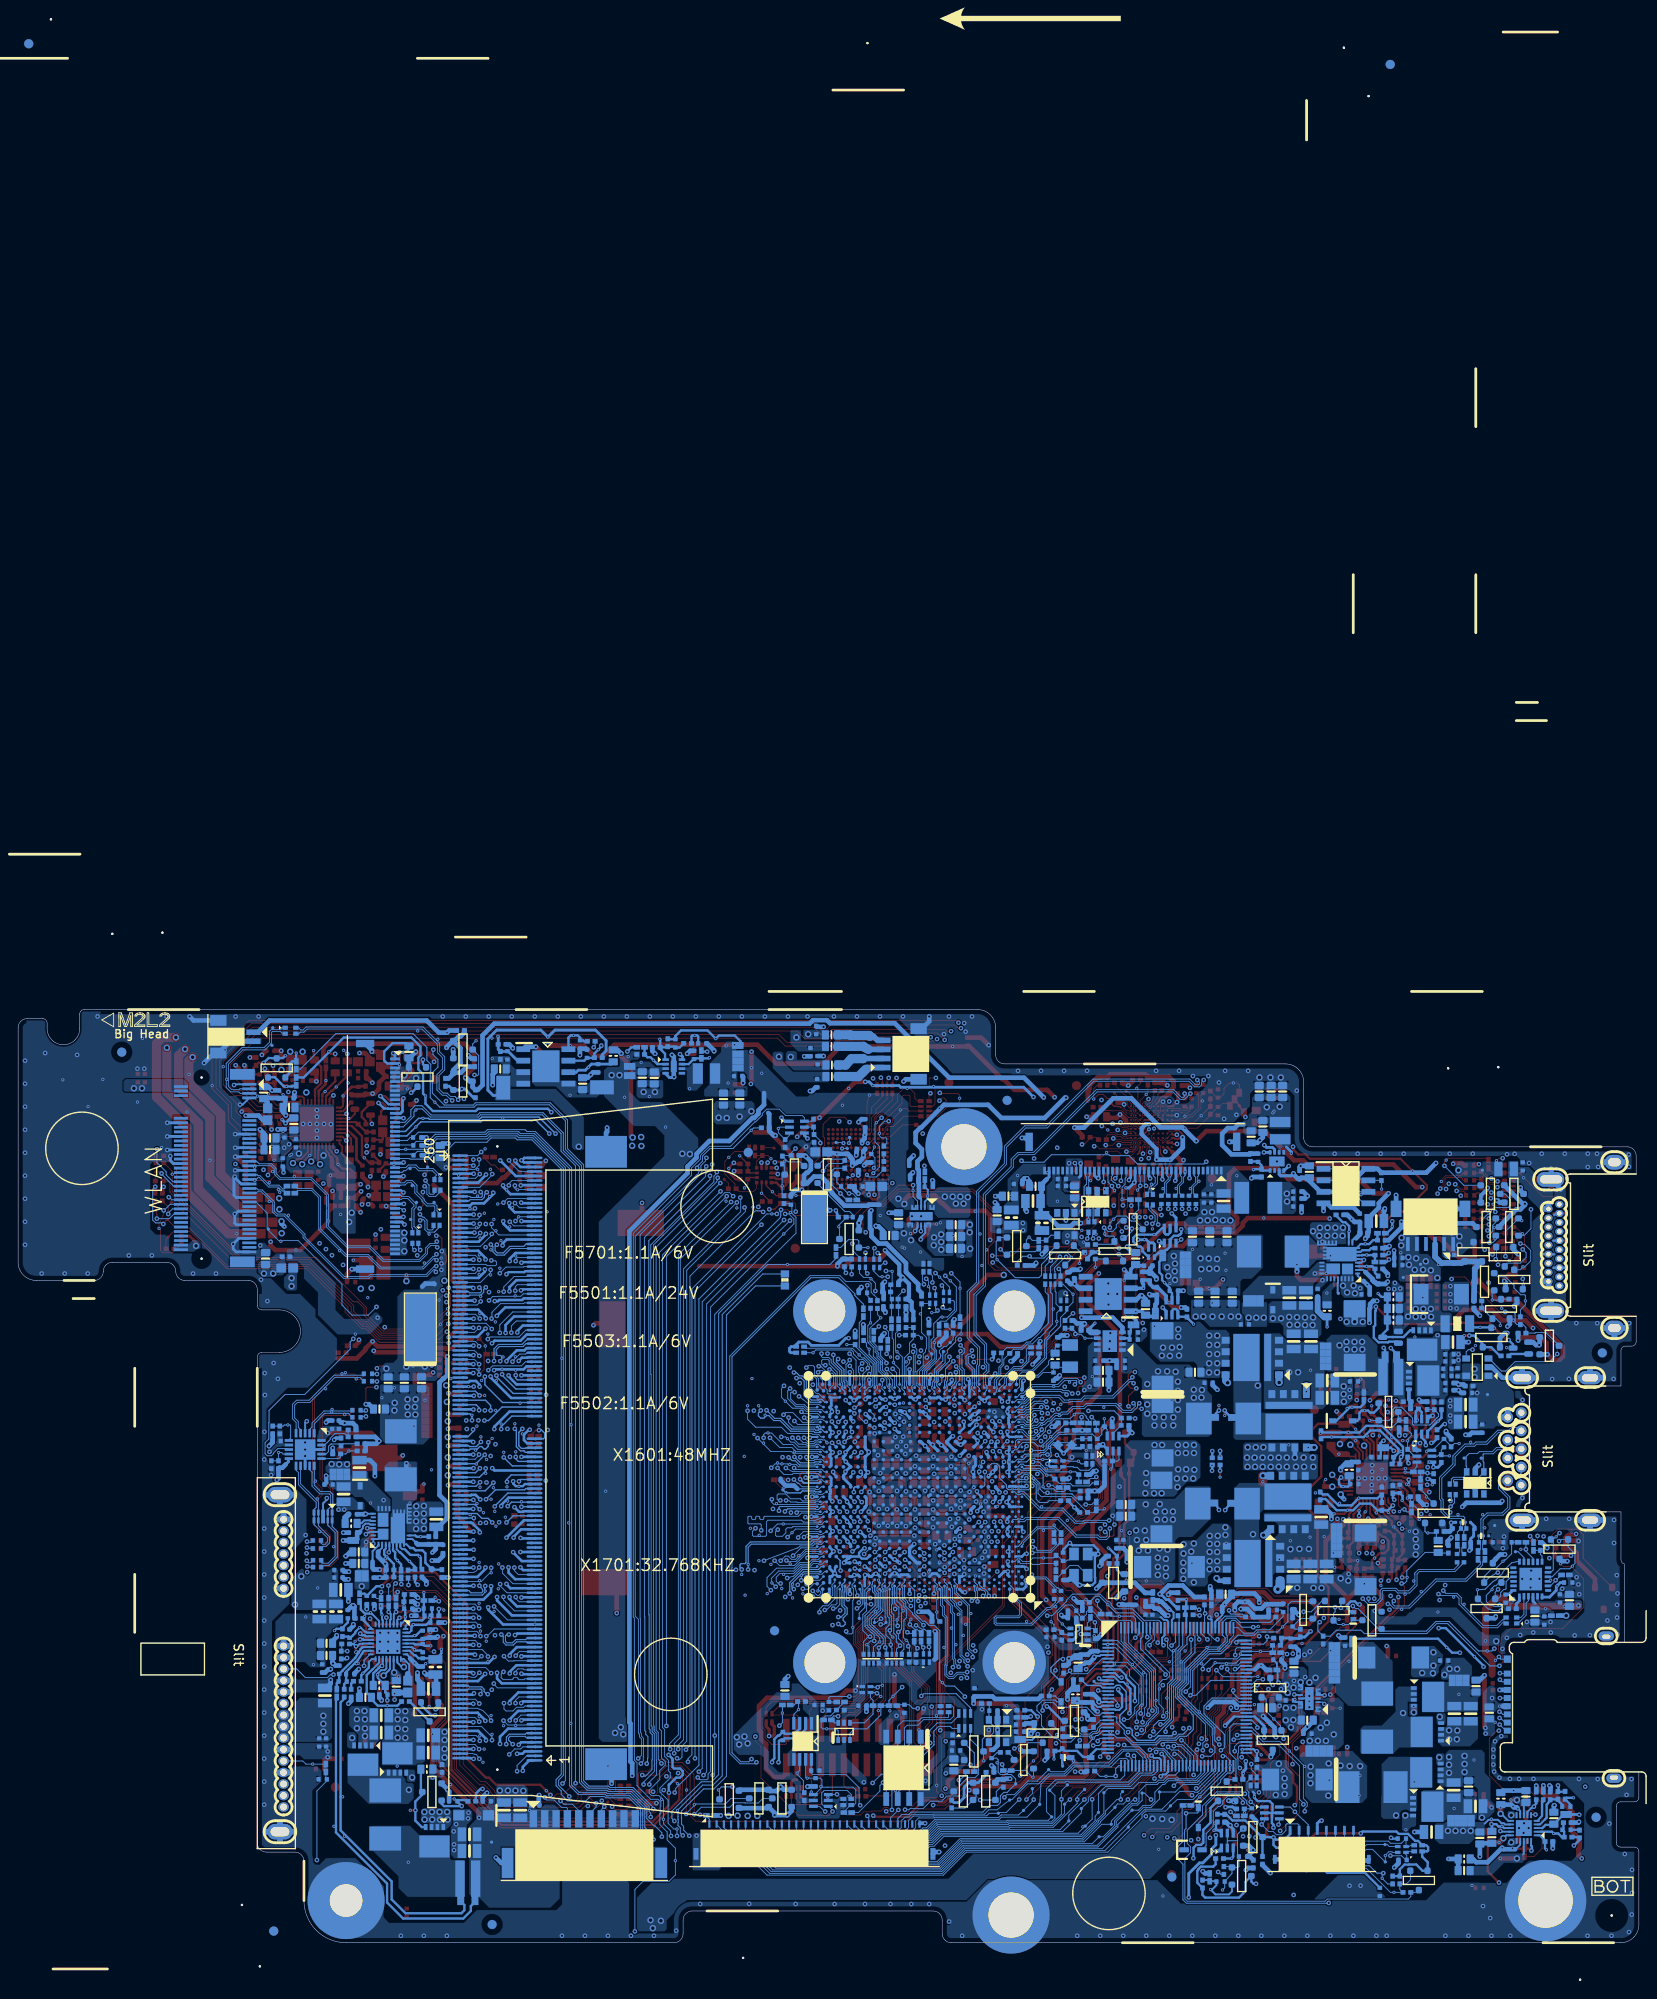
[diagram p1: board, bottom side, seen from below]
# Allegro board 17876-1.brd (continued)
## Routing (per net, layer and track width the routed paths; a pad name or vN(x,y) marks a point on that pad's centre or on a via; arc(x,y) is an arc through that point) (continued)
LPC_SERIRQ_CPU: length 153.1
  TOP w0.089: v1(60.04,35.36) 60.04,35.32 60.12,35.24 v2(60.12,33.89) 60.03,33.79 60.03,32.52 60.41,32.14 60.43,32.14 62.13,30.44 62.13,29.72 62.94,28.91 62.94,27.92 63.71,27.15 63.71,25.57 v1(63.62,25.49)
  L4 w0.14: v1(83.2,67.95) 83.26,67.95 83.64,67.57 84.08,67.57 84.35,67.84 84.35,68.63 86.43,70.71 86.43,71.33 89.45,74.35 90.45,74.35 91.59,75.49 94.41,75.49 100.2,81.28 v1(100.2,81.76) ; v1(106.93,21.36) 106.93,21.43 106.41,21.95 103.51,21.95 103.33,21.77 100.94,21.77 99.85,20.68 98.77,20.68 98.65,20.8 96.85,20.8 95.94,21.71 95.09,21.71 93.37,23.43 88.11,23.43 85.32,26.22 82,26.22 80.54,27.68 76.5,27.68 73.42,24.6 67.95,24.6 67.16,23.8 65.9,23.8 65.06,24.64 64.45,24.64 63.66,25.43 63.66,25.45 v1(63.62,25.49)
  BOTTOM w0.089: v1(83.2,67.95) 83.2,67.82 82.82,67.45 82.82,66.58 R1631.1 ; R2435.2 60.54,35.62 60.85,35.31 U2404.3 60.24,34.69 R2436.2 59.99,35.18 60.04,35.22 v1(60.04,35.36) ; v1(100.2,81.76) 106.03,75.94 106.03,22.94 106.98,21.98 106.98,21.42 v1(106.93,21.36)
LVDS_VDD_EN: length 15.6
  BOTTOM w0.102: Q5501.C 62.77,75.35 62.77,75.86 63.07,76.15 64.69,76.15 65.35,75.49 65.35,75.44 65.94,74.86 65.94,73.69 66.22,73.41 68.83,73.41 70.81,75.39 v2(70.84,75.39) 70.94,75.49 70.94,77.4 R5516.2 70.5,77.84 D5501.1
LVDS_VDD_EN_B: length 2.9
  BOTTOM w0.102: v2(61.75,74.98) 61.75,75.69 R5521.2 61.65,76.23 Q5501.B
LVDS_VDD_EN_CPU: length 215.3
  TOP w0.102: v1(78.97,35.05) 78.97,33.96 80.04,32.89 80.04,29.95 78.31,28.22 78.31,26.86 78.32,26.84 78.32,26.76 78.51,26.57 78.51,25.88 78.32,25.69 78.32,24.27 78.71,23.88 78.71,23.8 78.77,23.75 78.77,23.6 78.32,23.15 v2(78.32,22.87) 78.32,22.14 v1(78.23,22.05)
  L3 w0.127: v1(68.15,86.31) 68.96,86.31 73.28,84.79 76.53,84.79 77.27,84.05 77.27,82.22 75.89,80.84 73.31,80.84 72.2,79.73 72.19,79.73 72.03,79.58 72.03,77.78 72.06,77.75 72.06,77.4 71.78,77.12 70.36,77.12 69.01,75.77 v1(67.26,75.77) ; v1(78.23,22.05) 77.35,22.05 76.62,22.78 68.43,22.78 67.7,22.06 65.01,22.06 64.52,21.57 64.15,21.57 63.66,22.06 62,22.06 v1(61.71,22.34) 60.97,22.34 60.62,22.7 58.05,22.7 57.7,22.34 55.12,22.34 54.66,22.8 54.61,22.8 54.04,23.37 54.04,24.12 52.52,25.64 51.28,25.64 50.51,26.42 48.92,26.42 48.22,27.12 44.15,27.12 44.11,27.17 42.41,28.87 41.95,28.87 41.71,28.63 41.3,28.63 40.78,29.15 38.67,29.15 38.04,29.78 35.18,29.78 34.28,30.68 31.45,30.68 31.03,31.1 26.55,31.1 23.93,33.73 21.74,33.73 17.41,38.06 17.41,41.68 17.69,41.96 17.69,44.18 17.01,44.86 17.01,57.27 18.47,58.73 18.47,61.6 18.94,62.07 18.94,65.53 18.28,66.19 18.28,73.76 25.21,80.7 27.08,80.7 27.85,81.47 32.05,81.47 32.3,81.73 36.64,81.73 39.92,85 46.55,85 v1(47.75,86.21)
  BOTTOM w0.102: v1(47.75,86.21) 48.01,85.96 55.35,85.96 56.26,86.87 58.39,86.87 58.5,86.97 64.85,86.97 65.66,86.15 66.55,86.15 66.58,86.13 66.94,86.13 66.96,86.15 67.99,86.15 v1(68.15,86.31) ; Q5501.E 64.28,76.94 65.66,75.57 67.06,75.57 v1(67.26,75.77) 68.02,75.77 68.61,75.19 R5522.2 ; R2440.2 61.85,22.21 v1(61.71,22.34) ; CPU1.B24 81.05,39.8 81.35,39.5 81.35,39.2 81.25,39.1 81.25,37.9 80.92,37.57 80.92,37.14 80.17,36.39 80.17,36.25 v1(78.97,35.05)
LVDS_VDD_EN_KBC: length 3.1
  BOTTOM w0.102: R2440.1 60.4,22.38 v2(60.2,22.58) 59.91,22.87 59.69,22.87 59.21,23.35 U2401.26
LVDS_VDD_EN_R: length 4.6
  BOTTOM w0.102: U5501.4 64.88,78.09 R5508.2 65.46,77.52 R5503.2 66.95,77.52 v2(67.31,77.88) 67.61,77.58 D5501.3
M_A_A0: length 48.9
  TOP w0.14: v1(128.68,56.64) 128.64,56.64 128.27,57.02 v2(128.26,57.02)
  L3 w0.216: v1(128.68,56.64) 128.42,56.9 127,56.9 126.8,57.1 126.77,57.1 124.99,58.88 118.72,58.88 114.65,54.81 105.69,54.81 104.34,53.47 103.33,53.47 102.87,53.93 102.16,53.93 101.68,53.44 101.22,53.44 100.76,53.9 100.28,53.9 99.82,53.44 99.36,53.44 98.9,53.9 98.27,53.9 97.94,53.57 97.51,53.57 97.15,53.93 96.57,53.93 96.21,53.57 95.28,53.57 94.74,54.1 91.06,54.1 90.37,53.42 88.93,53.42 88.42,53.93 88.41,53.93 v1(88.21,54.12)
  BOTTOM w0.14: DIMM1.144 129.22,55.87 128.68,56.42 v1(128.68,56.64) ; CPU1.AG38 88.21,54 v1(88.21,54.12)
M_A_A1: length 49
  TOP w0.14: v1(123.98,53.62) v2(123.98,54.18)
  L3 w0.102: v1(86.57,48.67) 86.57,48.18 86.77,47.98 89.27,47.98
  L3 w0.216: v1(123.98,53.62) 123.98,53.52 123.55,53.09 120.5,53.09 115.37,47.96 110.02,47.96 109.81,47.74 109.81,47.36 109.59,47.14 109.19,47.14 108.97,47.36 108.97,47.74 108.73,47.98 108.32,47.98 108.11,47.77 108.11,47.39 107.87,47.14 107.46,47.14 107.24,47.36 107.24,47.74 107,47.98 106.6,47.98 106.38,47.77 106.38,47.39 106.14,47.14 105.73,47.14 105.52,47.36 105.52,47.74 105.27,47.98 104.84,47.98 104.63,47.77 104.63,47.33 104.39,47.09 98.68,47.09 98.22,47.55 96.49,47.55 96.24,47.3 95.22,47.3 94.84,46.92 92.71,46.92 91.65,47.98 89.27,47.98
  BOTTOM w0.14: v1(86.57,48.67) 87,49.1 CPU1.W35 ; DIMM1.133 123.68,53.13 123.98,53.42 v1(123.98,53.62)
M_A_A2: length 49.6
  TOP w0.14: v2(127.19,53.34) v1(127.39,53.86)
  L3 w0.216: v1(88.2,48.67) 88.2,49.6 88.42,49.82 89.02,49.82 89.71,49.13 90.37,49.13 91.06,49.82 92.73,49.82 93.19,49.35 94.41,49.35 94.79,49.48 96.01,49.48 96.8,48.69 97.36,48.69 97.88,49.21 98.19,49.21 98.74,48.67 99.24,48.67 99.8,49.23 100.24,49.23 100.79,48.67 101.3,48.67 101.83,49.2 115.11,49.2 120.57,54.66 125.25,54.66 125.65,54.26 127.18,54.26 127.39,54.04 v1(127.39,53.86)
  BOTTOM w0.14: DIMM1.132 128.36,52.87 127.39,53.84 v1(127.39,53.86) ; v1(88.2,48.67) 88.6,49.07 CPU1.W38
M_A_A3: length 48.2
  TOP w0.14: v1(125.3,53.57) v2(125.3,54.13)
  L3 w0.102: v1(85.78,48.63) 86.22,49.07 86.73,49.07 86.97,48.84 86.97,48.52 87.23,48.26 89.71,48.26 89.75,48.3
  L3 w0.216: 89.75,48.3 95.21,48.3 95.51,48.41 95.86,48.41 96.08,48.2 103.62,48.2 104.09,48.67 115.32,48.67 120.78,54.14 124.83,54.14 125.3,53.66 v1(125.3,53.57)
  BOTTOM w0.14: v1(85.78,48.63) 86.2,49.05 CPU1.W34 ; v1(125.3,53.57) 124.35,52.62 DIMM1.131
M_A_A4: length 49.2
  TOP w0.14: v2(128.33,52.84) 128.33,52.84 127.93,52.44 v1(127.93,52.36)
  L3 w0.102: 90.65,47.05 90.27,47.14 88.83,47.14 88.4,47.57 v1(88.2,47.57)
  L3 w0.216: v1(127.93,52.36) 127.93,52.54 127.51,52.96 126.42,52.96 125.96,52.5 120.65,52.5 115.37,47.22 114.64,47.22 114.43,47 114.43,46.81 114.2,46.59 113.54,46.59 113.36,46.76 113.36,47.03 113.14,47.25 112.44,47.25 112.23,47.03 112.23,46.77 112.04,46.59 111.56,46.59 111.36,46.78 111.36,47.03 111.15,47.25 110.57,47.25 110.39,47.07 110.39,46.8 110.17,46.59 98.45,46.59 98.04,46.99 96.62,46.99 96.44,46.81 95.3,46.81 95.02,46.53 92.25,46.53 92.1,46.38 91.31,46.38 90.65,47.05
  BOTTOM w0.14: CPU1.U38 88.6,47.97 v1(88.2,47.57) ; v1(127.93,52.36) 128.42,51.87 DIMM1.128
M_A_A5: length 49.1
  TOP w0.14: v1(127.29,52.36) v2(127.29,51.8)
  L3 w0.102: 90.32,46.81 90.2,46.93 88.68,46.93 88.5,47.11 87.86,47.11 v1(87.4,47.57)
  L3 w0.216: 90.32,46.81 91.06,46.08 91.16,46.08 91.19,46.05 92.23,46.05 92.25,46.08 95.2,46.08 95.43,46.31 96.75,46.31 96.95,46.51 97.84,46.51 98.68,45.67 99.55,45.67 99.98,46.1 100.46,46.1 100.97,45.59 101.55,45.59 102.06,46.1 114.99,46.1 120.87,51.98 124.68,51.98 124.84,51.82 126.75,51.82 v1(127.29,52.36)
  BOTTOM w0.14: v1(87.4,47.57) 87.8,47.97 CPU1.U37 ; DIMM1.126 127.98,51.38 127.29,52.06 v1(127.29,52.36)
M_A_A6: length 49.4
  TOP w0.14: v1(124.94,50.88) v2(124.94,50.32)
  L3 w0.102: 90.08,46.54 89.89,46.73 88.55,46.73 88.38,46.9 87.27,46.9 v1(86.6,47.57)
  L3 w0.216: 90.08,46.54 90.95,45.67 94.26,45.67 95.02,44.91 96.01,44.91 96.09,44.99 102.92,44.99 103.07,45.14 103.07,45.34 103.3,45.57 103.75,45.57 103.96,45.35 103.96,45.2 104.18,44.99 104.56,44.99 104.83,45.25 104.83,45.4 105.04,45.62 105.47,45.62 105.69,45.4 105.69,45.25 105.93,45.01 106.31,45.01 106.55,45.25 106.55,45.4 106.77,45.62 107.2,45.62 107.42,45.4 107.42,45.25 107.66,45.01 108.04,45.01 108.6,45.57 115.21,45.57 120.12,50.47 120.85,50.47 121.84,51.46 124.51,51.46 124.94,51.03 v1(124.94,50.88)
  BOTTOM w0.14: v1(124.94,50.88) 124.98,50.92 124.98,51.12 124.47,51.62 DIMM1.127 ; CPU1.U34 86.2,47.97 v1(86.6,47.57)
M_A_A7: length 49.5
  TOP w0.14: v1(127.91,50.83) v2(127.91,50.27)
  L3 w0.102: 89.5,46.05 87.02,46.05 v1(86.6,46.47)
  L3 w0.216: v1(127.91,50.83) 127.41,51.34 126.16,51.34 125.19,50.36 122.42,50.36 115.74,43.68 94.81,43.68 94.46,44.02 91.54,44.02 89.5,46.05
  BOTTOM w0.14: CPU1.R35 87,46.87 v1(86.6,46.47) ; v1(127.91,50.83) 128.37,50.38 DIMM1.122
M_A_A8: length 49.8
  TOP w0.14: v1(123.62,50.93) v2(123.62,50.37)
  L3 w0.216: v1(88.2,46.47) 89.53,46.47 90.66,45.34 93.8,45.34 93.9,45.24 94.16,45.24 94.44,44.96 94.44,44.78 95.07,44.15 103.43,44.15 103.53,44.25 108.77,44.25 109.11,44.59 109.11,44.87 109.33,45.09 109.76,45.09 109.98,44.87 109.98,44.41 110.19,44.2 110.62,44.2 110.84,44.41 110.84,44.85 111.06,45.06 111.49,45.06 111.7,44.85 111.7,44.41 111.92,44.2 112.35,44.2 112.57,44.41 112.57,44.87 112.78,45.09 113.21,45.09 113.43,44.87 113.43,44.41 113.65,44.2 114.08,44.2 114.29,44.41 114.29,44.85 114.51,45.06 114.94,45.06 115.16,44.85 115.16,44.63 115.37,44.41 115.79,44.41 116.46,45.09 116.46,45.44 116.31,45.59 116.31,45.89 116.57,46.15 116.97,46.15 117.07,46.05 117.37,46.05 117.68,46.36 117.68,46.66 117.58,46.76 117.58,47.07 117.88,47.38 118.19,47.38 118.29,47.27 118.6,47.27 118.9,47.58 118.9,47.88 118.76,48.03 118.76,48.34 119.06,48.64 119.37,48.64 119.51,48.5 119.82,48.5 120.12,48.8 120.12,49.11 120.02,49.21 120.02,49.51 120.33,49.82 120.63,49.82 120.73,49.72 121.04,49.72 122.25,50.93 v1(123.62,50.93)
  BOTTOM w0.14: v1(123.62,50.93) 123.62,50.98 123.48,51.13 DIMM1.125 ; v1(88.2,46.47) 88.6,46.87 CPU1.R38
M_A_A9: length 50.1
  TOP w0.14: v1(127.25,48.95) v2(126.7,48.95)
  L3 w0.102: 89.66,44.97 88.8,44.97 88.4,45.37 v1(88.2,45.37)
  L3 w0.216: v1(127.25,48.95) 126.98,49.22 122.78,49.22 116.26,42.7 94.56,42.7 93.98,43.28 91.35,43.28 89.66,44.97
  BOTTOM w0.14: DIMM1.121 122.86,50.13 123,49.99 126.21,49.99 v1(127.25,48.95) ; CPU1.N38 88.6,45.77 v1(88.2,45.37)
M_A_A10: length 52.3
  TOP w0.14: v1(128.8,57.66) v2(128.8,58.22)
  L3 w0.102: 89.53,55.67 89.53,55.68 87.49,55.68 86.71,54.89 86.59,54.89 v1(85.82,54.12)
  L3 w0.216: 89.53,55.67 90.24,55.67 91.32,56.75 94.57,56.75 94.84,57.02 112.75,57.02 117.3,61.57 121.16,61.57 121.69,61.04 126.57,61.04 127.99,59.62 128.7,59.62 129.34,58.98 129.34,58.29 128.8,57.76 v1(128.8,57.66)
  BOTTOM w0.14: DIMM1.146 129.04,58.38 128.8,58.14 v1(128.8,57.66) ; v1(85.82,54.12) 86.2,53.74 CPU1.AG34
M_A_A11: length 50.2
  TOP w0.14: v1(126.44,50.78) v2(126.44,50.22)
  L3 w0.102: 89.53,45.54 89.24,45.84 86.6,45.84 v1(85.95,46.49)
  L3 w0.216: v1(126.44,50.78) 125.51,49.84 122.64,49.84 115.98,43.18 94.64,43.18 94.13,43.69 91.39,43.69 89.53,45.54
  BOTTOM w0.14: v1(85.95,46.49) 85.95,46.77 CPU1.R34 ; DIMM1.120 127.34,49.87 v1(126.44,50.78)
M_A_A12: length 50.1
  TOP w0.14: v1(126.29,48.16) v2(126.29,47.6)
  L3 w0.102: v1(87.4,45.37) 87.85,44.92 88.52,44.92 88.77,44.67 89.35,44.67
  L3 w0.216: v1(126.29,48.16) 126.29,48.2 125.79,48.7 122.99,48.7 116.05,41.76 97.3,41.76 97.06,41.65 91.9,41.65 90.93,42.62 90.93,43.09 89.35,44.67
  BOTTOM w0.14: DIMM1.119 124.85,49.62 126.29,48.19 v1(126.29,48.16) ; v1(87.4,45.37) 87.8,45.77 CPU1.N37
M_A_A13: length 54.2
  TOP w0.14: v1(128.61,61.38) v2(129.17,61.38)
  L3 w0.102: 87.54,58.35 87.14,57.95 87.14,57.31 87.14,57.31 87.14,57 v1(86.86,56.37)
  L3 w0.216: 87.54,58.35 88.45,59.26 91.06,61.06 91.56,61.11 92.74,61.11 92.96,61.22 93.47,61.72 94.56,62.14 101.73,62.35 115.8,65.76 125.17,65.76 125.58,65.64 126.9,65.64 127.16,65.72 127.8,66.36 128.56,66.49 128.98,66.37 129.33,66.02 129.84,64.96 129.84,62.41 128.85,61.42 128.65,61.42 v1(128.61,61.38)
  BOTTOM w0.14: v1(128.61,61.38) 128.62,61.38 DIMM1.158 ; CPU1.AN35 87,56.51 v1(86.86,56.37)
M_A_ACT#: length 53.1
  TOP w0.14: v1(127.95,47.84) 127.92,47.84 127.54,47.47 v2(127.54,47.47)
  L3 w0.102: 89.44,43.16 89.44,43.21 89,43.66 87.21,43.66 v1(86.6,44.27)
  L3 w0.216: 89.44,43.16 89.44,42.48 91.19,40.74 91.19,39.5 93.05,37.64 94,37.64 94,37.65 96.3,37.65 97.49,38.84 107.04,38.84 107.54,39.35 115.87,39.35 123.42,46.89 124.56,46.89 125.08,47.41 127.52,47.41 v1(127.95,47.84)
  BOTTOM w0.14: v1(86.6,44.27) 87,44.67 CPU1.L35 ; DIMM1.114 128.51,48.38 128.42,48.29 128.4,48.29 v1(127.95,47.84)
M_A_ALERT_N: length 2.8
  TOP w0.14: v2(128.26,48.48) v1(128.65,48.87) 128.71,48.82 R1206.2
  BOTTOM w0.14: v1(128.65,48.87) DIMM1.116
M_A_BA0: length 48.9
  TOP w0.14: v1(89.06,55.18) v2(89.62,55.18)
  L3 w0.216: v1(128.02,58.78) 128.02,58.9 127.64,59.29 126.95,59.29 126.64,59.59 126.64,60.26 126.43,60.48 121.51,60.48 120.98,61.01 120.24,61.01 119.76,60.53 118.95,60.53 118.73,60.75 118.73,60.85 118.49,61.09 118.11,61.09 117.74,60.72 117.14,60.72 116.83,60.41 116.83,59.66 116.36,59.19 115.6,59.19 115.16,58.75 115.16,57.99 114.7,57.52 114.14,57.52 113.74,57.13 113.74,56.57 113.47,56.3 112.79,56.3 112.55,56.54 112.04,56.54 111.8,56.3 109.61,56.3 109.37,56.54 108.86,56.54 108.58,56.26 107.62,56.26 107.34,56.54 106.78,56.54 106.54,56.3 94.92,56.3 94.88,56.35 94.45,56.35 94.41,56.3 91.35,56.3 90.23,55.18 v1(89.06,55.18)
  BOTTOM w0.14: v1(128.02,58.78) 128.02,59.05 128.34,59.38 DIMM1.150 ; CPU1.AJ38 v1(89.06,55.18)
M_A_BA1: length 48.8
  TOP w0.14: v1(125.58,56.69) v2(125.58,57.25)
  L3 w0.216: v1(125.58,56.69) 125.78,56.9 125.78,57.33 124.76,58.35 119.38,58.35 115.29,54.26 106.05,54.26 104.75,52.96 88.92,52.96 88.28,53.6 87.13,53.6 v1(86.56,54.16)
  BOTTOM w0.14: v1(125.58,56.69) 125.58,56.95 124.4,58.13 DIMM1.145 ; v1(86.56,54.16) 87,53.73 CPU1.AG35
M_A_BG0: length 50.3
  TOP w0.14: v1(124.87,48.19) v2(124.87,48.74)
  L3 w0.102: v1(86.6,45.37) 87.14,44.83 87.37,44.83 87.79,44.41 87.79,44.1 88.03,43.86 89.19,43.86 89.76,43.29
  L3 w0.216: 89.76,43.29 89.76,42.82 91.58,41 92.27,41 95.01,38.25 96.16,38.25 97.18,39.27 97.23,39.27 97.28,39.32 106.25,39.32 106.76,39.83 115.62,39.83 123.22,47.42 124.2,47.42 124.87,48.09 v1(124.87,48.19)
  BOTTOM w0.14: CPU1.N34 86.2,45.77 v1(86.6,45.37) ; DIMM1.115 124.43,48.62 v1(124.87,48.19)
M_A_BG1: length 48.9
  TOP w0.14: v1(123.34,48.11) v2(123.34,48.67)
  L3 w0.102: v1(88.2,44.27) 89.16,44.27 89.39,44.04
  L3 w0.216: 89.39,44.04 89.46,44.04 90.37,43.13 90.37,42.66 91.7,41.33 92.41,41.33 92.76,40.97 94.79,40.97 95.02,40.74 95.02,40.46 95.35,40.13 95.81,40.13 95.99,40.31 95.99,40.81 96.2,41.02 96.72,41.02 97.59,40.16 99.14,40.16 99.29,40.31 100.59,40.31 100.8,40.53 100.8,40.68 101.02,40.9 101.45,40.9 101.67,40.68 101.67,40.53 101.88,40.31 103.02,40.31 103.24,40.53 103.24,40.68 103.46,40.9 103.89,40.9 104.1,40.68 104.1,40.53 104.32,40.31 106.5,40.31 106.71,40.53 106.71,40.65 106.93,40.87 107.36,40.87 107.58,40.65 107.58,40.53 107.79,40.31 108.26,40.31 108.48,40.53 108.48,40.68 108.69,40.9 109.13,40.9 109.34,40.68 109.34,40.53 109.56,40.31 109.99,40.31 110.21,40.53 110.21,40.68 110.42,40.9 110.85,40.9 111.07,40.68 111.07,40.53 111.29,40.31 111.72,40.31 111.93,40.53 111.93,40.68 112.15,40.9 112.58,40.9 112.8,40.68 112.8,40.53 113.01,40.31 113.44,40.31 113.66,40.53 113.66,40.68 113.88,40.9 114.31,40.9 114.52,40.68 114.52,40.53 114.74,40.31 115.36,40.31 123.16,48.11 v1(123.34,48.11)
  BOTTOM w0.14: CPU1.L38 88.6,44.67 v1(88.2,44.27) ; v1(123.34,48.11) 123.32,48.11 123.32,48.13 DIMM1.113
M_A_CAS#: length 53.8
  TOP w0.14: v1(127.97,60.4) v2(127.41,60.4)
  L3 w0.216: v1(89.08,57.53) 91.38,59.84 93.64,59.84 95.07,61.27 99.06,61.27 99.5,60.82 111.85,60.82 116.31,65.28 124.7,65.28 125.12,65.1 127.3,65.1 127.81,65.31 128.27,65.31 128.58,65.38 128.85,65.38 129.36,64.87 129.36,62.74 128.8,62.18 128.05,62.18 127.43,61.56 127.43,60.94 v1(127.97,60.4)
  BOTTOM w0.14: CPU1.AN38 89.08,57.4 v1(89.08,57.53) ; DIMM1.156 128.43,60.87 127.97,60.41 v1(127.97,60.4)
M_A_CKE0: length 50.9
  TOP w0.14: v2(125.12,46.96) v1(124.99,46.38)
  L3 w0.216: v1(124.99,46.38) 124.97,46.36 123.62,46.36 116.1,38.84 114.27,38.84 114.1,38.66 114.1,38.43 113.82,38.15 113.38,38.15 113.17,38.37 113.17,38.62 112.95,38.84 112.52,38.84 112.31,38.62 112.31,38.42 112.09,38.21 111.78,38.21 111.18,38.81 110.21,38.81 109.63,38.23 97.64,38.23 96.52,37.11 91.62,37.11 90.6,38.13 90.6,40.77 v1(88.2,43.17)
  BOTTOM w0.14: v1(124.99,46.38) 124.25,47.13 DIMM1.109 ; CPU1.J38 88.6,43.57 v1(88.2,43.17)
M_A_CKE1: length 53.6
  TOP w0.14: v2(126.16,45.98) v1(126.57,46.38)
  L3 w0.216: v1(126.57,46.38) 125.87,45.68 123.68,45.68 115.6,37.59 97.74,37.59 96.72,36.58 92.13,36.58 92.11,36.59 91.43,36.59 90.04,37.97 90.04,40.84 88.25,42.64 87.36,42.64 v1(86.81,43.19)
  BOTTOM w0.14: v1(86.81,43.19) 86.73,43.19 CPU1.J34 ; v1(126.57,46.38) 127.03,46.84 127.71,46.84 128.25,47.38 DIMM1.110
M_A_CLK0: length 50.5
  TOP w0.14: v1(124.08,56.72) v2(124.08,57.28)
  L3 w0.191: v1(124.08,56.72) 123.36,57.43 119.93,57.43 114.41,51.91 113.27,51.91 113.08,52.1 113.08,52.64 112.76,52.96 111.78,52.96 111.48,52.66 111.48,52.3 111.24,52.06 110.5,52.06 110.31,52.25 110.31,52.54 109.9,52.95 108.86,52.95 108.46,52.54 108.46,52.1 108.25,51.89 107.27,51.89 107.08,52.08 107.08,52.45 106.72,52.81 105.9,52.81 105.54,52.45 105.54,52.08 105.24,51.78 97.12,51.78 97.02,51.88 95.92,51.88 95.9,51.89 92.99,51.89 92.34,52.55 90.57,52.55 90.14,52.12 90.14,51.58 89.95,51.39 87.26,51.39 86.89,51.75 86.88,51.75 v1(86.72,51.92)
  BOTTOM w0.14: v1(124.08,56.72) 123.9,56.55 123.9,54.74 123.46,54.29 123.08,54.29 122.91,54.13 DIMM1.137 ; CPU1.AC35 v1(86.72,51.92)
M_A_CLK1: length 49
  TOP w0.14: v2(126.58,55.66) 126.58,55.65 v1(127,55.23)
  L3 w0.191: v1(127,55.23) 127,55.39 126.81,55.58 120.18,55.58 114.86,50.26 96.53,50.26 96.39,50.4 94.39,50.4 94.27,50.28 86.68,50.28 86.53,50.13 86.53,49.86 v1(86.65,49.74)
  BOTTOM w0.14: CPU1.AA34 86.51,50.32 86.65,50.18 v1(86.65,49.74) ; DIMM1.138 129.12,54.38 128.99,54.5 128.22,54.5 127.96,54.76 127.74,54.76 127.48,54.51 127.28,54.51 127,54.79 v1(127,55.23)
M_A_CLK#0: length 50.7
  TOP w0.14: v1(123.24,56.72) v2(123.24,56.16)
  L3 w0.191: v1(85.9,51.97) 85.95,51.97 86.46,51.46 86.77,51.46 87.13,51.09 90.08,51.09 90.44,51.46 90.44,52 90.69,52.25 92.22,52.25 92.87,51.6 95.78,51.6 95.8,51.59 96.9,51.59 97,51.49 105.36,51.49 105.83,51.96 105.83,52.33 106.03,52.52 106.6,52.52 106.79,52.33 106.79,51.96 107.15,51.6 108.38,51.6 108.75,51.98 108.75,52.42 108.99,52.66 109.78,52.66 110.02,52.41 110.02,52.13 110.38,51.77 111.36,51.77 111.77,52.18 111.77,52.54 111.9,52.67 112.64,52.67 112.79,52.52 112.79,51.98 113.15,51.61 114.53,51.61 120.05,57.14 123.11,57.14 123.24,57.01 v1(123.24,56.72)
  BOTTOM w0.14: DIMM1.139 122.82,54.62 122.89,54.56 123.35,54.56 123.64,54.85 123.64,56.33 v1(123.24,56.72) ; CPU1.AC34 85.91,51.42 85.73,51.6 85.73,51.8 v1(85.9,51.97)
M_A_CLK#1: length 48.7
  TOP w0.14: v2(127.82,55.84) v1(127.82,55.28)
  L3 w0.191: v1(85.83,49.76) 85.83,49.84 86.56,50.57 94.15,50.57 94.27,50.69 96.51,50.69 96.65,50.55 114.74,50.55 120.06,55.87 126.97,55.87 127.12,55.78 v1(127.82,55.28)
  BOTTOM w0.14: v1(127.82,55.28) 128.33,54.76 129.08,54.76 129.19,54.87 DIMM1.140 ; CPU1.AA32 v1(85.83,49.76)
M_A_CS#0: length 50.8
  TOP w0.14: v1(87.68,55.27) 87.68,55.28 v2(87.21,55.74)
  L3 w0.102: 90.02,54.43 89.91,54.54 88.41,54.54 v1(87.68,55.27)
  L3 w0.216: 90.02,54.43 90.83,54.43 91.08,54.69 94.84,54.69 95.12,54.41 104.45,54.41 105.33,55.3 114.07,55.3 118.13,59.36 125.27,59.36 127,57.63 v1(127.43,57.63)
  BOTTOM w0.14: CPU1.AL35 87.13,55.82 v1(87.68,55.27) ; DIMM1.149 125.48,59.13 126.97,57.63 v1(127.43,57.63)
M_A_CS#1: length 50.1
  TOP w0.14: v1(125.48,62.74) v2(125.48,63.3)
  L3 w0.102: 89.54,57.23 89.43,57.13 88.72,57.13 v1(88.37,57.48)
  L3 w0.216: 89.54,57.23 91.82,59.51 93.27,59.51 93.27,59.52 94.01,59.52 95.25,60.76 98.88,60.76 99.36,60.28 111.99,60.28 115.85,64.14 116.28,64.14 116.66,63.76 117,63.76 117.21,63.97 117.21,64.28 117.43,64.49 117.86,64.49 118.08,64.28 118.08,63.97 118.29,63.76 118.72,63.76 118.94,63.97 118.94,64.38 119.18,64.62 119.59,64.62 119.8,64.4 119.8,63.97 120.02,63.76 120.45,63.76 120.67,63.97 120.67,64.4 120.88,64.62 121.32,64.62 121.53,64.4 121.53,64.1 121.75,63.88 123.09,63.88 123.29,63.68 123.85,63.68 124.36,63.17 125.04,63.17 v1(125.48,62.74)
  BOTTOM w0.14: v1(125.48,62.74) 125.48,62.64 123.96,61.12 121.9,61.12 DIMM1.157 ; v1(88.37,57.48) 88.34,57.48 CPU1.AR37
M_A_DM0: length 59.4
  TOP w0.089: v1(127.94,22.28) v2(127.94,22.84)
  L4 w0.14: v1(127.94,22.28) 127.52,21.86 126.06,21.34 123.01,21.34 122.58,21.77 118.08,21.77 112.7,27.15 111.25,27.15 110.54,26.44 98.22,26.44 95.91,28.75 91.77,28.75 91.11,28.09 88.62,28.09 87.06,29.65 87.06,31.76 87.96,33.52 87.96,34.49 87.93,34.61 v1(87.32,37.9)
  BOTTOM w0.089: CPU1.B35 87.1,39.49 87.42,39.17 87.42,38.71 87.48,38.65 87.48,38.06 v1(87.32,37.9) ; DIMM1.12 128.36,22.87 127.94,22.46 v1(127.94,22.28)
M_A_DM1: length 49.9
  TOP w0.089: v1(92.45,40) v2(92.45,40.56)
  L4 w0.14: v1(92.45,40) 92.64,40.19 92.84,40.19 93.88,39.14 94.58,38.42 94.88,37.87 94.91,37.84 95.57,37.26 97.45,36.02 104.15,36.02 104.78,35.39 113.25,35.39 119.89,28.75 125.68,28.75 126.19,29.26 127.08,29.26 127.25,29.1 127.25,28.74 127.11,28.6 v1(126.39,28.6)
  BOTTOM w0.089: CPU1.D40 89.87,40.97 90.16,40.67 90.49,40.67 90.5,40.69 90.54,40.72 92.13,40.72 92.45,40.4 92.45,40 v1(92.45,40) ; DIMM1.33 125.99,28.12 126.39,28.53 v1(126.39,28.6)
M_A_DM2: length 47.6
  TOP w0.089: v1(96.57,42.17) v2(97.13,42.17)
  L4 w0.14: v1(96.57,42.17) 97.79,42.17 98.81,42.52 101.17,42.52 102.87,41.99 114.81,41.99 121.54,35.26 125.63,35.26 126.75,34.14 126.75,33.3 127.89,32.16 128.14,32.16 128.32,32.34 128.32,32.54 v1(128.02,32.84)
  BOTTOM w0.089: v1(96.57,42.17) 92.9,43.56 92.77,43.6 92.58,43.79 91.2,43.79 90.97,44.01 90.97,44.02 90.58,44.02 90.53,43.97 90.22,43.97 89.93,44.27 CPU1.K40 ; DIMM1.54 128.47,33.38 128.02,32.92 v1(128.02,32.84)
M_A_DM3: length 48.4
  TOP w0.089: v1(125.7,39.59) v2(125.89,39.06)
  L4 w0.14: v1(92.96,47.48) 92.96,47.49 93.11,47.64 93.11,48 92.97,48.13 92.48,48.13 92.3,47.96 92.3,47.3 93.07,46.53 96.04,46.53 96.57,46.64 97.33,46.79 119.18,46.79 121.13,44.83 121.13,41.89 122.94,40.08 125.56,40.08 125.7,39.94 v1(125.7,39.59)
  BOTTOM w0.089: v1(125.7,39.59) 125.7,39.39 124.93,38.63 DIMM1.75 ; v1(92.96,47.48) 92.81,47.63 90.94,47.63 90.88,47.57 CPU1.T41
M_A_DM4: length 51.7
  L4 w0.14: v1(128.02,65.84) 128.02,65.61 127.43,65.03 127.43,64.62 127.56,64.49 127.56,64.04 127.2,63.68 126.16,63.68 126.01,63.53 125.58,63.53 125.22,63.17 123.14,63.17 122.86,62.89 121.82,62.89 121.45,62.52 121.45,62.33 122.47,61.3 122.47,61.11 122.27,60.91 122.08,60.91 121.05,61.93 120.86,61.93 120.66,61.73 120.66,61.54 120.82,61.38 120.82,61.18 120.62,60.98 120.42,60.98 120.26,61.14 120.07,61.14 119.08,60.16 119.08,59.96 119.46,59.59 119.46,59.39 119.26,59.19 119.06,59.19 118.69,59.57 118.49,59.57 118.29,59.37 118.29,59.17 118.41,59.05 118.41,58.85 118.22,58.66 118.02,58.66 117.9,58.78 117.7,58.78 116.85,57.93 108.11,52.25 106.07,52.25 105.9,52.42 97.54,52.42 97.43,52.53 95.87,52.53 v1(95.77,52.42)
  BOTTOM w0.089: v1(128.02,65.84) 128.02,65.94 128.45,66.38 DIMM1.178 ; v1(95.77,52.42) 95.34,52.85 v2(94.59,52.85) 93.97,52.85 93.9,52.78 93.63,52.78 93.61,52.8 93.04,52.8 92.76,52.52 CPU1.AE41
M_A_DM5: length 52.9
  TOP w0.089: v1(98.38,58.71) v2(98.38,59.27)
  L4 w0.14: v1(98.38,58.71) 98.42,58.75 102.13,58.75 102.56,59.18 102.75,59.18 102.99,58.94 103.19,58.94 103.38,59.14 103.38,59.34 103.15,59.57 103.15,59.77 103.35,59.97 103.55,59.97 103.78,59.73 103.98,59.73 104.17,59.93 104.17,60.13 103.94,60.36 103.94,60.56 104.14,60.76 104.34,60.76 104.57,60.52 104.77,60.52 104.96,60.72 104.96,60.92 104.73,61.15 104.73,61.35 105.03,61.65 106.15,61.65 108.76,64.26 108.95,64.26 109.06,64.15 109.26,64.15 109.46,64.35 109.46,64.54 109.35,64.65 109.35,64.85 114.21,69.71 125.23,69.71 125.7,70.18 126.36,70.18 126.92,70.74 v1(126.92,70.89)
  BOTTOM w0.089: CPU1.AL40 90.25,55.82 90.55,56.12 91.22,56.12 91.31,56.21 93.96,56.21 94.65,56.9 97.49,56.9 98.38,57.79 v1(98.38,58.71) ; v1(126.92,70.89) 126.92,70.92 126.52,71.32 125.98,71.32 125.96,71.35 123.42,71.35 123.14,71.62 DIMM1.199
M_A_DM6: length 51.2
  TOP w0.089: v2(126.16,78.59) v1(126.62,78.23)
  L4 w0.14: v1(126.62,78.23) 126.25,77.89 126.07,77.75 125.2,77.45 124.65,76.9 110.6,76.9 105.89,72.19 105.89,71.53 99,64.64 95.01,64.64 94.65,64.46 93.54,63.9 92.94,63.3 92.84,63.1 92.7,62.96 92.56,62.41 92.2,62.05 92.2,61.42 v1(92.7,60.31)
  BOTTOM w0.089: v1(126.62,78.23) 126.62,78.11 127.85,76.88 DIMM1.220 ; v1(92.7,60.31) 91.59,59.43 90.57,59.43 CPU1.AU40
M_A_DM7: length 61.5
  TOP w0.089: v2(125.96,81.54) v1(125.33,81.69)
  L4 w0.14: v1(125.33,81.69) 124.85,82.17 115.45,82.17 115.31,82.31 115.31,82.82 115.17,82.96 114.9,82.96 114.76,82.82 114.76,82.28 114.62,82.14 114.34,82.14 114.2,82.28 114.2,82.82 114.06,82.96 113.78,82.96 113.64,82.82 113.64,82.28 113.5,82.14 113.22,82.14 113.08,82.28 113.08,82.82 112.94,82.96 112.66,82.96 112.52,82.82 112.52,81.75 112.41,81.64 112.1,81.64 111.96,81.77 111.96,82.82 111.82,82.96 111.54,82.96 111.4,82.82 111.4,81.75 111.29,81.64 110.98,81.64 110.84,81.77 110.84,82.82 110.7,82.96 110.42,82.96 110.29,82.82 110.29,82.28 110.15,82.14 109.69,82.14 109.55,82.28 109.55,82.81 109.41,82.95 109.13,82.95 108.99,82.81 108.99,82.28 108.85,82.14 107.97,82.14 94.36,68.53 94.36,67.97 91.62,65.23 91.14,65.23 90.93,65.03 v1(90.22,65.03)
  BOTTOM w0.089: CPU1.BA37 88.2,63.08 89.15,64.04 89.15,64.34 89.41,64.59 90.12,64.59 90.22,64.7 v1(90.22,65.03) ; DIMM1.241 123.06,82.13 123.08,82.15 124.87,82.15 v1(125.33,81.69)
M_A_DQ0: length 58.6
  TOP w0.089: v1(128.02,21.36) v2(127.46,21.36)
  L4 w0.14: v1(128.02,21.36) 125.73,20.75 125.14,20.54 124.56,20 124.36,19.94 123.14,19.92 120.01,20.18 117.43,20.98 112.88,25.53 97.82,25.53 96.89,26.45 94.94,27.79 92.18,27.79 91.62,27.59 88.39,27.59 87.91,28.07 87.9,28.07 86.56,29.41 86.56,31.92 87.07,33.42 87.07,37.16 86.89,37.49 v1(86.27,38.31)
  BOTTOM w0.089: CPU1.A34 86.27,38.33 v1(86.27,38.31) ; DIMM1.8 128.47,21.87 128.02,21.42 v1(128.02,21.36)
M_A_DQ1: length 60.7
  L4 w0.14: v1(87.5,34.37) 87.5,33.62 86.82,31.87 86.82,29.52 88.49,27.84 91.34,27.84 91.8,28.3 95.68,28.3 97.99,25.99 111.01,25.99 111.15,26.13 111.15,26.35 111.29,26.49 111.57,26.49 111.71,26.35 111.71,26.13 111.85,25.99 112.13,25.99 112.27,26.13 112.27,26.35 112.41,26.49 112.69,26.49 112.83,26.35 112.83,26.13 112.97,25.99 113.23,25.99 117.91,21.31 119.18,21.31 119.32,21.17 119.32,20.99 119.49,20.83 119.88,20.83 120.02,20.97 120.02,21.17 120.16,21.31 120.58,21.31 120.72,21.17 120.72,20.77 120.83,20.65 121.33,20.65 121.42,20.74 121.42,21.17 121.56,21.31 122.39,21.31 122.53,21.17 122.53,20.83 122.98,20.38 124.29,20.38 v1(124.69,20.78)
  BOTTOM w0.089: v1(124.69,20.78) 124.08,21.39 123.42,21.39 123.19,21.62 122.83,21.62 122.83,21.63 DIMM1.7 ; CPU1.B34 86.55,39.82 86.85,39.52 86.85,39.22 86.68,39.05 86.68,37.87 86.77,37.78 v2(86.77,34.8) 86.77,34.22 86.89,34.09 87.41,34.09 87.5,34.18 v1(87.5,34.37)
M_A_DQ2: length 58.7
  TOP w0.089: v1(128,24.39) v2(128,24.96)
  L4 w0.14: v1(90.45,36.48) 90.65,36.48 94.56,32.56 95.25,32.13 97.76,29.62 98.51,29.62 98.65,29.76 98.65,30.01 98.79,30.15 99.07,30.15 99.21,30.01 99.21,29.76 99.35,29.62 99.63,29.62 99.77,29.76 99.77,30.01 99.91,30.15 100.19,30.15 100.33,30.01 100.33,29.76 100.47,29.62 100.75,29.62 100.89,29.76 100.89,30.01 101.03,30.15 101.31,30.15 101.45,30.01 101.45,29.76 101.59,29.62 102.26,29.62 102.47,29.41 108.56,29.41 108.76,29.62 110.3,29.62 110.83,30.15 112.27,30.15 118.36,24.06 122.43,24.06 122.89,23.6 125.86,23.6 126.11,23.85 128.3,23.85 129.03,23.12 129.77,23.12 130.07,23.42 130.07,24.59 129.69,24.97 128.58,24.97 v1(128,24.39)
  BOTTOM w0.089: CPU1.A38 88.75,37.95 89.51,37.19 90.07,37.19 90.45,36.81 v1(90.45,36.48) ; DIMM1.20 128.48,24.87 v1(128,24.39)
M_A_DQ3: length 60.8
  TOP w0.089: v1(123.98,24.54) 123.98,24.11 123.98,23.98 v2(123.98,23.98)
  L4 w0.14: v1(123.98,24.54) 123.98,24.58 123.53,25.02 118.67,25.02 111.86,31.83 110.54,31.83 110.4,31.69 110.4,31.41 110.26,31.27 109.95,31.27 109.81,31.41 109.81,31.69 109.67,31.83 109.42,31.83 109.28,31.69 109.28,31.41 109.14,31.27 108.84,31.27 108.69,31.41 108.69,31.69 108.56,31.83 108.3,31.83 108.16,31.69 108.16,31.41 108.02,31.27 107.75,31.27 107.58,31.44 107.58,31.69 107.44,31.83 107.18,31.83 107.04,31.69 107.04,31.41 106.9,31.27 106.6,31.27 106.46,31.41 106.46,31.69 106.32,31.83 106.07,31.83 105.93,31.69 105.93,31.41 105.79,31.27 105.49,31.27 105.34,31.41 105.34,31.69 105.2,31.83 104.95,31.83 104.81,31.69 104.81,31.41 104.67,31.27 104.37,31.27 104.22,31.41 104.22,31.69 104.08,31.83 103.83,31.83 103.69,31.69 103.69,31.41 103.55,31.27 103.25,31.27 103.11,31.41 103.11,31.69 102.97,31.83 102.71,31.83 102.57,31.69 102.57,31.41 102.43,31.27 102.13,31.27 101.99,31.41 101.99,31.69 101.85,31.83 101.22,31.83 100.66,31.27 97.38,31.27 95.55,33.1 95,33.35 90.45,37.9 90.45,38.51 90.03,38.93 90.03,39.13 90.69,39.79 90.69,39.99 90.3,40.39 90.1,40.39 89.44,39.72 89.24,39.72 88.85,40.11 88.39,40.11 87.78,39.5 87.78,39.14 89.31,37.61 v1(89.73,37.61)
  BOTTOM w0.089: v1(123.98,24.54) 123.98,24.54 123.39,25.12 DIMM1.21 ; v1(89.73,37.61) 88.98,38.36 88.98,39.16 89.06,39.26 89.06,39.5 88.75,39.82 CPU1.B38
M_A_DQ4: length 58.8
  TOP w0.089: v2(127.59,19.91) 127.59,19.91 127.98,20.3 v1(127.99,20.3)
  L4 w0.14: v1(127.99,20.3) 126.52,20.3 125.88,20.27 125.66,20.23 125.44,20.14 125.25,20.01 124.86,19.62 124.36,19.46 120.6,19.46 117.65,20.12 112.7,25.07 97.66,25.07 94.73,27.33 88.29,27.33 86.31,29.31 86.31,32.23 86.78,33.8 86.78,37.03 86.28,37.54 v1(86.1,37.54)
  BOTTOM w0.089: CPU1.A33 85.87,38.53 85.87,38.1 85.9,37.97 v1(86.1,37.54) ; DIMM1.4 128.75,20.87 128.52,20.81 128.4,20.77 128.29,20.74 v1(127.99,20.3)
M_A_DQ5: length 60.6
  L4 w0.14: v1(86.31,36.91) 86.31,33.89 86.06,33.63 86.06,29.19 88.37,26.87 94.54,26.87 96.8,24.61 112.52,24.61 118.14,19 119.08,19 119.22,18.86 119.22,18.23 119.39,18.06 119.78,18.06 119.92,18.2 119.92,18.84 120.08,19 120.48,19 120.62,18.86 120.62,18.23 120.78,18.06 121.18,18.06 121.32,18.2 121.32,18.84 121.48,19 122.2,19 122.38,18.82 122.38,18.29 122.65,18.02 123.53,18.02 123.83,18.32 v1(123.83,18.92)
  BOTTOM w0.089: v1(123.83,18.92) 123.83,19.56 122.76,20.63 DIMM1.3 ; v1(86.31,36.91) 86.17,36.91 85.94,37.14 85.93,37.14 85.67,37.4 85.67,39.17 85.75,39.25 85.75,39.47 CPU1.B33
M_A_DQ6: length 58.9
  TOP w0.089: v1(126.59,22.35) v2(126.59,23)
  L4 w0.14: v1(88.93,36.88) 88.93,36.88 89.72,36.1 90.25,36.1 94.22,32.12 94.83,31.76 97.42,29.17 97.93,29.17 98.07,29.03 98.07,28.74 98.21,28.6 98.49,28.6 98.63,28.74 98.63,29.03 98.77,29.17 99.05,29.17 99.19,29.03 99.19,28.74 99.33,28.6 99.6,28.6 99.74,28.74 99.74,29.03 99.88,29.17 100.16,29.17 100.3,29.03 100.3,28.74 100.44,28.6 100.72,28.6 100.86,28.74 100.86,29.03 101,29.17 101.64,29.17 101.88,28.93 102.5,28.93 102.64,28.79 102.64,28.69 102.78,28.55 103.06,28.55 103.2,28.69 103.2,28.79 103.34,28.93 108.71,28.93 108.95,29.17 109.7,29.17 109.84,29.03 109.84,28.44 109.98,28.3 110.26,28.3 110.4,28.44 110.4,29.07 110.59,29.26 110.87,29.26 111.01,29.12 111.01,28.67 111.15,28.53 111.4,28.53 111.54,28.67 111.54,29.5 111.68,29.64 111.96,29.64 112.12,29.48 112.12,28.87 112.26,28.73 113.06,28.73 118.19,23.6 122.25,23.6 122.71,23.14 124.69,23.14 125.12,22.7 125.6,22.7 126.03,23.14 126.66,23.14 126.8,23 126.8,22.56 v1(126.59,22.35)
  BOTTOM w0.089: v1(126.59,22.35) 126.59,22.71 127.76,23.87 DIMM1.16 ; v1(88.93,36.88) 88.9,36.91 88.61,36.91 88.2,37.32 CPU1.A37
M_A_DQ7: length 61
  TOP w0.089: v2(125.32,23.95) 125.32,24.02 v1(125.32,24.51)
  L4 w0.14: v1(89.87,36.73) 90.25,37.11 90.68,37.11 94.89,32.9 95.5,32.52 97.41,30.61 97.72,30.61 97.9,30.79 98.28,30.79 98.45,30.61 98.84,30.61 99.01,30.79 99.39,30.79 99.57,30.61 99.95,30.61 100.13,30.79 100.51,30.79 100.69,30.61 101.07,30.61 101.43,30.96 101.81,30.96 102.16,30.61 102.68,30.61 102.82,30.47 102.82,30.01 102.96,29.87 103.25,29.87 103.4,30.02 103.4,30.67 103.54,30.81 103.82,30.81 103.96,30.67 103.96,30.01 104.1,29.87 104.38,29.87 104.52,30.01 104.52,30.67 104.66,30.81 104.94,30.81 105.08,30.67 105.08,30.01 105.22,29.87 105.5,29.87 105.64,30.01 105.64,30.67 105.77,30.81 106.13,30.81 106.27,30.67 106.27,29.99 106.38,29.87 106.69,29.87 106.83,30.01 106.83,30.67 106.97,30.81 107.24,30.81 107.39,30.66 107.39,29.99 107.5,29.87 107.81,29.87 107.95,30.01 107.95,30.67 108.09,30.81 108.31,30.81 108.48,30.65 108.48,30.22 108.62,30.08 108.87,30.08 109.04,30.24 109.04,30.67 109.18,30.81 109.43,30.81 109.57,30.67 109.57,30.22 109.71,30.08 109.97,30.08 110.11,30.22 110.11,30.47 110.25,30.61 110.73,30.61 110.87,30.75 110.87,31.23 111.01,31.37 111.29,31.37 111.43,31.23 111.43,30.75 111.57,30.61 112.45,30.61 118.54,24.51 122.61,24.51 123.06,24.06 124.87,24.06 v1(125.32,24.51)
  BOTTOM w0.089: v1(125.32,24.51) 124.84,24.03 121.99,24.03 DIMM1.17 ; CPU1.B37 88.2,39.47 88.51,39.15 88.51,37.45 88.67,37.29 89.1,37.29 89.66,36.73 v1(89.87,36.73)
M_A_DQ8: length 46.8
  TOP w0.089: v1(92.28,39.07) v2(92.28,38.51)
  L4 w0.14: v1(127.99,26.39) 127.99,26.11 127.76,25.88 126.01,25.88 125.76,26.14 125.76,26.65 125.02,27.38 119.33,27.38 112.7,34.01 104.11,34.01 103.53,34.6 96.6,34.6 96.44,34.75 95.93,35.2 95.6,35.44 95.26,35.62 94.79,36.1 94.35,36.39 92.66,38.08 92.66,38.69 v1(92.28,39.07)
  BOTTOM w0.089: v1(92.28,39.07) 92.22,39.01 91.69,39.01 91.08,39.62 CPU1.B41 ; v1(127.99,26.39) 127.99,26.41 128.45,26.87 DIMM1.28
M_A_DQ9: length 49.1
  TOP w0.089: v2(91.33,39.83) v1(91.85,39.57)
  L4 w0.14: v1(91.85,39.57) 91.62,39.35 91.62,38.86 91.68,38.7 92.18,38.2 92.25,38 95.13,35.13 96.13,34.43 96.42,34.14 97.41,34.14 97.55,34 97.55,33.62 97.69,33.48 97.97,33.48 98.11,33.62 98.11,34 98.25,34.14 98.53,34.14 98.67,34 98.67,33.52 98.81,33.38 99.09,33.38 99.23,33.52 99.23,34 99.36,34.14 99.64,34.14 99.78,34 99.78,33.59 99.92,33.45 100.2,33.45 100.34,33.59 100.34,34 100.48,34.14 100.76,34.14 100.9,34 100.9,33.67 101.04,33.53 101.32,33.53 101.46,33.67 101.46,34 101.6,34.14 101.88,34.14 102.02,34 102.02,33.67 102.16,33.53 102.44,33.53 102.58,33.67 102.58,34 102.72,34.14 103.23,34.14 103.4,33.96 103.4,33.71 103.58,33.53 112.55,33.53 119.15,26.93 123.86,26.93 124,26.79 v1(124,26.44)
  BOTTOM w0.089: CPU1.C40 90.41,40.01 91.42,40.01 v1(91.85,39.57) ; DIMM1.29 123.63,27.12 124,26.75 v1(124,26.44)
M_A_DQ10: length 50.8
  TOP w0.089: v1(95.28,39.3) 95.28,39.3 95.69,39.71 v2(95.7,39.71)
  L4 w0.14: v1(124,29.75) 123.57,30.18 122.44,30.18 122.3,30.04 122.3,29.83 122.16,29.69 121.88,29.69 121.74,29.83 121.74,30.04 121.6,30.18 121.32,30.18 121.18,30.04 121.18,29.83 121.04,29.69 120.76,29.69 120.62,29.83 120.62,30.04 120.48,30.18 119.74,30.18 113,36.91 112.45,36.91 112.31,36.77 112.31,36.41 112.19,36.3 111.86,36.3 111.75,36.41 111.75,36.77 111.61,36.91 111.33,36.91 111.19,36.77 111.19,36.41 111.08,36.3 110.75,36.3 110.63,36.41 110.63,36.77 110.49,36.91 110.21,36.91 110.07,36.77 110.07,36.41 109.96,36.3 109.63,36.3 109.51,36.41 109.51,36.77 109.37,36.91 109.09,36.91 108.95,36.77 108.95,36.41 108.84,36.3 108.51,36.3 108.4,36.41 108.4,36.77 108.26,36.91 107.98,36.91 107.84,36.77 107.84,36.41 107.72,36.3 107.39,36.3 107.28,36.41 107.28,36.77 107.14,36.91 106.86,36.91 106.72,36.77 106.72,36.41 106.6,36.3 106.27,36.3 106.16,36.41 106.16,36.77 106.02,36.91 105.74,36.91 105.6,36.77 105.6,36.57 105.46,36.43 105.18,36.43 105.04,36.57 105.04,36.77 104.9,36.91 98.08,36.91 96.09,38 95.66,38.43 95.45,38.57 95.09,38.92 95.09,39.11 v1(95.28,39.3)
  BOTTOM w0.089: CPU1.F41 91.18,42.07 91.48,41.77 92.54,41.77 93.29,41.02 94.95,41.02 95.76,40.21 95.76,39.78 v1(95.28,39.3) ; v1(124,29.75) 124,29.95 123.72,30.23 123.16,30.23 123.06,30.12 DIMM1.41
M_A_DQ11: length 48.6
  TOP w0.089: v2(96.21,38.53) v1(95.81,38.91)
  L4 w0.14: v1(126.68,29.76) 126.73,29.76 127,30.02 127,30.42 126.86,30.56 125.2,30.56 124.95,30.3 124.64,30.3 124.39,30.56 123.88,30.56 123.65,30.63 119.91,30.63 113.18,37.37 98.18,37.37 96.29,38.44 v1(95.81,38.91)
  BOTTOM w0.089: v1(95.81,38.91) 96.24,39.35 96.24,40.29 95.19,41.34 93.24,41.34 92.62,41.96 91.59,41.96 91.29,42.26 90.61,42.26 90.25,42.62 CPU1.G40 ; DIMM1.42 127.3,30.38 v1(126.68,29.76)
M_A_DQ12: length 47.8
  TOP w0.089: v1(126.7,24.51) v2(126.7,25.07)
  L4 w0.14: v1(126.7,24.51) 124.28,25.48 122.83,25.48 121.26,26.01 118.8,26.01 112.19,32.62 100.89,32.62 100.36,32.08 97.53,32.08 97.11,32.18 95.73,33.56 95.02,33.96 91.19,37.79 v1(91.19,38.19)
  BOTTOM w0.089: v1(91.19,38.19) 91.19,38.19 90.75,38.1 90.47,38.1 90.09,38.48 90.09,38.79 90.1,38.79 CPU1.A40 ; v1(126.7,24.51) 127.04,25.06 127.61,25.63 128.23,25.87 DIMM1.24
M_A_DQ13: length 49.5
  TOP w0.089: v2(90.63,38.83) v1(91.19,38.83)
  L4 w0.14: v1(91.19,38.83) 91.64,38.38 91.64,37.97 94.06,35.56 95.21,34.41 95.91,34.01 96.85,33.07 97.38,33.07 97.52,32.93 97.52,32.68 97.66,32.54 97.94,32.54 98.08,32.68 98.08,32.88 98.22,33.02 98.47,33.02 98.61,32.88 98.61,32.7 98.77,32.54 99.03,32.54 99.17,32.68 99.17,32.83 99.31,32.97 99.59,32.97 99.73,32.83 99.73,32.7 99.89,32.54 100.17,32.54 100.31,32.68 100.31,32.93 100.45,33.07 112.37,33.07 118.97,26.47 122.48,26.47 123.01,25.94 125.13,25.94 125.27,26.07 v1(125.27,26.44)
  BOTTOM w0.089: CPU1.B40 90.58,39.14 90.58,38.99 90.3,38.71 90.3,38.55 90.54,38.31 90.67,38.31 v1(91.19,38.83) ; DIMM1.25 122.95,26.12 123.09,25.99 123.88,25.99 124.28,25.58 125.04,25.58 125.27,25.81 125.27,26.44 v1(125.27,26.44)
M_A_DQ14: length 47.3
  TOP w0.089: v2(94.41,40.65) v1(94.01,40.26)
  L4 w0.14: v1(127.99,29.8) 127.99,30.24 128.13,30.38 128.91,30.38 129.05,30.52 129.05,30.88 128.91,31.02 124.14,31.02 123.8,31.09 120.09,31.09 113.36,37.82 98.52,37.82 98.26,37.95 96.8,38.66 96.18,39.28 95.46,39.89 94.95,40.11 v1(94.01,40.26)
  BOTTOM w0.089: DIMM1.38 129.08,29.38 128.85,29.29 128.45,29.29 128.36,29.38 v1(127.99,29.8) ; CPU1.E41 90.83,41.39 92.37,41.39 93.31,40.46 v1(94.01,40.26)
M_A_DQ15: length 50.4
  TOP w0.089: v2(94.61,39.09) v1(94.74,39.65)
  L4 w0.14: v1(94.74,39.65) 94.49,39.91 94.29,39.91 93.99,39.61 93.99,39.39 95.21,38.17 95.4,38.05 95.84,37.61 96.88,37.01 97.58,36.46 104.43,36.46 105.05,35.84 113.44,35.84 120.07,29.21 125.43,29.21 125.57,29.35 125.57,29.65 v1(125.32,29.9)
  BOTTOM w0.089: CPU1.F40 89.88,42.07 90.18,41.77 90.53,41.77 90.62,41.86 91.11,41.86 91.39,41.58 92.46,41.58 93.29,40.74 94.82,40.74 95.22,40.34 95.22,39.88 95,39.65 v1(94.74,39.65) ; v1(125.32,29.9) 125.58,29.64 125.58,29.26 125.35,29.03 124.35,29.03 124.26,29.12 124.26,29.17 124.15,29.29 123.82,29.29 123.73,29.2 123.73,29.12 123.64,29.03 123.06,29.03 122.97,29.12 DIMM1.37
M_A_DQ16: length 46.9
  TOP w0.089: v1(127.04,31.59) v2(127.04,31.03)
  L4 w0.14: v1(94.73,42.16) 94.73,42.16 95.2,41.68 95.73,41.68 97.49,39.93 99.24,39.93 99.39,40.08 101.17,40.08 101.68,39.57 105.51,39.57 106.02,40.08 113.49,40.08 120.57,33 125.17,33 126.15,32.02 126.61,32.02 v1(127.04,31.59)
  BOTTOM w0.089: v1(127.04,31.59) 127.04,31.72 127.7,32.38 DIMM1.50 ; CPU1.J40 90.25,43.72 90.59,43.38 92.01,43.38 93.08,42.31 93.53,42.31 93.9,42.67 94.22,42.67 v1(94.73,42.16)
M_A_DQ17: length 48.1
  TOP w0.089: v2(92.73,42.72) 92.74,42.71 v1(93.36,42.71)
  L4 w0.14: v1(93.36,42.71) 92.67,42.71 92.28,42.32 92.28,41.63 93.22,40.69 95.4,40.69 97.04,39.05 98.3,38.64 106.38,38.64 106.52,38.77 106.52,39.03 106.66,39.17 106.94,39.17 107.08,39.03 107.08,38.77 107.22,38.64 107.5,38.64 107.64,38.77 107.64,39.03 107.78,39.17 108.06,39.17 108.2,39.03 108.2,38.77 108.34,38.64 108.62,38.64 108.76,38.77 108.76,39.03 108.9,39.17 109.18,39.17 109.31,39.03 109.31,38.77 109.45,38.64 109.73,38.64 109.87,38.77 109.87,39.03 110.01,39.17 110.29,39.17 110.43,39.03 110.43,38.77 110.57,38.64 110.85,38.64 110.99,38.77 110.99,39.03 111.13,39.17 111.41,39.17 111.55,39.03 111.55,38.77 111.69,38.64 111.97,38.64 112.11,38.77 112.11,39.03 112.25,39.17 112.53,39.17 112.67,39.03 112.67,38.77 112.81,38.64 113.64,38.64 120.19,32.08 123.57,32.08 v1(123.98,31.68)
  BOTTOM w0.089: CPU1.J41 90.84,43.58 92.5,43.58 v1(93.36,42.71) ; v1(123.98,31.68) 123.8,31.85 123.8,31.9 123.55,32.16 123.14,32.16 123.13,32.15 123.03,32.15 123,32.12 DIMM1.49
M_A_DQ18: length 45.9
  L4 w0.14: v1(93.97,44.77) 93.97,45.07 94.13,45.24 94.56,45.24 94.72,45.09 94.72,44.17 94.99,43.9 102.46,43.9 103.51,43.38 115.32,43.38 122.07,36.63 126.34,36.63 v1(128.02,34.95)
  BOTTOM w0.089: DIMM1.62 128.39,35.38 128.02,35 v1(128.02,34.95) ; CPU1.N40 90.25,45.92 90.55,45.62 90.82,45.62 90.86,45.66 93.08,45.66 v2(93.48,45.26) v1(93.97,44.77)
M_A_DQ19: length 49
  TOP w0.089: v1(126.36,37.11) v2(126.36,36.55)
  L4 w0.14: v1(95.05,45.59) 95.05,44.5 95.2,44.35 102.77,44.35 103.58,44.05 115.29,44.05 115.68,43.66 115.87,43.66 116.12,43.91 116.32,43.91 116.52,43.71 116.52,43.51 116.27,43.26 116.27,43.07 116.47,42.87 116.67,42.87 116.91,43.12 117.11,43.12 117.31,42.92 117.31,42.72 117.06,42.47 117.06,42.28 122.25,37.09 126.34,37.09 v1(126.36,37.11)
  BOTTOM w0.089: CPU1.N41 93.38,45.92 93.5,45.8 94.01,45.8 94.16,45.65 94.16,45.24 94.54,44.86 95.18,44.86 95.29,44.97 95.29,45.35 v1(95.05,45.59) ; DIMM1.63 124.88,35.63 v1(126.36,37.11)
M_A_DQ20: length 47
  TOP w0.089: v2(95.81,41.76) v1(95.39,42.17)
  L4 w0.14: v1(95.39,42.17) 95.89,42.17 97.66,40.39 99.03,40.39 99.19,40.54 101.35,40.54 101.85,40.03 105.33,40.03 105.84,40.54 113.67,40.54 120.75,33.45 125.43,33.45 126.34,32.54 126.85,32.54 v1(127.76,31.62)
  BOTTOM w0.089: CPU1.H40 89.93,43.17 90.22,42.87 90.5,42.87 90.59,42.96 91.89,42.96 93.22,41.63 94.86,41.63 v1(95.39,42.17) ; v1(127.76,31.62) 128.09,31.29 128.91,31.29 128.98,31.37 129.01,31.37 129.01,31.38 DIMM1.46
M_A_DQ21: length 48.6
  TOP w0.089: v1(94.09,42.19) v2(93.68,41.81)
  L4 w0.14: v1(94.09,42.19) 93.18,42.19 92.99,42 92.99,41.37 93.18,41.18 95.58,41.18 97.21,39.54 97.62,39.39 98.66,39.12 99.29,39.12 99.43,39.26 99.43,39.49 99.57,39.63 99.85,39.63 99.99,39.49 99.99,39.26 100.13,39.12 100.41,39.12 100.55,39.26 100.55,39.49 100.69,39.63 100.97,39.63 101.11,39.49 101.11,39.26 101.25,39.12 105.69,39.12 106.2,39.63 113.31,39.63 120.4,32.54 124.97,32.54 125.27,32.23 v1(125.27,31.62)
  BOTTOM w0.089: v1(94.09,42.19) 93.96,42.06 93.06,42.06 91.96,43.17 CPU1.H41 ; DIMM1.45 124.16,31.12 124.2,31.09 124.79,31.09 125.27,31.57 v1(125.27,31.62)
M_A_DQ22: length 46.5
  TOP w0.089: v2(127.86,34.39) v1(127.86,33.83)
  L4 w0.14: v1(127.86,33.83) 127.66,34.49 125.98,36.17 121.89,36.17 115.16,42.9 103.45,42.9 102.13,43.44 94.7,43.44 93.24,44.89 93.24,44.91 92.99,45.16 92.55,45.16 v1(92.15,44.77)
  BOTTOM w0.089: v1(92.15,44.77) 91.85,45.07 91.57,45.17 90.63,45.17 90.52,45.06 90.22,45.06 CPU1.M40 ; DIMM1.58 130.09,34.37 128.27,34.37 128.14,34.24 v1(127.86,33.83)
M_A_DQ23: length 48.3
  TOP w0.089: v1(127.23,33.83) v2(127.23,33.28)
  L4 w0.14: v1(127.23,33.83) 127.23,34.29 125.81,35.71 121.72,35.71 114.99,42.45 103.1,42.45 101.8,42.98 94.06,42.98 92.8,44.24 v1(92.8,44.73)
  BOTTOM w0.089: v1(92.8,44.73) 92.8,44.79 92.22,45.37 CPU1.M41 ; v1(127.23,33.83) 127.13,33.83 126.34,34.63 DIMM1.59
M_A_DQ24: length 46.6
  TOP w0.089: v1(128.02,36.91) v2(128.02,37.47)
  L4 w0.14: v1(128.02,36.91) 128.02,37.19 127.9,37.45 127.3,38.06 126.82,38.37 125.63,38.9 124.94,39.09 124.51,39.3 123.9,39.63 122.76,39.63 120.68,41.71 120.68,43.5 120.39,44.55 118.71,46.24 117.84,46.33 97.31,46.33 96.34,46.08 94.68,46.08 94.17,46.22 92.75,46.22 v1(92,46.97)
  BOTTOM w0.089: v1(92,46.97) 91.68,46.72 91.47,46.62 90.93,46.62 90.59,46.74 CPU1.R40 ; DIMM1.70 128.48,37.38 v1(128.02,36.91)
M_A_DQ25: length 49.6
  TOP w0.089: v2(97.1,44.96) v1(96.88,45.52)
  L4 w0.14: v1(123.98,38.15) 123.42,38.71 122.4,38.71 119.76,41.35 119.76,42.08 119.62,42.22 118.96,42.22 118.82,42.36 118.82,42.64 118.96,42.78 119.62,42.78 119.76,42.91 119.76,43.26 119.55,43.47 118.58,43.47 117.68,44.37 117.68,44.57 117.93,44.82 117.93,45.01 117.73,45.21 117.53,45.21 117.3,44.98 117.1,44.98 116.81,45.27 97.12,45.27 v1(96.88,45.52)
  BOTTOM w0.089: v1(123.98,38.15) 123.98,38 123.6,37.63 DIMM1.71 ; v1(96.88,45.52) 96.88,46.12 96.99,46.23 98.26,46.23 98.35,46.32 98.35,46.98 98.26,47.07 98.02,47.07 97.93,46.98 97.93,46.8 97.84,46.71 97.57,46.71 97.48,46.8 97.48,46.98 97.39,47.07 97.13,47.07 97.04,46.98 97.04,46.8 96.95,46.71 96.68,46.71 96.59,46.8 96.59,46.98 96.51,47.07 92.79,47.07 92.43,47.42 91,47.42 90.9,47.32 90.58,47.32 90.53,47.27 90.2,47.27 89.9,47.57 CPU1.T40
M_A_DQ26: length 48.6
  TOP w0.089: v1(94.77,48.82) v2(95.2,48.47)
  L4 w0.14: v1(94.77,48.82) 95.05,48.64 95.38,48.46 120.14,48.46 122.5,46.1 122.5,44.3 123.19,43.61 125.67,43.61 125.81,43.47 125.81,42.76 125.67,42.62 123.75,42.62 123.57,42.45 123.57,42.03 123.71,41.89 123.95,41.89 124.13,41.71 v1(124.13,41.4)
  BOTTOM w0.089: v1(94.77,48.82) 94.78,48.83 95,48.83 95.12,48.95 95.12,49.4 95,49.53 94.16,49.53 93.62,49 92.54,49 92.3,48.76 91.03,48.76 90.92,48.87 90.6,48.87 90.25,49.22 CPU1.W40 ; DIMM1.83 123.68,40.63 124.13,41.07 v1(124.13,41.4)
M_A_DQ27: length 46.5
  TOP w0.089: v1(128.01,41.42) v2(128.01,41.98)
  L4 w0.14: v1(128.01,41.42) 127.24,44.92 126.56,45.59 125.98,45.82 125.1,45.82 124.59,45.92 120.62,49.89 94.51,49.89 v1(91.92,49.16)
  BOTTOM w0.089: DIMM1.84 128.66,40.87 128.42,40.96 128.01,41.37 v1(128.01,41.42) ; CPU1.Y40 90.18,49.47 90.49,49.47 90.55,49.53 90.98,49.53 91.08,49.63 91.45,49.63 v1(91.92,49.16)
M_A_DQ28: length 46.3
  L4 w0.14: v1(95.83,45.47) 95.83,45.19 96.22,44.81 116.59,44.81 118.34,43.05 118.34,42.14 122.86,37.62 127.09,37.62 127.53,37.18 127.53,36.35 v1(128.02,35.87)
  BOTTOM w0.089: v1(128.02,35.87) 128.02,35.99 128.4,36.38 DIMM1.66 ; v1(95.83,45.47) 95.09,46.22 v2(94.44,46.22) 90.58,46.22 90.53,46.17 90.2,46.17 89.9,46.47 CPU1.P40
M_A_DQ29: length 49.2
  TOP w0.089: v1(97.51,45.75) v2(98.07,45.75)
  L4 w0.14: v1(125.33,38.18) 124.99,38.51 124.87,38.64 124.16,38.64 123.62,39.17 122.58,39.17 120.22,41.53 120.22,43.44 119.6,44.06 119.6,44.26 119.72,44.38 119.72,44.57 119.52,44.77 119.32,44.77 118.88,44.33 118.68,44.33 118.47,44.55 118.47,44.71 118.92,45.17 118.92,45.36 118.73,45.56 118.53,45.56 118.41,45.44 118.21,45.44 117.78,45.87 97.64,45.87 v1(97.51,45.75)
  BOTTOM w0.089: v1(125.33,38.18) 125.33,37.85 124.1,36.63 DIMM1.67 ; v1(97.51,45.75) 97.84,45.42 97.84,44.99 97.71,44.86 96.42,44.86 96.29,44.99 96.29,46.48 96.14,46.64 92.43,46.64 92.22,46.42 90.4,46.42 CPU1.P41
M_A_DQ30: length 48.9
  TOP w0.089: v2(125.86,41.81) v1(125.45,41.4)
  L4 w0.14: v1(125.45,41.4) 126.34,42.29 126.34,44.21 126.2,44.35 125.59,44.35 125.31,44.07 123.37,44.07 122.96,44.48 122.96,46.28 120.32,48.92 95.73,48.92 v1(95.71,48.95)
  BOTTOM w0.089: v1(125.45,41.4) 125.45,40.79 124.28,39.63 DIMM1.79 ; CPU1.V40 89.93,48.67 90.23,48.37 90.53,48.37 90.58,48.42 90.82,48.42 90.86,48.38 95.47,48.38 95.71,48.62 v1(95.71,48.95)
M_A_DQ31: length 47
  TOP w0.089: v1(126.68,41.39) v2(126.68,40.83)
  L4 w0.14: v1(126.68,41.39) 126.8,41.5 126.8,44.6 126.21,45.19 124.69,45.19 120.45,49.43 94.74,49.43 v1(94.13,48.82)
  BOTTOM w0.089: v1(126.68,41.39) 126.68,40.96 127.77,39.87 DIMM1.80 ; v1(94.13,48.82) 93.83,48.82 93.65,48.64 92.94,48.64 92.86,48.57 90.95,48.57 90.84,48.67 CPU1.V41
M_A_DQ32: length 52
  TOP w0.089: v1(94.16,52.4) 93.77,52.79 v2(93.72,52.79)
  L4 w0.14: v1(94.16,52.4) 94.22,51.94 95.15,51 96.67,51 96.82,50.85 108.97,50.85 119.09,56.76 119.88,57.04 127.36,59.53 128.83,59.87 129.9,61.17 130.1,61.49 130.1,63.71 129.13,65.05 128.85,65.33 128.45,65.33 128.31,65.19 v1(127.99,64.77)
  BOTTOM w0.089: v1(127.99,64.77) 128.33,65.18 128.57,65.38 DIMM1.174 ; CPU1.AD41 90.53,52 93.42,52 v1(94.16,52.4)
M_A_DQ33: length 53.3
  TOP w0.089: v2(124.02,64.68) v1(124.33,64.14)
  L4 w0.14: v1(124.33,64.14) 124.33,63.98 123.98,63.63 120.04,63.63 119.61,63.2 119.61,63 120.11,62.5 120.11,62.31 119.92,62.11 119.72,62.11 119.22,62.61 119.02,62.61 118.82,62.41 118.82,62.21 119.32,61.71 119.32,61.52 119.13,61.32 118.93,61.32 118.43,61.82 118.23,61.82 118.03,61.62 118.03,61.42 118.53,60.92 118.53,60.72 118.34,60.53 118.14,60.53 117.64,61.03 117.44,61.03 117.24,60.83 117.24,60.63 117.74,60.13 117.74,59.93 117.55,59.74 117.35,59.74 116.85,60.24 116.65,60.24 116.45,60.04 116.45,59.84 116.95,59.34 116.95,59.14 116.75,58.95 116.56,58.95 116.06,59.45 115.86,59.45 115.66,59.25 115.66,59.05 116.29,58.42 116.29,58.23 116.12,58.05 115.92,58.05 115.32,58.66 114.99,58.66 111.58,55.25 108.35,53.15 93.97,53.15 93.25,52.43 v1(93.25,52.4)
  BOTTOM w0.089: CPU1.AD40 89.9,51.97 90.2,52.27 90.51,52.27 90.55,52.22 93.07,52.22 v1(93.25,52.4) ; DIMM1.173 122.71,65.13 122.86,64.97 123.52,64.97 124.33,64.16 v1(124.33,64.14)
M_A_DQ34: length 53.7
  TOP w0.089: v2(96.13,56.27) v1(95.91,55.73)
  L4 w0.14: v1(95.91,55.73) 96.57,56.39 98.25,56.39 98.65,55.98 104.88,55.98 105.41,56.52 105.61,56.52 105.92,56.21 106.12,56.21 106.32,56.41 106.32,56.61 106.01,56.92 106.01,57.11 106.21,57.32 106.41,57.32 106.81,56.92 107.01,56.92 107.2,57.12 107.2,57.31 106.8,57.71 106.8,57.91 107,58.11 107.2,58.11 107.6,57.71 107.8,57.71 107.99,57.91 107.99,58.11 107.6,58.5 107.6,58.7 107.79,58.9 107.99,58.9 108.39,58.5 108.59,58.5 108.79,58.7 108.79,58.9 108.39,59.3 108.39,59.49 108.58,59.69 108.78,59.69 109.18,59.29 109.38,59.29 109.58,59.49 109.58,59.69 109.18,60.09 109.18,60.28 109.37,60.48 109.57,60.48 109.97,60.08 110.17,60.08 110.37,60.28 110.37,60.48 109.97,60.88 109.97,61.07 110.16,61.27 110.36,61.27 110.76,60.87 110.96,60.87 111.16,61.07 111.16,61.27 110.76,61.67 110.76,61.86 110.95,62.06 111.15,62.06 111.55,61.66 112.38,61.66 117.68,66.96 123.47,66.96 123.55,66.88 124.05,66.88 124.46,67.29 v1(124.46,67.34)
  BOTTOM w0.089: CPU1.AH41 90.41,54.23 93.07,54.23 93.5,54.66 94.84,54.66 v1(95.91,55.73) ; DIMM1.187 123.91,68.62 124.46,68.07 v1(124.46,67.34)
M_A_DQ35: length 51.9
  TOP w0.089: v2(96.62,55.15) 96.61,55.16 v1(96.61,55.73)
  L4 w0.14: v1(96.61,55.73) 97,56.13 97.67,56.13 98.27,55.53 106.6,55.53 107.62,56.54 107.62,56.87 111.91,61.16 113.39,61.16 113.74,61.52 113.74,62.38 115.21,63.86 115.72,63.86 116.17,63.41 116.37,63.41 117.03,64.08 117.03,64.27 116.81,64.5 116.81,64.69 117.01,64.89 117.21,64.89 117.43,64.67 117.63,64.67 117.82,64.87 117.82,65.09 117.48,65.44 117.48,65.64 117.66,65.82 117.86,65.82 118.22,65.46 118.42,65.46 118.61,65.66 118.61,65.85 118.47,66 118.47,66.2 118.69,66.42 125.53,66.42 126.62,67.51 v1(126.62,67.74)
  BOTTOM w0.089: CPU1.AH40 89.9,54.17 90.2,54.47 90.51,54.47 90.55,54.42 92.83,54.42 93.4,54.99 94.46,54.99 95.72,56.25 96.45,56.25 96.61,56.09 v1(96.61,55.73) ; DIMM1.186 127.25,68.38 v1(126.62,67.74)
M_A_DQ36: length 51.7
  TOP w0.089: v1(128.02,63.86) v2(128.02,63.3)
  L4 w0.14: v1(91.97,51.34) 92.33,51.69 93.14,51.69 93.68,52.22 93.68,52.52 93.98,52.82 94.33,52.82 94.63,52.53 94.63,52.16 95.38,51.41 96.82,51.41 96.93,51.31 108.76,51.31 121.13,58.76 125.85,60.63 127.46,60.89 128.9,60.89 129.64,61.62 129.64,63.54 128.85,64.33 128.45,64.33 128.02,63.9 v1(128.02,63.86)
  BOTTOM w0.089: DIMM1.170 128.53,64.38 128.02,63.86 v1(128.02,63.86) ; CPU1.AB40 89.93,50.87 90.22,51.17 90.55,51.17 90.73,50.99 91.62,50.99 v1(91.97,51.34)
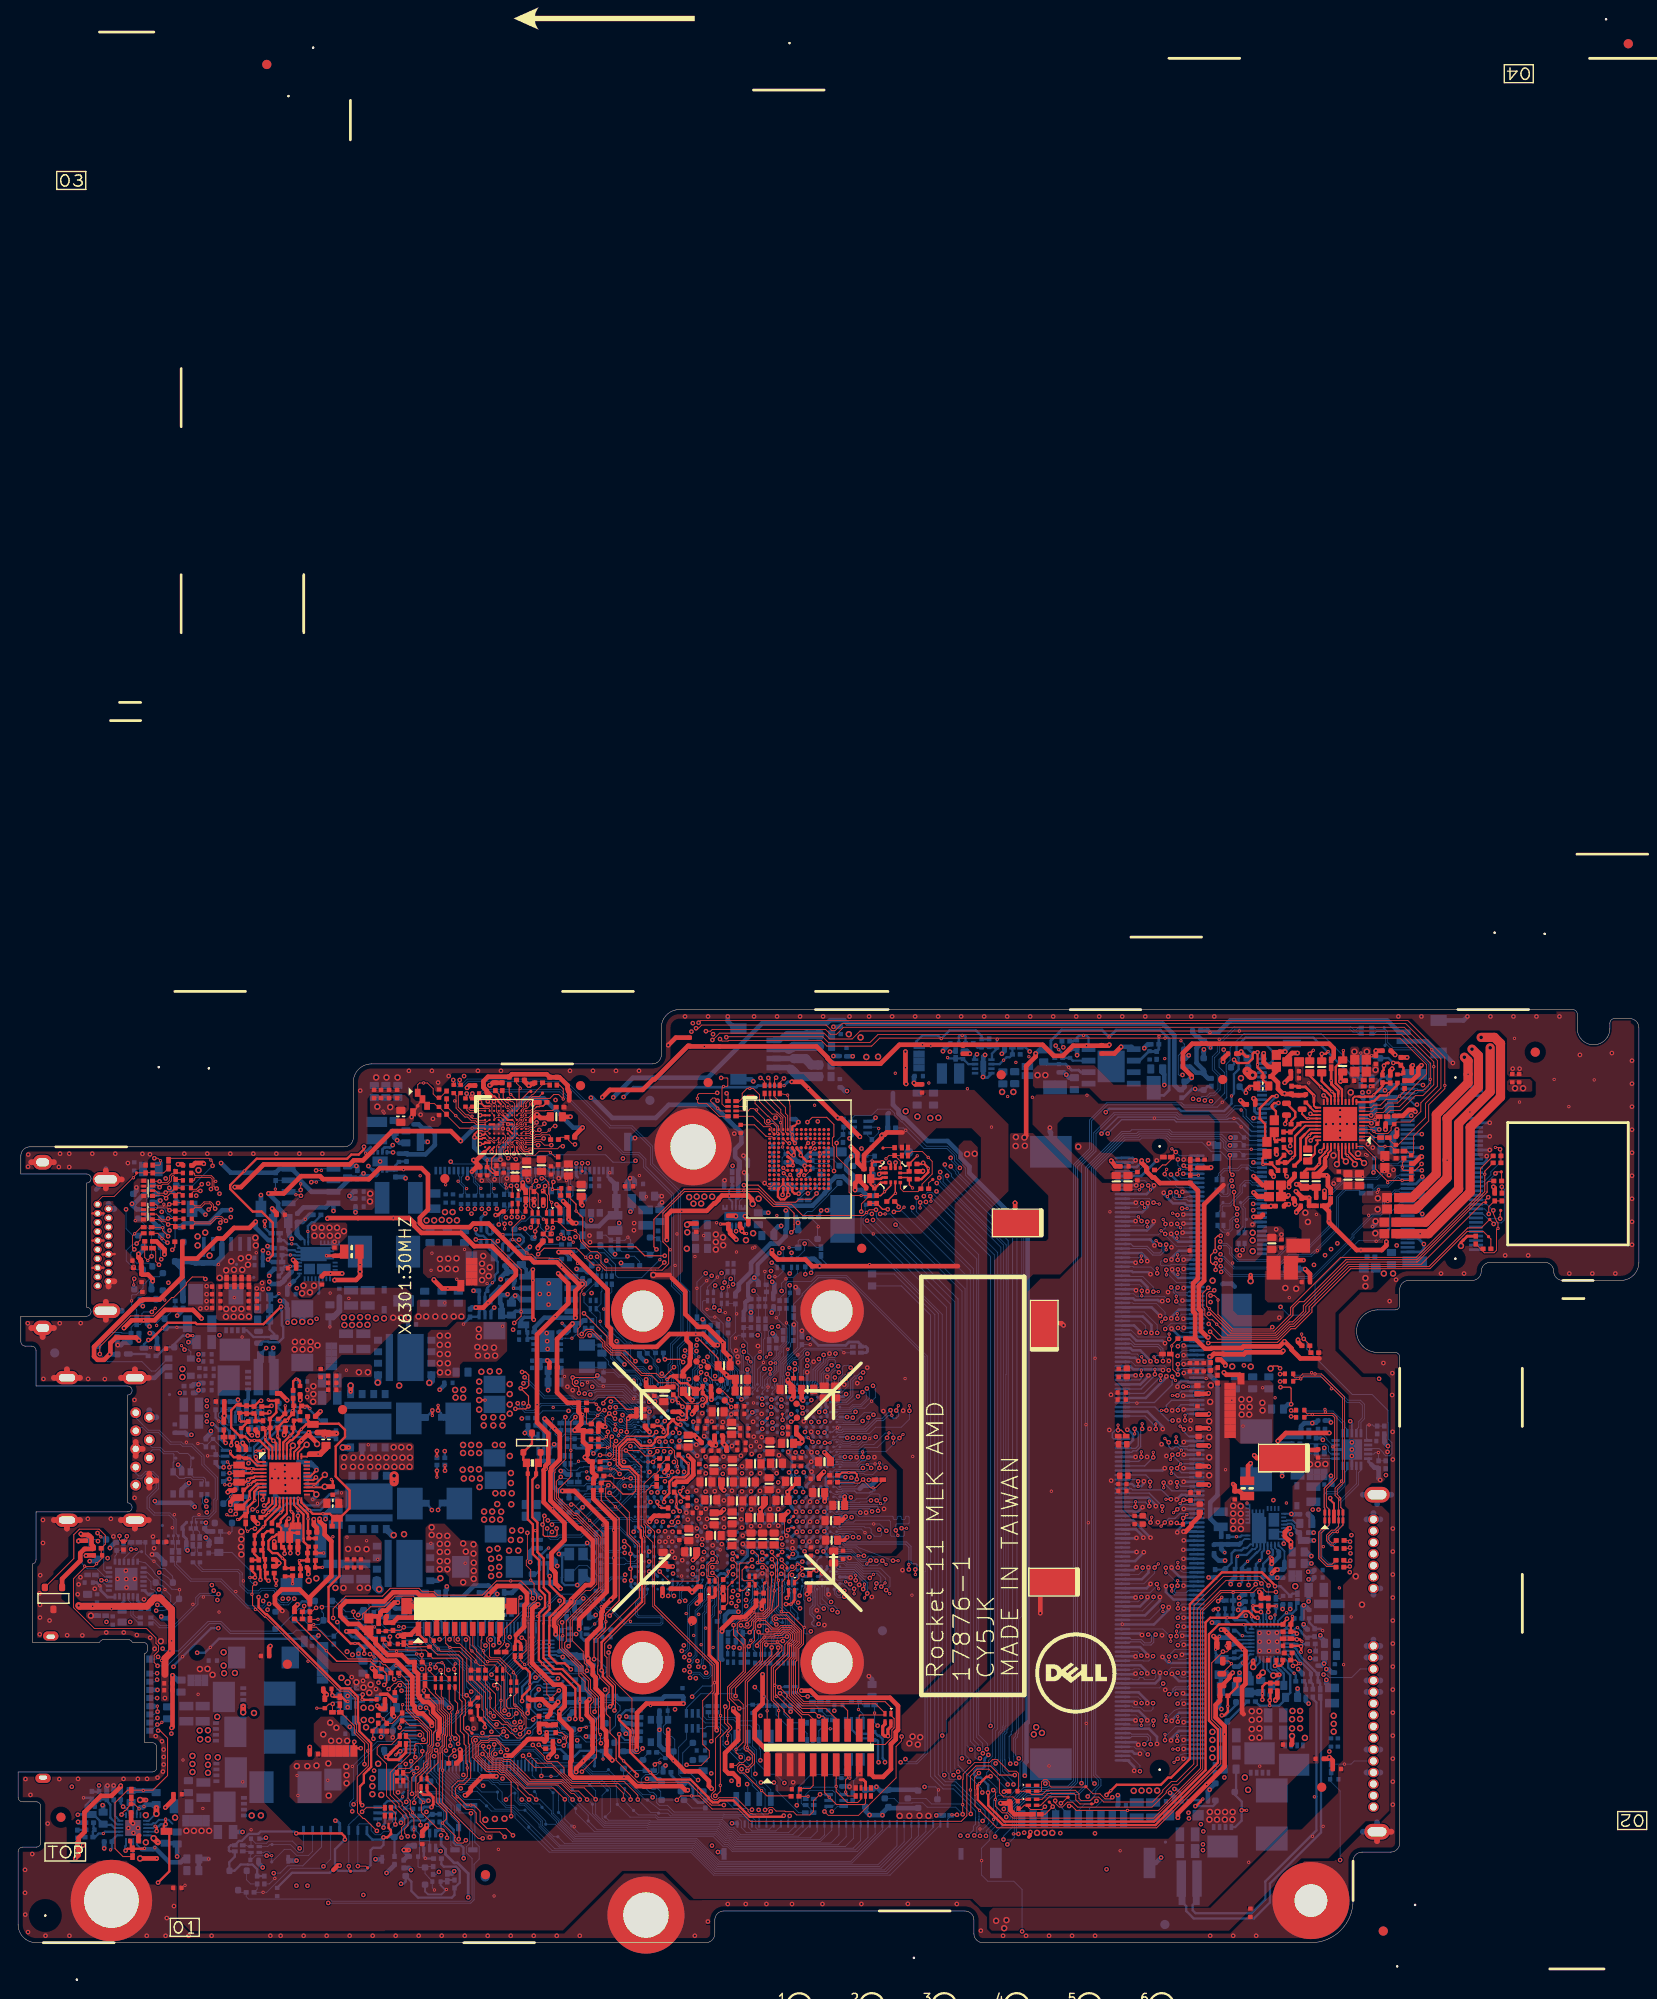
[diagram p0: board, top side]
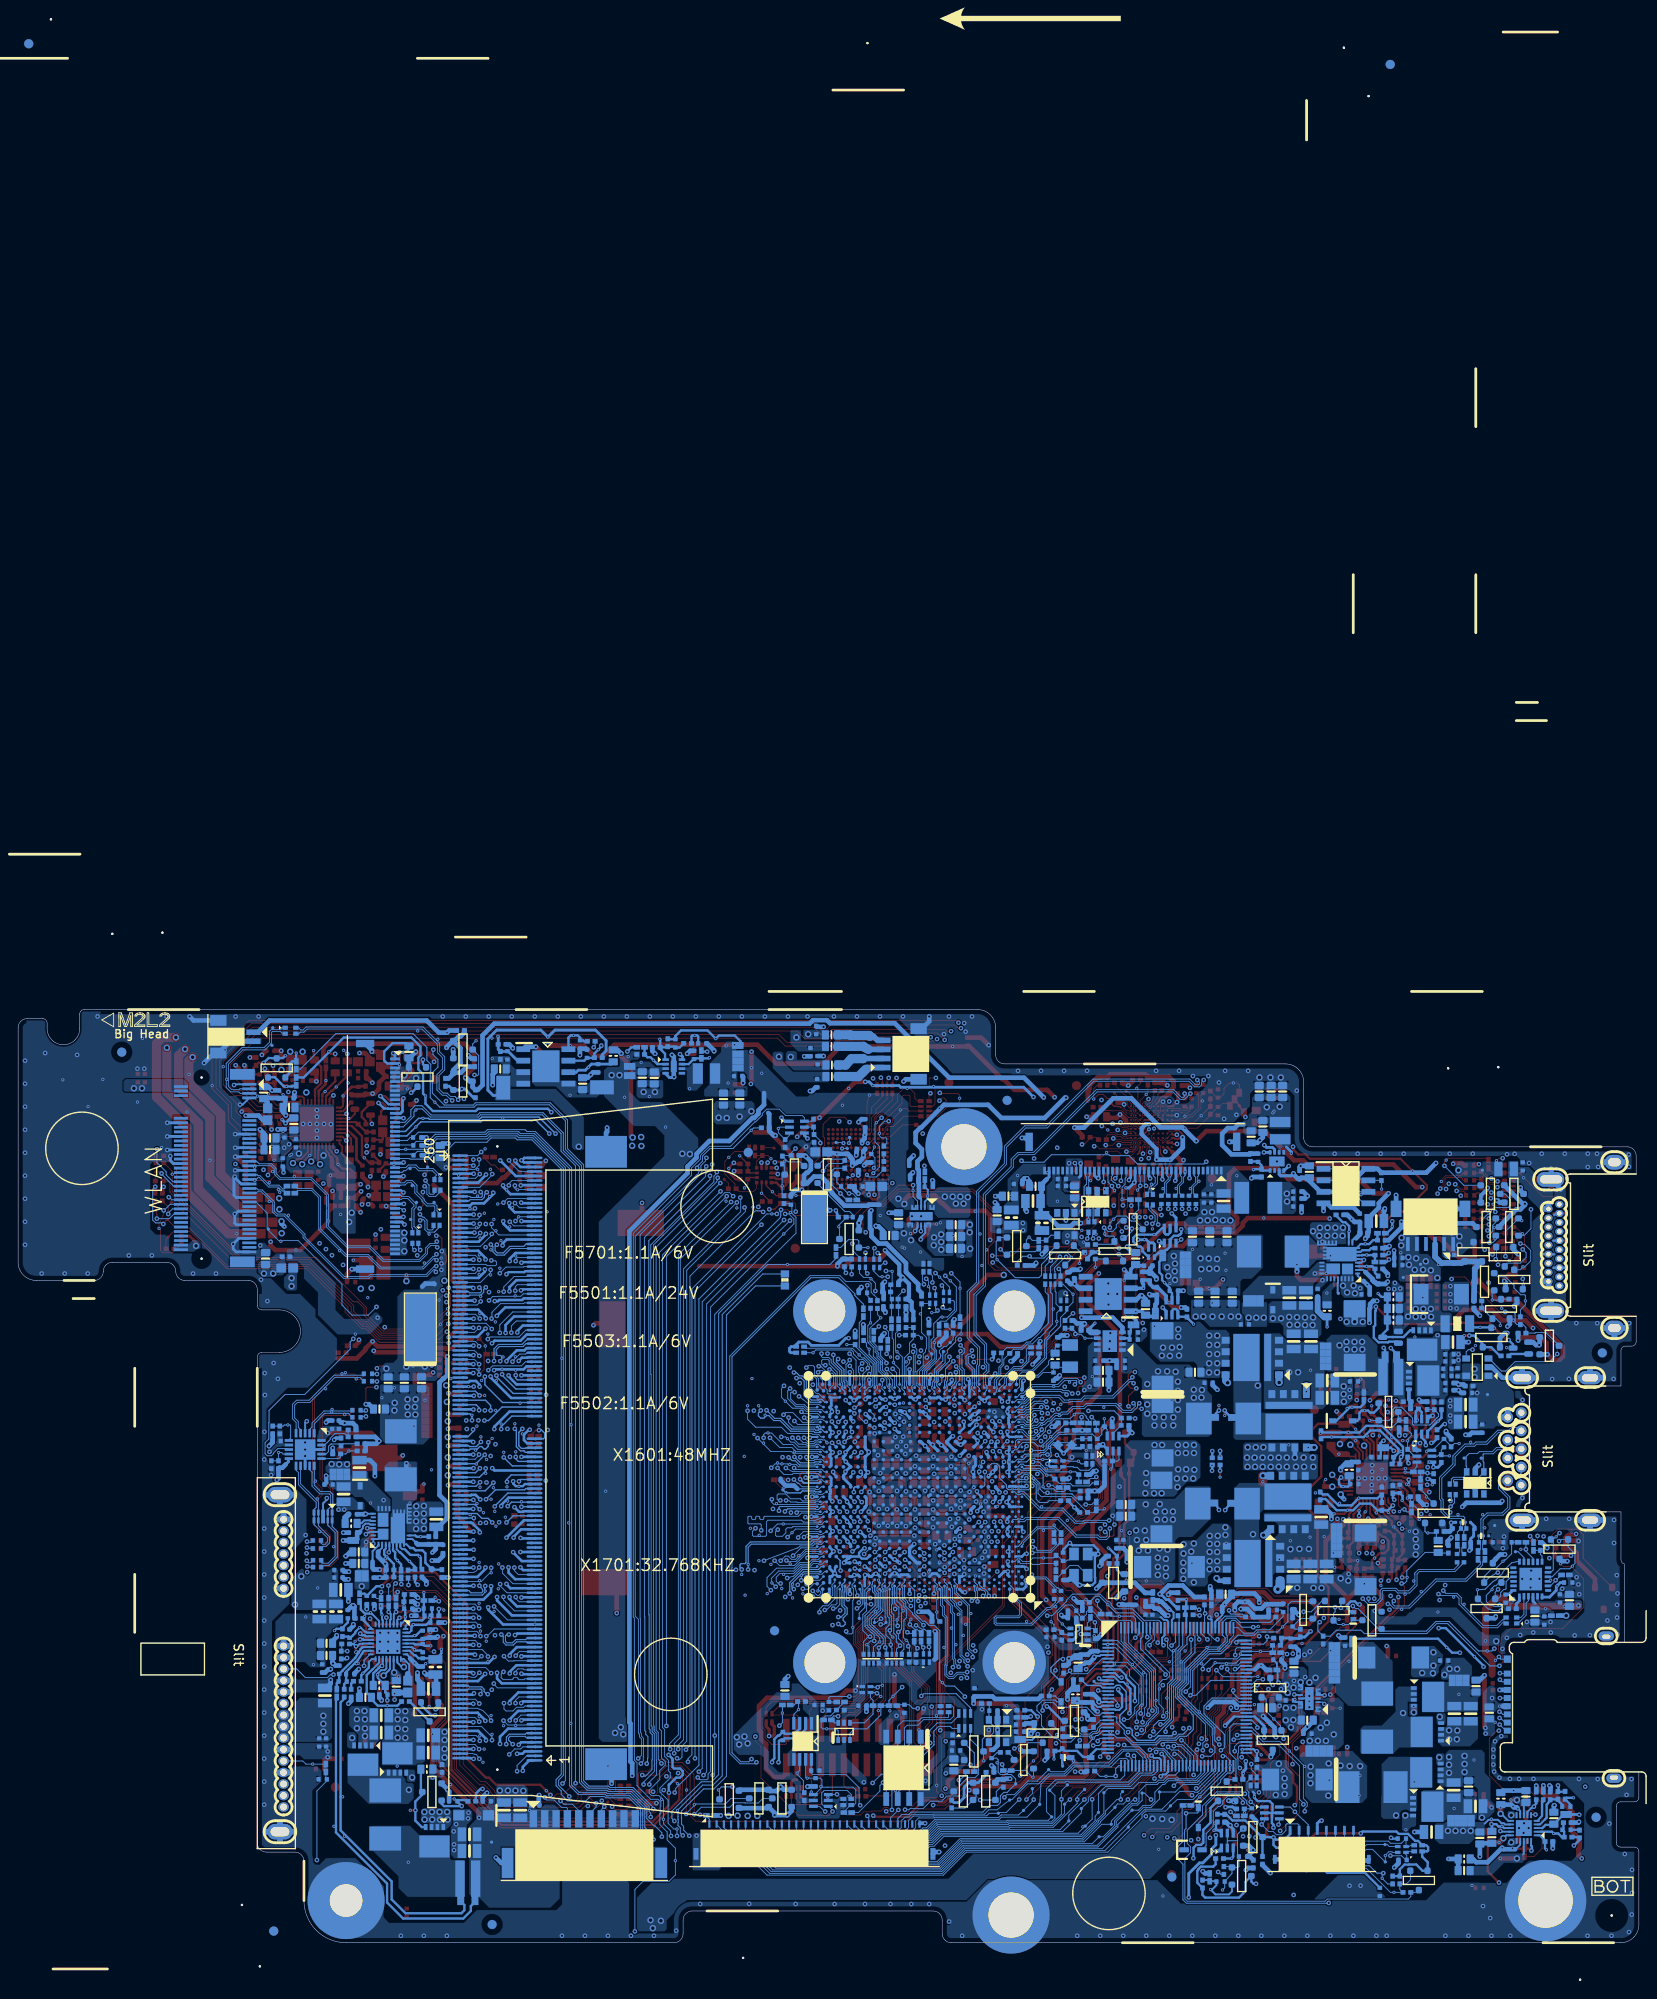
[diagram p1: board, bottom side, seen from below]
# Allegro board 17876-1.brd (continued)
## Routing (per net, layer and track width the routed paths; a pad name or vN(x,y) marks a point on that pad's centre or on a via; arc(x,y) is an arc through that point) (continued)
M_A_DQ37: length 54.2
  TOP w0.089: v1(95.07,52.4) v2(95.07,52.96)
  L4 w0.14: v1(127,63.2) 128.3,63.2 128.45,63.35 128.93,63.35 129.16,63.12 129.16,62.26 128.91,62 126.97,62 126.77,61.8 126.77,61.36 126.63,61.22 126.35,61.22 126.19,61.38 126.19,61.79 126.05,61.93 125.77,61.93 125.63,61.79 125.63,61.3 125.49,61.16 125.21,61.16 125.07,61.3 125.07,61.51 124.93,61.65 124.57,61.65 108.58,51.91 108.36,51.77 105.82,51.77 105.56,52.02 97.38,52.02 97.28,52.12 96.16,52.12 95.99,51.94 95.55,51.94 95.45,52.05 95.43,52.05 v1(95.07,52.4)
  BOTTOM w0.089: DIMM1.169 122.9,64.13 123.35,63.67 126.53,63.67 127,63.2 v1(127,63.2) ; v1(95.07,52.4) 94.36,51.69 93.45,51.69 93.34,51.79 90.62,51.79 90.24,51.42 CPU1.AC40
M_A_DQ38: length 53.5
  TOP w0.089: v1(127.05,66.63) v2(127.05,67.18)
  L4 w0.14: v1(127.05,66.63) 127.36,66.63 127.5,66.49 127.5,65.73 127.28,65.51 119.79,65.51 114.53,60.25 112.27,60.25 108.53,56.52 108.53,55.35 107.8,54.61 96.09,54.61 95.81,54.89 93.85,54.89 93.32,54.36 92.51,54.36 92.35,54.51 92.35,54.75 92.21,54.89 91.66,54.89 91.52,54.75 91.52,53.98 v1(91.9,53.59)
  BOTTOM w0.089: v1(127.05,66.63) 126.82,66.85 123.62,66.85 122.85,67.62 DIMM1.183 ; CPU1.AF40 89.9,53.07 90.2,53.37 90.47,53.37 90.52,53.32 90.98,53.32 91.08,53.22 91.81,53.22 91.9,53.31 v1(91.9,53.59)
M_A_DQ39: length 51.8
  TOP w0.089: v1(97.28,55.7) v2(97.68,56.1)
  L4 w0.14: v1(128.03,67.86) 128.03,67.53 127.66,67.16 126.9,67.16 125.7,65.97 119.58,65.97 116.21,62.59 116.01,62.59 115.4,63.21 115.2,63.21 115,63.01 115,62.81 115.62,62.2 115.62,62 115.42,61.8 115.22,61.8 114.61,62.42 114.41,62.42 114.21,62.22 114.21,62.02 114.83,61.41 114.83,61.21 114.33,60.71 112.09,60.71 108.08,56.69 108.08,55.96 107.19,55.07 97.91,55.07 v1(97.28,55.7)
  BOTTOM w0.089: CPU1.AG40 90.22,53.84 90.49,53.84 90.68,54.03 93.37,54.03 93.57,54.23 95.81,54.23 v1(97.28,55.7) ; DIMM1.182 128.51,67.38 v1(128.03,67.86)
M_A_DQ40: length 51.1
  TOP w0.089: v2(126.22,68.52) 126.58,68.89 v1(126.64,68.89)
  L4 w0.14: v1(92.79,55.73) 93.24,56.19 93.7,56.19 95.25,57.74 103.5,57.74 104.1,58.33 104.3,58.33 104.44,58.18 104.64,58.18 104.84,58.38 104.84,58.58 104.69,58.73 104.69,58.92 104.89,59.12 105.09,59.12 105.23,58.97 105.43,58.97 105.63,59.17 105.63,59.37 105.48,59.52 105.48,59.71 105.68,59.91 105.88,59.91 106.02,59.77 106.22,59.77 111.05,64.6 111.05,64.98 111.26,65.18 111.64,65.18 111.84,65.39 111.84,65.77 112.05,65.97 112.43,65.97 112.63,66.18 112.63,66.56 112.84,66.76 113.22,66.76 113.42,66.97 113.42,67.35 113.63,67.55 114.01,67.55 114.21,67.76 114.21,68.14 114.42,68.34 114.8,68.34 115.25,68.8 125.49,68.8 125.6,68.68 126.44,68.68 v1(126.64,68.89)
  BOTTOM w0.089: CPU1.AK41 90.86,55.27 91.01,55.12 91.82,55.12 91.92,55.22 92.27,55.22 92.78,55.73 v1(92.79,55.73) ; v1(126.64,68.89) 126.6,68.93 126.6,69.59 125.65,70.54 123.11,70.54 123.03,70.62 DIMM1.195
M_A_DQ41: length 48.9
  TOP w0.089: v1(127.84,70.79) v2(127.84,71.35)
  L4 w0.14: v1(127.84,70.79) 126.77,69.72 125.88,69.72 125.43,69.27 114.53,69.27 110.15,64.89 110.15,64.35 107.18,61.38 106.98,61.38 106.85,61.51 106.65,61.51 106.45,61.32 106.45,61.12 106.58,60.99 106.58,60.79 106.39,60.59 106.19,60.59 106.06,60.72 105.86,60.72 103.33,58.19 98.32,58.19 98.12,57.99 95.15,57.99 93.68,56.52 92.93,56.52 v1(92.15,55.74)
  BOTTOM w0.089: v1(127.84,70.79) 128.24,70.39 130.09,70.39 DIMM1.194 ; CPU1.AK40 89.87,55.49 90.13,55.49 90.2,55.57 90.5,55.57 90.59,55.48 90.93,55.48 91.08,55.32 91.74,55.32 91.97,55.55 91.97,55.57 92.14,55.74 v1(92.15,55.74)
M_A_DQ42: length 51.5
  TOP w0.089: v1(125.3,71.86) v2(125.86,71.86)
  L4 w0.14: v1(94.42,58.27) 94.42,58.32 96.21,60.12 101.41,60.12 104.77,63.47 104.96,63.47 105.36,63.07 105.59,63.07 105.84,63.32 105.84,63.52 105.43,63.93 105.43,64.13 105.77,64.47 105.97,64.47 106.3,64.13 106.68,64.13 110.57,68.02 110.57,68.48 110.29,68.76 110.29,68.91 110.61,69.24 110.81,69.24 111.16,68.89 111.36,68.89 111.56,69.09 111.56,69.29 111.21,69.63 111.21,69.83 111.4,70.03 111.6,70.03 111.95,69.68 112.15,69.68 112.35,69.88 112.35,70.08 112,70.42 112,70.62 112.19,70.82 112.39,70.82 112.74,70.47 112.94,70.47 113.54,71.07 124.51,71.07 v1(125.3,71.86)
  BOTTOM w0.089: v1(125.3,71.86) 125.3,72.39 124.15,73.53 122.68,73.53 122.59,73.62 DIMM1.207 ; CPU1.AP41 91.05,57.47 91.12,57.4 92.27,57.4 93.4,58.52 94.17,58.52 v1(94.42,58.27)
M_A_DQ43: length 49.3
  TOP w0.089: v1(128.02,74.32) v2(128.02,73.76)
  L4 w0.14: v1(92.13,57.96) 92.4,57.96 92.86,58.42 92.86,58.67 95.64,61.45 100.79,61.45 111.79,72.44 121.79,72.44 122.96,72.95 124.49,72.95 124.59,72.85 125.37,72.85 126.24,73.71 126.24,74.45 126.59,74.8 127.58,74.8 127.72,74.67 v1(128.02,74.32)
  BOTTOM w0.089: v1(128.02,74.32) 128.46,73.88 DIMM1.208 ; CPU1.AP40 90.19,57.78 90.48,57.78 90.56,57.7 91.16,57.7 91.28,57.59 91.76,57.59 v1(92.13,57.96)
M_A_DQ44: length 50.7
  L4 w0.14: v1(125.73,67.31) 125.73,67.63 125.59,67.77 125.25,67.77 125.18,67.84 117.39,67.84 116.55,67 116.35,67 116.09,67.26 115.9,67.26 115.7,67.06 115.7,66.86 115.96,66.6 115.96,66.4 115.72,66.16 115.52,66.16 115.09,66.59 114.9,66.59 114.7,66.39 114.7,66.19 115.1,65.79 115.1,65.54 114.9,65.35 114.7,65.35 114.53,65.52 114.33,65.52 114.14,65.32 114.14,65.12 114.31,64.95 114.31,64.75 114.11,64.56 113.91,64.56 113.74,64.73 113.54,64.73 113.35,64.53 113.35,64.33 113.52,64.16 113.52,63.96 113.32,63.77 113.12,63.77 112.95,63.94 112.75,63.94 112.56,63.74 112.56,63.54 112.73,63.37 112.73,63.17 112.45,62.89 110.67,62.89 104.6,56.82 95.66,56.82 v1(94.67,55.83)
  BOTTOM w0.089: CPU1.AJ41 92.72,54.72 93.24,55.25 93.6,55.25 v2(93.99,55.64) 94.18,55.83 v1(94.67,55.83) ; v1(125.73,67.31) 125.73,68.2 124.3,69.62 DIMM1.191
M_A_DQ45: length 49
  TOP w0.089: v1(127.94,68.89) v2(127.94,69.45)
  L4 w0.14: v1(93.43,55.74) 93.84,55.74 95.38,57.28 104.42,57.28 110.49,63.35 111.51,63.35 111.81,63.66 111.81,63.85 111.63,64.04 111.63,64.24 111.83,64.43 112.02,64.43 112.21,64.25 112.41,64.25 112.6,64.45 112.6,64.64 112.42,64.83 112.42,65.03 112.62,65.22 112.82,65.22 113,65.04 113.2,65.04 113.39,65.24 113.39,65.43 113.21,65.62 113.21,65.82 114.76,67.36 115.34,67.36 116.32,68.34 125.31,68.34 125.43,68.23 126.62,68.23 126.75,68.35 127.41,68.35 v1(127.94,68.89)
  BOTTOM w0.089: DIMM1.190 128.43,69.38 v1(127.94,68.89) ; CPU1.AJ40 90.25,54.72 90.56,55.03 90.77,55.03 90.78,55.02 90.83,55.02 90.93,54.92 91.9,54.92 92,55.02 92.35,55.02 92.36,55.03 92.72,55.03 v1(93.43,55.74)
M_A_DQ46: length 50.8
  TOP w0.089: v1(124.03,71.96) v2(124.03,71.4)
  L4 w0.14: v1(93.85,57.96) 93.74,58.08 93.74,58.28 96.02,60.56 101.17,60.56 105.75,65.14 105.95,65.14 106.39,64.7 106.61,64.7 106.79,64.89 106.79,65.08 106.34,65.53 106.34,65.73 106.64,66.03 106.84,66.03 107.28,65.59 107.5,65.59 107.68,65.78 107.68,65.97 107.23,66.42 107.23,66.62 107.43,66.82 107.63,66.82 108.04,66.41 108.26,66.41 108.45,66.59 108.45,66.79 108.02,67.21 108.02,67.41 108.25,67.64 108.46,67.64 108.92,67.18 109.09,67.18 109.29,67.38 109.29,67.53 108.81,68 108.81,68.2 109.01,68.4 109.21,68.4 109.65,67.96 109.85,67.96 110.04,68.16 110.04,68.36 109.61,68.8 109.61,68.99 112.14,71.53 123.6,71.53 v1(124.03,71.96)
  BOTTOM w0.089: v1(93.85,57.96) 93.85,57.43 93.34,56.92 CPU1.AN41 ; v1(124.03,71.96) 124.03,72.39 123.8,72.62 DIMM1.203
M_A_DQ47: length 49.5
  TOP w0.089: v2(126.75,73.71) 126.75,73.72 v1(126.75,74.27)
  L4 w0.14: v1(126.75,74.27) 126.75,73.59 125.55,72.39 124.38,72.39 124.29,72.49 123.16,72.49 122.02,71.99 111.96,71.99 100.99,61.01 95.83,61.01 93.23,58.41 93.23,57.58 v1(93.22,57.58)
  BOTTOM w0.089: v1(93.22,57.58) 93.22,57.57 92.85,57.21 90.96,57.21 90.95,57.22 90.55,57.22 90.25,56.92 CPU1.AN40 ; DIMM1.204 127.86,72.88 126.75,73.99 v1(126.75,74.27)
M_A_DQ48: length 51.2
  TOP w0.089: v1(127.99,75.36) v2(127.99,75.92)
  L4 w0.14: v1(93.69,61.18) 93.69,61.43 95.05,62.8 99.75,62.8 111.54,74.58 115.08,74.58 115.49,74.17 121.2,74.17 121.62,74.58 124.42,74.58 124.59,74.75 125.22,74.75 126.26,75.8 126.85,75.8 127.33,76.28 127.95,76.28 128.19,76.04 128.19,75.57 v1(127.99,75.36)
  BOTTOM w0.089: v1(93.69,61.18) 93.95,60.91 93.95,60.07 93.07,59.19 92.19,59.19 91.82,58.82 90.51,58.82 90.47,58.87 90.2,58.87 89.91,58.57 CPU1.AT40 ; v1(127.99,75.36) 127.99,75.44 128.43,75.88 129.03,75.88 129.03,75.88 DIMM1.216
M_A_DQ49: length 52
  TOP w0.089: v1(123.98,75.24) v2(123.98,75.8)
  L4 w0.14: v1(93.2,60.77) 92.99,60.97 92.99,61.17 95.07,63.24 99.56,63.24 111.49,75.17 115.71,75.17 115.85,75.03 115.85,74.74 115.96,74.63 116.24,74.63 116.38,74.77 116.38,75.35 116.52,75.49 116.8,75.49 116.94,75.35 116.94,74.77 117.08,74.63 117.39,74.63 117.53,74.77 117.53,75.37 117.67,75.51 117.95,75.51 118.09,75.37 118.09,74.74 118.2,74.63 118.5,74.63 118.64,74.77 118.64,75.37 118.78,75.51 119.06,75.51 119.2,75.37 119.2,74.74 119.32,74.63 119.62,74.63 119.76,74.77 119.76,75.37 119.9,75.51 120.18,75.51 120.32,75.37 120.32,74.83 120.47,74.68 120.74,74.68 120.88,74.82 120.88,75.37 121.02,75.51 121.3,75.51 121.44,75.37 121.44,75.27 121.58,75.13 121.88,75.13 122.03,75.28 122.03,75.45 122.12,75.54 123.67,75.54 v1(123.98,75.24)
  BOTTOM w0.089: v1(93.2,60.77) 93.54,60.77 93.62,60.68 93.62,60.02 92.98,59.38 92.11,59.38 91.75,59.03 90.79,59.03 CPU1.AU41 ; DIMM1.215 123.79,75.62 123.98,75.44 v1(123.98,75.24)
M_A_DQ50: length 50.8
  TOP w0.089: v2(128.31,78.91) v1(127.94,79.35)
  L4 w0.14: v1(91.9,63.48) 92.05,63.48 94.55,65.97 97.75,65.97 102.39,70.61 103.07,70.61 104.52,72.06 104.52,72.72 110.11,78.31 122.71,78.31 122.91,78.26 123.95,78.26 124.84,79.15 125.54,79.15 126.2,79.81 127.8,79.81 127.94,79.67 v1(127.94,79.35)
  BOTTOM w0.089: v1(91.9,63.48) 91.67,63.7 91.16,63.7 91.01,63.55 91.01,62.72 90.55,62.26 90.55,61.47 CPU1.AY40 ; DIMM1.228 128.09,78.88 127.94,79.02 v1(127.94,79.35)
M_A_DQ51: length 52.2
  TOP w0.089: v1(124.64,79.58) v2(124.64,79.02)
  L4 w0.14: v1(90.15,62.39) 89.84,62.39 89.48,62.03 89.48,60.78 89.76,60.5 90.58,60.5 90.75,60.68 90.75,62.26 91.34,62.84 91.34,63.53 91.72,63.91 92.1,63.91 94.61,66.42 97.48,66.42 102.47,71.41 102.67,71.41 102.83,71.25 103.02,71.25 103.22,71.45 103.22,71.64 103.06,71.8 103.06,72 103.29,72.22 103.48,72.22 103.65,72.05 103.85,72.05 104.05,72.25 104.05,72.45 103.88,72.62 103.88,72.82 109.83,78.77 122.78,78.77 123.04,78.72 123.77,78.72 v1(124.64,79.58)
  BOTTOM w0.089: v1(124.64,79.58) 124.18,79.13 DIMM1.229 ; CPU1.BA40 v1(90.15,62.39)
M_A_DQ52: length 52.9
  TOP w0.089: v1(125.73,73.89) v2(125.73,74.45)
  L4 w0.14: v1(92.43,58.6) 89.86,58.6 89.73,58.74 89.73,59.4 89.86,59.54 93.04,59.54 95.41,61.91 99.08,61.91 99.09,61.9 100.13,61.9 111.46,73.23 121.89,73.23 122.43,73.41 124.66,73.41 124.76,73.31 125.2,73.31 125.65,73.76 125.65,73.81 v1(125.73,73.89)
  BOTTOM w0.089: DIMM1.211 123.07,74.62 123.11,74.58 125.04,74.58 v1(125.73,73.89) ; CPU1.AR40 90.25,58.02 90.66,58.43 92.26,58.43 v1(92.43,58.6)
M_A_DQ53: length 51.1
  L4 w0.14: v1(94.36,61.47) 94.38,61.47 94.38,61.54 95.19,62.35 99.94,62.35 111.73,74.14 112.58,74.14 112.72,74 112.72,73.83 112.86,73.69 113.14,73.69 113.28,73.83 113.28,74 113.42,74.14 113.7,74.14 113.84,74 113.84,73.83 113.98,73.69 114.36,73.69 114.5,73.83 114.5,73.9 114.64,74.04 114.92,74.04 115.06,73.9 115.06,73.83 115.2,73.69 121.46,73.69 121.91,74.14 122.51,74.14 122.73,73.92 123.22,73.92 123.45,74.14 124.66,74.14 124.79,74.27 125.37,74.27 126.42,75.31 v1(126.67,75.31)
  BOTTOM w0.089: v1(126.67,75.31) 126.62,75.26 126.2,75.26 126.11,75.17 126.11,74.83 126.21,74.73 127.13,74.73 127.27,74.88 DIMM1.212 ; v1(94.36,61.47) 94.38,61.47 94.38,61.44 94.64,61.18 94.64,60.2 v2(94.21,59.77) 93.44,59 92.27,59 91.89,58.62 90.4,58.62 CPU1.AT41
M_A_DQ54: length 50.7
  TOP w0.089: v2(127.9,77.77) 127.9,77.77 v1(127.9,78.34)
  L4 w0.14: v1(127.9,78.34) 127.45,78.79 126.49,78.79 125.93,78.23 124.94,77.83 124.46,77.34 110.41,77.34 105.44,72.37 105.44,71.71 99.73,66 99.53,66 99.43,66.09 99.24,66.09 99.04,65.89 99.04,65.7 99.13,65.6 99.13,65.4 98.81,65.08 94.37,65.08 92.58,63.3 92.58,63.2 92.33,62.94 92.33,62.64 91.9,62.21 91.4,62.21 v1(91.36,62.24)
  BOTTOM w0.089: v1(127.9,78.34) 127.9,78.3 128.33,77.88 DIMM1.224 ; CPU1.AW40 90.14,60.22 90.55,60.64 90.8,60.64 91.61,61.44 91.61,61.9 91.44,62.08 91.44,62.15 91.36,62.23 v1(91.36,62.24)
M_A_DQ55: length 52.8
  TOP w0.089: v2(126.39,79.83) v1(126.64,79.33)
  L4 w0.14: v1(126.64,79.33) 126.39,79.33 125.76,78.69 125.17,78.69 124.28,77.8 122.61,77.8 122.22,77.85 110.29,77.85 104.98,72.54 104.98,71.88 103.18,70.08 102.98,70.08 102.9,70.16 102.7,70.16 102.5,69.96 102.5,69.77 102.58,69.69 102.58,69.49 102.38,69.29 102.19,69.29 102.11,69.37 101.91,69.37 101.71,69.17 101.71,68.98 101.79,68.89 101.79,68.7 101.59,68.5 101.4,68.5 101.31,68.58 101.12,68.58 100.92,68.38 100.92,68.19 101,68.1 101,67.91 100.75,67.65 100.52,67.65 100.39,67.78 100.19,67.78 99.89,67.48 99.89,67.28 100.04,67.13 100.04,66.94 99.83,66.74 99.64,66.74 99.49,66.89 99.3,66.89 97.94,65.53 94.46,65.53 92.33,63.4 92.33,63.31 91.79,62.77 v1(91.77,62.77)
  BOTTOM w0.089: v1(91.77,62.77) 91.73,62.72 91.28,62.72 90.77,62.22 90.77,61.09 CPU1.AY41 ; DIMM1.225 125.85,78.13 126.64,78.92 v1(126.64,79.33)
M_A_DQ56: length 60.8
  TOP w0.089: v2(124.32,81.14) v1(124.06,81.64)
  L4 w0.14: v1(89.34,63.27) 88.8,62.72 88.8,62.22 88.61,62.03 87.83,62.03 87.63,62.23 87.63,63.04 89,64.42 90.7,64.42 91.26,64.97 91.72,64.97 94.61,67.87 94.61,68.4 94.97,68.76 95.36,68.76 95.5,68.9 95.5,68.94 98.32,71.76 98.83,71.76 99.16,72.09 99.16,72.65 100.89,74.37 101.45,74.37 101.83,74.75 101.83,74.95 101.77,75.01 101.77,75.2 101.97,75.4 102.16,75.4 102.22,75.34 102.42,75.34 102.62,75.54 102.62,75.74 102.56,75.8 102.56,75.99 102.76,76.19 102.96,76.19 103.01,76.13 103.21,76.13 103.41,76.33 103.41,76.53 103.35,76.59 103.35,76.78 103.55,76.98 103.75,76.98 103.8,76.92 104,76.92 104.2,77.12 104.2,77.32 104.14,77.38 104.14,77.57 104.34,77.77 104.54,77.77 104.59,77.72 104.79,77.72 104.99,77.91 104.99,78.11 104.93,78.17 104.93,78.36 105.13,78.56 105.33,78.56 105.38,78.51 105.58,78.51 106.02,78.94 106.02,79.33 107.87,81.18 112.91,81.18 113.05,81.32 113.05,81.52 113.19,81.66 113.47,81.66 113.61,81.52 113.61,81.32 113.75,81.18 114.03,81.18 114.17,81.32 114.17,81.52 114.31,81.66 114.59,81.66 114.73,81.52 114.73,81.32 114.87,81.18 115.15,81.18 115.29,81.32 115.29,81.52 115.42,81.66 115.7,81.66 115.84,81.52 115.84,81.32 115.98,81.18 116.26,81.18 116.4,81.32 116.4,81.52 116.54,81.66 116.82,81.66 116.96,81.52 116.96,81.32 117.1,81.18 117.38,81.18 117.52,81.32 117.52,81.52 117.66,81.66 117.94,81.66 118.08,81.52 118.08,81.32 118.22,81.18 118.5,81.18 118.64,81.32 118.64,81.52 118.78,81.66 119.06,81.66 119.2,81.52 119.2,81.32 119.34,81.18 119.62,81.18 119.76,81.32 119.76,81.52 119.9,81.66 120.17,81.66 120.31,81.52 120.31,81.32 120.45,81.18 120.73,81.18 120.87,81.32 120.87,81.52 121.01,81.66 121.29,81.66 121.43,81.52 121.43,81.32 121.57,81.18 123.6,81.18 v1(124.06,81.64)
  BOTTOM w0.089: v1(124.06,81.64) 123.55,81.13 DIMM1.237 ; CPU1.BA38 88.7,61.32 88.7,62.82 89.15,63.27 v1(89.34,63.27)
M_A_DQ57: length 59.6
  TOP w0.089: v1(128.47,81.05) v2(129.03,81.05)
  L4 w0.14: v1(128.47,81.05) 128.71,81.05 128.85,81.19 128.85,82.16 128.71,82.3 128.36,82.3 128.22,82.16 128.22,81.62 128.08,81.48 127.76,81.48 127.64,81.61 127.64,81.95 127.42,82.17 126.21,82.17 126,81.95 126,81.19 125.86,81.05 124.16,81.05 123.83,80.72 108.05,80.72 106.48,79.15 106.48,78.77 101.63,73.92 101.07,73.92 99.62,72.47 99.62,71.91 98.97,71.26 98.78,71.26 98.73,71.31 98.53,71.31 98.34,71.11 98.34,70.92 98.38,70.87 98.38,70.67 98.18,70.47 97.99,70.47 97.94,70.52 97.74,70.52 97.54,70.32 97.54,70.13 97.59,70.08 97.59,69.88 97.39,69.68 97.2,69.68 97.15,69.73 96.95,69.73 96.75,69.53 96.75,69.34 96.8,69.29 96.8,69.09 96.6,68.89 96.41,68.89 96.36,68.94 96.16,68.94 95.96,68.74 95.96,68.54 96.01,68.5 96.01,68.3 95.5,67.79 94.89,67.79 91.82,64.72 91.39,64.72 90.73,64.06 90.25,64.06 89.93,63.74 v1(89.8,63.74)
  BOTTOM w0.089: v1(128.47,81.05) 128.65,80.88 DIMM1.236 ; CPU1.AY37 88.2,61.17 88.5,61.48 88.5,63 89.38,63.88 89.38,64.25 89.52,64.39 90.08,64.39 90.2,64.27 90.2,63.89 90.05,63.74 v1(89.8,63.74)
M_A_DQ58: length 60.9
  TOP w0.089: v2(124.98,83.09) v1(124.74,83.59)
  L4 w0.14: v1(124.74,83.59) 124.74,83.85 124.05,84.53 123.04,84.53 122.86,84.71 121.03,84.71 120.85,84.53 119.34,84.53 118.71,85.17 107.8,85.17 105.59,82.96 105.59,82.76 105.69,82.65 105.69,82.45 105.5,82.26 105.3,82.26 105.19,82.36 104.99,82.36 104.8,82.17 104.8,81.97 104.9,81.86 104.9,81.66 104.71,81.47 104.51,81.47 104.4,81.57 104.2,81.57 103.99,81.37 103.99,81.17 104.06,81.1 104.06,80.9 103.87,80.7 103.67,80.7 103.6,80.77 103.4,80.77 103.2,80.57 103.2,80.38 103.27,80.31 103.27,80.11 102.96,79.79 102.76,79.79 102.6,79.95 102.4,79.95 102.21,79.75 102.21,79.56 102.36,79.4 102.36,79.2 102.17,79 101.97,79 101.81,79.16 101.61,79.16 101.42,78.96 101.42,78.77 101.57,78.61 101.57,78.41 101.38,78.21 101.18,78.21 101.02,78.37 100.82,78.37 100.63,78.17 100.63,77.98 100.78,77.82 100.78,77.62 100.59,77.42 100.39,77.42 100.23,77.58 100.03,77.58 99.83,77.38 99.83,77.19 99.99,77.03 99.99,76.83 99.79,76.63 99.6,76.63 99.44,76.79 99.24,76.79 93.34,70.89 93.34,68.38 91.29,66.32 88.43,66.32 v1(87.12,65.02)
  BOTTOM w0.089: CPU1.BA34 86.41,61.41 86.41,64.3 v1(87.12,65.02) ; DIMM1.249 124.38,84.13 124.74,83.77 v1(124.74,83.59)
M_A_DQ59: length 59.5
  TOP w0.089: v2(128.18,85.35) v1(127.94,84.84)
  L4 w0.14: v1(85.74,63.94) 85.74,64.63 87.99,66.88 91.14,66.88 92.84,68.58 92.84,71.81 107.14,86.11 119.51,86.11 120.09,85.93 120.62,85.8 121.3,85.9 123.11,85.9 123.55,85.7 124.41,85.7 125.21,85.41 127.37,85.41 v1(127.94,84.84)
  BOTTOM w0.089: v1(85.74,63.94) 86.15,63.53 86.15,62.99 86,62.84 CPU1.BA33 ; DIMM1.250 128.41,84.37 v1(127.94,84.84)
M_A_DQ60: length 59.1
  TOP w0.089: v2(127.43,80.52) v1(127.98,80.33)
  L4 w0.14: v1(127.98,80.33) 127.92,80.27 127.33,80.27 127.17,80.43 127.17,81.55 127.03,81.69 126.75,81.69 126.61,81.55 126.61,80.41 126.47,80.27 125.98,80.27 125.71,80.55 125.43,80.55 125.29,80.41 125.29,80.38 125.15,80.24 124.87,80.24 124.73,80.38 124.73,80.41 124.59,80.55 124.31,80.55 124.03,80.27 122.76,80.27 122.51,80.01 122.2,80.01 121.95,80.27 121.64,80.27 121.39,80.01 121.09,80.01 120.83,80.27 120.53,80.27 120.27,80.01 119.97,80.01 119.71,80.27 119.41,80.27 119.16,80.01 118.85,80.01 118.6,80.27 118.29,80.27 118.04,80.01 117.73,80.01 117.48,80.27 117.17,80.27 116.92,80.01 116.62,80.01 116.36,80.27 116.06,80.27 115.8,80.01 115.5,80.01 115.24,80.27 114.94,80.27 114.68,80.01 114.38,80.01 114.13,80.27 113.82,80.27 113.57,80.01 113.26,80.01 113.01,80.27 112.7,80.27 112.45,80.01 112.14,80.01 111.89,80.27 111.59,80.27 111.33,80.01 111.03,80.01 110.77,80.27 110.47,80.27 110.21,80.01 109.91,80.01 109.66,80.27 108.23,80.27 107.93,79.97 107.93,79.75 108.33,79.35 108.33,79.15 108.13,78.95 107.94,78.95 107.52,79.36 107.33,79.36 106.93,78.97 106.93,78.58 101.81,73.46 101.24,73.46 100.08,72.29 100.08,71.73 96.88,68.53 96.88,68.53 96.39,68.05 96.39,67.62 96.11,67.33 94.81,67.33 91.95,64.47 91.57,64.47 90.73,63.63 v1(90.53,63.63)
  BOTTOM w0.089: DIMM1.232 128.15,79.88 127.98,80.05 v1(127.98,80.33) ; CPU1.AY39 89.3,61.18 88.9,61.58 88.9,62.74 89.03,62.87 89.53,62.87 90.3,63.63 v1(90.53,63.63)
M_A_DQ61: length 61.1
  TOP w0.089: v2(123.66,80.12) v1(124,79.66)
  L4 w0.14: v1(90.6,62.96) 90.87,62.96 91.08,63.17 91.08,63.63 91.64,64.19 92.02,64.19 94.72,66.88 96.88,66.88 97.15,67.15 97.15,67.35 96.84,67.66 96.84,67.86 97.06,68.08 97.26,68.08 97.58,67.76 97.78,67.76 97.95,67.93 97.95,68.13 97.68,68.4 97.68,68.6 97.88,68.8 98.07,68.8 98.27,68.6 98.47,68.6 98.67,68.8 98.67,68.99 98.47,69.19 98.47,69.39 98.67,69.59 98.86,69.59 99.06,69.39 99.26,69.39 99.46,69.59 99.46,69.78 99.26,69.98 99.26,70.18 99.46,70.38 99.66,70.38 99.85,70.18 100.05,70.18 100.25,70.38 100.25,70.58 100.05,70.77 100.05,70.97 100.25,71.17 100.45,71.17 100.64,70.97 100.84,70.97 101.04,71.17 101.04,71.37 100.52,71.88 100.52,72.1 100.71,72.29 100.88,72.29 101.41,71.76 101.63,71.76 101.81,71.95 101.81,72.14 101.36,72.59 101.36,72.79 101.56,72.99 101.76,72.99 102.2,72.55 102.42,72.55 102.62,72.75 102.62,72.95 102.42,73.14 102.42,73.34 102.62,73.54 102.82,73.54 103.01,73.34 103.21,73.34 103.41,73.54 103.41,73.74 103.21,73.93 103.21,74.13 103.41,74.33 103.61,74.33 103.8,74.13 104,74.13 104.2,74.33 104.2,74.53 104,74.72 104,74.92 104.2,75.12 104.4,75.12 104.59,74.92 104.79,74.92 104.99,75.12 104.99,75.32 104.79,75.51 104.79,75.71 104.99,75.91 105.19,75.91 105.38,75.71 105.58,75.71 105.78,75.91 105.78,76.11 105.58,76.3 105.58,76.5 105.78,76.7 105.98,76.7 106.17,76.5 106.37,76.5 106.57,76.7 106.57,76.9 106.37,77.1 106.37,77.29 106.57,77.49 106.77,77.49 106.97,77.29 107.16,77.29 107.36,77.49 107.36,77.69 107.16,77.89 107.16,78.08 107.36,78.28 107.56,78.28 107.76,78.08 107.95,78.08 109.42,79.55 122.73,79.55 123.11,79.17 123.6,79.17 124,79.58 v1(124,79.66)
  BOTTOM w0.089: DIMM1.233 123.56,80.13 124,79.68 v1(124,79.66) ; CPU1.AY38 89.51,60.57 89.6,60.66 89.6,61.04 89.75,61.19 89.75,62.78 90.11,63.14 90.41,63.14 v1(90.6,62.96)
M_A_DQ62: length 61
  TOP w0.089: v2(123.76,83.11) v1(124.07,83.58)
  L4 w0.14: v1(124.07,83.58) 124.07,83.86 123.85,84.08 122.86,84.08 122.68,84.25 121.21,84.25 120.55,83.59 119.63,83.59 118.52,84.71 117.27,84.71 117.02,84.46 116.61,84.46 116.46,84.61 116.05,84.61 115.9,84.46 115.49,84.46 115.34,84.61 114.63,84.61 114.47,84.46 114.07,84.46 113.91,84.61 113.51,84.61 113.36,84.46 112.95,84.46 112.8,84.61 112.39,84.61 112.24,84.46 111.83,84.46 111.68,84.61 111.27,84.61 111.12,84.46 110.71,84.46 110.56,84.61 110.15,84.61 110,84.46 109.6,84.46 109.44,84.61 108.51,84.61 108.07,84.16 107.87,84.16 107.76,84.27 107.56,84.27 107.37,84.08 107.37,83.88 107.48,83.77 107.48,83.57 107.28,83.37 107.08,83.37 106.97,83.48 106.77,83.48 106.58,83.29 106.58,83.09 106.69,82.98 106.69,82.78 99.66,75.76 99.3,75.76 99.07,75.53 99.07,75.17 98.87,74.97 98.68,74.97 98.5,75.14 98.3,75.14 98.11,74.94 98.11,74.75 98.28,74.57 98.28,74.38 97.98,74.08 97.78,74.08 97.58,74.27 97.39,74.27 97.19,74.08 97.19,73.88 97.39,73.68 97.39,73.48 97.19,73.28 96.99,73.28 96.79,73.48 96.6,73.48 96.4,73.29 96.4,73.09 96.6,72.89 96.6,72.69 96.4,72.49 96.2,72.49 96,72.69 95.81,72.69 95.61,72.5 95.61,72.3 95.81,72.1 95.81,71.9 95.61,71.7 95.41,71.7 95.21,71.9 95.02,71.9 94.82,71.71 94.82,71.51 95.02,71.31 95.02,71.11 94.82,70.91 94.62,70.91 94.42,71.11 94.22,71.11 93.6,70.49 93.6,68.28 91.34,66.02 88.77,66.02 87.11,64.36 v1(87.11,64.31)
  BOTTOM w0.089: DIMM1.245 121.91,83.14 123.95,83.14 124.07,83.25 v1(124.07,83.58) ; CPU1.AY35 87.1,61.17 87.4,61.47 87.4,61.94 87.52,62.06 87.52,63.84 87.4,63.96 v1(87.11,64.31)
M_A_DQ63: length 59.8
  TOP w0.089: v2(126.77,85.36) v1(126.57,84.84)
  L4 w0.14: v1(126.57,84.84) 124.94,84.84 124.03,84.99 123.57,84.99 123.05,85.19 121.05,85.19 119.17,85.65 107.31,85.65 93.59,71.92 93.09,70.96 93.09,68.48 91.19,66.58 88.32,66.58 87.6,65.86 86.94,65.46 86.69,65.2 86.69,64.95 86.69,64.95 86.69,64.24 86.77,63.99 v1(87.1,63.67)
  BOTTOM w0.089: v1(87.1,63.67) 86.79,63.31 86.69,63.15 86.69,61.69 86.85,61.42 86.85,61.16 86.7,60.92 CPU1.AY34 ; v1(126.57,84.84) 126.57,84.75 127.94,83.37 DIMM1.246
M_A_DQS_DN0: length 60.7
  L4 w0.152: v1(88.37,35.18) 88.72,35.54 89.91,35.54 94.48,30.96 94.48,30.75 94.06,30.32 94.06,29.9 94.53,29.42 94.96,29.42 95.38,29.85 95.6,29.85 97.74,27.71 99.11,27.71 99.26,27.56 99.26,27.33 99.59,27 100.26,27 100.53,27.28 100.53,27.56 100.69,27.71 101.14,27.71 101.3,27.56 101.3,27.33 101.62,27 102.29,27 102.57,27.28 102.57,27.56 102.72,27.71 103.18,27.71 103.33,27.56 103.33,27.33 103.65,27 104.32,27 104.6,27.28 104.6,27.94 104.75,28.09 105.21,28.09 105.36,27.94 105.36,27.33 105.69,27 106.35,27 106.63,27.28 106.63,27.94 106.78,28.09 107.24,28.09 107.39,27.94 107.39,27.33 107.72,27 108.39,27 108.66,27.28 108.66,27.69 108.86,27.89 109.24,27.89 109.42,27.71 109.42,27.38 109.72,27.08 110.39,27.08 110.69,27.38 110.69,27.56 110.85,27.71 112.93,27.71 118.31,22.33 118.92,22.33 119.3,22.71 119.83,22.71 120.21,22.33 120.95,22.33 121.33,22.71 121.86,22.71 122.24,22.33 124.23,22.33 124.31,22.25 v1(124.31,21.91)
  BOTTOM w0.114: v1(124.31,21.91) 124.76,22.37 124.76,22.6 124.59,22.77 122.93,22.77 122.78,22.63 DIMM1.11 ; CPU1.A36 87.65,39.27 87.65,39.27 87.65,38.79 87.73,38.71 87.73,38.08 87.73,38.07 87.73,37.27 87.39,36.93 87.39,36.27 87.83,35.83 87.83,35.59 87.6,35.36 87.6,35.16 87.82,34.94 88.12,34.94 v1(88.37,35.18)
M_A_DQS_DN1: length 48.2
  TOP w0.114: v2(93.42,39.57) v1(93.28,39.03)
  L4 w0.152: v1(93.28,39.03) 93.26,39.01 93.26,38.02 93.92,37.34 94.2,37.34 95.73,36.07 97.15,35.16 103.83,35.16 104.42,34.57 112.92,34.57 119.55,27.94 125.32,27.94 126.34,26.93 127.35,26.93 v1(127.86,27.44)
  BOTTOM w0.114: v1(93.28,39.03) 93.49,39.24 93.49,39.65 92.19,40.95 90.37,40.95 CPU1.D41 ; DIMM1.32 129.31,27.87 129.19,28 127.82,28 127.71,27.88 127.71,27.59 v1(127.86,27.44)
M_A_DQS_DN2: length 49.5
  TOP w0.114: v1(98.32,41.19) v2(98.32,41.75)
  L4 w0.152: v1(98.32,41.19) 98.78,41.66 98.78,41.66 99.08,41.96 100.13,41.96 100.74,41.35 101.68,41.35 102.19,40.84 102.79,40.84 103.32,41.38 104.06,41.38 104.6,40.84 104.98,40.84 105.52,41.38 114.63,41.38 115.35,40.65 115.35,40.02 115.68,39.69 116.31,39.69 116.79,39.22 116.79,38.59 117.12,38.26 117.75,38.26 118.23,37.78 118.23,37.15 118.56,36.82 118.72,36.82 118.88,36.82 119.19,36.82 119.67,36.34 119.67,35.71 120,35.38 120.63,35.38 121.74,34.27 123.03,34.27 123.47,34.7 124.84,34.7 125.53,34.01 v1(125.56,34.01)
  BOTTOM w0.114: DIMM1.53 122.69,33.12 122.78,33.21 123.88,33.21 124.23,32.86 125.04,32.86 125.35,33.16 125.35,33.8 v1(125.56,34.01) ; v1(98.32,41.19) 98.32,43.64 97.97,43.99 91.3,43.99 91.05,44.25 90.37,44.25 CPU1.K41
M_A_DQS_DN3: length 47.2
  TOP w0.114: v2(127.34,38.82) 127.34,38.82 v1(127.34,39.38)
  L4 w0.152: v1(94.26,47.6) 94.26,47.6 94.71,47.14 96.24,47.14 96.55,47.45 119.3,47.45 121.69,45.06 121.69,42.11 123.16,40.64 126.18,40.64 127.18,39.65 127.18,39.63 127.18,39.63 127.19,39.63 127.34,39.47 v1(127.34,39.38)
  BOTTOM w0.114: CPU1.U40 90.26,48.12 90.57,47.81 90.83,47.81 90.92,47.9 93.96,47.9 94.2,47.66 v1(94.26,47.6) ; DIMM1.74 127.66,38.38 127.39,38.64 127.39,39.12 v1(127.34,39.38)
M_A_DQS_DN4: length 53.9
  TOP w0.114: v2(125.37,64.66) v1(125.68,64.19)
  L4 w0.152: v1(93.85,53.57) 93.85,53.9 94.2,54.25 94.5,54.25 94.95,53.79 108.15,53.79 109.34,54.99 109.34,55.85 109.88,56.39 110.05,56.39 110.51,55.92 110.94,55.92 111.46,56.45 111.46,56.82 110.81,57.48 110.81,57.64 111.15,57.99 111.32,57.99 112.05,57.26 112.53,57.26 113.03,57.76 113.03,58.18 112.38,58.83 112.38,58.99 112.71,59.31 112.87,59.31 113.4,58.78 114.21,58.78 120.12,64.7 125.53,64.7 125.68,64.54 v1(125.68,64.19)
  BOTTOM w0.114: CPU1.AE40 90,52.65 90.11,52.76 90.48,52.76 90.55,52.83 90.84,52.83 90.94,52.72 92.64,52.72 93.12,53.21 93.46,53.21 93.72,53.46 v1(93.85,53.57) ; DIMM1.177 122.84,66.13 123.17,65.8 125.78,65.8 126.13,65.46 126.13,64.94 126.01,64.82 125.65,64.82 125.53,64.7 125.53,64.34 v1(125.68,64.19)
M_A_DQS_DN5: length 49.3
  TOP w0.114: v1(96.93,58.74) v2(97.16,59.27)
  L4 w0.152: v1(127.28,72.34) 127.28,72.49 127.14,72.62 126.92,72.62 126.34,72.04 126.34,71.76 124.85,70.26 113.98,70.26 105.93,62.22 104.81,62.22 101.9,59.31 97.09,59.31 96.88,59.09 96.88,58.79 v1(96.93,58.74)
  BOTTOM w0.114: v1(96.93,58.74) 96.93,58.73 97.19,58.46 97.19,58.16 96.94,57.9 96.58,57.9 96.3,58.18 96.04,58.18 95.49,57.63 94.79,57.63 93.61,56.45 91.1,56.45 90.97,56.33 90.49,56.33 90.44,56.37 CPU1.AM41 ; v1(127.28,72.34) 127.51,72.11 127.51,71.8 127.81,71.49 129.03,71.49 129.15,71.38 DIMM1.198
M_A_DQS_DN6: length 53
  TOP w0.114: v1(126.73,77.06) v2(126.73,76.48)
  L4 w0.152: v1(92.99,62.32) 93.59,62.32 95.1,63.83 99.36,63.83 107.07,71.54 107.07,71.83 107.07,72.15 107.42,72.49 108.02,72.49 108.63,73.09 108.63,73.7 108.97,74.04 109.57,74.04 110.06,74.53 110.06,75.14 110.41,75.48 111.01,75.48 111.63,76.09 112.45,76.09 112.75,75.8 113.58,75.8 113.87,76.09 114.48,76.09 114.78,75.8 115.61,75.8 115.91,76.09 124.34,76.09 124.71,75.72 125.4,75.72 126.16,76.48 126.41,76.7 v1(126.73,77.06)
  BOTTOM w0.114: v1(92.99,62.32) 92.46,62.32 92.14,62 92.14,60.35 91.44,59.65 90.45,59.65 90.43,59.67 CPU1.AV41 ; v1(126.73,77.06) 126.49,76.83 126.49,76.28 126.11,75.9 125.25,75.9 124.52,76.62 DIMM1.219
M_A_DQS_DN7: length 59.5
  TOP w0.114: v2(126.86,82.36) v1(127.18,82.83)
  L4 w0.152: v1(127.18,82.83) 127.18,83.16 127.03,83.31 126.27,83.31 125.72,82.77 122.52,82.77 122.22,83.07 122.22,83.26 122.07,83.42 121.61,83.42 121.46,83.26 121.46,83.07 121.16,82.77 118.76,82.77 118.47,83.06 118.47,83.62 118.31,83.77 117.48,83.77 117.32,83.62 117.32,83.03 117.02,82.73 116.35,82.73 116.05,83.03 116.05,83.47 115.88,83.64 108.69,83.64 94.11,69.06 94.11,68.07 91.52,65.48 88.98,65.48 88.82,65.33 88.82,64.97 v1(88.91,64.88)
  BOTTOM w0.114: v1(88.91,64.88) 88.91,64.1 87.99,63.17 87.99,61.84 87.89,61.75 87.89,61.47 87.96,61.4 87.96,61.14 87.65,60.83 CPU1.AY36 ; v1(127.18,82.83) 127.43,82.58 127.43,82.28 127.69,82.02 129,82.02 129.15,81.88 DIMM1.240
M_A_DQS_DP0: length 60.7
  L4 w0.152: v1(125.02,21.91) 125,21.91 124.33,22.58 122.35,22.58 121.97,22.96 121.23,22.96 120.84,22.58 120.32,22.58 119.93,22.96 119.19,22.96 118.81,22.58 118.42,22.58 113.03,27.97 110.74,27.97 110.44,27.67 110.44,27.48 110.29,27.33 109.83,27.33 109.68,27.48 109.68,27.81 109.35,28.14 108.76,28.14 108.41,27.79 108.41,27.38 108.28,27.26 107.82,27.26 107.65,27.43 107.65,28.05 107.34,28.35 106.68,28.35 106.38,28.05 106.38,27.38 106.25,27.26 105.79,27.26 105.61,27.43 105.61,28.05 105.31,28.35 104.64,28.35 104.34,28.05 104.34,27.38 104.22,27.26 103.76,27.26 103.58,27.43 103.58,27.67 103.28,27.97 102.61,27.97 102.31,27.67 102.31,27.38 102.18,27.26 101.73,27.26 101.55,27.43 101.55,27.67 101.25,27.97 100.58,27.97 100.28,27.67 100.28,27.38 100.15,27.26 99.7,27.26 99.52,27.43 99.52,27.67 99.22,27.97 97.84,27.97 95.7,30.1 95.28,30.1 94.85,29.68 94.64,29.68 94.31,30 94.31,30.22 94.74,30.64 94.74,31.07 90.02,35.79 88.52,35.79 v1(88.37,35.94)
  BOTTOM w0.114: v1(125.02,21.91) 125.01,21.92 125.01,22.7 124.69,23.01 122.91,23.01 122.8,23.12 DIMM1.13 ; v1(88.37,35.94) 88.06,35.94 87.63,36.37 87.63,36.83 87.97,37.17 87.97,38.17 87.97,38.18 87.97,38.81 87.89,38.89 87.89,39.17 87.96,39.24 87.96,39.5 87.95,39.51 87.95,39.52 87.65,39.82 CPU1.B36
M_A_DQS_DP1: length 48.3
  TOP w0.114: v2(93.42,38.05) v1(93.73,38.56)
  L4 w0.152: v1(127.06,27.44) 126.8,27.18 126.45,27.18 125.43,28.2 119.66,28.2 113.03,34.83 104.53,34.83 103.93,35.42 97.22,35.42 95.88,36.28 94.29,37.59 94.03,37.59 93.51,38.12 93.51,38.34 v1(93.73,38.56)
  BOTTOM w0.114: v1(127.06,27.44) 127.3,27.56 127.47,27.72 127.47,27.98 127.72,28.24 129.07,28.24 129.21,28.38 DIMM1.34 ; v1(93.73,38.56) 93.73,39.75 92.29,41.19 90.57,41.19 90.24,41.52 CPU1.E40
M_A_DQS_DP2: length 49.6
  TOP w0.114: v1(99.03,41.2) v2(99.03,40.64)
  L4 w0.152: v1(99.03,41.2) 99.03,41.56 99.19,41.71 100.02,41.71 100.63,41.1 101.57,41.1 102.08,40.59 102.9,40.59 103.43,41.12 103.96,41.12 104.49,40.59 105.09,40.59 105.62,41.12 114.52,41.12 115.1,40.55 115.1,39.92 115.58,39.44 116.21,39.44 116.54,39.11 116.54,38.48 117.02,38 117.65,38 117.98,37.67 117.98,37.04 118.45,36.56 118.67,36.56 118.88,36.56 119.08,36.56 119.41,36.24 119.41,35.61 119.89,35.13 120.52,35.13 121.64,34.01 123.14,34.01 123.57,34.44 124.74,34.44 124.85,34.33 124.85,34.12 v1(124.74,34.01)
  BOTTOM w0.114: v1(124.74,34.01) 124.97,34.01 125.11,33.87 125.11,33.26 124.94,33.1 124.33,33.1 123.98,33.45 122.88,33.45 122.71,33.63 DIMM1.55 ; v1(99.03,41.2) 99.21,41.38 99.21,41.72 99.1,41.83 98.67,41.83 98.56,41.95 98.56,43.74 98.07,44.24 91.4,44.24 91.15,44.49 90.59,44.49 90.26,44.82 CPU1.L40
M_A_DQS_DP3: length 47.1
  TOP w0.114: v1(127.98,39.4) v2(127.98,39.96)
  L4 w0.152: v1(94.92,47.68) 94.93,47.67 94.93,47.66 95.19,47.4 96.14,47.4 96.44,47.7 119.41,47.7 121.95,45.16 121.95,42.22 123.27,40.9 126.29,40.9 127.3,39.88 127.53,39.88 127.98,39.43 v1(127.98,39.4)
  BOTTOM w0.114: DIMM1.76 129.17,38.87 128.91,38.62 127.76,38.62 127.64,38.74 127.64,38.99 127.76,39.12 v1(127.98,39.4) ; v1(94.92,47.68) 94.93,47.68 94.93,48.03 94.81,48.14 90.8,48.14 CPU1.U41
M_A_DQS_DP4: length 53.8
  TOP w0.114: v1(93.22,53.62) v2(93.22,54.18)
  L4 w0.152: v1(126.37,64.2) 126.37,64.3 125.72,64.95 120.02,64.95 114.11,59.04 113.51,59.04 112.98,59.57 112.6,59.57 112.13,59.1 112.13,58.72 112.77,58.08 112.77,57.86 112.42,57.51 112.16,57.51 111.42,58.24 111.05,58.24 110.55,57.75 110.55,57.37 111.21,56.71 111.21,56.55 110.83,56.18 110.62,56.18 110.15,56.64 109.78,56.64 109.09,55.95 109.09,55.09 108.04,54.05 95.06,54.05 94.6,54.5 94.1,54.5 v1(93.22,53.62)
  BOTTOM w0.114: DIMM1.179 122.68,66.62 123.27,66.04 125.88,66.04 126.37,65.56 v1(126.37,64.2) ; v1(93.22,53.62) 93.19,53.62 92.54,52.97 91.04,52.97 90.94,53.07 CPU1.AF41
M_A_DQS_DP5: length 49.3
  TOP w0.114: v2(96.44,58.22) v1(96.29,58.78)
  L4 w0.152: v1(127.99,72.32) 127.43,72.87 126.82,72.87 126.09,72.14 126.09,71.86 124.74,70.52 113.87,70.52 105.83,62.47 104.71,62.47 101.8,59.56 96.99,59.56 96.29,58.86 v1(96.29,58.78)
  BOTTOM w0.114: v1(96.29,58.78) 95.39,57.88 94.69,57.88 93.51,56.69 91,56.69 90.87,56.57 90.59,56.57 90.48,56.68 90.22,56.68 89.91,56.37 CPU1.AM40 ; v1(127.99,72.32) 127.75,72.07 127.75,71.9 127.91,71.73 129.06,71.73 129.21,71.88 DIMM1.200
M_A_DQS_DP6: length 52.9
  TOP w0.114: v2(125.6,77.5) v1(126.06,77.04)
  L4 w0.152: v1(126.06,77.04) 126.06,76.74 125.72,76.39 125.29,75.97 124.82,75.97 124.44,76.35 115.8,76.35 115.5,76.05 114.89,76.05 114.59,76.35 113.77,76.35 113.47,76.05 112.85,76.05 112.56,76.35 111.52,76.35 110.91,75.73 110.3,75.73 109.81,75.24 109.81,74.64 109.47,74.3 108.86,74.3 108.37,73.8 108.37,73.2 107.92,72.74 107.31,72.74 106.82,72.25 106.82,71.83 106.82,71.65 99.26,64.09 94.99,64.09 93.85,62.94 v1(93.27,62.94)
  BOTTOM w0.114: DIMM1.221 122.83,77.13 123.08,76.87 124.62,76.87 125.35,76.14 126.01,76.14 126.25,76.38 126.25,76.85 v1(126.06,77.04) ; v1(93.27,62.94) 93.01,62.94 92.64,62.56 92.36,62.56 91.9,62.1 91.9,60.45 91.34,59.89 90.56,59.89 90.48,59.98 90.2,59.98 89.89,59.67 CPU1.AV40
M_A_DQS_DP7: length 59.3
  TOP w0.114: v2(128.19,82.42) v1(127.85,82.86)
  L4 w0.152: v1(127.85,82.86) 127.39,83.31 127.38,83.31 127.13,83.57 126.16,83.57 125.62,83.02 122.63,83.02 122.47,83.18 122.47,83.37 122.17,83.67 121.51,83.67 121.2,83.37 121.2,83.18 121.05,83.02 118.86,83.02 118.72,83.17 118.72,83.72 118.42,84.02 117.37,84.02 117.07,83.72 117.07,83.14 116.92,82.98 116.46,82.98 116.31,83.14 116.31,83.57 115.98,83.9 108.58,83.9 93.85,69.17 93.85,68.18 91.41,65.74 88.87,65.74 88.57,65.44 88.57,65.16 88.39,64.98 v1(88.39,64.42)
  BOTTOM w0.114: DIMM1.242 129.06,82.37 128.94,82.26 127.79,82.26 127.67,82.38 127.67,82.68 v1(127.85,82.86) ; v1(88.39,64.42) 88.59,64.23 88.59,64.11 87.74,63.27 87.74,61.94 87.65,61.85 CPU1.BA36
M_A_EVENT#: length 39.8
  TOP w0.089: v1(93.9,51.08) 93.92,51.1 R501.1 ; v2(128.4,54.37) v1(128.03,53.88)
  L4 w0.114: v1(93.9,51.08) 94.44,50.55 96.44,50.55 96.6,50.4 109.4,50.4 117.63,54.92 125.35,54.92 125.78,54.48 127.69,54.48 128.03,54.14 v1(128.03,53.88)
  BOTTOM w0.089: DIMM1.134 130.09,53.37 128.46,53.37 128.03,53.8 v1(128.03,53.88)
M_A_EVENT#_APU: length 9
  TOP w0.089: R504.2 92.24,50.83 92.34,50.73 92.86,50.73 v1(93.27,51.13) 93.27,51.06 94.11,50.21 v2(94.37,50.21) 94.65,50.21 95.44,51 R501.2
  BOTTOM w0.089: v1(93.27,51.13) 92.86,50.73 92.76,50.73 92.36,50.32 CPU1.AA41
M_A_ODT0: length 48.9
  TOP w0.14: v1(126.11,62.61) v2(126.11,62.05)
  L3 w0.102: v1(87.55,57.48) 87.55,57.44 88.24,56.75 88.47,56.75 88.6,56.72 90.12,56.72 90.16,56.76
  L3 w0.216: v1(126.11,62.61) 125.6,62.1 122.18,62.1 121.64,62.64 116.59,62.64 112.32,58.37 99.8,58.37 98.86,59.31 95.15,59.31 94.64,58.81 93.77,58.81 92.45,57.48 90.88,57.48 90.16,56.76
  BOTTOM w0.14: v1(87.55,57.48) 87.55,57.17 CPU1.AN37 ; DIMM1.155 124.25,60.62 126.11,62.49 v1(126.11,62.61)
M_A_ODT1: length 49.8
  TOP w0.14: v2(123.98,63.2) v1(123.98,62.64)
  L3 w0.102: 90.17,57.35 89.74,56.92 88.68,56.92 88.57,56.97 88.3,56.97 87.96,57.31 87.96,58.12 v1(88.42,58.57)
  L3 w0.216: 90.17,57.35 92,59.19 93.75,59.19 93.75,59.18 94.01,59.18 94.01,59.19 94.34,59.19 95,59.84 99.09,59.84 99.49,59.44 103.43,59.44 103.65,59.22 103.65,59.07 103.87,58.85 104.3,58.85 104.51,59.07 104.51,59.48 104.73,59.69 105.16,59.69 105.38,59.48 105.38,59.07 105.59,58.85 106.02,58.85 106.24,59.07 106.24,59.48 106.46,59.69 106.89,59.69 107.1,59.48 107.1,59.07 107.32,58.85 107.75,58.85 107.97,59.07 107.97,59.48 108.18,59.69 108.62,59.69 108.83,59.48 108.83,59.07 109.05,58.85 109.48,58.85 109.7,59.07 109.7,59.48 109.91,59.69 110.34,59.69 110.56,59.48 110.56,59.07 110.77,58.85 111.21,58.85 112.15,59.79 112.75,59.79 116.15,63.2 123.57,63.2 123.98,62.79 v1(123.98,62.64)
  BOTTOM w0.14: DIMM1.161 123.79,62.13 123.98,62.31 v1(123.98,62.64) ; v1(88.42,58.57) 88.6,58.76 CPU1.AU38
M_A_PARITY: length 4.3
  TOP w0.14: R1202.2 122.3,56.03 121.77,56.57 v1(121.41,56.57) v2(121.41,57.13)
  BOTTOM w0.14: DIMM1.143 120.92,55.62 120.78,55.76 120.78,56.24 121.16,56.62 121.36,56.62 v1(121.41,56.57)
M_A_RAS#: length 48
  TOP w0.14: v1(126.75,58.75) v2(126.19,58.75)
  L3 w0.102: v1(88.34,55.26) 88.85,54.76 90.22,54.76
  L3 w0.216: 90.22,54.76 90.46,54.76 90.88,55.17 97.51,55.17 98.07,55.73 98.91,55.73 99.47,55.17 100.1,55.17 100.61,55.68 101.14,55.68 101.57,55.25 102.13,55.25 102.61,55.73 103.25,55.73 103.81,55.17 104.24,55.17 104.85,55.78 113.64,55.78 117.8,59.95 125.55,59.95 v1(126.75,58.75)
  BOTTOM w0.14: v1(126.75,58.75) 126.75,59.31 127.31,59.87 DIMM1.152 ; CPU1.AJ37 v1(88.34,55.26)
M_A_WE#: length 50.9
  TOP w0.14: v1(127.38,62.49) 127.38,62.43 127.72,62.1 127.72,62.09 v2(127.75,62.06)
  L3 w0.102: v1(88.29,56.34) 88.72,55.91 89.34,55.91 89.52,56.08
  L3 w0.216: v1(127.38,62.49) 127.38,62.42 126.52,61.56 121.91,61.56 121.36,62.1 116.81,62.1 112.22,57.51 94.09,57.51 93.68,57.1 90.95,57.1 89.94,56.08 89.52,56.08
  BOTTOM w0.14: v1(127.38,62.49) 127.38,61.58 125.42,59.62 DIMM1.151 ; v1(88.29,56.34) 88.29,56.13 CPU1.AL38
M_VREF_CA_DIMMA: length 1.4
  BOTTOM w0.254: DIMM1.164 v1(128.66,62.87)
  vias: v2(131.14,62.27)
M_VREFDQ: length 4.4
  BOTTOM w0.14: CPU1.Y41 90.9,49.77 91,49.86 92.33,49.86 92.54,49.65 93.97,49.65 94.07,49.75 94.25,49.75 TP501.1
M_ZVDDIO: length 5.3
  TOP w0.203: R503.2 90.63,51.59 90.93,51.89 v2(91.7,51.89) 92.38,51.89 92.58,51.69 v1(92.58,51.16)
  BOTTOM w0.203: CPU1.AB41 90.48,50.74 92.16,50.74 v1(92.58,51.16)
MIC2_VREFO: length 8.3
  TOP w0.203: v1(142.65,91.49) 142.76,91.37 HDA27.23
  L3 w0.254: v1(142.65,91.49) 144.12,92.97 148.22,92.97 149.07,93.82 v1(149.07,93.91)
MIC_CAP: length 6.2
  TOP w0.203: HDA27.15 146.12,93.45
  TOP w0.254: v2(146.28,98.48) 146.28,97.51 C2715.1 145.44,96.67 145.44,94.86 146.13,94.18 146.13,93.45 146.12,93.45
MIC_GND: length 3.7
  TOP w0.508: R5502.1 56.03,83.03 55.7,83.36 v1(55.7,83.9)
  BOTTOM w0.305: v2(56.62,83.31) 56.29,83.31 v1(55.7,83.9) 55.6,84 LCD1.20
MODEL_ID: length 184.5
  TOP w0.102: R2414.1 44.91,28.37 45.36,27.92 45.36,27.81 46.48,26.7 46.48,25.71 47.19,24.99 47.19,22.99 47.14,22.94 47.14,22.89 47.04,22.79 47.04,21.64 46.8,21.4 46.8,21.02 46.86,20.96 v2(46.86,19.04) 46.86,15.45 50.8,11.51 v1(51.28,11.51)
  L3 w0.102: v1(51.28,11.51) 51.28,11.39 51.65,11.03 56.64,11.03 57.71,12.09 77.5,12.09 78.61,10.97 106.68,10.97 107.41,11.71 v1(107.85,11.71)
  BOTTOM w0.102: IOBD1.15 136.22,90.55 135.55,91.22 135.55,91.93 135.09,92.39 134.32,92.39 133.3,91.37 128.19,91.37 127.95,91.61 120.95,91.61 118.72,89.38 118.72,87.44 116.94,85.66 116.94,17.88 116.94,17.69 116.07,16.82 113.91,16.82 113.76,16.68 111.19,16.68 109.5,14.99 109.5,13.69 108.69,12.88 108.58,12.88 107.85,12.14 v1(107.85,11.71)
MODEL_ID_AD: length 5.1
  TOP w0.102: R2414.2 45.01,29.47 45.01,30.56 R2410.2 44.58,30.99 44.58,31.65 44.55,31.68 v1(44.55,31.75) 44.43,31.87 v2(43.99,31.87)
  BOTTOM w0.102: v1(44.55,31.75) 44.55,32.36 44.36,32.55 U2401.94
NC#7: length 2.4
  BOTTOM w0.102: U6305.7 28.45,84.15 R6354.2 28.4,84.1 v2(28.4,83.18)
NCT_CLK: length 95.2
  TOP w0.089: v1(97.52,22.75) 97.52,22.28 96.91,21.67 96.91,18.2 92.77,14.05 89.43,14.05 v1(89,14.48) ; R2476.1 52.89,32.27 53.58,32.95 53.58,33.05 53.69,33.16 53.69,34.63 55.26,36.19 55.26,37.89 v1(55.47,38.11)
  L3 w0.14: v1(97.52,22.75) 97.27,22.5 97.27,22.48 96.94,22.15 95.92,22.15 95.48,22.59 95.48,23.13 95.81,23.46 95.81,24.22 95.22,24.81 94.51,24.81 93.68,23.97 87.86,23.97 86.13,25.71 86.13,25.86 85.62,26.36 85.52,26.36 84.55,27.33 84.55,28.31 84.21,28.65 83.13,28.65 82.62,29.15 82.62,29.8 82.36,30.07 81.99,30.07 81.97,30.05 81.4,30.05 80.07,31.38 78.25,31.38 78.03,31.61 77.11,31.61 74.01,34.71 62.48,34.71 62.11,35.07 61.69,35.07 61.15,34.53 57,34.53 55.47,36.06 v1(55.47,38.11) ; v1(85.95,15.17) 85.95,15.11 86.5,14.56 86.53,14.56 86.61,14.48 v1(89,14.48)
  BOTTOM w0.089: v1(85.95,15.17) 85.95,15.19 86.07,15.31 86.07,17.11 87.53,18.57 91.21,18.57 91.36,18.72 EC2601.1 91.36,20.2 U2601.8 ; v1(89,14.48) 89,14.61 89.44,15.05 Q2604.1 89.93,15.05 90.2,15.32 90.2,16.54 90.02,16.71 90.01,16.71 89.92,16.8 87.39,16.8 86.94,16.35 RN2601.4
NCT_CLK_R: length 3
  TOP w0.089: R2476.2 53.76,32.31 54,32.56 v1(54,32.84)
  BOTTOM w0.089: v1(54,32.84) 53.97,32.87 53.97,32.92 53.55,33.34 53.49,33.41 53.49,33.96 53.55,34.02 U2401.119
NCT_DATA: length 13.2
  BOTTOM w0.089: R2477.1 87.75,14.46 87.02,15.19 RN2601.3 86.64,15.19 86.44,15.39 86.44,16.87 86.74,17.17 89.51,17.17 89.53,17.16 90.17,17.16 ; U2601.7 91.98,18.25 91.89,18.16 v2(91.8,18.16) EC2602.1 90.35,18.16 90.17,17.99 90.17,17.16 ; 90.17,17.16 90.98,16.35 Q2604.4
NCT_DATA_R: length 54.4
  TOP w0.089: v2(52.11,25.39) 52.5,25 v1(52.5,25)
  L3 w0.14: v1(83.43,17.68) 82.8,17.68 82.3,18.18 80.03,18.18 79.26,18.96 78.67,18.96 77.22,20.41 75.3,20.41 74.99,20.72 70.98,20.72 70.79,20.53 69.93,20.53 69.4,20 66.51,20 66.2,19.69 63.79,19.69 63.29,20.19 61.08,20.19 60.55,19.67 58.72,19.67 58.41,19.98 55.73,19.98 54.93,20.79 54.93,21.55 54.33,22.14 53.95,22.14 53.14,22.95 53.14,23.51 53.26,23.62 53.26,24.29 52.54,25 v1(52.5,25)
  BOTTOM w0.089: U2401.120 53.95,34.01 53.85,33.91 53.85,33.55 54.09,33.3 54.14,33.3 54.43,33.01 54.43,32.39 51.82,29.78 51.82,29.42 52.2,29.04 52.54,29.04 52.98,28.6 52.98,26.35 52.5,25.87 v1(52.5,25) ; v1(83.43,17.68) 83.78,17.33 83.78,16.74 86.15,14.37 R2477.2
P2800_DXN: length 78.1
  TOP w0.254: Q2601.E 57.67,53.2 R2604.2 57.18,52.71 C2604.2 57.18,51.51 56.77,51.1 56.77,46.94 57.33,46.38 57.33,43.11 58.01,42.42 58.01,39.21 58.67,38.55 58.67,36.81 58.02,36.16 58.02,35.26 57.99,35.24 57.99,33.16 57.99,33.15 57.99,31.42 59.2,30.2 60.07,30.2 62.01,28.26 v2(62.01,26.64) 62.01,24.81 v1(62.18,24.64)
  L4 w0.254: v1(62.18,24.64) 62.35,24.64 63.59,23.41 63.65,23.34 64.52,23.34 65.91,21.95 67.44,21.95 67.94,22.46 72.19,22.46 72.96,23.23 74.35,23.23 76.24,25.12 79.15,25.12 79.71,24.56 84.84,24.56 84.86,24.54 85.12,24.54 87.67,21.98 88.91,21.98 89.38,21.5 93.48,21.5 94.55,20.42 95.35,20.42 95.68,20.09 v1(95.68,19.92)
  BOTTOM w0.254: U2601.3 92.63,23.63 93.2,23.06 94.28,23.06 C2605.2 94.89,22.86 95.03,22.86 95.43,22.46 95.43,20.35 95.68,20.09 v1(95.68,19.92)
P2800_DXP: length 80.1
  TOP w0.254: Q2601.C 56.72,55.07 Q2601.B 55.77,53.3 R2604.1 56.26,52.81 C2604.1 56.26,46.73 56.82,46.17 56.82,42.9 57.51,42.21 57.51,39 58.16,38.34 58.16,37.02 57.51,36.37 57.51,35.47 57.49,35.45 57.49,33.37 57.48,33.36 57.48,31.21 57.89,30.8 v2(57.89,30.77) 57.93,30.73 57.96,30.73 58.99,29.69 59.86,29.69 61.5,28.05 v1(61.5,24.69)
  L4 w0.254: v1(94.97,19.92) 94.34,19.92 93.26,20.99 89.17,20.99 88.7,21.47 87.46,21.47 84.9,24.03 84.65,24.03 84.63,24.06 79.49,24.06 79.3,24.25 79.3,24.26 78.94,24.61 76.45,24.61 74.56,22.72 73.17,22.72 72.4,21.95 68.16,21.95 67.65,21.44 65.7,21.44 64.31,22.84 63.44,22.84 63.38,22.9 62.14,24.13 61.97,24.13 61.5,24.6 v1(61.5,24.69)
  BOTTOM w0.254: U2601.2 91.98,23.56 92.99,22.56 94.28,22.56 C2605.1 94.82,22.35 94.92,22.25 94.92,19.97 v1(94.97,19.92)
P_ZVDDP: length 3.1
  TOP w0.203: v1(73.03,47.63) 72.67,47.99 72.67,48.42 v2(72.66,48.42) 72.67,48.43 72.67,49.48 R301.2
  BOTTOM w0.203: v1(73.03,47.63) 73.03,47.72 72.63,48.12 CPU1.U8
P_ZVSS: length 2.7
  TOP w0.203: v2(73.42,50.24) 73.42,50.17 v1(73.06,49.81) 73.06,49.47 73.43,49.1 R302.1
  BOTTOM w0.203: v1(73.06,49.81) 73.06,49.68 CPU1.W8
PBAT_PRES1#: length 7
  TOP w0.102: v1(115.1,15.39) 115.19,15.39 115.85,16.05 AFTP4301.1 115.85,16.11 113.82,16.11 113.16,15.44 113.15,15.44 112.88,15.17 RN4301.3
  BOTTOM w0.102: v1(115.1,15.39) 115.1,14.98 115.77,14.3 BATT1.6
PBAT_SMBCLK1: length 14.8
  TOP w0.089: RN4302.3 112.87,16.72 112.96,16.81 112.96,17.74 113.21,17.99 113.57,17.99 113.81,17.74 113.81,17.39 114.03,17.18 117.81,17.18 AFTP4303.1 118.64,16.44 119.41,16.44 119.97,15.88 120.61,15.88 v1(120.78,16.05)
  BOTTOM w0.089: BATT1.4 118.28,14.84 118.36,14.93 118.91,14.93 119.73,15.75 120.57,15.75 120.78,15.95 v1(120.78,16.05)
PBAT_SMBDAT1: length 11.1
  TOP w0.089: RN4301.4 113.02,15.82 113.66,16.47 116.56,16.47 116.74,16.28 116.74,15.78 117.2,15.32 118.49,15.32 AFTP4302.1 118.7,15.32 v1(119.03,15.65)
  BOTTOM w0.089: v1(119.03,15.65) 118.67,15.29 117.72,15.29 117.03,14.59 BATT1.5
PCB_VER_AD: length 7.1
  TOP w0.102: v1(42.57,34.83) 42.21,34.47 R2438.1 40.67,34.47 C2417.1 40.56,34.37 R2437.2
  BOTTOM w0.102: U2401.98 45.15,35.36 44.93,35.59 44.58,35.59 43.82,34.83 v1(42.57,34.83) 42.28,34.83 42.19,34.91 v2(42.01,34.91)
PCIE_RST#_C: length 2.1
  TOP w0.102: R1729.2 70.41,53.44 70.1,53.13 70.1,53.09 v1(70.08,53.06) v2(69.52,53.06)
  BOTTOM w0.102: v1(70.08,53.06) 70.2,52.94 CPU1.AE4
PD4403_A: length 4.5
  BOTTOM w0.254: PQ4413.B 28.71,59.04 29.25,58.5 29.64,58.5 29.68,58.55 29.7,58.55 29.89,58.74 v2(30.28,58.74) 30.59,58.74 30.85,58.49 30.85,57.85 31.1,57.6 PD4404.A
PD4403_K: length 4.6
  BOTTOM w0.254: PR4432.2 30.35,59.49 30.73,59.11 v2(31.66,59.11) 31.89,59.11 33.4,57.6 PD4404.K
PD4410_2: length 7.2
  TOP w0.254: v1(132.87,25.1) 133.12,25.1 133.53,25.5 v2(133.53,26.09) PR4481.2 133.58,27.26 134.57,28.25 134.57,29.01 PQ4416.3
  BOTTOM w0.254: v1(132.87,25.1) 133.29,25.1 134.43,26.24 PD4410.2
PDB_R: length 8.4
  TOP w0.102: R2712.2 153.53,84.14 v2(152.77,84.14) 151.07,84.14 150.04,85.18 150.04,85.19 149.83,85.4 149.83,86.57 148.52,87.89 HDA27.40
PG_1: length 178.6
  TOP w0.254: v2(132.86,38.13) 132.86,38.1 v1(132.46,37.7)
  L4 w0.254: v1(132.46,37.7) 132.77,37.39 133.27,37.39 133.75,36.91 133.75,33.64 131.22,31.11 131.22,18.52 128.35,15.65 122.85,15.65 121.67,16.83 119.63,16.83 119.48,16.68 118.44,16.68 117.88,17.23 117.88,17.81 117.58,18.11 117.1,18.11 113.66,21.55 112.15,21.55 111.75,21.95 108.14,21.95 107.45,22.63 107.36,22.63 106.62,23.37 96.24,23.37 94.89,24.72 89.66,24.72 88.77,25.6 87.43,25.6 82.75,30.28 76.93,30.28 73.88,33.33 70.91,33.33 70.58,33.66 67.57,33.66 67.09,33.17 61.02,33.17 60.89,33.3 59.97,33.3 59.48,32.81 56.5,32.81 55.83,32.14 55.43,32.14 54.55,31.27 53.31,31.27 53.06,31.02 51.87,31.02 50.31,29.46 49.83,29.46 48.71,28.35 43.36,28.35 42.13,29.58 39.77,29.58 39.55,29.36 38.42,29.36 37.76,30.02 35.94,30.02 33.75,32.21 32.38,32.21 31.74,32.84 28.47,32.84 28.07,33.25 26.47,33.25 23.62,36.1 23.62,36.47 22.63,37.46 22.63,40.24 21.79,41.07 21.79,55.33 25.04,58.58 25.04,62.01 27.57,64.53 27.57,65.45 v1(27.38,65.64)
  BOTTOM w0.254: PG4429.1 26.75,65 v1(27.38,65.64) ; PR4467.1 133.17,37.7 v1(132.46,37.7)
PG_2: length 176.4
  TOP w0.254: v1(132.46,36.83) 132.43,36.87 132.06,36.87 v2(131.91,36.72)
  L4 w0.254: v1(28.17,65.66) 27.95,65.44 27.95,64.37 25.43,61.85 25.43,58.42 22.17,55.17 22.17,41.23 23.01,40.39 23.01,37.62 24,36.63 24,36.25 26.62,33.63 28.22,33.63 28.63,33.22 31.9,33.22 32.54,32.59 33.91,32.59 36.09,30.41 37.92,30.41 38.58,29.75 39.4,29.75 39.61,29.96 42.29,29.96 43.52,28.73 48.55,28.73 49.67,29.84 50.16,29.84 51.71,31.4 52.9,31.4 53.16,31.65 54.4,31.65 55.27,32.52 55.68,32.52 56.34,33.19 59.32,33.19 59.81,33.68 61.05,33.68 61.18,33.56 66.93,33.56 67.41,34.04 70.74,34.04 71.07,33.71 74.04,33.71 77.09,30.66 82.91,30.66 87.58,25.99 88.93,25.99 89.81,25.1 95.05,25.1 96.4,23.75 106.78,23.75 107.52,23.01 107.61,23.01 108.3,22.33 111.91,22.33 112.31,21.93 113.82,21.93 117.26,18.49 117.74,18.49 118.26,17.97 118.26,17.39 118.6,17.06 119.32,17.06 119.47,17.21 121.82,17.21 123.01,16.03 128.19,16.03 130.84,18.68 130.84,31.26 133.36,33.79 133.36,36.76 133.11,37.01 132.64,37.01 v1(132.46,36.83)
  BOTTOM w0.254: v1(132.46,36.83) PR4468.1 ; PG4407.1 28.02,65.46 28.17,65.61 v1(28.17,65.66)
PLT_RST#: length 293.9
  TOP w0.089: v1(54.89,23.47) 54.56,23.47 53.92,24.11 53.4,24.11 52.98,24.53 52.71,24.53 52.7,24.52 52.38,24.52 51.75,25.15 51.75,25.68 51.75,25.75 51.58,25.92 51.58,27.59 49.99,29.19 R6803.1 ; v1(162.27,82.29) 161.99,82 AFTP6105.1 161.72,81.74 154.87,74.88 146.81,74.88 142.14,70.21 142.14,69.65 140.77,68.28 140.38,68.28 138.94,66.84 132.89,66.84 v1(131.42,68.3) ; v1(73.79,19.64) 73.86,19.56 75.39,19.56 76.29,20.46 76.29,21.18 75.56,21.9 75.56,26.73 76.61,27.77 76.61,30.57 70.05,37.13 70.05,40.8 70.06,40.8 70.06,44.17 69.27,44.96 69.27,45.87 69.26,45.88 69.26,46.01 69.08,46.18 69.08,50.64 70.21,51.77 70.41,51.77 70.78,52.14 EC1701.2 71.6,53.44 R1729.1
  L3 w0.14: v1(102.01,22.86) 102.22,22.65 107.4,22.65 107.4,22.65 107.46,22.65 108.09,22.02 113.79,22.02 117.8,18.02 118.99,18.02 119.08,17.93 126.89,17.93 129.57,20.6 129.57,31.19 130.23,31.85 130.23,58.96 130.11,59.08 130.11,60.97 130.3,61.16 130.3,67.13 130.31,67.14 130.31,67.19 v1(131.42,68.3)
  L4 w0.14: v1(54.89,23.47) 54.89,22.88 55.01,22.76 55.01,19.35 56.7,17.67 69.21,17.67 69.23,17.65 69.6,17.65 69.62,17.67 72.05,17.67 73.79,19.41 v1(73.79,19.64) 74.02,19.86 75.19,19.86 75.98,20.66 76.46,20.66 77.35,20.66 78,21.31 78.54,21.31 78.8,21.57 84.41,21.57 86.83,19.15 87.48,19.15 88.14,18.49 89.26,18.49 91.55,16.19 100.52,16.19 101.74,17.41 101.74,18 v1(102.23,18.49)
  BOTTOM w0.089: v1(102.23,18.49) 102.01,18.72 v1(102.01,22.86) 102.01,69.35 93.04,78.32 93.04,80.07 93.49,80.52 93.49,81.34 C1701.1 93.73,81.59 R6328.2 ; WLAN1.52 161.92,82 162.15,82.23 162.21,82.23 162.26,82.29 v1(162.27,82.29)
PLT_RST#_DEBUG: length 7.2
  TOP w0.089: DB1.4 47.19,33.36 47.2,33.35 47.2,33.05 v2(47.67,32.59) 48.8,32.59 49.99,31.4 R6803.2 R6802.2
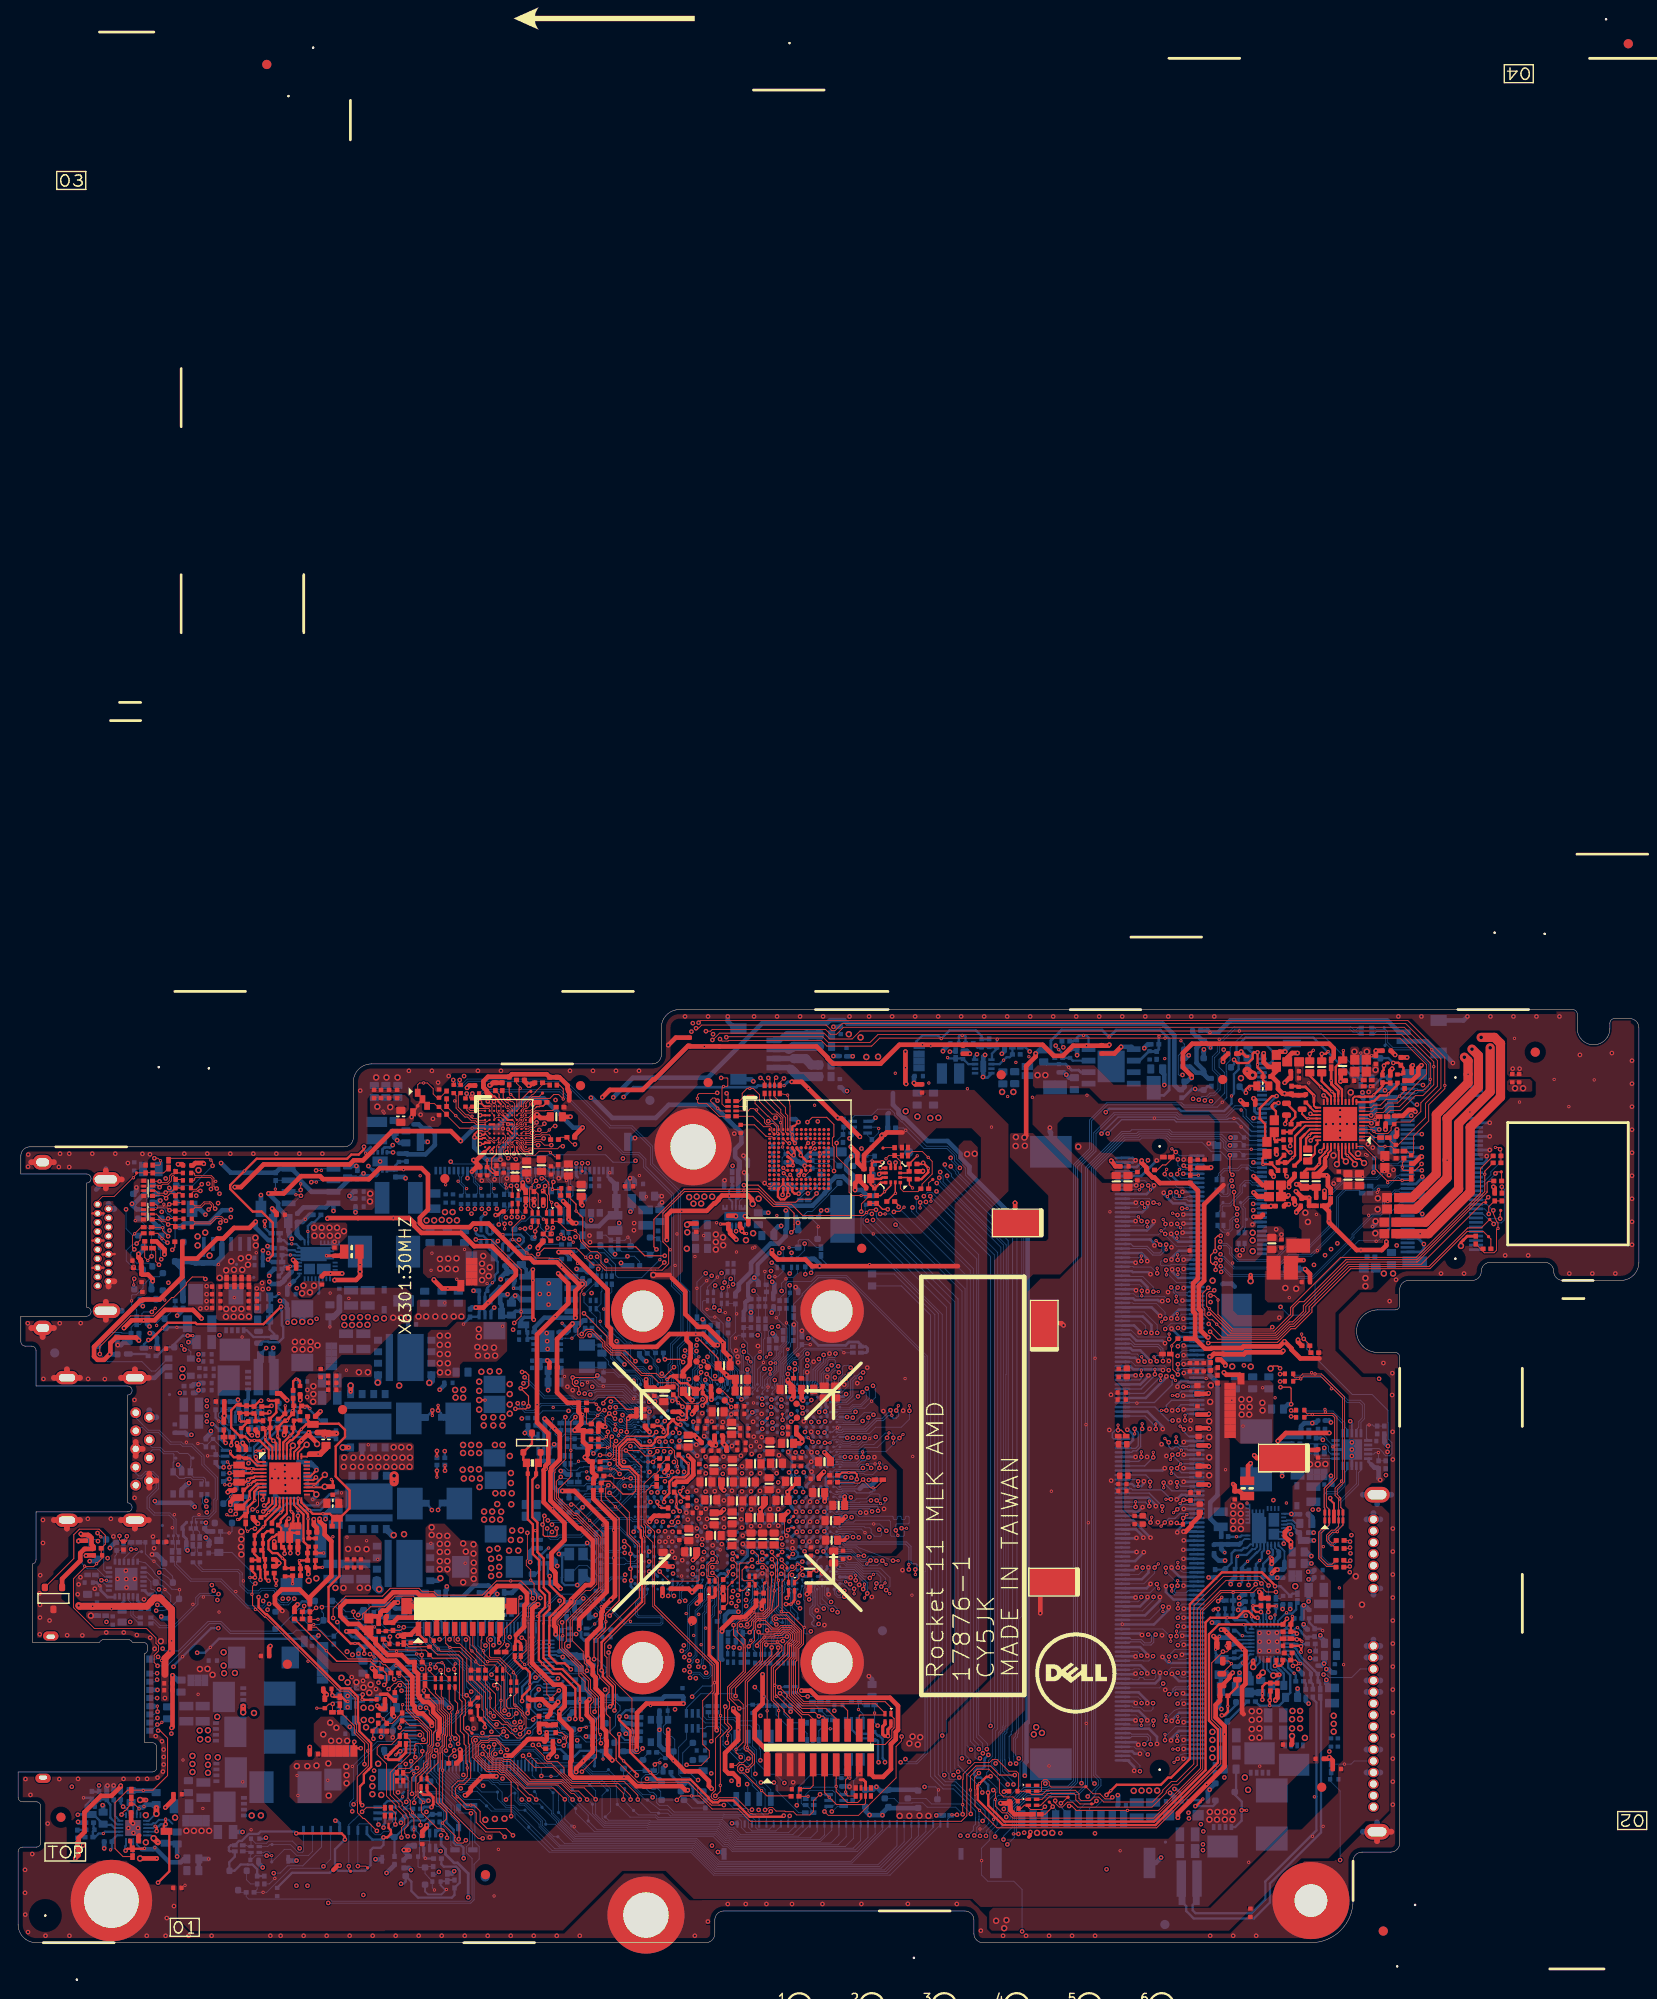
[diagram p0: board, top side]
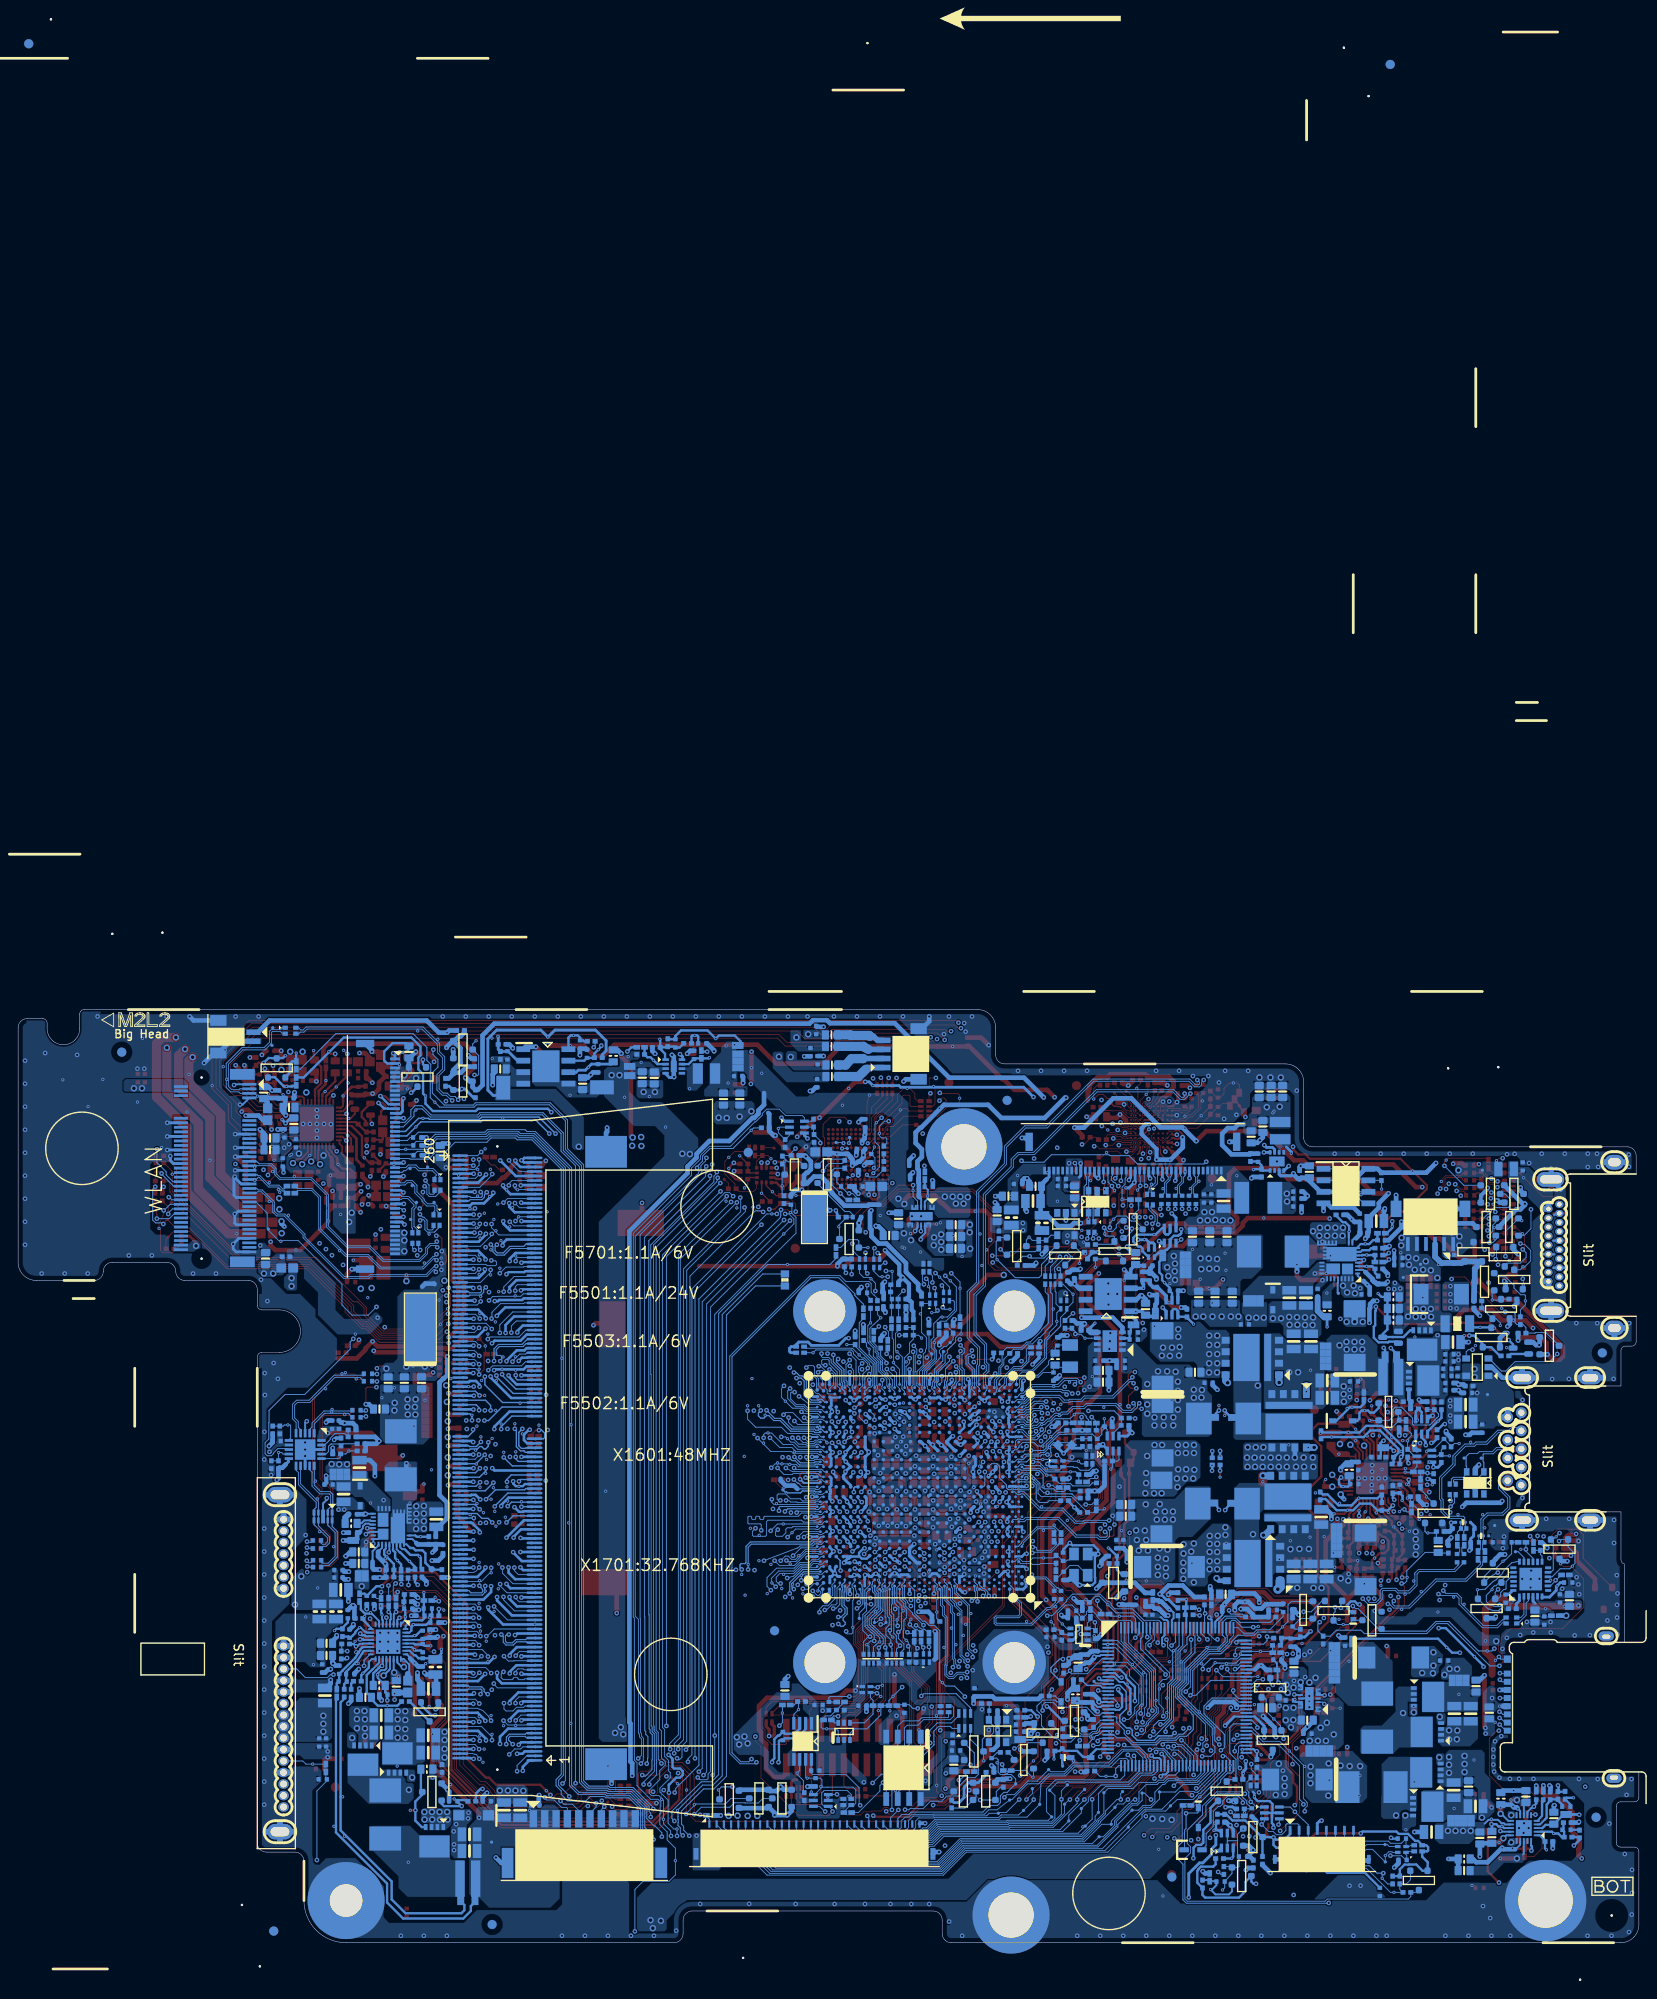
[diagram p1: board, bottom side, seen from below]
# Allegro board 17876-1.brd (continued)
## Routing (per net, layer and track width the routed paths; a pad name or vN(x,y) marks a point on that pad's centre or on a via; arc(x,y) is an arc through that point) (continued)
PLTRST#_CPU_D: length 3.8
  BOTTOM w0.102: R6327.2 94.29,85.7 Q6301.D 94.57,84.51 v2(94.57,83.54) 94.57,82.65 R6328.1
PM_PWRBTN#: length 34.1
  TOP w0.089: v1(65.15,50.5) 64.85,50.2 64.85,49.19 v2(65.93,48.12) 67.22,46.82 67.22,45.02 68.35,43.9 68.35,39.14 v1(65.3,36.1)
  BOTTOM w0.089: U2401.117 52.75,35.36 52.98,35.59 54.64,35.59 55.91,36.86 57.85,36.86 58.26,37.27 58.26,37.45 58.47,37.65 58.65,37.65 59.47,38.48 62.51,38.48 63.17,37.81 63.17,37.69 64.76,36.1 v1(65.3,36.1) ; R1730.1 64.43,50.24 64.69,50.5 v1(65.15,50.5)
PQ3802_1: length 3.8
  BOTTOM w0.102: PR4311.2 17.3,70.08 PR4302.1 16.15,68.88 ; v2(15.29,68.12) 15.29,68.4 15.77,68.88 16.15,68.88 ; 16.15,68.88 PQ4302.B
PQ4209_D: length 2.6
  BOTTOM w0.254: PQ4309.D 16.33,67.92 v2(17.53,67.92) 18.29,67.92 PR4316.2
PQ4405_2: length 4.1
  BOTTOM w0.102: PR4442.1 25.12,56.21 25.12,55.98 25.53,55.57 v2(25.53,55.39) PR4446.2 24.77,53.7 PQ4414.2
PQ4405_3: length 2.2
  BOTTOM w0.102: v2(25.81,51.94) 24.92,51.94 PR4447.1 24.89,52.15 24.5,52.54 PQ4414.3
PQ4405_5: length 3
  BOTTOM w0.102: PQ4414.5 22.22,53.7 22.05,53.87 PR4413.2 ; v2(20.92,53.74) 21.67,53.74 PR4413.2 ; PR4413.2 21.81,54.39 PC4404.1
PQ4405_6: length 4.1
  BOTTOM w0.102: v2(19.84,55.1) 20.37,55.1 PR4448.1 20.73,54.81 PC4404.2 22.77,54.35 PQ4414.6
PQ4408_C: length 3.1
  BOTTOM w0.102: PR4433.1 26.44,57.66 PR4442.2 ; PR4433.1 26.49,57.71 26.49,58.04 26.56,58.11 PQ4413.C ; PR4433.1 26.47,57.63 v2(27.38,56.72)
PQ4408_E: length 12
  BOTTOM w0.102: PR4436.1 22.61,58.85 PR4431.2 22.12,58.37 22.12,58.09 22.29,57.93 22.31,57.93 22.52,57.72 22.52,57.7 23.08,57.14 24.88,57.14 24.98,57.24 24.98,57.91 26.19,59.11 26.9,59.11 27.13,58.88 27.13,58.09 27.57,57.65 PQ4413.E v2(29.72,57.65)
PQ4415_C: length 2.6
  TOP w0.102: PQ4415.3 133.63,31.09 v2(133.92,30.8) 133.92,30.74 PQ4416.1
PR_2: length 2.4
  BOTTOM w0.254: v2(143.99,34.45) 143.97,34.45 143.77,34.65 PR4407.2 143.1,34.76 142.51,35.35 PC4405.1
PROCHOT#_EC: length 8.5
  TOP w0.089: v1(61.99,23.54) 61.99,23.59 62.16,23.76 v2(62.71,23.76)
  BOTTOM w0.089: Q2402.G 64.24,23.59 R2442.1 63.26,23.93 62.55,23.93 62.15,23.54 v1(61.99,23.54) 61.97,23.52 61.97,23.44 61.56,23.02 60.61,23.02 60.31,23.33 59.9,23.33 59.77,23.46 59.77,23.64 59.26,24.15 U2401.24
PROJECT_ID1: length 1.8
  TOP w0.089: v1(62.26,86.05) 62.26,86.04 TP5501.1
  BOTTOM w0.089: v1(62.26,86.05) 62.19,86.05 62.1,85.96 LCD1.33
PS_ID: length 7.2
  BOTTOM w0.102: PR4307.1 13.08,69.85 12.53,70.4 v2(12.53,70.84) 12.53,71.45 12.6,71.52 13.04,71.52 13.79,72.27 13.79,72.57 14.73,73.51 15.58,73.51 PQ4301.S
PS_ID_R: length 11.7
  BOTTOM w0.635: PR4311.1 18.16,72.9 PQ4301.D 18.11,74.39 PD4304.2 PD4304.1 19.4,75.2 19.56,75.03 20.42,75.03 ; 20.42,75.03 21.74,75.03 AFTP4308.1 22.5,75.71 DCIN1.3 ; 20.42,75.03 EC4307.1
PSID_DISABLE#_R_C: length 3
  BOTTOM w0.102: PQ4301.G 16.18,71.79 v2(16.18,70.93) 15.31,70.93 PQ4302.C 15.17,71.05 PR4303.2
PSID_EC: length 96.7
  TOP w0.102: v1(14.76,69.62) 14.76,69.66 15.13,70.03 v2(15.14,70.03)
  L3 w0.102: v1(14.76,69.62) 16.54,67.85 16.54,44.67 17.18,44.02 17.18,42.12 16.94,41.87 16.94,37.85 21.68,33.11 23.74,33.11 26.24,30.61 30.84,30.61 31.24,30.2 32.91,30.2 35.52,27.59 35.52,25.9 37.64,23.77 37.64,23.46 38.09,23.01 39.55,23.01 39.67,23.14 41.71,23.14 42.98,21.87 v1(46.3,21.87)
  BOTTOM w0.102: v1(46.3,21.87) 46.36,21.87 46.81,22.33 46.81,23.75 50.44,27.38 50.44,27.89 49.73,28.6 49.73,30.19 47.54,32.39 46.26,32.39 45.44,33.21 45.44,33.89 45.55,34 U2401.99 ; PD4303.3 10.28,67.36 11.39,67.36 11.47,67.29 PR4306.2 12.47,67.92 12.78,68.23 PR4307.2 13.46,68.23 13.67,68.43 13.67,69.42 13.87,69.62 v1(14.76,69.62)
PSL_IN1#: length 9
  BOTTOM w0.102: Q2405.D 45.27,18.01 44.61,18.01 R2473.2 44.47,18.15 44.47,20.24 45.15,20.92 45.15,23.75 44.75,24.15 U2401.73
PSL_IN2#: length 3.8
  BOTTOM w0.102: 40.44,32.03 40.56,32.15 v2(41.78,32.15) U2401.93 ; 40.44,32.03 R2489.1 ; 40.44,32.03 R2488.2
PSL_OUT#: length 44.4
  TOP w0.102: v1(42.11,23.75) 42.11,24.21 R2493.1 42.7,24.49 43.23,23.96 44.43,23.96 45.2,23.19 45.2,22.65 45.19,22.65 45.19,22.16 45.04,22 44.93,22 44.9,21.97 43.92,21.97 43.78,21.84 v2(43.78,21.28) 43.74,21.23 43.74,20.93 43.74,20.58 43.84,20.48 v1(43.84,20.47)
  L3 w0.102: v1(75.05,17.95) 74.55,17.45 70.84,17.45 70.79,17.5 69.65,17.5 69.56,17.4 67.1,17.4 66.6,16.89 49.9,16.89 49.24,17.55 47.8,17.55 44.88,20.47 v1(43.84,20.47)
  BOTTOM w0.102: v1(75.05,17.95) 74.93,17.95 74.22,18.66 PR5411.1 ; U2401.74 42.74,24.55 42.16,23.98 42.16,23.8 v1(42.11,23.75)
PURE_HW_SHUTDOWN#: length 28.5
  L3 w0.102: v1(33.53,37.03) 33.83,37.34 37.52,37.34 38.09,36.77 43.37,36.77 43.74,36.4 43.76,36.4 43.92,36.25 46,36.25 46.53,36.78 48.08,36.78 48.11,36.76 v1(48.54,36.76)
  BOTTOM w0.102: R2603.1 48.9,36.98 48.67,36.76 v1(48.54,36.76) ; R2472.2 37.93,34.61 C2606.1 37.35,35.78 Q2401.B 35.82,35.94 35.82,36.31 35.05,37.09 33.58,37.09 v1(33.53,37.03) 33.53,36.53 33.71,36.35 Q2603.D 33.24,35.12 v2(32.63,35.12) 32.04,35.12 EC2403.1 31.47,35.59 D4001.3
PWR_0D95V:
  vias: v2(45.58,74.22) v2(45.68,76.11) v2(48.42,73.23) v2(49.28,76.53) v3(46.56,75.47) v3(46.58,74.4) v3(47.42,74.4) v3(47.47,75.52) v3(48.31,74.35) v3(48.39,75.54)
PWR_0D95V_BOOT:
  vias: v2(34.44,71.71)
PWR_0D95V_BOOT_A: length 4
  BOTTOM w0.305: v2(34.42,67.97) PR5210.2
  BOTTOM w0.635: PR5210.2 34.82,69.09 35.46,69.72 PC5206.1
PWR_0D95V_CS: length 3.9
  BOTTOM w0.203: PU5201.10 32.02,77.87
  BOTTOM w0.254: PR5202.2 33.43,80.27 32.69,79.53 32.41,79.53 31.98,79.1 v2(31.98,78.51) 32.02,78.47 32.02,77.87
PWR_0D95V_EN: length 2.7
  BOTTOM w0.203: PU5201.6 30.57,75.86
  BOTTOM w0.254: PR5209.2 PR5206.2 29.91,75.9 29.92,75.91 v2(30.05,75.91) 30.53,75.91 30.57,75.86
PWR_0D95V_FB: length 3
  BOTTOM w0.203: PU5201.3 30.3,74.66
  BOTTOM w0.254: PR5207.2 29.13,73.94 PR5208.1 29.39,74.63 29.49,74.63 29.53,74.66 v2(30.05,74.66) 30.3,74.66
PWR_0D95V_PG: length 3.4
  BOTTOM w0.203: 30.72,77.12 31.05,76.79 PU5201.8
  BOTTOM w0.254: PR5204.2 PR5203.2 29.34,77.55 29.77,77.12 30.18,77.12 v2(30.2,77.14) 30.23,77.12 30.72,77.12
PWR_0D95V_PH: length 7.9
  TOP w0.508: PR5211.1 37.74,76.2 v2(37.74,74.84) v1(37.74,74.07) 37.74,73.6 37.3,73.15 34.95,73.15 v1(34.92,73.13)
  BOTTOM w0.508: PL5201.1 37.73,74.08 v1(37.74,74.07)
PWR_0D95V_SNUB: length 2.1
  TOP w0.305: PC5214.1 v2(34.04,75.82)
  TOP w0.508: PC5214.1 35.53,75.82 PR5211.2
PWR_0D95V_TON: length 2.1
  BOTTOM w0.203: PU5201.7 30.71,76.26 30.53,76.44
  BOTTOM w0.254: 30.53,76.44 29.76,76.44 29.54,76.66 PR5205.2
PWR_0D95V_VCC: length 4.9
  BOTTOM w0.203: PU5201.9 31.62,77.55 31.42,77.75 31.22,77.75
  BOTTOM w0.508: 31.22,77.75 30.78,78.18 PR5201.1 30.78,79.53 PC5202.1 31.39,79.55 v2(31.7,79.86) 32.18,80.34 PR5202.1
PWR_0D95V_VDDQ: length 27.9
  TOP w0.508: PG5212.1 v2(47.44,72.21) 46.81,72.21 45.9,73.13 v1(45.9,73.2)
  L3 w0.508: v1(27.72,72.96) 27.76,72.93 27.97,72.93 30.23,70.66 32.87,70.66 33.81,71.6 44.53,71.6 45.9,72.98 v1(45.9,73.2)
  BOTTOM w0.203: PU5201.2 30.42,74.26 30.18,74.02
  BOTTOM w0.508: 30.18,74.02 30.16,74.02 29.41,73.27 29.41,73.13 29.21,72.93 29.13,72.93 28.93,72.72 PR5207.1 28.77,72.71 27.97,72.71 v1(27.72,72.96)
PWR_0D95V_VLDOIN: length 1.7
  BOTTOM w0.203: TP5201.1 33.25,71.76 33.25,72.8 33.22,72.83 PU5201.28
PWR_0D95V_VTTREF: length 2.9
  BOTTOM w0.203: 30.45,73.03 31.05,73.62 PU5201.1
  BOTTOM w0.508: 30.45,73.03 30.39,73.03 v2(29.99,72.63) 29.71,72.35 PC5213.1
PWR_0D775V: length 11.4
  TOP w0.381: v1(56.92,68.76) 56.82,68.86 v2(56.82,73.12) v1(56.82,74.3)
  BOTTOM w0.381: 56.08,73.56 56.08,74.32 PC4904.1 55.42,74.73 PC4903.1 ; 56.08,73.56 v1(56.82,74.3) ; 56.08,73.56 PU4901.4 ; v1(56.92,68.76) 56.65,69.03 55.85,69.03 55.47,68.65 PG4901.1
PWR_0D775V_EN: length 5.3
  BOTTOM w0.254: PG4903.2 52.93,75.16 52.93,73.99 52.63,73.69 52.63,73.13 v2(52.35,72.85) 51.79,72.29 PC4907.1 51.54,71.71 PQ4901.5
PWR_0D775V_EN_R: length 3.9
  BOTTOM w0.254: PQ4901.2 51.54,69.75 51.35,69.94 51.09,69.94 50.89,69.73 PQ4901.3 50.7,69.09 49.91,69.09 PR4901.2 49.75,68.92 49.75,68.87 v2(49.15,68.28)
PWR_0D775V_VIN: length 2.9
  BOTTOM w0.381: PG4902.1 54.33,69.14 PC4905.1 54.89,69.7 PU4901.1
PWR_0D775V_VREF: length 6.3
  BOTTOM w0.381: PQ4901.6 52.19,71.4 53.02,72.24 53.11,72.24 PR4902.2 53.62,72.34 54,72.72 PR4903.1 54.08,73.13 PC4906.1 54.79,72.81 54.68,72.7 v2(54.68,72.24) PU4901.3
PWR_1D0V_FB: length 3.7
  BOTTOM w0.254: v2(42.54,85.33) 42.49,85.38 PR6301.1 ; PU6301.1 41.51,85.23 PR6301.1 ; PR6301.1 41.65,85.8 PC6303.2 42.09,86.23 PR6302.2
PWR_1D0V_LX: length 0.9
  BOTTOM w0.305: 38.91,87.83 38.35,87.28 v2(38.35,87.15)
PWR_1D8V_EN: length 3.3
  BOTTOM w0.254: v2(102.59,97.7) 102.68,97.61 PR5409.2 104.22,97.61 PC5411.1 104.32,97.54 104.89,96.97 PU5401.7
PWR_1D8V_FB: length 5.3
  BOTTOM w0.254: PU5401.1 107.49,98.12 108.03,98.66 PR5405.1 ; v2(108.08,99.72) 108.03,99.67 PR5405.1 ; PR5405.1 107.26,98.83 PR5403.2 106.45,98.91 PC5401.2 105.89,98.81 PR5406.1
PWR_1D8V_FB_R1: length 9.9
  BOTTOM w0.254: PG5401.2 99.16,99.5 99.79,100.13 101.56,100.13 v2(101.89,99.79) 102.8,100.7 105.73,100.7 106.35,100.08 PC5401.1 107.14,99.72 PR5403.1
PWR_1D8V_FB_R2: length 2.4
  BOTTOM w0.254: PR5406.2 104.57,100.04 104.46,100.15 v2(104.21,100.15) 103.97,100.15 103.84,100.02 PC5412.1
PWR_1D8V_PG: length 3.5
  BOTTOM w0.254: PU5401.2 108.34,96.97 v2(108.77,97.41) 109.1,97.74 109.44,97.74 PR5407.2 PR5412.2
PWR_1D8V_PH:
  vias: v2(104.78,94.26)
PWR_1D8V_PVIN:
  vias: v2(110.13,97.17)
PWR_2D5V_PWRGD: length 89.7
  L3 w0.254: v1(134.79,39.5) 134.79,39.55 135.51,40.27 136.3,40.27 137.26,41.23 137.26,41.44 138.17,42.34 139.33,42.34 141.02,44.04 141.02,46.89 141.05,46.92 141.05,50.47 140.97,50.55 140.97,54.76 141.05,54.84 141.05,59.62 140.47,60.2 139.74,60.2 137.64,62.3 137.64,64.82 134.34,68.12 134.34,71.25 134.8,71.71 134.8,74.62 134.01,75.41 134.01,76.68 135.08,77.75 135.08,89.59 132.31,92.36 132.31,93.2 131.34,94.17 131.34,95.47 129.76,97.06 125.07,97.06 125.02,97 118.43,97 118.19,97.25 117.97,97.46 115.56,97.46 114.53,98.49 v1(114.53,99.02)
  BOTTOM w0.254: PU5302.7 116.41,97.36 PC5317.1 115.32,97.66 PR5312.2 115.29,98.15 v2(114.87,98.57) 114.86,98.57 114.53,98.91 v1(114.53,99.02) ; v1(134.79,39.5) 135.09,39.8 PR5306.1
PWR_3D3V:
  vias: v2(32,31.07)
PWR_3D3V_BOOT: length 2.8
  BOTTOM w0.203: 13.39,14.84 13.1,14.55 PU4501.9
  BOTTOM w0.508: PR4503.2 14.1,15.24 v2(13.89,15.04) 13.79,14.94 13.49,14.94 13.39,14.84
PWR_3D3V_BOOT_A: length 2.9
  BOTTOM w0.508: PR4503.1 15.01,16.79 v2(13.82,16.79) PC4511.2
PWR_3D3V_CS: length 2.6
  BOTTOM w0.203: PU4501.5 10.88,13.78 10.88,13.81 10.69,14 10.69,14.04 10.69,14.04
  BOTTOM w0.254: 10.69,14.04 10.69,15.45 10.66,15.49 10.66,15.66 PR4506.1
PWR_3D3V_EN: length 3.9
  TOP w0.102: v2(13.35,14.78) 12.84,15.29 PC4502.1 ; v1(11.42,14.14) 11.48,14.2 11.48,14.3 11.76,14.59 11.85,14.59 12.1,14.84 12.1,14.92 PC4502.1 ; PC4502.1 12.5,15.32 PR4502.1
  BOTTOM w0.102: v1(11.42,14.14) PU4501.6
PWR_3D3V_FB: length 5.4
  BOTTOM w0.203: PU4501.4 10.92,13.05 10.37,13.6
  BOTTOM w0.254: 10.37,13.6 10.18,13.79 10.18,15.24 10.03,15.39 9.78,15.74 PR4508.1 9.75,15.82 PR4505.2 8.93,15.67 8.45,15.22 PC4515.2
PWR_3D3V_FB_A: length 2.1
  BOTTOM w0.254: v2(7.21,15.99) 7.99,15.99 PR4509.2 7.55,15.24 PC4515.1
PWR_3D3V_FB_B: length 39
  L3 w0.254: v1(19.76,32.01) 17.98,32.01 16.54,30.57 16.54,29.31 17.07,28.77 17.07,25.91 16.41,25.25 16.41,22.55 16.58,22.38 16.58,18.69 15.4,17.51 13.01,17.51 12.29,16.79 9.32,16.79 8.93,17.18 v1(8.93,17.36)
  BOTTOM w0.254: v1(8.93,17.36) 8.85,17.24 PR4505.1 8.82,16.63 PR4509.1 ; PG4522.2 22.16,33.56 v2(21.21,32.6) 20.61,32.01 v1(19.76,32.01)
PWR_3D3V_HG: length 20.5
  TOP w0.635: v3(24.84,25.43) v2(24.84,26.09)
  L4 w0.635: v3(14.1,14.07) 14.1,14.22 15.61,15.73 16.09,15.73 18.35,17.99 18.35,21.55 19.15,22.35 19.15,24.49 21,26.34 24.21,26.34 24.84,25.71 v3(24.84,25.43)
PWR_3D3V_LG: length 16.9
  TOP w0.635: v3(15.27,14.23) v2(15.27,14.89)
  L4 w0.635: v3(21.98,24.93) 21.98,24.89 21.84,24.76 21.84,22.05 21.31,21.52 20.4,21.52 20.13,21.25 20.13,17.77 16.59,14.23 v3(15.27,14.23)
  BOTTOM w0.203: PU4501.11 14.41,13.45 15.19,14.23 v3(15.27,14.23)
PWR_3D3V_PH: length 23.6
  TOP w0.508: v3(13.46,15.75) v2(14.12,15.75)
  L4 w0.635: v3(13.46,15.75) 14.55,15.75 15.29,16.49 15.77,16.49 17.58,18.31 17.58,22.04 18.25,22.71 18.25,24.71 20.64,27.1 24.52,27.1 26.04,25.59 v3(26.04,25.35)
  BOTTOM w0.203: PC4511.1 12.7,15.24 PU4501.8
PWR_3D3V_VREG: length 3.5
  BOTTOM w0.203: PU4501.3 10.65,12.65
  BOTTOM w0.254: 10.65,12.65 10.3,13.01 9.52,13.01 PC4517.1 8.33,14.14 PG4524.2
PWR_5V:
  vias: v2(30.79,18.45) v2(30.89,16.25) v2(34.19,17.94) v2(36.89,19.46) v3(30.77,19.49) v3(31.92,19.49) v3(32.94,19.55) v3(34.24,19.79) v3(34.28,16.23) v3(36.23,19.43) v3(36.25,18.49) v3(36.25,17.6)
PWR_5V_BOOT: length 7
  BOTTOM w0.203: PU4501.17 13.1,10.83 13.61,10.31 13.65,10.31
  BOTTOM w0.508: 13.65,10.31 14.93,10.31 v2(15.1,10.48) 16.7,8.88 17.96,8.88 18.33,9.24 PR4504.1
PWR_5V_BOOT_A: length 2.4
  BOTTOM w0.508: v2(21.03,9.24) PR4504.2 19.94,7.96 PC4512.1
PWR_5V_CS: length 2.2
  BOTTOM w0.203: 10.72,11.65 10.92,11.85 PU4501.1
  BOTTOM w0.254: 10.72,11.65 10.36,11.3 PR4507.1 10.36,10.41 v2(10.2,10.25)
PWR_5V_EN: length 4.2
  TOP w0.254: PR4514.1 12.63,10.37 13.9,10.37 v2(13.96,10.42) ; PR4514.1 12.45,10.54 12.45,11.15 PC4501.1 ; PR4514.1 12.06,10.36 v1(11.86,10.16)
  BOTTOM w0.203: PU4501.20 11.9,10.72
  BOTTOM w0.254: v1(11.86,10.16) 11.81,10.21 11.81,10.63 11.9,10.72
PWR_5V_FB: length 4.9
  BOTTOM w0.203: PU4501.2 10.82,12.25
  BOTTOM w0.254: PR4512.1 8.33,12.58 PC4516.2 8.25,12.27 PR4511.2 8.5,11.66 8.9,12.05 v2(9.41,12.05) 9.41,12.06 9.6,12.25 10.82,12.25
PWR_5V_FB_A: length 1
  BOTTOM w0.254: PC4516.1 6.58,12.46 PR4510.2
PWR_5V_HG: length 13.5
  L4 w0.635: v3(25.78,14.04) 24.48,14.04 21.6,11.17 17.08,11.17 16.31,10.39 14.78,10.39 v3(14.1,11.08)
  vias: v2(25.71,12.46)
PWR_5V_LG: length 14.2
  TOP w0.635: v2(15.44,11.07) 15.42,11.07 v3(14.96,11.53)
  L4 w0.635: v3(14.96,11.53) 15.72,11.53 17.17,12.98 17.73,12.98 22.03,17.29 v3(22.03,20.46)
  BOTTOM w0.203: PU4501.15 14.64,11.85 v3(14.96,11.53)
PWR_5V_PH: length 18.8
  TOP w0.508: v2(15.3,9.31) 15.28,9.31 15.27,9.3 v3(13.46,9.3)
  L4 w0.635: v3(26.8,14.05) 26.8,13.79 26.16,13.16 25.4,13.16 25.32,13.24 24.75,13.24 21.92,10.4 17.4,10.4 16.62,9.63 13.79,9.63 v3(13.46,9.3)
  BOTTOM w0.203: PU4501.18 12.7,9.83 12.78,9.76
PWR_5V_VO: length 90.8
  TOP w0.254: v1(37.11,22.18) 37.06,22.13 PG4523.2 v1(37.82,21.46) ; v1(15.29,12.32) 15.29,12.69 v2(15.13,12.86)
  L4 w0.254: v1(15.29,12.32) 15.07,12.54 13.98,12.54 12.81,11.37 12.15,11.37 10.85,10.06 10.85,9.63 12.32,8.16 22.45,8.16 25.17,10.87 28.04,10.87 28.6,11.43 34.37,11.43 35.87,12.93 35.87,14.07 35.86,14.08 35.86,15.72 37.12,16.98 37.12,18.99 37.14,19 37.14,19.66 36.94,19.85 36.94,21.42 37.11,21.59 v1(37.11,22.18) ; v1(37.82,21.46) 37.64,21.29 37.64,16.6 36.82,15.78 36.52,15.48 36.52,15.48 36.37,15.33 36.37,14.29 36.38,14.28 36.38,12.72 34.58,10.92 28.83,10.92 28.27,10.36 25.38,10.36 22.66,7.65 12.09,7.65 10.44,9.3 8.34,9.3 7.17,10.47 v1(7.17,10.73)
  BOTTOM w0.203: PU4501.14 15.22,12.25
  BOTTOM w0.254: 15.22,12.25 v1(15.29,12.32) ; PR4511.1 6.64,11.66 PR4510.1 6.55,11.35 v1(7.17,10.73)
PWR_5V_VREG: length 4.5
  TOP w0.254: v2(16.28,13.64) v1(16.28,13.08) 16.08,12.88 PG4525.1
  BOTTOM w0.203: PU4501.13 14.88,12.65
  BOTTOM w0.254: 14.88,12.65 15.06,12.83 15.49,12.83 15.75,13.08 v1(16.28,13.08) 16.23,13.03 PC4518.1
PWR_CHG_ACDET: length 3.6
  BOTTOM w0.203: PU4401.1 136.18,35.61
  BOTTOM w0.254: PR4452.2 136.27,37.7 PR4416.1 136.32,36.88 PC4419.1 136.18,36.74 136.18,35.97 ; 136.18,35.97 v2(136.14,35.97) ; 136.18,35.97 136.18,35.61
PWR_CHG_ACN: length 5.1
  BOTTOM w0.203: 135.5,34.43 135.7,34.22 PU4401.31
  BOTTOM w0.254: 135.5,34.43 135.5,34.89 v2(135.28,35.1) 135.25,35.08 133.86,35.08 133.6,35.33 PC4468.2 133.32,35.41 PR4468.2 133.22,36.2 PC4466.2
PWR_CHG_ACOK: length 179.4
  TOP w0.254: v1(136.8,35.87) 136.52,35.87 135.78,36.6 135.3,36.6 134.56,35.87 v2(133.46,35.87) 131.59,35.87 131.06,35.34 131.06,19.05 125.38,13.36 108.86,13.36 107.09,15.14 107.09,16.54 v1(107.06,16.56) ; v1(22.91,55.17) 22.91,55.19 22.73,55.37 PR4474.2 22.73,56.57 PR4434.2
  L3 w0.254: v1(22.91,55.17) 22.91,54.92 21.87,53.88 21.87,50.52 21.72,50.37 21.72,49.35 21.63,49.27 21.63,46.88 21.82,46.69 21.82,40.33 27.65,34.49 31.22,34.49 32.51,33.2 37.49,33.2 37.67,33.38 40.31,33.38 40.68,33.01 42.81,33.01 43.46,33.66 44.7,33.66 45.77,32.59 46.63,32.59 47.09,32.13 50.39,32.13 50.83,31.7 51.69,31.7 51.89,31.5 57.09,31.5 57.54,31.04 60.6,31.04 60.63,31.07 61.32,31.07 62.51,32.26 63.86,32.26 66.23,29.89 66.23,29.79 67.82,28.2 70.08,28.2 70.55,28.68 79.97,28.68 82.22,26.43 82.51,26.43 86.5,22.44 92.6,22.44 93.88,21.16 98.83,21.16 98.96,21.03 99.67,21.03 100.51,21.87 107.14,21.87 107.44,21.57 107.44,21.07 v1(107.1,20.73)
  L4 w0.254: v1(22.91,55.17) 23.04,55.17 23.29,55.42 23.32,55.42 23.6,55.7 25.05,55.7 25.43,55.33 v1(25.43,52.92)
  BOTTOM w0.203: v1(136.8,35.87) 137.05,35.62 PU4401.2
  BOTTOM w0.254: v1(107.06,16.56) 107.09,16.59 107.09,17.41 107,17.5 106.98,17.5 106.27,18.21 105.84,18.21 105.54,18.51 105.54,18.93 105.84,19.23 106.5,19.23 106.66,19.39 106.66,20.13 106.68,20.14 106.68,20.31 106.73,20.36 106.73,20.37 v1(107.1,20.73) ; v1(22.91,55.17) 22.73,55.17 22.28,55.63 PR4451.2 ; v1(25.43,52.92) 25.43,52.96 25.53,53.06 PR4446.1
PWR_CHG_ACP: length 5.7
  BOTTOM w0.203: 135.92,35.18 136.14,34.96 PU4401.32
  BOTTOM w0.254: 135.92,35.18 135.51,35.59 134.29,35.59 134.04,35.84 PC4467.2 134.14,36.2 PC4466.1 134.11,36.91 PR4467.2 v2(134.11,38.66)
PWR_CHG_AD_OFF: length 166.7
  TOP w0.254: v1(56.24,25.33) 56.34,25.43 R2443.1 ; v1(18.72,67.01) v2(19.28,67.01)
  L3 w0.254: v1(18.72,67.01) 19.23,67.01 20.42,65.81 20.42,62.92 18.92,61.43 18.92,58.55 18.16,57.79 18.16,51.64 17.45,50.93 17.45,45.05 18.14,44.36 18.14,41.77 17.86,41.49 17.86,38.25 21.91,34.19 24.1,34.19 26.74,31.55 31.22,31.55 31.62,31.14 34.47,31.14 35.38,30.23 38.23,30.23 38.86,29.59 42.67,29.59 43.92,28.35 45.07,28.35 45.33,28.09 49.38,28.09 49.5,28.22 50.34,28.22 51.66,26.9 54.68,26.9 56.24,25.35 v1(56.24,25.33) 56.87,25.33 58.06,24.13 63.75,24.13 64.28,23.6 70.17,23.6 70.81,24.24 75.15,24.24 75.76,24.84 80.21,24.84 80.47,24.58 80.47,24.44 81.33,23.57 81.48,23.57 84.86,20.19 91.66,20.19 93.89,17.96 95.61,17.96 95.84,17.73 104.92,17.73 105,17.65 105.9,17.65 105.96,17.71 106.56,17.71 106.59,17.73 108.31,17.73 108.5,17.92 108.55,17.97 110.08,17.97 110.13,17.92 113.03,17.92 113.18,18.07 114.72,18.07 114.87,17.92 117.65,15.14 125.02,15.14 126.92,17.05 127.56,17.05 v1(127.64,16.97)
  BOTTOM w0.203: 56.27,28.15 56.9,28.78 57.34,28.78 57.91,29.35 U2401.11
  BOTTOM w0.254: v1(56.24,25.33) 56.13,25.43 56.13,28.02 56.27,28.15 ; PR4444.1 128.35,16.49 127.86,16.97 v1(127.64,16.97) ; v1(18.72,67.01) 18.19,67.01 17.23,66.05 PQ4309.G 16.3,65.73 15.34,64.77 PR4312.1
PWR_CHG_AD_OFF_R: length 2.3
  BOTTOM w0.254: PQ4304.1 14.14,64.99 PR4312.2
PWR_CHG_AMON: length 2.1
  BOTTOM w0.203: PU4401.6 138.65,35.61 138.73,35.69 v2(138.73,36.18) 138.73,36.32 138.84,36.43
  BOTTOM w0.254: PR4475.2 138.84,36.43
PWR_CHG_ASGATE: length 2.2
  BOTTOM w0.203: v2(135.13,33.89) 135.31,33.89 135.37,33.82 PU4401.30
  BOTTOM w0.254: PC4409.2 134.44,34.44 134.98,33.91 135.1,33.91 v2(135.13,33.89)
PWR_CHG_BATDRV: length 2.5
  BOTTOM w0.203: PU4401.25 135.99,31.82 135.64,31.47 135.64,31.37
  BOTTOM w0.508: PC4408.2 134.75,30.48 v2(135.13,30.87) 135.64,31.37
PWR_CHG_BATGONE: length 4.4
  TOP w0.254: v2(141.64,32.05) 141.64,32.69 v1(141.6,32.72) 141.55,32.77 PC4436.1
  BOTTOM w0.203: v1(141.6,32.72) 141.48,32.72 141.2,33 140.87,33 140.84,33.03 PU4401.13
  BOTTOM w0.254: v1(141.6,32.72) 141.86,32.97 PR4439.1
PWR_CHG_BMON: length 3.9
  BOTTOM w0.203: 139.85,36.27 139.82,36.27 139.06,35.52 139.06,35.15 PU4401.7
  BOTTOM w0.254: PR4476.2 141.07,37.52 141.07,36.77 140.62,36.32 140.11,36.32 v2(140,36.43) 139.85,36.27
PWR_CHG_BTST: length 3
  BOTTOM w0.203: PU4401.24 136.34,31.31 135.74,30.71 135.74,29.82 135.89,29.67
  BOTTOM w0.635: 135.89,29.67 PR4428.1
PWR_CHG_BTST1: length 1.3
  BOTTOM w0.635: PR4428.2 PC4431.1
PWR_CHG_CMSRC: length 3.7
  BOTTOM w0.203: PC4409.1 134.39,33.53 134.5,33.42 PU4401.29
  BOTTOM w0.406: PR4477.2 PC4409.1
  BOTTOM w0.508: PR4477.2 132.72,33.68 132.61,33.78 v2(132.59,33.78)
PWR_CHG_COMP: length 4
  BOTTOM w0.203: PU4401.10 140.42,34.22 140.51,34.32 140.61,34.32 141.07,34.77 v2(141.22,34.77) 141.57,34.43 141.57,34.43 141.68,34.32 141.68,34.19
  BOTTOM w0.254: 141.68,34.19 142.21,33.66 PC4406.1 142.44,33.78 PR4407.1
PWR_CHG_DCIN: length 9
  BOTTOM w0.203: PU4401.18 139.05,30.93 139.22,30.76 139.22,30.74 139.8,30.16
  BOTTOM w0.254: PR4437.1 137.03,26.16 139.2,26.16 139.9,26.87 PC4435.1 140.42,27.6 140.42,29.53 139.8,30.16
PWR_CHG_DCIN_R: length 3.1
  BOTTOM w0.254: PD4410.3 135.68,26.62 PR4437.2
PWR_CHG_FSET: length 2.5
  TOP w0.203: v1(141.15,33.48) 141.07,33.48 141,33.56 PR4406.2
  TOP w0.254: v2(141.71,33.27) 141.69,33.27 141.47,33.48 v1(141.15,33.48)
  BOTTOM w0.203: PU4401.12 140.76,33.42
  BOTTOM w0.254: v1(141.15,33.48) 140.82,33.48 140.76,33.42
PWR_CHG_HIDRV: length 15.9
  TOP w0.508: v2(136.32,31.11) v3(136.32,30.43)
  L4 w1.016: v3(136.32,30.43) 136.22,30.33 136.22,29.92 133.76,27.46 133.76,19.89 v3(135.41,18.24)
  BOTTOM w0.203: v3(136.32,30.43) 136.55,30.43 137.05,30.93 PU4401.23
PWR_CHG_LODRV: length 13.9
  TOP w0.508: v2(139.22,29.57) v3(138.56,29.49)
  L4 w1.016: v3(138.56,29.49) 138.66,29.39 138.66,29.29 139.73,28.22 139.73,26.32 139.42,26.02 139.42,22.32 140,21.74 141.44,21.74 142.04,22.34 v3(142.04,22.61)
  BOTTOM w0.203: PU4401.21 137.85,30.2 137.98,30.07 137.98,30.06 138.21,29.82 138.23,29.82 v3(138.56,29.49)
PWR_CHG_NTC: length 3.4
  BOTTOM w0.203: 140.18,30.99 139.86,31.31 PU4401.17
  BOTTOM w0.254: 140.18,30.99 140.18,30.37 140.81,29.75 v2(140.85,29.75) 140.85,29.71 141.02,29.53 PR4410.1
PWR_CHG_NTC_1: length 1
  BOTTOM w0.254: PR4412.1 142.14,28.6 PR4410.2
PWR_CHG_PHASE: length 17.2
  TOP w0.508: v2(136.9,29.36) 136.92,29.36 v3(137.39,29.82)
  L4 w1.016: v3(137.39,29.82) 137.36,29.8 137.36,29.44 136.86,28.93 136.86,28.88 134.9,26.93 134.9,20.45 136.55,18.8 136.55,17.65 v3(135.76,16.87)
  BOTTOM w0.203: PU4401.22 137.45,29.96 137.39,29.9 v3(137.39,29.82)
PWR_CHG_PROG: length 1.5
  BOTTOM w0.203: PU4401.9 139.96,34.75 140.23,35.03
  BOTTOM w0.254: PR4405.1 140.84,35.64 140.23,35.03
PWR_CHG_REGN: length 7.3
  TOP w0.254: v2(138.16,26.17) v1(138.15,26.75) 138.15,26.82 138.23,26.9 PR4417.1
  BOTTOM w0.203: PR4438.2 139.22,29.24 139.22,29.7 138.84,30.08 138.45,30.08 138.25,30.28 PU4401.20
  BOTTOM w0.254: PR4438.2 138.38,27.64 PC4445.1 138.15,27.36 v1(138.15,26.75)
PWR_CHG_SCL: length 3.7
  TOP w0.254: v2(138.89,37.16) PR4449.2 v1(138,36.5)
  BOTTOM w0.203: v1(138,36.5) 137.77,36.27 137.77,35.69 137.85,35.61 PU4401.4
  BOTTOM w0.254: PR4449.2 v1(138,36.5)
PWR_CHG_SDA: length 4.4
  TOP w0.254: PR4435.2 v2(136.3,37.19) 136.3,36.83 136.63,36.5 v1(137.19,36.5)
  BOTTOM w0.203: PU4401.3 137.44,35.15 137.44,36.25 v1(137.19,36.5)
  BOTTOM w0.254: PR4435.2 v1(137.19,36.5)
PWR_CHG_SRN: length 6.9
  BOTTOM w0.203: 140.94,32.56 140.92,32.59 140.83,32.59 140.79,32.63 PU4401.14
  BOTTOM w0.254: 141.34,31.99 141.09,32.39 141.09,32.42 140.94,32.56 ; 141.34,31.99 141.7,31.43 143.08,30.05 143.08,30.05 143.46,29.67 PC4462.2 143.46,28.91 PC4463.2 143.73,28.64 PR4457.2 ; 141.34,31.99 v2(141.57,32.12)
PWR_CHG_SRN_R: length 36.8
  BOTTOM w0.254: v2(144.04,12.85) 143.81,12.84 ; 143.81,12.84 143.81,26.75 143.73,26.84 PR4457.1 ; 143.81,12.84 143.81,12.17 138.18,6.53 138.18,4.44 136.41,2.67 129.76,2.67 128.93,3.5 128.93,4.04 PG4426.1
PWR_CHG_SRP: length 6.1
  BOTTOM w0.203: 140.77,32.18 140.73,32.22 PU4401.15
  BOTTOM w0.254: 141.69,30.9 141.4,31.19 140.77,32.18 ; 141.69,30.9 v2(141.57,30.79) ; 141.69,30.9 142.7,29.89 PC4461.2 142.7,28.91 PC4463.1 142.91,28.54 PR4456.2
PWR_CHG_SRP_R: length 34.9
  BOTTOM w0.254: PG4428.1 129.65,4.17 129.65,3.58 129.97,3.25 136.14,3.25 137.67,4.78 137.67,6.76 143.31,12.4 143.31,16.1 ; 143.31,16.1 143.31,26.52 142.91,26.92 PR4456.1 ; 143.31,16.1 v2(143.08,16.1)
PWR_CORE_BOOT1:
  vias: v2(33.04,48.51)
PWR_CORE_BOOT_1:
  vias: v2(35.7,49.65)
PWR_CORE_COMP: length 5.5
  TOP w0.203: PU4601.19 30.86,48.44 31.16,48.14
  TOP w0.254: 31.16,48.14 31.99,47.31 32,47.04 v2(32,46.79) 32,45.4 PR4629.1 32.07,45.27 PC4615.1 32.85,44.62 PC4616.1
PWR_CORE_COMP_A: length 1.6
  TOP w0.254: PC4616.2 32.81,43.68 PR4627.1 v2(33.73,43.01)
PWR_CORE_COMP_B: length 1.6
  TOP w0.254: PR4628.2 32.79,42.17 PC4617.1 33.57,41.43 33.57,41.43 v2(33.58,41.43)
PWR_CORE_EN: length 5.3
  TOP w0.203: PU4601.8 26.55,50.26
  TOP w0.254: v2(24.23,46.71) 24.41,46.71 24.89,47.19 PR4617.2 25.35,47.42 25.35,48.03 26.06,48.74 26.06,49.77 26.55,50.26
PWR_CORE_FB_A: length 1.8
  TOP w0.254: PC4614.1 30.23,40.43 PR4624.2 v2(30.3,39.62)
PWR_CORE_FB_R: length 10
  TOP w0.203: 30.73,48.04 30.46,48.3 PU4601.18
  TOP w0.254: PR4624.1 31.17,41.28 PR4625.1 31.16,41.69 31.04,41.82 v2(31.04,42.17) 31.15,42.17 31.17,42.19 PR4628.1 31.95,42.19 PR4627.2 31.95,43.59 PC4615.2 31.52,44.26 31.52,44.59 31.5,44.61 31.5,47.27 30.73,48.04
PWR_CORE_HG1: length 21.1
  TOP w0.203: PU4601.22 32.57,49.86 32.92,49.51 v3(32.92,49.48)
  L4 w1.016: v3(32.92,49.48) 34.08,48.32 38.12,48.32 v3(41.45,44.99) 41.45,40.92 39.85,39.32 v3(39.85,39.02)
  BOTTOM w0.508: v2(32.53,48.95) 32.92,49.34 v3(32.92,49.48)
  BOTTOM w0.711: v3(41.45,44.99) 41.3,44.99 PU4701.1
  BOTTOM w1.016: PU4702.1 39.6,39.27 v3(39.85,39.02)
PWR_CORE_IMON: length 3.1
  TOP w0.203: PU4601.10 27.06,48.99
  TOP w0.254: v1(27,48.9) 27.01,48.9 27.01,48.93 27.06,48.99
  BOTTOM w0.254: v2(26.14,48.82) 26.09,48.87 26.09,49.31 PC4613.1 27.14,49.63 PR4618.1 27.16,49.06 v1(27,48.9)
PWR_CORE_ISEN1_N: length 35.5
  TOP w0.254: v2(28.47,39.42) v1(28.47,39.98) 28.27,40.18 PR4703.2
  L4 w0.254: v1(46.35,47.77) 46.37,47.75 46.38,47.75 48.5,45.63 48.5,38.98 47.6,38.08 46.13,38.08 45.95,38.25 44.73,38.25 44.63,38.36 41.96,38.36 40.89,37.29 38.84,37.29 38.07,38.05 37.19,38.05 36.6,38.64 36.6,39.33 34.73,41.2 30.15,41.2 28.93,39.98 v1(28.47,39.98)
  BOTTOM w0.254: PG4707.1 v1(46.35,47.77)
PWR_CORE_ISEN1_P: length 37.5
  TOP w0.254: v2(25.58,40.31) v1(26.14,40.31) 26.16,40.34 26.16,40.69 25.81,41.05 PR4702.2
  L4 w0.254: v1(26.14,40.31) 26.21,40.31 26.47,40.57 28.78,40.57 29.92,41.71 34.95,41.71 37.11,39.55 37.11,38.86 37.41,38.56 38.31,38.56 39.07,37.8 40.67,37.8 41.73,38.86 44.86,38.86 44.96,38.76 46.18,38.76 46.35,38.58 47.35,38.58 47.99,39.23 47.99,45.4 45.67,47.73 v1(45.67,47.75)
  BOTTOM w0.254: PG4706.1 v1(45.67,47.75)
PWR_CORE_ISEN_N: length 52.8
  TOP w0.254: v1(47.12,52.1) v2(47.12,52.69) ; PR4636.2 28,45.43 27.5,45.43 PC4619.2 PC4618.2 27.03,43.44 PR4633.2 27.08,43.13 27.08,42.5 PC4623.1 PC4622.1 27.25,40.95 PR4703.1 27.28,40.67 27.28,40.21 27.53,39.96 v1(27.64,39.96)
  L4 w0.254: v1(47.12,52.1) 47.88,52.86 51.12,52.86 51.64,52.34 51.64,50.15 51.54,50.05 51.54,50.04 51.18,49.68 51.17,49.68 50.32,48.83 50.32,44.85 50.9,44.27 50.9,39.45 50.44,38.98 49.29,38.98 47.83,37.52 45.93,37.52 45.7,37.75 44.5,37.75 44.4,37.85 43.48,37.85 42.93,37.29 42.93,37.26 42.44,36.78 38.61,36.78 37.85,37.54 36.96,37.54 35.95,38.55 34.77,38.55 34.42,38.9 34.42,38.91 33.99,39.35 31.75,39.35 31.42,39.68 29.59,39.68 29.39,39.47 28.12,39.47 v1(27.64,39.96)
  BOTTOM w0.254: v1(47.12,52.1) 47.09,52.12 PR4635.2
PWR_CORE_ISEN_P: length 8.8
  TOP w0.203: PU4601.14 28.86,48.19
  TOP w0.254: PR4702.1 PR4632.1 26.57,42.42 26.04,42.95 PR4633.1 26.11,43.38 PC4618.1 PC4619.1 v2(27.05,45.9) 27.28,46.13 27.28,46.5 28.86,48.08 28.86,48.19
PWR_CORE_ISUMN: length 3.1
  TOP w0.203: PU4601.15 29.26,47.76
  TOP w0.254: 29.26,47.76 29.09,47.58 29.09,47.54 v2(28.99,47.44) 28.95,47.44 28.02,46.51 PR4636.1
PWR_CORE_ISUMP: length 51.6
  TOP w0.254: v1(26.75,40.06) 26.75,41.2 PR4632.2 ; v1(46.23,52.1) v2(46.23,51.39)
  L4 w0.254: v1(26.75,40.06) 27.84,38.97 29.62,38.97 29.81,39.16 31.19,39.16 31.52,38.84 33.73,38.84 34.53,38.04 35.73,38.04 36.73,37.03 37.62,37.03 38.38,36.27 42.67,36.27 43.43,37.03 43.43,37.06 43.71,37.34 44.17,37.34 44.27,37.24 45.49,37.24 45.75,36.98 48.03,36.98 49.52,38.48 50.65,38.48 51.41,39.24 51.41,44.48 50.83,45.06 50.83,48.59 52.15,49.91 52.15,52.55 51.33,53.37 47.5,53.37 v1(46.23,52.1)
  BOTTOM w0.254: v1(46.23,52.1) PR4635.1
PWR_CORE_LG1: length 26.5
  TOP w0.203: PU4601.24 32.87,50.66 v3(33.86,51.64)
  TOP w1.016: v2(41.5,50.88) v3(41.5,51.54)
  L4 w1.016: v3(46.61,40.24) 46.14,40.24 44.65,41.72 44.65,46.71 41.5,49.86 v3(41.5,51.54) 34.54,51.54 34.44,51.64 v3(33.86,51.64)
  BOTTOM w0.508: v3(46.61,40.24) 46.33,39.96 PU4702.8
  BOTTOM w0.762: PU4701.8 v3(41.5,51.54)
PWR_CORE_NTC: length 10.3
  TOP w0.203: v1(27.15,48.26) 27.29,48.26 27.66,48.63 PU4601.11
  BOTTOM w0.254: PR4623.2 35.09,48.97 34.59,48.97 33.36,47.74 v2(32.18,47.74) 31.53,47.74 30.8,48.46 29.59,48.46 28.85,47.73 PR4626.2 27.69,47.73 v1(27.15,48.26)
PWR_CORE_NTC_A_R: length 8.7
  BOTTOM w0.254: PR4626.1 PR4622.2 28.47,49.43 28.84,49.06 v2(30.92,49.06) 31.72,48.27 33.16,48.27 34.37,49.48 34.91,49.48 PR4623.1
PWR_CORE_PGOOD: length 5.6
  TOP w0.203: 31.62,48.24 31.6,48.24 31.26,48.57 PU4601.20
  TOP w0.254: PR4620.2 34.67,46.65 PG4608.1 34.41,47.34 v2(33.65,47.34) 32.52,47.34 31.62,48.24
PWR_CORE_PH1: length 14.9
  TOP w0.203: PU4601.23 33.77,50.26 v3(33.85,50.33)
  TOP w0.254: PC4708.2 34.73,50.95 34.57,51.11 v2(34.57,51.13)
  TOP w0.508: PC4708.2 33.98,50.35 33.96,50.33 v3(33.85,50.33)
  L4 w1.016: v3(42.6,45.09) 42.6,45.47 38.57,49.5 34.68,49.5 v3(33.85,50.33)
PWR_CORE_SVC: length 2.6
  TOP w0.203: PU4601.3 26.08,52.26
  TOP w0.254: 26.08,52.26 26.01,52.33 v2(25.76,52.33) 25.22,52.33 25.15,52.4 24.99,52.4 PG4603.2
PWR_CORE_SVD: length 3.2
  TOP w0.203: PU4601.5 26.12,51.46
  TOP w0.254: PG4605.2 25.1,50.83 25.37,51.11 v1(25.4,51.11) 25.53,51.24 25.63,51.24 25.7,51.31 25.97,51.31 26.12,51.46
  BOTTOM w0.254: v2(25.4,50.55) v1(25.4,51.11)
PWR_CORE_SVT: length 3.9
  TOP w0.203: PU4601.7 26.4,50.66
  TOP w0.254: 26.4,50.66 25.55,49.81 v2(25.55,49.07) 25.55,49 24.77,48.21 PG4607.2
PWR_CORE_VDD: length 4.4
  TOP w0.203: PU4601.25 32.57,51.06
  TOP w0.254: 32.57,51.06 v1(32.87,51.36)
  BOTTOM w0.254: PR4616.2 31.98,50.75 PC4611.1 31.85,50.6 32.11,50.35 v2(32.65,50.35) 32.85,50.35 33.1,50.6 33.1,51.13 v1(32.87,51.36)
PWR_CORE_VDDIO: length 3.6
  TOP w0.203: PU4601.6 26.25,51.06
  TOP w0.254: 26.25,51.06 26.12,50.93 25.98,50.93 v2(25.65,50.61) 25.61,50.61 24.99,49.99 PC4612.2 24.82,49.94 24.82,49.35 PG4606.2
PWR_CORE_VR_HOT#: length 2.4
  TOP w0.203: 25.84,51.86 PU4601.4
  TOP w0.254: PG4604.2 24.74,51.82 25.8,51.82 25.84,51.86
PWR_CORE_VSEN1_N: length 5.1
  TOP w0.203: PU4601.17 30.06,47.69
  TOP w0.254: 30.06,47.69 v2(30.2,47.55) 30.2,47.53 30.38,47.36 30.38,46.56 30.33,46.51 30.33,46.03 PG4611.1 29.97,45.67 PG4609.1 30.15,45.24 PC4620.2
PWR_CORE_VSEN1_P: length 11
  TOP w0.203: PU4601.16 29.66,47.35
  TOP w0.254: 29.66,47.35 28.99,46.68 28.99,46.39 PC4621.2 29.03,45.77 PG4610.1 29.01,45.06 28.52,45.06 28.24,44.78 28.06,44.78 27.64,44.36 27.64,43.43 28.06,43 28.61,43 v2(29.17,42.45) 29.19,42.45 29.46,42.17 PC4614.2 30.24,41.34 PR4625.2
PWR_CPU_ISEN1: length 2.8
  TOP w0.203: PU4601.13 28.46,48.38
  TOP w0.254: 28.46,48.38 28.46,48.3 v2(27.66,47.49) 27.26,47.09 26.95,47.09 PR4630.2
PWR_DCBATOUT_0D95V: length 15.1
  TOP w0.508: v1(35.76,73.86) v2(34.49,73.86) 33.83,73.86 PC5203.1
  L4 w0.508: v1(35.76,73.86) 35.13,74.5 35.13,76.25 34.26,77.12 32.46,77.12 31.04,78.54 29.54,78.54 27.89,76.89 v1(27.53,76.89)
  BOTTOM w0.508: v1(27.53,76.89) 27.66,76.76 27.94,76.76 28.04,76.66 PR5205.1
PWR_DCBATOUT_3D3V:
  vias: v2(19.87,27.41)
PWR_DCBATOUT_5V:
  vias: v2(20.39,14.82)
PWR_DCBATOUT_VCCCORE:
  vias: v2(34.74,44.81) v2(36.3,44.76) v2(38.47,44.37) v2(39.69,42.32) v3(36.42,43.46) v3(37.47,43.46) v3(38.46,43.44)
PWR_DCBATOUT_VDDNB:
  vias: v2(36.24,63.19) v3(37.62,62.97) v3(38.61,62.97)
PWR_DCBATOUT_VDDQ: length 13.5
  L3 w0.508: v1(133.84,39.57) 135.84,41.57 135.84,42.41 135.71,42.53 135.71,47.96 136.6,48.85 v1(138.56,48.85)
  BOTTOM w0.508: v1(133.84,39.57) 133.84,39.87 PR5304.1
  vias: v2(139.99,48.53)
PWR_OPCN: length 2.9
  BOTTOM w0.203: 135.13,32.95 135.21,33.03 PU4401.28
  BOTTOM w0.254: v2(133.35,32.77) 134.04,32.77 PC4407.2 134.29,32.92 135.1,32.92 135.13,32.95
PWR_OPCP: length 2.1
  BOTTOM w0.203: 135.2,32.39 135.44,32.63 PU4401.27
  BOTTOM w0.254: 135.2,32.39 v2(135.15,32.34) 135.06,32.25 134.43,32.25 PC4407.1
PWR_VBAT: length 5.1
  BOTTOM w0.203: 135.18,31.73 135.68,32.22 PU4401.26
  BOTTOM w0.254: 135.18,31.73 135.04,31.73 134.71,31.4 PC4408.1 132.97,31.4 PR4454.1 132.18,31.93 v2(132.18,32.39)
PWR_VDDNB_BOOT: length 3.4
  TOP w0.203: PU4601.31 31.92,53.66 32.18,53.93
  TOP w0.635: 32.18,53.93 v2(33.11,53.93) 33.32,53.93 33.99,54.59 PR4704.1
PWR_VDDNB_BOOT_A: length 2.2
  TOP w0.635: PC4717.1 33.88,56.31 PR4704.2 v2(35.13,56.21)
PWR_VDDNB_COMP: length 5.1
  TOP w0.203: PU4601.36 29.26,54.43
  TOP w0.254: 29.26,54.43 29.26,55.21 29.99,55.94 v2(30,55.94) 30,55.94 30.35,56.3 PR4608.1 30.43,56.9 PC4603.1 30.48,57.66 PC4604.1
PWR_VDDNB_FB: length 7.4
  TOP w0.203: PU4601.37 28.86,54.39 28.88,54.41
  TOP w0.254: 28.88,54.41 28.88,55.53 28.65,55.75 v2(28.65,55.93) 28.65,56.8 PR4605.1 28.68,56.91 29.38,57.61 PC4603.2 29.62,57.61 29.87,57.86 29.87,57.94 PR4602.1 30.43,58.5 PR4604.2 30.35,59.34 PR4607.2
PWR_VDDNB_FB_A: length 1.8
  TOP w0.254: PC4604.2 31.11,59.08 PR4604.1 31.92,59.26 v2(32.21,58.97)
PWR_VDDNB_FB_B: length 2.5
  TOP w0.254: PC4608.1 31.11,61.96 30.86,62.21 v2(30.71,62.21) 30.61,62.21 30.35,61.96 PR4607.1
PWR_VDDNB_FB_C: length 1.9
  TOP w0.254: PC4602.1 28.86,57.81 29.17,58.12 29.18,58.12 PR4602.2 29.49,58.42 v2(29.49,59.26)
PWR_VDDNB_HG: length 15.9
  TOP w0.203: v3(31.85,54.97) 31.75,54.97 30.86,54.08 PU4601.32
  TOP w0.508: v3(36.7,61.5) v2(36.7,60.83)
  L4 w1.016: v3(39.7,61.83) 39.37,61.5 v3(36.7,61.5) 36.68,61.47 36.68,60.38 31.85,55.55 v3(31.85,54.97)
  BOTTOM w0.762: 36.7,60.56 v3(36.7,61.5) ; v3(39.7,61.83) 39.73,61.85 PU4706.1
PWR_VDDNB_ISEN1_N: length 36
  TOP w0.254: v1(27.74,58.57) 27.58,58.42 PR4706.2 ; v1(46.35,58.75) v2(46.35,59.31)
  L4 w0.254: v1(27.74,58.57) 27.91,58.75 28.19,58.75 28.47,59.03 28.47,59.41 31.75,62.69 35.1,62.69 39.95,67.54 46.2,67.54 46.28,67.62 47.7,67.62 48.06,67.26 48.06,62.43 47.12,61.5 47.12,59.51 v1(46.35,58.75)
  BOTTOM w0.254: v1(46.35,58.75) 46.69,58.42 PG4713.1
PWR_VDDNB_ISEN1_N_A: length 6.3
  TOP w0.254: PC4607.1 24.66,56.79 PR4606.1 24.59,57.53 v2(24.44,57.67) 24.42,57.7 24.42,58.45 PC4606.1 25.15,58.47 PR4609.1 25.24,58.42 PR4706.1 26.21,58.23 PC4605.1 26.26,57.61 PR4603.1
PWR_VDDNB_ISEN1_P: length 38.7
  TOP w0.254: v1(27.97,59.26) 27.81,59.26 27.71,59.16 26.92,59.16 PR4705.2 ; v1(45.72,58.75) v2(45.72,58.19)
  L4 w0.254: v1(27.97,59.26) 27.97,59.64 31.52,63.2 34.87,63.2 39.73,68.05 45.97,68.05 46.05,68.12 47.93,68.12 48.56,67.49 48.56,62.21 47.62,61.27 47.62,59.29 46.56,58.22 46.15,58.22 45.82,58.55 45.82,58.57 45.72,58.67 v1(45.72,58.75)
  BOTTOM w0.254: v1(45.72,58.75) 45.72,58.69 PG4712.1
PWR_VDDNB_ISEN1_P_A: length 59.9
  TOP w0.203: PU4601.40 27.66,54.42
  TOP w0.254: 27.66,54.42 26.66,55.42 v2(26.06,55.42) 25.51,55.42 25.05,55.88 PC4607.2 24.49,55.88 23.52,56.85 23.52,58.78 24.13,59.39 PC4606.2 24.56,59.26 PR4609.2 25.96,59.26 PR4705.1 26.67,59.82 v1(26.82,59.82)
  L4 w0.254: v1(47.09,54.26) 50.24,57.41 50.24,62.28 50.01,62.51 50.01,68.61 50.04,68.63 50.04,69.14 50.06,69.17 50.06,69.57 49.23,70.41 35.48,70.41 34.8,69.72 34.8,65.2 33.81,64.21 31.06,64.21 26.95,60.1 26.95,60.07 26.82,59.95 v1(26.82,59.82)
  BOTTOM w0.254: PR4610.2 v1(47.09,54.26)
PWR_VDDNB_ISUMN: length 3.5
  TOP w0.203: PU4601.39 28.06,54.69
  TOP w0.254: PR4603.2 27.28,56.49 v2(27.28,55.79) 27.28,55.48 28.06,54.69
PWR_VDDNB_ISUMN_A: length 52.5
  TOP w0.254: PR4606.2 25.4,56.26 25.65,56.01 v1(25.81,56.01) ; v1(46.23,54.28) v2(46.23,53.72)
  L4 w0.254: v1(25.81,56.01) 25.81,56.07 26.31,56.57 26.31,58.57 27.33,59.59 27.33,59.73 27.46,59.86 27.46,59.87 31.29,63.7 34.04,63.7 34.85,64.51 34.85,64.52 35.31,64.97 35.31,69.42 35.79,69.9 49,69.9 49.53,69.37 49.53,68.86 49.5,68.84 49.5,62.28 49.73,62.05 49.73,57.79 v1(46.23,54.28)
  BOTTOM w0.254: PR4610.1 v1(46.23,54.28)
PWR_VDDNB_LG: length 23.1
  TOP w0.203: v3(30.33,54.87) 30.33,54.71 30.06,54.45 PU4601.34
  TOP w0.508: v3(35.84,54.66) v2(36.5,54.66)
  L4 w1.016: v3(30.33,54.87) 30.33,54.68 31.62,53.39 33.83,53.39 35.1,54.66 v3(35.84,54.66) 38.97,57.79 41.38,57.79 v3(45.39,61.8)
  BOTTOM w0.762: PU4706.8 45.62,62.03 v3(45.39,61.8) ; 36.7,54.66 v3(35.84,54.66)
PWR_VDDNB_NTC: length 13.7
  TOP w0.203: PU4601.1 26.49,53.06
  TOP w0.254: v1(26.24,53.62) 26.24,53.31 26.49,53.06
  BOTTOM w0.254: PR4614.2 26.37,52.86 26.37,53.49 v1(26.24,53.62) 26.04,53.82 26.04,54.73 28.36,57.05 30.1,57.05 30.83,56.32 v2(32.05,56.32) 34.91,56.32 PR4613.2
PWR_VDDNB_NTC_A: length 11.8
  BOTTOM w0.254: PR4614.1 27.08,53.01 PR4612.2 26.89,53.79 26.84,53.79 26.54,54.08 26.54,54.52 28.57,56.54 29.65,56.54 30.38,55.81 v2(33.91,55.81) 34.9,55.81 PR4613.1
PWR_VDDNB_PG: length 6
  TOP w0.203: PU4601.35 29.66,54.36
  TOP w0.254: 29.66,54.36 29.66,55.06 30.07,55.48 30.25,55.48 30.95,56.17 30.95,56.36 v2(31.27,56.68) 31.81,57.23 32.22,57.23 PG4602.1 32.23,57.41 31.95,57.68 PR4611.2
PWR_VDDNB_PH: length 16.7
  TOP w0.203: PU4601.33 30.46,54.16 31.04,54.74 31.04,55.2
  TOP w0.508: 32.11,56.27 PC4717.2 ; 32.11,56.27 v2(31.26,55.42) 31.04,55.2 ; 32.11,56.27 32.11,56.03 32.99,55.15 v3(32.99,55.04)
  L4 w1.016: v3(42.06,61.5) 40.39,59.82 37.92,59.82 33.15,55.04 v3(32.99,55.04)
PWR_VDDNB_VSEN: length 9.9
  TOP w0.203: PU4601.38 28.46,54.37
  TOP w0.254: v2(27.61,59.92) 27.7,59.83 28.54,59.83 PR4601.2 28.5,59.67 28.5,58.53 PC4602.2 27.81,57.79 27.81,56.82 27.79,56.8 27.79,55.8 v1(28.18,55.4) 28.46,55.12 28.46,54.37
  BOTTOM w0.254: PC4601.2 28.5,53.72 28.5,54.61 PG4601.1 28.52,55.15 28.27,55.4 v1(28.18,55.4)
PWR_VDDNBE_IMON: length 4.4
  TOP w0.203: PC4609.1 25.58,53.47 26.39,52.66 PU4601.2
  TOP w0.254: PC4609.1 24.86,53.47 24.74,53.59 PR4615.1 23.82,53.59 23.44,53.97 v2(23.44,54.24)
PWR_VDDQ: length 19
  L4 w0.508: v1(143.03,44.4) 142.93,44.4 142.13,45.2 142.13,50.46 142.44,50.78 142.44,51.82 141.86,52.4 141.86,54.11 139.73,56.24 137.94,56.24 v3(135.89,58.29)
  BOTTOM w0.508: PG5312.1 v1(143.03,44.4)
  vias: v2(133.98,59.88) v2(135.2,57.02) v2(137.37,61.25) v2(138.75,60.15) v3(135.03,59.97) v3(135.1,59.13) v3(135.05,58.29) v3(135.92,59.97) v3(135.94,59.13) v3(137.34,59.59) v3(137.36,58.75)
PWR_VDDQ_BOOT: length 1.9
  BOTTOM w0.203: PU5301.27 139.97,46.55 140.03,46.61 140.69,46.61 141,46.31 141.45,46.31 PR5317.1
PWR_VDDQ_BOOT_A: length 1.2
  BOTTOM w0.635: PC5306.1 142.8,46.92 PR5317.2
PWR_VDDQ_CS: length 2.2
  BOTTOM w0.203: PU5301.10 135.05,44.95
  BOTTOM w0.254: 135.05,44.95 134.91,44.81 v2(134.48,44.81) 133.58,44.81 PR5302.2
PWR_VDDQ_EN: length 4.5
  BOTTOM w0.203: 136.78,43.09 137.12,43.43 PU5301.6
  BOTTOM w0.254: PR5319.2 135.18,41.13 PR5306.2 135.09,41.48 v2(135.71,42.1) 135.74,42.1 136.73,43.09 136.78,43.09
PWR_VDDQ_FB: length 4.2
  BOTTOM w0.203: PU5301.3 138.32,43.5 138.43,43.38
  BOTTOM w0.254: 138.2,42.58 137.42,41.81 PR5308.2 PR5309.1 ; 138.2,42.58 v2(138.2,42.58) ; 138.2,42.58 138.23,42.58 138.49,42.85 138.49,43.32 138.43,43.38
PWR_VDDQ_LVOIN: length 3.3
  BOTTOM w0.203: 141.15,45.37 141.15,45.44 140.84,45.75 140.84,45.98 140.56,46.26 140.16,46.26 140.05,46.15 PU5301.28
  BOTTOM w0.508: 141.15,45.37 141.25,45.26 PC5307.1 141.48,44.53 PG5312.2
PWR_VDDQ_PH: length 13.5
  TOP w0.508: PR5318.1 135.76,51.08 135.76,52.63 v1(136.04,52.91)
  L4 w0.508: v1(136.04,52.91) 140.68,48.28 140.68,47.46 v1(140.54,47.32)
  BOTTOM w0.203: PU5301.25 140.51,47.35 v1(140.54,47.32)
  BOTTOM w0.508: PL5301.1 136.65,51.49 136.04,52.1 v1(136.04,52.91) ; PC5306.2 140.7,47.3 140.68,47.32 v1(140.54,47.32)
  vias: v2(135.65,48.53)
PWR_VDDQ_SNUB: length 2.5
  TOP w0.508: v2(134.11,50.62) 134.29,50.45 PC5321.1 134.82,49.84 135.36,49.3 PR5318.2
PWR_VDDQ_TON: length 4.4
  BOTTOM w0.203: PU5301.7 136.72,43.65 136.51,43.44 136.24,43.44
  BOTTOM w0.254: PR5304.2 134.46,41.35 134.46,42.5 v2(134.6,42.64) 134.76,42.8 135.6,42.8 136.24,43.44
PWR_VDDQ_VCC: length 5.1
  BOTTOM w0.203: 134.95,44.12 135.38,44.55 PU5301.9
  BOTTOM w0.508: 134.95,44.12 134.79,43.96 PR5302.1 133.56,43.97 PR5301.1 ; PR5301.1 132.8,43.45 v2(133.18,43.06) ; PR5301.1 132.07,43.97 PC5302.1
PWR_VDDQ_VDDQ: length 31
  TOP w0.508: v1(133.1,62.94) 133.35,62.69 134.85,62.69 PG5313.1 ; v1(138.38,41.84) v2(138.38,42.39)
  L4 w0.508: v1(138.38,41.84) 137.78,42.43 135.09,42.43 132.97,44.55 132.97,58.93 133.17,59.13 133.17,62.87 v1(133.1,62.94)
  BOTTOM w0.203: 139.12,43.18 139.12,43.21 138.72,43.6 PU5301.2
  BOTTOM w0.508: PR5308.1 138.29,41.74 v1(138.38,41.84) 139.17,42.62 139.17,43.13 139.12,43.18
PWR_VDDQ_VTT: length 3.3
  TOP w0.508: v2(140.49,43.66) v1(140.49,44.22) 140.26,44.45 140.21,44.45 139.82,44.84 139.82,45.31 140.23,45.72 140.33,45.72 v1(140.36,45.75)
  BOTTOM w0.203: v1(140.36,45.75) PU5301.29
PWR_VDDQ_VTTREF: length 35.3
  TOP w0.508: R1211.2 132.44,64.37 132.74,64.37 133.25,63.86 v1(133.25,63.72) ; v2(138.39,40.77) 138.79,41.17 v1(138.99,41.17)
  L4 w0.508: v1(138.99,41.17) 138.83,41.17 138.73,41.07 133.35,41.07 132.21,42.22 132.21,59.26 132.38,59.44 132.38,61.85 132.33,61.9 132.33,63.32 132.73,63.72 v1(133.25,63.72)
  BOTTOM w0.203: PU5301.1 139.12,43.86 139.78,43.21 139.78,42.06
  BOTTOM w0.508: 139.78,42.06 139.78,41.36 PC5314.1 139.11,41.2 139.07,41.17 v1(138.99,41.17)
PWR_VPP_EN1: length 3.9
  BOTTOM w0.254: PU5302.8 118.16,99.89 117.9,100.15 v2(117.59,100.15) 117.12,100.15 116.87,99.89 PC5320.1 116.54,99.6 116.44,99.49 PR5314.2
PWR_VPP_FB: length 4.8
  BOTTOM w0.305: v2(125.93,100.05) 125.91,100.03 PR5316.1 125.91,98.61 PR5315.2 124.92,98.37 PC5319.2 124.82,98.4 123.77,97.36 PU5302.2
PWR_VPP_VCNTL: length 5.4
  BOTTOM w0.305: PU5302.6 117.3,96.09 117.08,96.31 116.29,96.31 v2(115.97,96.63) 115.62,96.98 PC5316.1 113.46,96.98 PR5310.2
PWR_VTT_EN: length 3.2
  BOTTOM w0.203: PU5301.5 137.52,43.49
  BOTTOM w0.254: 137.52,43.49 137.52,43.31 137.29,43.08 137.29,42.45 137.06,42.22 137.06,42.2 v2(137.04,42.19) 136.63,41.77 PR5307.2
Q1702_2: length 3.8
  BOTTOM w0.102: Q1701.2 58.04,53.24 R1747.2 ; R1747.2 58.11,53.16 57.53,53.16 57.39,53.31 Q1701.3 ; R1747.2 58.12,52.45 v2(58.29,52.27)
Q2406_D: length 9.2
  BOTTOM w0.102: Q4001.D 88.24,78.95 v2(88.31,79.03) 88.31,79.2 87.5,80.01 R4013.2 C4030.1 86.77,80.36 87.12,80.71 87.64,80.71 89.48,82.54 89.48,82.61 90.55,83.68 D4004.2
Q2406_G: length 4.7
  BOTTOM w0.102: R4008.2 88.11,76.74 87.25,77.6 86.24,77.6 86.1,77.46 Q4001.G v2(85.1,76.73)
Q2506_S: length 6.2
  BOTTOM w0.305: R2518.2 75.6,15.47 75.04,15.47 74.49,16.02 74.49,17.07 74.43,17.13 74.43,17.23 74.01,17.65 Q2506.S 72.91,17.66 72.06,18.51 R2517.1
Q5102_G: length 3.6
  BOTTOM w0.102: Q5401.G 73.36,20.94 PR5411.2
Q6203_S: length 3.7
  TOP w0.508: v1(42.58,10.23) v2(43.14,10.23)
  BOTTOM w0.508: R6501.2 42.95,9.5 C6504.2 42.58,10.16 v1(42.58,10.23) 43.05,10.7 Q6503.S
Q6204_S: length 6.3
  BOTTOM w0.203: Q6504.S 44.92,5.66 45.24,5.33 46.74,5.33 v2(47.27,5.87) 47.11,5.87 46.63,6.35 C6505.2 46.67,6.79 R6514.2 47.5,6.91 R6518.2
Q6205_D: length 2
  BOTTOM w0.254: R6505.2 46.68,13.17 46.68,12.62 v2(46.89,12.41) 46.39,12.41 Q6507.6
Q6206_D: length 2.1
  BOTTOM w0.254: Q6507.3 44.78,9.55 44.8,9.53 44.8,9.47 v2(44.94,9.33) 44.98,9.29 R6506.2
R1930.R: length 4.5
  BOTTOM w0.089: X1601.1 61.91,41.63 62.81,41.63 C1602.2 64.24,40.2 R1625.1
RING2: length 4.1
  L4 w1.016: v3(147.09,93.85) 147.09,94.34 149.1,96.34 v3(149.83,96.34)
RING2_R: length 14.7
  TOP w1.016: v3(136.27,95.76) 136.08,95.76 v2(135.65,96.2)
  L3 w1.016: v3(136.27,95.76) 136.42,95.91 145.49,95.91 145.57,95.99 146.93,95.99 148.87,97.93 v3(148.87,98.35)
RSMRST#_KBC: length 36.5
  TOP w0.089: v1(59.69,27.84) 58.87,27.02 EC2401.1 58.36,27.42 58.36,28.62 56.29,30.69 56.29,35.28 56.29,35.28 56.29,35.93 56.32,35.96 56.32,37.04 56.84,37.56 56.86,37.56 56.88,37.59 56.99,37.59 57.23,37.82 57.23,38.23 57.24,38.24 57.24,38.32 57.25,38.33 57.25,38.47 56.95,38.77 56.95,39.65 v2(56.58,40.02) 56.58,41.15 56.09,41.65 56.09,42.19 56.21,42.31 v1(56.21,45.24)
  L4 w0.14: v1(56.21,45.24) 56.21,48.11 56.26,48.16 56.26,55.93 56.39,56.06 56.39,57.08 v1(55.6,57.86)
  BOTTOM w0.089: U2401.15 58.58,27.76 59.52,27.76 59.6,27.84 v1(59.69,27.84) ; v1(55.6,57.86) 55.7,57.86 55.75,57.91 R1748.2
RSTN: length 6.9
  TOP w0.076: U6304.H5 53.3,88.57 53.3,88.22 53.15,88.07 52.95,88.07 52.8,87.92 52.8,87.53
  TOP w0.152: v2(51.77,86.4) C6327.1 51.77,85.54 52.39,84.91 R6345.2 52.78,84.97 52.26,85.49 52.26,86.53 52.8,87.06 52.8,87.53
RTC_1D5V_PWR: length 3.9
  BOTTOM w0.254: U2502.2 57.12,40.68 57.61,41.16 R2506.1 C2508.1 58.5,43.56 v2(58.56,43.56)
RTC_1D5V_S5: length 64.5
  TOP w0.254: v1(61.01,30.18) 60.64,30.55 60.62,30.55 60.33,30.84 59.47,30.84 58.62,31.68 58.62,32.89 v2(58.63,32.9) 58.63,34.97 58.65,35 58.65,35.9 59.3,36.55 59.3,36.56 60.27,37.54 60.27,37.96 59.98,38.25 59.89,38.25 58.67,39.47 v1(58.67,40.46) ; v1(73.1,57.18) 72.85,57.18 72.82,57.2 72.77,57.2 72.69,57.28 72.67,57.28 C1066.1 71.73,57.15 71.73,56.16 71.36,55.79 70.58,55.79 70.3,55.51 70.3,55.26 69.91,54.86 68.76,54.86 68.07,55.55 67.51,55.55 67.26,55.55 66.34,54.64 66.34,52.88 66.69,52.54 67.49,52.54 68.47,51.57 68.47,45.78 68.73,45.51 68.73,44.73 68.87,44.59 68.87,37.63 64.4,33.16 v1(64.4,30.06) 64.54,29.93 64.54,29.37 65.64,28.27 65.64,26.35 65.38,26.09 65.37,26.09 v1(65.35,26.07)
  L3 w0.254: v1(61.01,30.18) 61.67,29.52 63.86,29.52 v1(64.4,30.06)
  BOTTOM w0.254: Q2505.D 63.63,24.49 65.22,26.07 v1(65.35,26.07) ; v1(58.67,40.46) 58.47,40.67 R2506.2 ; v1(73.1,57.18) 73.1,57.12 CPU1.AM11
RTC_AUX_S5: length 169.7
  TOP w0.508: v1(59.87,39.09) 59.31,39.65 59.31,40.82 59.21,40.92 59.21,40.97 58.88,41.3 58.88,43 60.3,44.43 60.3,46.33 58.01,48.62 58.01,52.16 58.2,52.35 58.2,52.64 58.52,52.96 58.52,56.19 57.28,57.43 57.28,67.12 v2(59.28,69.12) 60.73,70.57 60.73,72.75 v1(59.61,73.86) ; R2708.1 145.21,97.72 145.21,98.72 144.71,99.23 131.17,99.23 131.15,99.24 130.62,99.24 130.61,99.23 129.59,99.23 128.57,98.21 128.57,96.63 129.54,95.67 v1(129.54,95.48)
  L4 w0.508: v1(65.7,93.31) 65.05,93.96 63.01,93.96 61.67,92.62 61.67,89.71 62.13,89.25 62.13,87.84 60.93,86.65 60.93,83.85 60.81,83.73 60.81,81.58 60.08,80.85 59.4,80.85 57.76,79.21 57.76,78.67 58.06,78.36 58.06,76.39 59.74,74.71 59.74,73.99 v1(59.61,73.86)
  BOTTOM w0.508: v1(59.87,39.09) 59.23,39.73 U2502.3 55.62,39.73 54.5,38.61 C2507.1 53.7,38.61 R2425.2 ; v1(129.54,95.48) 129.46,95.4 129.36,95.4 129.03,95.07 Q2501.3 128.74,94.45 R2513.1 128.17,94.13 127.64,94.67 127.64,100.15 126.34,101.45 91.55,101.45 91.16,101.83 89.63,101.83 89.3,101.5 82.14,101.5 76.12,95.48 67.87,95.48 v1(65.7,93.31)
RTC_CLK: length 12.4
  TOP w0.089: v1(64.72,58.78) 64.57,58.78 v2(63.98,58.19) 63.27,57.48 R2007.1 62.83,57.25 62.74,57.34 R2001.2
  L3 w0.14: v1(70.57,57.57) 70.21,57.21 66.34,57.21 66.27,57.28 65.07,57.28 64.97,57.38 64.95,57.38 64.63,57.7 64.63,58.66 64.72,58.75 v1(64.72,58.78)
  BOTTOM w0.089: CPU1.AN4 70.2,57.2 v1(70.57,57.57)
RTC_DET#: length 112.1
  TOP w0.102: R1703.2 64.49,53.34 65.36,53.34 65.71,53.7 65.71,54.05 65.71,54.06 65.71,55.09 v1(65.99,55.37)
  L3 w0.102: v1(88.27,90.65) 89.08,90.65 89.1,90.63 90.81,90.63 93.93,93.75 95.09,93.75 97.02,95.68 99.06,95.68 100.71,94.03 105.21,94.03 106.3,95.12 106.71,95.12 106.93,95.35 106.93,95.51 107.72,96.29 116.21,96.29 116.72,95.79 v1(128.52,95.79) ; v1(65.99,55.37) 66.04,55.32 66.12,55.32 66.14,55.3 68,55.3 69.75,53.54 71.91,53.54 v1(72.39,53.06)
  L4 w0.102: v1(88.27,90.65) 88.02,90.65 86.9,89.54 84.41,89.54 81.36,86.49 81.36,85.62 77.24,81.51 76.1,81.51 74.57,79.99 74.57,76.62 73.59,75.63 73.59,72.93 74.18,72.34 74.18,67.6 73.69,67.1 73.69,66.92 72.69,65.93 72.69,65.41 72.29,65 72.29,64.01 71.98,63.7 71.98,63.35 72.21,63.12 72.53,63.12 75.04,60.61 75.5,60.61 75.96,60.15 75.96,59.13 75.92,59.09 75.92,56.28 76.12,56.08 76.12,55.66 75.02,54.56 73.64,54.56 72.39,53.31 v1(72.39,53.06)
  BOTTOM w0.102: v1(128.52,95.79) 128.45,95.71 128.19,95.71 128.07,95.84 128.07,97.92 Q2502.D 128.72,99.19 v2(128.35,99.56) ; v1(72.39,53.06) 72.42,53.04 72.42,53.01 72.6,52.83 CPU1.AE8
RTC_DET#_G: length 10.9
  BOTTOM w0.508: R2501.1 129.64,100.46 130.05,100.05 130.24,100.05 130.68,99.62 130.77,99.62 Q2502.G ; v2(131.62,98.77) 131.59,98.79 131.59,98.87 130.94,99.53 Q2502.G ; Q2501.1 130.85,96.33 130.07,97.11 130.07,98.74 Q2502.G ; Q2501.1 130.03,96.03 129.36,96.7 R2505.1 ; Q2501.1 130.85,95.91 131.36,95.4 R2514.2
RTCRST_ON: length 3.1
  BOTTOM w0.102: Q2505.G 60.44,23.54 R2507.1 59.42,24.55 U2401.23
RUNPWROK_D: length 26.2
  TOP w0.102: R4004.1 42.11,29.77 43.08,28.81 43.08,25.75 43.96,24.87 44.14,24.87 45.64,23.37 45.64,21.84 45.46,21.66 45.46,21.06 45.26,20.86 45.26,19.73 v2(45.12,19.59) 45.12,19.43 44.28,18.59 44.23,18.59 43.9,18.26 43.9,16.63 43.92,16.62 43.92,16.26 43.71,16.06 v1(43.71,15.45)
  BOTTOM w0.102: D4002.A 47.77,10.71 47.77,12.03 46.98,12.82 46.98,14.48 46.41,15.05 46.21,15.05 45.93,15.33 45.93,15.65 45.38,16.2 44.25,16.2 43.71,15.66 v1(43.71,15.45)
S5_ENABLE: length 45.5
  TOP w0.152: R4003.2 31.32,34.93 31.32,34.93 v2(34.01,32.23) 35.18,31.07 38.88,31.07 39.19,30.75 39.26,30.75 39.56,30.45 39.9,30.45 C2448.1 40.67,29.69 40.67,29.43 40.67,29.42 40.67,28.71 v1(40.41,28.45)
  L3 w0.152: v1(51.25,23.15) 51,23.39 51,23.95 50.93,24.02 50.93,24.29 49.56,25.66 49.34,25.66 49.34,25.66 48.63,25.66 47.89,26.4 42.76,26.4 41.53,27.63 41.53,28.02 41.1,28.45 v1(40.41,28.45)
  BOTTOM w0.152: v1(40.41,28.45) 40.49,28.53 40.54,28.53 40.69,28.68 Q2403.D ; R2490.2 60.91,28.4 59.46,28.4 59.22,28.15 U2401.14 57.93,28.15 57.67,28.41 57.28,28.41 56.59,27.72 56.59,25.79 57.3,25.08 57.3,24.44 56.56,23.7 56.19,23.7 55.92,23.43 55.92,22.89 55.36,22.33 53.52,22.33 53.02,22.83 51.56,22.83 v1(51.25,23.15)
S5_MUX_APU: length 39
  TOP w0.102: v1(72.39,63.53) 71.27,62.41 70.87,62.41 70.43,62.84 68.88,62.84 66.62,65.1 65.53,65.1 64.77,65.86 64.77,66.3 63.37,67.69 63.17,67.69 63.16,67.68 62.7,67.68 v1(62.2,67.18)
  L4 w0.102: v1(72.39,63.53) 73.08,63.53 73.96,62.64 74.41,62.64 76.93,60.11 76.93,59.78 76.12,58.97 76.12,56.36 76.33,56.16 76.33,55.58 75.11,54.36 73.72,54.36 72.8,53.43 72.8,52.89 72.56,52.66 71.47,52.66 70.92,52.11 70.92,50.11 v1(71.31,49.72)
  BOTTOM w0.102: R4009.1 R4011.1 62.18,67.41 62.18,67.21 v1(62.2,67.18) 61.95,67.18 61.92,67.16 61.59,67.16 61.15,66.72 v2(61.13,66.72) 60.45,66.72 60.44,66.72 U4003.6 ; v1(71.31,49.72) 71.38,49.72 71.8,50.14 CPU1.AA7
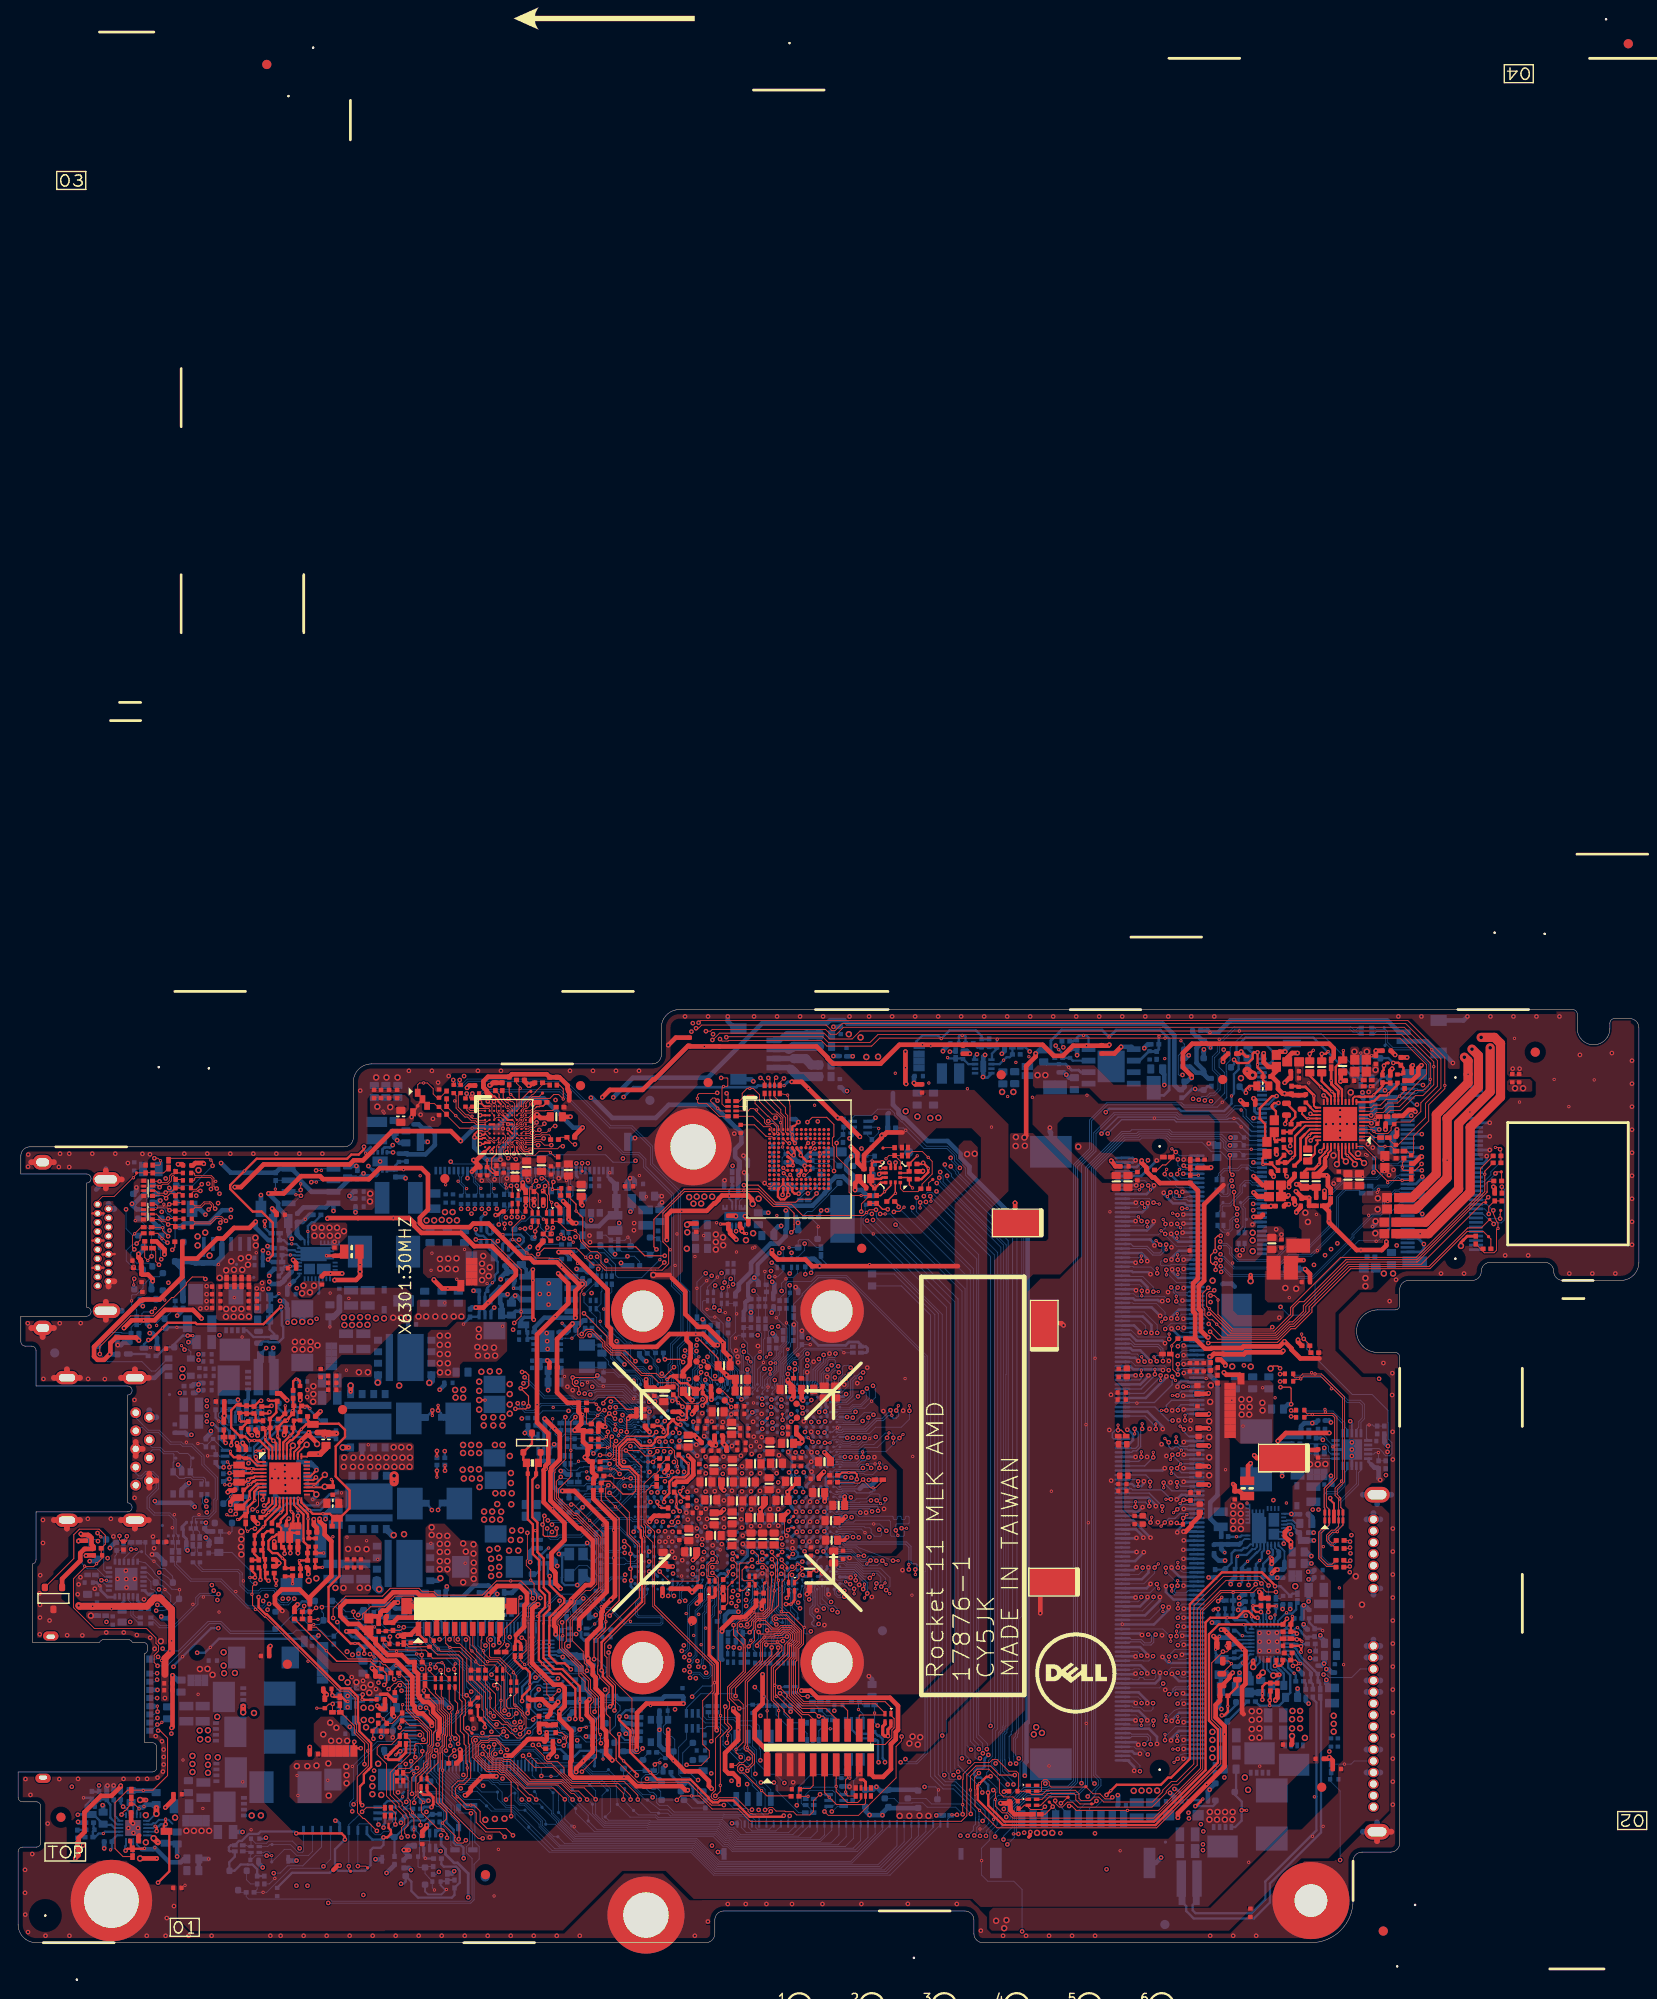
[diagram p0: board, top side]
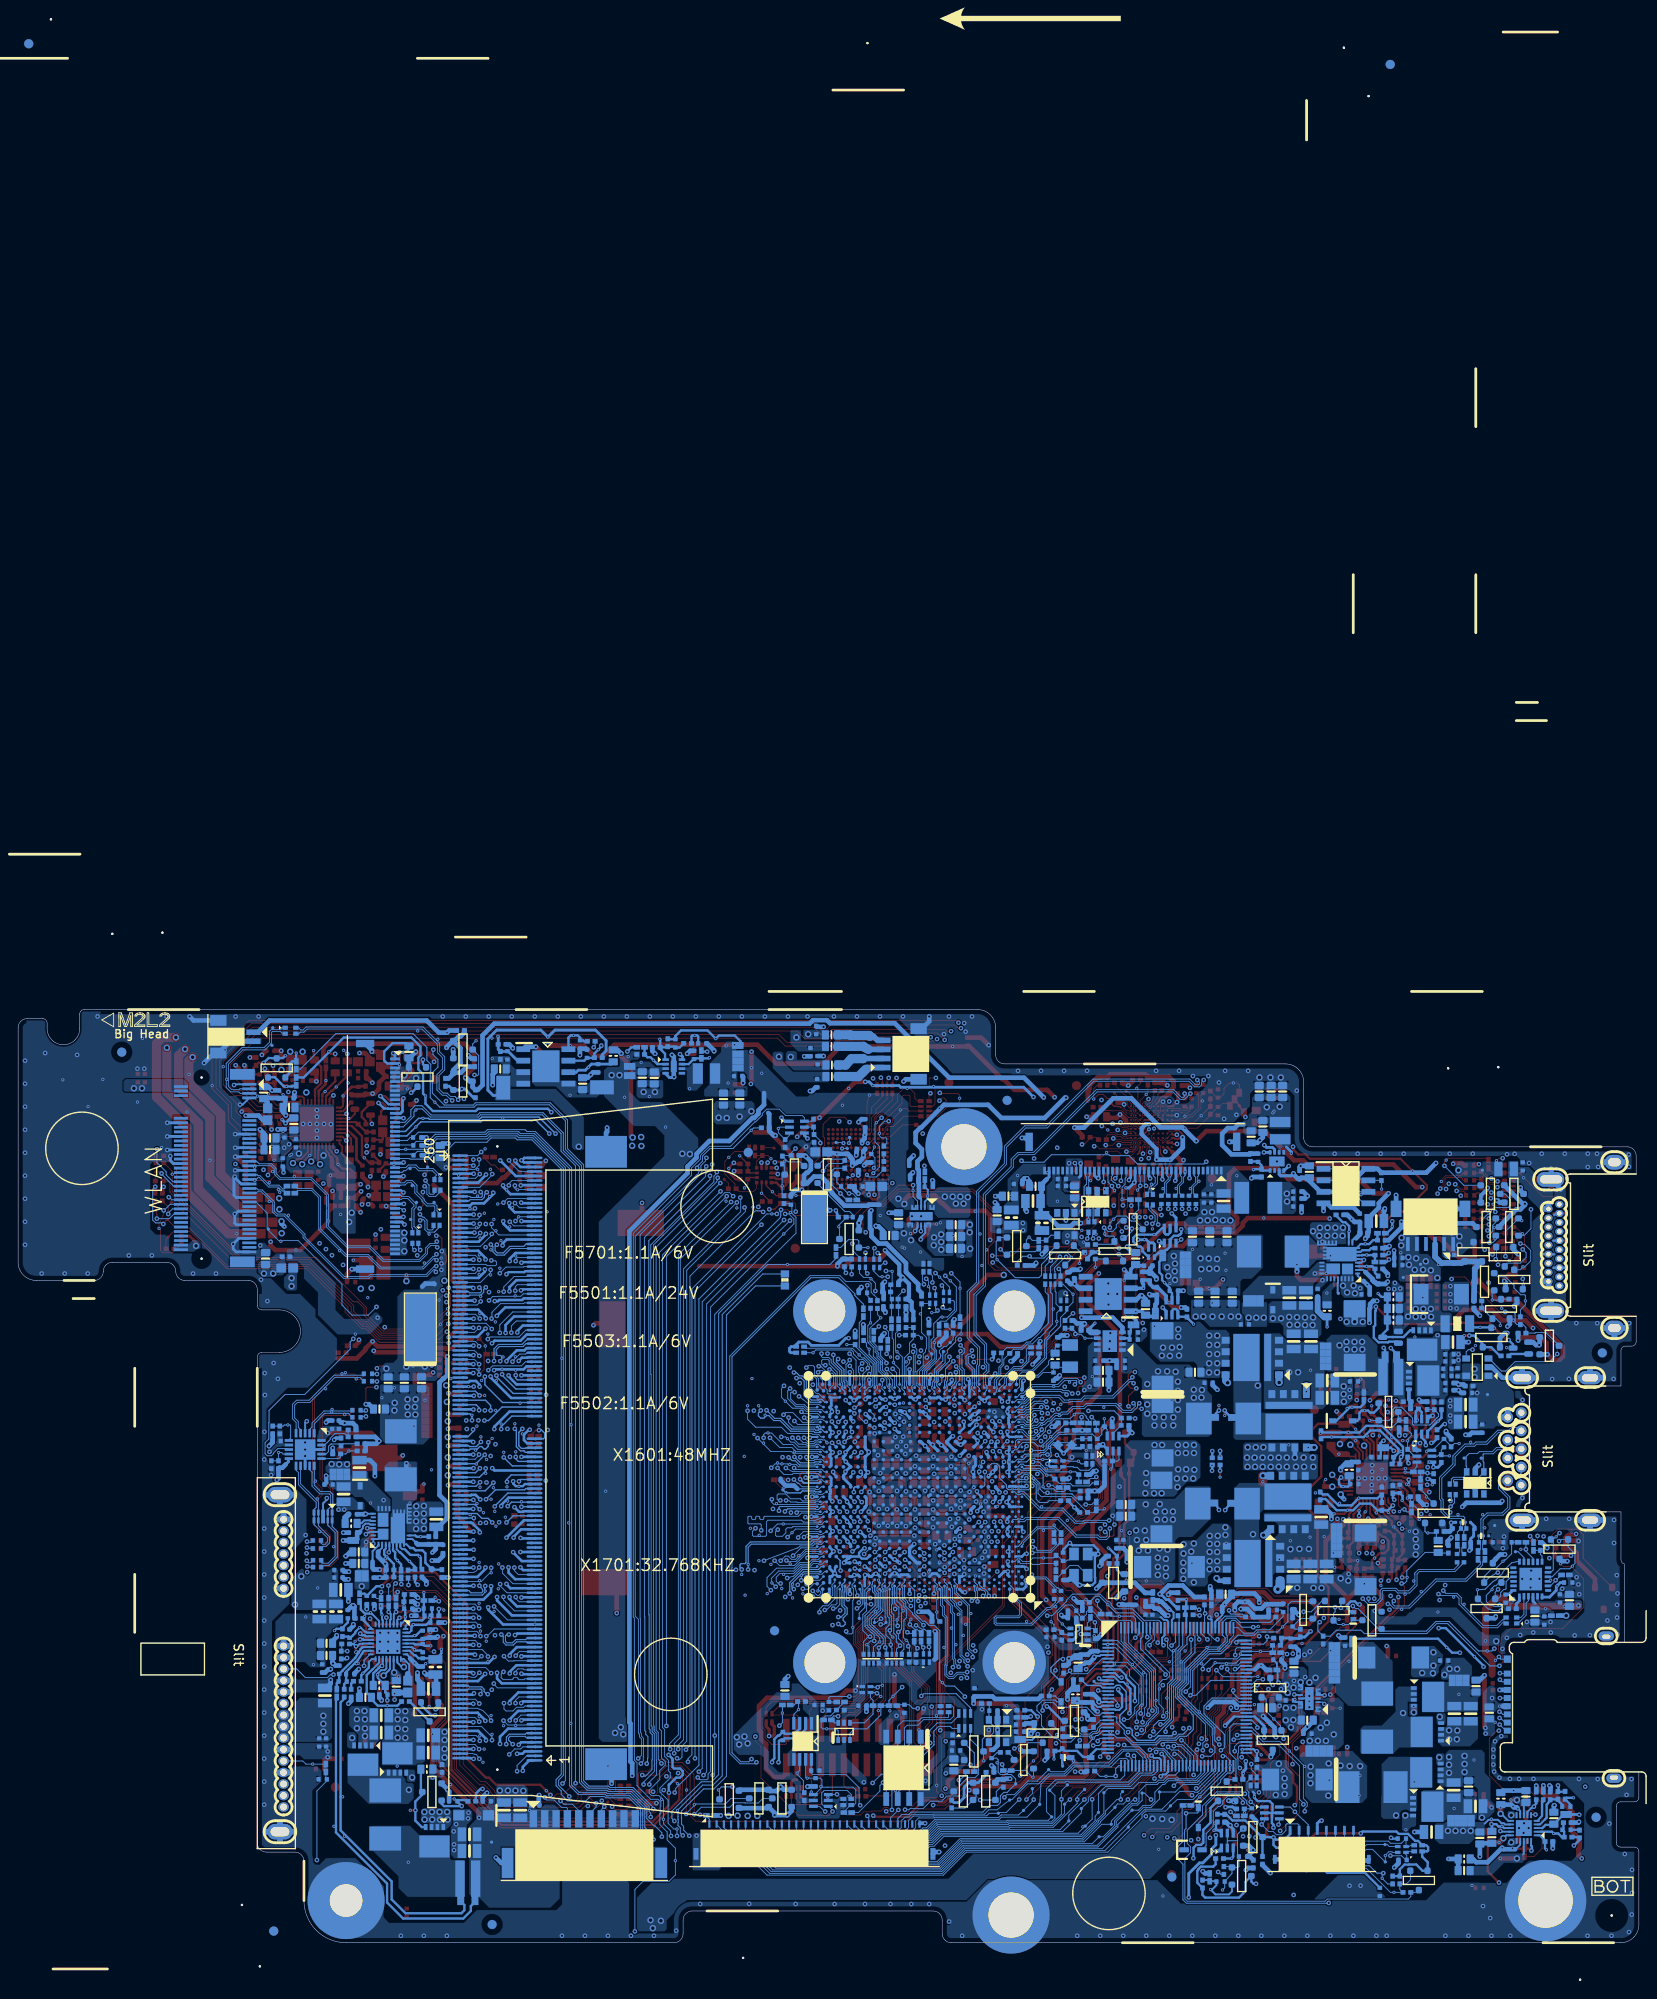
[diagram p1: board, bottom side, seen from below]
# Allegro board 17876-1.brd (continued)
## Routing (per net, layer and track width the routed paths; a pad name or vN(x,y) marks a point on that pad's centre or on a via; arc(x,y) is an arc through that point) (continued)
SATA3_DE1_HDD: length 2.8
  BOTTOM w0.102: U6001.9 149.64,53.93 149.81,54.1 v2(150.14,54.1) 150.16,54.08 R6002.2 R6005.1
SATA3_DE2_HDD: length 23.5
  TOP w0.102: R6006.2 142.57,65.25 R6009.1 142.57,65.99 v1(141.91,66.65) 141.67,66.89 v2(141.67,67.17)
  BOTTOM w0.102: v1(141.91,66.65) 142.24,66.32 142.24,65.53 147.27,60.5 149.45,60.5 151.21,58.75 151.21,57.41 151.23,57.38 151.23,55.6 151.64,55.2 151.64,53.98 151.41,53.75 150.95,53.75 150.72,53.98 150.72,54.05 150.24,54.54 149.18,54.54 U6001.8
SATA3_EQ1_HDD: length 4.8
  BOTTOM w0.102: U6001.17 144.92,53.93 144.63,54.23 144.63,54.79 144.37,55.04 144.33,55.04 144.32,55.05 143.46,55.05 R6007.1 143.03,55.07 R6003.2
SATA3_EQ2_HDD: length 4.4
  BOTTOM w0.102: U6001.19 145.06,54.93 144.45,55.54 144.45,55.68 143.92,56.21 142.85,56.21 R6004.2 R6008.1
SATA3_PRX_DTX_N0_L: length 12.5
  BOTTOM w0.089: 141.58,62.4 143.93,62.4 146.68,59.64 148.06,59.64 148.37,59.33 148.37,57.93 147.98,57.53 147.98,56.89 147.72,56.64 U6001.4 ; 141.58,62.4 v2(141.58,62.23) ; 141.58,62.4 141.16,62.4 C6008.1
SATA3_PRX_DTX_P0_L: length 12.7
  BOTTOM w0.089: U6001.5 148.22,57.43 148.61,57.83 148.61,59.43 148.16,59.88 146.78,59.88 144.03,62.64 143.15,62.64 ; v2(143.15,62.79) 143.15,62.64 ; 143.15,62.64 140.89,62.64 C6007.1
SATA3_PTX_DRX_N0_R: length 6.4
  BOTTOM w0.089: C6010.2 142.1,58.69 144.25,58.69 ; 144.25,58.69 145.13,58.69 146.46,57.36 146.46,56.92 146.72,56.66 U6001.2 ; 144.25,58.69 v2(144.25,58.86)
SATA3_PTX_DRX_P0_R: length 6
  BOTTOM w0.089: U6001.1 146.22,57.26 145.03,58.45 142.85,58.45 ; v2(142.85,58.29) 142.85,58.45 ; 142.85,58.45 142.47,58.45 C6009.2
SATA_ZVDD_095: length 3.7
  TOP w0.254: v1(72.87,57.86) 73.04,57.7 73.7,57.7 v2(73.75,57.76) 73.81,57.82 73.81,58.9 R1602.2
  BOTTOM w0.254: CPU1.AP11 73.84,57.12 73.3,57.66 73.08,57.66 v1(72.87,57.86)
SATA_ZVSS: length 2.5
  TOP w0.203: v1(73.33,59.16) v2(72.87,59.62) 72.67,59.82 72.67,60.12 R1601.2
  BOTTOM w0.203: CPU1.AU11 73.87,58.72 73.43,59.16 v1(73.33,59.16)
SD1_POWER: length 9.3
  TOP w0.076: 56.62,90.68 56.5,90.57 55.94,90.57 55.8,90.42 55.8,90.22 55.65,90.07 55.42,90.07 55.17,89.82 U6304.F8
  TOP w0.241: U6304.K2 51.48,87.25
  TOP w0.508: 57.3,91.39 57.21,91.39 56.62,90.79 56.62,90.68 ; 57.3,91.39 v1(57.28,91.42) ; 57.3,91.39 57.66,91.03 58.38,91.03 58.51,91.16 C6314.1 ; 51.48,87.25 50.61,86.39 v1(50.27,86.39) 50.98,85.67 C6315.1 50.59,85.61 v2(50.08,85.11)
SD1_REXT: length 4.6
  TOP w0.076: U6304.E8 55.05,90.47 55.3,90.72 55.3,90.92 55.45,91.07 55.65,91.07 55.8,91.22 55.8,91.42 55.95,91.57 56.54,91.57 57.16,92.19
  TOP w0.152: 57.16,92.19 57.26,92.29 57.56,92.29 57.58,92.32 57.86,92.36 57.98,92.37 58.06,92.45 R6346.1
SD_CD#: length 26.1
  TOP w0.102: v1(11.19,44.9) 11.19,44.49 11.39,44.29 EC3301.1 11.92,44.29 12,44.37 v1(12,44.87)
  L4 w0.102: v1(15.44,31.55) 15.44,32.21 15.49,32.26 15.49,32.77 15.21,33.05 15.19,33.05 15.01,33.23 15.01,33.86 14.78,34.09 14.15,34.09 12.8,35.44 12.8,35.61 12.57,35.84 12.4,35.84 7.06,41.18 7.06,44.12 8.58,45.65 10.74,45.65 11.19,45.2 v1(11.19,44.9)
  BOTTOM w0.102: v1(12,44.87) 11.63,44.5 R3309.2 ; SD1.1 15.25,31.3 15.44,31.5 v1(15.44,31.55) v2(15.84,31.15)
SD_CD#_CARD: length 2
  BOTTOM w0.102: R3309.1 R3307.2 10.87,42.85 10.69,42.67 U3301.13
SD_MMC_CLK/MS_DATA2: length 25.2
  L4 w0.127: v1(15.57,40.86) 15.3,40.36 15.12,39.81 14.83,38.63 14.68,36.96 14.68,36.4 15.68,35.41 15.82,35.41 16.38,34.85 16.4,34.85 17.32,33.93 17.32,33.91 17.41,33.82 17.41,31.82 16.97,31.37 16.97,30.91 16.74,30.69 16.69,30.54 16.55,30.17 16.39,29.76 15.85,27.95 15.76,27.58 v1(15.34,27)
  BOTTOM w0.102: SD1.5 v1(15.34,27) ; v1(15.57,40.86) 15.62,40.87 15.62,40.87 16.53,40.3 ED3302.1 17.08,40.25 17.02,40.48 16.2,41.3 15.8,41.3 v2(15,42.11) 14.85,42.25 14.72,42.25 14.05,42.93 EC3307.1 R3303.2
SD_MMC_CMM/MS_DATA3: length 25.3
  TOP w0.102: v1(15.39,25.5) 15.37,25.52 v2(15.37,26.11)
  L4 w0.127: v1(15.24,36.65) 15.95,36.65 16.28,36.33 16.28,35.69 17.92,34.05 17.92,31.59 17.6,31.27 17.6,29.42 16.65,28.47 16.65,27.19 16.65,27.19 16.65,26.82 15.39,25.56 v1(15.39,25.5)
  BOTTOM w0.102: U3301.18 14.05,41.93 14.86,41.12 15.05,40.81 15.05,40.76 15.31,40.5 15.32,40.5 15.75,40.07 16.14,39.84 16.4,39.58 16.43,39.56 16.96,39.02 v2(17.82,38.95) 17.82,38 ED3301.2 16.68,36.86 16.05,36.65 v1(15.24,36.65) ; v1(15.39,25.5) 15.27,25.37 15.19,25.37 15.01,25.2 SD1.7
SD_MMC_DAT1: length 27.4
  L4 w0.127: v1(15.34,29.75) 15.93,30.33 15.93,30.62 16.45,31.13 16.45,31.59 16.9,32.04 16.9,33.61 16.81,33.7 16.81,33.71 16.19,34.34 16.17,34.34 15.61,34.9 15.39,34.9 15.2,35.09 14.8,35.09 10.52,39.37 10.52,40.31 9.19,41.63 9.19,43.94 v1(8.81,44.32)
  BOTTOM w0.102: v1(8.81,44.32) 8.63,44.5 ED3303.1 7.81,43.68 7.06,42.93 7.06,41.84 v2(7.34,41.56) 7.62,41.28 8.69,41.28 9.58,40.38 U3301.10 ; v1(15.34,29.75) 15.3,29.7 SD1.2
SD_MMC_DATA0/MS_DATA5: length 28
  TOP w0.102: v1(8.76,45.21) 8.76,45.18 9.08,44.87 9.08,44.86 v2(9.14,44.8)
  L4 w0.127: v1(15.34,29.03) 14.9,29.48 14.9,30.69 15.26,31.05 15.65,31.05 15.94,31.34 15.94,31.82 16.4,32.28 16.4,33.39 16.31,33.48 16.31,33.5 15.98,33.83 15.63,33.83 15.51,33.96 15.51,34.07 14.99,34.58 14.59,34.58 10.01,39.16 10.01,39.91 8.37,41.54 8.37,44.73 8.76,45.12 v1(8.76,45.21)
  BOTTOM w0.102: U3301.11 9.71,40.88 9.45,41.15 9.45,44.24 ED3303.2 9.47,44.5 v1(8.76,45.21) ; v1(15.34,29.03) 15.11,28.8 SD1.3
SD_MMC_DATA2/MS_BS: length 25.9
  TOP w0.102: v1(15.37,24.08) 15.61,24.08 v2(15.87,24.33)
  L4 w0.127: v1(15.54,39) 15.54,38.17 15.63,38.08 16.04,38.08 17.31,36.81 17.31,36.11 18.94,34.48 18.94,32.58 19.06,32.45 19.09,32.45 19.22,32.33 19.22,32.07 19.09,31.95 19.06,31.95 18.94,31.82 18.94,31.13 18.62,30.81 18.62,29.09 18.83,28.88 19.2,28.88 19.33,28.76 19.33,28.15 19.2,28.02 18.86,28.02 18.73,27.9 18.73,27.44 v1(15.37,24.08)
  BOTTOM w0.102: v1(15.37,24.08) 14.69,23.4 SD1.9 ; v1(15.54,39) 15.86,38.68 ED3301.1 15.56,37.95 15.25,38.26 15.25,38.66 14.94,38.98 14.76,38.98 14.66,39.08 14.66,39.85 14.13,40.38 U3301.21
SD_MMC_DATA3/MS_CLK: length 25.3
  L4 w0.127: v1(15.38,24.8) 15.9,25.33 15.9,25.35 17.4,26.85 17.4,26.99 17.16,27.24 17.16,27.47 17.34,27.65 17.52,27.65 17.79,27.37 17.94,27.37 18.11,27.54 18.11,28.07 17.98,28.2 17.62,28.2 17.49,28.33 17.49,28.59 17.63,28.74 17.98,28.74 18.11,28.86 18.11,31.04 18.43,31.36 18.43,34.27 16.8,35.9 16.8,35.96 16.79,35.97 16.79,36.54 16.78,36.55 16.78,36.63 15.83,37.57 15.65,37.57 v1(15.37,37.29)
  BOTTOM w0.102: v1(15.37,37.29) 15.56,37.1 15.98,37.1 16.13,37.25 16.44,37.25 16.84,37.66 16.84,38.34 v2(16.21,38.97) 16.21,39.14 15.95,39.4 15.77,39.4 15.42,39.75 ED3302.2 15.18,39.96 14.25,40.88 U3301.20 ; SD1.8 14.77,24.3 15.28,24.8 v1(15.38,24.8)
SD_WP#/MS_DATA1_C: length 2.5
  TOP w0.102: v2(9.75,40.01) v1(9.19,40.01)
  BOTTOM w0.102: R3311.2 8.56,40.59 9.14,40.01 v1(9.19,40.01) 9.19,39.96 9.77,39.38 U3301.8
SDREG: length 3.3
  BOTTOM w0.305: U3301.6 9.86,38.15 9.12,38.89 9.12,39.3 v2(9.03,39.38) 8.66,39.75 8.26,39.75
SENSOR_I2C_SCL: length 1.2
  TOP w0.089: R6935.1 100.51,83.88 TP6901.1
SENSOR_I2C_SCL_R: length 10
  TOP w0.089: RN6901.4 98.66,87.32 99.82,87.32 v2(100.46,86.68) 100.89,86.24 100.89,84.85 99.77,83.73 99.77,83.35 R6935.2 99.32,82.9 97.73,82.9 97.38,83.25 U6901.1
SENSOR_I2C_SDA: length 1.3
  TOP w0.089: TP6902.1 95.51,87.76 R6936.1
SENSOR_I2C_SDA_R: length 3.6
  TOP w0.089: v2(95.8,86.54) 95.8,86.57 96.13,86.9 R6936.2 96.76,86.89 ; 96.76,86.89 RN6901.3 ; 96.76,86.89 97.15,86.5 97.15,86.5 97.38,86.27 U6901.4
SENSOR_KB_DIS: length 184.3
  L3 w0.102: v1(45.24,36.68) 45.75,37.19 53.15,37.19 56.73,33.61 60.17,33.61 60.2,33.63 64.14,33.63 64.79,34.28 73.84,34.28 77.21,30.91 79.93,30.91 84.91,25.94 85.45,25.94 85.7,25.68 85.7,25.53 87.69,23.55 93.85,23.55 94.69,24.39 95.05,24.39 95.3,24.13 95.3,23.77 95.06,23.53 95.06,22.41 95.74,21.73 97.12,21.73 97.97,22.58 97.97,23.38 98.12,23.54 100.14,23.54 101.27,22.4 107.36,22.4 108,21.77 113.21,21.77 v1(117.37,17.6)
  BOTTOM w0.102: v1(117.37,17.6) 117.37,85.77 118.97,87.37 118.97,89.31 121.05,91.38 127.85,91.38 128.1,91.14 133.39,91.14 134.29,92.03 134.88,92.03 v2(135,91.92) 135.2,91.71 135.2,91.24 136.39,90.05 IOBD1.16 ; 43.48,35.97 43.79,36.27 45.03,36.27 45.21,36.45 45.21,36.55 45.24,36.58 v1(45.24,36.68) ; 43.48,35.97 R2428.2 ; 43.48,35.97 43.97,35.97 44.04,36.04 45.67,36.04 46.35,35.36 U2401.101
SER_RXD: length 156.9
  TOP w0.102: v1(131.37,72.29) 130.76,71.68 130.76,70.16 130.99,69.93 130.99,69.27 131.49,68.76 131.81,68.76 v2(132.3,68.26) 133.51,67.06 138.85,67.06 140.32,68.53 140.69,68.53 141.86,69.7 141.86,70.31 146.69,75.13 154.4,75.13 154.42,75.16 154.47,75.16 162.12,82.81 162.12,82.86 162.15,82.89 162.15,83.89 162.28,84.02 R6109.1
  L3 w0.102: v1(131.37,72.29) 130.51,73.15 130.51,76.96 130.76,77.22 130.76,87.33 123.65,94.44 106.27,94.44 105.41,93.58 99.59,93.58 98.45,94.72 98.45,94.97 98.2,95.23 97.82,95.23 95.48,92.89 93.73,92.89 90.81,89.97 90.04,89.97 89.81,89.74 85.14,89.74 80.57,85.17 80.57,84.81 80.54,84.79 80.54,83.44 80.29,83.19 79.56,83.19 76.43,80.05 76.43,80.04 76.3,79.91 73.71,79.91 73.03,79.22 73.03,78.57 73.03,78.57 73.03,77.29 73,77.27 73,60.25 73.05,60.2 73.05,60.02 73.74,59.34 73.74,58.17 73.51,57.94 73.51,55.35 73.1,54.94 71.99,54.94 v1(71.3,54.25)
  BOTTOM w0.102: v1(71.3,54.25) 71.26,54.21 71.26,54.21 71,53.95 CPU1.AG5
SER_TXD: length 158.4
  TOP w0.102: v1(132.03,72.01) 131.88,71.86 131.44,71.86 131.19,71.61 131.19,70.27 131.49,69.98 v2(131.5,69.98) 131.5,69.97 133.96,67.51 138.61,67.51 140.46,69.37 140.46,70.12 145.98,75.64 154.31,75.64 161.42,82.75 161.42,85.45 R6108.1
  L3 w0.102: v1(132.03,72.01) 132.31,72.73 132.41,72.82 132.41,73.33 131.65,74.09 131.65,76.46 132.26,77.07 132.26,86.15 123.74,94.67 106.17,94.67 105.31,93.8 100.59,93.8 98.94,95.45 97.71,95.45 95.38,93.12 93.62,93.12 90.7,90.2 89.94,90.2 89.72,89.97 85.05,89.97 80.52,85.45 79.96,85.45 79.17,84.66 79.17,83.14 76.17,80.14 73.62,80.14 72.77,79.29 72.77,63.73 72.8,63.7 72.8,60.16 72.85,60.11 72.85,59.09 72.45,58.7 72.45,57.76 71.65,56.96 71.65,56.2 71.42,55.96 70.32,55.96 v1(69.71,55.35)
  BOTTOM w0.102: CPU1.AJ4 70.2,54.97 69.82,55.35 v1(69.71,55.35)
SLEEVE_R: length 14.2
  L3 w1.016: v3(147.5,98.35) 146.43,97.28 144.53,97.28 144.45,97.21 135.92,97.21 135.9,97.18 135.86,97.18 134.98,96.29 v3(134.98,95.43)
  vias: v2(135.94,94.24)
SMB0_CLK: length 67.2
  L4 w0.14: v1(85.12,63.43) 85.12,68.58 86.97,70.44 86.97,70.62 89.23,72.87 90.27,72.87 91.96,74.56 94.88,74.56 94.89,74.58 94.97,74.58 98.65,78.26 98.65,78.28 107.18,86.81 124.26,86.81 v1(124.71,86.36)
  BOTTOM w0.089: v1(124.71,86.36) 124.71,86.26 123.58,85.13 DIMM1.253 ; RN1703.3 v2(91.15,65.12) 90.85,65.43 86.93,65.43 86.68,65.18 86.68,64.98 86.05,64.35 85.58,64.35 85.12,63.89 v1(85.12,63.43) 85.12,63.3 85.68,62.74 85.68,61.48 86,61.16 CPU1.AY33
SMB0_DATA: length 72.3
  L4 w0.14: v1(84.96,62.77) 84.61,63.11 84.61,67.86 84.79,68.03 84.79,68.61 86.72,70.54 86.72,70.99 89.05,73.32 90.07,73.32 91.78,75.03 94.79,75.03 98.2,78.44 98.2,78.46 106.99,87.26 124.46,87.26 125.23,86.49 125.23,86.15 125.49,85.89 127.44,85.89 v1(128.02,86.46)
  BOTTOM w0.089: RN1703.4 91.97,65.62 86.86,65.62 86.83,65.59 86.78,65.59 v2(86.07,64.88) 85.73,64.54 85.5,64.54 84.92,63.97 84.92,63.8 84.72,63.59 84.72,63.01 v1(84.96,62.77) 84.98,62.77 85.45,62.3 CPU1.BA32 ; v1(128.02,86.46) 128.02,85.81 128.47,85.35 128.88,85.35 128.9,85.37 DIMM1.254
SML1_CLK: length 83.2
  TOP w0.089: v1(44.04,19.28) 44.03,19.27 43.96,19.27 43.74,19.05 43.51,19.05 43.21,18.76 RN2401.3 43.04,18.21 43.04,16.83 43.03,16.81 43.03,15.96 43.27,15.72 43.27,15.67 43.29,15.65 43.29,14.76 43.54,14.51 v2(43.54,14.34) 44.42,13.46 v1(44.42,12.98)
  L3 w0.14: v1(89.81,14.48) 88.9,13.57 85.37,13.57 85.35,13.55 84.98,13.55 84.96,13.57 81.64,13.57 81.03,14.17 81.03,14.66 v1(81,14.68)
  L4 w0.14: v1(81,14.68) 78.57,12.25 63.71,12.25 59.19,7.73 48.87,7.73 48.39,7.26 46.36,7.26 45.42,8.2 45.42,10.77 45.09,11.1 45.09,11.23 44.42,11.9 v1(44.42,12.98)
  BOTTOM w0.089: Q801.3 73.77,22.43 72.9,21.57 72.9,18.58 73.26,18.22 74.09,18.22 74.99,17.33 74.99,16.34 75.14,16.19 76.38,16.19 76.95,15.62 78.19,15.62 79,14.81 80.44,14.81 80.57,14.68 v1(81,14.68) ; Q2604.6 90.43,15.05 89.87,14.48 v1(89.81,14.48) ; v1(44.04,19.28) 44.25,19.49 44.25,20.34 44.27,20.35 44.27,20.88 44.19,20.96 44.19,21.62 44.05,21.75 U2401.67
SML1_DATA: length 84.3
  TOP w0.089: v1(82.45,14.66) 82.63,14.66 82.91,14.93 83.26,14.93 83.66,14.53 84.64,14.53 84.71,14.45 85.58,14.45 85.92,14.11 87.41,14.11 87.8,14.49 87.8,15.66 v1(88.52,16.38) ; v1(43.69,11.74) v2(43.69,12.53) 43.69,13.69 43.18,14.19 43.18,14.36 42.39,15.15 42.39,15.47 41.43,16.43 41.43,18.6 41.59,18.76 RN2401.4 41.83,19.03 42.04,19.24 42.8,19.24 42.8,19.24 43.2,19.24 43.36,19.41 43.37,19.41 44,20.05 44.02,20.05 44.62,20.64 v1(44.62,21.14)
  L4 w0.14: v1(43.69,11.74) 44.88,10.54 44.88,8.1 46.17,6.81 48.58,6.81 49.05,7.29 59.38,7.29 63.9,11.81 79.6,11.81 v1(82.45,14.66)
  BOTTOM w0.089: Q2604.3 88.55,16.35 v1(88.52,16.38) ; Q801.6 75.07,25.06 75.87,24.26 77.44,24.26 78.18,23.52 78.18,23.5 78.74,22.94 78.74,21.41 79.24,20.91 79.94,20.91 80.19,20.66 80.19,20.15 80.93,19.4 80.93,18.39 81.49,17.82 81.51,17.74 81.51,17.56 81.91,17.16 82.2,17.16 82.45,16.91 v1(82.45,14.66) ; v1(44.62,21.14) 44.63,21.15 44.63,21.65 44.13,22.15 U2401.68
SP5: length 3
  TOP w0.102: v1(12.47,43.42) v2(13.03,43.42)
  BOTTOM w0.102: R3303.1 v1(12.47,43.42) 12.47,43.22 11.69,42.44 U3301.15
SPI_CLK_KBC: length 7.4
  TOP w0.102: RN2405.1 48.23,29.9 48.13,30 v1(48.13,30.2) 48.13,30.66 v2(48.25,30.78)
  BOTTOM w0.102: v1(48.13,30.2) 48.13,30.48 47.27,31.34 44.75,31.34 44.73,31.32 44.37,31.32 43.94,31.75 U2401.92
SPI_CLK_ROM: length 191.7
  TOP w0.102: RN2405.4 48.23,27.85 48.22,27.84 48.22,26.71 48.51,26.42 v2(48.51,25.48) 48.32,25.29 48.32,23.15 48.69,22.79 48.69,22.77 48.74,22.73 48.74,22.33 48.69,22.29 48.69,22.07 v1(48.56,21.95)
  L4 w0.127: v1(48.56,21.95) 48.76,21.95 49.21,21.5 49.21,20.78 48.18,19.75 48.18,18.12 48.75,17.55 50.83,17.55 51.04,17.77 51.69,17.77 52.63,16.82 55.3,16.82 55.77,16.35 68.66,16.35 69.41,15.6 70.5,15.6 71.25,16.35 74.08,16.35 75.92,18.19 75.92,18.73 76.38,19.2 79.82,19.2 v1(79.85,19.16) 80.11,19.42 80.86,19.42 81.12,19.16 83.68,19.16 85.03,17.82 85.03,17.6 85.45,17.17 86.69,17.17 88.52,15.34 88.52,14.33 89.4,13.45 101.38,13.45 101.85,13.93 101.85,14.78 103.27,16.2 105.15,16.2 106.04,17.09 107.25,17.09 107.45,17.29 107.63,17.29 109.04,18.7 109.04,19.29 v1(109.52,19.76) ; v1(76.94,72.54) 76.94,73.26 77.11,73.43 77.11,74.14 79.73,76.76 79.73,77.71 82.35,80.33 82.35,80.74 82.63,81.03 84.12,81.03 85.47,82.38 85.47,82.62 85.97,83.12 86.41,83.12 86.83,83.12 87.01,83.3 87.9,84.19 90.56,84.19 93.85,87.48 93.87,87.48 94.18,87.79 97.09,87.79 98.91,85.98 98.91,85.72 99.16,85.47 99.55,85.47 99.69,85.61 100.97,85.61 101.35,85.99 102.2,85.99 v1(102.29,85.9)
  BOTTOM w0.102: v1(79.85,19.16) 79.85,18.79 81.04,17.61 81.04,17.36 81.71,16.69 81.71,16.69 81.81,16.59 U2501.6 ; RN1603.4 76.75,72.36 v1(76.94,72.54) ; v1(109.52,19.76) 109.42,19.86 109.42,20.36 109.39,20.4 109.39,22.76 109.62,23 109.62,23.3 109.73,23.41 109.73,35.97 109.77,36.01 109.77,77.83 103.02,84.58 103.02,84.85 102.29,85.58 v1(102.29,85.9)
SPI_CS_KBC_N0: length 6.2
  TOP w0.089: RN2405.2 47.07,29.65 47.07,30.66 46.83,30.9 v2(46.77,30.9) 46.27,30.9 46.08,30.71 v1(46.08,30.38)
  BOTTOM w0.089: v1(46.08,30.38) 45.82,30.63 44.25,30.63 43.93,30.95 U2401.90
SPI_CS_ROM_N0: length 181.9
  TOP w0.089: R2540.2 79.26,19.55 79.58,19.87 79.6,19.87 79.63,19.9 80.05,19.9 80.47,20.32 v1(80.61,20.32) ; v1(48.26,22.53) 47.92,22.87 47.92,22.88 47.85,22.94 47.85,25.26 47.8,25.31 47.8,25.33 47.75,25.38 47.75,25.51 48,25.76 48,26.11 47.66,26.46 47.66,26.59 47.58,26.67 RN2405.3
  L4 w0.14: v1(107.9,19.79) 107.9,18.28 107.41,17.8 107.24,17.8 107.04,17.6 105.83,17.6 105.19,16.97 103.28,16.97 101.17,14.86 90.93,14.86 88.72,17.07 87.58,17.07 86.88,17.77 86.14,17.77 84.24,19.67 81.33,19.67 81.07,19.93 81,19.93 v1(80.61,20.32) 80.23,19.93 79.86,19.93 79.78,19.86 76.31,19.86 75.12,18.66 74.37,18.66 72.57,16.87 69.95,16.87 69.93,16.85 68.9,16.85 68.88,16.87 55.99,16.87 55.42,17.43 52.75,17.43 51.9,18.28 50.26,18.28 50.04,18.07 48.96,18.07 48.7,18.33 48.7,19.54 49.73,20.57 49.73,21.71 48.9,22.53 v1(48.26,22.53) ; v1(78.66,73.28) 81.66,76.28 81.66,77.2 84.2,79.73 85.06,79.73 86.64,81.31 88.45,81.31 89.49,82.35 94.18,82.35 94.6,82.76 97.76,82.76 98.61,83.62 101.17,83.62 v1(101.4,83.85)
  BOTTOM w0.089: U2501.1 79.27,21.39 79.4,21.27 79.71,21.27 79.93,21.49 80.34,21.49 80.56,21.27 80.86,21.27 81.03,21.1 81.03,20.47 80.87,20.32 v1(80.61,20.32) ; RN1604.4 78.28,72.29 v2(78.41,72.42) 78.41,73.03 v1(78.66,73.28) ; v1(107.9,19.79) 107.9,19.9 108.25,20.26 108.25,23.23 108.48,23.46 108.48,76.77 v1(101.4,83.85)
SPI_CSN: length 31.4
  TOP w0.076: U6304.J6 54.05,88.17 54.13,88.09 54.16,88.09 54.3,87.95 54.3,87.55 54.34,87.5 54.34,86.91 54.76,86.49 v1(54.94,86.49)
  TOP w0.089: v1(32.89,85.24) v2(33.48,85.24)
  L4 w0.14: v1(54.94,86.49) 55.19,86.74 55.19,87.45 53.01,89.63 47.87,89.63 44.98,86.74 40.71,86.74 40.33,87.13 37.86,87.13 37.83,87.16 37.61,87.16 35.55,85.1 33.03,85.1 v1(32.89,85.24)
  BOTTOM w0.089: v1(32.89,85.24) 33.07,85.42 U6305.1
SPI_HOLD_CPU: length 171.6
  L3 w0.14: v1(84.58,17.63) 84.18,17.23 83.62,17.23 83.62,17.23 81.8,17.23 81.53,17.5 v1(80.47,17.5)
  L4 w0.14: v1(110.46,20.34) 110.61,20.18 110.61,19.59 109.98,18.95 109.82,18.95 109.56,18.69 109.56,18.31 109.95,17.92 110.05,17.92 110.32,17.65 110.32,17.15 109.02,15.86 108.26,15.86 107.56,15.15 103.7,15.15 102.95,14.39 102.95,13.54 101.81,12.4 88.97,12.4 87.47,13.9 87.47,14.91 86.3,16.08 81.89,16.08 v1(80.47,17.5) ; v1(75.9,73.89) 75.9,74.18 78.51,76.79 78.51,78.84 79.76,80.09 79.76,80.34 80.38,80.96 81.45,80.96 84.56,84.08 86.69,84.08 87.55,84.95 88.37,84.95 91.74,88.31 92.69,88.31 92.78,88.4 93.68,88.4 93.86,88.57 97.42,88.57 99.19,86.8 102.77,86.8 v1(102.93,86.63)
  BOTTOM w0.089: v1(84.58,17.63) 83.62,18.59 82.86,18.59 81.48,19.97 81.48,21.29 81.05,21.72 81.05,23.72 80.77,24 79.58,24 78.97,24.61 76.02,24.61 75.64,25 75.64,25.99 75.77,26.12 RN1601.2 ; v1(102.93,86.63) 102.95,86.63 103.03,86.55 103.03,86.28 103.53,85.78 103.53,85.33 103.82,85.04 103.82,84.89 103.96,84.74 104,84.74 110.79,77.96 110.79,36.04 110.42,35.68 110.42,23.12 110.32,23.01 110.32,22.71 110.08,22.47 110.08,20.68 110.36,20.4 110.39,20.4 v1(110.46,20.34) ; v1(75.9,73.89) 74.93,72.93 v2(74.93,72.24) R1617.2 ; v1(80.47,17.5) 80.54,17.43 U2501.7
SPI_MISO: length 31.3
  TOP w0.076: U6304.G6 54.3,89.07 54.3,88.72 54.3,88.22 54.44,88.07 54.65,88.07 54.8,87.92 54.8,87.16 v1(54.74,87.1)
  TOP w0.089: v1(32.36,83.95) v2(32.92,83.95)
  L4 w0.14: v1(32.36,83.95) 32.69,83.95 33.32,84.58 35.41,84.58 36.81,85.99 36.81,85.99 37.65,86.83 39.99,86.83 40.54,86.29 45.15,86.29 46.76,87.89 50.06,87.89 50.79,88.62 53.4,88.62 54.33,87.69 54.74,87.28 v1(54.74,87.1)
  BOTTOM w0.089: U6305.2 32.56,84.15 v1(32.36,83.95)
SPI_MOSI: length 29.8
  TOP w0.076: U6304.H6 54.05,88.67 53.8,88.42 53.8,87.72 53.56,87.48 53.56,87.09 54.05,86.59 v1(54.1,86.59)
  TOP w0.089: v2(30.67,82.56) 31.11,82.56 v1(31.22,82.45)
  L4 w0.14: v1(54.1,86.59) 53.87,86.59 53.57,86.89 52.95,86.89 52.9,86.84 47.19,86.84 45.57,85.22 39.8,85.22 37.67,83.09 33.3,83.09 32.66,82.45 v1(31.22,82.45)
  BOTTOM w0.089: U6305.5 30.38,81.61 v1(31.22,82.45)
SPI_SCK: length 27.7
  TOP w0.102: v2(31.19,83.75) v1(31.19,83.09) ; v1(53.95,87.25) 54.05,87.35 U6304.K6
  L4 w0.127: v1(31.19,83.09) 32.56,83.09 33.1,83.62 37.47,83.62 39.6,85.75 45.36,85.75 46.96,87.35 51.03,87.35 51.46,87.78 53.49,87.78 53.95,87.33 v1(53.95,87.25)
  BOTTOM w0.102: v1(31.19,83.09) 30.99,82.88 U6305.6
SPI_SI_KBC: length 4.3
  TOP w0.089: RN2406.2 46.06,29.33 45.44,29.95 v1(45.44,30.2) 45.44,30.72 v2(45.52,30.79)
  BOTTOM w0.089: v1(45.44,30.2) 45.44,30.05 45.14,29.75 U2401.87
SPI_SI_ROM: length 190.3
  TOP w0.089: RN2406.3 46.06,27.53 46.7,26.89 46.7,25.8 47.42,25.08 47.42,22.9 47.36,22.84 47.36,22.8 47.3,22.74 47.3,22.71 47.27,22.68 47.27,21.24 v1(47.23,21.2)
  L4 w0.14: v1(109.87,17.47) 109.58,17.18 109.58,16.79 108.94,16.16 108.15,16.16 107.42,15.42 103.59,15.42 102.67,14.49 102.67,13.64 101.7,12.67 89.08,12.67 87.74,14.01 87.74,15.02 86.4,16.36 83.31,16.36 v1(81.99,17.68) 81.49,18.18 79.11,18.18 78.97,18.32 77.23,18.32 73.7,14.79 49.43,14.79 47.23,16.99 v1(47.23,21.2) ; v1(77.65,73.92) 80.87,77.14 80.87,77.17 84,80.29 84,80.29 84.05,80.34 84.89,80.34 86.8,82.25 88.64,82.25 89.27,82.88 89.29,82.88 89.86,83.45 91.3,83.45 94.66,86.81 96.83,86.81 97.79,85.85 97.79,85.85 97.83,85.81 97.83,85.05 98.53,84.36 100.76,84.36 101.42,85.02 101.73,85.02 v1(101.78,85.07)
  BOTTOM w0.089: v1(77.65,73.92) 77.63,73.92 v2(77.18,73.47) 76.1,72.38 RN1603.3 ; v1(101.78,85.07) 101.78,84.93 102.1,84.61 102.1,83.99 109.07,77.02 109.07,62.74 109.03,62.7 109.03,23.92 108.92,23.82 108.92,23.59 108.92,23.59 108.92,23.33 108.91,23.32 108.91,23.28 108.68,23.05 108.68,20.08 108.65,20.05 108.65,18.94 109.87,17.72 v1(109.87,17.47) ; U2501.5 83.08,16.9 82.3,17.68 v1(81.99,17.68)
SPI_SO_CPU: length 187
  TOP w0.089: v1(47.7,21.74) v2(47.7,22.4) 47.7,22.79 47.63,22.85 47.63,25.17 47.58,25.22 47.58,25.24 46.91,25.91 46.91,27 46.71,27.21 RN2406.4
  L4 w0.14: v1(77.75,72.26) 77.53,72.49 77.53,73.06 81.31,76.84 81.31,77.22 84.1,80.01 84.96,80.01 86.93,81.99 88.75,81.99 89.38,82.62 89.4,82.62 89.97,83.18 91.66,83.18 92.02,83.54 94.76,83.54 95.18,83.12 97.47,83.12 98.35,84 100.86,84 101.3,84.43 v1(101.68,84.43) ; v1(47.7,21.74) 47.68,21.73 47.68,20.99 47.67,20.98 47.67,16.93 49.54,15.06 73.59,15.06 77.21,18.68 79.04,18.68 79.2,18.52 81.27,18.52 v1(81.37,18.63) 81.68,18.63 83.65,16.66 86.47,16.66 88,15.13 88,14.12 89.19,12.94 101.59,12.94 102.39,13.73 102.39,14.59 103.48,15.69 107.2,15.69 108.98,17.47 v1(109.23,17.47)
  BOTTOM w0.089: v1(109.23,17.47) 109.23,17.72 108.43,18.52 108.43,20.14 108.46,20.17 108.46,23.14 108.69,23.37 108.69,23.53 108.7,23.54 108.7,23.72 108.7,23.72 108.7,23.91 108.76,23.96 108.76,77.03 101.82,83.96 101.82,84.02 101.68,84.17 v1(101.68,84.43) ; v1(77.75,72.26) 77.63,72.14 RN1604.3 ; v1(81.37,18.63) 81.31,18.7 81.31,19.56 81.25,19.61 81.25,21.18 80.54,21.9 U2501.2
SPI_SO_KBC: length 5.9
  TOP w0.089: v1(46.63,30.08) 46.71,30 RN2406.1
  BOTTOM w0.089: v2(42.06,29.39) 42.1,29.35 U2401.86 45.91,29.35 v1(46.63,30.08)
SPI_WP_CPU: length 155.2
  L4 w0.14: v1(102.94,85.69) 102.94,85.97 102.38,86.53 99.08,86.53 97.3,88.31 93.97,88.31 93.8,88.13 92.89,88.13 92,87.24 91.15,87.24 88.61,84.7 87.69,84.7 87.05,84.07 86.62,83.64 84.5,83.64 81.38,80.52 81.21,80.52 79.68,79 79.07,79 78.79,78.72 78.79,76.56 76.56,74.32 v1(76.56,73.61) ; v1(81.93,20.12) 84.17,20.12 86.26,18.04 87.01,18.04 87.7,17.35 88.84,17.35 91.07,15.13 101.05,15.13 103.25,17.32 105,17.32 105.57,17.9 106.24,17.9 106.89,18.55 106.89,18.55 107.07,18.73 107.07,19.6 107.71,20.24 109.69,20.24 v1(110.16,19.77)
  BOTTOM w0.089: v1(110.16,19.77) 109.99,19.94 109.99,19.96 109.9,20.05 109.9,20.56 109.86,20.59 109.86,22.56 110.1,22.8 110.1,23.1 110.21,23.21 110.21,35.77 110.25,35.81 110.25,78.14 103.5,84.89 103.5,85.05 102.94,85.6 v1(102.94,85.69) ; R1619.2 77.24,68.45 77.1,68.6 76.48,68.6 75.34,69.74 75.34,72.4 v2(76.01,73.06) v1(76.56,73.61) ; v1(81.93,20.12) 81.93,21.3 81.81,21.42 U2501.3 81.81,23.91 81.23,24.49 79.5,24.49 79.17,24.82 79.1,24.82 79.07,24.84 76.28,24.84 76.19,24.93 RN1601.1
SPKR: length 102.8
  L3 w0.254: v1(120.05,91.67) 119.69,92.03 99.25,92.03 94.61,87.4 94.61,86.86 93.45,85.7 93.45,82.87 84.24,73.66 84.24,72.69 83.69,72.14 83.69,69.16 82.69,68.16 82.69,66.26 83.52,65.43 83.52,64.8 83.21,64.49 82.83,64.49 81.89,63.55 81.89,62.84 82.63,62.1 82.63,57.37 v1(83.27,56.73)
  BOTTOM w0.254: CPU1.AP29 83.66,57.12 v1(83.27,56.73) ; v1(120.05,91.67) 120.43,92.05 128.13,92.05 128.38,91.8 133.12,91.8 133.93,92.61 v2(133.93,93.46) 134.2,93.73 134.2,95.88 134.72,96.39 134.72,97.69 134.49,97.92 134.49,98.92 135.49,99.91 142.96,99.91 143.24,99.63 147.37,95.51 R2741.1
SVID_ALERT#_CPU: length 78
  TOP w0.102: v2(23.04,47.25) 23.06,47.27 23.23,47.11 23.51,47.11 23.52,47.11 23.81,47.11 v1(24.03,47.32) 24.16,47.45 PG4607.1
  L4 w0.102: v1(79.63,32.51) 79.1,31.98 77.29,31.98 75.13,34.14 71.27,34.14 70.94,34.47 67.13,34.47 66.83,34.16 63.07,34.16 62.18,35.05 61.42,35.05 60.83,34.47 58.5,34.47 58.34,34.32 57.15,34.32 56.46,33.62 56.17,33.62 55.77,33.22 55.46,33.22 55.19,32.96 55.09,32.96 54.22,32.08 52.98,32.08 52.72,31.83 51.51,31.83 49.96,30.28 49.49,30.28 48.4,29.19 43.68,29.19 42.03,30.84 36.3,30.84 34.11,33.02 32.74,33.02 32.11,33.66 29.9,33.66 29.49,34.06 26.8,34.06 24.43,36.43 24.43,36.81 23.65,37.59 23.52,37.72 23.52,40.77 22.96,41.33 22.96,46.25 v1(24.03,47.32)
  BOTTOM w0.102: R801.2 79.78,32.36 v1(79.63,32.51) 79.98,32.87 R810.1
SVID_CLK_CPU: length 80.9
  TOP w0.102: PG4603.1 23.55,52.71 v1(23.32,52.48) 23.32,52.86 v2(23.11,53.07)
  L4 w0.102: v1(23.32,52.48) 24.69,51.11 24.69,47.05 24.3,46.66 24.28,46.66 23.42,45.8 23.42,41.55 23.98,40.98 23.98,37.92 24.89,37.01 24.89,36.62 26.99,34.52 29.69,34.52 30.1,34.11 32.31,34.11 32.94,33.48 34.32,33.48 36.5,31.29 42.22,31.29 43.87,29.64 48.21,29.64 49.3,30.74 49.77,30.74 51.32,32.29 52.53,32.29 52.79,32.54 53.14,32.54 53.54,32.94 53.54,33.02 53.79,33.27 54.42,33.27 54.7,33.55 54.7,33.76 55.72,34.77 58.15,34.77 58.31,34.93 60.64,34.93 61.22,35.51 62.38,35.51 63.27,34.62 66.45,34.62 66.75,34.93 71.15,34.93 71.42,34.65 75.29,34.65 77.29,32.64 v1(78.36,32.64)
  BOTTOM w0.102: R813.1 v1(78.36,32.64) 78.31,32.6 RN807.3
SVID_DATA_CPU: length 80.2
  TOP w0.102: v2(22.81,50.55) v1(23.37,50.55) 23.55,50.55 23.83,50.83 PG4605.1
  L4 w0.102: v1(78.99,32.59) 78.61,32.21 77.39,32.21 75.18,34.42 71.32,34.42 71.04,34.7 66.98,34.7 66.67,34.39 63.17,34.39 62.28,35.28 61.32,35.28 60.73,34.7 58.4,34.7 58.25,34.55 55.81,34.55 54.96,33.7 54.96,33.33 54.96,33.32 54.96,33.15 54.12,32.31 52.88,32.31 52.63,32.06 51.41,32.06 49.86,30.51 49.4,30.51 48.3,29.41 43.77,29.41 42.12,31.07 36.4,31.07 34.21,33.25 32.84,33.25 32.21,33.89 30,33.89 29.59,34.29 26.9,34.29 24.66,36.53 24.66,36.9 24.6,36.96 24.6,36.97 23.75,37.82 23.75,40.87 23.19,41.43 23.19,45.9 24.21,46.92 24.23,46.92 24.46,47.14 24.46,49.46 v1(23.37,50.55)
  BOTTOM w0.102: RN807.4 78.96,32.56 v1(78.99,32.59) 79.12,32.72 79.12,32.74 79.22,32.84 R820.1
SVID_PWRGD: length 84.6
  L3 w0.102: v1(23.44,47.68) 23.44,41.42 26.16,38.71 27.59,38.71 28.14,38.15 28.14,37.03 29.42,35.75 31.76,35.75 32.26,35.26 33.76,35.26 34.34,34.67 35.92,34.67 36.2,34.96 41.4,34.96 41.7,35.26 42.77,35.26 43.26,34.77 45.42,34.77 46.28,33.91 46.7,33.91 46.78,33.82 46.9,33.82 47,33.72 47,33.19 47.45,32.74 50.62,32.74 51.06,32.3 51.92,32.3 52.07,32.16 54.84,32.16 54.97,32.29 61.68,32.29 62.22,32.83 64.43,32.83 65.19,33.59 73.55,33.59 76.96,30.18 79.35,30.18 v1(81.32,28.21)
  BOTTOM w0.102: v1(23.44,47.68) 23.57,47.68 23.75,47.86 24.41,47.86 24.97,48.41 PR4621.1 25.22,48.54 PR4619.2 ; U801.3 87.08,23.11 86.59,23.6 85.22,23.6 83.67,25.15 R823.1 R818.1 82.78,26.75 v2(82.33,27.2) v1(81.32,28.21)
SVID_PWRGD_R: length 25.7
  TOP w0.102: v1(79.6,25.86) 79.6,25.9 78.54,26.96 78.54,28.13 80.26,29.85 80.26,32.51 80.24,32.54 80.24,33.45 79.38,34.32 79.38,35.2 79.69,35.51 79.93,35.51 79.96,35.54 80.39,35.54 81.23,36.37 82.21,36.37 82.77,36.93 82.77,41.38 82.31,41.84 81.74,41.84 v2(81.61,41.96) 81.71,42.06 81.71,42.72 81.32,43.12 v1(81.05,43.12)
  BOTTOM w0.102: v1(81.05,43.12) 81.45,42.72 CPU1.G25 ; R818.2 81.81,26.27 C802.1 80.54,26.27 80.14,25.86 v1(79.6,25.86)
SYS_PRES1#: length 3.9
  TOP w0.102: AFTP4306.1 113.82,15.52 114.2,15.15 v1(114.2,15.01) 113.77,14.58 113.36,14.17 R4301.2
  BOTTOM w0.102: v1(114.2,15.01) 114.53,14.69 BATT1.7
SYS_PWRGD: length 76.9
  TOP w0.102: v1(59.89,51.41) 59.41,50.93 59.41,49.07 61.32,47.17 61.58,47.17 64.1,44.65 64.1,39.1 60.51,35.51 60.51,33.28 60.33,33.1 60.33,32.55 60.51,32.36 60.52,32.36 62.36,30.52 62.36,29.83 63.17,29.02 63.17,28.02 64.05,27.14 64.05,25.67 64.06,25.67 64.06,24.76 64.07,24.74 64.07,23.16 v2(64.26,22.97) 64.26,22.09 v1(64.34,22.01) ; R2609.2 32.92,34.83 36.42,31.32 38.98,31.32 39.23,31.08 39.92,31.08 40.31,30.68 40.52,30.68 41.15,30.06 R4004.2 41.35,29.57 41.35,29.17 41.45,29.07 v1(41.5,29.07)
  L3 w0.102: v1(41.5,29.07) 41.54,29.11 42.52,29.11 44.22,27.41 44.27,27.36 48.81,27.36 49.35,26.82 50.57,26.82 51.21,26.19 52.31,26.19 54.36,24.15 54.36,23.39 54.71,23.04 54.76,23.04 55.22,22.58 57.58,22.58 57.94,22.94 60.73,22.94 60.86,22.8 62.05,22.8 62.5,22.35 64,22.35 v1(64.34,22.01)
  BOTTOM w0.102: v1(41.5,29.07) 41.54,29.03 42.16,29.03 42.64,28.55 U2401.84 ; v1(59.89,51.41) 60.07,51.23 60.55,51.23 60.93,50.85 R1731.1
SYS_PWRGD_G: length 3.4
  TOP w0.102: v2(33.1,35.69) R2609.1 R2607.1 32.41,36.53 32.84,36.96 v1(32.89,36.96)
  BOTTOM w0.102: Q2603.G 32.76,37.6 32.89,37.47 v1(32.89,36.96)
SYS_PWRGD_R: length 8.4
  BOTTOM w0.102: CPU1.AE2 68.54,52.52 68.24,52.82 67.96,52.82 67.8,52.66 66.12,52.66 65.43,51.97 v2(62.75,51.97) 62.15,51.97 61.85,51.67 R1718.2 R1731.2
SYS_RESET#: length 9.8
  BOTTOM w0.102: CPU1.AF1 67.58,53.07 67.18,53.47 66.71,53.47 66.56,53.33 v2(65.8,53.33) 65.25,53.33 64.87,53.71 64.87,54.05 64.92,54.1 64.92,54.88 64.6,55.2 G1702.2 G1701.2 62.18,55.63 R2008.1 R2002.2
T_CRIT#: length 3.6
  BOTTOM w0.102: U2601.4 93.28,25.21 92.76,25.73 v2(92.76,25.73) 92.76,26.52 R2606.2 93.24,26.24 R2601.1
THERM_SYS_SHDN#: length 74.5
  TOP w0.102: v1(48.49,36.12) 48.52,36.12 48.97,36.58 48.97,36.93 48.62,37.29 46.14,37.29 45.55,37.87 43.99,37.87 43.61,38.25 41.58,38.25 40.41,37.09 38.91,37.09 38.2,36.37 38.13,36.37 38.02,36.27 38.02,35.89 37.82,35.69 37.36,35.69 37.01,36.04 v1(37.01,36.53)
  L3 w0.102: v1(48.49,36.12) 50.22,36.12 51.94,34.4 54.54,34.4 55.04,33.89 55.04,33.59 55.41,33.22 60.12,33.22 60.3,33.4 64.24,33.4 64.88,34.05 73.75,34.05 77.11,30.68 79.78,30.68 82.08,28.38 82.08,28.08 86.9,23.26 94.18,23.26 v1(94.87,23.95)
  BOTTOM w0.102: R2602.1 48.79,36.2 48.74,36.15 48.54,36.15 48.51,36.12 v1(48.49,36.12) ; Q2603.S 34.97,37.72 36.17,36.53 v1(37.01,36.53) ; v1(94.87,23.95) 94.54,24.28 v2(94.54,25.35) R2601.2
TOUCH_PANEL_EN: length 31.2
  TOP w0.102: v1(52.55,28.42) 52.92,28.06 v2(52.92,28)
  L3 w0.102: v1(52.55,28.42) 55.42,28.42 55.86,27.98 57.09,26.75 58.8,26.75 59.41,26.14 59.8,26.14 61.6,27.94 v1(64.8,27.94)
  BOTTOM w0.102: U2401.25 59.34,23.75 59.55,23.55 59.55,23.36 59.81,23.1 60.21,23.1 60.52,22.8 61.65,22.8 61.65,22.8 62.05,22.8 62.69,22.15 63.78,22.15 64.18,22.56 64.55,22.56 65.94,23.95 65.94,25.1 65.94,25.11 65.94,25.13 66.2,25.38 66.45,25.63 66.45,26.12 65.79,26.78 64.43,26.78 64.24,26.59 D2402.K 64.42,27.23 R2427.2 65.09,27.65 v1(64.8,27.94)
TOUCH_PANEL_INTR#: length 78.8
  TOP w0.127: v1(63.57,31.29) 63.57,33.47 64.85,34.75 64.85,36.27 66.34,37.77 66.34,46.81 64.36,48.8 R1708.2 64.37,49.95 R1735.2 64.57,50.94 65.34,50.94 66.76,49.52 67.82,49.52 68.15,49.84 68.15,51.44 67.36,52.22 66.55,52.22 66.01,52.76 66.01,54.28 66.03,54.3 66.03,54.7 66.01,54.71 66.01,54.76 66.22,54.97 66.23,54.97 67.16,55.91 69.98,55.91 v1(70.43,56.36) ; R5504.2 60.75,82.35 61.59,81.51 v2(61.59,80.76) 62.32,80.03 62.32,77.48 62.99,76.82 68.17,76.82 69.16,75.83 v1(71.37,75.83)
  L3 w0.127: v1(71.37,75.83) 71.47,75.83 71.75,75.54 71.75,75.29 71.78,75.26 71.78,74.91 71.75,74.88 71.75,73.08 72.33,72.5 72.33,64.56 71.78,64.01 71.78,60.86 72.63,60.01 72.63,59.2 72.14,58.7 72.14,57.75 71.55,57.16 71.23,57.16 v1(70.43,56.36)
  BOTTOM w0.127: v1(70.43,56.36) 70.41,56.34 70.36,56.34 70.2,56.18 CPU1.AL4 ; v1(63.57,31.29) 63.96,31.29 64.9,30.35 64.9,29.91 D2402.A
TP_CLK: length 11.9
  TOP w0.089: v1(36.5,8.43) 36.5,8.08 AFTP6532.1 ; v1(37.97,14.45) 38.41,14.89 RN6504.4
  BOTTOM w0.089: Q6508.6 38.5,14.98 v1(37.97,14.45) 37.06,13.54 37.02,13.54 36.5,13.03 TPAD1.3 v1(36.5,8.43)
TP_CLK_C: length 7.7
  BOTTOM w0.089: TPAD1.8 31.5,10.11 31.38,9.99 30.9,9.99 30.06,10.82 AFTP6529.1 27.76,10.82 27.55,10.61 RN6502.3
TP_DAT: length 14
  TOP w0.089: AFTP6531.1 38.39,8.45 v1(37.5,8.45) ; v1(41.65,13.05) 41.65,14.31 41.15,14.8 RN6504.3
  BOTTOM w0.089: v1(37.5,8.45) TPAD1.2 37.5,12.96 37.65,13.12 38.88,13.12 38.97,13.03 38.97,12.37 39.42,11.92 40,11.92 40.35,12.26 40.86,12.26 v1(41.65,13.05) 41.34,13.36 Q6508.3
TP_DATA_C: length 10.2
  BOTTOM w0.089: TPAD1.7 32.5,10.08 32.05,9.63 30.75,9.63 30.08,10.31 29.4,10.31 28.01,8.92 AFTP6530.1 27.99,9.65 27.61,10.03 27.26,10.03 27.19,9.96 RN6502.4
TP_DISABLE#: length 45
  L4 w0.102: v1(28.21,7.67) 31.16,7.67 34.23,4.61 v1(34.23,4.39)
  BOTTOM w0.102: TPAD1.6 33.5,10.57 31.42,8.49 29.72,8.49 28.91,7.67 v1(28.21,7.67) 28.34,7.55 v2(28.34,7.1) 27.72,6.48 R6520.2 ; v1(34.23,4.39) 34.26,4.36 49.95,4.36 50.33,4.74 50.33,8.67 50.89,9.23 50.89,10.61 50.41,11.09 50.41,15.05 R2494.1
TP_DISABLE#_R: length 6.1
  BOTTOM w0.102: R2494.2 49.4,15.15 v2(48.46,16.1) 48.4,16.1 45.55,18.95 U2401.62
TP_I2C_CLK: length 187.8
  L3 w0.14: v1(42.84,15.54) 42.84,15.54 43.1,15.28 43.1,15.22 44.4,13.92 44.7,13.92 44.73,13.9 45.7,13.9 46.44,13.16 47.95,13.16 48.49,12.62 50.69,12.62 50.81,12.51 51.68,12.51 51.71,12.54 53.3,12.54 53.33,12.57 54.07,12.57 54.25,12.75 55.56,12.75 56.62,13.81 72.31,13.81 72.35,13.77 74.06,13.77 74.09,13.81 80.51,13.81 81.5,12.81 102.47,12.81 102.8,13.14 104.62,13.14 104.63,13.13 105.51,13.13 106.45,12.19 106.45,12.17 v1(106.83,11.79)
  L4 w0.14: v1(80.11,65.23) 80.08,65.23 79.58,65.72 79.58,67.32 79.78,67.51 79.78,73.74 82.12,76.07 82.12,76.6 84.13,78.61 84.58,78.61 86.35,80.39 88.44,80.39 88.45,80.38 88.82,80.38 88.83,80.38 88.85,80.39 90.38,80.39 91.88,81.89 94.36,81.89 94.79,82.32 97.94,82.32 98.79,83.17 101.13,83.17 v1(101.37,82.93)
  BOTTOM w0.089: RN1704.4 42.86,18.15 43.26,17.75 43.26,16.82 43.06,16.62 43.06,16.61 43.06,16.26 43.06,16.26 43.06,16.08 42.92,15.94 42.92,15.62 v1(42.84,15.54) 42.78,15.54 42.22,14.98 Q6508.1 ; v1(106.83,11.79) 106.88,11.83 106.88,12.34 107.67,13.13 v2(107.67,13.62) 107.67,15.73 108.18,16.24 108.99,16.24 109.24,16.49 109.24,16.84 108.08,18 108.08,18.99 107.47,19.6 107.47,19.81 107.47,19.98 107.89,20.4 107.89,23.38 108.12,23.6 108.12,76.18 v1(101.37,82.93) ; CPU1.AY22 80.19,60.81 80.19,61.06 80.25,61.12 80.25,61.44 80.11,61.57 80.11,63.07 80.09,63.1 80.09,65.2 v1(80.11,65.23)
TP_I2C_DATA: length 193.1
  L3 w0.14: v1(39.78,13.04) 39.89,13.15 40.91,13.15 41.46,12.6 41.83,12.6 42.03,12.79 42.45,12.79 43.08,13.43 45.54,13.43 46,12.97 46.26,12.71 47.77,12.71 48.08,12.4 48.08,12.38 48.28,12.17 48.78,12.17 48.78,12.18 50.51,12.18 50.71,11.98 51.29,11.98 51.31,12 51.8,12 51.89,12.09 53.48,12.09 53.52,12.13 54.26,12.13 54.43,12.3 56.19,12.3 57.25,13.36 72.13,13.36 72.16,13.33 74.25,13.33 74.28,13.36 77.97,13.36 78.96,12.37 102.67,12.37 103,12.7 104.43,12.7 104.45,12.68 105.33,12.68 105.99,12.02 105.99,11.97 v1(106.17,11.79)
  L4 w0.14: v1(80.04,65.89) 80.24,66.09 80.24,73.38 82.7,75.85 82.7,76.56 84.1,77.95 85.52,77.95 87.51,79.94 88.26,79.94 88.27,79.93 89.01,79.93 89.02,79.93 89.02,79.94 90.56,79.94 91.79,81.17 94.29,81.17 94.96,81.84 98.09,81.84 98.97,82.72 99.46,82.72 99.78,82.4 v1(99.97,82.4) ; v1(39.78,13.04) 40.01,13.27 40.01,13.87 41.36,15.22 41.36,18.61 42.48,19.72 v1(42.79,19.72)
  BOTTOM w0.089: v1(80.04,65.89) 80.04,65.84 79.71,65.51 79.71,64.97 79.88,64.8 79.88,63.02 79.91,62.99 79.91,61.31 CPU1.BA22 ; v1(99.97,82.4) 100.4,82.82 100.86,82.82 107.77,75.92 107.77,23.75 107.54,23.52 107.54,20.55 107.12,20.13 107.12,19.96 107.1,19.95 107.1,18.96 106.91,18.77 106.91,18.19 107.16,17.94 107.18,17.94 108.06,17.06 108.06,16.63 107.15,15.73 107.15,13.18 106.52,12.55 v2(106.17,12.55) v1(106.17,11.79) ; v1(42.79,19.72) 42.79,19.12 42.19,18.52 RN1704.3 ; Q6508.4 39.69,13.13 v1(39.78,13.04)
TP_ON#: length 39.4
  L3 w0.102: v1(53.47,18.11) 57.46,18.11 v1(57.75,18.4)
  L4 w0.102: v1(53.47,18.11) 53.47,18.29 52.61,19.14 52.33,19.14 49.97,21.5 49.97,21.81 48.82,22.96 48.08,22.96 46.62,21.5 46.62,17.24 49.53,14.33 49.53,14.12 49.81,13.84 50.01,13.84 51.41,12.45 51.86,12.45 52.49,11.81 52.49,11.45 51.2,10.16 48.79,10.16 v1(46.44,7.81)
  BOTTOM w0.102: R2407.2 59.49,18.36 v2(58.82,18.36) 57.79,18.36 v1(57.75,18.4) 57.75,19.21 57.43,19.53 U2401.33 ; R6516.1 46.13,7.54 46.41,7.81 v1(46.44,7.81)
TP_ON#_GATE: length 12
  BOTTOM w0.102: 45.43,11.19 Q6507.2 ; 45.43,11.19 Q6507.5 ; 45.43,11.19 45.36,11.25 44.3,11.25 ; 44.3,11.25 44.3,11.97 Q6503.G ; 44.3,11.25 44.3,9.65 C6504.1 44.15,8.41 44.25,8.31 Q6504.G ; Q6504.G 44.92,7.64 C6505.1 45.72,6.05 v2(45.96,5.82) ; Q6504.G 45.01,8.4 R6516.2
TP_VDD: length 56.2
  TOP w0.254: v1(36.07,11.39) 36.07,11.7 35.7,12.07 v1(30.7,12.07) ; 40.89,13.11 40.89,12.68 41.15,12.42 AFTP6528.1 40.76,11.62 v1(40.33,11.62)
  BOTTOM w0.254: R6513.1 41.55,11.64 Q6503.D ; Q6503.D 41.61,11.65 43.45,13.49 44.86,13.49 45.53,14.17 R6504.1 R6505.1 ; Q6503.D 40.36,11.65 v1(40.33,11.62) ; v1(30.7,12.07) 30.5,12.27 26.77,12.27 26.51,12.01 25.47,12.01 24.69,11.23 24.38,11.23 23.92,10.78 RN6503.2 23.47,10.75 23.26,10.54 23.26,10.19 23.37,10.08 RN6503.1 23.92,9.49 23.3,8.88 Q6502.G 23.88,7.94 24.57,8.63 25.36,8.63 25.37,8.62 25.87,8.62 26.39,8.1 R6512.1 26.39,7.35 R6520.1 ; TPAD1.1 38.5,11.98 39.11,11.37 40.08,11.37 v1(40.33,11.62) ; EC6502.1 28.63,6.1 30.24,7.71 34.39,7.71 34.98,8.3 ; 34.98,8.3 35.35,7.93 37.92,7.93 37.93,7.93 38.28,7.93 38.9,8.55 38.9,10.19 39.18,10.47 40.01,10.47 40.33,10.79 v1(40.33,11.62) ; 34.98,8.3 34.98,10.3 v1(36.07,11.39)
TP_VDD_1D8V: length 31.7
  L4 w0.254: v1(40.34,12.7) 40.34,12.36 38.89,10.91 38.89,7.01 39.62,6.28 42.04,6.28 v1(42.26,6.5)
  BOTTOM w0.254: v1(42.26,6.5) 42.53,6.5 42.78,6.75 Q6504.D 43.41,6.73 43.41,5.7 44.14,4.98 47.88,4.98 48.17,5.27 R6518.1 48.74,6.62 48.74,7.93 48.64,8.03 48.64,8.1 48.34,8.4 46.97,8.4 46.72,8.65 R6506.1 ; Q6508.5 40.45,14.33 ; 40.45,14.33 40.51,14.27 40.51,13.2 40.34,13.03 v1(40.34,12.7) ; 40.45,14.33 Q6508.2 ; 40.45,14.33 40.44,14.33 40.44,15.31 40.77,15.63 42.08,15.63 42.44,15.99 v2(42.44,16.11) 42.44,16.48 42.62,16.66
TPAN_VDD: length 14.9
  TOP w0.508: v1(61.59,79.43) 61.2,79.43 v2(60.77,79.86) 60.77,81.24 v1(60.17,81.84)
  BOTTOM w0.305: 65.35,84.28 65.1,84.53 LCD1.39
  BOTTOM w0.508: v1(61.59,79.43) 62.36,79.43 62.69,79.1 64.11,79.1 65.33,80.32 F5503.2 66.04,80.47 C5519.1 65.94,81.97 C5520.1 65.94,83.69 65.35,84.28 ; ED5501.5 59.79,82.22 v1(60.17,81.84)
TPCLK: length 30.7
  L4 w0.14: v1(36.88,14.5) 36.88,11.57 35.63,10.32 31.17,10.32 v1(31.07,10.41)
  BOTTOM w0.089: v1(31.07,10.41) 30.28,11.21 27.64,11.21 27.41,10.97 26.21,10.97 EC6501.1 25.7,10.66 RN6502.2 25.35,10.61 25.22,10.75 RN6503.3 ; v1(36.88,14.5) 36.88,14.82 36.6,15.09 36.6,15.44 36.67,15.51 36.67,15.55 37.04,15.91 37.04,19.62 v2(38.59,21.17) 39.65,22.23 41.52,22.23 41.94,22.64 41.94,22.96 42.73,23.75 U2401.72
TPDATA: length 31.2
  TOP w0.089: v1(27.43,9.61) v2(27.99,9.61)
  L4 w0.14: v1(27.43,9.61) 35.55,9.61 37.33,11.38 37.33,14.31 37.33,14.31 37.33,14.69 37.33,14.69 37.33,14.97 v1(37.03,15.27)
  BOTTOM w0.089: v1(37.03,15.27) 37.03,15.4 37.45,15.82 37.45,19.53 39.77,21.85 41.57,21.85 42.16,22.44 42.16,22.77 42.75,23.35 U2401.71 ; v1(27.43,9.61) 27.41,9.59 26.18,9.59 25.73,9.13 EC6503.1 25.62,9.65 25.78,9.81 25.78,9.94 RN6502.1 25.64,10.08 RN6503.4
TPNL_INT: length 4
  TOP w0.127: R5504.1 59.95,82.55 C5518.1 59.82,83.13 v2(58.98,83.13) 58.98,83.87 v1(59.08,83.97)
  BOTTOM w0.127: v1(59.08,83.97) 59.08,84.51 59.1,84.53 LCD1.27
TS_USB20_CON_N1: length 6.2
  BOTTOM w0.089: 60.73,84.12 60.73,83.02 ED5501.6 60.74,81.6 60.25,81.11 60.25,79.73 EL5502.1 ; 60.73,84.12 v2(60.52,84.12) ; 60.73,84.12 60.73,84.53 60.6,84.66 LCD1.30
TS_USB20_CON_P1: length 6
  BOTTOM w0.089: EL5502.2 60.74,79.6 ED5501.1 60.74,81.24 60.99,81.48 60.99,82.22 61.24,82.48 61.24,83.46 60.97,83.73 60.97,84.53 61.1,84.66 LCD1.31
TS_USB20_N1: length 27.8
  TOP w0.089: v1(60.25,77.73) v2(59.92,78.2)
  L4 w0.114: v1(60.25,77.73) 60.34,77.64 60.34,76.71 60.76,76.29 60.76,74.01 61.09,73.68 61.09,71.07 60.78,70.76 60.78,68.88 60.5,68.61 60.5,68.04 61.34,67.2 61.34,62.97 62.03,62.28 62.48,62.28 62.71,62.05 62.71,60.78 v1(62.53,60.61)
  BOTTOM w0.089: v1(60.25,77.73) 60.25,77.85 60.3,77.9 60.3,78.21 EL5502.4 ; CPU1.AV2 68.91,59.67 68.61,59.97 68.3,59.97 68.26,59.92 67.96,59.92 66.8,61.08 63.7,61.08 63.57,60.94 62.94,60.94 62.61,60.61 v1(62.53,60.61)
TS_USB20_P1: length 26.4
  TOP w0.089: v1(60.88,77.73) 60.88,77.72 v2(61.28,77.32)
  L4 w0.114: v1(63.17,60.5) 63.17,60.59 62.93,60.83 62.93,62.14 62.57,62.5 62.12,62.5 61.56,63.06 61.56,67.29 60.72,68.13 60.72,68.52 60.99,68.79 60.99,70.67 61.3,70.98 61.3,73.77 60.97,74.1 60.97,76.38 60.55,76.8 60.55,77.37 60.88,77.7 v1(60.88,77.73)
  BOTTOM w0.089: v1(60.88,77.73) 60.75,77.85 EL5502.3 ; CPU1.AV1 68.37,59.67 68.35,59.68 67.86,59.68 66.7,60.83 63.8,60.83 63.67,60.7 63.31,60.7 63.17,60.56 v1(63.17,60.5)
UART_RX: length 2.2
  TOP w0.102: TP6306.1 56.41,93.96 55.55,93.09 U6304.A9
UART_TX: length 2.6
  TOP w0.102: U6304.A10 56.05,92.65 56.79,93.4 57.51,93.4 TP6305.1
USB1_USB20_CON_N6: length 10.4
  BOTTOM w0.089: AFTP3402.1 19.08,53.49 ; 19.08,53.49 19.08,52.62 19.01,52.55 ED3505.3 19.01,51.74 19.38,51.37 20.49,51.37 20.7,51.16 20.7,50.8 EL3503.4 ; 19.08,53.49 19.08,53.65 18.72,54 17.81,54 17.6,54.2 16.18,54.2 15.73,54.65 14.81,54.65 14.48,54.98 USB1.2
USB1_USB20_CON_P6: length 10.2
  BOTTOM w0.089: USB1.3 14.48,54.06 14.83,54.41 15.63,54.41 16.08,53.96 17.15,53.96 17.2,53.91 17.2,53.49 ; 17.2,53.49 17.2,53.11 17.11,53.02 ED3505.1 17.11,51.92 17.77,51.26 18.36,51.26 18.47,51.36 19.05,51.36 19.28,51.13 20.37,51.13 20.45,51.06 20.45,50.85 EL3503.3 ; 17.2,53.49 AFTP3403.1
USB1_USB20_N6: length 77.5
  L4 w0.114: v1(20.78,48.77) 20.89,48.77 21,48.88 21,55.57 21.95,56.52 21.95,62.64 26.59,67.28 33,67.28 34.09,68.37 34.09,70.03 35.18,71.12 49.53,71.12 49.87,70.78 50.77,70.78 51.18,70.37 51.18,68.63 52.58,67.24 52.58,66.7 53.43,65.85 53.43,63.95 54.08,63.3 54.08,62.97 55.03,62.02 55.03,60.97 55.6,60.4 55.6,59.73 v1(55.79,59.55)
  BOTTOM w0.089: 57.42,59.26 56.92,58.76 56.04,58.76 55.59,59.22 55.59,59.35 v1(55.79,59.55) ; 57.42,59.26 v2(57.28,59.39) ; 57.42,59.26 57.68,59.53 60.98,59.53 61.31,59.2 62.53,59.2 63.15,58.58 63.71,58.58 63.86,58.43 64.48,58.43 65.1,57.81 65.3,57.81 65.68,57.43 66.14,57.43 66.46,57.11 66.83,57.11 66.91,57.02 67.77,57.02 67.96,57.22 68.24,57.22 68.35,57.1 68.62,57.1 CPU1.AN2 ; v1(20.78,48.77) 20.67,48.87 20.67,49.25 EL3503.1
USB1_USB20_P6: length 77.8
  L4 w0.114: v1(20.78,48.13) 21.22,48.57 21.22,55.48 22.16,56.43 22.16,62.55 26.68,67.06 33.09,67.06 34.3,68.28 34.3,69.94 35.27,70.91 49.44,70.91 49.78,70.56 50.68,70.56 50.97,70.28 50.97,68.54 52.36,67.15 52.36,66.61 53.21,65.76 53.21,63.86 53.86,63.21 53.86,62.88 54.81,61.93 54.81,60.88 55.38,60.31 55.38,59.78 v1(55.14,59.54)
  BOTTOM w0.089: 59.06,59.29 60.88,59.29 61.21,58.96 62.43,58.96 63.05,58.34 63.61,58.34 63.76,58.19 64.38,58.19 65,57.57 65.2,57.57 65.58,57.19 66.04,57.19 66.36,56.87 66.73,56.87 66.81,56.78 67.87,56.78 68,56.92 CPU1.AN1 ; 59.06,59.29 57.78,59.29 57.02,58.52 55.94,58.52 55.35,59.12 55.35,59.34 v1(55.14,59.54) ; 59.06,59.29 v2(59.06,59.09) ; EL3503.2 20.34,49.34 20.34,48.58 v1(20.78,48.13)
USB1_USB30_RX_CON_N2: length 14.5
  BOTTOM w0.089: 17.2,45.8 17.2,44.96 ED3504.1 17.14,44.3 C3511.1 17.24,44 17.24,43.43 R3506.2 ; 17.2,45.8 v2(17.02,45.8) ; 17.2,45.8 17.2,46.66 16.66,47.19 14.99,47.19 14.24,47.94 14.24,49.19 15.25,50.2 15.25,51.32 14.8,51.77 14.16,51.77 13.66,51.27 13.2,51.27 12.98,51.06 USB1.5
USB1_USB30_RX_CON_P2: length 15.1
  BOTTOM w0.089: USB1.6 12.98,51.84 13.31,51.51 13.56,51.51 14.06,52.01 14.9,52.01 15.49,51.42 15.49,50.1 14.48,49.09 14.48,48.04 15.09,47.44 16.76,47.44 17.08,47.12 ; R3505.2 17.49,43.45 17.49,44.03 C3510.1 17.68,44.22 17.68,44.81 ED3503.1 17.44,45.15 17.44,46.76 17.08,47.12 ; 17.08,47.12 v2(17.25,47.24)
USB1_USB30_RX_N2: length 67.8
  L4 w0.114: v1(58.47,46.61) 58.5,46.59 58.75,46.59 58.98,46.81 59.51,46.81 60.29,46.04 60.29,44.39 58.64,42.73 58.64,42.34 58.59,42.29 58.59,41.95 53.29,36.65 52.95,36.65 52.93,36.64 51.14,36.64 48.87,34.38 48.83,34.38 48.65,34.2 43,34.2 42.98,34.17 42.28,34.17 41.95,34.51 36.74,34.51 34.96,36.29 30.97,36.29 30.58,36.68 30.23,36.68 29.82,37.09 29.02,37.09 28.29,37.81 27.88,37.81 27.71,37.64 v1(27.71,37.39)
  BOTTOM w0.089: 26.19,36.93 27.08,36.93 27.53,37.39 v1(27.71,37.39) ; 26.19,36.93 25.3,36.93 22.33,39.91 19.03,39.91 17.25,41.69 17.25,42.06 R3506.1 ; 26.19,36.93 v2(26.19,36.78) ; CPU1.Y1 68.34,49.77 68.33,49.79 67.87,49.79 66.07,47.98 63.58,47.98 62.13,46.53 61.34,46.53 61.26,46.62 58.48,46.62 v1(58.47,46.61)
USB1_USB30_RX_P2: length 67.2
  L4 w0.114: v1(58.93,46.15) 58.93,46.38 59.14,46.6 59.42,46.6 60.07,45.95 60.07,44.47 58.42,42.82 58.42,42.43 58.37,42.38 58.37,42.04 53.2,36.87 52.86,36.87 52.84,36.86 51.05,36.86 48.79,34.6 48.74,34.6 48.56,34.41 42.91,34.41 42.89,34.39 42.37,34.39 42.04,34.72 36.83,34.72 35.05,36.51 31.06,36.51 30.67,36.9 30.32,36.9 29.91,37.3 29.11,37.3 28.38,38.03 27.79,38.03 27.58,37.82 27.15,37.82 v1(27.05,37.72)
  BOTTOM w0.089: 23.92,38.65 25.4,37.17 26.98,37.17 27.22,37.42 27.22,37.55 v1(27.05,37.72) ; 23.92,38.65 v2(24.03,38.76) ; 23.92,38.65 22.43,40.15 19.13,40.15 17.49,41.79 17.49,42.05 R3505.1 ; v1(58.93,46.15) 59.15,46.38 61.16,46.38 61.24,46.29 62.23,46.29 63.68,47.74 66.17,47.74 67.97,49.54 68.21,49.54 68.3,49.46 68.58,49.46 68.89,49.77 CPU1.Y2
USB1_USB30_TX_CMC_N2: length 1.2
  BOTTOM w0.089: C3505.2 19.51,43.11 19.54,43.14 19.54,43.61 R3504.1
USB1_USB30_TX_CMC_P2: length 1.2
  BOTTOM w0.089: R3503.1 19.78,43.6 19.78,43.19 C3506.2
USB1_USB30_TX_CON_N2: length 20.8
  BOTTOM w0.089: 19.96,47.07 v2(19.97,47.26) ; 19.96,47.07 21,47.07 21.6,47.67 21.6,48.89 21.76,49.04 21.76,51.27 20.28,52.74 20.28,53.64 19.12,54.8 18.14,54.8 17.91,55.02 16.77,55.02 15.47,56.33 14.28,56.33 13.73,56.87 13.17,56.87 12.98,56.69 USB1.8 ; 19.96,47.07 19.37,47.07 19.22,46.92 19.22,46.47 ED3502.1 19.15,45.82 C3509.1 19.32,45.45 19.32,44.77 R3504.2
USB1_USB30_TX_CON_P2: length 21.8
  BOTTOM w0.089: USB1.9 12.98,57.96 14.38,56.57 15.57,56.57 16.87,55.27 18.01,55.27 18.24,55.04 18.58,55.04 ; 18.58,55.04 19.22,55.04 20.52,53.74 20.52,52.84 22,51.37 22,48.94 21.84,48.79 21.84,47.57 21.1,46.83 19.6,46.83 19.56,46.79 19.56,46.51 ED3501.1 19.66,45.75 C3508.1 20.04,45.32 R3503.2 ; 18.58,55.04 v2(18.58,55.24)
USB1_USB30_TX_N2: length 62.7
  L4 w0.114: v1(58.93,45.34) 58.71,45.12 58.55,45.12 58.45,45.21 58.29,45.21 57.75,44.67 57.75,42.29 52.94,37.49 50.8,37.49 48.53,35.22 47.15,35.22 47.01,35.36 37.08,35.36 35.31,37.13 34.14,37.13 33.37,37.9 30.91,37.9 30.83,37.97 v1(30.48,37.97)
  BOTTOM w0.089: 25.81,38.6 25.31,38.6 24.49,39.43 24.49,40.71 24.23,40.96 20.31,40.96 19.3,41.96 C3505.1 ; 25.81,38.6 v2(25.81,38.46) ; 25.81,38.6 26.62,38.6 26.9,38.88 28.23,38.88 28.32,38.79 28.32,37.92 28.54,37.71 28.54,37.7 28.93,37.3 29.27,37.3 29.29,37.29 29.82,37.29 30.43,37.9 30.43,37.92 v1(30.48,37.97) ; v1(58.93,45.34) 58.78,45.34 58.69,45.25 58.69,44.91 58.85,44.74 59.46,44.74 59.72,45 62.06,45 64.01,46.94 67.7,46.94 67.93,46.71 68.22,46.71 68.28,46.77 68.6,46.77 68.64,46.72 69.06,46.72 69.15,46.63 CPU1.P2
USB1_USB30_TX_P2: length 61.8
  L4 w0.114: v1(29.84,37.97) 30.33,38.46 30.63,38.46 30.89,38.2 30.91,38.2 31,38.11 33.46,38.11 34.23,37.35 35.4,37.35 37.17,35.58 47.1,35.58 47.24,35.43 48.44,35.43 50.71,37.71 52.85,37.71 57.53,42.38 57.53,44.76 58.27,45.5 58.39,45.62 v1(58.39,45.72)
  BOTTOM w0.089: 24.73,39.93 24.73,39.53 25.41,38.84 26.52,38.84 26.8,39.12 28.33,39.12 28.56,38.89 28.56,38.02 28.78,37.81 28.78,37.8 29.03,37.54 29.37,37.54 29.39,37.53 29.72,37.53 29.84,37.66 v1(29.84,37.97) ; 24.73,39.93 v2(24.87,39.93) ; 24.73,39.93 24.73,40.6 24.74,40.62 24.74,40.79 24.33,41.2 20.41,41.2 19.96,41.65 19.96,41.88 C3506.1 ; v1(58.39,45.72) 58.45,45.67 58.45,44.81 58.75,44.5 59.56,44.5 59.82,44.76 62.16,44.76 64.11,46.7 67.6,46.7 67.83,46.47 CPU1.P1
USB2_PWR_EN#: length 195.9
  TOP w0.102: v1(110.42,12.01) v2(109.86,12.01)
  L3 w0.102: v1(110.42,12.01) 110.3,12.12 108.35,12.12 107.01,13.46 107.01,13.51 106.64,13.87 105.9,13.87 105.82,13.78 104.9,13.78 104.89,13.79 104.79,13.79 104.7,13.88 104.7,14.35 104.45,14.61 103.33,14.61 102.18,13.46 91.96,13.46 90.11,15.31 88.07,15.31 87.53,15.85 79.12,15.85 77.71,17.26 77.71,17.48 77.03,18.17 75.77,18.17 75.33,18.61 74.78,18.61 74.73,18.57 70.07,18.57 69.88,18.76 69.14,18.76 68.75,18.37 68.75,18.31 68.47,18.03 67.06,18.03 66.38,17.35 52.7,17.35 51.54,18.52 v1(49.15,18.52)
  L4 w0.102: v1(52.81,24.1) 52.81,22.24 52.98,22.06 52.98,21.71 52.54,21.26 52.5,21.26 52.25,21.01 52.25,20.65 53.9,19 53.9,17.93 53.65,17.68 52.86,17.68 51.71,18.82 49.45,18.82 v1(49.15,18.52)
  BOTTOM w0.102: v1(52.81,24.1) 52.47,24.1 51.82,24.75 51.82,28.46 51.11,29.17 51.11,32.41 50.75,32.76 U2401.112 50.75,35.97 R2444.2 ; v1(110.42,12.01) 110.19,12.23 110.19,14.7 111.48,15.99 114.04,15.99 114.19,16.14 115.74,16.14 116.23,15.65 118.23,15.65 118.95,16.36 118.95,16.75 119.52,17.33 119.52,18 118.95,18.57 118.95,85.38 122.19,88.62 123.81,88.62 124.02,88.83 126.7,88.83 127.17,88.36 130.67,88.36 131.67,87.35 132.72,87.35 133.32,86.74 133.32,86.74 133.58,86.49 135.64,86.49 135.71,86.56 136.6,86.56 136.62,86.55 IOBD1.23
USB2_USB20_CON_N3: length 7.7
  BOTTOM w0.089: 132.99,81.56 132.89,81.56 132.66,81.33 132.66,80.77 132.39,80.5 EL6603.1 ; 132.99,81.56 133.71,81.56 134.07,81.93 134.07,82.07 134.87,82.87 134.87,83.6 135.4,84.13 136.04,84.13 136.3,83.87 136.68,83.87 136.85,84.05 IOBD1.28 ; 132.99,81.56 AFTP6602.1
USB2_USB20_CON_P3: length 7.3
  BOTTOM w0.089: 135.29,83.68 135.12,83.5 135.12,82.77 134.32,81.97 134.32,81.83 133.81,81.32 132.99,81.32 132.91,81.23 132.91,80.79 133.04,80.65 EL6603.2 ; 135.29,83.68 135.5,83.89 135.94,83.89 136.2,83.63 136.67,83.63 136.75,83.55 IOBD1.29 ; 135.29,83.68 AFTP6603.1
USB2_USB20_N3: length 127.4
  L4 w0.114: v1(65.43,59.74) 65.51,59.82 65.51,59.84 65.61,59.95 65.61,66.85 65.51,66.96 65.48,66.96 64.1,68.34 64.1,71.53 67.98,75.41 67.98,77.2 68.68,77.9 68.68,83.31 69.08,83.7 69.08,84.62 69.72,85.27 69.72,89.56 72.64,92.48 73.64,92.48 78.25,97.09 85.6,97.09 86.56,96.14 96.55,96.14 96.88,96.47 99.52,96.47 101.9,94.08 105.03,94.08 106.05,95.1 106.05,95.73 106.78,96.47 109.01,96.47 109.16,96.32 116.98,96.32 117.08,96.22 128.72,96.22 128.85,96.09 130.33,96.09 132.99,93.42 132.99,91.86 135.58,89.27 135.58,84.23 134.77,83.42 134.77,82.68 133.88,81.79 133.88,80.37 v1(134.52,79.73)
  BOTTOM w0.089: v2(133.53,78.22) 133.53,78.43 ; 133.53,78.43 133.73,78.43 134,78.71 134,79.64 134.05,79.69 134.21,79.85 134.4,79.85 v1(134.52,79.73) ; 133.53,78.43 132.95,78.43 132.39,78.99 EL6603.4 ; v1(65.43,59.74) 65.66,59.74 65.68,59.77 66.75,59.77 67.46,59.06 67.72,59.06 67.97,58.8 68.22,58.8 68.27,58.85 68.3,58.85 68.33,58.88 68.58,58.88 68.76,58.7 68.76,58.67 68.86,58.57 CPU1.AT2
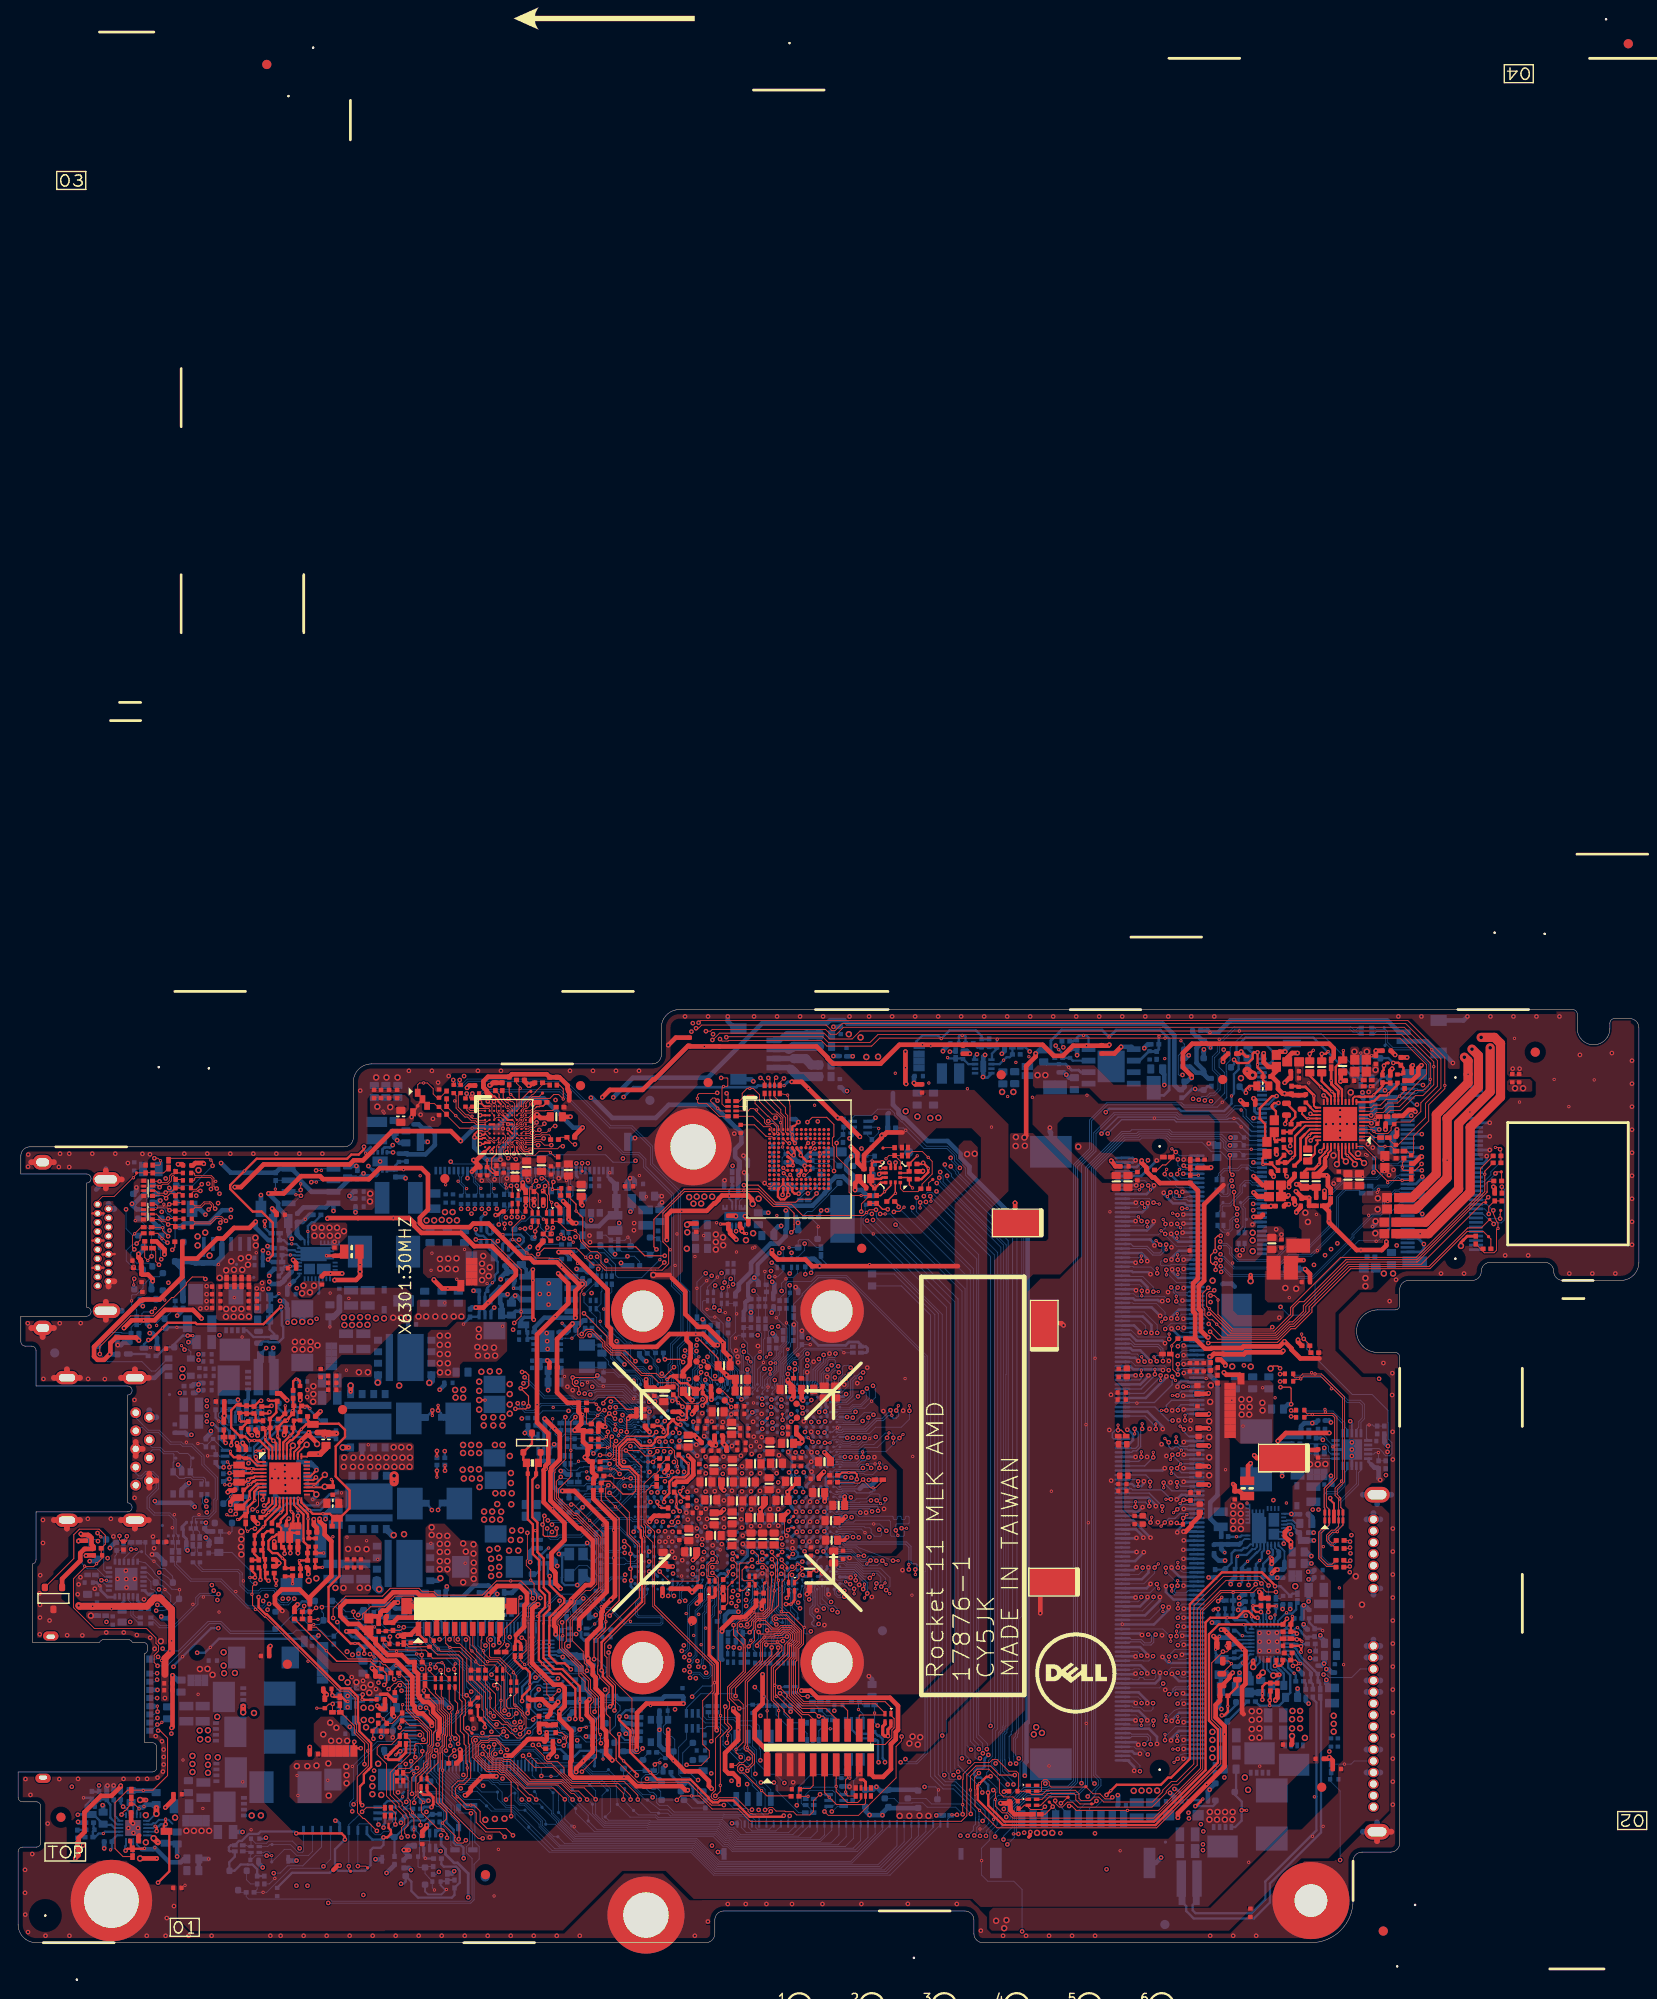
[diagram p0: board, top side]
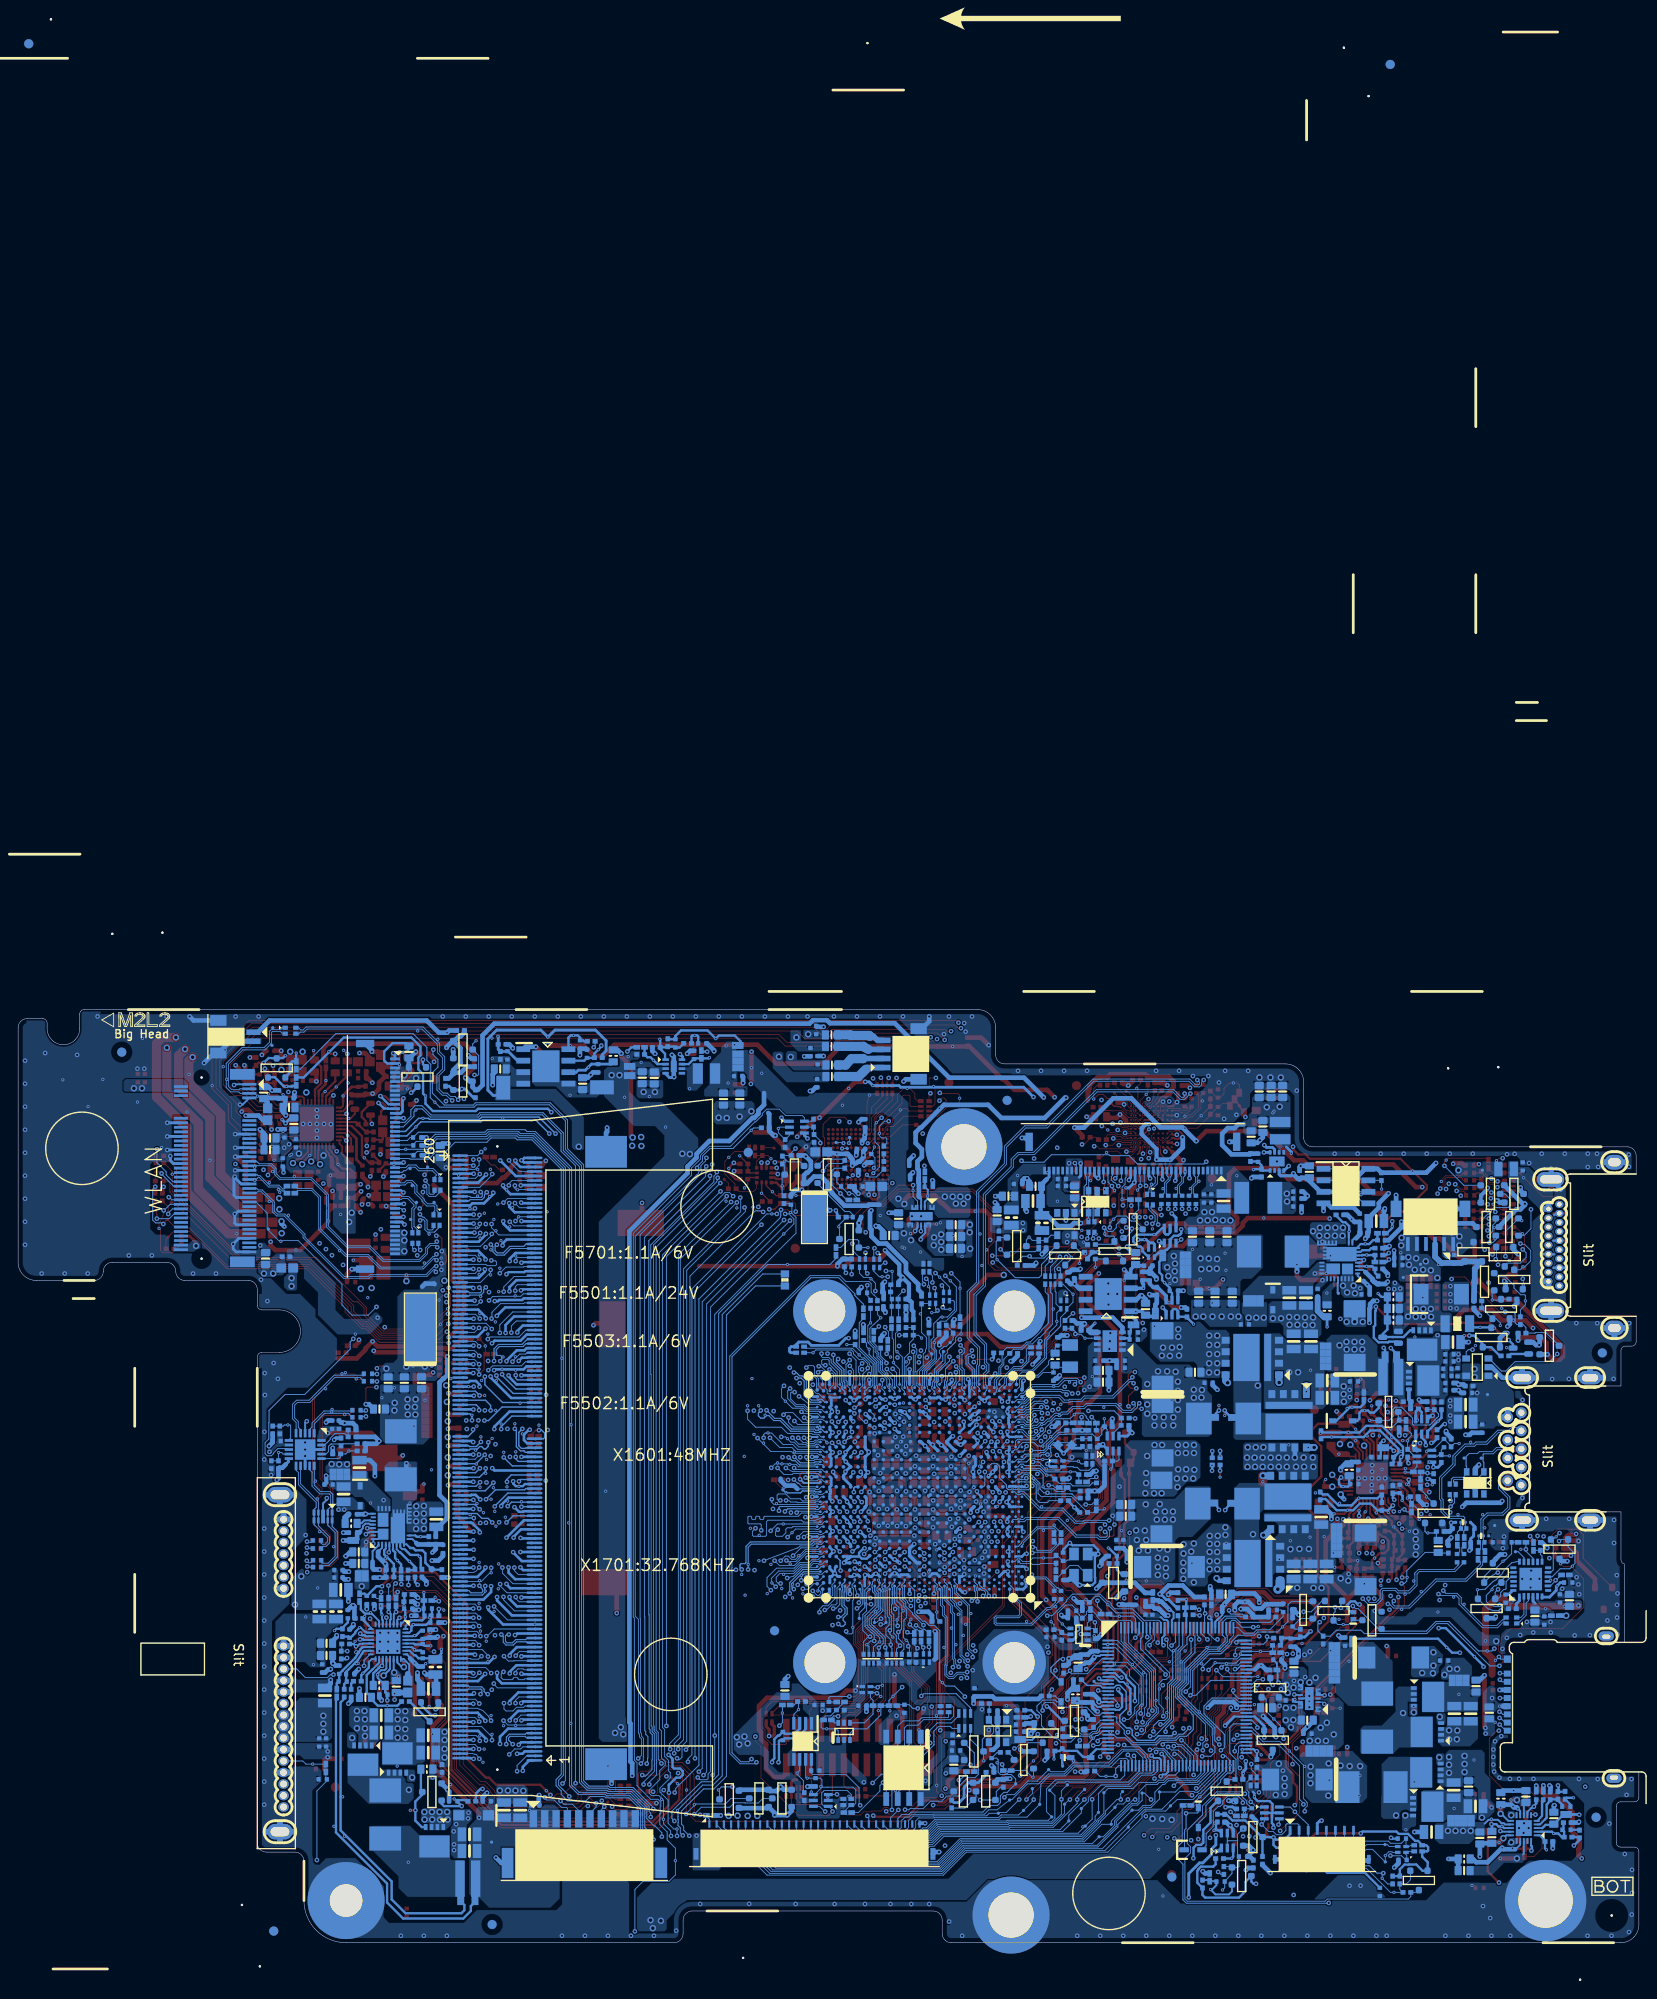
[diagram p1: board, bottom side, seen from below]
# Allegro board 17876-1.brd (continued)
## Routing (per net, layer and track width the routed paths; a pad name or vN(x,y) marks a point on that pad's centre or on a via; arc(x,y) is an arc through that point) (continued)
USB2_USB20_P3: length 127
  L4 w0.114: v1(134.54,80.39) 134.26,80.39 134.1,80.56 134.1,81.7 134.99,82.59 134.99,83.33 135.8,84.14 135.8,89.35 133.21,91.95 133.21,93.51 130.42,96.31 128.94,96.31 128.81,96.44 117.17,96.44 117.07,96.53 109.25,96.53 109.1,96.69 106.69,96.69 105.83,95.82 105.83,95.19 104.94,94.3 101.99,94.3 99.61,96.69 96.79,96.69 96.46,96.36 86.64,96.36 85.69,97.31 78.16,97.31 73.55,92.7 72.55,92.7 69.51,89.65 69.51,85.36 68.86,84.71 68.86,83.79 68.47,83.4 68.47,77.99 67.77,77.29 67.77,75.5 63.88,71.62 63.88,68.25 65.39,66.74 65.39,60.29 65.02,59.91 65.02,59.39 v1(65.33,59.08)
  BOTTOM w0.089: EL6603.3 133.04,78.84 133.21,78.68 133.63,78.68 133.76,78.81 133.76,79.74 134.11,80.09 134.24,80.09 v1(134.54,80.39) ; v1(65.33,59.08) 65.35,59.08 65.79,59.51 65.92,59.51 65.94,59.53 66.65,59.53 67.36,58.82 67.62,58.82 67.88,58.55 68.33,58.55 68.35,58.57 68.45,58.57 CPU1.AT1
USB3_PWR_EN#: length 88
  TOP w0.102: R2471.2 47.54,20.54 48.03,21.03 48.03,21.08 48.08,21.13 48.08,21.18 v1(48.13,21.23) ; v2(18.03,65.91) 18.06,65.88 18.06,65.87 18.36,65.57 v1(18.36,65.46)
  L3 w0.102: v1(18.36,65.46) 18.69,65.13 18.69,62.18 16.76,60.25 16.76,44.76 17.41,44.11 17.41,42.02 17.17,41.78 17.17,37.96 21.7,33.44 23.75,33.44 26.35,30.84 30.94,30.84 31.34,30.43 33,30.43 35.76,27.67 35.76,25.98 37.87,23.88 37.87,23.56 38.18,23.24 39.45,23.24 39.57,23.37 41.81,23.37 41.86,23.32 43.69,23.32 43.72,23.35 46.7,23.35 48.13,21.92 v1(48.13,21.23)
  BOTTOM w0.102: U2401.108 49.15,33.94 49,33.79 49,32.06 50.19,30.86 50.19,28.79 50.9,28.08 50.9,27.18 47.83,24.11 47.83,22.33 48.13,22.02 v1(48.13,21.23) ; v1(18.36,65.46) 18.82,65.46 19.06,65.22 U3601.4
USB3_USB20_CON_N4: length 6.2
  BOTTOM w0.089: 133.71,85.45 134.59,85.45 134.99,85.84 135.82,85.84 136.02,85.65 136.12,85.55 IOBD1.25 ; 133.71,85.45 133.07,85.45 132.51,84.89 132.51,84.69 132.29,84.47 EL6604.1 ; 133.71,85.45 AFTP6605.1
USB3_USB20_CON_P4: length 5.9
  BOTTOM w0.089: IOBD1.26 136.48,85.05 136.32,85.21 136.12,85.21 135.72,85.6 135.64,85.6 ; 135.64,85.6 AFTP6604.1 ; 135.64,85.6 135.09,85.6 134.69,85.21 133.17,85.21 132.75,84.79 132.75,84.69 132.94,84.49 EL6604.2
USB3_USB20_N4: length 119.5
  L4 w0.114: v1(65.96,59.11) 66.22,59.37 66.22,64.04 66.55,64.37 66.55,66.77 66.24,67.09 66.24,67.11 64.74,68.61 64.74,70.99 68.67,74.92 68.67,76.95 69.3,77.59 69.3,83.05 69.72,83.47 69.72,84.39 70.35,85.01 70.35,89.3 72.9,91.85 73.91,91.85 76.76,94.69 77.93,94.69 79.71,96.47 85.34,96.47 86.3,95.52 96.86,95.52 97.18,95.84 99.19,95.84 101.56,93.46 105.47,93.46 107.71,95.7 110.74,95.7 111.22,95.22 126.05,95.22 126.28,95.45 127.39,95.45 127.79,95.04 130.49,95.04 132.35,93.17 132.35,91.6 134.96,88.99 134.96,84.49 134.04,83.57 v1(134.04,83.49)
  BOTTOM w0.089: CPU1.AR2 68.38,58.23 68.18,58.32 67.82,58.32 67.56,58.57 67.31,58.57 66.92,58.97 66.27,58.97 v1(65.96,59.11) ; v1(134.04,83.49) 133.91,83.49 133.78,83.36 133.78,82.63 133.53,82.37 132.82,82.37 132.29,82.91 EL6604.4
USB3_USB20_P4: length 118.4
  L4 w0.114: v1(65.89,58.47) 66.04,58.47 66.44,58.87 66.44,63.95 66.77,64.28 66.77,66.86 66.46,67.18 66.46,67.2 64.96,68.7 64.96,70.9 68.88,74.83 68.88,76.86 69.52,77.5 69.52,82.96 69.94,83.38 69.94,84.3 70.56,84.92 70.56,89.21 72.99,91.63 74,91.63 76.85,94.48 78.02,94.48 79.79,96.26 85.26,96.26 86.21,95.3 96.95,95.3 97.27,95.62 99.1,95.62 101.47,93.25 105.56,93.25 107.8,95.48 110.66,95.48 111.13,95 126.14,95 126.37,95.23 127.3,95.23 127.7,94.83 130.4,94.83 132.14,93.08 132.14,91.51 134.75,88.9 134.75,84.58 134.19,84.03 134.03,84.03 v1(133.93,84.13)
  BOTTOM w0.089: v1(133.93,84.13) 133.93,84.02 133.54,83.63 133.54,82.73 133.43,82.62 133.06,82.62 132.84,82.83 132.84,82.96 EL6604.3 ; v1(65.89,58.47) 65.89,58.51 66.11,58.73 66.82,58.73 67.21,58.33 67.46,58.33 67.88,57.92 68,57.92 CPU1.AR1
USB_OC#0: length 129.7
  TOP w0.102: R1760.2 65.57,51.52 65.83,51.26 v2(66.81,51.26) v1(67.61,51.26)
  L3 w0.102: v1(136.32,80.85) 135.74,81.43 135.74,89.87 132.97,92.64 132.97,93.48 132,94.44 132,94.95 132.23,95.18 132.23,96.03 131.36,96.91 131.29,96.97 131.29,97.05 131.06,97.28 131.06,97.62 130.07,98.6 125.69,98.6 124.75,97.66 118.77,97.66 116.98,99.45 114.26,99.45 112.04,97.23 96.95,97.23 94.33,94.62 88.51,94.62 80.33,86.44 79.73,86.44 79.33,86.84 78.97,86.84 78.44,86.31 78.44,83.05 75.99,80.6 73.41,80.6 72.44,79.64 72.44,79.63 72.29,79.48 72.29,77.88 72.31,77.85 72.31,77.29 71.75,76.74 71.73,76.74 71.5,76.51 71.12,76.51 71.04,76.43 71.03,76.43 70.64,76.05 70.64,73.11 71.59,72.16 71.59,68.21 67.74,64.36 67.74,64.02 68.28,63.48 v1(69.77,63.48)
  L4 w0.102: v1(67.61,51.26) 67.64,51.28 67.8,51.28 68,51.48 68,55.67 68.4,56.07 68.4,60.68 69.77,62.05 v1(69.77,63.48)
  BOTTOM w0.102: CPU1.AB2 68.89,50.87 68.59,51.17 68.32,51.17 68.26,51.12 67.76,51.12 v1(67.61,51.26) ; v1(136.32,80.85) 136.45,80.85 136.65,81.05 IOBD1.34
USB_OC#1: length 88.3
  TOP w0.102: R1707.2 63.65,59.59 v2(63.81,59.43) 64.08,59.16 v1(64.08,58.9) ; v1(9.02,64.97) 9.02,65.79 12.42,69.19 14.94,69.19 16.97,71.22 17.17,71.22 18.55,72.61 18.55,72.81 19.23,73.48 20.45,73.48 v1(20.68,73.26)
  L3 w0.102: v1(67.59,54.81) 65.96,54.81 64.08,56.69 v1(64.08,58.9) 64.08,59.16 63.65,59.59 61.06,59.59 59.77,60.89 59.77,64.82 58.62,65.97 57.92,65.97 54.95,68.94 51.05,68.94 49.96,70.03 34.48,70.03 33.31,68.86 v1(32.94,68.86)
  L4 w0.102: v1(20.68,73.26) 20.68,73.03 20.37,72.72 20.37,72.29 20.62,72.04 21.58,72.04 23.03,70.59 25.08,70.59 26.79,68.89 30.07,68.89 30.25,69.06 32.72,69.06 32.92,68.86 v1(32.94,68.86)
  BOTTOM w0.102: v1(9.02,64.97) 9.86,64.14 13.67,64.14 14.71,63.1 15.16,63.1 15.98,63.91 15.98,63.93 16.52,64.48 U3601.3 ; v1(67.59,54.81) 67.61,54.79 67.61,54.71 67.79,54.54 67.79,54.35 67.97,54.17 CPU1.AH1
USB_SS_ZVDD_095: length 8.3
  TOP w0.254: v1(71.3,48.64) 71.3,49.03 71.88,49.61 71.88,50.89 72.35,51.36 73.58,51.36 74,51.78 74,52.89 v2(73.97,52.92) 73.86,52.92 R1610.1
  BOTTOM w0.254: v1(71.3,48.64) 71,48.94 CPU1.W5
USB_SS_ZVSS: length 2.3
  TOP w0.254: v1(70.56,48.66) 70.56,48.43 v2(70.82,48.16) 71.01,47.98 R1609.1
  BOTTOM w0.254: CPU1.W4 70.2,49.01 v1(70.56,48.66)
USB_ZVSS: length 2.4
  TOP w0.254: v1(71.25,56.36) 71.25,56.71 71.08,56.88 71.08,56.89 v2(71.07,56.9) 71.06,56.9 70.91,57.05 R1603.1
  BOTTOM w0.254: CPU1.AN7 71.28,56.4 71.28,56.4 v1(71.25,56.36)
VBKUP: length 4.6
  BOTTOM w0.203: v2(51.82,36.76) 51.69,36.76 51.36,36.43 51.36,35.82 51.55,35.62 U2401.114
  BOTTOM w0.508: v2(51.82,36.76) 52.7,37.64 C2402.1 53.04,37.8 R2425.1
VCORE_PWRGD: length 54.5
  TOP w0.254: v1(38.2,31.9) 38.2,32.41 37.58,33.03 v2(37.19,33.03) 36.7,33.03 34.26,35.46 34.26,39.26 35.47,40.47 35.47,46.84 PG4608.2 36.59,47.95 36.59,49.93 35.05,51.46 35.05,54.79 36.08,55.82 36.08,56.61 35.4,57.29 32.91,57.29 PG4602.2
  L3 w0.254: v1(38.2,31.9) 38.2,31.94 38.63,32.36 39.85,32.36 40.23,31.98 43.56,31.98 44.37,31.17 46.02,31.17 46.48,30.71 49.66,30.71 50.08,30.29 51.08,30.29 51.27,30.1 56.28,30.1 v1(57.11,29.27)
  BOTTOM w0.203: U2401.10 57.83,29.75 57.63,29.56 57.63,29.54 57.43,29.33 57.2,29.33 57.13,29.27 v1(57.11,29.27)
VD1_EN#: length 2.8
  TOP w0.254: v1(42.18,21.14) 42.12,21.14 42.04,21.06 42.01,21.06 v2(41.68,20.73)
  BOTTOM w0.203: U2401.66 42.54,21.35
  BOTTOM w0.254: R2468.1 42.16,21.11 v1(42.18,21.14) 42.32,21.14 42.54,21.35
VD_IN1: length 168.5
  TOP w0.102: v1(41.05,33.78) 41.05,33.02 C2613.1 40.49,33.48 R2608.2 40.31,33.02 41.01,32.32 42.95,32.32 42.98,32.3 44.97,32.3 45.42,31.85 C2612.1 45.77,31.4 48.45,31.4 48.71,31.14 48.71,27.65 48.7,27.64 48.7,26.91 49,26.62 49,25.68 49,25.28 48.81,25.09 48.81,23.35 49.17,22.99 49.17,22.97 49.22,22.93 49.22,22.71 49.23,22.7 49.23,21.93 49.43,21.73 49.43,19.81 49.58,19.66 v2(49.58,19.29) 49.58,18.34 49.1,17.86 48.55,17.86 47.89,17.2 47.89,16.28 49.45,14.72 50.16,14.72 50.56,14.32 50.56,13.29 51.63,12.22 53.16,12.22 v1(53.71,11.68)
  L3 w0.127: v1(41.05,33.78) 41.64,34.38 43.12,34.38 43.13,34.39 45.19,34.39 46.1,33.48 v1(46.52,33.48) ; v1(104.81,11.8) 104.37,11.36 103.84,11.36 103.68,11.51 78.64,11.51 77.67,12.47 57.54,12.47 56.48,11.41 53.97,11.41 v1(53.71,11.68)
  BOTTOM w0.102: v1(104.81,11.8) 105.44,12.43 105.44,12.85 105.67,13.07 105.67,13.77 105.69,13.79 105.69,14.52 103.24,16.97 102.11,16.97 100.72,18.36 100.72,69.28 97.5,72.49 R2612.1 ; v1(46.52,33.48) 46.84,33.48 47.55,34.19 U2401.104 ; R2614.2 40.89,33.63 v1(41.05,33.78) 41.05,33.33 41.42,32.95 U2401.95
VD_IN1_C: length 154.6
  TOP w0.102: v1(54.62,11.85) 53.88,12.59 51.78,12.59 50.99,13.38 50.99,14.51 50.31,15.19 v2(49.95,15.19) 49.5,15.19 48.26,16.43 48.26,17.05 48.7,17.49 49.25,17.49 49.95,18.19 49.95,19.83 49.8,19.98 49.8,21.9 49.7,22 49.7,23 49.18,23.52 49.18,24.94 49.37,25.13 49.37,25.83 49.36,25.83 49.36,26.77 49.07,27.06 49.07,27.51 49.08,27.52 49.08,31.29 48.6,31.77 46.31,31.77 C2612.2 43.13,32.67 42.77,33.02 R2613.1 41.96,33.02 C2613.2
  L3 w0.127: v1(54.62,11.85) 54.79,11.85 54.8,11.86 56.38,11.86 57.43,12.92 71.95,12.92 71.98,12.88 74.42,12.88 74.46,12.92 77.79,12.92 78.79,11.91 102.84,11.91 103.19,12.26 104.25,12.26 104.26,12.24 105.13,12.24 v1(105.54,11.84)
  BOTTOM w0.102: R2612.2 96.7,73.81 101.18,69.33 101.18,18.41 102.2,17.39 103.34,17.39 106.06,14.67 106.06,13.91 106.07,13.9 106.07,13.65 106.03,13.61 106.03,13.25 106.07,13.22 106.07,12.95 105.81,12.7 105.81,12.11 v1(105.54,11.84)
VD_OUT1#: length 4.2
  BOTTOM w0.203: U2401.110 49.95,36.09 R2602.2
  BOTTOM w0.254: R2602.2 R2603.2 49.96,37.09 v2(49.96,37.9) 50.75,37.9 R2615.2
VOL_DOWN#: length 188.9
  TOP w0.102: v1(49.42,11.31) 49.11,11 48.45,11 48.2,11.25 48.2,11.61 48.23,11.64 48.23,11.8 v2(46.83,13.21) 47.28,13.66 47.28,14.37 46.15,15.5 46.15,16.99 45.13,18.01 RN2403.3 45.13,18.64 46.35,19.86 46.35,20.82 46.34,20.83 46.34,21.04 v1(46.14,21.24)
  L3 w0.102: v1(49.42,11.31) 50.17,11.31 50.91,10.57 56.85,10.57 57.9,11.62 77.3,11.62 78.41,10.52 108.16,10.52 108.76,11.12 v1(108.76,11.39)
  BOTTOM w0.102: v1(46.14,21.24) 46.04,21.24 45.72,21.57 45.72,22.96 46.56,23.8 46.56,23.83 48.01,25.27 48.01,26.11 47.12,27 44.59,27 44.14,26.55 U2401.79 ; IOBD1.19 135.94,88.55 135.61,88.88 EC6603.1 134.72,89.46 127.38,89.46 127.1,89.74 122.94,89.74 122.73,89.54 121.81,89.54 117.81,85.54 117.81,17.42 116.98,16.6 116.17,16.6 116.17,16.6 114,16.6 113.85,16.45 111.29,16.45 109.73,14.89 109.73,12.73 108.76,11.76 v1(108.76,11.39)
VOL_UP#: length 186.5
  TOP w0.102: v1(45.03,25.94) 45.38,25.59 45.38,25.26 46.1,24.54 46.1,23.45 45.87,23.22 45.87,21.74 45.69,21.56 45.69,20.97 45.49,20.77 45.49,19.43 44.61,18.55 44.61,18.53 44.48,18.41 RN2403.4 44.48,17.93 44.12,17.58 44.12,16.73 44.14,16.71 44.14,16.11 v2(44.76,15.5) 44.5,15.25 44.5,14.4 46.27,12.63 46.72,12.63 47.34,12.01 v1(47.34,11.58)
  L3 w0.102: v1(47.34,11.58) 47.36,11.56 47.36,11.48 47.83,11.01 48.44,11.01 48.45,11 48.71,11 49.59,10.11 57.05,10.11 58.1,11.17 77.11,11.17 78.21,10.06 108.41,10.06 v1(109.19,10.85)
  BOTTOM w0.102: v1(45.03,25.94) 45.03,25.6 44.93,25.5 44.2,25.5 43.95,25.75 U2401.77 ; v1(109.19,10.85) 109.96,11.62 109.96,14.8 111.38,16.22 113.95,16.22 114.09,16.37 116.26,16.37 116.27,16.37 117.07,16.37 118.03,17.33 118.03,17.52 118.03,85.44 121.9,89.31 123.44,89.31 123.65,89.51 127,89.51 127.28,89.23 132.87,89.23 133.65,88.44 134.95,88.44 135.28,88.11 EC6602.1 135.32,88.05 IOBD1.20
VPP_2D5V: length 27.3
  BOTTOM w0.279: DIMM1.259 123.03,86.62 123.29,86.36 123.05,86.13 DIMM1.257
  BOTTOM w0.305: PR5313.2 126.47,93.52 127.05,94.11 127.05,99.77 126.08,100.74 121.2,100.74 v2(120.43,99.97) 120.41,99.97 119.65,100.74 115.17,100.74 114,99.56 114,98.45 114.43,98.02 PR5312.1 ; 123.29,86.36 v1(123.34,86.36)
  vias: v3(117.02,87.86)
VPP_IN:
  vias: v2(117.98,93.54)
VPP_PWR:
  vias: v2(126.57,97.59)
VTT_CT_0.95V: length 4.8
  TOP w0.305: C4006.1 v2(77.52,79.33)
  TOP w0.508: v1(79.27,77.62) 78.59,78.3 78.59,78.59 78.41,78.77 C4006.1
  BOTTOM w0.203: v1(79.27,77.62) 79.27,77.83 78.77,78.34 78.77,78.79 78.82,78.85 U4002.12
VTT_CT_1.8V: length 2.3
  TOP w0.305: v2(80.4,78.27) 80.18,78.27 v1(79.9,78.55)
  TOP w0.508: C4005.1 79.68,79.02 79.88,78.82 79.88,78.56 v1(79.9,78.55)
  BOTTOM w0.203: v1(79.9,78.55) 79.78,78.67 79.78,78.74 79.68,78.84 79.68,78.89 79.62,78.95 U4002.10
WAKE_L: length 11.4
  TOP w0.102: R1759.2 v2(65.41,52.3) 65.84,52.3 v1(66.4,51.74)
  L4 w0.102: v1(66.4,51.74) 66.68,51.45 66.68,51.43 66.67,51.41 66.67,50.73 66.95,50.45 v1(66.95,50.42)
  BOTTOM w0.102: v1(66.95,50.42) 67.39,49.99 68.24,49.99 68.32,50.07 68.58,50.07 68.63,50.02 68.97,50.02 69.02,50.07 69.28,50.07 69.33,50.02 69.63,50.02 69.8,50.19 69.8,50.53 70.55,51.27 70.55,52.57 70.85,52.87 71.45,52.87 CPU1.AE7
WIFI_RF_EN: length 192.9
  TOP w0.102: v1(162.87,79.33) 162.87,79.39 AFTP6104.1 161.5,78.9 160.01,78.9 155.73,74.63 146.94,74.63 142.49,70.18 142.49,69.67 140.86,68.04 140.46,68.04 139.03,66.61 132.4,66.61 v1(131.57,67.44) ; v1(163.77,83.44) 163.77,83.45 163.77,83.35 R6113.1
  L3 w0.102: v1(131.57,67.44) 131.37,67.44 130.86,66.93 130.86,61.05 130.71,60.89 130.71,19.11 125.11,13.51 110.09,13.51 109.79,13.21 108.8,13.21 108.13,13.88 108.13,14.18 107.91,14.39 107.91,14.43 106.98,15.36 105.95,15.36 105.61,15.7 102.22,15.7 102.11,15.58 91.86,15.58 90.4,17.04 84.35,17.04 84.3,16.98 80.38,16.98 79.96,17.4 79.96,17.61 79.04,18.53 78.5,18.53 77.04,19.99 74.64,19.99 74.32,20.3 71.16,20.3 70.97,20.1 70.1,20.1 69.57,19.57 66.81,19.57 66.51,19.27 63.15,19.27 62.65,19.76 61.25,19.76 60.73,19.24 58.55,19.24 58.23,19.56 55.56,19.56 54.41,20.71 54.41,21.47 54.15,21.72 53.78,21.72 52.69,22.8 52.69,23.54 50.07,26.16 48.82,26.16 48.1,26.88 43.25,26.88 43.21,26.93 v1(42.32,27.81)
  BOTTOM w0.102: v1(162.87,79.33) 162.99,79.45 163.73,79.45 164.04,79.77 164.04,83.17 v1(163.77,83.44) ; U2401.82 42.45,27.75 42.39,27.81 v1(42.32,27.81)
WIFI_RF_EN_R: length 4.2
  TOP w0.102: v1(162.33,80.43) 162.33,81.24 162.97,81.88 R6112.2 162.99,81.87 R6113.2
  BOTTOM w0.102: WLAN1.56 161.86,81 162.33,80.53 v1(162.33,80.43)
WLAN_CLK_CPU_N3: length 160.9
  L4 w0.127: v1(66.9,43.66) 67.05,43.51 67.23,43.51 67.5,43.78 67.5,44.49 66.52,45.47 66.52,48.8 65.72,49.6 65.72,54.02 67.88,56.18 67.88,57.53 67.96,57.6 67.96,58.12 67.88,58.2 67.88,61.11 68.47,61.69 68.47,62.53 68.67,62.74 68.67,65.55 68.74,65.62 70.79,67.67 71.11,68.17 71.6,68.89 71.6,71.05 70.65,72.01 70.65,73.93 70.59,74 70.59,75.99 70.92,76.32 70.92,80.93 71.51,81.53 71.51,83.94 72.49,84.91 75.82,84.91 77.44,86.54 77.44,89.87 81.1,93.52 99.25,93.52 100.91,91.87 101.12,91.87 101.14,91.85 106.38,91.85 107.82,93.3 128.67,93.3 133.22,88.74 133.22,79.99 133.88,79.33 133.88,75.5 133.2,74.81 133.2,74.5 132.79,74.09 v1(132.79,74.04)
  BOTTOM w0.089: v1(132.79,74.04) 132.79,74.17 132.89,74.27 133.06,74.27 133.77,73.56 139.95,73.56 140.17,73.33 142.97,73.33 147.45,77.81 147.45,78.13 149.54,80.22 150.37,80.22 150.79,80.65 150.79,81.65 151.07,81.93 ; v2(151.18,81.82) 151.07,81.93 ; 151.07,81.93 152.02,82.88 152.48,82.88 152.62,82.75 WLAN1.49 ; R1608.1 64.41,44.31 64.32,44.22 64.32,43.94 64.95,43.31 66.41,43.31 66.5,43.4 66.5,43.59 66.57,43.66 v1(66.9,43.66)
WLAN_CLK_CPU_N3_R: length 5.4
  BOTTOM w0.089: v2(65.72,45.52) 65.72,45.7 ; 65.72,45.7 66.36,45.7 67.94,44.11 67.94,43.99 68.1,43.84 CPU1.J1 ; 65.72,45.7 64.52,45.7 64.36,45.54 64.36,45.37 R1608.2
WLAN_CLK_CPU_P3: length 159.9
  L4 w0.127: v1(132.74,74.68) 133.65,75.59 133.65,79.23 132.99,79.89 132.99,88.65 128.57,93.07 107.92,93.07 106.47,91.62 101.05,91.62 101.03,91.64 100.82,91.64 99.16,93.3 81.2,93.3 77.67,89.77 77.67,86.44 75.91,84.69 72.59,84.69 71.74,83.84 71.74,81.43 71.15,80.84 71.15,76.23 70.82,75.9 70.82,74.09 70.88,74.03 70.88,72.1 71.83,71.15 71.83,68.81 71.3,68.04 71.24,67.95 70.97,67.53 68.9,65.46 68.9,62.64 68.69,62.44 68.69,61.6 68.11,61.02 68.11,58.29 68.19,58.22 68.19,57.51 68.11,57.43 68.11,56.09 65.95,53.93 65.95,49.7 66.75,48.9 66.75,45.57 67.73,44.59 67.73,43.69 67.07,43.03 v1(66.95,43.03)
  BOTTOM w0.089: R1607.1 64.11,43.97 64.11,43.86 64.86,43.11 66.88,43.11 v1(66.95,43.03) ; WLAN1.47 152.56,83.25 152.4,83.09 151.94,83.09 150.59,81.74 150.59,80.73 150.28,80.42 149.45,80.42 149.2,80.17 ; v1(132.74,74.68) 132.94,74.68 133.86,73.76 140.03,73.76 140.26,73.53 142.89,73.53 147.24,77.89 147.24,78.22 149.2,80.17 ; 149.2,80.17 v2(149.07,80.29)
WLAN_CLK_CPU_P3_R: length 6.5
  BOTTOM w0.089: 64.55,45.9 66.45,45.9 68.15,44.2 68.15,44.1 68.52,43.72 CPU1.J2 ; 64.55,45.9 64.44,45.9 63.78,45.24 R1607.2 ; 64.55,45.9 v2(64.55,46.1)
WLAN_CLKREQ_CPU_N3: length 120.5
  L3 w0.14: v1(84.38,56.85) 84.38,56.97 83.89,57.47 83.89,57.85 84.12,58.09 84.12,58.12 85.62,59.62 85.65,59.62 85.79,59.76 85.79,60.56 84.47,61.89 84.47,67.02 85.11,67.67 85.11,70.59 86.89,72.37 v1(86.89,73.79) 86.89,74.43 91.58,79.12 94.47,79.12 95.56,80.21 97.23,80.21 98.09,81.08 98.09,82.74 99.79,84.44 100.18,84.44 100.6,84.87 100.6,85.25 101.81,86.46 102.1,86.46 102.89,87.24 103.23,87.24 104.24,86.23 105.64,86.23 105.86,86.46 116.4,86.46 117.77,87.83 124.61,87.83 125.58,86.87 126.72,86.87 127.58,87.73 128.07,87.73 129.11,86.69 129.11,86.62 130.25,85.47 130.25,77.4 130.02,77.17 130.02,72.32 v1(131.62,70.72)
  L4 w0.14: v1(139.34,70.18) 139.04,70.48 138.22,70.48 137,71.71 136.02,71.71 135.08,70.77 131.71,70.77 131.66,70.72 v1(131.62,70.72)
  BOTTOM w0.089: R1715.2 v1(86.89,73.79) ; WLAN1.53 152.62,81.75 151.41,80.54 151.41,78.9 AFTP6102.1 151.28,78.64 150.16,77.52 148.01,77.52 143.15,72.67 143.15,70.39 142.03,69.27 140.26,69.27 v1(139.34,70.18) ; CPU1.AP31 84.63,56.85 v1(84.38,56.85)
WLAN_PCIE_RX_N3: length 144.6
  TOP w0.089: v2(132.21,75.57) v1(132.72,75.34)
  L4 w0.127: v1(132.72,75.34) 132.4,75.66 131.85,75.66 131.19,76.32 131.19,85.1 130.99,85.31 130.99,87.7 127.35,91.33 120.7,91.33 120.37,91 119.72,91 119.38,91.33 108.66,91.33 107.22,89.89 105.33,89.89 104.75,89.31 100,89.31 98.37,90.94 97.63,90.94 97.07,91.51 85.2,91.51 80.73,87.04 80.73,86.39 78.83,84.48 78.83,84 77.73,82.91 73.89,82.91 73.51,82.53 73.51,80.76 73.14,80.39 73.14,76.94 72.97,76.77 72.97,72.46 73.56,71.87 73.56,67.86 73.06,67.36 73.06,67.17 72.06,66.17 72.06,64.11 71.75,63.81 71.75,63.25 72.11,62.89 72.21,62.89 73.98,61.13 73.98,55.21 72.26,53.48 69.71,53.48 69.24,53.01 69.24,48.61 70.62,47.22 70.8,47.22 70.86,47.21 70.88,47.19 71.17,46.85 v1(71.17,46.45)
  BOTTOM w0.089: CPU1.N5 71,46.28 v1(71.17,46.45) ; v1(132.72,75.34) 132.89,75.52 133.04,75.52 134.18,74.37 138.95,74.37 140.35,75.77 142.78,75.77 145.72,78.72 145.72,82.24 146.52,83.03 148.06,83.03 R6104.2
WLAN_PCIE_RX_P3: length 144.2
  L4 w0.127: v1(132.72,75.99) 132.61,75.88 131.95,75.88 131.42,76.41 131.42,85.2 131.22,85.4 131.22,87.79 127.45,91.56 120.61,91.56 120.28,91.23 119.81,91.23 119.48,91.56 108.57,91.56 107.13,90.12 105.24,90.12 104.65,89.54 100.09,89.54 98.47,91.17 97.73,91.17 97.16,91.73 85.11,91.73 80.51,87.13 80.51,86.48 78.6,84.58 78.6,84.1 77.64,83.14 73.79,83.14 73.28,82.62 73.28,80.85 72.91,80.48 72.91,77.03 72.74,76.86 72.74,72.36 73.33,71.77 73.33,67.95 72.83,67.45 72.83,67.27 71.83,66.26 71.83,64.2 71.53,63.9 71.53,63.15 72.02,62.66 72.12,62.66 73.75,61.03 73.75,55.3 72.16,53.71 69.62,53.71 69.01,53.1 69.01,48.51 70.48,47.04 v1(70.48,46.5)
  BOTTOM w0.089: 133.94,74.9 133.12,75.72 132.99,75.72 v1(132.72,75.99) ; 133.94,74.9 134.26,74.58 138.86,74.58 140.26,75.98 142.69,75.98 145.52,78.8 145.52,82.32 146.43,83.24 148.08,83.24 R6101.2 ; 133.94,74.9 v2(134.06,75.03) ; v1(70.48,46.5) 70.2,46.22 CPU1.N4
WLAN_PCIE_TX_CON_N3: length 158.6
  L4 w0.127: v1(132.64,76.76) 132.54,76.86 132.26,76.86 132.07,77.05 132.07,80.96 132.12,81.02 132.12,88.29 128.2,92.2 108.31,92.2 106.86,90.76 104.95,90.76 104.38,90.18 100.4,90.18 99.86,90.72 99.86,91.37 99.27,91.96 98.86,92.37 83.75,92.37 78.56,87.18 78.56,86.08 76.3,83.82 73.2,83.82 72.61,83.22 72.61,81.08 72.28,80.75 72.28,77.29 72.1,77.12 72.1,72.1 72.7,71.51 72.7,68.21 72.16,67.68 72.16,67.5 70.06,65.4 70.06,64.15 70.42,63.79 70.42,63.19 70.32,63.09 70.32,61.97 68.85,60.5 68.85,55.89 68.5,55.54 68.5,51.15 68.29,50.94 68.29,47.38 68.73,46.94 68.73,41.5 67.85,40.62 67.61,40.62 66.97,39.98 v1(66.95,39.98)
  BOTTOM w0.089: 150.62,85.11 150.62,85.39 151,85.77 152.57,85.77 152.59,85.75 WLAN1.37 ; 150.62,85.11 v2(150.81,85.11) ; 150.62,85.11 150.62,84.83 150.02,84.23 146.58,84.23 144.85,82.5 144.85,78.99 142.57,76.71 140.13,76.71 138.61,75.19 134.57,75.19 133.71,76.05 133.71,76.61 133.35,76.96 132.84,76.96 v1(132.64,76.76) ; C304.2 64.54,39.19 65.51,40.16 66.78,40.16 v1(66.95,39.98)
WLAN_PCIE_TX_CON_P3: length 158.7
  L4 w0.127: v1(132.69,77.4) 132.3,77.79 132.3,80.87 132.35,80.92 132.35,88.38 128.3,92.43 108.21,92.43 106.76,90.98 104.86,90.98 104.29,90.41 100.5,90.41 100.09,90.82 100.09,91.47 99.5,92.05 98.96,92.6 83.65,92.6 78.33,87.28 78.33,86.18 76.21,84.05 73.11,84.05 72.38,83.32 72.38,81.17 72.05,80.84 72.05,77.39 71.88,77.22 71.88,72.01 72.47,71.41 72.47,68.31 71.94,67.78 71.94,67.6 69.83,65.49 69.83,64.05 70.19,63.69 70.19,63.29 70.09,63.18 70.09,62.07 68.62,60.59 68.62,55.98 68.27,55.64 68.27,51.25 68.06,51.04 68.06,47.29 68.5,46.84 68.5,41.59 67.76,40.85 67.24,40.85 v1(67.01,40.62)
  BOTTOM w0.089: 148.41,84.43 v2(148.41,84.58) ; 148.41,84.43 146.49,84.43 144.64,82.58 144.64,79.07 142.49,76.91 140.05,76.91 138.52,75.39 134.65,75.39 133.91,76.13 133.91,76.69 133.43,77.17 132.92,77.17 v1(132.69,77.4) ; 148.41,84.43 149.94,84.43 150.42,84.91 150.42,85.47 150.92,85.97 152.29,85.97 152.57,86.25 WLAN1.35 ; v1(67.01,40.62) 66.75,40.36 65.43,40.36 64.23,39.16 64.1,39.16 C303.2
WLAN_PCIE_TX_N3: length 15.7
  BOTTOM w0.089: 67.58,35.26 67.08,35.26 65.35,36.98 65.01,36.98 64.41,37.58 64.41,37.8 C304.1 ; 67.58,35.26 70.88,35.26 70.97,35.35 70.97,35.78 70.88,35.87 68.43,35.87 68.15,36.15 68.15,37.49 69.05,38.39 69.05,39.11 69.31,39.37 69.31,39.37 69.5,39.56 CPU1.B3 ; 67.58,35.26 v2(67.59,35.46)
WLAN_PCIE_TX_P3: length 15.7
  BOTTOM w0.089: 64.5,37.21 64.92,36.78 65.27,36.78 66.99,35.05 70.96,35.05 71.17,35.26 71.17,35.86 70.96,36.07 68.52,36.07 68.35,36.23 68.35,37.41 69.45,38.51 CPU1.A3 ; 64.5,37.21 v2(64.36,37.09) ; 64.5,37.21 C303.1
WLANTX_N3: length 5.1
  BOTTOM w0.089: v2(150.18,83.12) 150.04,83.26 ; 150.04,83.26 150.19,83.42 151.24,83.42 152.27,84.45 152.41,84.45 152.61,84.25 WLAN1.43 ; 150.04,83.26 149.76,82.98 149.48,82.98 149.22,82.73
WLANTX_P3: length 5.1
  BOTTOM w0.089: 151.31,83.77 151.16,83.62 150.11,83.62 149.67,83.19 149.56,83.19 149.22,83.52 ; 151.31,83.77 v2(151.17,83.91) ; 151.31,83.77 152.19,84.65 152.39,84.65 152.49,84.75 WLAN1.41
X25M_48M_OSC: length 1.3
  TOP w0.089: TP1604.1 82.7,57.91 v1(83.16,58.37)
  BOTTOM w0.089: v1(83.16,58.37) 83.13,58.37 83.11,58.4 83.02,58.4 CPU1.AU27
XI: length 7.8
  TOP w0.089: U6304.F1 51.46,89.91 v2(50.11,89.91) 48.72,89.91 47.29,91.34 R6353.1 47.27,91.44 C6344.1 46.33,92.25 45.96,92.62 45.31,92.62 45.15,92.46 X6301.3
XO: length 5.9
  TOP w0.089: R6365.1 R6353.2 v2(48.31,91.29) 49.07,90.53 50.35,90.53 50.55,90.32 U6304.E1
XO_R: length 5.5
  TOP w0.089: R6365.2 46.56,93.27 C6343.1 46.23,93.27 45.81,93.69 45.81,94.27 45.19,94.9 v2(44.76,94.9) 44.31,94.9 44.11,94.7 X6301.1
XTL_32K_X1_CPU: length 8.7
  BOTTOM w0.089: CPU1.BA2 68.7,62.08 68.55,62.23 68.55,62.23 68.53,62.26 68.53,62.28 68.17,62.64 66.34,62.64 65.16,63.82 65.16,64.17 64.44,64.9 R1745.1 64.44,65.66 C1703.1 64.12,65.98 X1701.2
XTL_32K_X2_CPU: length 8.1
  BOTTOM w0.089: X1701.1 64.2,63.52 R1745.2 64.62,63.58 C1704.1 65.76,62.94 66.27,62.43 68.1,62.43 68.33,62.21 68.33,62.18 68.35,62.16 68.35,61.37 CPU1.AY2

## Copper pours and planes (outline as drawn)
1V_CPU_CORE on TOP: 79.79,42.69 79.12,43.35 78.27,43.35 78.22,43.4 78.22,44.16 78.32,44.25 78.93,44.25 78.93,44.26 79.58,44.91 79.58,45.25 79.69,45.36 79.76,45.36 79.76,45.37 79.78,45.4 80.21,45.4 80.33,45.52 80.33,47.74 80.62,48.04 80.62,49.21 80.87,49.45 81.29,49.45 81.53,49.69 81.53,49.99 82.02,50.47 83.06,50.47 84.12,51.54 85.04,51.54 85.4,51.18 85.4,48.75 84.23,47.58 83.95,47.58 83.79,47.42 83.79,46.43 83.93,46.29 84.32,46.29 84.4,46.2 84.4,44.86 84.48,44.78 84.48,44.5 84.37,44.39 84.04,44.39 83.87,44.55 79.99,44.55 79.62,44.18 79.62,43.74 80,43.36 80.25,43.36 80.42,43.19 80.42,42.83 80.28,42.69 ; 15 cut-outs
1V_CPU_CORE on BOTTOM: 51.94,39.45 51.18,40.21 51.18,44.38 50.77,44.78 49.3,44.78 47.29,46.79 47.29,50.27 47.4,50.37 49.86,50.37 51.23,49 56.29,49 56.57,48.72 56.57,46.76 57.53,45.8 57.53,44.91 57.91,44.53 57.91,44.15 57.78,44.02 57.15,44.02 57.02,43.89 57.02,43.38 56.9,43.26 56.52,43.26 56.39,43.13 56.39,39.85 55.98,39.45 ; 4 cut-outs
1V_CPU_CORE on BOTTOM: 80.65,47.55 80.19,48.01 80.19,48.72 80.57,49.1 81.44,49.1 81.56,49.22 81.56,49.71 81.19,50.08 81.19,50.76 81.44,51.01 82.73,51.01 83.16,50.57 84.52,50.57 84.66,50.43 84.66,49.96 84.28,49.58 82.35,49.58 82.2,49.44 82.2,49.1 82.26,49.05 84.48,49.05 84.56,48.97 84.56,47.91 84.25,47.6 82.76,47.6 82.3,48.07 81.64,48.07 81.11,47.55
1V_CPU_CORE on BOTTOM: 84.16,43.61 83.9,43.87 80.29,43.87 80.14,43.72 79.81,43.72 79.66,43.88 79.14,43.88 79.09,43.93 79.09,44.69 79.61,45.21 80.14,45.21 80.37,44.98 84.28,44.98 84.73,44.53 85,44.53 85.07,44.46 85.07,44.11 84.56,43.61
1V_CPU_CORE on BOTTOM: 80.69,45.62 80.19,46.13 79.73,46.13 79.55,45.95 79.22,45.95 79.05,46.12 79.05,46.86 79.21,47.02 79.45,47.02 79.45,46.59 79.63,46.41 80.11,46.41 80.24,46.53 80.24,46.91 80.34,47.02 84.31,47.02 84.59,46.74 84.59,45.99 84.23,45.62
1V_CPU_CORE on L2VCC: 86.02,42.44 86.38,42.08 86.99,42.08 87.26,41.81 87.26,39.88 85.53,38.16 85.53,32.29 84.5,31.26 75.9,31.26 73.74,33.42 71.45,33.42 70.28,34.58 63.57,34.58 62.71,35.44 57.44,35.44 53.73,39.15 52.49,39.15 52.13,39.5 52.13,39.78 51.12,40.8 51.12,48.21 51.74,48.83 57.08,48.83 57.11,48.87 64.11,41.87 73.05,41.87 73.53,41.39 75.59,41.39 76.54,42.34 76.54,43.69 77.51,44.65 77.51,45.19 77.6,45.28 77.98,45.28 78.45,45.74 78.45,46.43 79.41,47.4 79.41,50.83 79.67,51.09 84.45,51.09 85.31,50.24 85.31,45.54 86.02,44.83
1V_CPU_CORE on L3: 64.3,41.83 71.34,41.83 71.57,42.06 72.86,42.06 73.47,41.46 75.64,41.46 76.35,42.17 76.68,42.17 76.91,42.4 76.91,43.72 76.94,43.76 76.94,44.21 77.42,44.68 77.42,45.29 77.57,45.44 77.98,45.44 78.28,45.75 78.28,46.48 79.28,47.48 79.28,49.99 80.33,51.05 83.06,51.05 83.11,51 84.2,51 85.05,50.15 85.05,46.38 85.64,45.8 85.64,45.28 86.26,44.65 86.26,43.23 86.49,43 86.61,43 87.12,42.5 87.12,42.24 87.5,41.86 87.5,40.08 85.8,38.38 85.8,32.54 84.58,31.32 77.19,31.32 73.91,34.6 57.41,34.6 51.19,40.82 51.19,47.58 52.84,49.23 56.9,49.23
1V_CPU_CORE on L4: 79.71,50.95 84.48,50.95 84.99,50.45 84.99,44.78 84.98,44.77 85.17,44.58 85.17,42.15 84.8,41.78 84.8,40.15 84.43,39.78 84.43,39.04 83.79,38.41 83.79,37.95 83.31,37.47 80.09,37.47 79.35,36.73 74.75,36.73 74.54,36.95 74.54,38.22 75.49,39.17 76.07,39.17 77.5,40.59 77.5,43.13 76.99,43.64 76.99,44.27 77.44,44.73 77.44,45.29 77.62,45.47 78.05,45.47 78.28,45.7 78.28,46.51 79.27,47.5 79.27,49.53 79.3,49.56 79.3,50.55
1V_S0 on TOP: 39.07,91.39 38.84,91.62 38.84,93.37 39.04,93.58 42.7,93.58 43.13,93.14 43.13,91.95 42.57,91.39 ; 6 cut-outs
1V_S0 on BOTTOM: 42.42,89.05 42.16,89.31 42.16,89.99 42.06,90.1 40.92,90.1 40.69,89.87 38.56,89.87 38.46,89.97 38.46,93.35 38.86,93.75 42.21,93.75 42.7,93.27 42.7,91.77 43.66,90.81 43.66,89.41 43.31,89.05 ; 9 cut-outs
1V_S0 on L3: 39.17,92.69 39.17,91.01 39.98,90.2 40.59,90.2 40.97,89.82 40.97,89.18 41.71,88.44 48.34,88.44 48.72,88.83 54.1,88.83 55.4,90.12 55.4,92.58 54.51,93.47 52.25,93.47 51.13,92.36 48.79,92.36 47.78,91.34 43.46,91.34 41.53,93.27 39.75,93.27
5V_HDMI on BOTTOM: 9.74,80.63 9.45,80.93 9.45,82.83 9.96,83.34 10.79,83.34 11.46,84 11.46,84.94 12.14,85.63 13.21,85.63 13.28,85.7 13.28,86.21 13.36,86.29 14.33,86.29 14.45,86.16 14.45,84.48 13.82,83.85 13.03,83.85 12.8,83.62 12.8,82.81 10.63,80.63 ; 2 cut-outs
5V_S0 on TOP: 137.96,70.67 137.62,71.01 137.62,74.07 137.74,74.2 141.58,74.2 142.04,73.74 142.04,71.98 142.02,71.98 140.71,70.67 ; 2 cut-outs
5V_S0 on BOTTOM: 37.69,23.29 36.8,24.18 36.8,25.38 37.08,25.66 37.08,26.27 37.11,26.29 38.13,26.29 38.18,26.34 39.27,26.34 39.34,26.27 39.34,24.31 38.33,23.29 ; 2 cut-outs
5V_S0 on BOTTOM: 150.07,22.17 150.06,22.18 148.75,22.18 148.75,22.18 144.7,22.18 144.23,22.65 144.23,26.94 144.32,27.03 147.8,27.03 148.34,26.49 148.34,25.88 148.49,25.73 148.75,25.73 148.76,25.74 150.01,25.74 150.3,25.45 150.3,22.41 ; 3 cut-outs
5V_S0 on L2VCC: 141.85,73.2 141.85,66.3 139.46,63.91 139.46,59.94 140.03,59.37 142.01,59.37 144.01,57.38 144.01,50.91 142.48,49.38 142.48,39.55 144.01,38.02 144.01,35.81 145.63,34.19 145.63,15.96 135.35,5.68 113.9,5.68 110.72,8.85 107.7,8.85 103.56,12.99 102.29,12.99 101.92,13.36 101.92,14.76 101.42,15.25 97.08,15.25 96.46,14.63 96.46,12.73 95.17,11.44 76.15,11.44 75.34,12.26 64.11,12.26 60.09,8.24 41.96,8.24 37.93,12.27 37.93,25.91 38.31,26.28 40.97,26.28 41.47,25.78 41.47,19.3 48.56,12.21 58.12,12.21 60.91,15 91.14,15 94.31,18.18 110.79,18.18 115.53,13.44 115.53,9.96 116.79,8.7 133.94,8.7 142.71,17.47 142.71,24.01 142.2,24.52 142.2,34.27 141.26,35.21 141.26,36.25 139.76,37.75 139.76,48.97 139.79,49 139.79,49.15 139.76,49.18 139.76,55.4 136.84,58.32 136.84,60.35 136.33,60.86 136.33,63.88 137.3,64.85 137.3,72.82 138.08,73.6 141.45,73.6
5V_S5 on TOP: 97.16,13.67 96.9,13.92 96.9,15.09 97.22,15.41 97.22,18.94 99.16,20.88 100.33,20.88 102.64,23.19 102.64,24.36 107.74,29.46 107.74,75.32 109.88,77.45 113.45,77.45 113.72,77.72 113.72,82.45 109.47,86.69 109.47,89.23 109.6,89.36 112.01,89.36 117.07,84.31 117.07,75.8 115.02,73.75 112.01,73.75 111.1,72.84 111.1,25.63 102.99,17.52 102.99,15.06 101.6,13.67
5V_S5 on TOP: 33.53,21.29 32.64,22.18 32.64,24.18 33.41,24.96 34.2,24.96 34.21,24.97 34.75,24.97 36.63,23.09 36.63,21.34 36.58,21.29
5V_S5 on BOTTOM: 136.12,75.82 136.02,75.92 136.02,78.51 136.25,78.74 137.79,78.74 137.87,78.67 137.87,75.87 137.82,75.82
5V_S5 on BOTTOM: 33.22,21.29 32.59,21.92 32.59,26.47 33.17,27.05 35.71,27.05 35.71,25.3 35.59,25.17 35.46,25.17 35.28,25 35.28,24.21 35.99,23.5 36.25,23.5 36.73,23.01 36.73,21.44 36.58,21.29 ; 1 cut-out
5V_S5 on BOTTOM: 17.58,62 17.48,62.1 17.48,63.78 17.63,63.93 19.41,63.93 19.53,63.81 19.53,62.99 19.63,62.89 20.24,62.89 20.27,62.87 20.27,62.33 20.22,62.28 19.71,62.28 19.43,62
5V_S5 on BOTTOM: 15.11,84.48 15.01,84.58 15.01,86.16 15.06,86.21 19.91,86.21 20.24,85.88 20.24,84.71 20.02,84.48
5V_S5 on L2VCC: 138.95,81.3 138.95,80.12 137.1,78.26 137.1,76.1 136.57,75.58 133.17,75.58 132.4,76.36 132.4,88.55 132.03,88.91 116.63,88.91 114.86,87.14 109.81,87.14 109.66,87.28 109.66,90.42 111.2,91.96 133.27,91.96 134.03,91.2 135.94,91.2 136.84,90.3 136.84,85.24 138.1,83.99 138.48,83.99 138.57,83.9 138.57,81.69
5V_S5 on L2VCC: 66.47,9.54 61.77,4.84 37.87,4.84 32.73,9.99 32.73,27.18 30.56,29.35 26.11,29.35 15.68,39.78 15.68,62.74 16.84,63.9 18.21,63.9 18.99,63.12 18.99,41.4 27.86,32.53 31.34,32.53 37.55,26.31 37.55,12.11 41.81,7.86 60.25,7.86 64.26,11.88 75.18,11.88 75.99,11.06 95.33,11.06 96.84,12.57 96.84,14.48 97.23,14.87 101.27,14.87 101.54,14.6 101.54,12.89 97.03,8.38 74.61,8.38 73.44,9.54
5V_USB30 on BOTTOM: 14.81,56.75 14.33,57.23 14.05,57.23 13.79,57.48 13.79,60.81 14.43,61.44 14.43,62.66 14.71,62.94 17.17,62.94 17.22,62.89 17.22,61.93 17.32,61.83 18.52,61.83 18.73,61.61 18.73,60.34 18.85,60.23 18.85,56.82 18.77,56.75 ; 4 cut-outs
12V_BT+ on BOTTOM: 120.14,3.86 119.13,4.88 119.13,14.66 119.72,15.25 120.76,15.25 121.23,14.78 121.74,14.78 121.86,14.9 121.86,15.42 121.89,15.44 122.48,15.44 122.56,15.37 122.56,14.84 122.72,14.68 126.15,14.68 126.21,14.75 126.21,15.99 126.29,16.07 126.99,16.07 127.05,16 127.05,15.15 127.24,14.96 128.17,14.96 128.35,14.78 128.35,13.62 129.11,12.85 129.11,5.36 128.88,5.13 128.17,5.13 126.9,3.86 ; 1 cut-out
19V_DCBATOUT_LCD on BOTTOM: 43.1,80.44 42.98,80.57 42.98,84.02 44.7,85.75 47.7,85.75 47.78,85.68 47.78,83.49 48.31,82.96 48.31,82.32 48.21,82.22 44.83,82.22 44.7,82.09 44.7,80.44 ; 2 cut-outs
+3V_1D8V_DVDD on TOP: 151.74,86.26 151.55,86.45 150.18,86.45 148.54,88.09 148.16,88.09 148.01,88.24 148.01,88.65 148.03,88.67 149.07,88.67 150.15,87.59 150.15,87.59 150.36,87.39 151.32,87.39 151.84,86.87 152.48,86.87 152.55,86.79 152.55,86.46 152.35,86.26
+3V_1D8V_DVDD on BOTTOM: 149.63,86.18 149.53,86.29 149.53,86.77 148.69,87.61 148.69,88.22 149.15,88.67 149.15,89.21 149.3,89.36 150.9,89.36 151.03,89.23 151.03,87.2 151.04,87.19 151.03,87.17 151.03,86.72 150.5,86.18 ; 3 cut-outs
+5V_AVDD on TOP: 143.79,92.43 143.23,92.99 143.23,93.75 142.27,94.72 141.35,94.72 140.94,95.12 140.94,97.64 141.02,97.72 141.73,97.72 141.86,97.59 141.86,95.56 141.91,95.51 142.54,95.51 143.81,94.24 143.81,93.32 143.99,93.14 144.17,93.14 144.22,93.09 144.22,92.48 144.17,92.43 ; 3 cut-outs
+5V_PVDD on TOP: 137.79,74.91 137.77,74.93 137.77,76.96 137.82,77.01 139.73,77.01 139.88,77.17 139.88,77.8 139.95,77.88 141.12,77.88 141.4,77.6 141.4,75.03 141.27,74.91 ; 3 cut-outs
+5V_PVDD1 on TOP: 146.48,84.39 146.09,84.79 145.31,84.79 144.51,85.59 144.51,86.41 144.83,86.73 144.83,87.01 145.21,87.39 145.21,88.24 145.24,88.27 145.44,88.27 145.45,88.25 145.45,87.33 145.62,87.16 145.62,86.7 145.14,86.22 145.14,85.84 145.59,85.38 148.48,85.38 148.98,85.89 148.98,86.34 148.58,86.74 147.74,86.74 147.23,87.25 147.23,88.25 147.26,88.28 147.41,88.28 147.43,88.25 147.43,87.56 147.52,87.47 147.56,87.47 147.57,87.48 148.69,87.48 149.54,86.63 149.54,85.28 148.65,84.39
+5V_PVDD1 on TOP: 141.66,76.05 141.66,78.67 141.38,78.94 141.38,80.42 141.94,80.98 143.15,80.98 143.84,80.29 143.84,76.48 143.41,76.05
+5V_PVDD1 on BOTTOM: 141.76,78.26 141.63,78.39 141.63,85.68 143.99,88.04 148.49,88.04 148.49,87.56 149.3,86.74 149.3,85.42 148.76,84.88 147.51,84.88 147.32,84.69 145.92,84.69 144.6,83.36 144.15,83.36 144.15,79.22 143.18,78.26 ; 1 cut-out
GND on TOP: 128.57,63.58 128.37,63.78 128.37,66.04 128.52,66.19 128.78,66.19 129.06,65.91 129.06,64.67 129.34,64.39 131.83,64.39 131.88,64.34 131.88,63.78 131.67,63.58 ; 1 cut-out
GND on TOP: 60.58,82.98 60.49,83.07 60.49,83.72 60.35,83.87 59.18,83.87 58.57,84.48 56.97,84.48 56.77,84.28 56.77,83.97 56.54,83.75 56.21,83.75 55.98,83.97 55.98,84.23 55.96,84.25 55.55,84.25 55.37,84.08 55.37,83.95 55.3,83.87 50.93,83.87 50.34,84.46 50.34,84.84 50.48,84.97 50.69,84.97 50.7,84.96 52.91,84.96 52.91,84.98 52.98,85.04 55.37,85.04 55.85,85.52 58.24,85.52 58.55,85.22 62.68,85.22 62.91,85 62.91,83.3 62.59,82.98 ; 11 cut-outs
GND on TOP: 133.86,45.29 133.73,45.42 133.73,46.97 133.68,47.02 133.35,47.02 133.17,47.19 133.17,48.57 133.86,49.25 134.54,49.25 134.57,49.23 134.57,48.77 134.65,48.69 134.92,48.69 135.64,47.98 135.79,47.98 136.02,47.75 136.02,45.29 ; 1 cut-out
GND on TOP: 32.31,59.34 31.75,59.89 31.75,62.43 32.13,62.82 34.54,62.82 34.54,60 33.88,59.34 ; 5 cut-outs
GND on TOP: 69.57,81.15 67.34,83.39 67.34,84.76 67.79,85.22 67.79,88.93 69.49,88.93 72.92,92.36 76.07,92.36 78.56,89.87 81.48,89.87 82.68,88.67 82.68,83.67 82.58,83.57 82.35,83.57 81.86,84.05 79.98,84.05 79.38,83.44 73.25,83.44 70.97,81.15 ; 4 cut-outs
GND on TOP: 88.34,27.41 86.49,29.26 86.49,32.34 86.97,32.82 86.97,34.67 86.77,34.88 86.77,39.68 87.93,39.68 88.42,40.16 88.42,41.33 88.27,41.48 88.24,41.45 87.27,41.45 87.05,41.68 87.05,42.6 87.35,42.9 87.91,42.9 88.14,42.67 96.9,42.67 97.66,43.44 97.66,52.22 95.73,54.15 95.73,58.07 95.15,58.65 95.15,60.35 94.44,61.06 88.57,61.06 88.47,61.16 88.47,61.62 88.11,61.98 86.26,61.98 86.13,62.1 86.13,64.47 85.52,65.08 85.52,73.31 86.31,74.09 101.57,74.09 103.02,72.65 103.02,31.02 99.42,27.41 ; 9 cut-outs
GND on TOP: 52.53,89.18 52.4,89.31 52.4,90.45 53.42,90.45 53.42,90.46 53.67,90.21 53.67,89.18
GND on TOP: 80.49,40.13 80.49,41.1 80.54,41.15 82.17,41.15 82.4,40.92 82.4,40.31 82.22,40.13
GND on TOP: 43.7,67.97 43.65,68.02 43.65,69.17 44.02,69.53 44.02,70.82 44.17,70.97 49.38,70.97 49.42,70.93 49.42,68.92 49.28,68.78 48.13,68.78 47.32,67.97
GND on TOP: 137.46,30.89 136.73,31.62 136.73,34.37 136.88,34.52 139.88,34.52 139.9,34.49 139.9,31.75 139.85,31.7 138.66,31.7 138.28,31.32 138.28,30.94 138.23,30.89 ; 4 cut-outs
GND on TOP: 83.69,16.71 83.57,16.84 83.57,20.91 83.69,21.03 86.74,21.03 86.87,20.91 86.87,17.68 86.64,17.45 85.93,17.45 85.65,17.17 85.65,16.71 ; 1 cut-out
GND on TOP: 26.19,69.42 26.01,69.6 26.01,72.67 26.14,72.8 26.52,72.8 26.9,73.18 27.25,73.18 27.36,73.08 27.36,71.81 27.64,71.53 27.64,70.08 26.97,69.42 ; 4 cut-outs
GND on TOP: 134.8,75.19 134.34,75.64 134.34,77.45 135.56,78.67 137.24,78.67 137.64,79.07 139.34,79.07 139.73,78.69 139.73,77.37 139.67,77.32 137.52,77.32 137.36,77.17 137.36,76.02 136.53,75.19 ; 3 cut-outs
GND on TOP: 74.88,56.47 74.65,56.69 74.65,57.18 74.83,57.35 74.83,58.37 75.21,58.75 75.74,58.75 75.82,58.68 75.82,58.14 75.49,57.81 75.49,57.35 75.29,57.15 75.29,56.59 75.16,56.47
GND on TOP: outline of 139 points within 0.51,0.51 178.39,102.49 ; 22 cut-outs
GND on TOP: 85.19,43.28 85,43.48 80.5,43.48 80.49,43.49 79.93,43.49 79.73,43.69 79.73,44.22 79.86,44.35 83.83,44.35 83.84,44.36 83.97,44.22 84.43,44.22 84.68,44.48 84.68,44.76 84.61,44.83 84.61,45.13 84.67,45.19 85.01,45.19 85.52,44.68 85.95,44.68 86.06,44.58 86.06,43.46 85.88,43.28
GND on TOP: 31.29,71.2 30.96,71.53 30.96,71.88 31.17,72.09 31.17,72.67 31.52,73.03 33.76,73.03 33.81,72.98 33.81,72.52 33.71,72.42 33.5,72.42 32.28,71.2
GND on TOP: 11.84,11.81 11.81,11.84 11.81,13.51 11.84,13.54 13.51,13.54 13.51,11.81
GND on TOP: outline of 83 points within 109.6,18.16 132.05,93.63 ; 25 cut-outs
GND on TOP: 91.74,16.79 91.49,17.05 91.49,17.45 92,17.96 92.35,17.96 92.48,18.09 92.48,20.91 93.17,20.91 93.22,20.86 93.22,16.84 93.17,16.79
GND on TOP: 34.77,76.38 34.59,76.56 34.59,76.99 34.57,77.01 32.49,77.01 32.28,77.22 32.28,79.25 32.54,79.5 36.12,79.5 36.32,79.3 36.32,77.98 35.59,77.24 35.46,77.24 35.36,77.14 35.36,76.53 35.2,76.38
GND on TOP: 77.27,44.4 77.17,44.49 77.17,45.36 77.29,45.48 78.07,45.48 78.29,45.7 78.29,46.51 78.5,46.73 79.32,46.73 79.46,46.86 79.46,47.9 79.47,47.91 79.47,49.83 79.73,50.09 80.47,50.09 80.85,50.47 80.85,51.16 81.56,51.87 81.56,53.82 81.74,54 82.09,54 82.6,54.51 83.82,54.51 85.37,52.96 86.69,52.96 86.77,52.88 86.77,52.38 86.74,52.35 84.1,52.35 83.82,52.63 83.82,53.42 83.54,53.7 82.58,53.7 82.42,53.54 82.42,51.92 82.63,51.72 83.36,51.72 83.52,51.56 83.52,51.08 83.21,50.78 82.09,50.78 80.38,49.06 80.38,47.89 80.2,47.71 80.2,45.72 80.06,45.57 79.56,45.57 79.33,45.34 79.33,44.88 78.85,44.4 ; 3 cut-outs
GND on TOP: 46.35,62.33 46.23,62.46 46.23,63.45 46.1,63.58 45.21,63.58 45.21,67.26 45.59,67.64 47.55,67.64 48.44,68.53 53.85,68.53 53.98,68.4 53.98,65.31 52.81,64.14 49.12,64.14 48.77,63.78 48.77,62.43 48.67,62.33
GND on TOP: 72.69,45.03 72.69,45.83 73.31,46.45 73.31,47.76 73.39,47.85 73.41,47.85 73.41,48.29 73.69,48.57 74.09,48.57 74.54,48.12 74.54,47.85 74.77,47.62 74.77,46.8 74.74,46.77 74.74,46.53 75.04,46.23 75.04,45.4 74.67,45.03 ; 5 cut-outs
GND on TOP: 18.97,69.62 18.75,69.85 18.75,72.9 18.82,72.98 21.41,72.98 21.72,72.67 21.72,69.83 21.51,69.62 ; 4 cut-outs
GND on TOP: 75.54,48.34 75.23,48.64 75.23,49.02 74.73,49.53 73.79,49.53 73.53,49.79 73.53,50.07 74.83,51.36 74.83,52.17 74.96,52.3 75.77,52.3 76.2,51.87 76.2,51.84 75.67,51.31 75.67,49.58 75.82,49.43 76.17,49.43 76.28,49.33 76.28,48.44 76.17,48.34 ; 2 cut-outs
GND on TOP: 35.76,38.41 35.51,38.66 35.51,41.23 35.94,41.66 38.38,41.66 38.89,41.15 38.89,38.74 38.56,38.41 ; 4 cut-outs
GND on TOP: 145.52,83.09 144.96,83.64 144.96,84.18 145.31,84.53 145.97,84.53 146.43,84.08 148.49,84.08 148.64,83.92 148.64,83.24 148.49,83.09 ; 1 cut-out
GND on TOP: 76.17,52.88 75.64,53.4 75.64,53.65 76.08,54.09 76.08,54.44 76.27,54.63 77.48,54.63 78.17,53.94 79.53,53.94 79.96,54.37 79.96,55.12 79.88,55.2 79.88,55.42 79.38,55.93 79.38,56.8 79.2,56.97 78.46,56.97 78.03,56.54 76.68,56.54 76.58,56.64 76.58,57.08 76.66,57.15 77.24,57.15 77.29,57.2 77.29,58.88 77.6,59.18 78.28,59.18 78.36,59.11 78.36,58.85 78.46,58.75 78.94,58.75 79.04,58.85 79.04,59.34 79.2,59.49 79.5,59.49 79.68,59.31 79.68,58.98 79.58,58.88 79.58,57.63 80.11,57.1 80.11,55.78 80.33,55.56 80.34,55.56 80.45,55.45 80.47,55.45 80.47,53.91 79.43,52.88 ; 5 cut-outs
GND on TOP, BOTTOM: 47.9,39.32 47.57,39.65 47.57,40.36 47.09,40.84 45.09,40.84 44.96,40.97 44.96,45.8 45.42,46.26 47.07,46.26 48.92,44.4 50.29,44.4 50.8,43.89 50.8,39.57 50.55,39.32
GND on TOP, BOTTOM: 178,100.9 173.9,96.8 169.8,100.9 169.8,102.8 171.6,102.8 171.81,102.71 171.9,102.5 171.9,100.9 173.9,98.9 175.9,100.9 175.9,101.5 175.99,101.71 176.2,101.8 178,101.8
GND on TOP, BOTTOM: 35.69,51.13 35.43,51.39 35.43,53.8 35.56,53.93 36.32,53.93 36.58,54.18 37.47,54.18 37.59,54.31 37.59,55.2 43.43,55.2 43.69,54.94 43.69,52.27 43.56,52.15 40.01,52.15 39.75,51.89 39.75,51.26 39.62,51.13
GND on BOTTOM: 107.9,93.19 107.7,93.4 107.7,95.1 107.8,95.2 110.52,95.2 110.64,95.07 110.64,93.45 110.39,93.19 ; 2 cut-outs
GND on BOTTOM: 75.13,18.57 74.9,18.8 74.9,19.08 74.12,19.86 74.12,20.55 74.65,21.08 74.65,21.46 74.68,21.49 75.18,21.49 75.21,21.46 75.21,20.98 74.85,20.63 74.85,19.69 75.16,19.38 76.53,19.38 76.76,19.15 76.76,18.77 76.56,18.57
GND on BOTTOM: 30.5,71.2 30.4,71.3 30.4,72.42 30.65,72.67 31.17,72.67 31.52,73.03 31.52,74.93 31.55,74.96 32.74,74.96 32.79,74.91 32.79,73.69 32.92,73.56 32.92,71.6 32.51,71.2 ; 1 cut-out
GND on BOTTOM: 35.43,66.75 35.05,67.13 35.05,69.67 35.94,70.56 35.94,70.69 36.07,70.82 40.51,70.82 40.89,70.44 40.89,68.53 40.77,68.4 39.62,68.4 39.24,68.02 39.24,67.13 38.86,66.75
GND on BOTTOM: 44.63,78.23 44.53,78.34 44.53,79.68 45.09,80.24 45.09,81.54 45.19,81.64 46.58,81.64 47.04,82.09 48.41,82.09 48.49,82.02 48.49,80.55 48.9,80.14 49.71,80.14 50.19,79.66 50.19,78.41 50.01,78.23 ; 8 cut-outs
GND on BOTTOM: 85.39,17.43 85.24,17.58 85.24,18.21 87.5,20.47 87.5,22.68 87.55,22.73 87.88,22.73 87.93,22.68 87.93,21.92 88.06,21.79 89.05,21.79 89.2,21.95 89.2,22.73 89.33,22.86 92.05,22.86 93.98,20.93 93.98,19.56 93.93,19.51 93.14,19.51 93.09,19.56 93.09,20.96 92.91,21.13 91.01,21.13 90.83,20.96 90.83,18.85 90.73,18.75 87.12,18.75 85.8,17.43 ; 1 cut-out
GND on BOTTOM: 63.09,70.59 63.02,70.66 63.02,71.86 63.25,72.09 63.83,72.09 64.11,71.81 64.11,70.64 64.06,70.59
GND on BOTTOM: 16.16,22.83 15.9,23.09 15.9,25.02 16.05,25.17 17.02,25.17 17.14,25.05 17.14,23.12 16.85,22.83
GND on BOTTOM: 61.78,82.84 61.71,82.91 61.71,83.44 61.66,83.49 61.66,84.12 61.65,84.13 61.65,84.4 61.38,84.67 61.38,86.37 61.39,86.38 61.59,86.57 63.09,86.57 63.26,86.41 63.26,84.72 63.39,84.59 63.44,84.59 63.54,84.49 63.54,84.16 63.6,84.1 63.6,83.06 63.58,83.06 63.36,82.84 61.79,82.84 ; 3 cut-outs
GND on BOTTOM: 131.5,19.36 131.29,19.56 131.29,23.6 131.39,23.7 133.3,23.7 133.32,23.67 133.32,20.14 133.1,19.92 132.46,19.92 132.44,19.89 132.44,19.43 132.36,19.36 ; 1 cut-out
GND on BOTTOM: 43.7,67.97 43.65,68.02 43.65,69.17 44.02,69.53 44.02,70.82 44.17,70.97 49.38,70.97 49.42,70.93 49.42,68.92 49.28,68.78 48.13,68.78 47.32,67.97 ; 7 cut-outs
GND on BOTTOM: 21.17,45.09 21.08,45.18 21.08,45.51 21.27,45.7 21.27,46.55 21.41,46.69 22.05,46.69 22.11,46.62 22.11,46 21.79,45.68 21.79,45.2 21.68,45.09
GND on BOTTOM: 18.62,21.67 17.75,22.53 17.75,24.94 21.06,24.94 21.18,24.82 21.18,23.93 21.31,23.8 22.07,23.8 22.2,23.67 22.2,22.15 21.72,21.67
GND on BOTTOM: 129.43,9.31 129.39,9.36 129.39,12.98 128.78,13.59 128.78,14.48 129.06,14.76 130.78,14.76 130.96,14.58 130.96,13.03 131.14,12.85 131.14,9.7 130.75,9.31
GND on BOTTOM: 14.12,36.63 14.1,36.65 14.1,37.24 13.61,37.72 13.61,38.05 13.74,38.18 14.07,38.18 14.43,37.82 14.94,37.82 15.01,37.75 15.01,36.81 14.83,36.63 ; 1 cut-out
GND on BOTTOM: 132.87,62 132,62.87 132,72.67 131.65,73.03 131.65,76.58 131.72,76.66 132.26,76.66 132.46,76.46 132.46,73.83 132.77,73.52 133.39,73.52 133.86,73.05 134.09,73.05 134.57,72.57 134.57,72.14 134.62,72.09 136.27,72.09 137.03,71.32 137.03,64.47 137.49,64.01 138.35,64.01 138.96,63.4 138.96,62.21 138.76,62 ; 6 cut-outs
GND on BOTTOM: 122.76,15.27 122.66,15.37 122.66,17.05 123.06,17.45 125.88,17.45 126.11,17.22 126.11,15.27
GND on BOTTOM: 54.89,66.33 54.27,66.96 54.27,67.76 54.42,67.91 54.76,67.91 55.04,67.63 55.55,67.63 55.61,67.57 55.61,66.33 ; 1 cut-out
GND on BOTTOM: 139.7,21.41 139.62,21.49 139.62,21.77 138.96,22.43 138.96,25.86 138.99,25.88 140.06,25.88 140.28,26.11 142.11,26.11 142.37,25.86 142.37,23.98 141.35,22.96 141.35,21.41
GND on BOTTOM: outline of 389 points within 0.51,0.51 178.39,102.49 ; 25 cut-outs
GND on BOTTOM: 144.45,88.34 144.02,88.77 144.02,92.31 144.22,92.51 147.65,92.51 147.88,92.74 148.72,92.74 148.79,92.66 148.79,91.67 148.69,91.57 147.88,91.57 147.88,90.32 148.11,90.1 148.97,90.1 148.97,88.77 148.54,88.34 ; 3 cut-outs
GND on BOTTOM: 19.56,56.64 19.28,56.92 19.28,60.05 19.53,60.3 20.88,60.3 21.23,59.95 21.23,57.02 20.85,56.64
GND on BOTTOM: 29.08,38.36 28.93,38.51 28.93,40.49 31.5,40.49 32,41 32.51,41 32.82,40.69 38.73,40.69 38.99,40.44 38.99,38.91 38.43,38.36
GND on BOTTOM: 57.07,46.48 56.77,46.79 56.77,48.87 56.41,49.23 51.31,49.23 50.93,49.61 50.93,49.82 49.89,50.87 48.91,50.87 48.39,51.39 48.39,54.94 48.9,55.45 56.13,55.45 56.77,54.81 56.77,52.91 58.34,51.34 58.34,47.09 57.73,46.48 ; 2 cut-outs
GND on BOTTOM: 22.61,29.29 22.07,29.82 22.07,30.41 21.64,30.84 21.64,31.8 22.58,32.74 25.02,32.74 25.15,32.62 25.15,29.52 24.92,29.29 ; 2 cut-outs
GND on BOTTOM: 142.75,47.55 142.54,47.75 140.79,47.75 140.67,47.88 140.67,48.49 140.84,48.67 141.43,48.67 141.94,49.18 143.71,49.18 143.84,49.05 143.84,47.7 143.69,47.55
GND on BOTTOM: 133.86,45.29 133.73,45.42 133.73,46.97 133.68,47.02 132.13,47.02 132,47.14 132,48.39 132.31,48.69 134.92,48.69 135.64,47.98 135.79,47.98 136.02,47.75 136.02,45.29
GND on BOTTOM: 39.83,25.4 39.55,25.68 39.55,26.11 39.22,26.44 38.79,26.44 38.66,26.57 38.66,27 38.81,27.15 39.19,27.15 39.57,27.54 40.39,27.54 40.84,27.08 40.84,25.5 40.82,25.5 40.72,25.4 ; 1 cut-out
GND on BOTTOM: 82.78,21.82 82.73,21.87 82.73,23.92 82.12,24.54 80.95,24.54 80.72,24.77 80.72,25.53 80.85,25.66 82.25,25.66 83.92,23.98 83.92,22.02 83.72,21.82 ; 1 cut-out
GND on BOTTOM: 84.76,44.65 84.3,45.11 80.39,45.11 80.09,45.42 79.76,45.42 79.43,45.09 78.38,45.09 78.23,45.24 78.23,45.52 78.41,45.7 79.38,45.7 79.76,46.08 80.04,46.08 80.54,45.57 84.48,45.57 85.09,44.96 85.09,44.76 84.99,44.65
GND on BOTTOM: 89.2,25.35 89.13,25.43 89.13,25.91 89.18,25.96 89.76,25.96 89.84,26.04 89.84,26.47 89.89,26.52 90.35,26.52 90.4,26.47 90.4,25.43 90.32,25.35
GND on BOTTOM: 46.35,62.33 46.23,62.46 46.23,63.45 46.1,63.58 45.21,63.58 45.21,67.26 45.59,67.64 47.55,67.64 48.44,68.53 53.85,68.53 53.98,68.4 53.98,65.31 52.81,64.14 49.12,64.14 48.77,63.78 48.77,62.43 48.67,62.33 ; 1 cut-out
GND on BOTTOM: 79.71,46.46 79.58,46.59 79.58,47.12 74.63,47.12 73.99,46.48 73.76,46.48 73.69,46.56 73.69,46.94 74.27,47.53 77.32,47.53 77.8,48.01 79.6,48.01 79.71,48.11 79.71,48.97 79.56,49.12 79.31,49.12 79.19,49.24 79.19,49.41 79.52,49.74 79.52,49.83 79.71,50.01 80.62,50.01 80.72,50.12 80.72,50.85 80.49,51.08 80.49,51.13 74.37,51.13 74.22,51.28 74.22,51.44 74.37,51.59 75.39,51.59 75.79,52 77.9,52 78.33,51.56 79.38,51.56 79.88,52.07 80.04,52.07 80.67,51.44 81.13,51.44 81.74,52.05 82.25,52.05 82.78,51.51 84.76,51.51 85.17,51.11 85.17,50.04 85.29,49.91 85.29,49.61 85.06,49.38 85.06,49.07 85.12,49.02 85.12,47.88 85.29,47.7 85.29,47.37 85.01,47.09 80.26,47.09 80.11,46.94 80.11,46.56 80.01,46.46 ; 1 cut-out
GND on BOTTOM: 29.39,49.48 28.89,49.98 27.98,49.98 27.86,50.09 25.98,50.09 25.98,50.85 26.24,51.11 27.18,51.11 27.66,51.59 27.66,53.82 27.69,53.85 28.19,53.85 28.22,53.82 28.22,53.21 28.3,53.14 29.03,53.14 29.16,53.27 29.16,53.75 29.3,53.89 29.73,53.89 30.35,53.27 30.35,52.73 30.58,52.5 31.19,52.5 31.23,52.47 31.23,49.7 31.01,49.48 ; 8 cut-outs
GND on BOTTOM: 107.24,7.11 107.21,7.14 107.21,10.39 107.42,10.59 110.57,10.59 110.82,10.85 110.82,12.22 110.36,12.68 110.36,14.56 110.46,14.66 113.64,14.66 113.74,14.56 113.74,12.68 113.88,12.54 114.48,12.54 114.68,12.35 114.68,10.52 111.28,7.11
GND on BOTTOM: 101.57,7.98 101.35,8.21 101.35,11.58 101.88,12.12 104.27,12.12 104.44,11.94 104.44,8 104.42,7.98
GND on BOTTOM: 73.28,49 73.18,49.1 73.18,49.35 73.38,49.56 73.38,50.07 73,50.45 73,51.03 73.23,51.26 73.23,52.4 73,52.63 73,53.7 73.15,53.85 73.48,53.85 73.63,53.7 73.63,53.52 73.84,53.32 74.04,53.32 74.27,53.54 74.5,53.54 74.57,53.47 75.18,53.47 75.86,54.15 78.35,54.15 78.36,54.13 78.74,54.13 78.89,53.98 80.09,53.98 80.64,53.42 81.1,53.42 81.69,54 81.97,54 82.3,53.67 82.85,53.67 83.21,54.03 83.21,54.33 83.49,54.61 83.79,54.61 84.18,54.99 84.18,55.98 84.07,56.08 82.7,56.08 82.47,56.31 82.47,56.52 82.52,56.57 82.85,56.57 82.96,56.47 83.67,56.47 83.74,56.54 84.99,56.54 85.09,56.44 85.09,55.48 84.63,55.02 84.63,53.27 84.48,53.11 75.25,53.11 75.12,52.99 74.47,52.99 73.84,52.35 73.84,51.92 73.65,51.73 73.65,50.36 73.96,50.04 74.6,50.04 74.73,50.17 75.01,50.17 75.72,49.46 77.29,49.46 77.62,49.79 77.62,50.07 77.75,50.19 78.08,50.19 78.41,49.86 78.41,49.23 78.41,49.23 78.32,49.15 74.32,49.15 74.17,49
GND on BOTTOM: 20.5,62.28 20.43,62.35 20.43,62.98 20.35,63.07 19.76,63.07 19.66,63.17 19.66,65.25 19.71,65.31 20.65,65.31 20.95,65 20.95,62.33 20.9,62.28 ; 2 cut-outs
GND on BOTTOM: 38.68,15.83 38.23,16.29 38.23,18.86 38.62,19.26 38.62,19.92 38.87,20.17 40.78,20.17 41.28,19.66 42.33,19.66 42.5,19.49 42.5,19.04 42.36,18.9 41.71,18.9 41.66,18.85 41.66,16.54 40.96,15.83
GND on BOTTOM: 73.76,75.61 73.57,75.8 73.48,75.8 73.36,75.92 73.36,79.43 73.76,79.83 75.06,79.83 75.36,79.53 75.36,75.92 75.36,75.92 75.36,75.78 75.18,75.61 ; 3 cut-outs
GND on BOTTOM: 26.06,70.72 25.93,70.84 25.93,72.39 26.11,72.57 26.29,72.57 26.85,73.13 27.13,73.13 27.3,72.95 27.3,71.96 26.95,71.6 26.95,70.84 26.82,70.72
GND on BOTTOM: 16.88,13.51 15.93,14.46 15.93,15.27 16.38,15.72 16.38,18.11 17.02,18.75 17.02,20.93 17.37,21.29 20.93,21.29 21.34,20.88 21.34,19.51 21.46,19.38 22.23,19.38 22.23,17.73 21.72,17.22 18.03,17.22 17.78,16.97 17.78,14.17 17.77,14.17 17.77,13.53 17.75,13.51 ; 4 cut-outs
GND on BOTTOM: 32.31,77.12 32.31,79.22 32.61,79.53 36.07,79.53 36.3,79.3 36.3,78.21 35.2,77.12
GND on BOTTOM: 18.97,69.6 18.75,69.83 18.75,72.87 18.82,72.95 21.41,72.95 21.72,72.65 21.72,69.8 21.51,69.6
GND on BOTTOM: 32.2,59.31 31.55,59.97 31.55,62.23 32.13,62.82 33.91,62.82 34.16,62.57 34.16,59.34 34.13,59.31 ; 2 cut-outs
GND on BOTTOM: 30.19,67.95 30.1,68.05 30.1,70.84 30.2,70.94 32.44,70.94 32.64,70.74 32.64,68.3 32.29,67.95
